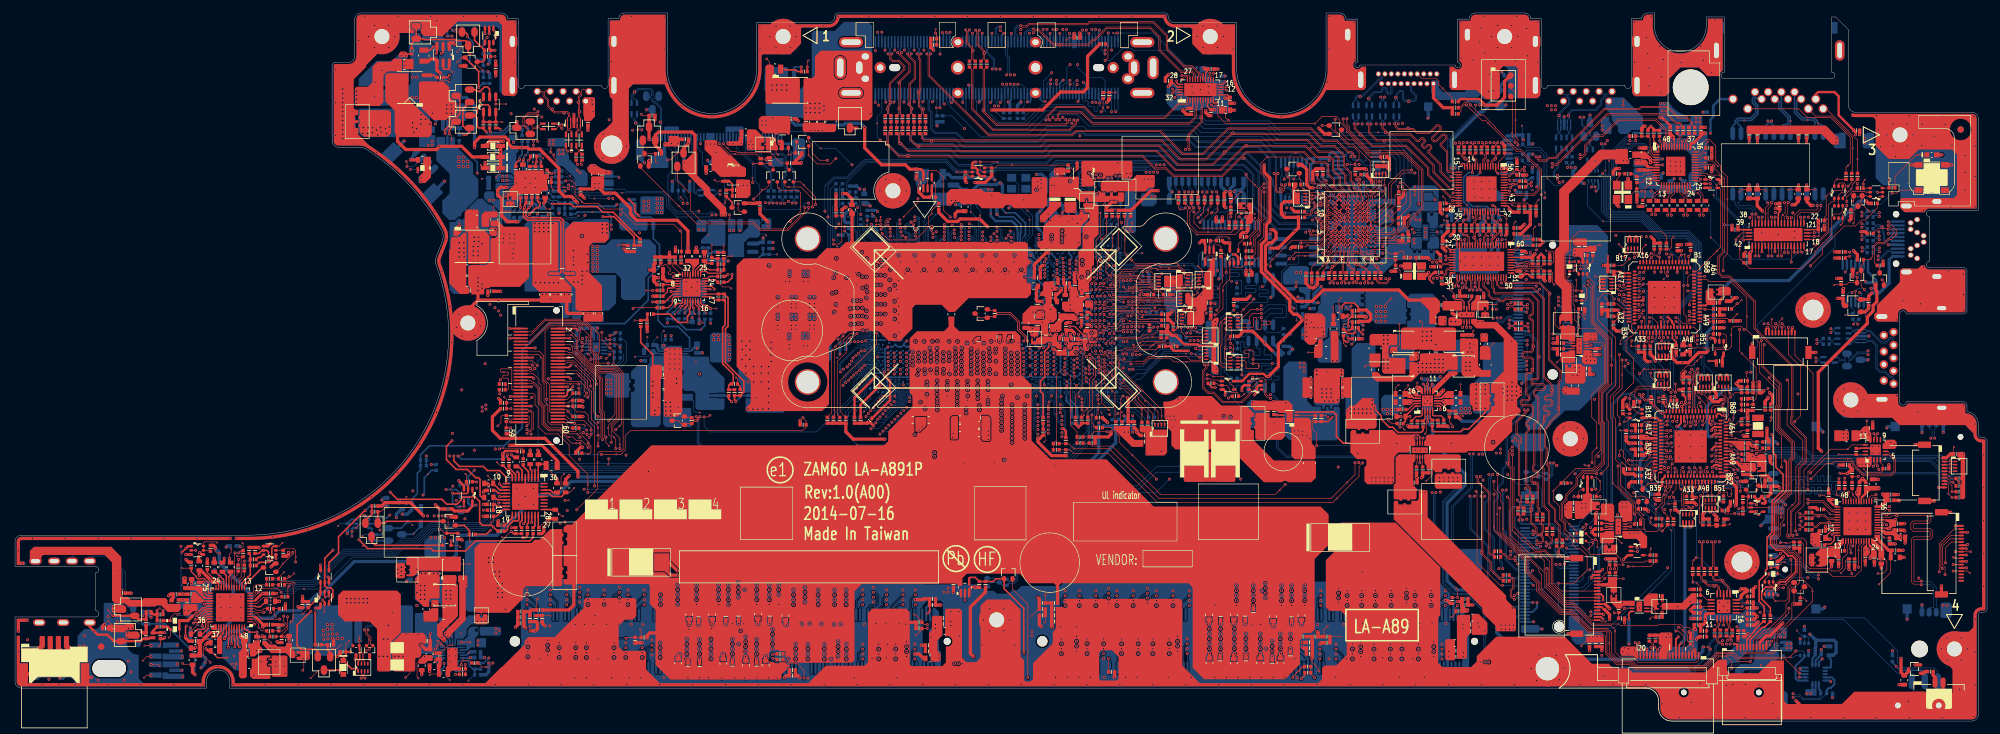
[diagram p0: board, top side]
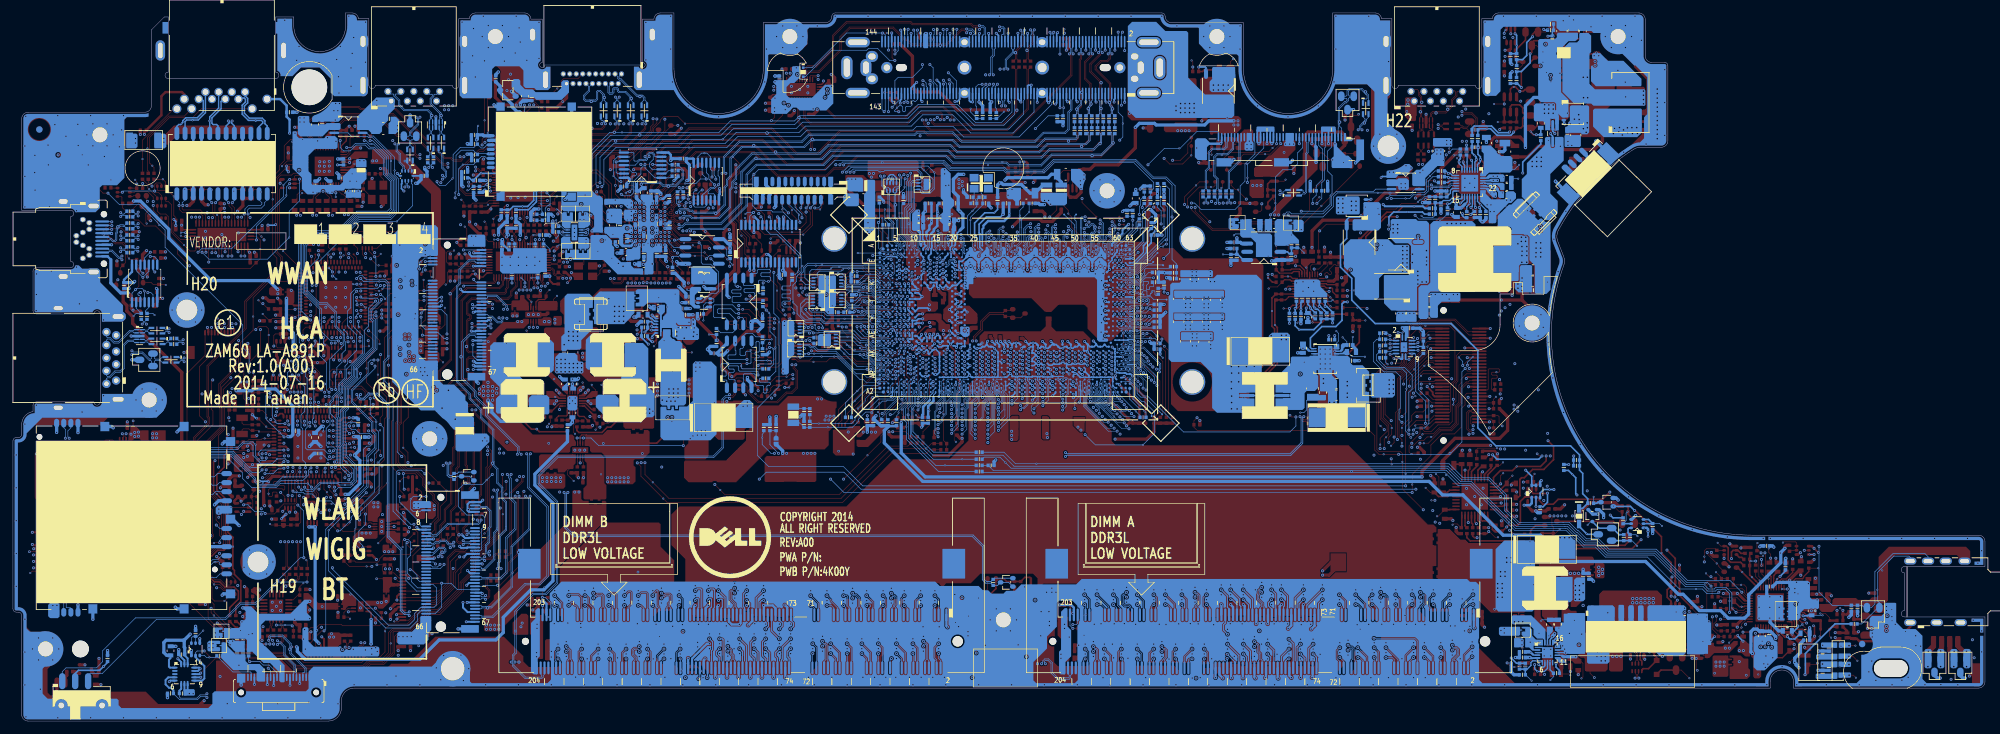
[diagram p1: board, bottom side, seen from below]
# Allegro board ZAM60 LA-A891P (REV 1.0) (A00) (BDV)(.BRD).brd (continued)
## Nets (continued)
N22988375: C319.1 R273.2
N23890107: QE4.2 RE70.2
N24544483: PD5.2 PD5.3 PL3.1 PQ2.1 PR7.1 PR10.2
N24607258: PC309.1 PU300.5
N48705653: PQ2.3 PR7.2 PR9.1
N48705663: PQ3.2 PR10.1 PR12.2
N48705665: PQ2.2 PQ3.1 PR11.2 PR13.1
N48708367: PR210.2 PU200.7
N48708425: PR206.2 PU200.9
N48716673: PR838.1 PU800.28
N48716693: PR845.1 PU800.26
N49522072: PC700.2 PQ701.2 PQ702.2 PR702.2
N49522215: PQ703.1 PQ703.3 PR706.2 PR707.2 PR709.2
N49522242: PC702.2 PC703.1 PR705.2 PU700.1
N49522275: PC701.2 PC702.1 PR704.2 PU700.2
N49522729: PQ701.1 PR701.2
N49522731: PQ702.1 PR701.3
N49522780: PQ700.4 PR700.1
N61500733: PR513.1 PU500.4
N61500909: PC510.2 PR526.1 PU500.28
N61500999: PH501.2 PR515.1
N61501245: PC501.1 PH500.2 PR505.2 PU500.14
N61501462: PR511.2 PU500.16
N66971793: PR105.2 PU100.5
N66972075: PR106.2 PU100.1
N78957489: PQ816.1 PR822.2
N78967043: PQ816.2 PU806.4
N78985854: PR810.2 PR812.2 PU804.2
N79002827: PQ806.2 PU804.4
N79023703: PR863.1 PU800.19
N79030038: PQ813.2 PQ813.3 PR829.2
N79030087: PQ813.6 PR826.2
N79030091: PQ814.2 PR826.1 PR827.1
N79030745: PD813.2 PQ814.1
N79114795: PC4.1 PQ1.2 PR6.2
N79114801: PD4.2 PQ1.1
N80905978: PC402.1 PR400.2 PR401.1 PU400.8
N80906026: PC403.2 PR402.2 PR403.1 PU400.2

Pads without a net: FD1 1; FD2 1; FD3 1; FD4 1; JAPS1 16 17 18; JDIMM1 77 122 125 198 205 206; JDIMM2 77 122 125 198 205 206; JEDP1 16 20 32; JHDMI1 14; JKBTP1 6 13; JLED1 9; JLOM1 14 15; JNGFF1 9 36 38 40 50 52 54 56; JNGFF2 12 14 16 17 20 32 34 36 38 40 48 50 51 52 53 54 55 56 57 58 59 60; JSATA1 8 20; JSIM1 1 2 5; JSPI1 17; JUSH1 9 10; JXDP1 40 42; PBATT1 11 12; PD2 3; PRP2 4 5; PU200 10; PU400 7; PU500 5; PU700 4; PU800 20 29 30 31 35 36; QL2 3 4 5; QZ11 3 4 5; RPC1 7; RPC17 8; RPE5 1; RPE6 4 5; UC1 A5 A21 A23 A35 A41 A43 A49 AA23 AA59 AB8 AB21 AB23 AC20 AC58 AC59 AD5 AD7 AD8 AD10 AD23 AD59 AD60 AE59 AE60 AF20 AG58 AH13 AL1 AL2 AL11 AL32 AM10 AM11 AN10 AP7 AP32 AT2 AU10 AU12 AU15 AU44 AV2 AV10 AV44 AV50 AV62 AW10 AW14 AW49 AY8 AY14 AY42 AY43 B21 B22 B23 B35 B41 B43 B49 C4 C21 C46 C47 D1 D15 D58 D61 E1 E6 E8 E13 E15 F6 F8 F22 G1 G10 H10 H18 H22 J2 J4 J13 J20 J21 J58 K4 K10 K18 K21 L3 L11 L59 M20 M21 N23 N58 N60 P20 R5 R20 R23 T23 T59 U10 U59 V21 V59 W23 Y20 Y22; UC8 1; UD1 1; UE1 A3 A5 A8 A9 A11 A12 A16 A23 A32 A42 A45 A46 A48 A49 A52 A55 A56 A57 A58 A59 A60 A61 A64 B1 B3 B4 B6 B7 B11 B13 B14 B16 B17 B18 B32 B39 B40 B45 B47 B49 B56 B57 B58 B60 B61 B63 B64 B65 B66; UE2 A15 B15 B16 B62; UI3 9 15; UI4 8 13 17; UL4 5; UN1 2 3; UN2 7; UR1 19 39 40 44 46; UV7 46; UV8 E10 H3 H11 K2 L2 L10 L11 L12 L13 M1 M2 M10 M11; UV600 2 4 14 22 23 58; UZ1 1 2 5 6 7 9 12 13 14 15 17 27 28; YC2 2 4

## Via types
v1: diameter 0.305, hole 0.152, TOP to BOTTOM, 753 vias
v2: diameter 0.457, hole 0.203, TOP to BOTTOM, 4660 vias
v3: diameter 0.406, hole 0.203, TOP to BOTTOM, 157 vias
v4: diameter 0.508, hole 0.254, TOP to BOTTOM, 593 vias

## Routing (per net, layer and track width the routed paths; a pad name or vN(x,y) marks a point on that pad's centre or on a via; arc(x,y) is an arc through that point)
0.675V_DDR_VTT_ON: length 105.7
  TOP w0.102: PR210.1 72.15,8.36 v1(72.73,8.36) 73.21,8.36 v2(73.85,8.99)
  TOP w0.254: UD1.4 147.45,22.07 147.6,22.22 148.37,22.22 149.01,21.58 RD14.2 RD9.2 151.19,21.58 151.6,22 QD1.2 152.84,20.49 155.89,17.44 v2(155.89,10.52)
  IN3 w0.122: v2(73.85,8.99) 75.05,7.79 118.22,7.79 118.73,8.3 143.62,8.3 145.84,10.52 v2(155.89,10.52)
1.05V_LP_EN: length 0.6
  BOTTOM w0.102: 200.04,66.56 200.4,66.56 v1(200.58,66.74)
1.05V_M_PWRGD: length 35.5
  TOP w0.254: v2(208.28,59.82) 207.58,60.51 PR313.1 ; RC27.1 185,51.59 v2(185.48,51.59)
  IN2 w0.254: v2(185.48,51.59) 185.02,52.04 185.02,54.58 185.49,55.05 188.82,55.05 190.07,53.81 193.9,53.81 194.42,53.29 199.5,53.29 200.23,54.01 200.23,57.26 201.98,59.02 204.37,59.02 205.19,59.84 206.11,59.84 206.32,59.63 208.09,59.63 v2(208.28,59.82)
  BOTTOM w0.102: v2(185.48,51.59) v1(184.78,51.59)
1.05V_MODPHY_EN: length 15.6
  TOP w0.102: QZ6.3 164.13,85.22 163.97,85.05 163.66,85.05 CZ25.1 v1(154.06,85.97) 151.84,85.97 151.4,85.53 RZ5.2 150.9,85.56 QZ10.3
1.05V_MP_PWROK: length 2.4
  TOP w0.254: v2(206.05,60.46) 206.34,60.46 PR313.2 PR315.2
  BOTTOM w0.254: PU300.2 v2(206.05,60.46)
1.5VSP:
  vias: v1(107.15,75.16)
1.35V_B+: length 26.1
  TOP w0.102: PQ200.5 v1(70.27,24.28)
  IN1 w0.254: v2(62.1,23.47) 60.98,22.35 60.98,9.25 61.49,8.74 66.1,8.74 v2(66.29,8.93)
  BOTTOM w0.254: v2(66.29,8.93) 66.29,8.36 65.77,7.84 PR206.1
  BOTTOM w0.508: PC206.1 PC203.1 v2(62.1,23.47)
1.35V_FB: length 6.8
  BOTTOM w0.102: PR209.1 70.97,7.16 v1(70.06,6.25)
  BOTTOM w0.203: PC213.1 70.74,8.03 70.16,8.61 70.16,9.05 69.91,9.31 68.45,9.31 68.41,9.27 PU200.6
  BOTTOM w0.254: PR205.1 PC213.1 71.04,7.17 PR209.1
3.3V_CAM_EN#: length 137.2
  TOP w0.102: QZ1.2 102.35,83.55 104.39,81.51 104.39,78.97 106.17,77.19 114.17,77.19 115.26,76.1 119.33,76.1 122.06,78.83 v2(122.06,79.43) ; v2(171.21,56.75) 171.84,57.38 173.23,57.38 173.99,58.14 v1(175.88,58.14) 175.98,58.14 176.3,58.46 179.08,58.46 RC174.1
  IN3 w0.076: 168.87,72.77 168.41,72.31 168.41,68.57 168.64,68.34 168.64,66.84 168.08,66.28 165.82,66.28 165.46,65.93 165.46,61.07 165.98,60.55 167.04,60.55 167.28,60.32 167.28,59.77 167.54,59.51 168.44,59.51 168.92,59.03
  IN3 w0.122: v2(122.06,79.43) 122.06,80.16 122.64,80.75 124.33,80.75 128.61,85.03 149.99,85.03 159.1,94.14 159.87,94.14 160.22,94.5 163.17,94.5 163.52,94.14 164.43,94.14 165.21,93.36 165.21,89.1 163.58,87.46 163.58,82.13 168.59,77.13 168.59,76.36 168.87,76.09 168.87,72.77 ; v2(171.21,56.75) 171.21,57.63 169.81,59.03 168.92,59.03
  BOTTOM w0.081: UC1.AM4 169.13,56.13 169.6,56.13 169.64,56.09 169.66,56.09 169.66,56.09 170.37,56.09 170.37,56.09 170.38,56.09 170.55,56.26 170.9,56.26 171.21,56.57 v2(171.21,56.75)
3.3V_HDD_EN: length 118.4
  TOP w0.102: UN3.3 v2(248.74,17.45) 248.06,16.78 RN6.2 RN7.1
  IN1 w0.089: v2(204.49,39.28) 204.77,39.28 211.32,32.73 228.96,32.73 229.28,32.41 238.35,32.41 244.94,25.82 244.94,21.68 245.81,20.81 245.81,18.77 247.12,17.45 v2(248.74,17.45)
  IN3 w0.122: v2(204.49,39.28) 199.19,39.28 196.1,42.37 196.1,47.68 195.9,47.89 195.9,56.95 195.75,57.09 191.52,61.33 191.52,63.07 187.24,67.35 185.46,67.35 184.64,68.17 181.33,68.17 180.34,69.16 v2(177.23,69.16)
  BOTTOM w0.076: UC1.K2 170.49,68.14 170.82,68.14 171.32,68.64 172.57,68.64 v1(173.17,68.04) 173.36,68.04
  BOTTOM w0.102: 173.36,68.04 173.95,67.45 175.75,67.45 175.97,67.66 175.97,68.54 176.59,69.16 v2(177.23,69.16)
3.3V_TP_EN: length 15.6
  TOP w0.081: v2(168.27,67.65) 168.8,68.18 169.64,68.18 171,69.54 172.7,69.54 173.36,70.19
  TOP w0.102: RPC3.7 180.88,68.43 180.68,68.63 180.68,69.01 179.83,69.86 176.49,69.86 176.38,69.98 v1(175.6,69.98) 175.35,70.23 173.39,70.23 173.36,70.19
  BOTTOM w0.081: v2(168.27,67.65) 168.15,67.53 UC1.L5
3.3V_TS_EN: length 123.7
  TOP w0.102: RPC4.7 176.38,67.73 175.85,68.27 174.13,68.27 173.7,68.7 171.08,68.7 170.29,67.91 170.29,67.29 170.01,67.01 168.66,67.01 168.47,67.2 167.53,67.2 v2(167.02,66.69) ; v2(122.64,79.43) 122.64,79.08 119.4,75.84 115.14,75.84 114.11,76.87 105.34,76.87 v1(102.54,79.67) 96.63,85.59 QV7.2
  IN3 w0.081: 167.42,76.26 167.42,73.15 168.21,72.36 168.21,68.45 167.94,68.18 167.56,68.18 167.36,67.98 167.36,67.41 167.02,67.07 v2(167.02,66.69)
  IN3 w0.122: v2(122.64,79.43) 122.64,79.51 123.52,80.39 124.32,80.39 128.69,84.76 150.07,84.76 159.21,93.89 159.97,93.89 160.32,94.25 163.07,94.25 163.42,93.89 164.33,93.89 164.96,93.26 164.96,91.9 162.37,89.31 162.37,82.58 167.42,77.53 167.42,76.26
  BOTTOM w0.081: UC1.N7 166.85,66.52 v2(167.02,66.69)
3.3V_WWAN_EN: length 15.7
  TOP w0.102: v2(244.92,57.59) 244.92,57.66 v1(245.27,58.01)
  TOP w0.203: RZ40.2 244.18,57.62 UZ2.3
  TOP w0.305: UE1.B42 v2(254.37,61.77)
  TOP w0.508: RZ40.2 v2(244.92,57.59)
  IN4 w0.508: v2(254.37,61.77) 253.39,60.78 250.63,60.78 250.41,61.01 247.04,61.01 246.44,60.4 246.44,59.11 v2(244.92,57.59)
+0.9V_LAN: length 7.1
  TOP w0.203: UL1.46 255.23,89.29 254.87,89.64 v2(254.83,89.64) UL1.47 ; UL1.11 253.14,83.99 252.66,83.51 v2(252.66,83.48) ; v2(258.37,81.77) 258.03,82.11 UL1.22 ; v2(257.67,89.71) 257.63,89.67 UL1.40 ; v2(255.44,81.77) 255.63,81.95 UL1.16
  TOP w0.508: CL9.1 v2(261.16,90.9)
  vias: v1(259.98,89.94) v2(250.76,85.25) v2(251.39,85.25) v2(256.14,90.22)
+0.675V_DDR_VTT: length 151.8
  IN4 w1.524: 74.67,12.48 74.67,9.94 76.77,7.85 142.28,7.85 142.8,8.36 143.63,7.53 148.76,7.53 149.4,8.17 222.23,8.17
  vias: v2(74.29,14.33) v2(74.29,13.63) v2(74.8,14.01) v2(142.24,14.96) v2(142.24,14.33) v2(142.8,10.33) v2(142.8,9.7) v2(223.76,14.97) v2(223.76,14.33) v2(223.83,10.58) v2(223.83,9.94) v3(141.51,12.98)
+0.675V_P: length 1.3
  TOP w0.127: v2(68.96,12.19) v3(70.28,12.19)
+1.2V_LDO: length 31.6
  TOP w0.102: v3(278.88,34.9) 279.61,34.9 280.25,34.26 CR21.2
  TOP w0.203: UR1.10 280.79,29.51 279.78,28.49 CR18.2 ; UR1.1 281.31,33.11 280.97,33.45
  TOP w0.381: CR21.2 280.27,34.14 280.97,33.45
  TOP w0.508: CR21.2 v2(280.97,34.26)
  IN2 w0.508: v2(289.61,29.76) 290.02,29.76 290.56,30.3 v2(290.56,31.16) 290.56,34.47 289.93,35.1 v2(288.59,35.1) 288.59,35.41 v2(288.02,35.99) 287.45,36.56 282.11,36.56 280.97,35.41 v2(280.97,34.26) 280.97,32.43 281.52,31.88 281.52,28.47 281.16,28.11 v2(280.53,28.11)
+1.05V_M: length 131.9
  TOP w0.381: v2(164.68,60.93) 164.81,61.06 RC300.1
  TOP w0.508: v2(163.71,59.88) 163.71,60.03 163.31,60.43 162.54,60.43 162.46,60.51 ; CC61.1 162.46,60.51 ; 162.46,60.51 v2(162.46,59.83) ; RC14.2 RC18.2 RC16.2 RC15.2 128.39,44.74 129.54,43.6 v2(134.43,43.6)
  IN2 w0.508: v2(197.71,44.22) 197.71,41.22 197.04,40.55 155,40.55 153.09,42.46 135.56,42.46 v2(134.43,43.6)
  IN3 w1.524: 171.88,82.98 171.88,81.2 173.85,79.23 178.62,79.23 182.5,75.35 188.59,75.35 192.15,71.79 194.26,71.79 196.21,69.84 196.21,63.14 197.44,61.91 197.44,59.77 198.99,58.22 198.99,56.5
  BOTTOM w0.203: UC1.AG13 163.51,59.38 163.71,59.58 v2(163.71,59.88) ; v2(162.46,59.83) 162.69,59.6 UC1.AG14
  BOTTOM w0.254: v2(166.44,59.07) 166.44,58.77 166.26,58.6 UC1.AG8 ; UC1.AF9 UC1.AE9
  BOTTOM w0.33: v2(166.44,59.07) UC1.AF9
  vias: v2(171.76,84.68) v2(172.08,84.11) v2(172.4,84.68) v2(197.74,44.87) v2(198.35,44.22) v2(198.37,44.87) v2(198.59,55.36) v2(198.59,54.72) v2(198.98,44.81) v2(198.98,44.22) v2(199.22,55.36) v2(199.22,54.72) v2(199.22,54.09) v2(199.67,44.09) v2(200.09,43.66) v3(170.42,86.33)
+1.05V_MODPHY:
  vias: v3(160.13,82.85)
+1.05V_MODPHY_PCH: length 2.7
  BOTTOM w0.254: UC1.M9 164.95,66.69 v2(164.88,66.76) 164.9,66.76 UC1.L10 165.75,67.61 UC1.K9 165.75,68.15 v2(165.78,68.18)
  vias: v3(166.3,76.89)
+1.05V_MP: length 13
  IN4 w0.254: v2(206.56,58.28) 206.56,50.96 205.23,49.63 v4(204.4,49.63)
  BOTTOM w0.254: PR307.1 PC304.1 207.58,59.3 v2(206.56,58.28)
  vias: v1(202.78,54.05) v4(201.17,54.2) v4(201.17,53.57) v4(201.98,51.35) v4(201.98,50.72) v4(201.98,50.08) v4(202.42,49.47) v4(202.68,51.35) v4(202.68,50.72) v4(202.68,50.08) v4(203.07,49.47) v4(203.37,51.35) v4(203.37,50.72) v4(203.37,50.08) v4(203.72,49.45) v4(204.98,54.2) v4(204.98,53.57)
+1.5V_RUN: length 185.5
  TOP w0.102: v3(30.19,9.07) 29.09,10.16 29.09,11.44 v2(29.49,11.84)
  TOP w0.508: RA3.1 29.78,12.13 v2(29.49,11.84)
  IN2 w0.508: v2(162.99,68.63) 162.99,68.24 162.48,67.74 158.67,67.74 158.1,68.31 158.1,71.8 156.77,73.13 127.51,73.13 124.58,70.21 118.87,70.21 113.88,75.19 107.43,75.19 ; v2(29.49,11.84) 30.74,11.84 32.06,10.52 35.05,10.52 36.26,11.72 36.26,20.1 36.95,20.8 36.95,24.68 38.8,26.52 40.7,26.52 41.52,27.34 43.37,27.34 44.34,28.31 48.67,28.31 51.54,31.18 54.89,31.18 60.09,36.38 61.96,36.38 66.04,40.46 66.04,43.99 68.13,46.09 68.13,51.85 70.74,54.46 76.01,54.46 83.7,62.15 90.75,62.15 92.58,63.98 92.58,65.7 101.29,74.4 104.46,74.4 105.34,75.29
  BOTTOM w0.254: UC1.J15 162.65,68.29 v2(162.99,68.63)
  vias: v2(105.66,75.98) v2(106.36,75.98)
+1.05V_RUN: length 251.7
  TOP w0.254: UV8.E5 205.28,74.9 205.28,74.91 v2(205.29,74.91) ; UV8.J3 v2(208.54,73.61)
  TOP w0.279: 263.62,37.84 262.96,37.84 UE2.B51 ; JXDP1.43 v2(76.51,50.2) ; v2(86.2,51.72) 86.2,51.7 85.34,50.84 85.34,50.48 85.06,50.2 JXDP1.44
  TOP w0.508: 263.62,37.84 264.63,37.84 265.29,37.18 265.29,36.93 266.01,36.21 CE25.1 266.01,33.45 v2(265.86,33.3) ; v2(127.89,81.57) 128.52,81.57 129.35,80.75 CC79.1 ; RE70.1 252.03,32.8 v2(252.41,32.42) ; RC197.1 v2(126.87,81.57) ; CC84.1 157.84,66.97 157.84,65.08 CC70.1 158.7,64.89 v2(158.73,64.86) ; v2(162.05,68.62) 162.05,67.77 CC59.1 162.33,67.44 162.33,65.91 CC60.1 ; RC117.1 v2(87.75,47.09)
  IN2 w0.508: v2(86.2,51.72) 86.2,51.32 85.72,50.84 79.31,50.84 78.67,50.2 v2(76.51,50.2) ; v2(198.64,69.37) 210.8,69.37 212.85,71.41 212.85,74.93 214.75,76.83 216.6,76.83
  IN2 w1.524: 210.82,87.67 215.64,87.67 218.06,85.25 218.06,79.43
  IN3 w0.508: v2(252.41,32.42) 251.76,31.77 250.97,31.77 249.97,30.77 249.37,30.77 248.84,30.24 248.84,29.18 246.97,27.31 245.48,27.31 243.88,25.7 243.32,25.7 239.79,22.18 237.91,22.18 237.58,21.85 228.69,21.85 227.13,23.41 206.02,23.41 203.12,26.31 193.08,26.31 179.07,40.32 179.07,45.19 ; v2(126.87,81.57) 126.49,81.57 123,78.08 116.09,78.08 115.07,77.06 110.15,77.06 104.4,71.32 104.4,69.65 102.49,67.73 100.8,67.73 99.5,66.43 99.5,64.55 95.63,60.68 95.63,57.25 92.27,53.89 91.5,53.89 90.53,52.91 86.94,52.91 86.2,52.17 v2(86.2,51.72) 86.2,48.64 v2(87.75,47.09)
  IN4 w0.508: v2(265.86,33.3) 265.86,33.2 265.28,32.62 264.24,32.62 262.98,31.36 254.62,31.36 253.55,32.42 v2(252.41,32.42)
  BOTTOM w0.229: v2(162.04,69.2) 162.2,69.2 UC1.H15 ; v2(163.96,69.35) 164.22,69.1 164.22,69.09 UC1.H11 UC1.J11
  BOTTOM w0.254: v2(166.37,66.69) 166.37,66.69 166.2,66.51 UC1.N8 165.93,66.22 165.75,66.04 UC1.P9 ; UC1.AG17 161.15,58.72 v2(161.47,58.4) 161.79,58.72 UC1.AG16 ; v2(162.05,68.62) 161.72,68.29 UC1.J17 ; v2(158.69,59.25) 158.68,59.24 158.24,59.24 UC1.AF22 ; v2(166.37,60.03) 166.2,59.85 UC1.AE8
  BOTTOM w0.305: UC1.R21 159.1,65.23 v2(158.73,64.86) 159.1,64.5 UC1.T21
  BOTTOM w0.457: RC125.1 v2(127.89,81.57) RC124.1 ; RC126.1 v2(126.87,81.57) RC127.1
  BOTTOM w0.508: v2(131.24,82.21) RC196.2
  vias: v2(144.4,79.92) v2(144.7,80.5) v2(145.34,80.5) v2(158.05,83.41) v2(158.05,82.78) v2(158.56,83.73) v2(158.56,83.1) v2(158.56,82.46) v2(160.96,59.81) v2(174.53,83.79) v2(175.12,83.79) v2(175.7,83.79) v2(177.89,47.14) v2(178.05,46.56) v2(178.47,47.14) v2(178.66,46.56) v2(179.08,47.14) v2(179.26,46.56) v2(179.79,49.81) v2(180.4,49.81) v2(198.03,69.35) v2(216.18,74.48) v2(216.2,73.9) v3(155.86,80.59)
+1.5V_RUN_AUDIO:
  vias: v1(31.9,13.33)
+1.05V_RUN_UZ7:
  vias: v1(194.55,46.1)
+1.05V_RUN_VMM: length 16.8
  TOP w0.127: v2(197.98,67.18) v3(197.98,67.88)
  IN3 w0.508: v2(211.19,70.76) 210.08,69.66 200.96,69.66 198.49,67.18 v2(197.98,67.18)
  BOTTOM w0.508: QV20.4 196.98,66.84 196.98,66.84 197.63,66.84 v2(197.98,67.18)
+1.05V_VCCST: length 114.2
  TOP w0.508: PC511.1 PR529.1 PR528.1 ; PR528.1 PR527.1 ; PR528.1 v2(101.14,72.5) ; v2(150.29,76.44) v3(149.09,77.63) 146.05,77.63 145.67,77.25 144.14,77.25 142.75,78.65 RC202.2
  IN1 w0.508: v2(101.14,72.5) 101.84,71.8 105.55,71.8 106.19,71.17 106.98,71.17 109.85,68.3 116.1,68.3 118.03,70.23 125.88,70.23 v2(126.79,69.32)
  IN2 w0.508: v2(150.29,76.44) 149.02,76.44 148.51,75.93 148.51,74.4 147.94,73.83 132.58,73.83 127.76,78.65 127.76,79.92 128.33,80.49 128.78,80.49 v2(130.55,82.27)
  IN3 w0.508: v2(126.79,69.32) 126.79,70.54 125.79,71.54 125.79,76.81 127.19,78.21 127.19,79.6 127.95,80.37 129.28,80.37 130.55,81.64 v2(130.55,82.27) ; v2(150.29,76.44) 150.29,75.35 150.16,75.22 150.16,71.43 151.75,69.84 151.75,67.3 157.21,61.84 v2(157.21,60.71)
  BOTTOM w0.457: v2(130.55,82.27) 130.1,82.73 RC199.1 RC25.1
  BOTTOM w0.508: RC204.1 126.87,67.86 RC208.1 RC114.1 126.86,69.38 v2(126.79,69.32) RC116.1
  vias: v2(157.22,60.05)
+1.5V_VIN: length 1.9
  BOTTOM w0.102: v1(116.07,75.1) 115.85,75.32 114.23,75.32
+1.05V_VMM_UV10: length 0.8
  BOTTOM w0.102: 219.9,73.62 220.41,73.62 v1(220.65,73.38)
+1.05V_VMM_VDD: length 6.9
  TOP w0.203: UV8.G3 206.91,73.94 v2(207.24,73.61) ; UV8.E9 v2(205.29,78.16) ; UV8.C8 v2(203.99,77.51) ; UV8.C9 v2(203.99,78.16) ; UV8.E8 v2(205.29,77.51) ; UV8.H8 v2(207.89,77.51) ; UV8.E6 v2(205.29,75.56) ; UV8.E7 v2(205.29,76.21) ; UV8.F12 v2(205.94,80.11) ; UV8.G12 v2(207.24,80.11) ; UV8.H6 v2(207.89,75.56) ; UV8.H7 v2(207.89,76.21) ; UV8.H9 v2(207.89,78.16) ; UV8.D3 v2(204.64,73.61) ; UV8.E3 v2(205.29,73.61)
  vias: v1(206.61,73.89)
+1.05V_VMM_VDDTX: length 6.3
  TOP w0.203: UV8.E12 v2(205.29,80.11) ; UV8.F3 v2(205.94,73.61) ; UV8.J2 v2(207.89,73.61) ; UV8.C6 v2(203.99,75.56) ; UV8.D12 v2(205.29,79.46) ; UV8.C7 v2(203.99,76.21)
  TOP w0.254: UV8.K10 v2(209.19,78.81) ; UV8.J10 v2(208.54,78.81) ; UV8.K9 v2(209.19,78.16) ; UV8.K8 v2(209.19,77.51)
  BOTTOM w0.508: v2(203.99,76.21) 203.27,76.21 CV93.1 ; CV91.1 205.28,80.12 v2(205.29,80.11)
  vias: v1(209.81,77.49)
+1.8V_RUN_CARD: length 3.9
  TOP w0.102: v2(288.4,25.06) 288.91,25.06 289.27,24.71 289.27,23.42 288.66,22.81 v3(287.89,22.81)
  vias: v2(288.38,26.44) v2(297.95,17.88) v2(298.59,17.87)
+1.35V_MEM: length 90.1
  TOP w0.508: 86.36,21.5 86.36,17.94 85.6,17.18 RD4.1 ; RD22.1 161.11,23.2 161.1,23.22 ; RD2.1 97.67,13.19 98.11,13.63 100.19,13.63
  BOTTOM w0.178: v2(147.21,49.62) 146.78,50.05 UC1.AY40 ; UC1.AN33 150.88,55.29 v2(150.62,55.03)
  BOTTOM w0.203: UC1.AR48 141.86,53.99 v2(141.54,53.66)
  BOTTOM w0.229: v2(140.9,49.99) 140.84,49.99 140.46,50.37 140.46,50.74 140.49,50.76 UC1.AY50
  BOTTOM w0.254: UC1.AP43 144.72,54.64 v2(144.39,54.31) ; UC1.AY44 143.64,50.74 v2(144.08,50.29) ; UC1.AY35 149.93,50.65 v2(150.37,50.22)
  BOTTOM w0.279: UC1.AJ33 151.01,58.19 151.47,58.65 v2(151.47,58.75) ; UC1.AJ31 152.31,58.19 152.76,58.64 v2(152.76,58.75) ; UC1.AH26 155.24,58.22 154.99,58.47 v2(154.99,58.47) ; v2(148.86,57.63) 148.6,57.89 UC1.AJ37
  BOTTOM w0.356: v2(116.57,18.01) 116.57,18 116.2,17.64 JDIMM1.117 ; JDIMM2.112 v2(196.2,6.77) ; JDIMM2.81 186.9,17.44 187.34,17.88 v2(188.75,17.88) 188.7,17.83 JDIMM2.87 ; JDIMM2.124 199.8,9.66 197.5,11.95 v2(197.11,11.95) ; JDIMM1.105 112.6,15.07 v2(112.63,15.05) ; v2(117.79,6.65) 118.3,7.16 JDIMM1.124 ; v2(110.85,15.05) 110.8,15.1 JDIMM1.99 ; JDIMM2.75 185.1,17.59 185.1,17.59 v2(185.46,17.95) ; v2(108.72,18.01) 109,17.73 JDIMM1.93 ; JDIMM2.99 192.3,15.14 v2(192.49,14.96) 192.51,14.93 193.66,14.93 194.1,15.37 JDIMM2.105 ; v2(118.02,18.01) 118,17.99 JDIMM1.123 ; JDIMM1.75 103.6,14.74 v2(104.12,14.22) ; v2(116.44,6.67) 116.5,6.73 JDIMM1.118 ; v2(194.4,6.77) JDIMM2.106 ; v2(192.6,6.77) JDIMM2.100 ; JDIMM2.94 v2(190.8,6.77) ; v2(191.13,14.83) 190.5,15.46 JDIMM2.93 ; JDIMM1.88 107.5,7.03 v2(107.18,6.71) ; JDIMM1.81 105.4,17.93 v2(105.33,18.01) ; JDIMM1.100 111.1,6.8 v2(111.21,6.69) ; v2(199.31,17.88) 199.5,17.69 JDIMM2.123 ; v2(107.68,14.32) 107.2,14.79 JDIMM1.87 ; v2(114.62,18.01) 114.4,17.79 JDIMM1.111 ; JDIMM2.76 v2(185.4,6.77) ; JDIMM1.112 114.7,6.71 v2(114.66,6.67) ; v2(109.21,6.61) 109.3,6.7 JDIMM1.94 ; JDIMM1.82 105.7,6.8 v2(105.77,6.73) ; JDIMM2.118 198,9.41 v2(197.78,9.63) ; JDIMM2.111 195.9,17.7 v2(195.72,17.88) ; JDIMM1.106 112.9,6.8 v2(112.74,6.64) ; v2(189,6.77) JDIMM2.88 ; v2(197.29,17.88) 197.7,17.47 JDIMM2.117 ; JDIMM2.82 v2(187.2,6.77) ; v2(103.99,6.73) 103.9,6.82 JDIMM1.76
  vias: v3(97.88,38.61)
+1.35V_MEN_P: length 32.5
  IN1 w0.508: v4(74.61,19.15) 74.61,15.91 73.28,14.58 73.28,11.85 71.24,9.82 v2(70.36,9.82)
  IN4 w0.254: v4(73.91,25.25) 75.24,25.25 76.04,24.45 76.04,17.4 73.21,14.58 v2(73.21,9.75)
  BOTTOM w0.254: PC213.2 PR205.2 72.41,8.95 v2(73.21,9.75)
  vias: v3(75.78,17.3) v4(73.21,25.25) v4(73.21,24.55) v4(73.91,24.55) v4(74.17,23.09) v4(74.17,22.39) v4(74.61,21.25) v4(74.61,20.55) v4(74.61,19.85) v4(74.86,23.09) v4(74.86,22.39) v4(75.31,21.25) v4(75.31,20.55) v4(75.31,19.85) v4(75.31,19.15)
+3.3V_ALW: length 499.4
  TOP w0.254: v2(205.03,63.93) 205.03,64.15 205.53,64.66 206.94,64.66 207.58,64.02 PR306.1 ; RPE3.7 260.85,53.25 v2(260.59,53.51) 260.35,53.27 RPE3.8 ; RPE6.6 261.73,32.55 v2(261.98,32.3) 262.23,32.55 RPE6.7 ; RPE5.8 263.27,53.27 v2(263.51,53.51) 263.77,53.25 RPE5.7 ; RPE6.8 262.73,32.76 v2(263.06,32.43) ; RPE4.6 250.25,74.65 v2(250.5,74.9) 250.75,74.66 RPE4.5 ; RPE9.7 255,56.06 v2(255.19,55.86) 255.5,56.17 RPE9.8 ; RPE9.6 254.5,55.99 v2(254.3,55.8) 254,56.1 RPE9.5 ; RPE4.7 249.75,74.65 v2(249.49,74.9) 249.25,74.66 RPE4.8
  TOP w0.305: JLED1.8 269.65,12.19 ; 245.73,18.06 245.69,18.1 JKBTP1.11
  TOP w0.381: v2(269.49,34.01) 268.81,34.7 RZ22.1 ; UZ10.5 264.03,56.44 263.84,56.24 CZ48.1 ; UC8.5 140.37,84.96 140,85.33 139.38,85.33 ; UZ6.5 270.44,33.68 270.57,33.8 270.57,34.01 269.97,34.61 CZ34.1 ; PU804.5 70.67,33.22 70.2,32.75
  TOP w0.457: CZ34.1 269.49,34.23 v2(269.49,34.01)
  TOP w0.508: 70.2,32.75 69.94,32.49 v2(69.4,32.49) 67.9,32.49 67.58,32.81 PC805.2 ; v2(264.77,31.24) RE63.1 ; v2(264.16,62.78) RE9.1 RE10.1 RE84.2 ; RE79.1 RE36.1 257.79,53.68 v2(258.12,54.01) ; v2(252.79,74.9) 253.29,74.41 RE11.1 RE35.1 ; RE83.1 v2(266.63,61.89) ; v2(263.84,54.92) CZ48.1 ; 139.38,85.33 CC35.1 138.29,85.33 137.6,86.02 133.92,86.02 131.3,88.63 v2(131.3,91.8) ; RE81.1 271.59,49.26 271.59,50.34 v2(271.13,50.8) ; v2(252.65,55.59) 252.22,55.59 251.82,55.99 RE12.1 250.89,57.06 RE276.1 ; RE5.1 247.5,60.31 v2(248.04,60.31) ; RC213.1 173.35,44.98 v2(173.35,44.68) 173.86,44.17 RC217.1 ; PR306.1 207.67,63.56 208.84,63.56 209.5,62.9 209.5,62.12 209.2,61.82 207.71,61.82 PR315.1 ; PR2.1 50.21,10.38 v2(49.84,10.01) ; RE25.1 v2(264.13,60.81) ; RZ31.1 286.88,80.03 286.47,80.03 v2(286.09,80.42) ; PR895.1 56.63,33.26 57.16,33.78 61.08,33.78 v2(63.14,31.72) ; v2(246.41,17.37) 246.41,17.4 245.76,18.06 245.73,18.06 ; PR859.2 v2(72.37,31.67) ; v2(273.26,25.44) 272.53,24.7 272.36,24.7 RZ24.1 ; v2(94.09,73.02) 94.5,72.61 PR813.1 PR815.1 ; PR107.2 223,47.02 v2(223.29,46.74) ; RE8.1 v2(258.3,73.72) ; v2(273.17,15.15) 271.21,13.18 270.63,13.18 269.65,12.19 ; RE69.1 249.74,36.99 249.37,36.63 v2(249.37,36.2) ; RE68.1 248.46,49.55 v2(248.92,50.01)
  IN1 w0.508: v2(91.82,92.98) 82.86,92.98 82.65,92.76 80.17,92.76 79.02,93.92 v2(76.67,93.92) ; v2(273.17,15.15) 273.17,16.54 271.73,17.99 271.73,23.35 273.26,24.89 v2(273.26,25.44) 273.1,25.27 271.7,25.27 270.49,26.48 270.49,33.01 v2(269.49,34.01) ; v2(72.37,31.67) 71.3,31.67 70.48,32.49 v2(69.4,32.49) 68.83,31.91 68.83,31.03 67.94,30.14 63.62,30.14 63.14,30.62 v2(63.14,31.72) 62.48,31.72 56.13,25.37 56.13,11.53 55.37,10.77 52.83,10.77 52.07,10.01 v2(49.84,10.01)
  IN2 w0.508: v2(249.54,29.06) 248.38,27.9 246.03,27.9 244.79,26.66 244.79,25.03 245.95,23.88 245.95,22.83 246.41,22.36 v2(246.41,17.37)
  IN2 w0.635: v2(301.13,41.3) 295.77,41.3 295.02,40.55 281.43,40.55 276.41,45.57 276.41,46.77 272,51.19
  IN3 w0.508: v2(173.35,44.68) 173.36,44.67 173.36,37.19 190,20.55 190,18.05 191.14,16.91 202.23,16.91 205.34,13.79 222.12,13.79 222.74,13.17 224.27,13.17 224.93,13.83 225.97,13.83 225.98,13.84 226.92,12.89 240.75,12.89 241.23,13.37 241.23,16.17 242.82,17.75 244.28,17.75 244.66,17.37 v2(246.41,17.37)
  IN4 w0.508: v2(205.03,63.93) 206.86,65.76 218.81,65.76 220.52,64.05 220.52,63.35 220.93,62.94 221.47,62.94 221.92,62.5 v4(221.92,61.77) ; v2(76.67,93.92) 76.65,93.92 73.62,96.95 73.62,99.99 73.68,100.05 73.68,100.98 v2(73.11,101.55) ; v2(95.44,91.35) 95.44,83.62 93,81.19 v2(93,79.87) 95.03,77.84 95.03,73.81 94.24,73.02 v2(94.09,73.02) 93.27,72.2 93.27,66.27 91.76,64.77 91.76,63.06 90.7,62 89.4,62 88.52,61.11 86.5,61.11 83.7,58.31 80.13,58.31 78.23,56.41 78.23,51.22 78.44,51.01 78.44,44.28 79.25,43.47 80.54,43.47 82.04,41.97 82.04,33.88 81.02,32.87 81.02,29.37 79.37,27.72 77.15,27.72 76.64,28.23 73.02,28.23 72.37,28.88 v2(72.37,31.67)
  BOTTOM w0.305: PR740.2 86.55,79.29 86.87,79.6 92.74,79.6 v2(93,79.87)
  BOTTOM w0.508: v2(73.11,101.55) 73.33,101.76 PR8.2 ; v2(223.29,46.74) 223.69,46.34 229.35,46.34 230.74,47.73 230.74,48.83 231.33,49.42 v4(231.33,49.63) ; v2(116.08,92.81) 119.95,92.81 120.58,92.18 128.08,92.18 128.33,92.43 130.67,92.43 v2(131.3,91.8) ; PR810.1 69.14,32.23 v2(69.4,32.49) ; v2(263.83,66.72) 265.22,68.12 274.11,68.12 280.67,74.67 280.67,76.05 285.04,80.42 v2(286.09,80.42)
  vias: v2(115.44,92.81) v2(115.44,92.18) v2(116.08,92.18) v2(226.11,61.77) v2(226.74,61.77) v2(236.79,95.16) v2(237.42,95.16) v2(237.42,94.53) v2(238.06,95.16) v2(238.06,94.53) v2(242.81,56.36) v2(242.82,55.73) v2(243.46,56.36) v2(243.46,55.73) v2(243.52,59.73) v2(243.52,59.09) v2(243.52,57) v2(244.15,59.73) v2(244.15,59.09) v2(244.09,55.73) v2(248.35,33.76) v2(248.35,33.12) v2(248.98,33.76) v2(248.98,33.12) v2(250.17,29.06) v2(250.81,29.06) v2(251.33,74.9) v2(252.09,74.9) v2(263.83,66.09) v2(268.54,40.93) v2(269.1,40.75) v2(270.89,51.41) v3(117.1,93.27) v3(221.96,42.95) v3(231.3,58.67) v4(222.61,61.77) v4(229.99,51.41) v4(229.99,50.71) v4(230.63,51.73) v4(230.63,51.03) v4(230.63,50.33) v4(230.63,49.63) v4(231.34,52.37) v4(231.33,51.73) v4(231.33,51.03) v4(231.33,50.33) v4(232.03,51.73) v4(232.03,51.03) v4(232.03,50.33) v4(232.66,51.35) v4(232.66,50.65)
+3.3V_ALW2: length 387.6
  TOP w0.203: PU100.3 v2(218.28,46.22)
  TOP w0.381: v2(75.33,41.33) 75.77,41.76 77.57,41.76 PR846.1 ; v2(193.66,53.26) 193.4,53.26 192.95,53.71 190.76,53.71 189.62,52.57 UC6.5 ; PU806.5 v2(47.21,24.13)
  TOP w0.508: v2(270.74,45.29) 270.74,43.72 271.01,43.44 RE57.2 ; v2(44.43,19.29) PC810.2 PR819.2 ; R272.2 165.75,102.81 165.75,97.94 165.08,97.28 161.58,97.28 158.79,94.5 v2(150.9,94.5) ; v2(147.06,83.29) 146.86,83.49 RZ16.1 ; v2(75.33,41.33) 75.4,41.26 PR855.1 ; v2(193.04,86.02) 193.04,84.87 193.93,83.98 193.93,77.3 193.35,76.73 193.35,74.47 192.59,73.71 192.59,69.49 197,65.08 197,63.51 197.62,62.89 198.17,62.89 v2(198.87,62.19) 198.87,61.9 v3(195.88,58.91) 195.23,58.27 195.23,54.83 v2(193.66,53.26)
  IN1 w0.508: v2(72.66,55.27) 74.99,57.6 76.8,57.6 79.29,60.09 84.71,60.09 86.88,62.25 86.88,63.42 92.52,69.06 92.52,75.72 v2(92.16,76.07) ; v2(44.43,19.29) 44.43,21.42 47.14,24.13 v2(47.21,24.13) 49.23,24.13 51.36,26.25 v2(51.36,29) ; v2(147.06,83.29) 147.06,90.66 v2(150.9,94.5)
  IN2 w0.508: v2(92.16,76.07) 92.92,75.31 95.63,75.31 96.19,74.75 97.13,74.75 97.53,75.16 103.57,75.16 105.22,76.81 114.68,76.81 116.01,78.14 123.19,78.14 125.33,80.29 125.33,82.26 128.45,85.37 132.5,85.37 132.96,85.83 141.65,85.83 144.2,83.29 v2(147.06,83.29) 147.06,83.73 147.63,84.3 149.6,84.3 152.13,86.82 177.69,86.82 178.5,86.02 v2(193.04,86.02) ; v2(218.28,46.22) 218.16,46.34 202.67,46.34 196.24,52.77 194.15,52.77 v2(193.66,53.26) ; v2(61.47,35.6) 60.26,35.6 54.58,29.92 51.64,29.92 51.36,29.64 v2(51.36,29)
  IN3 w0.508: v2(61.47,35.6) 64.32,38.46 v2(64.32,39.66) 64.32,41.22 v2(67.59,44.49) 67.59,48.01 71.05,51.47 71.05,53.67 v2(72.66,55.27)
  IN4 w0.508: v2(75.33,41.33) 75.27,41.26 74.16,41.26 70.93,44.49 v2(67.59,44.49) ; v2(270.74,45.29) 270.74,47.81 269.99,48.56 268.53,48.56 264.4,52.69 250.12,52.69 246,48.57 235.51,48.57 233.02,46.08 222.82,46.08 222.37,46.52 218.58,46.52 v2(218.28,46.22)
  BOTTOM w0.254: PR864.1 65.08,39.67 64.83,39.66 v2(64.32,39.66)
  BOTTOM w0.508: PR829.1 v2(51.36,29) ; PC100.2 218.3,46.24 v2(218.28,46.22) 218.67,45.84 PR103.2 ; RV212.1 198.97,62.29 v2(198.87,62.19)
+3.3V_ALW_DEG: length 1.1
  TOP w0.102: v1(299.65,42.39) 299.53,42.27 RE71.2
+3.3V_ALW_PCH: length 346.7
  TOP w0.305: JAPS1.1 v2(299.84,30.19)
  TOP w0.381: v2(185.04,58.02) 182.93,58.02 182.71,58.24 180.71,58.24 v3(180.65,58.29) 179.43,59.51 v2(179.43,59.65)
  TOP w0.508: RC120.2 73.77,47.05 73.77,44.94 74.99,43.72 81.9,43.72 86.99,38.63 v2(86.99,37.76) ; RC81.1 178,60.67 178.13,60.79 RC179.1 ; RC81.1 178.23,60.17 178.75,59.65 v2(179.43,59.65) ; RC81.1 RC82.1
  IN2 w0.508: v2(299.84,30.19) 300.71,29.32 300.71,18.17 297.75,15.21 294.45,15.21 v2(290.13,10.9) ; 161.53,57.64 161.53,51.54 164,49.07 164,47.73 165.59,46.15 v2(167.48,46.15) 168.12,45.5 170.36,45.5 171.19,44.68 v2(171.45,44.68)
  IN2 w0.762: 227.14,63.54 226.03,64.64 223.56,64.64 221.82,66.38 193.62,66.38 191.67,64.43 187.51,64.43 186.74,63.65 186.74,63.04 185.72,62.02 ; 172.08,43.92 173.03,42.96 187.39,42.96 188.91,44.49 188.91,50.14 186.18,52.87
  IN3 w0.508: v2(227.5,62.66) 227.5,65.26 227.8,65.56 233.84,65.56 236.92,62.48 238.54,62.48 240.66,60.36 240.66,56.87 242.76,54.77 245.04,54.77 245.62,54.2 249.57,54.2 250.04,54.68 254.87,54.68 255.89,55.7 261.02,55.7 261.25,55.93 269.55,55.93 270.58,54.91 273.04,54.91 276.71,51.23 276.71,45.01 279.03,42.7 285.72,42.7 286.64,43.61 288.66,43.61 290.41,45.36 296.03,45.36 298.21,43.19 298.21,31.83 v2(299.84,30.19)
  BOTTOM w0.229: UC1.AH14 162.66,58.03 v2(162.34,58.35) ; UC1.AE20 159.95,60.33 v2(160.02,60.33)
  BOTTOM w0.254: UC1.AC9 UC1.AA9 165.1,61.93 164.82,62.2 v2(164.16,62.2) ; UC1.AE21 159.2,59.58 UC1.AE20
  BOTTOM w0.508: RC2.1 v2(290.13,10.9) ; v2(86.99,37.76) 163.76,37.76 167.48,41.47 v2(167.48,46.15)
  vias: v2(160.96,60.4) v2(172.08,44.68) v2(185.51,61.78) v2(185.54,61.19) v2(185.73,54.42) v2(185.73,53.83) v2(226.87,62.66)
+3.3V_ALW_PCH_UZ8: length 1.5
  TOP w0.127: v1(228.95,64.41) 227.78,64.41 227.57,64.63
+3.3V_ALW_UE1: length 59.1
  TOP w0.254: CE6.1 256.71,58.59 256.12,59.18 UE1.A43
  TOP w0.279: UE1.A17 248.39,69.26 248.14,69.51 CE4.1
  TOP w0.305: UE1.A54 261.31,64.26 261.73,64.69 CE2.1 ; UE1.B30 v2(250.97,63.51) ; UE1.B5 v2(256.87,69.39)
  TOP w0.508: CE3.1 v2(257.54,72.74) ; CE6.1 256.41,58.1 256.02,57.7 256.02,56.24 256.84,55.42 v3(257.69,55.42) 258.62,55.42 260.18,56.98 261.35,56.98 v2(261.63,57.27) ; CE5.1 v2(247.76,63.55) ; CE4.1 247.07,69.06 v2(247.32,68.82) ; CE2.1 v2(262.48,65.37)
  IN1 w0.508: v2(247.76,63.55) 247.76,63.93 246.74,64.95 246.74,68.24 v2(247.32,68.82) ; v2(256.87,69.39) 256.87,72.47 257.15,72.74 v2(257.54,72.74)
  IN4 w0.508: v2(247.32,68.82) 247.32,69.39 248.21,70.28 255.98,70.28 v2(256.87,69.39) 257.62,68.64 259.69,68.64 v2(261.73,66.59) ; v2(250.97,63.51) 250.56,63.93 248.14,63.93 v2(247.76,63.55)
  BOTTOM w0.508: v2(262.48,65.37) 262.48,61.06 261.44,60.01 261.44,57.46 v2(261.63,57.27)
+3.3V_ALW_UE2: length 70.3
  TOP w0.254: CE13.1 258.13,50.11 v3(258.13,49.33) 258.13,49.18 257.61,48.66 v2(257.53,48.66)
  TOP w0.279: UE2.A26 252.76,41.71 252.74,41.73 ; UE2.B3 261.94,46.8 261.8,46.66 261.8,46.1 262.09,45.81 v2(262.12,45.81) ; v2(257.53,48.66) 257.69,48.51 UE2.A11 ; 259.19,35.67 259.19,35.67 UE2.A41
  TOP w0.305: 254.52,37.35 254.94,37.76 UE2.B35
  TOP w0.381: 259.19,35.67 CE19.1 ; 254.52,37.35 254.52,36.45 254.05,35.98 CE22.1
  TOP w0.508: v2(263.95,49.7) 263.58,49.7 263.26,49.38 262.43,49.38 261.97,49.84 CE17.1 ; v2(259.83,34.59) 259.33,34.59 CE19.1 ; CE22.1 254.03,35.06 v2(253.41,35.06)
  IN1 w0.508: v2(267.73,39.64) 267.73,40.07 267.52,40.27 267.52,41.34 266.18,42.68 v2(265.94,42.68) 265.94,46.85 264.58,48.21 264.58,49.34 264.21,49.7 v2(263.95,49.7)
  IN2 w0.508: v2(259.83,34.59) 258.83,34.59 258.12,33.88 254.85,33.88 253.67,35.06 v2(253.41,35.06) ; v2(263.95,49.7) 263.66,49.7 261.64,47.69 261.64,46.11 261.94,45.81 v2(262.12,45.81)
  IN4 w0.508: v2(266.89,39.66) 266.89,39.04 267.33,38.59 267.33,36.74 266.89,36.3 265.36,36.3 263.78,34.71 262.95,34.71 262.32,34.08 260.01,34.08 259.83,34.26 v2(259.83,34.59) ; v2(263.95,49.7) 262.53,49.7 260.62,47.8 258.4,47.8 v2(257.53,48.66)
  BOTTOM w0.508: v2(253.41,35.06) 252.82,35.06 251.14,36.74 251.14,40.3 v2(251.97,41.12) 251.2,41.88 251.2,43.78 CE14.1 251.41,43.99 v2(252.08,43.99)
+3.3V_ALWP: length 10.8
  TOP w0.254: v4(227.19,48.36) 227.19,47.71 224.62,45.15 v3(223.8,45.15) 223.39,44.74 219.26,44.74 219.01,45 PR100.1
  vias: v4(225.8,51.98) v4(225.8,51.28) v4(225.79,50.59) v4(225.79,49.83) v4(225.79,49.13) v4(225.8,48.36) v4(226.5,51.98) v4(226.49,51.29) v4(226.49,50.59) v4(226.49,49.83) v4(226.49,49.13) v4(226.5,48.36) v4(227.2,51.98) v4(227.19,51.29) v4(227.19,50.59)
+3.3V_CAM: length 6.4
  TOP w0.127: v3(100.81,86.78) 101.29,86.78 102.35,87.85 QZ1.1
  TOP w0.508: QZ1.1 103.31,88.57 v2(104.02,89.28) 104.09,89.35 CZ1.1
  BOTTOM w0.254: v2(104.02,89.28) 103.96,89.34 JEDP1.11
+3.3V_HDD: length 16.2
  TOP w0.254: 266.76,19.09 266.42,18.74 UN2.20
  TOP w0.381: RN18.1 RN10.2 v2(258.89,18.52) ; RN8.2 v2(258.89,15.85)
  TOP w0.508: RN24.1 267.31,13.06 v2(267.76,13.51) ; v2(269.24,17.5) RN12.2 RN14.1 ; v2(266.62,20.27) 266.79,20.43 267.43,20.43 CN29.1 267.52,19.99 267.34,19.99 266.76,19.41 266.76,19.09 ; v2(269.36,15.34) 268.86,14.83 RN20.1 ; RN22.1 260.49,14.49 260.41,14.57 CN24.1 260.86,14.9 261.22,15.26 v2(261.22,15.75) 261.22,16.37
  IN2 w0.508: v2(266.62,20.27) 268.62,18.27 268.62,18.12 v2(269.24,17.5)
  vias: v3(256.97,17.7)
+3.3V_LAN: length 100
  TOP w0.203: UL4.21 278.66,75.98 CL15.1
  TOP w0.254: UL4.14 274.96,72.53 v2(274.93,72.49) ; UL4.1 268.46,72.67 268.29,72.5 v2(268.21,72.5) ; CL27.1 272.72,78.76 272.5,78.55 272.5,77.74 272.46,77.71 UL4.30 ; UL4.8 v2(271.96,72.57) ; UL4.39 267.2,75.98 267.19,75.99 CL26.1 ; UL4.4 v2(269.96,72.57)
  TOP w0.381: v2(263.46,83.16) 263.46,83.67 263.37,83.75 UL2.5 ; RL4.2 RL6.1 253.24,91.54 v2(252.79,91.99) 252.35,91.54 RL5.1 ; JLOM1.12 278.27,96.89 278.64,97.26 281.18,97.26 281.81,96.62 281.81,93.69 CL19.1 284.44,91.06 v2(284.44,90.72)
  TOP w0.508: RL1.1 v2(262.2,87.86) RL2.1 ; CL27.1 272.65,79.2 272.53,79.29 v2(272.08,79.29) ; RL30.1 CL25.1 268.09,72.38 v2(268.21,72.5) ; CL15.1 v2(278.67,76.68) RL29.1 ; CL26.1 v2(266.25,76.63)
  TOP w1.524: 239.77,63.75 239.77,67.07 238.71,68.13 238.71,72.48 239.39,73.16 239.39,75.09 239.38,75.09 239.38,81.81 v3(244.17,86.6) 245.17,87.6 247.62,87.6 247.63,87.59
  IN2 w0.381: v2(284.44,90.72) 284.44,85.98 282.38,83.92 264.6,83.92
  IN2 w0.508: v2(272.08,79.29) 270.73,79.29 269.78,80.25 266.11,80.25
  BOTTOM w0.381: v2(262,90.91) 262,93 262.46,93.46 CL18.1 262.46,95.17 263.46,96.18 JLOM1.9
  vias: v2(248.56,86.64) v2(249.15,86.61)
+3.3V_LAN_OUT: length 5.7
  TOP w0.203: v2(254.86,81.69) 254.86,81.84 255.23,82.2 UL1.15 ; UL1.29 v2(260.54,85.19) ; v2(252.73,86.96) 252.89,86.79 UL1.4 ; UL1.5 252.74,86.39 v2(252.73,86.37) ; UL1.19 v2(256.83,81.93)
  BOTTOM w0.102: v2(254.86,81.69) v1(254.86,81.04)
+3.3V_LAN_UZ2: length 3.8
  TOP w0.102: v1(238,63.91) 238,61.28 238.52,60.76 238.74,60.76 238.87,60.88
+3.3V_M: length 76.8
  TOP w0.508: v2(187.1,79.38) 186.86,79.62 RC231.1 ; 217.6,65.09 215.41,65.09 213.85,66.66 202.18,66.66 200.42,64.9 v1(199.31,64.9) 198.08,64.9 193.23,69.75 193.23,73.44 193.74,73.95 194.18,73.95 194.88,74.65 194.88,75.54 194.43,75.98 v2(194.05,75.98)
  IN2 w0.508: v2(194.05,75.98) 194.05,77.32 191.89,79.48 v2(189.1,79.48) 187.19,79.48 v2(187.1,79.38) 184.75,79.38 184.15,78.78 184.15,72.55 182.5,70.9 180,70.9 177.34,68.24 177.34,63.84 176.2,62.7 173.33,62.7 172.79,63.23 171.17,63.23
  BOTTOM w0.254: v2(166.46,61.9) 166.2,62.16 UC1.Y8
  BOTTOM w0.508: v2(187.1,79.38) 186.88,79.6 JSPI1.16
+3.3V_M_TPM: length 28.1
  TOP w0.102: v1(191.63,77.8) 190.97,77.14 CZ6.1
  TOP w0.508: CZ6.1 190.5,77.7 v2(190.24,77.95) ; CZ4.1 191.15,69.43 v2(190.88,69.7) ; CZ7.1 186.59,77.33 v2(186.59,77.95)
  IN2 w0.508: v2(190.24,77.95) 190.24,77.57 189.8,77.13 187.41,77.13 v2(186.59,77.95) 186.5,77.86 186.5,69.32 185.99,68.81 v2(185.99,68.36) 187.51,68.36 187.83,68.68 190.31,68.68 190.88,69.26 v2(190.88,69.7)
  BOTTOM w0.356: v2(186.59,77.95) 186.33,77.7 UZ1.19 ; UZ1.3 v2(190.88,69.7) ; UZ1.24 189.58,77.41 190.13,77.95 v2(190.24,77.95)
+3.3V_M_UZ8: length 1.2
  TOP w0.102: 221.22,64.82 221.22,65.2 v1(220.67,65.75)
+3.3V_MMI: length 5.3
  TOP w0.102: v2(283.4,23.47) 283.86,23.01 v3(283.86,22.77)
  TOP w0.203: UR1.11 281.04,29.11 v2(280.81,28.87) ; UR1.9 280.3,29.91 CR2.1
  TOP w0.457: RR6.1 v2(283.4,23.47)
  TOP w0.508: CR2.1 v2(279.78,30.07)
  vias: v2(280.48,26.83) v2(281.11,26.83) v2(281.68,27.09) v2(284.59,35.35) v2(286.7,25.18) v2(291.4,28.42)
+3.3V_RTC_LDO: length 113.4
  TOP w0.102: v2(260.92,11.47) v3(261.68,11.47)
  TOP w0.508: PD3.3 v2(293.62,8.7)
  IN4 w0.508: v2(293.62,8.7) 293.24,9.08 288.64,9.08 281.68,16.05 273.21,16.05 268.06,10.9 261.49,10.9 v2(260.92,11.47)
  BOTTOM w0.508: PR103.1 219.06,43.22 224.09,38.18 224.09,36.49 221.29,33.69 221.29,21.69 222.69,20.29 224.72,20.29 228.98,16.04 228.98,13.69 230.12,12.55 238.88,12.55 241.87,9.56 259.6,9.56 260.8,10.77 260.8,11.35 v2(260.92,11.47)
+3.3V_RUN: length 268.5
  TOP w0.102: v3(44.46,7.85) 44.63,8.01 v2(44.63,9.68)
  TOP w0.203: UV7.56 230.44,84.88 230.63,85.06 230.63,85.35 230.49,85.5 ; UV7.41 228.82,79.47 228.56,79.73 v2(228.33,79.73) ; CV604.1 232.96,71.69 UV600.57 ; UV7.28 221.74,79.68 CV62.1 ; UV600.5 228.83,74.18 v2(229.11,74.46) ; UV600.21 221.72,72.89 221.31,73.3 CV601.1 ; UV600.51 231.48,69.29 232.1,68.67 CV603.1 ; UV600.30 221.93,69.29 221.8,69.17 v2(221.8,68.81) ; v2(223.52,85.89) 223.52,86.08 223.64,86.21 223.9,86.21 224.02,86.09 UV7.14 ; PU500.20 107.37,66.83 v2(107.43,66.78) ; PU500.21 107.67,67.23 108.06,66.84 v2(108.06,66.78)
  TOP w0.254: RPE8.7 245.1,67.36 v2(244.84,67.1) 245.08,66.86 RPE8.8 ; RPE3.6 261.35,53.27 v2(261.59,53.51) 261.85,53.25 RPE3.5 ; RPE8.6 245.16,67.86 v2(244.9,68.12) 245.15,68.36 RPE8.5
  TOP w0.305: RV604.1 221.27,67.59 221.8,68.12 v2(221.8,68.81) ; JUSH1.8 256.66,10.16 256.66,12.66 v2(257.03,13.03) ; JLPDE1.2 271.06,60.63 v2(270.81,60.88) 270.56,60.62 JLPDE1.1 ; RV611.1 234.26,68.67 233.8,69.13 v2(233.3,69.13)
  TOP w0.381: 192.59,51.92 192.21,51.92 191.89,51.6 191.89,50.79 v2(191.54,50.44) ; RC156.2 174.42,65.95 v2(174.41,65.96) ; RV615.1 235.71,74.46 v2(236.15,74.02) 235.71,73.57 RV601.1 ; v2(226.98,95.26) 226.98,95.49 226.3,96.18 223.4,96.18 RV8.1 ; v2(189.59,51.09) 189.59,51.59 189.93,51.92 190.69,51.92
  TOP w0.406: UC5.5 187.74,73.92 v2(187.7,73.95)
  TOP w0.457: RV54.1 222.37,75.62 v2(221.79,75.03) ; v2(233.3,69.13) 232.84,68.67 CV603.1
  TOP w0.508: CC96.2 115.12,78.43 v2(116.41,77.15) ; RV605.1 v2(218.75,70.27) ; v2(234.88,72.24) 234.5,71.86 RV614.1 234.4,71.72 CV604.1 ; CC64.1 160.79,65.11 CC66.1 161.1,66.01 161.67,66.59 v2(161.67,66.87) ; RV51.1 RV511.1 v2(234.17,77.19) 234.17,76.77 232.75,75.35 RV603.1 ; v2(229.7,85.41) 229.79,85.5 230.49,85.5 ; v2(250.34,48.69) 250.16,48.86 RE67.1 ; RE51.1 248.97,43.35 249.35,42.97 v2(249.68,42.97) RE48.1 ; v2(187.7,73.95) 186.88,73.95 RC95.1 ; RV501.1 v2(281.18,71.6) ; RC163.1 RC176.1 RC164.1 172.48,78.98 175.5,82.01 v2(176.65,82.01) ; CV62.1 v2(221.97,79.1) ; RV613.1 v2(237.17,72.24) ; RV612.1 v2(237.17,68.05) ; CD31.1 CD32.1 143.04,17.94 v2(143.05,17.95) ; v2(226.98,95.26) 229.02,95.26 230.2,96.44 230.2,98.92 MIC1.6 ; v2(178.75,63.28) 178.37,62.9 RC180.1 RC66.1 178.41,62.01 RC247.2 ; v2(281.62,65.37) CV510.1 282.51,64.56 UV501.1 ; 146.75,78.84 145.67,78.84 145.29,78.46 v2(145.29,77.95) ; RV6.1 99.9,88.09 98.94,89.04 QV8.3 98.94,90.59 99.44,91.08 104.61,91.08 105.09,90.6 105.09,86.78 ; RV515.1 v2(233.61,84.43) ; PR516.2 98.73,67.98 PR519.1 v2(99.44,68.55) ; RV507.1 v2(281.49,68.44) ; v2(87.75,48.56) 87.63,48.69 RC122.1 ; CV601.1 220.6,73.19 v2(221.1,72.68)
  TOP w1.016: 109.41,79.16 106.93,81.64 106.93,82.21 105.85,83.29
  IN1 w0.508: v2(224.41,17.18) 237.23,17.18 237.93,17.88 244.98,17.88 246.12,16.74 v2(247.14,16.74)
  IN2 w0.381: v2(250.34,48.69) 254.18,48.69 255.06,49.57 256.79,49.57 259.78,52.55 260.63,52.55 v2(261.59,53.51)
  IN2 w0.508: v2(99.44,68.55) 96.58,68.55 93.41,65.38 93.41,63.91 91.01,61.51 90.79,61.51 v2(90.03,60.75) ; v2(94.42,41.12) 94.42,44.93 90.79,48.56 v2(87.75,48.56)
  IN3 w0.508: v2(112.14,13.95) 113,13.95 113.6,14.55 113.6,15.79 114.37,16.56 140.45,16.56 141.84,17.95 v2(143.05,17.95)
  BOTTOM w0.203: RPC20.5 168.21,83.98 168.72,84.49 169.16,84.49 169.42,84.24 169.42,84.05 v2(169.48,83.98) 169.48,83.79 169.71,83.57 RPC20.8
  BOTTOM w0.254: UC1.W9 165.75,62.91 UC1.V8 166.37,63.54 v2(166.37,63.84) ; v2(161.67,66.87) 161.99,67.18 UC1.K16 UC1.K14 ; UC1.U8 166.2,64.61 v2(166.37,64.79) UC1.T9 ; JEDP1.10 103.46,88.84
  BOTTOM w0.305: UN1.1 280.48,8.26 280.64,8.42 280.64,9.49 280.4,9.73 CN1.1 ; RV610.1 228.17,72.86 229.09,73.77 CV600.1 ; 277.75,4.77 UN1.8 ; 278.25,4.71 UN1.7 ; CN2.1 278.22,10.29 278.22,10.16 277.75,9.7 277.75,8.74 UN1.14
  BOTTOM w0.356: v2(222.94,18.49) 222.66,18.49 222.3,18.13 JDIMM2.199 ; JDIMM1.199 140.8,17.55 141.21,17.95 v2(143.05,17.95) ; CV514.1 287.59,68.24 286.35,69.48 UV502.14
  BOTTOM w0.508: CV600.1 229.17,74.4 v2(229.11,74.46) ; 278.43,12.5 278.28,12.34 278.28,11.42 278.2,11.34 CN2.1 ; 278.43,12.5 281.09,12.5 281.43,12.15 281.43,10.6 280.98,10.16 CN1.1 ; 278.43,12.5 278.31,12.5 v2(277.37,13.44) ; v2(233.19,80.57) 233.56,80.94 RV57.1 ; v2(226.35,75.14) 226.35,75.14 226.35,76.77 226.71,77.13 CV61.1 RV68.1 ; RN2.1 v2(276.53,14.65) ; RC160.1 RC158.1 175.21,69.24 v2(174.94,69.51) ; RV58.1 CV66.1 228.67,77.13 229.7,76.1 v2(229.7,75.17) ; RC68.1 174.46,65.91 v2(174.41,65.96) ; v2(103.38,86.4) 103.38,88.76 103.46,88.84 ; RV602.1 221.92,75.16 v2(221.79,75.03) ; v2(221.8,68.81) 221.82,68.8 CV602.1 ; v2(285.94,67.98) 286.12,67.8 CV514.1 ; v2(235.19,82.63) 235.4,82.84 RV60.1 CV69.1 ; RV55.1 RV56.1 221.56,78.37 v2(221.26,78.07) ; RN4.1 v2(280.87,3.62) ; v2(117.14,73.07) PR400.1
  vias: v2(45.25,9.7) v2(109.15,78.27) v2(109.79,78.27) v2(116.41,76.52) v2(163.07,83.48) v2(176.15,63.89) v2(178.6,68.45) v2(178.6,67.41) v2(179.19,68.45) v2(179.19,67.41) v2(183.29,65.86) v2(183.77,66.97) v2(216.52,77.52) v2(217.12,77.52) v2(220.14,37.64) v2(220.14,37.04) v2(220.84,37.64) v2(220.84,37.04) v2(221,62.13) v2(221,61.54) v2(221.54,37.64) v2(221.54,37.04) v2(222.23,37.64) v2(222.23,37.04) v2(222.93,37.64) v2(222.93,37.04) v2(247.08,18.52) v2(247.8,18.33) v2(248.38,18.31) v2(272.84,13) v2(273.48,13.63) v2(273.48,13) v2(276.9,4.24) v2(277.49,25.5) v2(277.49,24.89) v2(277.49,24.29) v2(277.49,4.25)
+3.3V_RUN_AUDIO: length 66.1
  TOP w0.102: v3(25.89,8.94) 26.1,8.74 RA4.1
  TOP w0.508: v2(37.72,26.77) 37.64,26.85 RA26.1 RA38.2 ; RA4.1 27.43,7.56 v2(27.81,7.17) ; v2(42.29,26.07) 42.29,25.82 41.97,25.5 RA29.1 ; RA45.2 v2(29.72,25.08)
  IN1 w0.508: v2(39.49,11.28) 38.35,10.13 37.27,10.13 36.89,9.75 29.02,9.75 27.81,8.55 v2(27.81,7.17) ; v2(40.13,11.28) 40.13,11.66 39.75,12.04 39.75,13.05 v2(38.27,14.52) 37.84,14.95 37.84,17.82 38.27,18.25 v2(38.27,19.73) 42.29,23.74 v2(42.29,26.07) ; v2(29.72,25.08) 29.72,26.85 30.45,27.58 36.9,27.58 v2(37.72,26.77)
  IN3 w0.508: v2(42.29,26.07) 41.84,26.52 37.97,26.52 v2(37.72,26.77)
  BOTTOM w0.254: v2(27.81,7.17) 27.76,7.23 27.76,10.44 23.17,15.02 RA1.1
+3.3V_RUN_CARD: length 17.8
  TOP w0.127: v2(272.95,32.17) v3(272.95,31.51)
  IN2 w1.016: 272.37,31.6 272.37,29.25 273.8,27.83 275.61,27.83 277.07,26.36 278.13,26.36 279.5,24.99 284.73,24.99 285.24,25.5
  vias: v2(272.93,32.78) v2(285.81,26.44) v2(286.42,26.44)
+3.3V_RUN_UN3:
  vias: v1(252.6,19.57)
+3.3V_RUN_UZ9: length 2.8
  TOP w0.102: v1(218.09,37.13) 219.06,38.1 219.06,38.68 218.49,39.26 CZ44.1
+3.3V_RUN_VDDA: length 5.4
  TOP w0.102: v2(210.75,79.6) 211.08,79.6 211.67,80.19 v3(211.67,80.57)
  TOP w0.203: UV8.H5 v2(207.89,74.91) ; UV8.H12 v2(207.89,80.11) ; UV8.C10 v2(203.99,78.81) ; UV8.J4 v2(208.54,74.26) ; UV8.K7 v2(209.19,76.21) ; UV8.K6 v2(209.19,75.56)
  BOTTOM w0.508: CV98.1 208.39,80.83 207.89,80.32 v2(207.89,80.11)
+3.3V_RUN_VDDIO: length 7
  TOP w0.203: UV8.C11 v2(203.99,79.46) ; UV8.K12 v2(209.19,80.11) ; UV8.C3 v2(203.99,73.61) ; UV8.C12 v2(203.99,80.11) ; UV8.C4 v2(203.99,74.26) ; UV8.K4 v2(209.19,74.26) ; UV8.K11 v2(209.19,79.46)
  TOP w0.254: v2(203.34,75.56) 203.34,75.56 203.66,75.89 UV8.B6 ; UV8.K3 208.86,73.94 v2(209.19,74.26) ; UV8.B5 v2(203.34,74.91)
  BOTTOM w0.457: CV96.1 209.73,74.26 v2(209.19,74.26)
  BOTTOM w0.508: CV97.1 203.88,73.51 v2(203.99,73.61) ; CV95.1 203.56,80.11 v2(203.99,80.11)
  vias: v1(209.81,79.7)
+3.3V_RUN_VMM: length 83.5
  TOP w0.508: RV83.2 RV84.2 201.28,67.55 v2(201.02,67.29) 201.02,67.28 200.8,67.06 200.12,67.06 199.5,67.68 RV516.2 ; v2(209.66,83.29) 209.66,83.55 208.91,84.3 RV82.2 ; RV86.1 197.36,73.32 v2(197.1,73.06) ; 197.41,80.31 196.14,80.31 195.69,79.86 195.69,78.41 196.2,77.9 RV85.2 198.35,76.29 v3(197.75,75.69) 196.76,74.71 196.76,74.69 195.2,73.13 v2(193.93,73.13) ; v2(200.61,83.57) 200.56,83.62 200.56,84.94 201.03,85.41 RV518.1 RV519.1 ; RV88.1 215.26,75.3 v2(215.26,75.79)
  IN2 w0.508: v2(216.33,81.33) v2(216.33,81.96) v2(216.33,82.6) 213.66,85.26 v2(212.44,85.26) 211.63,85.26 v2(209.66,83.29) 209.05,82.68 202.59,82.68 201.71,83.57 v2(200.61,83.57) 200.47,83.57 199.9,83 199.9,81.89 197.91,79.91 197.91,75.81 ; 197.91,75.13 197.91,73.87 v2(197.1,73.06) 195.65,73.06 195.51,73.2 194,73.2 v2(193.93,73.13) 193.93,71.98 197.5,68.41 200.7,68.41 201.02,68.09 v2(201.02,67.29)
  BOTTOM w0.381: v2(209.66,83.29) 209.47,83.48 209.47,83.82 209.66,84.01 UV11.14 ; CV121.1 199.64,86.97 199.55,86.87 UV12.14
  BOTTOM w0.457: v2(200.61,83.57) 200.47,83.57 200.21,83.83 200.21,86.02 200.71,86.51 CV121.1
  BOTTOM w0.508: v2(201.02,67.29) 201.02,67.87 202.41,69.25 RV517.1 ; UV9.8 194.94,74.52 194.23,73.81 CV114.1 v2(193.93,73.13) RV87.1 ; CV118.1 209.9,83.05 v2(209.66,83.29)
+3.3V_SPI: length 51.2
  TOP w0.508: RC31.1 189.11,59.48 189.54,59.92 189.54,60.24 v2(189.61,60.3) 191.26,60.3 v3(193.08,58.48) v2(194.31,57.25) ; v2(187.13,81.89) 186.86,81.62 RC231.2 ; v2(190.88,65.76) 190.33,65.21 188.35,65.21 RC29.1
  IN1 w0.508: v2(190.88,65.76) 190.43,65.32 190.43,61.06 189.61,60.24 v2(189.61,60.3)
  IN2 w0.508: v2(190.88,65.76) 192.02,66.9 192.02,73 193.16,74.14 194.05,74.14 195.07,75.16 195.07,77.51 191.45,81.13 187.64,81.13 187.13,81.64 v2(187.13,81.89)
  BOTTOM w0.508: UC2.8 190.61,61.58 190.31,61.89 189.74,61.89 189.15,61.3 CC6.1 188.91,61 v2(189.61,60.3) ; JSPI1.15 186.38,82.64 v2(187.13,81.89) ; v2(194.31,57.25) 194.94,56.62 195.69,56.62 CC7.1 194.42,58.4 UC3.8
+3.3V_SUS: length 196.6
  TOP w0.102: v3(187.54,92.86) 187.06,93.34 v2(187.06,94.23)
  TOP w0.203: UI4.3 181.98,94.93 CI419.1 ; UI4.29 179.62,98.04 CI418.1 ; UI4.9 184.38,95.61 184.26,95.49 184.26,95.05 CI416.1 ; CI414.1 187.36,96.84 UI4.12 ; UI4.16 186.61,98.44 186.99,98.83 v2(186.99,98.85) ; UI4.20 183.98,100.22 184.38,100.62 CI415.1
  TOP w0.508: CI414.1 187.63,96.32 v2(186.99,96.32) ; CI415.1 183.88,100.82 v2(183.69,101.01) ; CI416.1 v2(185.4,94.55) ; CI418.1 178.69,98.61 v2(178.23,98.15) ; CI419.1 181.16,94.74 v2(181.09,94.66) ; 254.39,13.27 RZ9.1 RZ8.1
  IN2 w1.016: 249.79,27.73 249.79,27.71 256.45,27.71 257.36,28.62 264.83,28.62 267.42,31.22 267.42,33.63 268.68,34.89 270.01,34.89 274.6,39.48 274.6,45.02 266.3,53.32 266.3,58.15 265.64,58.81 265.64,63.58 265.2,64.02 265.2,70.37 259.34,76.24 256.35,76.24 255.39,77.19 246.57,77.19 242.5,81.25 v2(242.5,83.16) 242.88,83.54 242.88,88.14 239.42,91.6 237.74,91.6 234.38,94.97 231.98,94.97 230.57,96.38 221.07,96.38 219.53,94.84 203.24,94.84 200.57,92.17 189.1,92.17 187.7,93.57
  IN2 w1.524: 255.03,14.22 256.14,15.34 256.14,19.05 254.87,20.32 254.85,20.32 248.65,26.52
  BOTTOM w0.254: UI5.10 CI38.1
  BOTTOM w0.508: CI38.1 241.68,83.73 242.25,83.16 v2(242.5,83.16)
  vias: v2(187.06,94.82) v2(246.05,26.18) v2(246.68,26.18) v2(247.32,26.19) v2(255.19,12.99) v2(255.51,13.49) v2(255.83,12.99)
+3.3V_SUS_UL3: length 2.1
  TOP w0.102: v1(248.3,27.51) 246.92,28.88 UL3.14
+3.3V_TP: length 3.2
  TOP w0.102: RZ18.1 v3(248.55,22)
  TOP w0.305: JKBTP1.5 245.25,21.1
  TOP w0.508: 246.41,21.06 245.28,21.06 245.25,21.1
+3.3V_TSP: length 5
  TOP w0.102: v3(96.78,93.84) 96.99,93.64 CZ2.1
  TOP w0.508: v2(97.98,89.92) QV8.1 CZ2.1
+3.3V_VMM_UV10: length 1.3
  BOTTOM w0.127: 219.69,78.43 219.9,78.43 220.58,79.12 v1(220.72,79.12)
+3.3V_WLAN: length 16.1
  TOP w0.102: CZ18.2 242.85,12.44 v3(242.05,11.63)
  IN2 w2.032: 241.17,29.18 241.93,28.42 241.93,15.02
  vias: v2(242.12,33.63) v2(242.12,32.99) v2(242.76,33.63) v2(242.76,32.99) v2(243.2,13.06) v2(243.84,13.06) v2(244.47,13.06) v2(245.11,13.06)
+3.3V_WLAN_UL3:
  vias: v1(246.77,33.02)
+3.3V_WWAN: length 1.6
  TOP w0.102: v3(244.96,73.6) 244.47,73.6 244.22,73.34
  TOP w0.508: RZ39.1 v2(242.57,62.97)
  vias: v2(240.73,53.44) v2(241.03,72.75) v2(241.03,72.12) v2(241.11,54.65) v2(241.11,54.01) v2(241.42,53.44) v2(241.74,54.65) v2(241.74,54.01)
+3.3V_WWAN_UZ2: length 1.6
  TOP w0.102: v1(238.29,55.47) 239.28,56.46 CZ24.1
+3V5V_PWR_SRC: length 15.8
  TOP w0.102: v4(217.51,60.2) 217.51,61.47 v3(217.15,61.82)
  TOP w0.203: PU100.12 218.68,51.61 219,51.92 v2(219,52.12)
  IN2 w0.508: v2(219,52.12) 220.79,52.12 222.31,53.63 222.31,57.57 221.03,58.85 v4(218.87,58.85)
  BOTTOM w0.508: v2(219,52.12) 219.44,51.67 PC117.1
  vias: v4(217.5,59.51) v4(217.5,58.81) v4(218.17,59.51) v4(218.17,58.81) v4(218.18,60.2) v4(218.87,59.54) v4(218.88,60.24) v4(219.57,58.2)
+5V_ALW: length 447.2
  TOP w0.203: UZ8.4 v2(224.33,60.88) ; v2(249.67,30.09) 249.66,30.08 UL3.4 ; v2(243.57,58.15) 243.44,58.02 UZ2.4 ; UZ9.4 217.09,43.99 216.84,44.24 216.14,44.24 215.95,44.05
  TOP w0.254: UZ7.4 203.75,47.79 204.2,47.33 204.2,44.02 205.25,42.97 206.87,42.97 ; UN3.4 249.65,16.95 249.4,16.7 v2(249.4,15.72)
  TOP w0.305: JLED1.1 266.15,11.76 265.99,11.92 v2(265.64,11.92)
  TOP w0.381: PU1.5 73.28,103.94 PR11.1 v2(74.17,103.73)
  TOP w0.508: RD9.1 149.97,19.96 147.63,17.63 147.63,10.45 v2(148.14,9.94) ; v2(73.07,65.81) CC95.2 ; PR526.2 v2(104,73.26) 104,75.8 102.35,77.45 96.07,77.45 95.12,78.4 95.12,79.29 92.77,81.64 v3(91.95,81.64) 91.05,81.64 v2(90.22,82.47) ; LED3.2 v2(297.76,87.55) ; PR204.2 v2(62.85,7.17) ; v2(281.84,39.48) 281.94,39.59 CI19.1 ; RZ21.1 271.35,37.41 270.84,37.91 v2(269.77,37.91) ; PC20.1 74.28,102.04 v2(74.27,102.06) ; RZ5.1 150.92,84.29 149.92,83.29 v2(148.33,83.29) ; CC94.1 89.4,82.28 v2(89.58,82.47) ; v2(81.72,29.95) 81.72,29.31 81.4,28.99 PR843.2 ; PR202.1 v2(64.07,7.66) ; RI13.2 v2(289.57,39.66)
  IN1 w0.508: v2(104,73.26) 104,74.09 104.7,74.78 115.54,74.78 v2(115.6,74.72)
  IN2 w0.508: v2(115.6,74.72) 117.53,74.72 121,71.25 123.92,71.25 125.79,73.13 125.79,76.75 126.53,77.48 126.53,79.16 126.24,79.45 126.24,81.89 128.71,84.37 133.22,84.37 133.66,84.81 141.16,84.81 143.76,82.21 147.44,82.21 148.33,83.1 v2(148.33,83.29) ; v2(269.77,37.91) 268.27,36.41 266.3,36.41 264.23,34.33 264.23,32.7 262.5,30.97 254.32,30.97 253.44,30.09 v2(249.67,30.09) 249.41,30.09 247.86,28.54 245.77,28.54 244.04,26.81 244.04,24.61 244.42,24.23 244.42,15.81 245.93,14.3 245.93,10.67 245.44,10.17 v2(245.21,10.17) ; v2(201.37,64.71) 202.28,65.62 221.5,65.62 222.9,64.23 222.9,62.57 224.33,61.14 v2(224.33,60.88) 224.33,60.54 224.62,60.25 225.69,60.25 226.13,60.69 230.05,60.69 234.38,56.36 234.38,50.42 232.32,48.36 232.32,47.24 228.99,43.92 223.5,43.92 218.74,39.16 214.38,39.16 v2(212.85,37.63)
  IN2 w2.032: 85.6,42.52 85.6,44.93 83.31,47.22 77.85,47.22 ; 208.15,37.31 203.71,37.31 201.93,39.09 165.92,39.09 164.04,37.21 90.78,37.21 88.39,39.6
  IN3 w0.508: v2(87.25,40.49) 87.75,39.98 87.75,37.25 86.1,35.6 86.1,32.23 85.53,31.66 84.26,31.66 82.55,29.95 v2(81.72,29.95) ; v2(216.21,75.51) 216.21,75.35 217.64,73.93 219.53,73.93 220.43,73.02 220.43,63.68 221.65,62.46 223.01,62.46 224.33,61.14 v2(224.33,60.88)
  IN4 w0.508: v2(224.33,60.88) 224.33,61.3 224.6,61.57 225.3,61.57 225.74,61.12 229.64,61.12 234.17,56.6 241.96,56.6 243.51,58.15 v2(243.57,58.15)
  BOTTOM w0.203: UV10.4 216.25,75.55 v2(216.21,75.51)
  BOTTOM w0.508: v2(249.41,11.94) 249.4,11.95 v2(249.4,15.72) ; PU400.6 114.86,73.83 115.05,74.02 PC400.1 v2(115.6,74.72) ; v2(201.37,64.71) RV210.1
  vias: v2(72.2,48.55) v2(72.2,47.92) v2(72.77,48.87) v2(72.77,48.23) v2(89.6,83.1) v2(90.23,83.1) v2(209.67,37.63) v2(209.67,36.99) v2(210.31,37.63) v2(210.31,36.99) v2(210.94,37.63) v2(210.94,36.99) v2(211.58,37.63) v2(211.58,36.99) v2(212.21,37.63) v2(212.21,36.99) v2(212.85,36.99) v2(259.76,93.26) v2(259.76,92.63) v2(260.4,93.26) v2(260.4,92.63) v2(284.85,39.71) v2(285.43,39.71) v2(286.01,39.7) v2(286.61,39.62) v2(289.86,43.12) v2(289.87,42.53) v2(290.47,42.77) v3(207.48,41.38) v3(213.52,42.93)
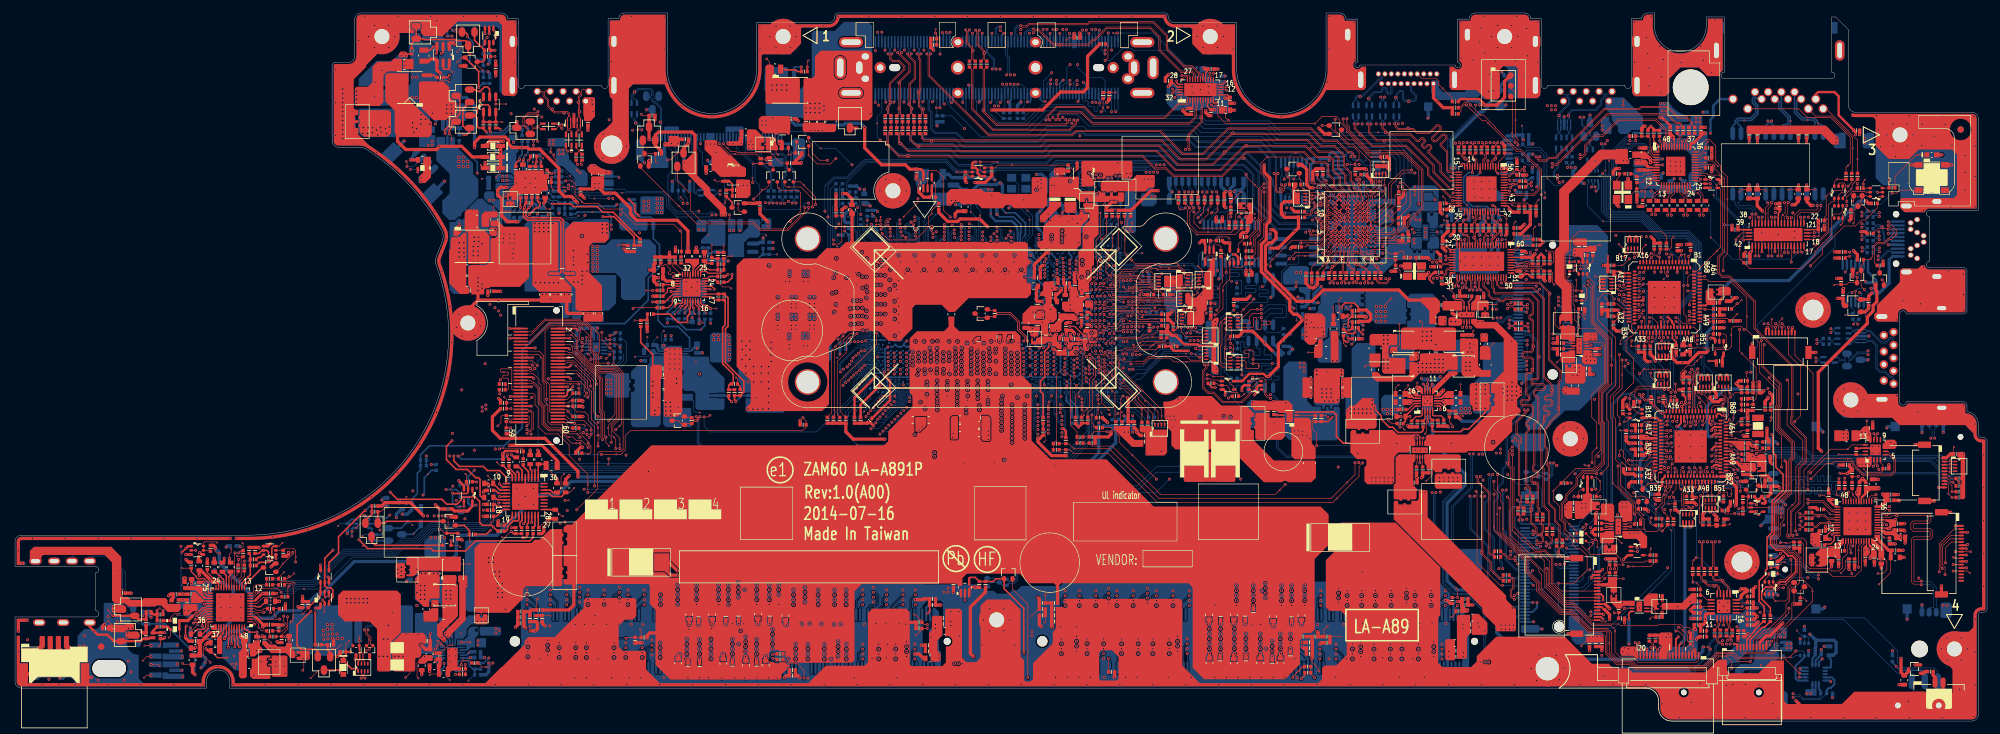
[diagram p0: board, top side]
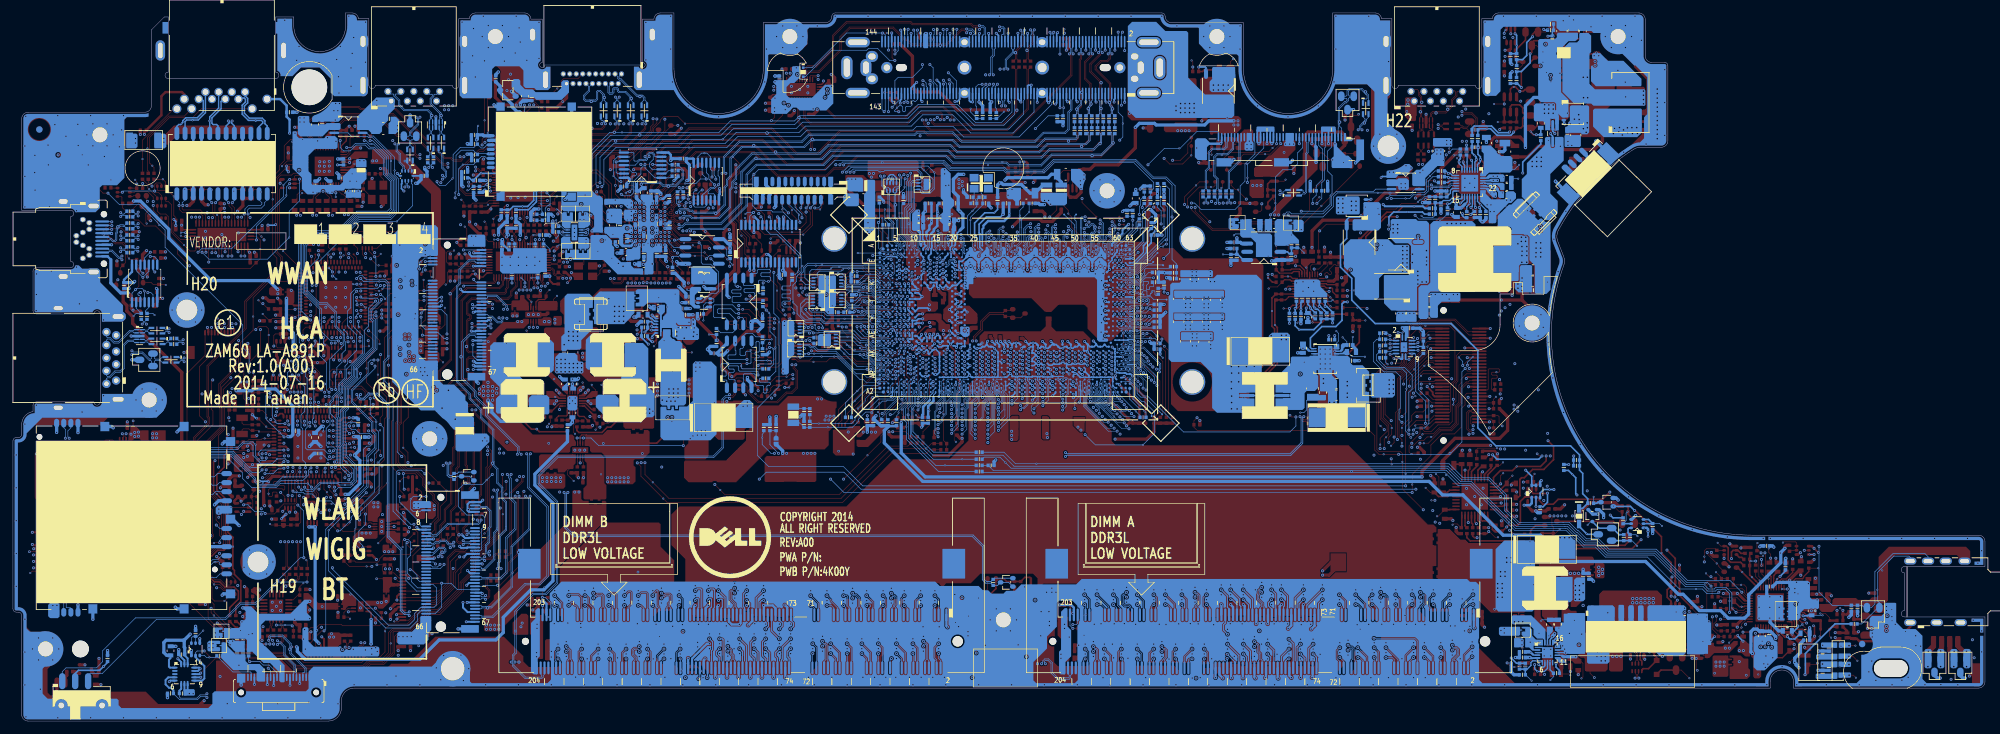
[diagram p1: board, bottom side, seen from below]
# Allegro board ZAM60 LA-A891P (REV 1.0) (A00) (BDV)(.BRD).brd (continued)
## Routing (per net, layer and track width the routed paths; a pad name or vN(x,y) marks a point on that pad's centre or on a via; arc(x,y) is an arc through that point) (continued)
+5V_ALW2: length 2.6
  TOP w0.102: v2(218.28,52.12) v3(218.28,52.87)
  TOP w0.203: PU100.13 v2(218.28,52.12)
  BOTTOM w0.508: PC118.1 218.28,51.53 v2(218.28,52.12)
+5V_ALW_UZ5: length 2
  TOP w0.508: UZ5.1 269.41,36.42 269.54,36.3 CZ35.1 RZ21.2
+5V_ALWP: length 25.8
  TOP w0.203: v2(217.6,52.12) 217.88,51.83 PU100.14
  TOP w0.254: PR101.2 217.6,44.93 217.29,44.63 213.73,44.63 212.9,45.45 212.37,45.45 211.13,46.68 211.13,47.22 210.23,48.12 210.23,48.69 209.98,48.94 v4(209.74,48.94)
  IN4 w0.508: v4(209.53,47.61) 210.75,46.39 216.28,46.39 217.17,47.28 217.17,50.38 217.65,50.86 217.65,52.06 v2(217.6,52.12)
  vias: v3(205.85,47.92) v4(206.36,48.24) v4(206.36,47.61) v4(206.99,48.24) v4(206.99,47.61) v4(207.63,48.24) v4(207.63,47.61) v4(208.26,48.24) v4(208.26,47.61) v4(208.9,48.24) v4(208.9,47.61) v4(209.53,48.24) v4(209.74,49.63)
+5V_HDD:
  vias: v3(269.82,8.62)
+5V_RUN: length 361.7
  TOP w0.254: RPE2.7 258.74,30.28 v2(259,30.02) 259.24,30.26 RPE2.8 ; RPE2.5 257.74,30.32 v2(258.05,30.02) 258.24,30.21 RPE2.6 ; JUSH1.7 257.17,11.73 v2(257.48,12.04)
  TOP w0.305: JKBTP1.12 245.22,17.6 245.58,17.25
  TOP w0.508: QV501.2 287.51,66.66 287.72,66.46 287.72,64.84 287.14,64.27 287.14,63.41 286.24,62.51 286.24,61.49 278.66,53.91 278.66,42.21 v2(279.17,41.71) ; 245.58,17.25 245.63,17.25 246.41,16.46 v2(246.41,15.72)
  IN2 w0.508: v2(279.17,41.71) 279.17,41.36 270.66,32.85 270.66,26.66 271.5,25.82 271.5,18.35 271.97,17.88 272.03,17.88 274.44,15.47 v2(274.44,11.98) ; 258.25,7.98 258.24,7.99 258.24,11.16 257.48,11.92 v2(257.48,12.04) ; v2(246.41,15.72) 246.62,15.51 246.62,8.97 246.41,8.76 ; v2(105.39,57.64) 105.39,59.78 104.25,60.92 94.16,60.92 92.83,59.6 92.83,55.09 91.44,53.7 71.5,53.7 v2(69.02,51.22)
  IN2 w1.016: 222.95,84.81 223.69,84.06 223.69,80.84 225.71,78.82 229.93,78.82 231.23,77.52 231.23,71.18 228.74,68.7 228.74,67.26 229.68,66.33 233.55,66.33 235.33,64.55 235.33,47.73 233.08,45.48 233.08,41.37 230.77,39.06 226.92,39.06 226.63,38.77 219.83,38.77 218.75,37.69 218.75,37.19 217.93,36.36
  IN4 w1.016: 63.45,83.82 63.61,83.98 63.61,85.88 65.87,88.14 70.24,88.14 71.02,87.36 73.48,87.36 74.05,86.79 76.49,86.79 77.66,85.62 80.05,85.62 85.27,80.4 85.27,67.72 86.47,66.51 86.47,65.58 85.8,64.91 79.3,64.91 69.02,54.63 v2(69.02,51.22) 69.02,47.43 66.22,44.63 66.22,40.03 64.26,38.07 64.26,34.65 51.5,21.88 51.5,20.65 48.99,18.15 48.99,17.41 46.92,15.34 45.34,15.34 44.51,14.52 44.51,12.93 41.65,10.07
  BOTTOM w0.508: 222.08,86.21 222.1,86.22 222.1,88.77 221.93,88.94 221.93,89.7 226.44,94.21 226.84,94.21 227.59,94.97 227.59,95.34 229.47,97.21 UV2.1 229.47,98.18 CV23.1 ; v2(259,30.02) v2(258.05,30.02) 258.05,12.61 v2(257.48,12.04)
  vias: v2(40.31,9.13) v2(40.31,8.49) v2(40.94,9.13) v2(40.94,8.49) v2(41.58,9.13) v2(41.58,8.49) v2(62.74,84.05) v2(62.74,83.41) v2(217.28,35.41) v2(217.93,35.41) v2(221.93,85.57) v2(222.53,85.57) v2(229.68,14.83) v2(229.68,14.2) v2(230.31,14.83) v2(230.31,14.2) v2(230.95,14.83) v2(230.95,14.2) v2(231.58,14.83) v2(231.58,14.2) v2(273.83,11.98) v2(273.83,11.34) v2(274.44,11.34) v3(41.78,7.4)
+5V_RUN_AUDIO: length 23.2
  IN2 w0.635: v2(37.97,9.18) 37.46,9.69 29.72,9.69 28.81,10.59 28.81,11.61 25.08,15.34 25.08,19.79 26.21,20.92 v2(26.21,22.08)
  vias: v3(36.89,7.09)
+5V_RUN_PVDD: length 8.2
  BOTTOM w0.508: v2(32.34,12.78) 32.34,13.07 33.13,13.86 CA47.1 33.4,13.89 CA46.1 34.88,13.89 35.21,14.22 35.77,14.22 36.17,13.83 36.17,10.68 v2(35.94,10.45)
  vias: v1(35.05,7.21)
+5V_RUN_UZ9:
  vias: v1(213.88,38.15)
+5V_USB_CHG_PWR: length 1.1
  TOP w0.102: v3(286.18,46.42) 286.18,45.31
  vias: v2(285.35,44.69) v2(285.35,44.05) v2(285.94,44.63) v2(285.94,44) v2(286.51,44.36)
+GND_CHASSIS:
  vias: v2(281.43,90.09) v2(281.43,89.51)
+V1.05S_APLLOPI: length 2.6
  TOP w0.102: v3(172.62,77.08) 172.62,76.52 v2(172.34,76.24)
  BOTTOM w0.254: v2(158.73,63.24) 159.1,62.87 UC1.W21 159.1,62.79 v2(158.72,62.42) 159.1,62.04 UC1.AA21
  vias: v2(172.02,75.73) v2(172.65,75.73)
+V1.05SP_B+:
  vias: v1(202.42,66.01)
+VCC_CORE: length 73.2
  TOP w0.508: v2(129.03,79.1) 129.35,78.78 CC79.2 129.35,73.76
  BOTTOM w0.127: 155.98,70.47 155.98,70.14 UC1.G25 ; 154.51,70.13 UC1.F28 ; UC1.F28 154,70.64 ; UC1.F28 154.54,70.67 154.54,70.82 v2(154.39,70.97) ; UC1.F28 154,70.13 ; UC1.F48 141.46,70.64 ; UC1.F48 141.46,70.13 ; UC1.F48 142.02,70.69 142.02,70.81 v2(141.85,70.98) ; UC1.F48 141.97,70.13 ; UC1.F24 157.03,70.65 157.03,70.8 v2(156.88,70.96) ; UC1.F24 156.51,70.64 ; UC1.F24 157.01,70.13 ; UC1.F24 156.51,70.13 ; UC1.G35 149.64,69.77 149.46,69.77 ; UC1.G35 150.1,69.89 150.1,69.62 v2(149.93,69.45) ; UC1.G35 150.1,70.23 150.1,70.47 ; UC1.G35 149.59,70.39 149.59,70.4 ; UC1.G53 138.81,70.35 138.81,70.36 ; UC1.G53 138.55,70.06 138.81,69.79 ; UC1.G53 138.43,70.14 138.43,70.49 ; UC1.G53 v2(138.52,69.45) ; UC1.G33 151.01,70.11 151.01,70.49 ; UC1.G33 151.01,70.01 151.01,69.5 v2(151.06,69.45) ; UC1.G33 151.34,69.77 151.43,69.77 ; UC1.G33 151.29,70.29 ; UC1.G49 141.33,70.37 141.33,70.4 ; UC1.G49 140.91,69.94 140.91,69.56 v2(141.03,69.45) ; UC1.G49 141.25,69.83 141.53,69.83 ; UC1.G49 140.91,70.17 140.91,70.55 ; UC1.F56 136.45,70.13 ; UC1.F56 136.45,70.64 ; UC1.F56 136.99,70.67 136.99,70.83 v2(136.84,70.98) ; UC1.F56 136.95,70.13 ; 137.1,70.36 137.39,70.07 UC1.G55 ; 146.48,69.9 146.2,69.9 UC1.G41 ; 157.25,66.89 UC1.M23 ; UC1.M23 UC1.L22 UC1.K23 ; UC1.M23 157.67,67.31 UC1.K23 ; 157.65,70.4 157.65,70.26 UC1.G23 ; UC1.G29 153.79,69.83 153.97,69.83 ; UC1.G29 153.44,69.94 153.44,69.56 v2(153.56,69.45) ; UC1.G29 153.44,70.17 153.44,70.52 ; UC1.G29 153.84,70.34 153.84,70.4 ; v2(155.96,69.34) 155.96,69.94 UC1.G25 ; UC1.G31 152.42,70.06 152.1,69.74 ; UC1.G31 152.53,70.15 152.53,70.5 ; UC1.G31 v2(152.44,69.45) ; UC1.G31 152.44,70.06 152.17,70.32 ; 147.37,70.47 147.42,70.41 UC1.G39 ; 138.95,70.13 UC1.F52 ; UC1.F52 139.51,70.68 139.51,70.82 v2(139.34,70.98) ; UC1.F52 138.95,70.64 ; UC1.F52 139.46,70.13 ; UC1.F36 149.54,70.68 149.54,70.82 v2(149.37,70.98) ; UC1.F36 148.98,70.64 ; UC1.F36 148.98,70.13 ; UC1.F36 149.49,70.13 ; 146.35,70.37 UC1.G41 ; UC1.G41 146.04,70.05 145.93,69.94 145.93,69.56 v2(146.04,69.45) ; UC1.G41 145.93,70.17 145.93,70.45 146,70.52 ; UC1.F32 151.49,70.64 ; UC1.F32 152,70.13 ; UC1.F32 152.05,70.69 152.05,70.83 v2(151.9,70.98) ; UC1.F32 151.49,70.13 ; 144.64,70.33 UC1.G43 ; UC1.G43 145.04,69.93 145.04,69.57 v2(144.91,69.45) ; UC1.G43 144.69,69.83 144.45,69.83 ; UC1.G43 145.02,70.16 145.02,70.53 ; 157.15,70.36 UC1.G23 ; UC1.G23 157.23,69.83 157.08,69.83 ; UC1.G23 157.71,69.8 157.67,69.75 UC1.H23 ; UC1.G51 140.02,70.18 140.02,70.49 ; UC1.G51 139.89,70.06 139.65,70.3 ; UC1.G51 139.9,70.05 139.64,69.79 ; UC1.G51 140.02,69.93 140.02,69.57 v2(139.9,69.45) ; 157.25,67.71 UC1.K23 ; UC1.K23 UC1.J23 ; UC1.G47 142.5,69.97 142.5,69.54 v2(142.41,69.45) ; UC1.G47 142.53,70.18 142.53,70.5 ; UC1.G47 142.38,70.06 142.05,69.72 ; UC1.G47 142.41,70.07 142.12,70.36 ; 143.97,70.13 UC1.F44 ; UC1.F44 144.51,70.67 144.51,70.83 v2(144.36,70.98) ; UC1.F44 143.97,70.64 ; UC1.F44 144.48,70.13 ; 155.06,70.5 155.06,70.18 UC1.G27 ; 156.4,70.23 156.25,70.23 UC1.G25 ; UC1.F40 146.98,70.13 ; UC1.F40 147.03,70.68 147.03,70.82 v2(146.87,70.98) ; UC1.F40 146.48,70.64 ; UC1.F40 146.48,70.13 ; 143.41,70.52 143.41,70.18 UC1.G45 ; 148.85,70.36 148.55,70.06 UC1.G37 ; 148.85,69.79 148.58,70.06 UC1.G37 ; UC1.G45 143.76,69.83 144,69.83 ; UC1.G45 143.81,70.33 ; UC1.G45 143.44,69.96 143.44,69.54 v2(143.53,69.45) ; 148.47,70.49 148.47,70.14 UC1.G37 ; 137.48,70.49 137.48,70.15 UC1.G55 ; UC1.G55 137.54,69.9 137.54,69.6 ; UC1.G55 137.37,70.06 137.1,69.79 ; UC1.G39 147.42,69.95 147.18,69.7 ; UC1.G39 147.02,70.06 146.99,70.02 ; UC1.G25 156.4,69.72 156.4,69.72 ; UC1.G27 154.61,70.39 154.61,70.4 ; UC1.G27 155.01,69.99 v2(155.01,69.41) ; UC1.G27 154.72,69.83 154.61,69.83 ; UC1.H23 UC1.J23 ; UC1.H23 157.23,69.33 ; UC1.J23 157.3,68.52 ; 136.27,69.79 136.01,70.05 ; 136.01,70.05 136.01,69.67 136.02,69.66 ; 136.01,70.05 UC1.G57 ; UC1.G57 135.83,70.24 135.83,70.42 ; UC1.G57 136.03,70.06 136.27,70.3 ; UC1.G37 v2(148.55,69.45)
  BOTTOM w0.229: UC1.F59 134.76,70.15 v2(134.46,70.45)
  BOTTOM w0.254: v2(136.59,60.14) 136.5,60.23 UC1.AD57 ; UC1.M57 136.26,66.73 v2(136.27,66.74) ; v2(136.52,68.11) 136.45,68.03 UC1.K57 ; UC1.AB57 136.46,61.53 v2(136.53,61.6) ; v2(136.53,64.14) 136.52,64.13 UC1.U57 ; v2(136.53,62.87) 136.49,62.83 UC1.W57 ; v2(136.27,59.06) 136.14,58.93 UC1.AG57 ; v2(136.34,65.34) 136.25,65.43 UC1.P57
  BOTTOM w0.508: v2(129.03,79.1) 128.94,79.1 128.15,78.31 128.15,77.3 128.38,77.08 RC209.1
  vias: v2(117.87,61.16) v2(117.87,60.57) v2(117.88,64.58) v2(117.88,63.98) v2(119.06,67.96) v2(119.66,58.19) v2(119.66,57.59) v2(119.69,67.96) v2(120,64.52) v2(120,63.92) v2(120,61.18) v2(120,60.58) v2(120.67,64.52) v2(120.67,63.92) v2(120.69,61.18) v2(120.69,60.58) v2(121.83,67.98) v2(121.84,58.01) v2(122.54,67.97) v2(122.48,58.01) v2(122.81,64.55) v2(122.81,63.96) v2(122.81,61.21) v2(122.81,60.62) v2(123.53,64.55) v2(123.53,63.96) v2(123.53,61.21) v2(123.53,60.62) v2(136.27,69.22) v2(137.48,69.15) v2(147.44,69.38) v2(152.97,69.13) v3(114.53,50.01) v4(112.32,58.75) v4(112.37,55.9) v4(112.38,57.48) v4(112.94,56.58) v4(112.91,54.88) v4(112.93,53.75) v4(112.98,58.04) v4(113.27,48.23) v4(113.28,52.48) v4(113.56,58.74) v4(113.55,55.92) v4(113.59,57.44) v4(114.03,48.23) v4(114.13,54.82) v4(114.15,53.72) v4(114.15,52.45) v4(114.79,48.23) v4(115.34,54.82) v4(115.33,53.81) v4(115.33,52.46) v4(115.57,48.26) v4(116.47,54.81) v4(116.42,53.81) v4(116.46,52.45) v4(116.46,51.41) v4(116.42,50.25) v4(116.42,49.25) v4(116.44,48.28) v4(116.86,58.57) v4(116.84,57.68) v4(116.84,56.59) v4(116.85,55.6)
+VCC_PWR_SRC: length 26.2
  TOP w0.254: v4(98.55,52.49) 98.55,56.68 96.7,58.53 PR518.1
  IN4 w0.254: v2(107.49,61.51) 107.49,60.83 105.69,59.03 99.63,59.03 98.55,57.95 v4(98.55,52.49)
  BOTTOM w0.254: v2(107.49,61.51) PR511.1
  vias: v1(99.43,48.49) v4(98.55,51.85) v4(98.55,50.71) v4(98.55,50.08) v4(98.87,48.04) v4(98.87,47.41)
+VCCIO_OUT: length 9.5
  TOP w0.102: v1(131.1,79.83) 131.26,79.67 v2(132.14,79.67)
  IN4 w0.508: v2(132.14,79.67) 132.33,79.48 v2(132.33,76.81)
  BOTTOM w0.305: UC1.A59 134.88,73.81 133.28,75.41 133.28,75.92 132.39,76.81 v2(132.33,76.81)
  BOTTOM w0.508: v2(132.14,79.67) 131.69,80.12 RC196.1
+VCCIOA_OUT: length 3.1
  TOP w0.508: v2(159.05,70.46) 158.76,70.46 158.44,70.14 v3(158.44,69.77) RC133.1
  BOTTOM w0.254: v2(159.05,70.46) 159.19,70.46 159.61,70.88 UC1.E20
+VDDA_AVDD1:
  vias: v1(28.9,19.67)
+VDDA_PVDD:
  vias: v1(29.78,13.36)
GND: length 3640.2
  TOP w0.152: UV8.D7 204.64,76.86 v2(203.99,76.86)
  TOP w0.203: UV8.J11 v2(208.54,79.46) ; UV8.H10 v2(207.89,78.81) ; v2(207.24,76.21) 206.91,76.54 UV8.G7 ; UV8.F10 v2(205.94,78.81) ; UV8.F11 v2(205.94,79.46) 205.62,79.14 UV8.E11 ; UV8.J7 v2(208.54,76.21) ; UV8.D10 v2(204.64,78.81) 204.96,79.13 UV8.D11 ; UV8.K5 v2(209.19,74.91) ; UV8.G5 206.91,75.24 v2(207.24,75.56) 206.91,75.89 UV8.G6 ; UV8.C5 v2(203.99,74.91) ; UV8.D6 v2(204.64,75.56) ; UV8.F6 v2(205.94,75.56) 206.26,75.24 UV8.F5 ; UV8.F8 v2(205.94,77.51) ; UL3.11 v2(245.86,30.08) ; UV8.J9 v2(208.54,78.16) ; v2(105.39,66.47) 105.43,66.43 PU500.19 ; UV8.D8 v2(204.64,77.51) ; UI4.28 179.78,98.44 179.5,98.72 v2(179.5,98.98) ; UV8.D9 v2(204.64,78.16) ; UV600.11 v2(226.43,74.45) ; v2(103.74,67.93) 104.08,67.93 104.35,68.19 PU500.29 ; v2(183.52,99.99) 183.58,99.94 UI4.21 ; UV8.J12 v2(208.54,80.11) ; UV7.35 226.42,77.73 v2(226.39,77.7) ; v2(105.39,67.93) 105.69,67.63 PU500.22 ; UI4.11 185.18,95.68 185.29,95.57 v2(185.6,95.57) ; UV8.G8 v2(207.24,77.51) ; UZ8.11 v2(224.33,62.85) ; v2(227.67,77.76) 227.62,77.82 UV7.38 ; UV7.26 v2(222.16,80.48) ; UZ9.11 v2(217.09,39.92) ; UV600.19 223.23,72.59 v2(224.09,71.73) ; UV8.J8 v2(208.54,77.51) ; UV8.J5 v2(208.54,74.91) ; UV8.D5 v2(204.64,74.91) ; UV8.D4 v2(204.64,74.26) ; UV8.G4 206.91,74.59 v2(207.24,74.26) ; UV8.G11 v2(207.24,79.46) ; UZ2.11 v2(241.73,58.02) ; UV8.F9 v2(205.94,78.16) ; UV8.G9 v2(207.24,78.16) ; UV8.L8 UV8.L7 v2(209.84,76.21) 209.51,75.89 UV8.L6 ; UV7.43 230.67,79.68 230.9,79.45 v2(230.9,79.2) ; v2(232.03,69.63) 231.97,69.69 UV600.52 ; UV8.J6 v2(208.54,75.56) ; UV8.F7 v2(205.94,76.21) ; UV8.H4 v2(207.89,74.26) ; UV8.E4 v2(205.29,74.26) ; UV8.F4 v2(205.94,74.26) ; UV8.G10 v2(207.24,78.81)
  TOP w0.254: PC3.2 64.16,13.5 v3(64.22,13.56) ; RI14.1 285.16,42.16 285.21,42.21 UI3.14 286.56,42.21 286.81,41.96 UI3.17 ; RPE10.8 253.87,53.71 v2(254.11,53.96) 254.37,53.7 RPE10.7 ; RPE10.6 254.87,53.71 v2(255.11,53.96) 255.37,53.7 RPE10.5 ; JXDP1.8 v2(85.76,59.2) ; v3(261.74,55.67) CZ48.2 ; RE24.2 v3(246.16,71.89) ; v3(281.98,38.35) 282.06,38.27 v2(283.19,38.27) ; v3(140.98,16.61) 141.34,16.97 CD32.2 ; UN3.5 252.87,16.95 252.92,16.9 v2(252.92,16.89) ; PU800.32 v2(78.85,34.72) PU800.5 ; PU800.23 78.85,30.78 v2(78.6,30.53) ; UV8.C14 204.31,81.13 v2(204.64,81.46) 204.64,81.45 204.96,81.13 UV8.D14 ; v3(219.06,67.78) 218.58,68.26 v2(218.58,68.49) ; UN2.3 v2(264.04,17.74) ; UV8.C13 204.32,80.44 v2(204.64,80.76) UV8.D13 ; PU800.14 v2(74.86,34.72)
  TOP w0.279: v2(76.58,46.27) 76.65,46.2 JXDP1.59 ; JXDP1.49 v2(79.79,48.7) ; JXDP1.32 85.58,53.2 v2(85.85,52.93) ; v2(85.66,57.57) 85.53,57.7 JXDP1.14 ; v2(85.91,55.03) 85.58,54.7 JXDP1.26 ; JXDP1.13 v2(80.39,57.7) ; JXDP1.31 79.94,53.2 v2(80.16,52.97) ; JXDP1.37 v2(79.82,51.7) ; JXDP1.19 v2(80.01,56.2) ; JXDP1.38 v2(85.4,51.7) ; JXDP1.1 v2(76.45,60.7) ; JXDP1.25 79.51,54.7 v2(79.69,54.52) ; JXDP1.50 v2(85.51,48.7) ; JXDP1.2 86.73,60.7 v2(87,60.43) ; JXDP1.7 v2(76.45,59.2) ; JXDP1.20 v2(85.6,56.2)
  TOP w0.305: v2(262.28,39.22) 262.67,39.61 263.11,39.61 263.26,39.46 UE2.B54 ; JDEG1.10 v2(297.25,36.13) ; UE2.B66 263.2,45.46 263.19,45.48 262.57,45.48 262.18,45.09 v2(262.18,44.93) ; v2(252.78,46.91) 253.68,46.91 254.13,46.46 UE2.B18 ; v2(258.03,46.28) 257.94,46.37 UE2.B11 ; v2(243.6,22.07) 243.6,22.28 243.92,22.6 JKBTP1.2 ; v2(301.55,26.64) 301.5,26.69 JAPS1.8 ; JAPS1.10 v2(301.57,25.69) ; v2(245.41,18.71) 245.41,19.29 245.1,19.6 JKBTP1.8 ; v2(274.7,60.87) 274.7,60.69 274.56,60.55 JLPDE1.9 ; v2(245.41,15.77) 245.08,16.1 JKBTP1.15 ; v2(252.16,11.1) 252.17,11.09 JUSH1.17 ; JAPS1.14 v2(301.57,23.69) ; JLED1.10 270.65,12.2 v2(270.81,12.36) ; JKBTP1.14 245.32,16.6 v2(245.48,16.45) ; v2(245.34,23.46) 244.99,23.11 244.51,23.11 JKBTP1.1 ; v2(262.24,41.96) 262.24,42.08 262.62,42.46 263.53,42.46 UE2.B60 ; JUSH1.3 259.17,10.75 259.56,11.14 v2(259.56,11.12) 259.66,11.02 259.66,10.16 JUSH1.2 ; v2(251.63,65.51) 251.63,65.26 251.39,65.01 UE1.B27 ; JAPS1.12 v2(301.57,24.69)
  TOP w0.381: RC140.2 v2(179.07,65.95) ; UZ11.3 249.25,25.65 v2(248.57,24.98) ; RV620.2 235.39,71.79 v2(235.84,72.24) 236.28,71.79 RV619.2 ; RC242.2 RC243.2 164.83,45.92 v2(164.35,45.44) 163.89,45.9 RC152.2 ; UC4.3 183.93,73.72 183.8,73.84 RC80.2 ; UC5.3 189.04,71.73 188.59,72.17 v2(188.27,72.17) ; DE1.2 v2(62.25,84.91) ; v2(269.1,32.44) 269.04,32.38 UZ6.3 ; CC100.1 166,63.25 v2(166.41,62.84) ; CC49.2 161.45,59.41 v2(161.86,59.82) ; v2(181.35,57.25) 179.07,57.25 178.67,57.64 RC174.2 RC175.2 ; v2(148.38,20.75) 147.86,20.75 147.45,20.33 UD1.3 ; PQ817.4 v2(48.5,19.31) ; PR858.2 v2(76.69,29.9) ; v2(218.58,68.49) 218.58,68.66 219.3,69.38 RV608.1 ; v2(148.51,86.44) 148.17,86.44 147.94,86.22 QZ10.4 148.47,85.56 148.76,85.26 148.76,84.69 149.2,84.26 QZ10.1 ; UL2.3 v2(262,82.45) ; UC8.3 141.67,81.34 CC24.2 ; QE2.1 v2(252.19,46.89) ; PU804.3 69.37,36.38 v2(68.56,37.19) ; CC80.2 163.29,59.33 163.09,59.54 v2(163.09,59.81) ; v2(46.42,17.46) 47.09,17.46 47.2,17.57 PQ817.1 ; v2(48.36,22.28) 48.51,22.13 PU806.3 ; v2(161.78,45.21) 162.01,45.21 162.39,44.83 CC12.1 ; CC52.2 166.02,61.32 v2(166.37,60.96) ; PU1.2 v2(73.28,106.27) ; v2(40.32,25.15) 40.32,25.73 QA3.1 ; v2(254.11,93.29) 254.58,93.29 v3(254.94,92.94) 255.78,92.1 CL8.2 ; v2(187,50.39) 187,51.05 186.8,51.26 186.5,51.26 186.5,51.26 UC6.3
  TOP w0.406: v2(262.05,59.23) 262.49,59.23 262.73,58.99 UZ10.3
  TOP w0.457: v2(139.25,83.79) 139.25,83.95 139.32,84.01 CC35.2 ; DI1.3 v2(86.37,93.83) ; RN13.1 268.79,16.61 v2(269.24,16.17) 268.79,15.72 RN21.1 ; QE2.4 249.09,48.64 v2(249.09,48.98) ; v2(223.23,66.6) 223.28,66.55 CZ41.2 ; v2(128.46,79.48) 128.25,79.48 RC198.2 ; v2(39.43,27.41) 39.07,27.05 QA3.4 ; RC130.2 132.2,46.13 v2(132.68,45.66) ; v2(153.45,58.71) 153.45,59.14 CC28.2 ; CR31.2 v2(285.92,24.11) ; RN9.1 259.33,16.74 v2(258.89,17.18) 259.33,17.63 RN11.1 ; v2(52.58,9.56) 52.7,9.69 PD2.1 ; v2(54.8,9.6) PD1.1 ; CZ37.2 244.08,29.7 v2(243.63,29.26) 244.08,28.81 CZ36.2 ; YV2.4 v2(214.11,70.38)
  TOP w0.508: v2(270.89,50.08) 270.89,49.89 270.44,49.45 RE82.1 ; CD8.2 114.6,9.61 v2(114.6,9.61) ; RC191.2 121.33,46.47 v2(121.33,46.48) ; CZ18.1 v2(243.32,10.9) ; v2(184.57,10.43) 184.59,10.41 CD52.2 ; JLPDE1.12 v2(268.46,58.4) ; PR303.2 v2(208.25,59.12) ; v2(208.84,85.26) 208.7,85.4 RV75.2 ; CD43.2 190.23,10.41 v2(190.21,10.43) ; SW3.3 v2(299.27,86) ; C316.2 164.59,106.33 v2(164.52,106.39) ; C319.2 169.1,96.05 v2(168.72,95.67) ; CR8.1 v2(281.81,23.85) ; PC4.2 49.22,12.56 v4(49.06,12.72) ; CR21.1 v2(280.27,35.92) ; v2(106.54,71.86) PC507.1 ; CV10.2 120.71,93.13 v2(121.03,92.81) ; CD28.2 140.38,9.7 139.7,10.38 v2(139.05,10.38) ; CI414.2 v2(188.47,95.54) ; v2(263.85,65.39) 263.39,64.93 CE2.2 ; v2(184.01,94.41) 184.01,94.09 184.46,93.63 CI416.2 ; CE1.2 265.18,64.94 265.68,65.44 v2(266.13,65.44) ; CD38.2 190.1,15.06 v2(190.11,15.06) ; RV502.1 v2(281.18,72.55) ; RD7.2 81.47,15.14 v2(81.9,14.71) ; v2(245.22,62.85) CE9.2 245.27,63.55 CE5.2 RE17.1 ; CV113.2 217.45,71.65 218.34,71.65 v2(218.6,71.39) ; RR8.2 v2(284.29,23.47) ; v2(272.69,36.07) 272.46,36.3 CZ35.2 271.35,35.17 CZ34.2 ; v2(227.86,100.04) 228.02,99.88 MIC1.1 ; v2(168.84,46.14) 168.07,46.91 RC91.1 ; RV89.2 RV76.2 215.06,77.83 v2(215.44,78.21) ; CZ2.2 v2(98.89,92.94) ; v2(259.67,14.15) 259.5,14.33 CN24.2 ; 71.54,65.11 69.98,63.54 H7.1 ; 71.54,65.11 v3(74.72,65.11) PC706.2 ; 71.54,65.11 71.54,66.58 v4(71.55,66.59) ; RD21.2 201.85,12.11 v2(201.64,11.9) ; CD37.2 197.28,14.97 v2(197.27,14.96) ; CI415.2 v2(185.91,100.82) ; CL21.2 CL20.2 269.22,79.68 v2(270.06,78.84) ; QV10.3 198.9,86.02 199.62,85.31 RV509.1 200.12,82.46 200.58,82.46 v2(200.58,82.47) ; v2(107.75,15.03) 107.74,15.04 CD14.2 ; CD39.2 186.31,15.01 v2(186.3,15) ; RV61.2 220.6,74.89 CV601.2 v2(221.24,74.22) ; CL19.2 v2(285.06,90.72) ; v2(282.58,66.89) 282.51,66.82 CV510.2 ; v2(148.25,58.71) 148.72,59.18 CC27.2 ; PC705.2 85.25,65.1 85.25,63.23 85.45,63.04 v2(88.25,63.04) ; v2(300.5,4.93) JRTC1.4 ; JKBTP1.17 239.65,25.2 v2(239.63,25.22) ; v2(258.85,20.33) 258.87,20.36 RN19.1 ; RR5.2 v2(290.56,27.39) ; PR308.2 208.71,62.58 208.82,62.47 v2(208.77,62.47) ; RZ33.2 283.72,77.63 v2(283.46,77.38) ; v2(13.87,14.96) 13.54,14.63 CA13.2 ; v2(245.46,70.47) RE24.2 CE4.2 ; v2(277.87,79.73) 277.51,79.73 276.91,80.33 CL16.2 ; v2(64.96,33.44) 65.59,32.81 PC805.1 ; RN23.1 260.25,13.06 v2(259.86,12.67) ; v2(277.29,33) 278.3,33 RR2.1 ; v2(253.41,34.4) 253.67,34.14 254.03,34.14 CE22.2 ; v2(169.38,44.73) 169.38,44.37 168.95,43.94 CC15.1 CC14.1 ; v2(137.65,14.97) 137.96,15.28 RD15.1 RD16.1 ; RZ40.1 v2(244.92,56.67) ; RV1.2 116.34,87.11 v2(116.08,86.84) ; v2(41.78,18.14) CA33.2 ; CE28.2 267.2,44.03 v2(267.06,44.17) ; v2(141.95,103.74) 141.51,104.18 R271.2 C311.2 ; v2(109.41,10.33) 109.46,10.28 CD18.2 ; v2(111.82,15.09) 111.81,15.1 CD3.2 ; CA12.2 v2(17.96,19.79) ; RE86.2 CE19.2 259.46,33.81 v2(259.83,33.45) ; CE34.2 248.57,38.48 248.84,38.21 v2(249.28,38.21) 250.16,38.21 CE36.2 ; CZ7.2 185.6,77.86 v2(185.68,77.95) ; v2(178.29,99.99) 177.77,99.47 CI418.2 ; CR13.1 v2(291.04,35.03) ; v2(39.56,23.85) 40.09,24.38 QA1.3 ; v2(186.3,10.43) 186.24,10.37 CD44.2 ; YL1.4 247.51,79.87 v2(247.84,79.54) ; PC816.2 72.97,36.75 73.2,36.52 v2(73.2,36.49) ; CR35.2 RR11.2 v2(275.79,26.12) ; RE56.1 256.73,32.67 v2(257.16,32.24) ; v2(102.74,10.33) 102.49,10.08 CD19.2 ; CA53.2 v2(40.88,18.52) ; RV50.2 CV62.2 220.25,78.72 v2(220.55,78.42) ; CI420.2 v2(188.47,94.46) ; v2(249.23,83.92) 249.31,83.85 YL1.2 ; CD35.2 169.92,6.82 v2(169.87,6.77) ; v2(257.06,51.23) 257.65,51.23 CE13.2 ; CD17.2 112.95,9.95 v2(112.9,10) ; PC3.2 64.16,11.66 64.07,11.57 PC209.1 63.45,11.09 v2(62.75,11.79) ; CC61.2 162.61,61.63 v2(163.13,61.63) ; v2(98.54,65.7) PR513.2 ; v2(116.01,10.01) 116,10 CD16.2 ; PC813.2 80.88,41.77 v2(80.77,41.88) ; v2(272.08,79.99) 272.64,79.99 272.72,80.03 CL27.2 ; PR525.2 97.69,61.06 v2(97.69,60.21) ; CZ41.2 CZ42.2 ; CL14.1 v2(250.63,80.24) ; CD49.2 195.56,10.41 v2(195.55,10.43) ; v2(197.11,11.19) 197.09,11.17 CD41.2 ; v2(152.15,58.71) 152.15,59.36 CC26.2 ; CA50.2 v2(40.43,19.73) ; CE8.2 v2(264.13,61.77) ; v2(198.94,11.47) 199.13,11.28 CD55.2 CD56.2 ; v2(271.52,39.78) 271.26,40.04 CE21.2 ; v2(139.7,82.33) 139.7,81.75 140.45,81 CC24.2 ; MIC1.2 228.81,98.5 v2(228.15,99.16) ; JDEG1.12 v2(293.62,42.73) ; RV503.1 285.99,75.67 v2(285.24,75.67) ; v2(245.79,25.08) CZ31.2 CZ30.2 ; RE65.2 CE30.2 260.84,32.05 v2(261.1,32.3) ; v2(233.55,72.41) 233.33,72.63 CV604.2 ; CL13.1 247,85.05 247.38,85.43 v2(247.96,85.43) ; CD6.2 95.91,12.11 v2(96.93,12.11) ; v2(214.55,81.83) 214.55,81.26 214.22,80.93 RV78.2 RV77.2 ; RD14.1 148.46,20.67 v2(148.38,20.75) ; CL17.2 275.57,80.34 275.07,79.83 v2(274.58,79.83) ; CI419.2 181.03,93.82 180.46,94.38 v2(180.46,94.53) ; CD24.2 CD25.2 v2(140.06,11.73) ; CV115.2 v2(212.61,69.57) ; CD7.2 105.65,14.91 v2(105.66,14.9) ; CD50.2 192.45,10.43 v2(192.45,10.43) ; CD45.2 198.8,14.97 v2(198.8,14.96) ; v2(230.9,79.2) 231.38,78.71 RV52.2 ; CD4.2 109.84,15.04 v2(109.85,15.03) ; CD46.2 194.42,14.84 194.51,14.75 v2(194.51,14.72) ; CR6.2 v2(287.33,24.1) ; RV617.2 RV618.2 236.28,68.24 v2(236.47,68.05) ; v2(87.75,49.45) 87.63,49.58 CC21.2 ; v2(98.04,86.72) 97.93,86.6 QV7.3 ; CE18.2 268.04,38.13 v2(268.48,37.69) ; QV9.3 202.41,90.79 202.38,90.77 v2(201.47,91.68) ; CR15.1 v2(291.77,26.4) ; RV510.2 v2(235.06,78.09) ; RL13.2 v2(250.82,79.59) ; CE7.2 258.29,57.18 RE21.1 v2(258.87,56.57) ; CR3.2 291.91,29.51 v2(292.02,29.4) ; v2(105.27,73.26) PC510.1 ; v2(183.07,73.95) 183.39,74.28 RC80.2 ; v2(218.45,69.34) 217.89,68.78 YV2.2 ; CA30.2 40.65,12.15 v2(40.51,12.29) ; CD47.2 188.34,15.09 v2(188.43,15) ; RC306.2 RC139.1 168.65,79.41 169.48,80.24 v2(170.16,80.24) ; CL7.2 v2(251.01,88.62) ; PC817.2 72.63,35.67 v2(72.37,35.41) ; v2(98.04,69.76) PC505.1 98.74,70.66 PC511.2 ; CV60.2 230.17,89.01 v2(229.77,89.42) ; RE58.2 268.88,42.54 268.51,42.54 v2(268.5,42.53) 267.99,43.03 CE20.2 CE15.2 ; CC96.1 114.61,80.12 114.54,80.05 v2(113.6,80.05) 113.58,80.06 QV2.3 ; v2(272.75,6.9) JLED1.12 272.75,8.4 ; CR4.2 285.04,37.03 v2(285.51,37.5) 285.99,37.01 CR10.1 ; RE20.1 252.71,56.75 253.48,55.99 v2(253.48,55.67) ; CR22.1 v2(292.02,30.53) ; JAPS1.20 v2(297.7,20.9) ; CL24.2 CL23.2 244.26,32.08 v2(244.41,32.23) ; v2(110.86,9.61) 110.85,9.61 CD9.2 ; v2(190.24,69.7) 190.23,69.68 CZ4.2 ; CR9.1 v2(287.96,37.38) ; RV609.1 220.25,72.06 v2(219.75,72.57) ; RV514.1 232.09,86.84 v2(232.03,86.91) ; CR1.2 v2(292.1,27.53) ; v2(74.27,99.77) 74.28,99.78 PC20.2 ; CE3.2 v2(257.54,73.65) ; v2(251.2,31.1) RZ38.1 ; CD42.2 194.29,10.03 v2(194.28,10.05) ; v2(103.83,9.61) 104.01,9.43 CD11.2 ; UV501.2 285.94,63.29 v2(286.19,63.54) 286.45,63.79 CV509.2 ; CD12.2 119.06,15.04 v2(119.2,14.9) ; CE17.2 262.89,50.73 v2(262.36,51.26) ; JDEG1.11 v2(296.59,34.03) ; PQ832.3 67.41,31.56 v2(67.23,31.73) ; RV73.2 213.75,74.26 v2(213.74,74.27) ; v2(215.19,45.73) 215.41,45.5 PR106.1 PR104.2 ; CZ48.2 v2(262.92,55.02) ; CZ1.2 102.52,89.97 ; v2(116.63,15.07) 116.63,15.07 CD2.2 ; RD20.2 v2(198.94,12.17) ; v2(2.41,6.96) 2.09,7.28 JSPK1.6 ; v2(184.69,62.19) 184.78,62.28 RC303.2 ; CZ50.2 CZ23.2 v2(237.68,58.46) ; v2(283.19,38.27) 283.65,38.73 CR23.2 283.89,39 283.47,39.42 CI19.2 ; CA11.2 40.7,14.9 CA54.2 v2(41.45,14.85) ; v2(284.1,72.75) 284.72,72.12 RV504.2 ; v2(104.2,14.96) 104.19,14.98 CD15.2 ; PR114.2 v4(213.34,48.18) ; v2(228.41,97.5) 228.81,97.09 MIC1.3 ; v2(221.03,18.64) 221.36,18.64 221.81,18.19 RD28.2 ; PR844.2 68.96,28.1 v2(69.09,27.98) ; v2(191.36,17.88) 191.37,17.87 CD40.2 ; CD13.2 114.79,15.04 v2(114.79,15.04) ; v2(267.45,72.5) 267.18,72.23 CL25.2 ; SW3.1 v2(293.11,86) ; JAPS1.19 v2(299.15,32.29) ; v2(249.74,42.02) RE55.1 250.42,41.14 CE16.2 ; v2(102.07,73.29) PC514.1 ; CZ44.2 CZ45.2 217.53,37.81 v2(217.36,37.63) ; DI2.1 v2(77.54,92.71) ; JRTC1.2 v2(297.95,4.61) ; JLPDE1.11 v2(278.32,57) ; PQ3.3 v2(68.72,101.3) ; CD63.2 CD64.2 v2(225.28,17.95) ; CZ52.2 CZ53.2 v2(243.95,53.64) ; PC810.1 43.88,17.56 v2(43.75,17.69) ; v2(251.9,91.99) 251.71,91.99 251.39,91.67 RL9.2 ; RC132.2 RC131.2 131.68,46.06 RC130.2 ; RC304.2 189.39,75.23 189.7,75.54 v2(190.24,75.54) 190.5,75.79 CZ6.2 ; CE29.2 v2(267.76,47.37) 267.71,47.42 CE45.2 267.73,48.04 CE44.2 ; v2(221.49,45.5) 221.37,45.62 PR105.1 PR102.1 ; RZ27.2 275.13,18.12 v2(275.02,18.01) ; PC119.2 v2(214.17,47.1) ; CZ20.2 CZ17.1 v2(245.22,10.9) ; RE88.2 264.73,32.95 v2(265.03,33.26) 265.1,33.32 CE25.2 ; v2(268.98,20.79) 268.62,20.42 CN29.2 RN16.1 ; CE12.2 266.48,51.68 v2(265.99,52.18) 266.43,52.62 CE10.2 ; CD22.2 CD23.2 120.66,7.09 120.9,7.09 v2(121.27,6.71) ; CZ9.2 187.77,81.39 v2(187.77,81.89) ; v2(258.77,49.83) 258.75,49.85 CE40.2 ; CR7.1 v2(280.72,23.85) ; RV67.1 230.5,75.29 v2(230.35,75.13) ; CN4.2 v2(254.52,16.83) ; v2(102.36,22.57) 101.36,22.57 99.96,23.96 CD20.2 101.05,24.55 v2(102.37,23.23) ; CD51.2 188.34,10.34 v2(188.43,10.43) ; RC128.1 v2(76.56,44.42) ; v2(249.79,45.77) CE38.2 RE77.2 ; CE23.2 v2(249.73,43.92) ; RV3.1 121.57,87.57 RV2.2 121.41,86.27 v2(121.51,86.37) ; v2(262.56,31.99) 262.95,31.59 JTAG1.2 ; v2(105.78,9.61) 105.79,9.61 CD10.2 ; RV74.2 197.75,78.79 v2(197.23,79.31) ; PR874.2 v2(72.37,33.51) ; JKBTP1.18 v2(239.99,13.5) ; v2(74.74,49.89) 75.03,49.59 CC22.2 ; CN3.1 v2(254.57,18.69) ; 275.7,2.08 275.7,2.66 v2(275.21,3.15) ; CC13.1 160.2,41.03 158.07,43.15 158.07,43.72 v2(158.08,43.72) 158.37,43.72 CC65.2 ; RV79.2 v2(200.39,67.74) ; QV502.3 v2(283.99,68.68) ; v2(77.34,14.52) 77.71,14.88 CD1.2 CD5.2 RD6.2 ; RV100.2 232.67,76.25 v2(233.25,76.82) ; CI3.2 v2(88.53,91.34) ; v2(248.73,15.19) RN7.2 ; JSPK1.5 11.31,6.77 v2(11.87,6.77) ; RL12.2 v2(262.19,84.94) ; RN25.1 v2(266.27,12.45) ; CI17.2 v2(287.08,46.27) ; CZ46.2 v2(216.58,37.64) 216.67,37.55 CZ47.2 ; v2(232.03,69.63) 232.08,69.58 CV603.2 ; CD32.2 CD31.2 140.4,18.9 140.27,18.77 v2(139.14,18.77) ; v2(292.61,3.05) JRTC1.3 ; CE6.2 v2(256.71,56.5) ; v2(291.17,34.07) 291.17,34.07 291.1,34.14 CR19.1 ; v2(237.68,57.57) CZ49.2 CZ24.2 ; CR14.1 v2(291.94,25.32) ; UZ5.2 v2(266.61,37.08) ; CR34.2 v2(288.4,23.66) ; v2(130.1,91.71) D20.1 ; v2(158.62,14.6) 158.29,14.93 RD25.2 ; CL15.2 v2(279.59,76.63) ; v2(87.7,42.34) 87.41,42.34 86.67,41.6 RC305.2 ; CZ43.2 v2(226.96,66.19) ; v2(67.9,104.67) 67.7,104.88 67.2,104.88 67.1,104.77 PQ6.6 ; CL9.2 v2(261.21,91.82) ; RZ10.1 258.94,13.56 v2(258.71,13.79) ; CA10.2 v2(42.35,12.48) ; CV9.2 112.27,90.14 112.2,90.08 ; CD48.2 184.53,15.05 v2(184.57,15) ; CV12.2 v2(106.8,84.68) ; CZ40.2 222.35,62.85 v2(223.57,62.85) ; CD30.2 v2(145.02,19.91) ; CE32.2 v2(61.11,86.78) ; RV505.1 v2(288.68,71.14) ; PC1.2 v2(291.16,5.63) ; CL26.2 v2(265.34,76.68) ; PC815.2 v2(79.61,41.89)
  GND1 w0.203: JDOCK1.159 158.64,100.11 ; JDOCK1.159 157.7,99.79 ; JDOCK1.159 158.96,101.05 ; JDOCK1.159 156.76,101.99 ; JDOCK1.159 156.76,100.11 ; JDOCK1.159 156.44,101.05 ; JDOCK1.159 158.64,101.99 ; JDOCK1.159 157.7,102.31 ; 75.9,98.3 JUSB1.11 ; JUSB1.11 76.85,100.15 ; JUSB1.11 75.9,100.15 ; JUSB1.11 76.85,96.44 ; JUSB1.11 75.9,96.44 ; JUSB1.11 77.8,96.44 ; JDOCK1.155 158.76,105.95 ; JDOCK1.155 158.76,104 ; JDOCK1.155 156.65,104 ; JDOCK1.155 158.76,104.97 ; JDOCK1.155 156.65,104.97 ; JDOCK1.155 157.7,104 ; JDOCK1.155 156.65,105.95 ; H13.1 152.87,16.82 ; H13.1 152.87,14.48 ; H13.1 153.29,15.65 ; H13.1 151.7,17.24 ; H13.1 151.7,14.06 ; H13.1 150.11,15.65 ; H13.1 150.53,16.82 ; H13.1 150.53,14.48 ; 234.95,103.69 JUSB2.12 ; JUSB2.12 234,105.1 ; JUSB2.12 234,103.69 ; JUSB2.12 234.95,106.51 ; JUSB2.12 234,106.51 ; H6.1 292.89,90.65 ; H6.1 292.47,91.82 ; H6.1 292.47,89.48 ; H6.1 290.13,89.48 ; H6.1 289.71,90.65 ; H6.1 291.3,89.06 ; H6.1 291.3,92.24 ; H6.1 290.13,91.82 ; JDOCK1.158 146.96,101.05 ; JDOCK1.158 145.7,99.79 ; JDOCK1.158 146.64,100.11 ; JDOCK1.158 146.64,101.99 ; JDOCK1.158 144.76,101.99 ; JDOCK1.158 145.7,102.31 ; JDOCK1.158 144.44,101.05 ; JDOCK1.158 144.76,100.11 ; 296.99,79.63 JMDP1.22 ; JMDP1.22 298.07,79.63 ; JMDP1.22 295.91,79.63 ; JMDP1.22 295.91,81.07 ; JMDP1.22 298.07,81.07 ; JMDP1.22 296.99,81.07 ; JMDP1.22 295.91,80.35 ; JMDP1.22 298.07,80.35 ; JDOCK1.154 146.76,104 ; JDOCK1.154 145.7,104 ; JDOCK1.154 145.7,105.95 ; JDOCK1.154 144.65,105.95 ; JDOCK1.154 144.65,104 ; JDOCK1.154 144.65,104.97 ; JDOCK1.154 146.76,104.97 ; JDOCK1.154 146.76,105.95 ; H15.1 124.09,50.84 ; H15.1 120.9,50.84 ; H15.1 124.09,54.03 ; H15.1 122.5,50.25 ; H15.1 124.68,52.43 ; H15.1 120.31,52.43 ; H15.1 122.5,54.62 ; H15.1 120.9,54.03 ; JHDMI1.23 225.53,106.15 ; JHDMI1.23 224.45,104.57 ; JHDMI1.23 224.45,107.73 ; JHDMI1.23 225.53,104.57 ; JHDMI1.23 223.37,106.15 ; JHDMI1.23 225.53,107.73 ; JHDMI1.23 223.37,104.57 ; JHDMI1.23 223.37,107.73 ; JUSB2.11 235.9,96.44 ; JUSB2.11 234,98.3 ; JUSB2.11 234.95,96.44 ; JUSB2.11 234,96.44 ; JUSB2.11 234,100.15 ; JUSB2.11 234.95,100.15 ; 291.11,69.45 JMDP1.23 ; JMDP1.23 293.47,69.45 ; JMDP1.23 291.11,68.73 ; JMDP1.23 292.29,70.17 ; JMDP1.23 293.47,68.73 ; JMDP1.23 293.47,70.17 ; JMDP1.23 292.29,68.73 ; H4.1 230.2,107.44 ; H4.1 228.61,105.85 ; H4.1 229.03,107.02 ; H4.1 230.2,104.26 ; H4.1 231.38,107.02 ; H4.1 231.38,104.68 ; H4.1 231.79,105.85 ; H4.1 229.03,104.68 ; 293.95,74.97 JMDP1.7 ; JMDP1.7 294.58,76.13 ; JMDP1.7 293.31,74.97 ; JMDP1.7 293.95,76.13 ; JDOCK1.164 174.2,98.1 ; JDOCK1.164 172.14,98.1 ; JDOCK1.164 176.26,98.1 ; JDOCK1.164 174.2,96.15 ; JDOCK1.164 172.14,96.15 ; JDOCK1.164 176.26,97.12 ; JDOCK1.164 172.14,97.12 ; JDOCK1.164 176.26,96.15 ; 296.28,2.42 SW1.4 ; SW1.4 296.52,3.18 ; SW1.4 298.28,2.42 ; SW1.4 298.04,3.18 ; SW1.4 298.04,1.66 ; SW1.4 297.28,3.42 ; SW1.4 296.52,1.66 ; SW1.4 297.28,1.41 ; JMDP1.24 298.07,68.75 ; JMDP1.24 295.91,68.75 ; JMDP1.24 296.99,69.47 ; JMDP1.24 295.91,69.47 ; JMDP1.24 295.91,68.03 ; JMDP1.24 296.99,68.03 ; JMDP1.24 298.07,69.47 ; JMDP1.24 298.07,68.03 ; 177.82,72.39 H17.1 ; H17.1 179.42,72.98 ; H17.1 175.64,74.57 ; H17.1 179.42,76.17 ; H17.1 176.23,72.98 ; H17.1 176.23,76.17 ; H17.1 180.01,74.57 ; H17.1 177.82,76.76 ; 238.76,43.65 H10.1 ; H10.1 241.52,42.48 ; H10.1 240.35,42.06 ; H10.1 239.18,42.48 ; H10.1 239.18,44.82 ; H10.1 240.35,45.24 ; H10.1 241.94,43.65 ; H10.1 241.52,44.82 ; 207.07,97.42 JHDMI1.20 ; JHDMI1.20 208.83,97.42 ; JHDMI1.20 208.83,99.17 ; JHDMI1.20 208.83,100.92 ; JHDMI1.20 207.07,99.17 ; JHDMI1.20 207.95,97.42 ; 84.13,97.94 JUSB1.7 ; JUSB1.7 85.27,96.8 ; JUSB1.7 85.44,97.37 ; JUSB1.7 83.96,97.37 ; JUSB1.7 84.7,96.63 ; JUSB1.7 84.13,96.8 ; JUSB1.7 85.27,97.94 ; 129.2,104 JDOCK1.153 ; JDOCK1.153 131.26,104 ; JDOCK1.153 129.2,105.95 ; JDOCK1.153 127.14,104.97 ; JDOCK1.153 127.14,105.95 ; JDOCK1.153 131.26,105.95 ; JDOCK1.153 131.26,104.97 ; JDOCK1.153 127.14,104 ; JUSB2.13 251.6,105.1 ; JUSB2.13 250.65,103.69 ; JUSB2.13 251.6,103.69 ; JUSB2.13 251.6,106.51 ; JUSB2.13 250.65,106.51 ; H12.1 239.04,8.1 ; H12.1 236.8,10.34 ; H12.1 236.8,5.86 ; H12.1 235.17,9.73 ; H12.1 234.57,8.1 ; H12.1 238.43,6.47 ; H12.1 235.17,6.47 ; H12.1 238.43,9.73 ; 293.95,76.97 JMDP1.1 ; JMDP1.1 294.58,76.97 ; JMDP1.1 293.31,78.13 ; JMDP1.1 294.58,77.55 ; JMDP1.1 294.58,78.13 ; JMDP1.1 293.95,78.13 ; JDOCK1.156 174.2,105.95 ; JDOCK1.156 176.26,104 ; JDOCK1.156 176.26,105.95 ; JDOCK1.156 172.14,104.97 ; JDOCK1.156 174.2,104 ; JDOCK1.156 172.14,105.95 ; JDOCK1.156 176.26,104.97 ; JDOCK1.156 172.14,104 ; 127.14,96.15 JDOCK1.161 ; JDOCK1.161 127.14,97.12 ; JDOCK1.161 131.26,96.15 ; JDOCK1.161 131.26,97.12 ; JDOCK1.161 127.14,98.1 ; JDOCK1.161 131.26,98.1 ; JDOCK1.161 129.2,98.1 ; JDOCK1.161 129.2,96.15 ; 264.84,24.6 H19.1 ; H19.1 268.9,24.6 ; H19.1 266.87,22.57 ; H19.1 268.36,23.11 ; H19.1 265.38,23.11 ; H19.1 265.38,26.09 ; H19.1 266.87,26.63 ; H19.1 268.36,26.09 ; 91.6,96.44 JUSB1.10 ; JUSB1.10 92.55,96.44 ; JUSB1.10 93.5,98.3 ; JUSB1.10 92.55,100.15 ; JUSB1.10 93.5,96.44 ; JUSB1.10 93.5,100.15 ; 133.7,99.99 JDOCK1.157 ; JDOCK1.157 132.65,101.05 ; JDOCK1.157 133.7,102.1 ; JDOCK1.157 134.5,101.85 ; JDOCK1.157 134.5,100.25 ; JDOCK1.157 132.91,100.25 ; JDOCK1.157 132.91,101.85 ; H20.1 279.36,65.05 ; H20.1 275.84,63.56 ; H20.1 276.38,62.07 ; H20.1 279.9,63.56 ; H20.1 277.87,61.53 ; H20.1 277.87,65.59 ; H20.1 279.36,62.07 ; H20.1 276.38,65.05 ; 290.98,1.41 SW1.5 ; SW1.5 289.98,2.42 ; SW1.5 290.22,1.66 ; SW1.5 291.74,1.66 ; SW1.5 290.22,3.18 ; SW1.5 291.98,2.42 ; SW1.5 291.74,3.18 ; SW1.5 290.98,3.42 ; JDOCK1.162 145.7,98.1 ; JDOCK1.162 144.65,96.15 ; JDOCK1.162 145.7,96.15 ; JDOCK1.162 146.76,98.1 ; JDOCK1.162 146.76,97.12 ; JDOCK1.162 144.65,98.1 ; JDOCK1.162 146.76,96.15 ; JDOCK1.162 144.65,97.12 ; H11.1 300.88,9.98 ; H11.1 299.7,9.56 ; H11.1 301.29,11.15 ; H11.1 298.53,12.32 ; H11.1 299.7,12.74 ; H11.1 298.53,9.98 ; H11.1 300.88,12.32 ; H11.1 298.11,11.15 ; JUSB3.11 289.83,49.75 ; JUSB3.11 287.17,48.92 ; JUSB3.11 287.17,50.58 ; JUSB3.11 287.17,49.75 ; JUSB3.11 288.5,50.58 ; JUSB3.11 289.83,48.92 ; JUSB3.11 288.5,48.92 ; JUSB3.11 289.83,50.58 ; 92.55,103.69 JUSB1.13 ; JUSB1.13 93.5,103.69 ; JUSB1.13 92.55,106.51 ; JUSB1.13 93.5,105.1 ; JUSB1.13 93.5,106.51 ; JUSB1.4 81.77,96.44 ; JUSB1.4 81.77,95.3 ; JUSB1.4 80.63,96.44 ; JUSB1.4 81.94,95.87 ; JUSB1.4 80.63,95.3 ; JUSB1.4 81.2,95.13 ; JUSB1.4 80.46,95.87 ; 239.3,95.13 JUSB2.4 ; JUSB2.4 238.73,95.3 ; JUSB2.4 240.04,95.87 ; JUSB2.4 239.87,95.3 ; JUSB2.4 239.87,96.44 ; JUSB2.4 238.56,95.87 ; JUSB2.4 238.73,96.44 ; H21.1 137.26,82 ; H21.1 135.67,80.41 ; H21.1 135.67,83.59 ; H21.1 134.08,82 ; H21.1 136.84,83.17 ; H21.1 134.5,80.83 ; H21.1 136.84,80.83 ; H21.1 134.5,83.17 ; JHDMI1.8 214.66,99.03 ; JHDMI1.8 214.2,99.15 ; JHDMI1.8 213.74,99.03 ; JHDMI1.8 214.2,97.99 ; JHDMI1.8 213.74,98.11 ; JHDMI1.8 214.66,98.11 ; 215.7,99.49 JHDMI1.11 ; JHDMI1.11 215.24,99.61 ; JHDMI1.11 215.7,100.65 ; JHDMI1.11 216.16,99.61 ; JHDMI1.11 215.24,100.53 ; JHDMI1.11 216.16,100.53 ; H9.1 283.7,51.24 ; H9.1 284.88,50.82 ; H9.1 282.53,50.82 ; H9.1 283.7,48.06 ; H9.1 282.53,48.48 ; H9.1 284.88,48.48 ; H9.1 285.29,49.65 ; H9.1 282.11,49.65 ; JHDMI1.21 223.33,99.17 ; JHDMI1.21 222.45,97.42 ; JHDMI1.21 221.57,100.92 ; JHDMI1.21 221.57,97.42 ; JHDMI1.21 221.57,99.17 ; JHDMI1.21 223.33,97.42 ; H7.1 71.15,62.72 ; H7.1 68.81,60.38 ; H7.1 69.98,59.96 ; H7.1 69.98,63.14 ; H7.1 71.15,60.38 ; H7.1 68.39,61.55 ; H7.1 71.57,61.55 ; H7.1 68.81,62.72 ; H22.1 93.72,87.38 ; H22.1 93.72,90.42 ; H22.1 92.2,86.82 ; H22.1 90.68,90.42 ; H22.1 92.2,90.98 ; H22.1 90.68,87.38 ; H22.1 94.28,88.9 ; H22.1 90.12,88.9 ; JHDMI1.5 213.16,99.61 ; JHDMI1.5 212.7,100.65 ; JHDMI1.5 212.7,99.49 ; JHDMI1.5 212.24,99.61 ; JHDMI1.5 212.24,100.53 ; JHDMI1.5 213.16,100.53 ; JUSB3.10 289.83,63.38 ; JUSB3.10 289.83,62.55 ; JUSB3.10 287.17,63.38 ; JUSB3.10 289.83,61.72 ; JUSB3.10 287.17,61.72 ; JUSB3.10 287.17,62.55 ; JUSB3.10 288.5,63.38 ; JUSB3.10 288.5,61.72 ; 289.47,56.15 JUSB3.7 ; JUSB3.7 290.3,56.98 ; JUSB3.7 290.3,55.32 ; JUSB3.7 289.66,56.79 ; JUSB3.7 289.66,55.52 ; JDOCK1.163 158.76,97.12 ; JDOCK1.163 158.76,96.15 ; JDOCK1.163 158.76,98.1 ; JDOCK1.163 156.65,97.12 ; JDOCK1.163 156.65,98.1 ; JDOCK1.163 157.7,98.1 ; JDOCK1.163 157.7,96.15 ; JDOCK1.163 156.65,96.15 ; JDOCK1.160 170.5,100.25 ; JDOCK1.160 168.91,101.85 ; JDOCK1.160 169.7,99.99 ; JDOCK1.160 169.7,102.1 ; JDOCK1.160 170.76,101.05 ; JDOCK1.160 168.91,100.25 ; JDOCK1.160 170.5,101.85 ; 291.11,80.37 JMDP1.21 ; JMDP1.21 293.47,80.37 ; JMDP1.21 292.29,80.37 ; JMDP1.21 293.47,79.65 ; JMDP1.21 292.29,78.93 ; JMDP1.21 293.47,78.93 ; JMDP1.21 291.11,79.65 ; H2.1 119.87,104.68 ; H2.1 117.53,107.02 ; H2.1 118.7,107.44 ; H2.1 119.87,107.02 ; H2.1 117.11,105.85 ; H2.1 120.29,105.85 ; H2.1 117.53,104.68 ; H2.1 118.7,104.26 ; JDOCK1.152 176.93,103.03 ; JDOCK1.152 176.93,101.05 ; JDOCK1.152 176.93,99.07 ; JDOCK1.152 174.82,103.03 ; JDOCK1.152 175.88,99.07 ; JDOCK1.152 174.82,99.07 ; JDOCK1.152 174.82,101.05 ; JDOCK1.152 175.88,103.03 ; 287.97,59.65 JUSB3.4 ; JUSB3.4 289.43,59.01 ; JUSB3.4 288.8,60.48 ; JUSB3.4 288.16,60.28 ; JUSB3.4 288.16,59.01 ; JUSB3.4 288.8,58.82 ; H16.1 179.42,50.84 ; H16.1 177.82,50.25 ; H16.1 180.01,52.43 ; H16.1 175.64,52.43 ; H16.1 176.23,54.03 ; H16.1 177.82,54.62 ; H16.1 176.23,50.84 ; H16.1 179.42,54.03 ; JHDMI1.17 219.16,100.53 ; JHDMI1.17 218.7,100.65 ; JHDMI1.17 218.24,100.53 ; JHDMI1.17 218.7,99.49 ; JHDMI1.17 218.24,99.61 ; JHDMI1.17 219.16,99.61 ; 262.01,101.95 JLOM1.16 ; JLOM1.16 262.01,103.7 ; JLOM1.16 262.01,105.45 ; JLOM1.16 262.93,101.95 ; JLOM1.16 262.93,105.45 ; H3.1 186.29,105.85 ; H3.1 185.87,104.68 ; H3.1 183.11,105.85 ; H3.1 184.7,104.26 ; H3.1 184.7,107.44 ; H3.1 183.53,107.02 ; H3.1 185.87,107.02 ; H3.1 183.53,104.68 ; 242.23,97.94 JUSB2.7 ; JUSB2.7 243.37,97.94 ; JUSB2.7 243.37,96.8 ; JUSB2.7 242.06,97.37 ; JUSB2.7 242.23,96.8 ; JUSB2.7 243.54,97.37 ; JUSB2.7 242.8,96.63 ; 297.75,48.45 298.93,48.45 ; 297.75,48.45 298.93,47.67 ; 297.75,48.45 296.57,48.45 ; 297.75,48.45 296.57,47.67 ; 297.75,48.45 297.75,47.67 ; 75.9,103.69 JUSB1.12 ; JUSB1.12 75.9,106.51 ; JUSB1.12 75.9,105.1 ; JUSB1.12 76.85,106.51 ; JUSB1.12 76.85,103.69 ; H1.1 56.7,107.44 ; H1.1 55.11,105.85 ; H1.1 56.7,104.26 ; H1.1 58.29,105.85 ; H1.1 55.53,107.02 ; H1.1 57.87,104.68 ; H1.1 57.87,107.02 ; H1.1 55.53,104.68 ; 204.87,106.15 JHDMI1.22 ; JHDMI1.22 207.03,106.15 ; JHDMI1.22 205.95,107.73 ; JHDMI1.22 204.87,104.57 ; JHDMI1.22 207.03,107.73 ; JHDMI1.22 204.87,107.73 ; JHDMI1.22 207.03,104.57 ; JHDMI1.22 205.95,104.57 ; 126.47,103.03 JDOCK1.145 ; JDOCK1.145 126.47,99.07 ; JDOCK1.145 127.53,103.03 ; JDOCK1.145 127.53,99.07 ; JDOCK1.145 126.47,101.05 ; JDOCK1.145 128.58,99.07 ; JDOCK1.145 128.58,103.03 ; JDOCK1.145 128.58,101.05 ; H14.1 124.09,76.17 ; H14.1 120.9,76.17 ; H14.1 120.31,74.57 ; H14.1 124.09,72.98 ; H14.1 122.5,76.76 ; H14.1 124.68,74.57 ; H14.1 122.5,72.39 ; H14.1 120.9,72.98 ; JUSB2.10 251.6,100.15 ; JUSB2.10 249.7,96.44 ; JUSB2.10 251.6,96.44 ; JUSB2.10 251.6,98.3 ; JUSB2.10 250.65,100.15 ; JUSB2.10 250.65,96.44 ; JUSB3.12 298.93,64.62 ; JUSB3.12 296.57,63.85 ; JUSB3.12 297.75,64.62 ; JUSB3.12 298.93,63.85 ; JUSB3.12 296.57,64.62 ; 293.31,74.13 JMDP1.13 ; JMDP1.13 294.58,72.97 ; JMDP1.13 293.95,74.13 ; JMDP1.13 293.95,72.97 ; JMDP1.19 294.58,71.55 ; JMDP1.19 294.58,72.13 ; JMDP1.19 293.95,70.97 ; JMDP1.19 293.31,70.97 ; JMDP1.19 293.95,72.13 ; JMDP1.19 294.58,70.97 ; JHDMI1.2 211.2,99.15 ; JHDMI1.2 210.74,98.11 ; JHDMI1.2 210.62,98.57 ; JHDMI1.2 210.74,99.03 ; JHDMI1.2 211.2,97.99 ; JHDMI1.2 211.66,99.03 ; JHDMI1.2 211.66,98.11
  VCC w0.203: 55.53,104.68 H1.1 ; H1.1 55.11,105.85 ; H1.1 56.7,104.26 ; H1.1 58.29,105.85 ; H1.1 57.87,107.02 ; H1.1 55.53,107.02 ; H1.1 57.87,104.68 ; H1.1 56.7,107.44 ; 150.11,15.65 H13.1 ; H13.1 152.87,16.82 ; H13.1 150.53,16.82 ; H13.1 150.53,14.48 ; H13.1 151.7,14.06 ; H13.1 153.29,15.65 ; H13.1 152.87,14.48 ; H13.1 151.7,17.24
  IN2 w0.508: 16.98,15.6 20.58,15.6 v2(21.04,16.05) ; v2(15.81,15.38) 14.28,15.38 v2(13.87,14.96)
  IN2 w0.762: 16.7,16 16.7,16.57 16.11,17.16 ; 16.13,17.84 17.96,19.67 v2(17.96,19.79) ; v2(10.68,11.67) 12.05,13.04 16.2,13.04 16.69,13.52 16.76,13.52 16.77,13.54 16.77,14.71
  GND2 w0.203: JDOCK1.157 134.5,101.85 ; JDOCK1.157 132.91,101.85 ; JDOCK1.157 132.65,101.05 ; JDOCK1.157 134.5,100.25 ; JDOCK1.157 133.7,99.99 ; JDOCK1.157 132.91,100.25 ; JDOCK1.157 133.7,102.1 ; 235.17,9.73 H12.1 ; H12.1 238.43,6.47 ; H12.1 238.43,9.73 ; H12.1 234.57,8.1 ; H12.1 236.8,10.34 ; H12.1 236.8,5.86 ; H12.1 235.17,6.47 ; H12.1 239.04,8.1 ; 287.97,59.65 JUSB3.4 ; JUSB3.4 288.16,59.01 ; JUSB3.4 288.8,58.82 ; JUSB3.4 288.8,60.48 ; JUSB3.4 289.43,59.01 ; JUSB3.4 288.16,60.28 ; JUSB2.7 243.54,97.37 ; JUSB2.7 242.23,96.8 ; JUSB2.7 242.23,97.94 ; JUSB2.7 243.37,96.8 ; JUSB2.7 242.06,97.37 ; JUSB2.7 243.37,97.94 ; JUSB2.7 242.8,96.63 ; 223.37,107.73 JHDMI1.23 ; JHDMI1.23 223.37,104.57 ; JHDMI1.23 225.53,106.15 ; JHDMI1.23 224.45,104.57 ; JHDMI1.23 223.37,106.15 ; JHDMI1.23 225.53,104.57 ; JHDMI1.23 224.45,107.73 ; JHDMI1.23 225.53,107.73 ; JUSB1.4 81.94,95.87 ; JUSB1.4 80.46,95.87 ; JUSB1.4 80.63,96.44 ; JUSB1.4 81.2,95.13 ; JUSB1.4 81.77,95.3 ; JUSB1.4 80.63,95.3 ; JUSB1.4 81.77,96.44 ; 157.7,96.15 JDOCK1.163 ; JDOCK1.163 158.76,98.1 ; JDOCK1.163 156.65,98.1 ; JDOCK1.163 156.65,97.12 ; JDOCK1.163 158.76,96.15 ; JDOCK1.163 157.7,98.1 ; JDOCK1.163 158.76,97.12 ; JDOCK1.163 156.65,96.15 ; 292.29,78.93 JMDP1.21 ; JMDP1.21 291.11,79.65 ; JMDP1.21 293.47,79.65 ; JMDP1.21 291.11,80.37 ; JMDP1.21 293.47,80.37 ; JMDP1.21 292.29,80.37 ; JMDP1.21 293.47,78.93 ; 293.31,78.13 JMDP1.1 ; JMDP1.1 294.58,77.55 ; JMDP1.1 293.95,78.13 ; JMDP1.1 293.95,76.97 ; JMDP1.1 294.58,76.97 ; JMDP1.1 294.58,78.13 ; 145.7,96.15 JDOCK1.162 ; JDOCK1.162 145.7,98.1 ; JDOCK1.162 144.65,96.15 ; JDOCK1.162 146.76,96.15 ; JDOCK1.162 146.76,98.1 ; JDOCK1.162 144.65,98.1 ; JDOCK1.162 146.76,97.12 ; JDOCK1.162 144.65,97.12 ; JUSB1.11 77.8,96.44 ; JUSB1.11 75.9,98.3 ; JUSB1.11 76.85,100.15 ; JUSB1.11 75.9,96.44 ; JUSB1.11 76.85,96.44 ; JUSB1.11 75.9,100.15 ; JUSB2.10 251.6,96.44 ; JUSB2.10 249.7,96.44 ; JUSB2.10 251.6,98.3 ; JUSB2.10 250.65,100.15 ; JUSB2.10 251.6,100.15 ; JUSB2.10 250.65,96.44 ; 228.61,105.85 H4.1 ; H4.1 229.03,104.68 ; H4.1 230.2,107.44 ; H4.1 230.2,104.26 ; H4.1 231.79,105.85 ; H4.1 229.03,107.02 ; H4.1 231.38,104.68 ; H4.1 231.38,107.02 ; 239.3,95.13 JUSB2.4 ; JUSB2.4 238.73,95.3 ; JUSB2.4 238.56,95.87 ; JUSB2.4 239.87,95.3 ; JUSB2.4 240.04,95.87 ; JUSB2.4 238.73,96.44 ; JUSB2.4 239.87,96.44 ; JHDMI1.20 208.83,100.92 ; JHDMI1.20 208.83,99.17 ; JHDMI1.20 208.83,97.42 ; JHDMI1.20 207.07,97.42 ; JHDMI1.20 207.07,99.17 ; JHDMI1.20 207.95,97.42 ; 129.2,96.15 JDOCK1.161 ; JDOCK1.161 129.2,98.1 ; JDOCK1.161 127.14,98.1 ; JDOCK1.161 131.26,96.15 ; JDOCK1.161 131.26,97.12 ; JDOCK1.161 127.14,97.12 ; JDOCK1.161 127.14,96.15 ; JDOCK1.161 131.26,98.1 ; 122.5,50.25 H15.1 ; H15.1 122.5,54.62 ; H15.1 124.09,54.03 ; H15.1 120.9,50.84 ; H15.1 124.68,52.43 ; H15.1 120.9,54.03 ; H15.1 120.31,52.43 ; H15.1 124.09,50.84 ; 126.47,99.07 JDOCK1.145 ; JDOCK1.145 128.58,99.07 ; JDOCK1.145 127.53,103.03 ; JDOCK1.145 126.47,103.03 ; JDOCK1.145 127.53,99.07 ; JDOCK1.145 126.47,101.05 ; JDOCK1.145 128.58,103.03 ; JDOCK1.145 128.58,101.05 ; H11.1 300.88,12.32 ; H11.1 301.29,11.15 ; H11.1 298.53,9.98 ; H11.1 298.11,11.15 ; H11.1 298.53,12.32 ; H11.1 299.7,9.56 ; H11.1 300.88,9.98 ; H11.1 299.7,12.74 ; 210.74,99.03 JHDMI1.2 ; JHDMI1.2 210.74,98.11 ; JHDMI1.2 211.66,98.11 ; JHDMI1.2 211.2,99.15 ; JHDMI1.2 211.2,97.99 ; JHDMI1.2 211.66,99.03 ; JHDMI1.2 210.62,98.57 ; JDOCK1.154 146.76,104 ; JDOCK1.154 146.76,105.95 ; JDOCK1.154 146.76,104.97 ; JDOCK1.154 145.7,105.95 ; JDOCK1.154 144.65,105.95 ; JDOCK1.154 144.65,104.97 ; JDOCK1.154 145.7,104 ; JDOCK1.154 144.65,104 ; 134.5,83.17 H21.1 ; H21.1 137.26,82 ; H21.1 135.67,83.59 ; H21.1 135.67,80.41 ; H21.1 136.84,83.17 ; H21.1 136.84,80.83 ; H21.1 134.5,80.83 ; H21.1 134.08,82 ; 262.01,103.7 JLOM1.16 ; JLOM1.16 262.93,105.45 ; JLOM1.16 262.01,101.95 ; JLOM1.16 262.01,105.45 ; JLOM1.16 262.93,101.95 ; 156.44,101.05 JDOCK1.159 ; JDOCK1.159 156.76,100.11 ; JDOCK1.159 158.96,101.05 ; JDOCK1.159 158.64,101.99 ; JDOCK1.159 157.7,102.31 ; JDOCK1.159 156.76,101.99 ; JDOCK1.159 157.7,99.79 ; JDOCK1.159 158.64,100.11 ; SW1.5 291.74,1.66 ; SW1.5 291.98,2.42 ; SW1.5 290.22,3.18 ; SW1.5 289.98,2.42 ; SW1.5 290.98,1.41 ; SW1.5 290.22,1.66 ; SW1.5 291.74,3.18 ; SW1.5 290.98,3.42 ; 144.76,100.11 JDOCK1.158 ; JDOCK1.158 144.44,101.05 ; JDOCK1.158 145.7,102.31 ; JDOCK1.158 146.64,100.11 ; JDOCK1.158 146.64,101.99 ; JDOCK1.158 145.7,99.79 ; JDOCK1.158 146.96,101.05 ; JDOCK1.158 144.76,101.99 ; H19.1 268.36,26.09 ; H19.1 268.9,24.6 ; H19.1 264.84,24.6 ; H19.1 265.38,26.09 ; H19.1 265.38,23.11 ; H19.1 266.87,22.57 ; H19.1 266.87,26.63 ; H19.1 268.36,23.11 ; H17.1 179.42,76.17 ; H17.1 177.82,72.39 ; H17.1 177.82,76.76 ; H17.1 175.64,74.57 ; H17.1 179.42,72.98 ; H17.1 176.23,76.17 ; H17.1 180.01,74.57 ; H17.1 176.23,72.98 ; H14.1 124.09,76.17 ; H14.1 122.5,76.76 ; H14.1 122.5,72.39 ; H14.1 124.68,74.57 ; H14.1 124.09,72.98 ; H14.1 120.9,76.17 ; H14.1 120.31,74.57 ; H14.1 120.9,72.98 ; 56.7,104.26 H1.1 ; H1.1 57.87,104.68 ; H1.1 56.7,107.44 ; H1.1 58.29,105.85 ; H1.1 57.87,107.02 ; H1.1 55.53,104.68 ; H1.1 55.11,105.85 ; H1.1 55.53,107.02 ; JUSB1.10 92.55,100.15 ; JUSB1.10 91.6,96.44 ; JUSB1.10 92.55,96.44 ; JUSB1.10 93.5,96.44 ; JUSB1.10 93.5,98.3 ; JUSB1.10 93.5,100.15 ; 68.81,60.38 H7.1 ; H7.1 71.15,62.72 ; H7.1 68.81,62.72 ; H7.1 71.15,60.38 ; H7.1 69.98,59.96 ; H7.1 69.98,63.14 ; H7.1 68.39,61.55 ; H7.1 71.57,61.55 ; H9.1 284.88,48.48 ; H9.1 283.7,51.24 ; H9.1 282.53,48.48 ; H9.1 283.7,48.06 ; H9.1 285.29,49.65 ; H9.1 282.53,50.82 ; H9.1 282.11,49.65 ; H9.1 284.88,50.82 ; 295.91,68.75 JMDP1.24 ; JMDP1.24 296.99,69.47 ; JMDP1.24 298.07,68.03 ; JMDP1.24 295.91,69.47 ; JMDP1.24 295.91,68.03 ; JMDP1.24 296.99,68.03 ; JMDP1.24 298.07,69.47 ; JMDP1.24 298.07,68.75 ; 212.24,100.53 JHDMI1.5 ; JHDMI1.5 212.7,99.49 ; JHDMI1.5 212.7,100.65 ; JHDMI1.5 212.24,99.61 ; JHDMI1.5 213.16,100.53 ; JHDMI1.5 213.16,99.61 ; JDOCK1.152 175.88,103.03 ; JDOCK1.152 176.93,99.07 ; JDOCK1.152 175.88,99.07 ; JDOCK1.152 174.82,99.07 ; JDOCK1.152 174.82,101.05 ; JDOCK1.152 174.82,103.03 ; JDOCK1.152 176.93,103.03 ; JDOCK1.152 176.93,101.05 ; H6.1 292.89,90.65 ; H6.1 292.47,89.48 ; H6.1 290.13,89.48 ; H6.1 291.3,92.24 ; H6.1 292.47,91.82 ; H6.1 291.3,89.06 ; H6.1 289.71,90.65 ; H6.1 290.13,91.82 ; 156.65,104.97 JDOCK1.155 ; JDOCK1.155 158.76,104.97 ; JDOCK1.155 156.65,105.95 ; JDOCK1.155 156.65,104 ; JDOCK1.155 158.76,105.95 ; JDOCK1.155 158.76,104 ; JDOCK1.155 157.7,104 ; 176.23,50.84 H16.1 ; H16.1 175.64,52.43 ; H16.1 180.01,52.43 ; H16.1 179.42,54.03 ; H16.1 176.23,54.03 ; H16.1 179.42,50.84 ; H16.1 177.82,50.25 ; H16.1 177.82,54.62 ; 297.75,47.67 297.75,48.45 ; 297.75,48.45 298.93,48.45 ; 297.75,48.45 296.57,48.45 ; 297.75,48.45 298.93,47.67 ; 297.75,48.45 296.57,47.67 ; H3.1 184.7,107.44 ; H3.1 183.11,105.85 ; H3.1 185.87,107.02 ; H3.1 186.29,105.85 ; H3.1 183.53,104.68 ; H3.1 185.87,104.68 ; H3.1 183.53,107.02 ; H3.1 184.7,104.26 ; JMDP1.7 293.95,76.13 ; JMDP1.7 294.58,76.13 ; JMDP1.7 293.95,74.97 ; JMDP1.7 293.31,74.97 ; 129.2,104 JDOCK1.153 ; JDOCK1.153 127.14,104 ; JDOCK1.153 131.26,105.95 ; JDOCK1.153 127.14,105.95 ; JDOCK1.153 131.26,104 ; JDOCK1.153 131.26,104.97 ; JDOCK1.153 129.2,105.95 ; JDOCK1.153 127.14,104.97 ; 291.11,68.73 JMDP1.23 ; JMDP1.23 293.47,68.73 ; JMDP1.23 291.11,69.45 ; JMDP1.23 292.29,68.73 ; JMDP1.23 293.47,70.17 ; JMDP1.23 292.29,70.17 ; JMDP1.23 293.47,69.45 ; JDOCK1.164 176.26,98.1 ; JDOCK1.164 172.14,97.12 ; JDOCK1.164 174.2,98.1 ; JDOCK1.164 172.14,96.15 ; JDOCK1.164 172.14,98.1 ; JDOCK1.164 176.26,97.12 ; JDOCK1.164 174.2,96.15 ; JDOCK1.164 176.26,96.15 ; 287.17,48.92 JUSB3.11 ; JUSB3.11 289.83,50.58 ; JUSB3.11 287.17,50.58 ; JUSB3.11 288.5,50.58 ; JUSB3.11 289.83,48.92 ; JUSB3.11 288.5,48.92 ; JUSB3.11 287.17,49.75 ; JUSB3.11 289.83,49.75 ; 289.66,56.79 JUSB3.7 ; JUSB3.7 289.47,56.15 ; JUSB3.7 290.3,56.98 ; JUSB3.7 290.3,55.32 ; JUSB3.7 289.66,55.52 ; 75.9,105.1 JUSB1.12 ; JUSB1.12 75.9,106.51 ; JUSB1.12 76.85,106.51 ; JUSB1.12 75.9,103.69 ; JUSB1.12 76.85,103.69 ; 168.91,101.85 JDOCK1.160 ; JDOCK1.160 169.7,102.1 ; JDOCK1.160 170.5,101.85 ; JDOCK1.160 168.91,100.25 ; JDOCK1.160 169.7,99.99 ; JDOCK1.160 170.5,100.25 ; JDOCK1.160 170.76,101.05 ; 84.7,96.63 JUSB1.7 ; JUSB1.7 85.27,96.8 ; JUSB1.7 85.44,97.37 ; JUSB1.7 83.96,97.37 ; JUSB1.7 84.13,96.8 ; JUSB1.7 85.27,97.94 ; JUSB1.7 84.13,97.94 ; 234.95,96.44 JUSB2.11 ; JUSB2.11 235.9,96.44 ; JUSB2.11 234.95,100.15 ; JUSB2.11 234,98.3 ; JUSB2.11 234,96.44 ; JUSB2.11 234,100.15 ; 117.11,105.85 H2.1 ; H2.1 117.53,107.02 ; H2.1 120.29,105.85 ; H2.1 119.87,107.02 ; H2.1 119.87,104.68 ; H2.1 118.7,107.44 ; H2.1 118.7,104.26 ; H2.1 117.53,104.68 ; 172.14,105.95 JDOCK1.156 ; JDOCK1.156 176.26,104.97 ; JDOCK1.156 172.14,104.97 ; JDOCK1.156 176.26,105.95 ; JDOCK1.156 176.26,104 ; JDOCK1.156 174.2,105.95 ; JDOCK1.156 172.14,104 ; JDOCK1.156 174.2,104 ; H10.1 240.35,45.24 ; H10.1 239.18,44.82 ; H10.1 241.94,43.65 ; H10.1 238.76,43.65 ; H10.1 241.52,42.48 ; H10.1 239.18,42.48 ; H10.1 240.35,42.06 ; H10.1 241.52,44.82 ; JHDMI1.22 207.03,104.57 ; JHDMI1.22 207.03,107.73 ; JHDMI1.22 204.87,106.15 ; JHDMI1.22 205.95,107.73 ; JHDMI1.22 207.03,106.15 ; JHDMI1.22 204.87,104.57 ; JHDMI1.22 204.87,107.73 ; JHDMI1.22 205.95,104.57 ; JMDP1.19 294.58,70.97 ; JMDP1.19 293.31,70.97 ; JMDP1.19 293.95,70.97 ; JMDP1.19 293.95,72.13 ; JMDP1.19 294.58,71.55 ; JMDP1.19 294.58,72.13 ; 90.12,88.9 H22.1 ; H22.1 92.2,90.98 ; H22.1 92.2,86.82 ; H22.1 90.68,90.42 ; H22.1 90.68,87.38 ; H22.1 93.72,90.42 ; H22.1 94.28,88.9 ; H22.1 93.72,87.38 ; 296.57,64.62 JUSB3.12 ; JUSB3.12 297.75,64.62 ; JUSB3.12 298.93,63.85 ; JUSB3.12 298.93,64.62 ; JUSB3.12 296.57,63.85 ; 287.17,63.38 JUSB3.10 ; JUSB3.10 289.83,63.38 ; JUSB3.10 288.5,61.72 ; JUSB3.10 288.5,63.38 ; JUSB3.10 287.17,61.72 ; JUSB3.10 289.83,62.55 ; JUSB3.10 287.17,62.55 ; JUSB3.10 289.83,61.72 ; JHDMI1.11 215.7,100.65 ; JHDMI1.11 215.7,99.49 ; JHDMI1.11 215.24,100.53 ; JHDMI1.11 216.16,100.53 ; JHDMI1.11 216.16,99.61 ; JHDMI1.11 215.24,99.61 ; H13.1 151.7,17.24 ; H13.1 150.53,14.48 ; H13.1 152.87,14.48 ; H13.1 150.53,16.82 ; H13.1 151.7,14.06 ; H13.1 152.87,16.82 ; H13.1 153.29,15.65 ; H13.1 150.11,15.65 ; JMDP1.22 296.99,81.07 ; JMDP1.22 296.99,79.63 ; JMDP1.22 295.91,81.07 ; JMDP1.22 298.07,80.35 ; JMDP1.22 298.07,79.63 ; JMDP1.22 295.91,80.35 ; JMDP1.22 298.07,81.07 ; JMDP1.22 295.91,79.63 ; JHDMI1.8 214.2,99.15 ; JHDMI1.8 214.2,97.99 ; JHDMI1.8 213.74,99.03 ; JHDMI1.8 214.66,99.03 ; JHDMI1.8 214.66,98.11 ; JHDMI1.8 213.74,98.11 ; JUSB1.13 93.5,106.51 ; JUSB1.13 92.55,103.69 ; JUSB1.13 93.5,103.69 ; JUSB1.13 93.5,105.1 ; JUSB1.13 92.55,106.51 ; 221.57,100.92 JHDMI1.21 ; JHDMI1.21 223.33,97.42 ; JHDMI1.21 221.57,97.42 ; JHDMI1.21 221.57,99.17 ; JHDMI1.21 223.33,99.17 ; JHDMI1.21 222.45,97.42 ; JUSB2.12 234.95,106.51 ; JUSB2.12 234.95,103.69 ; JUSB2.12 234,106.51 ; JUSB2.12 234,105.1 ; JUSB2.12 234,103.69 ; SW1.4 298.04,3.18 ; SW1.4 298.04,1.66 ; SW1.4 297.28,3.42 ; SW1.4 296.52,3.18 ; SW1.4 298.28,2.42 ; SW1.4 296.52,1.66 ; SW1.4 296.28,2.42 ; SW1.4 297.28,1.41 ; 276.38,65.05 H20.1 ; H20.1 279.9,63.56 ; H20.1 277.87,61.53 ; H20.1 279.36,62.07 ; H20.1 276.38,62.07 ; H20.1 279.36,65.05 ; H20.1 277.87,65.59 ; H20.1 275.84,63.56 ; JUSB2.13 251.6,106.51 ; JUSB2.13 250.65,103.69 ; JUSB2.13 250.65,106.51 ; JUSB2.13 251.6,105.1 ; JUSB2.13 251.6,103.69 ; 293.31,74.13 JMDP1.13 ; JMDP1.13 294.58,72.97 ; JMDP1.13 293.95,72.97 ; JMDP1.13 293.95,74.13 ; JHDMI1.17 219.16,99.61 ; JHDMI1.17 218.24,99.61 ; JHDMI1.17 218.7,100.65 ; JHDMI1.17 218.7,99.49 ; JHDMI1.17 219.16,100.53 ; JHDMI1.17 218.24,100.53
  GND3 w0.203: JMDP1.24 296.99,69.47 ; JMDP1.24 298.07,68.75 ; JMDP1.24 296.99,68.03 ; JMDP1.24 295.91,69.47 ; JMDP1.24 295.91,68.75 ; JMDP1.24 295.91,68.03 ; JMDP1.24 298.07,68.03 ; JMDP1.24 298.07,69.47 ; 291.11,68.73 JMDP1.23 ; JMDP1.23 292.29,70.17 ; JMDP1.23 291.11,69.45 ; JMDP1.23 293.47,70.17 ; JMDP1.23 293.47,69.45 ; JMDP1.23 292.29,68.73 ; JMDP1.23 293.47,68.73 ; 156.65,105.95 JDOCK1.155 ; JDOCK1.155 157.7,104 ; JDOCK1.155 158.76,104.97 ; JDOCK1.155 156.65,104.97 ; JDOCK1.155 158.76,104 ; JDOCK1.155 158.76,105.95 ; JDOCK1.155 156.65,104 ; JUSB3.4 288.8,60.48 ; JUSB3.4 288.16,60.28 ; JUSB3.4 288.8,58.82 ; JUSB3.4 289.43,59.01 ; JUSB3.4 288.16,59.01 ; JUSB3.4 287.97,59.65 ; JUSB1.12 76.85,106.51 ; JUSB1.12 76.85,103.69 ; JUSB1.12 75.9,105.1 ; JUSB1.12 75.9,103.69 ; JUSB1.12 75.9,106.51 ; 212.24,100.53 JHDMI1.5 ; JHDMI1.5 212.7,99.49 ; JHDMI1.5 212.7,100.65 ; JHDMI1.5 212.24,99.61 ; JHDMI1.5 213.16,100.53 ; JHDMI1.5 213.16,99.61 ; JDOCK1.145 128.58,101.05 ; JDOCK1.145 128.58,103.03 ; JDOCK1.145 126.47,103.03 ; JDOCK1.145 128.58,99.07 ; JDOCK1.145 127.53,103.03 ; JDOCK1.145 126.47,99.07 ; JDOCK1.145 127.53,99.07 ; JDOCK1.145 126.47,101.05 ; 81.2,95.13 JUSB1.4 ; JUSB1.4 81.77,95.3 ; JUSB1.4 80.63,95.3 ; JUSB1.4 80.46,95.87 ; JUSB1.4 81.77,96.44 ; JUSB1.4 81.94,95.87 ; JUSB1.4 80.63,96.44 ; JDOCK1.158 146.64,100.11 ; JDOCK1.158 145.7,99.79 ; JDOCK1.158 144.44,101.05 ; JDOCK1.158 146.64,101.99 ; JDOCK1.158 145.7,102.31 ; JDOCK1.158 146.96,101.05 ; JDOCK1.158 144.76,101.99 ; JDOCK1.158 144.76,100.11 ; 210.62,98.57 JHDMI1.2 ; JHDMI1.2 210.74,99.03 ; JHDMI1.2 210.74,98.11 ; JHDMI1.2 211.2,97.99 ; JHDMI1.2 211.66,98.11 ; JHDMI1.2 211.2,99.15 ; JHDMI1.2 211.66,99.03 ; 156.65,96.15 JDOCK1.163 ; JDOCK1.163 157.7,96.15 ; JDOCK1.163 156.65,98.1 ; JDOCK1.163 158.76,96.15 ; JDOCK1.163 158.76,98.1 ; JDOCK1.163 157.7,98.1 ; JDOCK1.163 158.76,97.12 ; JDOCK1.163 156.65,97.12 ; H13.1 153.29,15.65 ; H13.1 151.7,14.06 ; H13.1 150.53,14.48 ; H13.1 151.7,17.24 ; H13.1 152.87,16.82 ; H13.1 150.11,15.65 ; H13.1 152.87,14.48 ; H13.1 150.53,16.82 ; 229.03,107.02 H4.1 ; H4.1 231.79,105.85 ; H4.1 229.03,104.68 ; H4.1 231.38,104.68 ; H4.1 230.2,104.26 ; H4.1 230.2,107.44 ; H4.1 228.61,105.85 ; H4.1 231.38,107.02 ; 127.14,105.95 JDOCK1.153 ; JDOCK1.153 131.26,104.97 ; JDOCK1.153 131.26,104 ; JDOCK1.153 127.14,104 ; JDOCK1.153 129.2,104 ; JDOCK1.153 131.26,105.95 ; JDOCK1.153 127.14,104.97 ; JDOCK1.153 129.2,105.95 ; H6.1 292.89,90.65 ; H6.1 289.71,90.65 ; H6.1 290.13,91.82 ; H6.1 291.3,92.24 ; H6.1 291.3,89.06 ; H6.1 292.47,91.82 ; H6.1 290.13,89.48 ; H6.1 292.47,89.48 ; JHDMI1.20 208.83,99.17 ; JHDMI1.20 208.83,97.42 ; JHDMI1.20 207.07,97.42 ; JHDMI1.20 208.83,100.92 ; JHDMI1.20 207.95,97.42 ; JHDMI1.20 207.07,99.17 ; 134.5,83.17 H21.1 ; H21.1 135.67,80.41 ; H21.1 134.5,80.83 ; H21.1 137.26,82 ; H21.1 136.84,80.83 ; H21.1 135.67,83.59 ; H21.1 136.84,83.17 ; H21.1 134.08,82 ; 290.22,3.18 SW1.5 ; SW1.5 290.98,1.41 ; SW1.5 291.98,2.42 ; SW1.5 290.22,1.66 ; SW1.5 290.98,3.42 ; SW1.5 291.74,1.66 ; SW1.5 291.74,3.18 ; SW1.5 289.98,2.42 ; 183.53,107.02 H3.1 ; H3.1 184.7,107.44 ; H3.1 183.53,104.68 ; H3.1 185.87,104.68 ; H3.1 183.11,105.85 ; H3.1 185.87,107.02 ; H3.1 186.29,105.85 ; H3.1 184.7,104.26 ; 289.66,55.52 JUSB3.7 ; JUSB3.7 290.3,55.32 ; JUSB3.7 289.47,56.15 ; JUSB3.7 290.3,56.98 ; JUSB3.7 289.66,56.79 ; 84.13,96.8 JUSB1.7 ; JUSB1.7 83.96,97.37 ; JUSB1.7 85.27,96.8 ; JUSB1.7 84.13,97.94 ; JUSB1.7 84.7,96.63 ; JUSB1.7 85.27,97.94 ; JUSB1.7 85.44,97.37 ; JDOCK1.160 170.76,101.05 ; JDOCK1.160 169.7,99.99 ; JDOCK1.160 169.7,102.1 ; JDOCK1.160 168.91,100.25 ; JDOCK1.160 170.5,100.25 ; JDOCK1.160 168.91,101.85 ; JDOCK1.160 170.5,101.85 ; 235.17,6.47 H12.1 ; H12.1 239.04,8.1 ; H12.1 236.8,5.86 ; H12.1 234.57,8.1 ; H12.1 235.17,9.73 ; H12.1 238.43,9.73 ; H12.1 238.43,6.47 ; H12.1 236.8,10.34 ; JUSB2.10 250.65,100.15 ; JUSB2.10 251.6,100.15 ; JUSB2.10 251.6,96.44 ; JUSB2.10 249.7,96.44 ; JUSB2.10 250.65,96.44 ; JUSB2.10 251.6,98.3 ; H11.1 301.29,11.15 ; H11.1 300.88,9.98 ; H11.1 299.7,12.74 ; H11.1 300.88,12.32 ; H11.1 298.53,9.98 ; H11.1 298.11,11.15 ; H11.1 298.53,12.32 ; H11.1 299.7,9.56 ; JMDP1.22 296.99,81.07 ; JMDP1.22 298.07,81.07 ; JMDP1.22 295.91,81.07 ; JMDP1.22 296.99,79.63 ; JMDP1.22 298.07,80.35 ; JMDP1.22 295.91,80.35 ; JMDP1.22 298.07,79.63 ; JMDP1.22 295.91,79.63 ; JHDMI1.11 216.16,100.53 ; JHDMI1.11 215.7,99.49 ; JHDMI1.11 215.24,100.53 ; JHDMI1.11 215.24,99.61 ; JHDMI1.11 216.16,99.61 ; JHDMI1.11 215.7,100.65 ; 287.17,50.58 JUSB3.11 ; JUSB3.11 288.5,48.92 ; JUSB3.11 289.83,49.75 ; JUSB3.11 289.83,50.58 ; JUSB3.11 289.83,48.92 ; JUSB3.11 288.5,50.58 ; JUSB3.11 287.17,49.75 ; JUSB3.11 287.17,48.92 ; 293.95,76.97 JMDP1.1 ; JMDP1.1 293.31,78.13 ; JMDP1.1 293.95,78.13 ; JMDP1.1 294.58,77.55 ; JMDP1.1 294.58,76.97 ; JMDP1.1 294.58,78.13 ; JDOCK1.162 145.7,98.1 ; JDOCK1.162 144.65,98.1 ; JDOCK1.162 146.76,97.12 ; JDOCK1.162 144.65,97.12 ; JDOCK1.162 146.76,98.1 ; JDOCK1.162 146.76,96.15 ; JDOCK1.162 145.7,96.15 ; JDOCK1.162 144.65,96.15 ; 275.84,63.56 H20.1 ; H20.1 276.38,62.07 ; H20.1 277.87,65.59 ; H20.1 277.87,61.53 ; H20.1 279.9,63.56 ; H20.1 279.36,62.07 ; H20.1 279.36,65.05 ; H20.1 276.38,65.05 ; JUSB1.10 93.5,96.44 ; JUSB1.10 92.55,96.44 ; JUSB1.10 91.6,96.44 ; JUSB1.10 93.5,98.3 ; JUSB1.10 92.55,100.15 ; JUSB1.10 93.5,100.15 ; JUSB3.10 289.83,62.55 ; JUSB3.10 289.83,63.38 ; JUSB3.10 287.17,61.72 ; JUSB3.10 289.83,61.72 ; JUSB3.10 287.17,62.55 ; JUSB3.10 288.5,61.72 ; JUSB3.10 287.17,63.38 ; JUSB3.10 288.5,63.38 ; JUSB1.13 93.5,105.1 ; JUSB1.13 92.55,106.51 ; JUSB1.13 93.5,103.69 ; JUSB1.13 93.5,106.51 ; JUSB1.13 92.55,103.69 ; 282.11,49.65 H9.1 ; H9.1 284.88,50.82 ; H9.1 283.7,51.24 ; H9.1 282.53,48.48 ; H9.1 282.53,50.82 ; H9.1 284.88,48.48 ; H9.1 283.7,48.06 ; H9.1 285.29,49.65 ; H10.1 241.94,43.65 ; H10.1 241.52,44.82 ; H10.1 239.18,42.48 ; H10.1 240.35,45.24 ; H10.1 239.18,44.82 ; H10.1 241.52,42.48 ; H10.1 240.35,42.06 ; H10.1 238.76,43.65 ; 265.38,23.11 H19.1 ; H19.1 264.84,24.6 ; H19.1 266.87,26.63 ; H19.1 268.9,24.6 ; H19.1 265.38,26.09 ; H19.1 268.36,26.09 ; H19.1 266.87,22.57 ; H19.1 268.36,23.11 ; 172.14,104 JDOCK1.156 ; JDOCK1.156 176.26,104 ; JDOCK1.156 176.26,105.95 ; JDOCK1.156 176.26,104.97 ; JDOCK1.156 172.14,104.97 ; JDOCK1.156 172.14,105.95 ; JDOCK1.156 174.2,105.95 ; JDOCK1.156 174.2,104 ; 218.24,99.61 JHDMI1.17 ; JHDMI1.17 219.16,100.53 ; JHDMI1.17 219.16,99.61 ; JHDMI1.17 218.7,99.49 ; JHDMI1.17 218.7,100.65 ; JHDMI1.17 218.24,100.53 ; H7.1 69.98,63.14 ; H7.1 68.39,61.55 ; H7.1 69.98,59.96 ; H7.1 71.15,60.38 ; H7.1 71.15,62.72 ; H7.1 71.57,61.55 ; H7.1 68.81,62.72 ; H7.1 68.81,60.38 ; H22.1 94.28,88.9 ; H22.1 90.68,87.38 ; H22.1 92.2,86.82 ; H22.1 90.12,88.9 ; H22.1 93.72,90.42 ; H22.1 92.2,90.98 ; H22.1 93.72,87.38 ; H22.1 90.68,90.42 ; 176.23,54.03 H16.1 ; H16.1 177.82,50.25 ; H16.1 177.82,54.62 ; H16.1 176.23,50.84 ; H16.1 180.01,52.43 ; H16.1 179.42,54.03 ; H16.1 175.64,52.43 ; H16.1 179.42,50.84 ; 132.65,101.05 JDOCK1.157 ; JDOCK1.157 134.5,100.25 ; JDOCK1.157 134.5,101.85 ; JDOCK1.157 132.91,100.25 ; JDOCK1.157 133.7,102.1 ; JDOCK1.157 133.7,99.99 ; JDOCK1.157 132.91,101.85 ; SW1.4 298.28,2.42 ; SW1.4 298.04,1.66 ; SW1.4 297.28,3.42 ; SW1.4 298.04,3.18 ; SW1.4 296.52,1.66 ; SW1.4 297.28,1.41 ; SW1.4 296.52,3.18 ; SW1.4 296.28,2.42 ; 127.14,98.1 JDOCK1.161 ; JDOCK1.161 129.2,98.1 ; JDOCK1.161 127.14,97.12 ; JDOCK1.161 131.26,97.12 ; JDOCK1.161 131.26,98.1 ; JDOCK1.161 129.2,96.15 ; JDOCK1.161 127.14,96.15 ; JDOCK1.161 131.26,96.15 ; H14.1 124.09,76.17 ; H14.1 122.5,72.39 ; H14.1 122.5,76.76 ; H14.1 120.9,76.17 ; H14.1 124.09,72.98 ; H14.1 124.68,74.57 ; H14.1 120.31,74.57 ; H14.1 120.9,72.98 ; 156.76,101.99 JDOCK1.159 ; JDOCK1.159 156.76,100.11 ; JDOCK1.159 157.7,99.79 ; JDOCK1.159 157.7,102.31 ; JDOCK1.159 156.44,101.05 ; JDOCK1.159 158.64,100.11 ; JDOCK1.159 158.64,101.99 ; JDOCK1.159 158.96,101.05 ; 221.57,100.92 JHDMI1.21 ; JHDMI1.21 223.33,99.17 ; JHDMI1.21 221.57,97.42 ; JHDMI1.21 221.57,99.17 ; JHDMI1.21 223.33,97.42 ; JHDMI1.21 222.45,97.42 ; H17.1 179.42,72.98 ; H17.1 175.64,74.57 ; H17.1 180.01,74.57 ; H17.1 176.23,76.17 ; H17.1 179.42,76.17 ; H17.1 176.23,72.98 ; H17.1 177.82,72.39 ; H17.1 177.82,76.76 ; 297.75,48.45 298.93,47.67 ; 297.75,48.45 296.57,47.67 ; 297.75,48.45 298.93,48.45 ; 297.75,48.45 296.57,48.45 ; 297.75,48.45 297.75,47.67 ; H15.1 124.09,54.03 ; H15.1 120.9,54.03 ; H15.1 124.68,52.43 ; H15.1 124.09,50.84 ; H15.1 122.5,54.62 ; H15.1 122.5,50.25 ; H15.1 120.9,50.84 ; H15.1 120.31,52.43 ; 234,98.3 JUSB2.11 ; JUSB2.11 234.95,100.15 ; JUSB2.11 234.95,96.44 ; JUSB2.11 234,100.15 ; JUSB2.11 234,96.44 ; JUSB2.11 235.9,96.44 ; JMDP1.19 294.58,72.13 ; JMDP1.19 293.31,70.97 ; JMDP1.19 294.58,71.55 ; JMDP1.19 294.58,70.97 ; JMDP1.19 293.95,70.97 ; JMDP1.19 293.95,72.13 ; 172.14,97.12 JDOCK1.164 ; JDOCK1.164 176.26,96.15 ; JDOCK1.164 176.26,98.1 ; JDOCK1.164 172.14,98.1 ; JDOCK1.164 174.2,98.1 ; JDOCK1.164 172.14,96.15 ; JDOCK1.164 176.26,97.12 ; JDOCK1.164 174.2,96.15 ; 293.95,72.97 JMDP1.13 ; JMDP1.13 293.95,74.13 ; JMDP1.13 294.58,72.97 ; JMDP1.13 293.31,74.13 ; 239.3,95.13 JUSB2.4 ; JUSB2.4 240.04,95.87 ; JUSB2.4 239.87,96.44 ; JUSB2.4 238.73,96.44 ; JUSB2.4 239.87,95.3 ; JUSB2.4 238.73,95.3 ; JUSB2.4 238.56,95.87 ; JMDP1.21 293.47,78.93 ; JMDP1.21 291.11,80.37 ; JMDP1.21 292.29,78.93 ; JMDP1.21 293.47,80.37 ; JMDP1.21 291.11,79.65 ; JMDP1.21 292.29,80.37 ; JMDP1.21 293.47,79.65 ; 293.31,74.97 JMDP1.7 ; JMDP1.7 293.95,74.97 ; JMDP1.7 293.95,76.13 ; JMDP1.7 294.58,76.13 ; JHDMI1.22 205.95,107.73 ; JHDMI1.22 207.03,106.15 ; JHDMI1.22 207.03,104.57 ; JHDMI1.22 204.87,104.57 ; JHDMI1.22 204.87,107.73 ; JHDMI1.22 205.95,104.57 ; JHDMI1.22 207.03,107.73 ; JHDMI1.22 204.87,106.15 ; JDOCK1.154 146.76,104 ; JDOCK1.154 145.7,105.95 ; JDOCK1.154 144.65,104.97 ; JDOCK1.154 146.76,104.97 ; JDOCK1.154 144.65,104 ; JDOCK1.154 145.7,104 ; JDOCK1.154 146.76,105.95 ; JDOCK1.154 144.65,105.95 ; 242.06,97.37 JUSB2.7 ; JUSB2.7 242.23,97.94 ; JUSB2.7 243.54,97.37 ; JUSB2.7 243.37,97.94 ; JUSB2.7 243.37,96.8 ; JUSB2.7 242.23,96.8 ; JUSB2.7 242.8,96.63 ; 117.53,107.02 H2.1 ; H2.1 120.29,105.85 ; H2.1 118.7,104.26 ; H2.1 117.53,104.68 ; H2.1 119.87,104.68 ; H2.1 117.11,105.85 ; H2.1 119.87,107.02 ; H2.1 118.7,107.44 ; JDOCK1.152 176.93,103.03 ; JDOCK1.152 174.82,101.05 ; JDOCK1.152 174.82,103.03 ; JDOCK1.152 174.82,99.07 ; JDOCK1.152 176.93,101.05 ; JDOCK1.152 175.88,103.03 ; JDOCK1.152 176.93,99.07 ; JDOCK1.152 175.88,99.07 ; JUSB3.12 297.75,64.62 ; JUSB3.12 296.57,64.62 ; JUSB3.12 296.57,63.85 ; JUSB3.12 298.93,64.62 ; JUSB3.12 298.93,63.85 ; JUSB2.13 251.6,105.1 ; JUSB2.13 250.65,106.51 ; JUSB2.13 251.6,106.51 ; JUSB2.13 250.65,103.69 ; JUSB2.13 251.6,103.69 ; JHDMI1.8 214.66,98.11 ; JHDMI1.8 213.74,99.03 ; JHDMI1.8 214.66,99.03 ; JHDMI1.8 214.2,97.99 ; JHDMI1.8 213.74,98.11 ; JHDMI1.8 214.2,99.15 ; H1.1 56.7,107.44 ; H1.1 55.53,104.68 ; H1.1 56.7,104.26 ; H1.1 58.29,105.85 ; H1.1 57.87,104.68 ; H1.1 57.87,107.02 ; H1.1 55.53,107.02 ; H1.1 55.11,105.85 ; 234,105.1 JUSB2.12 ; JUSB2.12 234.95,103.69 ; JUSB2.12 234,106.51 ; JUSB2.12 234,103.69 ; JUSB2.12 234.95,106.51 ; 75.9,100.15 JUSB1.11 ; JUSB1.11 76.85,96.44 ; JUSB1.11 75.9,96.44 ; JUSB1.11 77.8,96.44 ; JUSB1.11 76.85,100.15 ; JUSB1.11 75.9,98.3 ; JHDMI1.23 225.53,106.15 ; JHDMI1.23 224.45,104.57 ; JHDMI1.23 223.37,106.15 ; JHDMI1.23 223.37,104.57 ; JHDMI1.23 225.53,107.73 ; JHDMI1.23 225.53,104.57 ; JHDMI1.23 224.45,107.73 ; JHDMI1.23 223.37,107.73 ; 262.93,101.95 JLOM1.16 ; JLOM1.16 262.01,105.45 ; JLOM1.16 262.01,103.7 ; JLOM1.16 262.01,101.95 ; JLOM1.16 262.93,105.45
  BOTTOM w0.127: UC1.AV46 142.89,52.33 143.25,52.7 143.25,52.96 143.24,52.98 143.24,53.29 ; UC1.AV39 147.61,52.33 147.98,52.7 147.98,53.2 147.96,53.22 ; UC1.AV41 146.04,52.33 146.4,52.7 146.4,53.18 146.45,53.22 ; 149.48,53.22 149.55,53.15 149.55,52.7 149.19,52.33 UC1.AV36 ; UC1.AV43 144.46,52.33 144.83,52.7 144.83,53.17 144.78,53.21
  BOTTOM w0.152: v2(154.92,50.04) 154.92,50.1 155.11,50.29 UC1.AY26 ; UC1.AD3 169.42,60.33 169.09,60.66 168.7,60.66 168.5,60.47 168.5,60.32 v2(168.2,60.01)
  BOTTOM w0.178: UC1.AN63 131.41,55.12 v2(131.28,54.99) ; UC1.AT46 UC1.AT43 ; UC1.AV51 UC1.AW51 UC1.AY51 139.8,49.46 v2(139.94,49.33) ; UC1.AV24 UC1.AW24 UC1.AY24 156.47,50.35 v2(156.39,50.27) ; v2(161.65,50.18) 161.65,50.18 161.6,50.23 161.6,50.88 161.61,50.9 161.61,51.01 161.6,51.02 UC1.AY16 161.56,51.24 UC1.AW16 UC1.AV16 ; v2(134.66,50.27) 134.7,50.3 UC1.AY59 ; v2(152.61,50.28) 152.68,50.36 UC1.AY30 ; UC1.AW33 151.33,52.45 UC1.AV33 ; UC1.AW33 UC1.AY33 ; UC1.AW33 151.09,51.85 UC1.AV34 ; v2(138.26,50) 138.34,50.08 138.34,50.44 138.45,50.55 UC1.AY53 ; v2(150.62,53.73) 150.35,53.46 UC1.AT35 ; v2(135.95,50.23) 136.02,50.3 UC1.AY57 ; UC1.AV59 UC1.AW59 ; v2(131.3,57.28) 131.52,57.28 131.79,57.55 UC1.AJ63 ; 148.21,53.22 147.96,53.22 ; UC1.AR52 139,54.19 139,54.44 UC1.AP52 ; v2(167.55,72.22) 167.43,72.22 166.93,71.72 UC1.D8 ; UC1.AY18 160.25,50.35 v2(160.18,50.28) ; UC1.AY22 157.82,50.32 v2(157.88,50.26) ; UC1.AD63 132.14,60.34 v2(131.64,60.34) ; UC1.AU30 152.17,53.15 152.15,53.18 UC1.AU33 ; UC1.D2 170.06,71.43 169.67,71.82 169.17,71.82 v2(169.05,71.94)
  BOTTOM w0.203: UC1.AN49 140.88,55.29 140.77,55.18 140.4,55.18 140.29,55.29 UC1.AN51 139.95,55.29 139.82,55.16 139.44,55.16 139.31,55.29 UC1.AN52 ; v2(133.16,61.46) 133.16,61.35 133.46,61.05 UC1.AC61 ; PU200.3 PU200.21 ; UC1.Y63 131.7,62.58 v2(131.59,62.47) ; UC1.K1 170.84,67.78 171.13,68.07 v2(171.31,68.07) ; UC1.D59 134.88,71.29 135.41,70.77 UC1.F58 ; v2(165.53,52.5) 165.85,52.18 UC1.AV8 ; UC1.B56 UC1.A56 ; v2(131.58,68.7) 131.7,68.57 UC1.J63 ; v2(167.33,50.36) 167.41,50.44 UC1.AY6 ; UC1.AW60 134.46,51.53 UC1.AW59 ; v2(68.12,11.09) 68.41,11.39 PU200.1 ; UV10.11 219.7,75.55 v2(219.78,75.63) ; v2(169.78,65.91) 169.48,66.21 UC1.N3 ; UC1.B44 UC1.A44 ; v2(167.48,55.67) 167.29,55.67 UC1.AN7 ; v2(169.21,62.92) 169.21,63.05 UC1.V3 ; v2(169.15,53.96) 169.48,54.29 UC1.AP3 ; v2(133.16,70.45) 133.46,70.15 UC1.F61 ; UC1.AU51 139.31,53.15 139.28,53.18 138.98,53.18 138.95,53.15 UC1.AU53 ; v2(133.16,64.45) 133.46,64.15 UC1.U61 ; v2(168.2,60.01) 168.2,59.6 UC1.AE5 ; PU501.3 102.76,56.79 v2(102.73,56.75) ; UC1.AM1 171.19,55.8 v2(171.4,56) ; v2(169.09,56.93) 169.48,57.33 UC1.AK3 ; UC1.T1 v2(171.32,64.79) ; UC1.AW4 168.81,50.93 UC1.AY4 168.86,50.38 v2(169.06,50.18) ; UC1.A52 UC1.B52
  BOTTOM w0.229: UC1.AN31 UC1.AM31 UC1.AL31 152.52,57.06 v2(153.03,57.57) 153.36,57.89 UC1.AJ29 ; UC1.AN31 UC1.AP31 UC1.AR31 152.52,53.31 UC1.AU30 153.06,53.15 153.1,53.2 153.41,53.2 153.45,53.15 UC1.AU28 154.35,53.15 154.39,53.2 154.7,53.2 154.74,53.15 UC1.AU26 155.59,53.15 155.64,53.2 155.94,53.2 155.99,53.15 UC1.AU24 ; UC1.AN31 152.19,55.62 151.96,55.39 UC1.AN32 ; v2(145.28,57.66) 145.51,57.89 UC1.AJ41 ; v2(145.28,57.66) 145.16,57.77 UC1.AH42 ; v2(145.28,57.66) 144.75,57.66 UC1.AJ43 ; UC1.AP38 148.08,54.64 v2(147.76,54.31) UC1.AR39 ; v2(148.71,55.12) 148.88,55.29 UC1.AN36 ; UC1.AH49 141.26,57.77 v2(141.37,57.66) ; UC1.AU53 138.08,53.15 138.04,53.2 137.73,53.2 137.69,53.15 UC1.AU55 136.79,53.15 136.74,53.2 136.44,53.2 136.39,53.15 UC1.AU57 135.54,53.15 135.5,53.2 135.19,53.2 135.15,53.15 UC1.AU59 ; UC1.AH34 150.36,57.79 v2(150.51,57.63) ; UC1.AH34 150.13,58.45 v2(149.71,58.45) ; UC1.AH34 v2(150.85,58.71) ; UC1.H13 v2(163.02,69.33) ; v2(131.45,58.81) 131.63,58.99 132.39,58.99 UC1.AG63 UC1.AG62 UC1.AG61 UC1.AG60 ; v2(167.02,63.84) 166.85,63.66 UC1.V7 ; UC1.F30 153,69.8 v2(152.99,69.8) ; v2(154.94,54.31) 155.26,54.64 UC1.AP26 ; UC1.AL60 UC1.AL61 133.31,56.34 v2(133.27,56.3) ; UC1.AL60 134.43,56.79 134.47,56.83 134.47,57.14 134.43,57.18 UC1.AJ60 ; UC1.AL60 134.43,55.97 134.48,55.92 134.48,55.54 134.43,55.49 UC1.AN60 134.43,54.64 134.47,54.6 134.47,54.13 v2(134.34,54) ; UC1.AW50 140.55,51.53 v2(140.9,51.88) 141.01,51.88 UC1.AV49 ; UC1.F42 145.48,69.8 v2(145.47,69.8) ; UC1.U22 v2(158.75,64.05) 158.18,64.62 UC1.R22 ; v2(137.95,69.8) 137.95,69.8 UC1.F54 ; UC1.AW35 150.29,51.88 v2(150.35,51.88) 150.35,51.89 150.64,52.18 UC1.AV34 ; v2(140.46,69.8) 140.46,69.8 UC1.F50 ; v2(149.71,58.45) UC1.AJ35 ; v2(149.71,58.45) 149.29,58.45 UC1.AH36 ; v2(141.49,54.31) 141.82,54.64 UC1.AP48 UC1.AN48 ; UC1.AN23 157.17,55.29 v2(156.84,54.96) 157.17,54.64 UC1.AP23 ; UC1.AL46 143.25,56.32 v2(143.44,56.32) 143.64,56.32 143.9,56.59 UC1.AL45 ; v2(150.62,56.33) 150.88,56.59 UC1.AL33 ; UC1.AR15 162.43,53.59 v2(162.19,53.59) ; 157.17,57.24 v2(156.84,57.57) 156.86,57.59 UC1.AH24 ; 157.17,57.24 UC1.AK23 ; 157.17,57.24 v2(156.84,56.92) 157.17,56.59 ; v2(137.27,52) 137.24,52.03 UC1.AV55 ; UC1.AJ58 135.73,57.89 UC1.AH57 136.38,57.89 UC1.AJ56 ; v2(164.18,62.95) 164.76,62.95 UC1.Y10 ; UC1.AJ25 156.21,57.79 156.01,57.58 v2(155.75,57.58) 155.67,57.66 155.15,57.66 UC1.AJ27 ; v2(164.72,57.03) 165.02,56.73 UC1.AL10 ; v2(158.75,61.61) UC1.AB22 ; UC1.J10 165.18,68.29 v2(164.82,68.64) ; UC1.E11 164.37,70.9 164.08,71.19 v2(163.95,71.19) 164.05,71.29 UC1.D12 ; UC1.AP54 138.11,54.64 v2(137.78,54.31) ; UC1.AN42 145.94,55.29 v2(146.26,54.96) 146.59,55.29 UC1.AN40 ; UC1.AB7 166.8,61.45 166.37,61.02 v2(166.37,60.96) ; v2(148.78,51.83) 148.47,51.53 UC1.AW37 ; UC1.AP22 158.01,54.64 v2(157.69,54.31) ; UC1.AU33 151.17,53.18 v2(150.62,53.73) 150.88,53.99 UC1.AR33 ; v2(169.05,71.94) 168.93,71.82 168.28,71.82 168.23,71.78 168.22,71.78 UC1.D5 ; UC1.AL17 161.56,56.93 162.25,57.61 v2(162.25,57.6) ; UC1.F26 155.51,69.8 v2(155.5,69.8) ; UC1.AP39 146.98,54.96 UC1.AN40 ; UC1.AN39 146.98,55.62 UC1.AN40 ; v2(139.63,56.27) 139.96,56.59 UC1.AL51 ; UC1.AR43 144.72,53.99 v2(144.39,53.66) 144.05,53.32 UC1.AT43 144.12,53.21 145.55,53.21 UC1.AT42 146.01,53.29 146.08,53.22 146.45,53.22 146.51,53.29 UC1.AT40 147.27,53.21 148.2,53.21 148.28,53.29 UC1.AT37 149.41,53.29 149.48,53.22 149.85,53.22 149.92,53.29 UC1.AT35 ; UC1.AB20 159.95,61.96 v2(160.05,61.96) ; UC1.AW42 145.29,51.53 v2(145.63,51.87) 145.94,52.18 UC1.AV41 ; v2(141.37,57.66) 141.67,57.66 141.9,57.89 UC1.AJ47 142.26,57.89 v2(142.49,57.66) 142.98,57.66 UC1.AJ45 ; v2(141.37,57.66) 140.91,57.66 140.68,57.89 UC1.AJ50 ; 157.17,56.59 UC1.AL23 ; 157.17,56.59 v2(156.84,56.27) 157.17,55.94 UC1.AM23 ; UC1.AN52 139.05,55.29 138.8,55.04 v2(138.71,55.04) ; UC1.AH28 154.26,58.59 v2(154.12,58.74) ; v2(158.57,66.04) 158.18,66.43 UC1.M22 ; v2(158.57,66.04) 158.61,66.08 UC1.N21 ; v2(158.57,66.04) 158.2,65.68 UC1.P22 ; v2(161.02,69.26) 161.18,69.26 161.51,68.94 UC1.H17 ; UC1.L61 133.46,67.15 v2(133.17,67.44) ; v2(153.03,56.27) 153.36,56.59 UC1.AL29 ; v2(149.66,54.96) 149.99,55.29 UC1.AN35 ; UC1.AF18 160.19,59.69 160.05,59.69 160.05,59.7 v2(160.06,59.7) ; UC1.AF14 163.09,59.24 v2(163.09,59.81) ; UC1.AL54 138.19,56.59 v2(138.68,57.08) ; UC1.AN48 142.22,55.29 v2(142.49,55.56) 142.76,55.29 UC1.AN46 143.09,55.18 143.8,55.18 UC1.AN45 144.17,55.03 144.63,55.03 UC1.AN43 ; UC1.AN48 141.76,55.12 141.2,55.12 UC1.AN49 ; v2(158.7,59.94) 158.69,59.94 158.69,59.91 159.1,60.31 159.1,60.36 ; UC1.AV46 142.83,52.18 v2(142.47,51.83) 142.18,51.53 UC1.AW47 ; UC1.AW40 146.84,51.53 v2(147.2,51.88) 147.49,52.18 UC1.AV39 ; v2(156.91,53.47) 157.04,53.47 157.35,53.15 UC1.AU22 158.19,53.15 158.23,53.2 158.54,53.2 158.58,53.15 UC1.AU20 159.48,53.15 159.53,53.2 159.83,53.2 159.87,53.15 UC1.AU18 160.73,53.15 160.77,53.2 161.08,53.2 161.12,53.15 UC1.AU16 ; UC1.AJ39 147.47,57.89 147.76,57.6 v2(147.76,57.57) ; UC1.AJ39 147.11,57.42 147.24,57.28 UC1.AL39 ; UC1.AJ39 v2(147.11,58.45) ; v2(138.75,56.27) 138.81,56.27 139.14,55.94 ; v2(153.93,52) 153.9,52.03 UC1.AV28 ; UC1.AH17 161.25,57.85 161.7,57.85 UC1.AH16 ; UC1.AH40 146.69,58.45 v2(147.11,58.45) ; UC1.AV20 159.03,52.03 v2(159.07,52) ; UC1.AL22 158.01,56.59 v2(157.69,56.27) ; v2(157.29,63.25) 157.67,63.62 UC1.V23 158.08,63.24 UC1.W22 ; v2(154.94,56.27) 155.26,56.59 UC1.AL26 ; UC1.AH32 151.55,58.1 v2(151.55,57.57) ; UC1.F34 150.49,69.8 v2(150.49,69.8) ; v2(147.11,58.45) 147.53,58.45 UC1.AH38 ; UC1.AP29 153.36,54.64 v2(153.03,54.31) ; v2(164.35,59.79) 164.35,59.6 UC1.AF11 ; v2(163.96,57.02) 163.6,57.38 UC1.AJ13 163.32,57.2 163.32,56.85 UC1.AL13 162.69,57.25 UC1.AJ14 ; v2(171.3,58.67) 171.18,58.79 UC1.AG1 ; v2(142.96,69.8) 142.97,69.8 UC1.F46 ; UC1.A18 160.18,73.93 v2(160.21,73.97) ; v2(138.68,57.08) 138.84,57.24 UC1.AK52 139.31,57.35 UC1.AJ52 ; v2(138.68,57.08) 138.66,57.1 UC1.AH53 ; v2(135.88,54.31) 136.2,54.64 UC1.AP57 ; UC1.W20 159.64,63.24 v2(160.03,63.63) UC1.U20 ; v2(138.73,55.64) 138.84,55.64 139.14,55.94 ; v2(147.98,69.8) 147.98,69.8 UC1.F38 ; v2(148.71,56.42) 148.88,56.59 UC1.AL36 ; UC1.AP20 159.92,54.64 v2(159.59,54.31) ; UC1.AV43 144.46,52.13 144.2,51.87 v2(144.06,51.87) 143.71,51.53 UC1.AW44 ; UC1.AL20 159.92,56.59 v2(159.59,56.27) ; 139.14,55.94 UC1.AM52 ; UC1.AL57 136.2,56.59 v2(135.88,56.27) ; UC1.D18 160.68,71.6 v2(161.02,71.27) 161.03,71.27 161.4,70.89 UC1.E17 ; v2(164.41,50.18) UC1.AY11
  BOTTOM w0.254: v2(134.34,54) 134.22,53.87 UC1.AT61 133.73,53.82 UC1.AT62 132.79,53.82 132.64,53.66 UC1.AT63 132.03,53.66 v2(131.72,53.35) ; JDOCK1.43 143.45,95.59 v2(143.63,95.41) ; v2(160.39,57.48) 160.25,57.62 UC1.AH19 UC1.AH17 ; UC1.AE10 165.22,59.55 165.22,59.54 165.04,59.54 UC1.AF11 164.32,58.82 ; 110.96,91.35 JEDP1.25 v2(110.96,89.28) ; v2(244.33,81.96) 244.71,82.34 244.71,83.04 244.64,83.12 UI5.6 ; 165.45,98.41 165.95,97.91 JDOCK1.125 ; 165.45,98.41 JDOCK1.123 ; 165.45,98.41 v2(165.09,98.77) ; 164.32,58.82 UC1.AF12 ; 164.32,58.82 UC1.AG11 ; UC1.AL40 147.24,56 UC1.AN39 ; UC1.AL40 146.26,56.2 146.26,56.2 v2(146.24,56.21) ; UC1.AL40 146.98,56.92 UC1.AL39 ; v2(166.99,67.63) 166.85,67.48 UC1.L7 ; v2(153.97,106.33) 153.95,106.31 JDOCK1.82 ; JDOCK1.93 156.95,95.93 156.77,95.74 v2(156.45,95.74) JDOCK1.91 ; v2(164.26,95.8) 164.45,96 JDOCK1.119 ; UC1.F30 UC1.D30 ; UC1.AJ14 162.47,57.38 v2(162.25,57.6) ; JSATA1.14 v2(265.44,5.64) ; UC1.AP10 165.16,54.78 v2(165.48,54.46) ; v2(134.46,65.95) 134.76,65.65 UC1.P59 ; v2(155.38,106.34) 155.45,106.27 JDOCK1.88 ; UC1.AR52 139.02,53.99 138.45,53.42 UC1.AU53 ; JDOCK1.37 141.95,95.94 v2(141.77,95.76) ; UC1.A28 UC1.B28 ; JDOCK1.120 164.45,106.32 v2(164.52,106.39) ; v2(161.02,69.26) 160.87,69.26 160.56,69.57 UC1.G18 ; v2(135.91,64.9) 135.79,64.78 UC1.T58 ; JDOCK1.69 150.95,95.86 v2(150.77,95.68) ; UC1.F50 UC1.D50 ; UC1.G5 168.07,69.59 v2(167.76,69.9) 167.45,69.59 UC1.G6 166.9,69.91 v2(166.8,69.91) 166.6,69.91 UC1.G8 ; JDOCK1.57 147.95,98.21 147.83,98.34 v2(147.38,98.34) 147.45,98.26 JDOCK1.55 ; v2(167.57,106.84) 167.45,106.72 JDOCK1.132 ; UC1.AH32 v2(152.15,58.71) ; UC1.B20 159.07,73.01 v2(159.42,73.01) 159.42,72.72 159.27,72.57 UC1.C20 ; UC1.AF17 161.47,59.44 v2(161.86,59.82) 161.86,59.74 162.29,59.31 UC1.AF15 ; UC1.AT13 163.39,53.3 v2(163.75,53.3) 164.21,53.3 164.56,53.65 UC1.AR11 ; 102.46,91.34 JEDP1.8 v2(102.46,89.28) ; UC1.AH51 v2(140.45,58.71) ; UC1.AH51 140.28,57.89 UC1.AJ50 ; UC1.AH51 139.63,57.89 UC1.AJ52 ; v2(100.46,89.28) JEDP1.4 100.46,91.44 100.45,91.44 ; JDOCK1.95 158.45,96.15 158.8,95.8 v2(159.18,95.8) ; UI5.5 244.99,84.31 v2(245.36,84.68) ; JDOCK1.13 135.95,95.85 v2(135.81,95.71) ; UC1.AU24 156.6,53.15 v2(156.91,53.47) 156.91,53.66 157.24,53.99 UC1.AR23 ; v2(140.62,53.74) 140.87,53.48 UC1.AT49 ; v2(140.62,53.74) 140.39,53.74 UC1.AU51 ; v2(140.62,53.74) 140.87,53.99 UC1.AR49 ; UC1.J59 134.76,68.57 134.43,68.9 v2(134.43,68.89) ; v2(137.45,103.74) JDOCK1.20 ; UC1.AH22 158.8,58.36 UC1.AG21 158.83,57.89 v2(158.95,57.77) 159.2,58.03 UC1.AH20 ; v2(139.14,58.71) UC1.AH53 138.33,57.89 UC1.AJ54 137.68,57.89 UC1.AH55 ; JDOCK1.108 v2(161.45,106.33) ; v2(145.39,55.02) 145.38,55.02 145.45,55.09 145.64,55.09 UC1.AN42 ; 112.46,91.38 JEDP1.28 112.46,89.53 v2(112.2,89.28) 111.96,89.53 JEDP1.27 111.96,91.37 ; UC1.AJ27 154.59,57.89 UC1.AH28 153.94,57.89 UC1.AJ29 ; v2(162.54,52.5) 162.87,52.18 UC1.AV14 ; v2(161.97,99.12) 161.45,98.6 JDOCK1.107 ; v2(171.38,52.72) 171.25,52.85 UC1.AU1 ; v2(266.61,37.08) 265.3,37.08 v3(265.22,36.99) ; JDOCK1.63 149.45,96.19 v2(148.99,95.72) 148.95,95.76 JDOCK1.61 ; v2(143.31,106.46) 143.45,106.32 JDOCK1.44 ; v2(265.34,76.68) 264.25,76.68 v3(264.14,76.78) ; UC1.AH49 v2(141.75,58.71) ; UC1.AH40 146.32,58.08 v2(146.32,57.67) 146.04,57.67 UC1.AJ41 ; v3(41.78,13.06) v2(42.35,12.48) ; v2(134.45,103.74) JDOCK1.8 ; v3(279.89,77.57) 279.59,77.27 v2(279.59,76.63) ; v2(163.05,98.49) 162.95,98.39 JDOCK1.113 ; v2(132.95,95.68) JDOCK1.1 ; UC1.Y59 134.76,62.64 v2(134.47,62.93) ; v2(138.95,103.74) JDOCK1.26 ; UC1.AH55 137.03,57.89 UC1.AJ56 ; UC1.AH55 137.36,58.34 v2(137.79,58.78) ; v2(168.35,54.07) 167.94,54.07 UC1.AR5 ; JDOCK1.102 v2(159.95,106.33) ; v2(262.19,84.94) 262.47,85.22 v3(262.47,85.83) ; JSATA1.12 264.44,6.13 264.45,6.12 v2(264.45,5.51) ; v2(101.46,89.28) JEDP1.6 101.46,91.36 ; JSATA1.18 v2(267.44,5.68) ; UC1.AJ60 134.6,57.55 v2(134.88,57.83) ; UC1.AG23 UC1.AJ23 158.04,57.95 v2(158.29,57.7) ; UC1.R8 UC1.R10 164.62,65.26 v2(164.25,65.63) 164.83,66.22 UC1.N10 ; UC1.AL17 UC1.AM17 UC1.AN17 UC1.AP17 UC1.AR17 161.56,53.96 161.93,53.59 v2(162.19,53.59) ; JDOCK1.101 159.95,98.47 v2(160.02,98.53) ; v2(153.49,95.74) 153.6,95.74 153.95,96.1 JDOCK1.81 ; v2(152.26,95.68) 152.45,95.87 JDOCK1.75 ; v2(169.84,68.91) 169.84,69.02 169.54,69.32 UC1.G3 ; UI1.1 93.15,84.21 v3(93.33,84.02) ; UC1.B4 168.39,72.86 v2(168.36,72.9) ; JDOCK1.87 v2(155.45,95.74) ; UC1.U9 165.31,63.39 UC1.V10 164.8,63.87 163.4,63.87 v2(163.13,63.6) ; JDOCK1.49 144.95,95.86 v2(144.7,95.61) 144.45,95.86 JDOCK1.47 ; JEDP1.15 v2(105.96,89.28) ; v2(131.57,65.44) 131.71,65.58 UC1.P63 UC1.P62 ; JDOCK1.58 v2(147.95,106.34) ; JDOCK1.38 v2(141.95,103.74) ; UC1.F58 135.41,69.96 v2(135.27,69.83) 135.7,69.41 UC1.H57 ; v2(140.27,95.76) 140.45,95.94 JDOCK1.31 ; UC1.D12 164.4,72.08 164.4,72.28 UC1.C11 ; UC1.AJ45 143.53,58.22 UC1.AH44 ; UC1.F20 159.58,70.24 v2(159.11,69.77) 159.09,69.74 UC1.G22 158.55,70.11 UC1.D21 158.04,71.08 UC1.D23 ; JDOCK1.51 v2(146.45,95.68) ; JSATA1.4 v2(260.44,5.82) ; UC1.F54 UC1.D54 ; v2(135.95,103.74) JDOCK1.14 ; UC7.7 90.03,56.05 90.1,55.99 90.31,55.99 v2(90.56,56.24) ; v2(162.99,71.23) 163.26,71.5 UC1.D14 163.26,71.9 UC1.C14 162.87,72.33 162.87,73.04 162.75,73.15 UC1.A14 162.75,74.64 v2(162.35,75.04) ; UC1.D59 134.88,71.63 134.48,72.04 134.48,72.2 134.12,72.56 UC1.B60 ; RPC20.6 168.71,83.79 168.89,83.98 ; v2(167.63,95.56) 167.63,95.97 167.45,96.15 JDOCK1.131 ; UC1.C18 160.28,72.13 UC1.D18 ; JDOCK1.114 v2(162.95,106.33) ; v2(262.56,31.99) 262.56,31.99 v3(263.26,31.29) ; v2(52.07,29.31) v3(52.07,28.56) ; v2(137.36,95.71) 137.45,95.81 JDOCK1.19 ; v2(150.95,106.35) JDOCK1.70 ; v3(267.09,46.84) 267.23,46.84 v2(267.76,47.37) ; UC1.AU59 UC1.AV59 ; UC1.L17 161.06,66.9 v2(161.03,66.9) 161.02,66.9 UC1.L18 160.24,67.04 v2(160.24,66.9) 160,66.9 UC1.L20 ; UC1.AJ43 144.18,58.22 UC1.AH44 ; UC1.A24 UC1.B24 ; v2(118.11,89.28) 117.96,89.43 JEDP1.39 ; 110.46,91.41 JEDP1.24 110.46,89.53 v2(110.2,89.28) 109.96,89.53 JEDP1.23 109.96,91.42 ; v2(168.89,83.98) 168.89,83.98 ; 168.89,83.98 168.97,83.9 168.97,83.67 169.21,83.43 RPC20.7 ; UC1.K12 163.45,67.36 UC1.L13 163.42,67.13 v2(163,66.71) 162.47,67.25 UC1.L15 ; UC1.AA1 171.19,61.79 v2(171.3,61.9) ; JDOCK1.32 v2(140.45,103.74) ; UC1.AD21 159.1,60.36 ; JDOCK1.7 134.45,96.24 134.57,96.12 134.57,95.72 v2(134.57,95.71) ; v2(145.65,58.71) UC1.AH42 ; JDOCK1.137 168.95,95.91 v2(168.72,95.67) ; UC1.AH38 v2(148.25,58.71) ; v2(135.96,63.48) UC1.V58 ; v3(38.21,13.26) 38.21,13.17 v2(37.4,12.36) ; UC1.AH30 v2(153.45,58.71) ; JDOCK1.64 v2(149.45,106.35) ; UC1.AA58 v2(135.96,62.18) ; JSATA1.7 v2(261.94,5.54) ; UC1.AE58 v2(135.96,59.58) ; v2(152.79,106.35) 152.45,106.01 JDOCK1.76 ; UC1.F46 UC1.D46 ; UC1.A11 v2(164.42,74.02) ; v2(144.35,58.71) UC1.AH44 ; UC1.AB10 165.16,61.45 165.16,61.47 165.08,61.54 v2(164.2,61.54) ; UC1.AL52 139.08,56.59 v2(138.75,56.27) ; v2(135.93,67.38) UC1.L58 ; UC1.F26 UC1.D26 ; v2(168.95,106.41) JDOCK1.138 ; JDOCK1.25 v2(138.95,95.76) ; UC1.F42 UC1.D42 ; UC1.F38 UC1.D38 ; v2(131.63,71.53) UC1.D63 132.21,71.47 UC1.D62 ; v2(142.56,58.74) UC1.AH46 ; v2(165.95,106.33) JDOCK1.126 ; UC1.F34 UC1.D34
  BOTTOM w0.279: UC1.L20 159.53,67.38 158.92,67.38 UC1.J22
  BOTTOM w0.305: JNGFF2.31 233.29,63.35 233.42,63.22 v2(233.61,63.22) ; v2(275.73,6.78) 275.75,6.76 UN1.10 ; JNGFF1.28 239.76,25.1 v2(239.63,25.22) ; UN1.12 276.15,7.76 v2(275.82,8.09) 275.99,8.26 UN1.13 ; JNGFF1.22 239.93,26.6 v2(239.76,26.77) ; v2(242.34,29.97) 241.97,29.6 JNGFF1.10 ; v2(233.93,60.32) 233.87,60.26 233.27,60.26 233.18,60.35 JNGFF2.43 ; JNGFF1.67 v2(234.69,15.35) ; v2(232.22,24.28) 232.28,24.35 JNGFF1.31 ; v2(230.95,62) 231.33,62 231.48,61.85 231.56,61.85 231.56,61.85 JNGFF2.37 ; v2(235.72,27.03) 235.72,27.02 235.49,26.78 234.55,26.78 234.49,26.85 JNGFF1.21 ; JNGFF1.7 234.3,32.35 234.5,32.55 234.5,33.53 234.19,33.85 JNGFF1.1 232.47,33.85 v2(232.15,34.16) ; v2(232.22,19.72) 232.34,19.85 JNGFF1.49 ; JNGFF1.15 234.26,28.35 234.31,28.3 234.86,28.3 235.11,28.55 235.12,28.55 v2(235.37,28.8) ; JNGFF1.55 v2(234.57,18.35) ; v2(234.5,23.28) 234.08,22.85 JNGFF1.37 ; JNGFF2.49 v2(233.68,58.85) ; v2(235.58,66.78) 235.16,66.35 JNGFF2.19 ; v2(280.59,6.1) 280.43,6.26 UN1.5 ; v2(235.2,18.33) 235.2,17.56 234.49,16.85 JNGFF1.61 ; JNGFF2.25 231.33,64.85 v2(231.18,64.69) ; JNGFF1.43 234.27,21.35 v2(234.63,20.99) ; CN2.2 279.12,10.26 278.25,9.4 278.25,8.74 UN1.15 ; v2(234.19,72.43) 234.19,72.17 233.86,71.85 JNGFF2.5 ; UN1.16 278.75,9.12 v2(279.27,9.64) ; v2(235.07,25.37) 234.6,25.85 JNGFF1.25 ; v2(233.55,72.41) 233.49,72.35 JNGFF2.3 ; JNGFF2.11 v2(233.61,70.35) ; v2(239.76,28.17) 239.83,28.1 JNGFF1.16
  BOTTOM w0.356: v2(212.62,15) 212.7,15.08 JDIMM2.167 ; JDIMM2.11 163.5,17.66 v2(164.47,18.63) ; JDIMM2.2 v2(160.8,6.77) ; JDIMM1.184 v2(136.3,6.71) ; JDIMM1.173 v2(133,15.07) ; JDIMM2.26 168,7.09 v2(168.32,6.77) 168.6,7.05 JDIMM2.28 ; v2(134.66,9.78) 134.5,9.62 JDIMM1.178 ; JDIMM1.196 139.9,9.52 v2(139.05,10.38) ; v2(86.5,6.71) JDIMM1.26 ; JDIMM2.43 173.1,17.37 173.37,17.64 173.37,18.31 173.05,18.63 v2(172.82,18.63) ; JDIMM2.190 219.6,9.48 220.39,10.27 ; v2(204,6.77) JDIMM2.138 ; JDIMM1.43 91.6,15.17 v2(91.4,14.97) ; v2(89.37,14.96) 89.8,15.39 JDIMM1.37 ; v2(171.6,6.77) JDIMM2.38 ; v2(175.84,11.2) 176.4,10.63 JDIMM2.54 ; JDIMM1.25 86.2,15.28 v2(86.56,14.92) ; v2(175.84,12.72) 174.6,11.49 JDIMM2.48 ; v2(217.8,6.79) JDIMM2.184 ; v2(122.5,6.65) JDIMM1.138 ; JDIMM2.150 207.6,9.65 v2(207.95,10) ; v2(190.24,75.54) 190.23,75.55 UZ1.25 ; JDIMM2.3 161.1,15.08 v2(161.6,14.58) ; v2(84.1,10.59) 84.7,9.99 JDIMM1.20 ; JDIMM2.13 v2(164.1,14.58) ; JDIMM1.179 134.8,15.28 v2(134.56,15.04) ; JDIMM2.156 209.4,9.78 v2(210,10.38) ; JDIMM1.167 131.2,15.01 v2(131.25,14.96) ; v2(93.21,14.97) 93.4,15.16 JDIMM1.49 ; JNGFF2.63 233.17,55.35 233.49,55.66 v2(233.61,55.66) ; v2(136.6,15.05) JDIMM1.185 ; v2(125.07,10.38) 124.3,9.61 JDIMM1.144 ; JDIMM1.32 v2(88.3,6.71) ; JDIMM2.153 208.5,15.3 v2(208.26,15.06) 207.9,15.41 JDIMM2.151 ; JDIMM1.46 92.5,7.03 v2(92.19,6.71) 91.9,7 JDIMM1.44 ; JDIMM2.172 214.2,7 v2(213.98,6.78) 213.6,7.15 213.6,7.15 JDIMM2.170 ; v2(188.27,72.17) 188.02,72.17 187.63,71.79 UZ1.8 ; v2(221.55,9.9) 221.4,9.75 JDIMM2.196 ; JDIMM2.136 203.4,9.33 v2(203.07,9.66) 202.8,9.39 JDIMM2.134 ; JDIMM1.187 137.2,15.41 137.21,15.41 v2(137.65,14.97) ; JDIMM2.195 v2(221.1,15.07) ; v2(124.6,15.03) JDIMM1.145 ; JDIMM2.14 v2(164.4,6.77) ; JDIMM1.55 95.2,14.99 v2(95.24,14.95) ; v2(79.25,10.72) 78.66,10.13 78.66,9.77 79.3,9.13 JDIMM1.2 ; v2(85.25,18.77) 85.24,18.77 84.4,17.94 JDIMM1.19 ; JDIMM2.63 179.1,13.65 v2(179.65,13.1) ; JDIMM1.8 v2(81.1,9.63) ; v2(122.53,10.38) 121.9,9.75 JDIMM1.136 ; JDIMM1.156 127.9,9.29 ; v2(100.3,6.71) JDIMM1.72 ; v2(169.87,6.77) 169.8,6.83 JDIMM2.32 ; v2(121.59,15.03) 121.4,15.03 121,15.42 JDIMM1.133 ; v2(170.28,18.63) 171.3,17.6 JDIMM2.37 ; v2(98.43,10.21) 98.5,10.14 JDIMM1.66 ; v2(96.7,6.71) JDIMM1.60 ; JDIMM2.49 174.9,18.15 v2(175,18.25) ; v2(167.01,18.63) 165.9,17.52 JDIMM2.19 ; JDIMM2.8 v2(162.6,6.77) ; v2(167.01,20.15) 167.83,19.33 167.83,17.56 167.7,17.44 JDIMM2.25 ; JDIMM2.185 218.1,15.32 217.85,15.07 v2(217.02,15.07) ; v2(176.39,18.63) 176.98,18.04 176.98,17.67 176.7,17.4 JDIMM2.55 ; JDIMM1.162 v2(129.7,6.71) ; v2(139.14,18.77) 139.74,18.17 139.74,17.67 139.6,17.52 JDIMM1.195 ; v2(211.33,9.77) 211.2,9.65 JDIMM2.162 ; JDIMM1.38 v2(90.1,9.63) ; v2(82.71,18.77) 82,18.06 JDIMM1.11 ; JDIMM1.31 v2(88,14.97) ; JDIMM1.127 v2(119.2,14.9) ; JDIMM1.128 v2(119.5,9.63) ; v2(215.03,18.26) 214.5,17.73 JDIMM2.173 ; JDIMM1.168 131.5,9.35 131.62,9.46 131.62,9.77 v2(131.01,10.38) ; JDIMM1.71 100,17.3 100.32,17.63 100.32,18.21 99.76,18.77 v2(99.76,18.77) ; v2(185.8,69.7) 185.68,69.81 UZ1.11 ; v2(210.24,18.64) 210.59,18.64 210.9,18.33 JDIMM2.161 ; v2(137.78,10) 138.1,9.67 JDIMM1.190 ; v2(120.64,10.38) 121.3,9.72 JDIMM1.134 ; JDIMM1.14 82.9,9.63 v2(82.32,10.21) ; JNGFF2.65 233.36,54.85 233.54,55.03 v2(233.61,55.03) ; v2(178.2,6.77) JDIMM2.60 ; JDIMM1.61 97,14.92 v2(97.02,14.9) 97.41,14.9 97.6,15.1 JDIMM1.63 ; JDIMM1.172 132.7,9.45 v2(132.44,9.71) 132.1,9.37 JDIMM1.170 ; v2(86.64,10.59) 87.23,10 87.23,9.52 87.1,9.4 JDIMM1.28 ; v2(81.9,14.71) 81.4,15.21 JDIMM1.9 ; JDIMM2.139 204.3,18.03 v2(204.54,18.26) ; UZ1.4 190.23,69.71 v2(190.24,69.7) ; JDIMM2.179 216.3,14.97 216.8,14.48 v2(216.99,14.48) ; v2(128.44,18.77) 129.4,17.81 JDIMM1.161 ; JDIMM1.13 v2(82.6,14.71) ; JDIMM1.150 v2(126.1,9.59) ; JDIMM2.44 v2(173.4,6.77) ; v2(97.24,18.77) 97.35,18.77 98.2,17.92 JDIMM1.65 ; 220.45,10.31 v2(220.52,10.38) ; JDIMM2.145 206.1,15.32 205.75,14.97 v2(205.36,14.97) ; JDIMM2.31 169.5,17.45 169.3,17.65 169.3,17.95 v2(169.01,18.25) ; JDIMM2.65 179.7,17.88 v2(178.96,18.63) ; v2(178.38,12.72) 178.5,12.85 JDIMM2.61 ; JDIMM2.144 v2(205.8,9.61) ; JDIMM2.127 200.7,15.23 201.01,14.92 v2(201.29,14.92) 201.92,14.92 202.5,15.5 JDIMM2.133 ; JDIMM2.20 v2(166.2,6.77) ; JDIMM2.71 181.5,17.12 182,17.62 182,18.09 v2(181.47,18.63) ; JDIMM2.128 201,9.74 v2(201.64,10.38) ; v2(122.8,15.07) JDIMM1.139 ; JDIMM2.178 v2(216,9.63) ; v2(92.57,10.59) 93.24,9.92 93.24,9.61 93.1,9.47 JDIMM1.48 ; JDIMM2.155 209.1,17.66 v2(208.12,18.64) ; UZ1.18 v2(185.68,77.95) ; JDIMM2.187 218.7,15.46 v2(219,15.16) 219.3,15.46 JDIMM2.189 ; JDIMM1.189 137.8,18.19 v2(137.22,18.77) ; v2(212.54,10.38) 213.09,9.82 213.09,9.39 213,9.29 JDIMM2.168 ; JDIMM2.46 174,9.49 174.1,9.59 174.1,10.66 v2(173.57,11.2) ; JDIMM2.9 162.9,18.58 v2(164.47,20.15) ; JDIMM2.72 v2(181.8,6.77) ; JDIMM1.153 127,15.37 v2(126.56,14.93) 126.4,15.09 JDIMM1.151 ; JDIMM1.155 v2(127.6,14.97) ; JDIMM1.3 v2(79.6,14.65) ; JDIMM1.54 v2(94.9,6.71)
  BOTTOM w0.381: v2(202.61,83.57) 202.56,83.57 201.96,84.17 RV508.1 ; v2(174.74,63.31) 174.83,63.22 RC171.2 ; UV12.7 195.65,81.37 195.54,81.48 v2(195.54,82.34) ; v2(204.64,80.76) 204.23,80.76 203.71,81.27 CV95.2 ; v2(203.09,86.68) 203.09,87.56 203.44,87.91 UV11.7 ; RC187.2 RC178.2 164.21,45.58 v2(164.35,45.44) ; v2(170.16,80.24) 170.16,80.43 170.76,81.02 RC141.1 ; CC83.2 RC123.2 133.08,78.98 v2(133.28,78.78) ; UV502.7 282.45,66.76 v2(282.58,66.89) ; v2(68.56,37.19) 68.74,37.01 PQ806.4 ; 127.9,9.29 v2(127.2,10) ; PQ813.1 52.25,29.88 52.07,29.69 v2(52.07,29.31) ; PQ806.1 70.04,33.69 70.34,33.38 v2(71.23,33.38)
  BOTTOM w0.406: QV21.1 198.51,65.33 v2(198.26,65.58) ; DI4.3 286.48,59.53 v2(286.5,59.54) ; QN1.4 v2(275.88,12.74) ; QV21.4 197.44,64.03 197.63,63.84 v2(197.63,63.83) ; JMDP1.8 289.56,75.45 v2(289.49,75.39) ; JMDP1.14 v2(289.49,73.65) ; DI6.3 v2(239.39,93.45)
  BOTTOM w0.432: QN1.1 v2(277.18,10.92)
  BOTTOM w0.457: CV121.2 202.81,86.97 v2(203.09,86.68) ; PQ813.4 54.58,31.18 v2(53.97,31.79) ; v2(252.19,46.89) 251.63,46.89 RE277.1 ; v2(209.19,74.91) 209.73,74.91 CV96.2
  BOTTOM w0.508: v2(34.8,26.96) 34.67,27.09 RA37.2 ; JSD1.24 278.57,45.55 v2(279.4,44.72) ; JSD1.6 274.22,26.97 v2(274.27,26.92) ; v2(194.08,65.51) 194.41,65.84 194.41,67.65 194.42,67.65 UC2.4 ; v2(187.83,57.06) 188.22,56.67 CC9.1 ; v2(228.61,82.27) 229.39,81.49 JSIM1.9 ; v2(234.57,87.67) 233.93,87.67 CZ66.2 233.87,87.6 CZ65.2 ; v2(257.16,42.46) 257.85,43.15 CE31.2 258.25,43.15 v2(258.94,42.46) ; CV83.2 CV91.2 205.01,81.97 204.64,81.6 v2(204.64,81.46) ; JSPI1.21 178.38,82.26 v2(178.81,81.83) 178.38,81.4 JSPI1.22 ; v2(152.87,40.38) 153.13,40.12 CC5.2 ; v2(73.21,8.99) 73.21,7.59 72.78,7.16 PR209.2 ; JSD1.20 272.21,19.67 v2(272.41,19.47) ; RC185.2 RC21.2 128.82,58.4 v2(129.1,58.68) ; CV84.2 208.54,76.8 v2(208.54,76.21) ; DA6.1 3.81,7.02 3.43,6.64 v2(3.05,6.64) ; v2(219.43,80.64) 218.99,81.09 JSIM1.11 ; PR403.2 107.35,71.29 PU400.1 109.53,71.29 109.67,71.16 v2(110.23,71.16) ; JEDP1.44 116.52,86.4 v2(116.08,86.84) ; JSD1.22 272.03,43.22 v2(272.4,42.85) ; CV89.2 CV97.2 203.88,71.21 v2(203.77,71.09) ; v2(233.42,35.98) 234.12,35.28 JNGFF1.68 ; CI38.2 240.76,85.01 241.11,85.35 v2(241.11,85.62) ; CE14.2 249.74,43.92 v2(249.73,43.92) ; JSD1.17 v2(294.7,17.98) ; v2(228.18,75.18) 228.38,75.39 CV66.2 CV61.2 ; JSATA1.21 v2(269.49,5.57) ; CA6.2 v2(101.58,83.46) ; v2(289.26,45.35) 289.46,45.55 JSD1.26 ; CN2.2 279.13,10.31 v2(279.13,11.05) ; CL3.2 257.72,83.5 v2(257.35,83.87) ; v2(21.04,16.05) 20.65,16.43 RA2.2 ; v2(185.8,69.7) 185.4,69.3 CZ5.2 ; CV82.2 207.55,82.4 207.98,81.97 CV98.2 v2(208.39,83.29) ; CI417.2 186.98,99.75 v2(186.99,99.75) ; PC741.1 v2(84.07,78.52) ; JSPI1.18 187.88,81.26 187.77,81.38 v2(187.77,81.89) 187.77,82.27 188.38,82.89 JSPI1.19 ; PC503.1 97.44,55.73 v2(96.71,55.73) ; CV116.2 CV117.2 v2(221.32,77.32) ; JNGFF2.69 233.12,52.5 v2(232.85,52.23) ; JSD1.10 v2(294.7,44.6) ; v2(229.77,89.42) 230.15,89.8 JSIM1.7 ; JFAN1.5 v2(60.13,89.71) ; C42.2 153.73,95.51 v2(153.49,95.74) ; CC50.2 CC3.1 v2(172.72,44.68) ; JEDP1.41 96.56,88.35 96.56,87.03 v2(97.28,86.31) ; 200.83,70.71 201.86,70.71 v2(202.18,71.04) ; R268.2 C310.2 v2(142.48,92.06) ; RL3.1 v2(254.57,86.92) ; v2(107.02,86.72) 107.34,86.4 JEDP1.43 ; CV93.2 203.54,76.86 v2(203.99,76.86) ; v2(104.63,62.4) PC500.1 ; UC3.4 190.61,52.14 191.25,52.78 v2(191.25,53.13) ; RC129.1 86.79,60.22 v2(87,60.43) 87.32,60.75 CC17.2 ; PC206.2 60.79,21.93 v2(60.49,21.63) ; JSPI1.24 189.88,81.61 189.42,82.08 ; v2(273.61,33.44) 272.97,34.07 JSD1.3 ; CV23.2 230.15,99.96 v2(229.74,100.37) ; PC300.2 v2(200.09,63.8) ; CL10.2 254.38,84.45 v2(254.68,84.75) ; CV87.2 208.64,70.66 v2(208.71,70.72) ; v2(126.86,64.43) RC189.2 RC190.2 ; C43.2 154.9,95.19 v2(155.45,95.74) ; CC56.2 v2(164.78,77.63) ; RC240.2 146.24,80.05 146.05,79.86 v2(145.35,79.86) ; v2(73.07,100.41) 73.34,100.14 PR12.1 ; CV90.2 210.88,72.36 v2(211.39,72.36) ; 98.04,85.91 98.53,86.4 JEDP1.42 ; v2(234.49,85.61) CV69.2 ; PC310.2 206.2,63.93 v2(206.44,64.16) ; PR310.2 207.77,61.77 v2(208.33,61.21) ; v2(193.99,75.35) 193.93,75.29 CV114.2 ; v2(217.34,53) 217.53,52.81 PC118.2 ; CL18.2 v2(260.86,94.14) ; v2(6.92,6.64) 7.36,6.64 7.81,7.09 DA7.1 ; CV374.2 200.75,66.09 v2(201.85,67.2) ; CL11.2 256.03,83.5 v2(256.4,83.87) ; v2(72.56,9.82) PC214.2 PC212.2 ; CN1.2 v2(279.58,11.56) ; JSD1.23 279.39,17.35 v2(279.66,17.61) ; v2(56.69,34.18) 57.01,34.49 PQ816.3 ; CA5.2 v2(104.28,83.46) ; DI3.1 v2(243.38,93.71) ; UV2.2 227.07,96.74 v2(227.71,97.38) ; PR401.2 116.53,71.25 PC402.2 v2(116.53,70.46) ; C263.2 CZ67.2 234.48,89.22 v2(234.54,89.28) ; CC4.1 186.81,47.1 v2(186.8,47.12) ; PC309.2 208.45,62.47 v2(208.77,62.47) ; CC8.1 153.96,79.73 v2(153.59,79.36) ; RV62.2 RV64.2 224.7,78.69 224.2,79.19 v2(223.48,79.19) ; DV4.1 v2(97.57,94.54) ; CC6.2 v2(188.91,62.97) ; RC183.2 RC184.2 RC188.2 127.17,62.66 v2(126.6,63.23) ; v2(185.8,41.4) 185.8,41.78 CMOS1.1 ; v2(28.75,8.24) 29.18,8.67 29.18,8.85 v3(29.4,9.07) 29.4,9.74 28.52,10.62 28.52,11.99 RA36.2 ; v2(105.71,61.45) PC501.2 ; CC10.1 196.99,57.94 v2(197.42,57.51) 196.86,56.95 CC7.2 ; RE78.2 258.25,41.38 v2(258.94,40.69) ; JSIM1.12 218.39,93.29 v2(218.33,93.23) ; JSD1.25 v2(292.4,15.75) ; CA49.1 31.89,13.94 33.21,15.26 33.21,15.87 v2(33.26,15.92) ; v2(231.66,83.6) RV66.2 ; v2(85.01,81.97) PC737.2 PR745.2 ; v2(286.83,66.89) CV514.2 ; DI5.1 v2(286.37,55.86) ; v2(183.13,47.03) 182.76,47.4 CC1.1 CC2.1 ; CV100.2 211.66,73.67 v2(211.38,73.39) ; v2(230.4,95.29) 230.13,95.02 JSIM1.10 ; CC11.1 157.29,81.19 157.86,81.76 v2(157.86,82.14) ; v2(33.26,19.22) 33.5,19.22 33.73,19.45 RA35.2 ; JSD1.13 v2(298,44.64) ; JFAN1.6 v2(66.38,83.48) ; v2(226.34,95.29) 226.34,95.54 225.94,95.94 CV27.2 225.63,95.95 CV26.2 ; CV85.2 204.64,76.91 v2(204.64,77.51) ; v2(126.49,68.55) 125.99,68.55 CC20.2 ; 189.42,82.08 188.59,82.08 v2(188.4,81.89) 188.88,81.41 JSPI1.20 ; 189.42,82.08 189.88,82.55 JSPI1.23 ; JFAN1.1 v2(61.11,86.78) ; PC311.2 v2(199.65,62.83) ; CV88.2 207.26,75.54 v2(207.24,75.56) ; v2(220.27,53.26) 219.82,52.81 PC117.2 ; CV118.2 210.82,82.39 v2(211.27,81.94) ; JSD1.21 270.79,31.22 v2(269.8,30.23) ; CV86.2 v2(207.25,71.23) ; v2(231.81,82.09) 232.14,81.76 RV63.2 ; RC218.2 v2(127.19,75.16) ; v2(260.71,44.24) 260.59,44.37 CE11.2 ; RC142.1 v2(167.13,81.57) ; JNGFF1.69 v2(235.96,14.25) ; PC709.2 v2(77.05,89.48) ; RV65.2 229.28,77.77 v2(229.59,77.47) ; PC509.1 v2(106.22,56.94) ; v2(117.14,74.02) PC400.2
  vias: v2(0.52,10.69) v2(1.67,9.79) v2(1.94,12.57) v2(4.2,5.61) v2(5.24,6.45) v2(6.82,5.65) v2(9.28,5.61) v2(9.94,11.58) v2(10.72,13.19) v2(12.84,6.32) v2(14.36,5.61) v2(14.39,16.15) v2(15.22,17.7) v2(15.22,17.11) v2(16.42,15.38) v2(16.86,6.29) v2(17.41,13.6) v2(17.42,13) v2(17.5,9.28) v2(17.94,7.61) v2(19.44,5.61) v2(24.52,5.61) v2(25.71,10.83) v2(25.78,7.85) v2(29.08,5.63) v2(31.35,8.43) v2(31.61,19.22) v2(31.8,17.57) v2(31.8,15.92) v2(33.26,17.57) v2(33.56,8.8) v2(33.72,5.63) v2(33.94,8.29) v2(34.17,8.85) v2(34.27,28.24) v2(34.91,19.22) v2(34.91,17.57) v2(34.91,15.92) v2(37.34,10.9) v2(37.97,10.9) v2(38.67,5.61) v2(39.81,28.47) v2(43.75,5.61) v2(45.25,29.63) v2(47.72,12.65) v2(48.37,12.71) v2(48.83,5.61) v2(49.49,100.72) v2(49.49,95.64) v2(49.49,90.56) v2(50.4,31.72) v2(52.37,89.23) v2(53.08,105.27) v2(53.91,5.61) v2(54.09,108.99) v2(54.62,105.85) v2(55.08,34.67) v2(55.56,107.55) v2(55.56,104.15) v2(55.84,87.97) v2(57.74,107.55) v2(57.74,104.15) v2(58.68,105.85) v2(58.99,5.61) v2(59.17,108.99) v2(59.14,85.34) v2(59.17,38.4) v2(60.26,101.99) v2(60.26,101.4) v2(60.88,107.35) v2(61.45,83.04) v2(62.54,42.77) v2(63.59,108.42) v2(63.85,89) v2(64.07,5.61) v2(64.25,108.99) v2(64.45,89.62) v2(64.45,89.03) v2(64.77,78.83) v2(64.97,11.12) v2(65.12,47.73) v2(65.17,108.29) v2(65.28,11.63) v2(65.96,69.49) v2(66.62,74.51) v2(66.79,53.06) v2(67.1,11.09) v2(67.1,10.08) v2(67.21,64.08) v2(67.49,58.55) v2(68.12,10.08) v2(68.26,60.88) v2(68.62,62.84) v2(69.05,59.54) v2(69.15,5.61) v2(69.33,108.99) v2(71.08,59.64) v2(71.31,62.94) v2(71.55,12.43) v2(71.55,11.79) v2(71.97,61.09) v2(73.34,80.56) v2(73.92,80.54) v2(74.23,42.07) v2(74.23,5.61) v2(74.41,108.99) v2(74.85,74.64) v2(74.84,73.96) v2(74.93,75.32) v2(75.56,75.32) v2(75.49,74.64) v2(75.47,73.96) v2(75.87,78.79) v2(76.35,79.82) v2(76.45,78.78) v2(76.48,75.27) v2(76.48,74.62) v2(76.49,73.94) v2(76.93,79.83) v2(76.93,72.31) v2(76.93,71.55) v2(77.01,73) v2(77.12,75.23) v2(77.15,74.55) v2(77.12,73.91) v2(77.25,108.08) v2(77.25,101.9) v2(77.56,36) v2(77.83,33.45) v2(79.12,20.3) v2(79.12,18.77) v2(79.25,12.24) v2(79.31,5.61) v2(79.74,44.37) v2(80.12,35.99) v2(80.12,33.45) v2(80.25,94.64) v2(81.4,93.41) v2(81.52,65.96) v2(82.15,65.96) v2(82.32,12.5) v2(82.57,89.78) v2(82.57,89.19) v2(82.71,20.3) v2(83.18,89.78) v2(83.18,89.19) v2(83.23,65.96) v2(83.87,65.96) v2(84.1,12.11) v2(84.39,5.61) v2(84.95,65.96) v2(85.25,20.3) v2(85.58,65.96) v2(86.64,12.11) v2(87.25,20.68) v2(87.25,18.39) v2(87.82,44.61) v2(88.3,12.11) v2(88.3,10.59) v2(88.39,44.36) v2(88.52,20.3) v2(88.52,18.77) v2(88.69,85.52) v2(88.88,63.04) v2(89.47,85.89) v2(89.47,5.61) v2(89.78,57.83) v2(89.91,88.9) v2(89.96,63.04) v2(90.6,63.04) v2(90.88,90.75) v2(90.88,87.05) v2(91.06,20.3) v2(91.06,18.77) v2(91.41,84.87) v2(92.01,84.87) v2(92.16,101.98) v2(92.57,12.11) v2(93.39,20.68) v2(93.39,18.39) v2(93.52,90.75) v2(93.52,87.05) v2(94.39,12.11) v2(94.39,10.59) v2(94.49,88.9) v2(94.55,5.61) v2(94.7,20.3) v2(94.7,18.77) v2(95.23,108.99) v2(96.93,10.59) v2(97.24,20.3) v2(98.43,12.5) v2(99.63,5.61) v2(99.7,12.11) v2(99.7,10.59) v2(100.31,108.99) v2(100.31,103.91) v2(100.59,98.83) v2(101.2,57.51) v2(101.2,56.75) v2(101.2,55.99) v2(101.2,55.23) v2(101.2,54.46) v2(101.96,57.51) v2(101.96,56.75) v2(101.96,55.99) v2(101.96,55.23) v2(101.96,54.46) v2(102.4,21.06) v2(102.4,19.53) v2(102.4,18.01) v2(102.73,57.51) v2(102.73,55.99) v2(102.73,55.23) v2(102.73,54.46) v2(103.03,95.12) v2(103.74,66.47) v2(103.83,12.66) v2(103.83,11.14) v2(104.55,67.03) v2(104.71,5.61) v2(105.33,21.06) v2(105.33,19.53) v2(105.78,12.66) v2(105.78,11.14) v2(107.56,11.9) v2(107.56,10.38) v2(107.71,93.45) v2(108.72,21.06) v2(108.72,19.53) v2(109.79,5.61) v2(110.25,21.06) v2(110.25,19.53) v2(110.25,18.01) v2(110.42,75.86) v2(110.86,12.66) v2(110.86,11.14) v2(111.06,75.86) v2(111.77,21.44) v2(111.77,19.15) v2(111.81,11.9) v2(112.01,75.86) v2(112.41,95.12) v2(112.76,20.3) v2(112.9,13.04) v2(112.9,10.76) v2(114.62,21.06) v2(114.62,19.53) v2(114.6,12.66) v2(114.6,11.14) v2(114.84,98.83) v2(114.87,5.61) v2(115.12,107.49) v2(115.12,103.91) v2(115.95,80.17) v2(116.67,105.85) v2(116.57,21.06) v2(116.57,19.53) v2(117.06,14.19) v2(117.06,12.66) v2(117.06,11.14) v2(117.61,107.49) v2(117.61,104.15) v2(117.73,80.1) v2(117.89,65.55) v2(117.88,62.8) v2(117.89,62.22) v2(118.02,21.06) v2(118.02,19.53) v2(119.53,80.35) v2(119.64,59.8) v2(119.64,59.21) v2(119.71,69.48) v2(119.71,68.88) v2(119.79,107.49) v2(119.79,104.15) v2(119.95,5.61) v2(120,65.55) v2(120.01,62.81) v2(120.01,62.22) v2(120.3,20.3) v2(120.3,18.77) v2(120.64,11.9) v2(120.73,105.85) v2(120.67,65.55) v2(120.69,62.81) v2(120.69,62.22) v2(121.83,88.61) v2(121.79,59.87) v2(121.79,59.27) v2(121.88,69.47) v2(121.88,68.87) v2(122.08,20.68) v2(122.08,18.39) v2(122.51,69.47) v2(122.51,68.87) v2(122.49,59.87) v2(122.49,59.27) v2(122.53,11.9) v2(122.81,65.55) v2(122.82,62.81) v2(122.82,62.22) v2(123,91.29) v2(123.5,65.55) v2(123.52,62.81) v2(123.52,62.22) v2(123.58,91.29) v2(124.17,91.29) v2(124.11,20.3) v2(124.11,18.77) v2(124.75,91.29) v2(124.88,107.49) v2(125.03,5.61) v2(125.07,11.9) v2(126.3,66.14) v2(126.65,20.3) v2(126.65,18.77) v2(127.21,108.99) v2(127.2,12.28) v2(128.44,20.3) v2(128.47,11.9) v2(128.47,10.38) v2(128.59,54.75) v2(128.83,52.73) v2(129.52,56.16) v2(130.05,53.85) v2(130.11,5.61) v2(130.48,52.09) v2(131,66.97) v2(130.98,20.3) v2(130.98,18.77) v2(131.01,11.9) v2(131.96,108.99) v2(131.87,47.54) v2(132.65,20.68) v2(132.65,18.39) v2(133.02,48.93) v2(133.45,11.9) v2(133.45,10.38) v2(133.64,82) v2(133.66,44.37) v2(133.68,47.04) v2(134.58,83.7) v2(134.58,80.3) v2(134.68,20.3) v2(134.68,18.77) v2(134.84,11.89) v2(134.93,48.48) v2(135.04,45.75) v2(135.24,76.13) v2(135.19,5.61) v2(136.09,11.9) v2(136.09,10.38) v2(136.42,47.13) v2(136.54,72.03) v2(136.76,83.7) v2(136.76,80.3) v2(136.88,76.28) v2(137.04,108.99) v2(137.22,20.3) v2(137.67,74.8) v2(137.7,82) v2(137.79,48.51) v2(137.78,12.28) v2(138.48,77.16) v2(139.03,72.04) v2(139.05,11.9) v2(139.14,20.3) v2(139.76,82.94) v2(139.71,45) v2(139.8,83.54) v2(140.17,45.45) v2(140.27,5.61) v2(141.92,72.02) v2(142.12,108.99) v2(142.38,75.67) v2(142.52,49.22) v2(143.62,75.61) v2(143.57,19.91) v2(144.21,20.55) v2(144.21,19.91) v2(144.41,72.04) v2(144.65,16.93) v2(144.59,15.4) v2(144.59,14.77) v2(144.97,44.45) v2(144.89,43.84) v2(145.21,74.78) v2(145.35,5.61) v2(145.61,50.05) v2(145.86,16.93) v2(145.92,13.18) v2(146.22,75.61) v2(146.43,8.86) v2(146.93,72.02) v2(147.2,108.99) v2(147.43,75.67) v2(149.44,72.02) v2(149.41,11.79) v2(149.55,75.62) v2(149.67,15.65) v2(150.37,82.21) v2(150.42,44.81) v2(150.42,44.18) v2(150.42,43.54) v2(150.43,5.61) v2(150.61,17.35) v2(150.61,13.95) v2(151,82.21) v2(151.29,75.36) v2(151.57,72.05) v2(152.21,100.81) v2(152.28,108.99) v2(152.46,48.48) v2(152.47,46.74) v2(152.79,17.35) v2(152.79,13.95) v2(153.15,74.66) v2(153.73,15.65) v2(154.09,46.93) v2(154.09,44.37) v2(154.09,43.07) v2(154.43,99.92) v2(154.45,72.02) v2(154.49,11.72) v2(155.51,5.61) v2(156.05,47.62) v2(156.05,45.67) v2(156.76,106.35) v2(156.96,72.02) v2(157.16,13.82) v2(157.16,13.18) v2(157.36,108.99) v2(158.06,45.73) v2(158.08,47.62) v2(158.23,74.07) v2(159.68,47.54) v2(159.71,45.72) v2(160.02,77.39) v2(160.37,93.33) v2(160.59,5.61) v2(160.78,85.25) v2(160.78,84.62) v2(161.35,78.08) v2(161.7,12.72) v2(161.7,11.2) v2(161.78,47.14) v2(161.91,93.34) v2(162.28,20.15) v2(162.28,18.63) v2(162.44,108.99) v2(163.13,64.36) v2(163.31,92.44) v2(163.38,77.63) v2(164.05,13.1) v2(164.05,10.82) v2(164.15,56.07) v2(164.78,78.84) v2(165.58,56.37) v2(165.67,5.61) v2(165.68,12.72) v2(165.68,11.2) v2(167.52,108.99) v2(168.22,12.72) v2(168.22,11.2) v2(168.22,9.67) v2(169.01,20.53) v2(170.28,20.15) v2(170.75,5.61) v2(171.01,12.72) v2(171.01,11.2) v2(172.51,60.18) v2(172.6,108.99) v2(172.58,61.01) v2(172.82,20.15) v2(173.57,12.72) v2(175,20.53) v2(175.59,81.11) v2(175.83,5.61) v2(176.17,81.12) v2(176.39,20.15) v2(177.58,86.03) v2(177.68,108.99) v2(178.38,11.2) v2(178.96,20.15) v2(179.65,10.82) v2(180.45,107.49) v2(180.82,41.4) v2(180.91,5.61) v2(181.15,12.72) v2(181.15,11.2) v2(181.38,81.83) v2(181.4,41.4) v2(181.47,20.15) v2(181.91,98.15) v2(181.91,97.14) v2(181.99,41.4) v2(182.18,78.71) v2(182.67,105.85) v2(182.6,41.4) v2(183.18,97.64) v2(183.51,81.83) v2(183.61,107.49) v2(183.61,104.15) v2(184.45,98.15) v2(184.45,97.14) v2(184.57,13.48) v2(184.57,11.95) v2(185.19,41.4) v2(185.79,107.49) v2(185.79,104.15) v2(185.99,5.61) v2(186.3,13.48) v2(186.3,11.95) v2(186.73,105.85) v2(188.3,103.91) v2(188.43,13.48) v2(188.43,11.95) v2(188.58,98.83) v2(188.75,20.93) v2(188.75,19.41) v2(189.49,78.47) v2(190.21,13.48) v2(190.21,11.95) v2(191.02,95.12) v2(191.07,5.61) v2(191.26,49.31) v2(191.26,48.72) v2(191.36,20.93) v2(191.36,19.41) v2(191.91,48.66) v2(192.45,13.48) v2(192.45,11.95) v2(192.58,64.25) v2(192.7,20.17) v2(193.21,21.31) v2(193.21,19.03) v2(193.31,11.19) v2(194.28,12.34) v2(194.43,49.44) v2(195.55,13.48) v2(195.55,11.95) v2(195.69,93.45) v2(195.72,20.93) v2(195.72,19.41) v2(196.15,5.61) v2(197.11,13.48) v2(197.29,20.93) v2(197.29,19.41) v2(198.1,6.71) v2(199.31,20.93) v2(199.31,19.41) v2(199.45,60.79) v2(199.48,75.59) v2(200.06,60.81) v2(200.26,52.75) v2(200.26,52.12) v2(200.26,51.35) v2(200.26,50.72) v2(200.39,95.12) v2(200.5,77.49) v2(200.72,80.14) v2(201,78.59) v2(201.22,75.8) v2(201.23,5.61) v2(201.32,60.82) v2(201.8,20.17) v2(201.8,18.64) v2(201.94,60.86) v2(202.83,98.83) v2(203.11,108.99) v2(203.11,103.91) v2(204.14,11.9) v2(204.14,10.38) v2(204.38,67.72) v2(204.54,20.55) v2(205.15,52.75) v2(205.15,52.12) v2(205.15,51.04) v2(205.15,50.4) v2(205.87,20.17) v2(205.87,18.64) v2(206.16,67.74) v2(206.31,5.61) v2(206.68,11.9) v2(206.68,10.38) v2(206.94,108.03) v2(206.94,102.23) v2(207.67,39.95) v2(207.71,86.08) v2(207.89,79.46) v2(207.93,67.72) v2(207.95,12.28) v2(208.12,20.17) v2(208.19,92.34) v2(209.71,67.74) v2(210,11.9) v2(210.24,20.17) v2(210.35,92.35) v2(211.39,5.61) v2(212.23,78.13) v2(212.43,92.35) v2(212.54,11.9) v2(212.68,20.17) v2(212.68,18.64) v2(212.81,78.71) v2(212.81,77.53) v2(214.32,11.9) v2(214.32,10.38) v2(214.42,92.42) v2(215.03,20.55) v2(216.36,20.17) v2(216.36,18.64) v2(216.39,41.89) v2(216.47,5.61) v2(216.86,11.9) v2(216.86,10.38) v2(217.15,41.89) v2(217.85,49.96) v2(217.85,49.09) v2(217.92,41.89) v2(217.98,76.18) v2(217.98,75.55) v2(217.98,74.91) v2(218.28,49.51) v2(218.72,49.96) v2(218.72,49.09) v2(218.86,20.17) v2(218.86,18.64) v2(219.25,12.28) v2(219.25,10) v2(220.27,35.41) v2(220.52,11.9) v2(221.03,20.17) v2(221.55,10.77) v2(221.55,5.61) v2(222.11,67.69) v2(222.6,89.37) v2(223.45,108.05) v2(223.45,102.46) v2(224.09,70.46) v2(224.39,89.45) v2(225.09,62.85) v2(225.33,102.17) v2(225.36,71.73) v2(225.36,70.46) v2(225.44,82.32) v2(225.47,83.48) v2(225.6,81.01) v2(225.64,67.16) v2(226.06,15.15) v2(226.17,89.45) v2(226.25,14.58) v2(226.35,105) v2(226.53,107.19) v2(226.55,9.13) v2(226.63,83.45) v2(226.62,82.28) v2(226.63,71.73) v2(226.63,70.46) v2(226.63,5.61) v2(226.69,80.94) v2(226.69,59.73) v2(226.74,35.35) v2(226.87,37.26) v2(226.98,108.99) v2(227.14,103.3) v2(227.33,59.73) v2(227.82,83.48) v2(227.8,82.3) v2(227.82,80.88) v2(227.95,89.45) v2(227.9,71.73) v2(227.9,70.46) v2(228.17,105.85) v2(228.42,62.28) v2(228.8,102.04) v2(229.11,107.55) v2(229.11,104.15) v2(229.17,71.73) v2(229.17,70.46) v2(231.29,107.55) v2(231.29,104.15) v2(231.49,43.31) v2(231.71,5.61) v2(231.82,43.79) v2(231.87,102.09) v2(232.06,108.99) v2(232.23,105.85) v2(232.19,43.33) v2(233.23,74.97) v2(233.28,99.59) v2(233.58,107.09) v2(233.61,31.22) v2(233.72,102.87) v2(233.87,74.97) v2(234.31,8.1) v2(235.14,6.26) v2(235.34,108.08) v2(235.34,101.88) v2(235.52,10.2) v2(237.17,26.82) v2(238.25,39.53) v2(238.19,10.13) v2(238.32,43.65) v2(238.63,83.26) v2(238.63,6.39) v2(239.27,51.16) v2(239.26,45.35) v2(239.26,41.95) v2(239.33,8.23) v2(239.65,33.31) v2(239.65,32.71) v2(239.71,51.6) v2(241.04,74.4) v2(241.04,73.76) v2(241.44,45.35) v2(241.44,41.95) v2(241.73,58.78) v2(241.73,57.26) v2(241.87,5.61) v2(242.38,43.65) v2(245.3,92.05) v2(245.3,91.41) v2(245.55,6.96) v2(246.06,89.76) v2(246.95,5.61) v2(247.76,30.84) v2(247.76,30.08) v2(247.76,29.32) v2(248.45,10.76) v2(249.31,11.2) v2(249.3,10.34) v2(250.25,108.08) v2(250.26,101.88) v2(250.28,11) v2(251.05,17.5) v2(251.39,81.95) v2(252.03,5.61) v2(252.09,105.7) v2(252.32,103.24) v2(252.51,100.99) v2(252.5,98.17) v2(252.84,108.99) v2(252.85,81.95) v2(253.35,67.04) v2(253.35,65.51) v2(253.35,63.99) v2(254.16,104.32) v2(254.37,97.12) v2(254.29,95.5) v2(254.44,99.63) v2(254.54,94.39) v2(254.52,2.67) v2(254.72,102.3) v2(254.87,95.5) v2(254.87,67.04) v2(254.87,65.51) v2(254.87,63.99) v2(255.15,94.39) v2(255.86,86.55) v2(255.85,85.83) v2(255.86,85.03) v2(256.4,67.04) v2(256.4,65.51) v2(256.4,63.99) v2(256.64,86.47) v2(256.63,85.79) v2(256.64,85) v2(257.16,44.24) v2(257.16,40.69) v2(257.19,0.51) v2(257.33,86.49) v2(257.45,101.82) v2(257.38,85.83) v2(257.39,85.03) v2(258.94,44.24) v2(259.05,2.9) v2(260.54,104.32) v2(260.71,42.46) v2(260.71,40.69) v2(260.91,102.17) v2(261.54,27.73) v2(262.15,100.34) v2(262.27,0.51) v2(262.75,108.37) v2(263.38,27.73) v2(263.41,18.38) v2(263.41,17.11) v2(263.83,2.69) v2(264.46,11.91) v2(264.58,24.6) v2(264.68,18.38) v2(264.68,17.11) v2(265.05,11.91) v2(265.55,26.45) v2(265.55,22.75) v2(267.35,0.51) v2(268.11,77.88) v2(268.19,26.45) v2(268.19,22.75) v2(269.03,23.79) v2(269.68,16.8) v2(269.92,75.48) v2(270.01,20.97) v2(271.19,11.79) v2(271.45,12.36) v2(271.64,2.69) v2(272.03,78.66) v2(272.46,75.23) v2(272.43,0.51) v2(274.74,78.59) v2(275,75.74) v2(275,74.72) v2(275.38,28.84) v2(275.58,63.56) v2(276.02,30.91) v2(276.55,65.41) v2(276.55,61.71) v2(277.14,77.92) v2(277.51,0.51) v2(277.71,28.37) v2(277.71,27.75) v2(278.14,27.32) v2(279.19,65.41) v2(279.19,61.71) v2(280.16,63.56) v2(281.67,49.65) v2(282.56,44.43) v2(282.56,43.8) v2(282.61,51.35) v2(282.61,47.95) v2(282.59,0.51) v2(283.17,44.43) v2(283.17,43.8) v2(283.45,32.18) v2(283.45,30.91) v2(283.45,29.64) v2(284.72,32.18) v2(284.72,30.91) v2(284.72,29.64) v2(284.79,51.35) v2(284.79,47.95) v2(285.73,49.65) v2(285.81,90.08) v2(285.81,89.38) v2(285.99,32.18) v2(285.99,30.91) v2(285.99,29.64) v2(287,42.46) v2(287,41.45) v2(287.67,93.62) v2(287.67,0.51) v2(287.96,91.41) v2(288.05,75.64) v2(288.02,42.46) v2(288.02,41.45) v2(288.03,38.9) v2(288.3,88.8) v2(289.27,90.65) v2(290.21,92.35) v2(290.21,88.95) v2(290.62,87.3) v2(290.75,62.03) v2(290.75,50.32) v2(291.75,65) v2(292.39,92.35) v2(292.39,88.95) v2(292.75,93.62) v2(292.75,0.51) v2(293.33,90.65) v2(294.07,47.79) v2(294.19,22.11) v2(294.47,64.52) v2(294.66,89) v2(294.73,92.28) v2(294.93,78.92) v2(294.93,70.21) v2(296.56,90.42) v2(297.67,11.15) v2(297.83,93.62) v2(297.83,0.51) v2(298.27,92.24) v2(298.61,12.85) v2(298.61,9.45) v2(298.82,69.6) v2(299.1,79.5) v2(299.32,89.06) v2(300.79,12.85) v2(300.79,9.45) v2(301.1,69.14) v2(301.13,65.96) v2(301.15,63.47) v2(301.13,48.84) v2(301.36,87.46) v2(301.33,82.1) v2(301.39,84.82) v2(301.73,11.15) v2(302.77,93.51) v2(302.74,0.65) v2(302.91,88.92) v2(302.91,84.23) v2(302.91,79.5) v2(302.91,45.92) v2(302.91,15.75) v2(302.91,10.67) v2(302.91,5.59) v2(304.24,41.15) v2(304.24,36.07) v2(304.24,30.99) v2(304.24,25.91) v2(304.24,20.83) v3(33.86,10.07) v3(62.11,19.9) v3(62.09,19.84) v3(67.22,9.17) v3(82.8,65.25) v3(89.62,16.33) v3(100.49,57.17) v3(102.5,48.53) v3(106.4,67.75) v3(139.23,84.45) v3(150.96,81.3) v3(160.59,82.8) v3(164.17,76.94) v3(196.35,49.2) v3(199.03,59.77) v3(200.28,61.65) v3(208.16,23.04) v3(223.35,71.09) v3(227.14,13.92) v3(239.61,50.67) v3(248.7,11.34) v4(47.64,14.01) v4(47.65,13.3) v4(48.3,14.91) v4(48.3,14.21) v4(48.33,13.42) v4(49,14.91) v4(49,14.21) v4(49.04,13.45) v4(49.76,13.47) v4(49.88,12.76) v4(50.65,97.73) v4(50.65,97.03) v4(50.65,96.33) v4(50.65,95.63) v4(50.65,94.93) v4(50.65,94.23) v4(50.65,93.55) v4(50.65,92.85) v4(50.65,92.15) v4(50.65,91.45) v4(50.65,90.75) v4(50.65,90.06) v4(50.59,12.79) v4(62.1,21.25) v4(62.1,17.88) v4(62.67,20.93) v4(62.67,20.23) v4(62.67,19.53) v4(62.67,18.83) v4(62.8,22.83) v4(63.31,20.93) v4(63.31,20.23) v4(63.31,19.53) v4(63.31,18.83) v4(63.43,22.83) v4(64.07,22.83) v4(64.26,28.36) v4(64.7,22.83) v4(64.96,28.36) v4(65.34,22.83) v4(65.66,28.36) v4(66.35,28.36) v4(71.54,68.52) v4(71.55,67.87) v4(71.55,67.22) v4(72.17,67.59) v4(72.17,66.93) v4(100.58,49.28) v4(100.58,48.58) v4(100.58,47.94) v4(100.61,47.31) v4(101.28,49.28) v4(101.29,48.6) v4(101.31,47.97) v4(101.32,47.31) v4(102.23,52.93) v4(102.23,52.23) v4(105.81,53.67) v4(108,59.66) v4(107.99,58.99) v4(108.71,59.65) v4(108.72,58.99) v4(110.31,59.59) v4(110.32,58.9) v4(110.37,58.23) v4(110.37,57.44) v4(110.37,56.67) v4(110.39,55.94) v4(199.53,60.16) v4(199.63,62.03) v4(199.59,61.39) v4(199.6,59.49) v4(200.68,60.82) v4(201.01,59.19) v4(202.17,60.18) v4(202.17,59.54) v4(211.44,48.18) v4(212.07,48.18) v4(212.07,47.54) v4(212.71,48.18) v4(212.71,47.54) v4(216.88,55.28) v4(216.88,54.65) v4(216.88,54.01) v4(217.51,55.28) v4(217.51,54.65) v4(217.51,54.01) v4(218.15,55.28) v4(218.15,54.65) v4(218.15,54.01) v4(218.78,55.28) v4(218.78,54.65) v4(218.78,54.01) v4(219.42,55.92) v4(219.42,55.28) v4(219.42,54.65) v4(219.42,54.01) v4(220.05,55.92) v4(220.05,55.28) v4(220.05,54.65) v4(220.05,54.01) v4(220.69,55.92) v4(220.69,55.28) v4(220.69,54.65) v4(220.69,54.01) v4(223.5,48.31) v4(223.61,47.68) v4(224.14,48.31) v4(224.24,47.66) v4(224.77,48.31) v4(224.89,47.66)
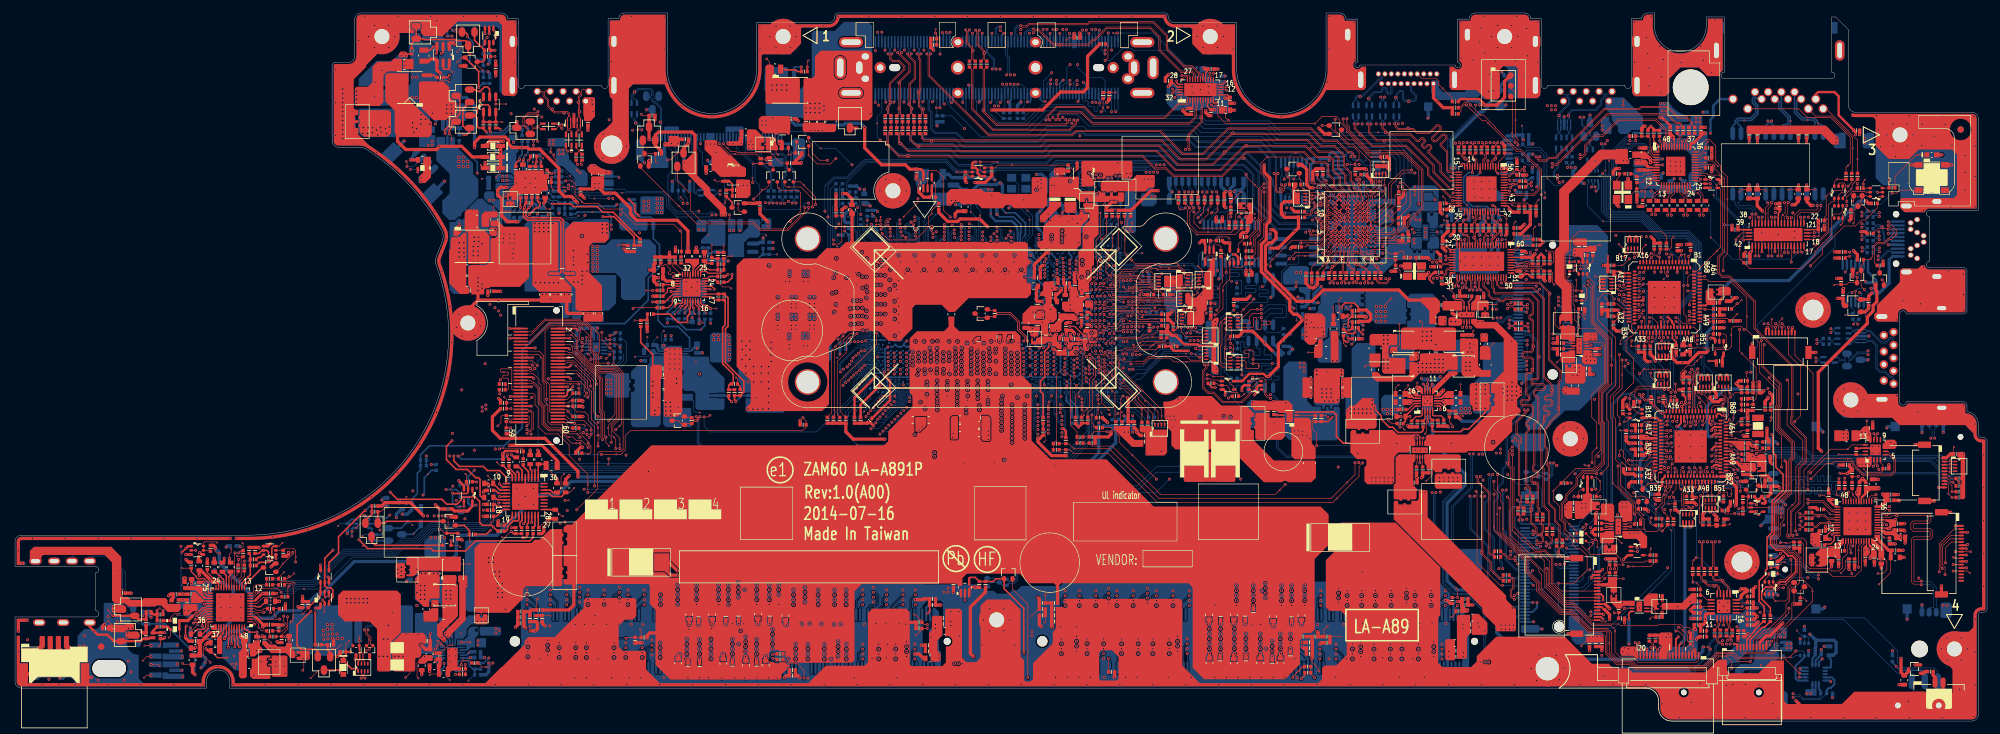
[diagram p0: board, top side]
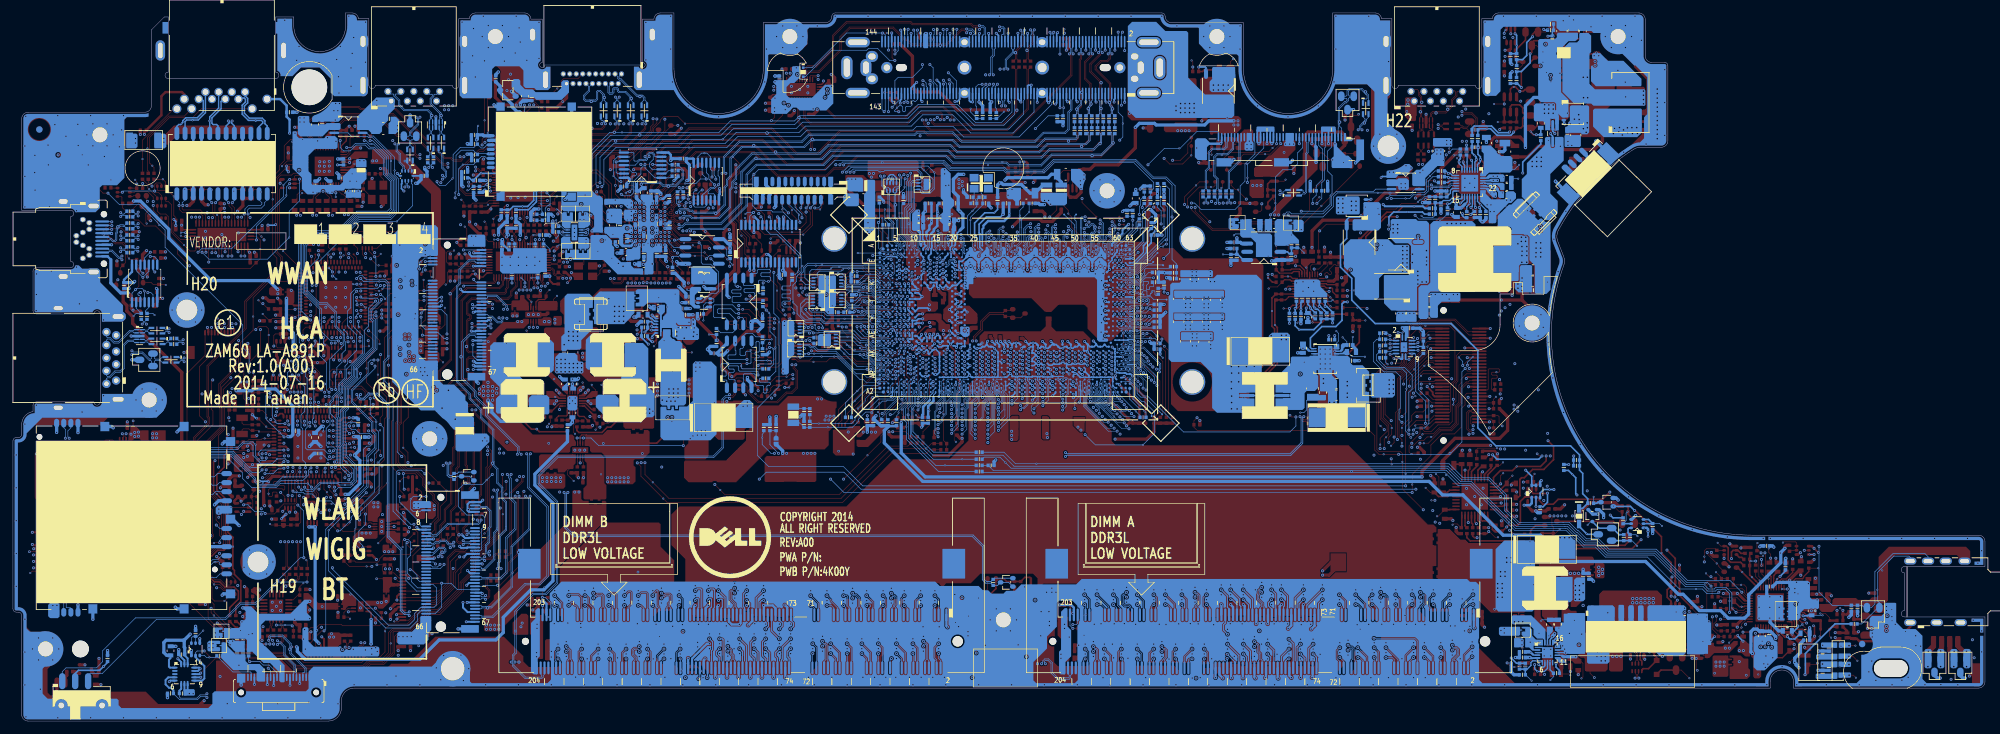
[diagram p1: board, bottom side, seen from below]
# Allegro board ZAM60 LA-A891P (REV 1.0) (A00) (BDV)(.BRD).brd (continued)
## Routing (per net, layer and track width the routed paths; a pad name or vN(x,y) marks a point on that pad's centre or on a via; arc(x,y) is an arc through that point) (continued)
GNDA: length 25.9
  TOP w0.203: UA1.26 29.74,19.37 29.38,19.73 v2(29.38,19.86) ; v3(32.8,9.79) 31.3,9.79 CA16.2
  TOP w0.254: v3(26.5,14.73) 26.35,14.58 v2(26.35,13.12) ; v2(26.41,26.71) v3(25.77,26.06)
  TOP w0.381: v2(26.41,26.71) 26.75,27.05 QA2.1 ; CA16.2 29.84,10.86 v2(29.51,11.19) ; v2(28.52,26.03) 28.59,26.03 28.87,25.75 QA2.4
  TOP w0.508: CA2.2 20.25,13.66 CA3.2 19.73,13.65 v2(19.56,13.82) ; CA4.2 v2(25.94,18.74) CA1.2 ; v2(26.41,24.99) 26.85,24.56 CA35.1 ; v2(27.87,11.4) 27.75,11.28 CA18.2 ; CA17.2 26.86,12.36 26.35,12.86 v2(26.35,13.12) ; CA8.2 v2(29.12,21.46) ; v2(28.37,25.41) 28.37,24.8 CA26.2 ; CA9.2 v2(27.29,21.25) ; CA51.2 v2(30.78,25.17)
  BOTTOM w0.508: v2(19.67,16.29) 19.7,16.31 CA41.2 ; RA37.1 32.83,27.09 v2(32.64,26.9) ; 30.03,21.44 32.18,21.44 RA35.1 ; RA44.2 30.83,25.12 v2(30.78,25.17) ; v2(27.1,14.41) CA52.2 RA36.1
  vias: v2(0.52,26.34) v2(0.52,13.94) v2(1.1,24.41) v2(1.81,15.6) v2(2.7,28.24) v2(7.78,28.24) v2(12.86,28.24) v2(17.94,28.24) v2(23.02,28.24) v2(28.1,28.24) v2(29.38,20.49) v2(30.54,14.52) v2(33.18,28.24)
GNDA_CHG:
  vias: v1(77.48,83.16) v2(78.85,83.93) v2(78.86,82.52) v2(79.61,83.17) v2(80.37,83.93) v2(80.39,82.52)
VCCSENSE: length 31.6
  TOP w0.254: PR531.1 109.84,68.75 v2(110.16,69.07)
  IN1 w0.254: v2(110.16,69.07) 110.22,69.13 110.22,70.09 111.74,71.6 119.5,71.6 119.71,71.4 125.21,71.4 127.7,73.89 127.7,76.11 128.01,76.43 v2(128.2,76.43)
  BOTTOM w0.203: 130.05,73 130.05,72.45 131.64,70.86 UC1.E63
  BOTTOM w0.254: 130.05,73 130.05,73.51 129.41,74.14 129.41,75.6 128.85,76.16 RC209.2 128.57,76.43 v2(128.2,76.43)
VDD_1.35V: length 4.8
  TOP w0.102: v1(64.09,7.09) 64.28,7.28 PC211.1
  TOP w0.508: v2(64.96,9.31) 65.26,9.61 PR201.1 65.66,8.67 PR202.2 65.47,7.34 PC211.1
VSSSENSE: length 32.4
  TOP w0.254: PR532.1 110.11,67.86 v1(110.79,68.54) v2(110.79,69.07)
  IN1 w0.254: v2(110.79,69.07) 110.73,69.13 110.73,69.87 111.95,71.09 119.25,71.09 119.45,70.89 125.46,70.89 128.2,73.63 v2(128.2,75.79)
  BOTTOM w0.203: 129.6,73.19 129.6,72.43 131.58,70.45 132.43,70.45 UC1.E62
  BOTTOM w0.254: 129.6,73.19 128.85,73.94 RC218.1 128.84,75.16 v2(128.2,75.79)
3301_ACAV_IN_NB: length 2
  TOP w0.254: PR848.1 79.17,30.46 79.35,30.64 PU800.24
3301_PWRSRC: length 2.2
  TOP w0.254: PU800.15 74.54,34.22 74.17,34.59 PR860.1
+AUX_LDO: length 3
  TOP w0.203: UR1.12 281.28,28.71 281.12,28.55 281.12,27.93 280.58,27.38 279.83,27.38 CR17.2
+BL_PWR_SRC:
  vias: v2(106.83,89.22) v2(107.46,89.22) v2(108.1,89.22) v3(108.32,87.93)
+CAP_LDO: length 10.4
  TOP w0.305: UE1.B46 256.37,61.28 256.08,61.58 256.08,61.82 v2(255.42,62.49)
  TOP w0.508: CE7.1 257.79,58.5 v2(258.05,58.76)
  IN1 w0.508: v2(258.05,58.76) 257.73,59.07 257.73,62.54 257.17,63.09 255.82,63.09 255.42,62.69 v2(255.42,62.49)
  BOTTOM w0.102: v2(258.05,58.76) 258.05,58.32 v1(258.35,58.01)
+COINCELL: length 1.8
  TOP w0.508: JRTC1.1 296.7,6.78 296.43,7.06 PR1.1
+DC_IN: length 100
  TOP w0.508: PC5.2 63.92,102.06 64.21,102.35 64.95,102.35 65.2,102.09 PQ6.3 65.2,100.67 65.68,100.19 v2(65.68,100.18) ; v2(71.02,88.68) 71.02,89.47 71.85,90.31 75.78,90.31 76.26,89.83 76.26,89.26 76.83,88.68 v3(78.32,88.68) 79.17,88.68 79.41,88.44 81.07,88.44 84.06,85.46 84.06,81.99 84.92,81.13 85.96,81.13 v3(86.45,80.64) v2(86.93,80.16) ; PR835.1 83.78,40.3 v3(82.68,41.4) 81.44,42.63 v2(76.39,42.63)
  IN4 w0.508: v2(76.39,42.63) 75.52,43.49 75.52,51.07 76.07,51.62 76.07,57.3 79.24,60.47 82.8,60.47 85.82,63.49 86.19,63.49 91.08,68.38 91.08,73.72 89.65,75.16 89.65,78.75 88.24,80.16 v2(86.93,80.16)
  BOTTOM w0.508: 65.34,96.43 69.72,96.43 71.02,95.14 v2(71.02,88.68) ; PR737.1 v2(86.93,80.16)
+DC_IN_SS: length 111.4
  TOP w0.508: 59.12,93.32 59.12,89.64 60.37,88.38 65.12,88.38 v3(65.62,88.87) 69.02,88.87 70.66,87.24 PD704.2 ; PR831.1 v2(83.75,37.44)
  IN1 w0.508: v2(75.05,62.78) 75.05,58.56 71.05,54.56 71.05,41.95 v2(70.99,41.88)
  IN2 w0.508: v2(83.75,37.44) 80.32,37.44 77.91,39.85 74.72,39.85 72.69,41.88 v2(70.99,41.88) 70.99,41.54 64.56,35.11 64.2,35.11 63.43,34.35 62.19,34.35 59.85,32.02 v2(59.85,32)
  IN3 w0.508: v2(75.05,62.78) 72.86,62.78 67.6,68.03 67.6,76.43 69.96,78.79 69.96,82.16 64.01,88.11 62.83,88.11 62.06,88.88 62.06,90.61 v4(61.63,91.05)
  BOTTOM w0.508: v2(59.85,32) 60.62,32 PD817.3
  vias: v4(61.47,92.51) v4(61.44,91.76) v4(62.06,91.6) v4(62.72,93.02) v4(62.7,92.32) v4(62.79,93.76) v4(63.45,93.08) v4(64.08,92.32)
+DCIN: length 2
  BOTTOM w0.102: v1(71.99,86) 72.67,85.33 73.71,85.33
+DCIN_JACK:
  vias: v3(55.53,96.52) v3(55.59,98.79) v3(56.73,100.61) v4(52.77,95.44) v4(52.78,97.41) v4(52.78,96.77) v4(52.78,96.11) v4(61.44,99.55) v4(61.4,96.39) v4(62.04,96.39) v4(62.08,99.55)
+DCPRRTC: length 0.5
  BOTTOM w0.229: v2(166.92,60.03) 166.85,59.95 UC1.AE7
  vias: v1(166.86,58.67)
+DIMM1_VREF_DQ: length 9.2
  TOP w0.102: RD4.2 80.63,18.74 v3(80.78,18.9)
  TOP w0.508: RD5.1 79.56,16.93 ; 79.56,16.93 RD6.1 CD5.1 CD1.1 78.62,14.69 v2(78.91,14.4) ; 79.56,16.93 79.82,17.18 RD4.2
  BOTTOM w0.356: JDIMM1.1 79,14.48 v2(78.91,14.4)
+DIMM2_VREF_DQ: length 8.1
  TOP w0.102: RD23.1 v3(159.2,19.57)
  TOP w0.508: v2(160.32,14.53) 160.2,14.66 CD33.1 CD34.1 RD24.1 RD22.2 RD23.1
  BOTTOM w0.356: v2(160.32,14.53) 160.5,14.71 JDIMM2.1
+DOCK_PWR_BAR: length 89.9
  TOP w0.508: PR832.2 85.09,37.39 v2(85.66,37.96) ; PD705.2 73.38,89.67 v2(75.45,89.67)
  IN1 w0.508: v4(97.2,78.98) 97.19,78.97 85.47,78.97 83.78,80.66 83.78,84.81 81.24,87.35 79.12,87.35 77.82,88.65 76.47,88.65 v2(75.45,89.67)
  IN4 w0.508: v2(85.66,37.96) 84.71,38.91 84.71,44.55 84.13,45.12 82.48,45.12 81.09,46.52 81.09,48.68 80.39,49.38 79.69,49.38 79.26,49.81 79.26,51.08 78.86,51.48 78.86,55.92 79.82,56.87 83.16,56.87 84.86,58.57 86.03,58.57 87.5,60.05 88.46,60.05 89.77,61.36 90.96,61.36 92.4,62.79 92.4,64.51 94.18,66.29 94.18,71.97 97.2,74.99 v4(97.2,78.98)
  vias: v3(132.22,93.93) v4(97.2,80.37) v4(97.2,79.67) v4(97.9,80.37) v4(97.9,79.67) v4(97.9,78.98) v4(99.23,80.75) v4(99.23,80.06) v4(99.23,79.36) v4(99.23,78.66) v4(99.93,80.75) v4(99.93,80.06) v4(99.93,79.36) v4(99.93,78.66) v4(122.22,95.49) v4(122.22,94.79) v4(122.22,94.09) v4(122.92,95.49) v4(122.92,94.79) v4(122.92,94.09) v4(123.62,95.49) v4(123.62,94.79) v4(123.62,94.09) v4(124.32,95.49) v4(124.32,94.79) v4(124.32,94.09) v4(125.02,95.1) v4(125.02,94.41)
+EDP_VDD: length 1.3
  TOP w0.102: v1(117.96,87.52) 117.6,87.87 UV24.1
+LCDVDD:
  vias: v2(113.41,89.15) v2(113.41,88.52) v2(114.04,89.15) v2(114.04,88.52) v3(113.69,89.67)
+LOM_VCT: length 2
  TOP w0.102: C316.1 162.81,105.65 v1(162.49,105.33)
  TOP w0.508: C316.1 v2(163.67,106.34)
+MIC1_VREF_OUT: length 8.3
  TOP w0.127: v1(25.55,13.07) 25.4,13.22 DA4.2
  TOP w0.203: UA1.30 29.59,17.77 29.31,17.49 28.95,17.49 28.19,16.74 27.91,16.74 27.4,16.23
  TOP w0.381: DA4.2 DA5.2 25.82,15.53
  TOP w0.508: 25.82,15.53 26.71,15.53 27.4,16.23
+NBDOCK_DC_IN_SS: length 146.9
  TOP w0.127: v2(142.95,94.84) v3(142.36,94.84)
  TOP w0.508: v2(74.74,30.96) 74.65,30.87 PR863.2
  IN1 w0.508: v2(69.53,31.28) 70.19,30.62 74.39,30.62 v2(74.74,30.96)
  IN3 w0.508: v2(142.95,94.84) 142.48,94.37 130.35,94.37 126.35,90.37 120.09,90.37 117.94,88.23 116.42,88.23 114.96,86.77 111.74,86.77 111.05,87.46 97.08,87.46 95.76,86.14 95.76,79.41 94.8,78.46 94.8,75.37 93.06,73.63 93.06,68.08 91.21,66.23 91.21,62.67 90.74,62.2 87.19,62.2 83.92,58.94 80.69,58.94 77.66,55.91 77.66,40.8 77.21,40.36 71.05,40.36 70.04,39.34 70.04,31.79 v2(69.53,31.28) 68.99,30.74 59.66,30.74 v2(58.94,31.46)
  BOTTOM w0.254: JDOCK1.41 v2(142.95,94.84)
  BOTTOM w0.508: PD817.2 59.63,32.7 58.94,32 v2(58.94,31.46)
+PBATT: length 79.3
  TOP w0.508: PR838.2 82.48,31.28 v2(82.23,31.03) ; PD702.2 v2(72.65,86.39) ; CC95.1 v2(75.04,66.46)
  IN1 w0.381: v2(82.23,31.03) 81.14,32.12 78.28,32.12 74.93,35.47 73.28,35.47 72.73,36.02 v2(71.35,36.02)
  IN2 w0.508: v2(72.65,86.39) 75.44,86.39 76.71,85.13 76.71,83.1 77.54,82.26 77.54,78.9 78.86,77.58 80.93,77.58 81.67,78.32 v2(82.4,78.32)
  IN3 w0.508: v2(82.4,78.32) 82.86,77.85 84.96,77.85 86.8,76.01 86.8,74.68 87.28,74.19 88.52,74.19 v4(89.32,73.39) ; v4(57.68,14.82) 59.48,14.82 61.4,16.74 61.4,23.98 62.48,25.06 70.61,25.06 73.47,27.91 77.02,27.91 78.29,29.18 79.94,29.18 81.79,31.03 v2(82.23,31.03)
  BOTTOM w0.508: v2(82.4,78.32) 82.03,77.95 PR723.2
  vias: v3(58.29,16.75) v4(51.27,18.94) v4(51.27,18.3) v4(51.9,18.94) v4(51.9,18.3) v4(52.54,18.94) v4(52.54,18.3) v4(53.17,18.94) v4(53.17,18.3) v4(53.81,18.94) v4(53.81,18.3) v4(54.44,18.94) v4(54.44,18.3) v4(56.26,10.01) v4(56.96,12.67) v4(56.89,10.01) v4(57.53,10.01) v4(57.59,12.67) v4(89.32,72.76) v4(89.32,72.12) v4(89.32,71.49) v4(89.32,70.85) v4(89.32,70.22) v4(89.32,69.58) v4(89.98,73.38) v4(89.98,72.75) v4(89.98,72.11) v4(89.98,71.48) v4(89.98,70.84) v4(89.98,70.21) v4(89.98,69.57)
+PCH_ASATA3PLL: length 9.6
  TOP w0.102: LC2.2 163.07,79.79 v3(161.78,78.51)
  BOTTOM w0.254: 164.08,76.36 164.14,76.3 164.14,74.47 163.89,74.22 163.89,73.73 UC1.A12 164.09,73.09 UC1.B11
  BOTTOM w0.508: 164.08,76.36 CC55.1 CC56.1 164.08,78.52 v2(163.76,78.84) 163.78,78.85 RC17.2
+PCH_AUSB3PLL: length 23
  IN2 w0.508: v2(151.76,78.34) 152.71,77.39 v2(158.61,77.39)
  BOTTOM w0.254: UC1.B27 155.34,73.26 155.34,75.37 155.45,75.48 155.45,76.82 154.3,77.96 152.14,77.96 v2(151.76,78.34) ; 159.45,74.74 159.45,74.54 159.64,74.35 159.64,73.5 159.91,73.23 UC1.B18
  BOTTOM w0.508: v2(151.76,78.34) 151.71,78.39 RC149.1 ; 159.45,74.74 159.45,76.04 CC51.1 CC47.1 158.66,77.44 v2(158.61,77.39)
  vias: v3(159.65,78.38)
+PCH_RTC_VCCSUS3_3: length 17.8
  TOP w0.508: v2(171.89,50.01) 172.02,49.89 v3(172.02,47.65) RC212.2 RC213.2
  IN2 w0.381: 164.7,56.31 164.75,56.26 164.75,52.14 165.8,51.09 171.38,51.09 171.89,50.58 v2(171.89,50.01)
  BOTTOM w0.229: 164.31,58.03 164.27,58.03 v2(163.96,57.72)
  BOTTOM w0.254: UC1.AH11 164.31,58.03
+PCH_VCC1P05: length 35.6
  TOP w0.076: v2(161.02,68.61) 160.7,68.94 v3(160.45,68.94)
  TOP w0.508: v2(161.02,68.61) 161.17,68.46 CC78.1
  IN3 w0.508: v2(161.02,68.61) 160.29,67.88 157.32,67.88 156.65,68.55 156.65,69.95 155.42,71.18 155.42,78.74 151.44,82.71 v2(151.44,83.67)
  BOTTOM w0.229: v2(161.02,68.61) 160.78,68.61 160.56,68.39 UC1.J18 160.56,68.17 160.2,67.81 UC1.K19
  BOTTOM w0.508: v2(151.44,83.67) 151.09,84.02 144.8,84.02 144.27,84.56 CC77.1 143.38,83.98 142.75,83.35 LC4.2
+PCH_VCCACLKPLL: length 31.6
  IN2 w0.508: v2(157.82,84.54) 157.06,85.31 153.12,85.31 152.28,84.47 v2(152.28,83.2)
  BOTTOM w0.254: 158.37,75.92 158.81,75.48 158.81,74.63 159.11,74.33 159.11,73.65 UC1.A20
  BOTTOM w0.508: 158.37,75.92 157.95,76.34 157.95,78.36 v3(158.4,78.82) 158.67,79.08 CC82.1 158.67,81.11 159.42,81.86 159.42,83.79 158.67,84.54 v2(157.82,84.54) ; LC5.2 145.57,82.88 CC81.1 147.57,81.64 148.9,82.97 151.74,82.97 151.97,83.2 v2(152.28,83.2) 152.59,82.89 RC69.2
+PCH_VCCDSW: length 22.8
  TOP w0.203: CC97.2 165.24,59.55 163.76,61.02 v2(163.01,61.02)
  TOP w0.254: RC211.2 v1(158.87,48.13) 158.87,50.56 158.47,50.97 158.47,52.55 159.13,53.21 159.13,57.21 159.85,57.93 v2(159.85,58.28)
  IN2 w0.254: v2(159.85,58.28) 159.5,58.63 159.5,60.79 160.09,61.39 162.71,61.39 163.01,61.09 v2(163.01,61.02)
  BOTTOM w0.254: UC1.AG19 160.25,58.69 v2(159.85,58.28) 159.44,58.69 UC1.AG20
+PCH_VCCDSW3_3: length 171
  TOP w0.305: JAPS1.3 v2(301.75,29.19) ; JAPS1.7 301.62,27.19 v2(301.75,27.31)
  IN2 w0.508: v2(175.66,44.69) 175.66,48.02 171.83,51.85 171.13,51.85 170.56,52.43 170.56,56.3
  IN3 w0.381: v2(301.75,29.19) v2(301.75,27.31) 301.24,27.31 300.73,26.81 300.73,22.9 297.16,19.33 278.25,19.33 276.15,21.44 272.5,21.44 271.1,20.04 269.89,20.04 269.47,19.62 265.57,19.62 265.15,20.04 262.25,20.04 260.16,17.94 258.43,17.94 256.75,16.27 248.49,16.27 246.81,17.94 244.92,17.94 244.54,18.33 242.57,18.33 240.26,16.02 226.6,16.02 226.29,15.71 204.32,15.71 202.45,17.58 202.45,20.3 200.89,21.86 190.57,21.86 174.94,37.49 174.94,41.25 v2(174.9,41.29)
  BOTTOM w0.254: v2(165.73,57.56) 165.26,58.03 UC1.AH10
  vias: v3(177.15,41.73)
+PCH_VCCDSW_R: length 3.2
  TOP w0.076: v1(159.04,43.18) 159.29,43.43 159.29,44.78 158.94,45.14 CC65.1
  TOP w0.254: CC65.1 RC211.1
+PWR_SRC: length 2.4
  TOP w0.102: v3(212.66,65.33) 211.77,64.44 v4(211.77,64.12)
  TOP w0.508: CC94.2 87.51,81.37 v2(88.01,80.87)
  vias: v2(111.89,82.82) v2(112.52,82.82) v2(113.15,82.82) v4(59.12,23.47) v4(59.12,22.83) v4(59.69,23.79) v4(59.69,23.15) v4(59.69,22.52) v4(80.32,76.94) v4(80.32,76.3) v4(80.32,75.67) v4(80.48,67.79) v4(81.02,76.94) v4(81.02,76.3) v4(81.02,75.67) v4(81.17,67.79) v4(81.72,76.94) v4(81.72,76.3) v4(81.72,75.67) v4(81.87,67.79) v4(82.42,76.94) v4(82.42,76.3) v4(82.42,75.67) v4(82.57,67.79) v4(83.12,76.94) v4(83.27,67.79) v4(83.97,67.79) v4(91.42,52.75) v4(91.42,52.05) v4(91.42,51.35) v4(91.42,50.65) v4(92.07,52.74) v4(92.07,52.04) v4(92.07,51.35) v4(92.07,50.65) v4(210.37,64.12) v4(210.37,63.35) v4(210.37,62.59) v4(210.39,61.82) v4(211.07,64.12) v4(211.07,63.35) v4(211.07,62.59) v4(211.08,61.82) v4(211.77,63.35) v4(211.77,62.59) v4(211.78,61.82)
+PWR_SRC_AC: length 63.9
  TOP w0.102: v3(116.15,102.4) 116.61,101.94 PC807.1
  TOP w0.254: v2(67.52,43.34) 66.67,42.49 66.67,40.42 68.18,38.91 69.9,38.91 71.18,37.63 71.63,37.63 71.87,37.39 71.87,34.86 72.14,34.59 PR860.2
  IN1 w0.254: v2(73.4,64.43) 73.4,63.89 73.78,63.51 73.78,59.09 69.59,54.9 69.59,49.19 68.77,48.36 68.77,44.49 67.62,43.34 v2(67.52,43.34)
  IN2 w0.254: v4(68.58,85.76) 68.58,82.92 69.78,81.71 69.78,75.48 69.09,74.78 68.68,74.78 68.09,74.19 68.09,69.25 72.92,64.43 v2(73.4,64.43)
  vias: v4(68.56,87.18) v4(68.58,86.52) v4(69.26,87.18) v4(69.28,86.52) v4(69.28,85.76) v4(69.97,86.52) v4(69.97,85.76) v4(116.95,98.34) v4(116.95,97.58) v4(117.71,98.34) v4(117.71,97.58) v4(118.47,98.34) v4(118.47,97.58) v4(119.24,98.34) v4(119.24,97.58)
+RSVD_VCC3P3_1: length 3.1
  TOP w0.203: RL6.2 253.24,89.72 254,88.96 254,88.11 253.87,87.99 UL1.1
+RTC_CELL: length 395.3
  TOP w0.102: v2(30.92,26.71) 30.92,26.22 31.18,25.97 v3(31.63,25.97)
  TOP w0.254: RPE5.6 264.27,53.25 v2(264.52,53.51) 264.77,53.27 RPE5.5
  TOP w0.508: PD3.1 292.62,7.69 PC1.1 291.45,7.54 v2(291.45,9.69) ; RE32.1 269.55,52.42 v2(269.54,52.43) ; v2(30.92,26.71) 30.92,26.94 30.69,27.17 RA21.1 ; v2(268.32,49.89) 267.78,49.89 RE62.1 ; RE31.1 v2(268.59,52.43)
  IN1 w0.508: v2(291.45,9.69) 291.45,21.79 294.05,24.4 294.05,36.02 291.83,38.24 285.67,38.24 285.24,38.67 284.05,38.67 276.91,45.81 276.91,47.41 274.87,49.45 270.54,49.45 269.54,50.45 v2(269.54,52.43) v2(268.59,52.43)
  IN2 w0.381: v2(163.03,57.71) 163.03,58.06 163.34,58.37 v2(164.71,58.37)
  IN2 w0.508: v2(187.81,47) 187.81,45.1 186.75,44.04 175.13,44.04 173.23,45.95 172.02,45.95 171.38,46.58 v2(171.38,47.22) 171.38,48.11 170.49,49 166.8,49 164.96,50.85 164.13,50.85 163.37,51.61 163.37,52.62 163.03,52.96 v2(163.03,57.71)
  IN3 w0.508: v2(268.32,49.89) 266.65,49.89 265.26,51.29 264.08,51.29 260.72,47.93 257.36,47.93 256.98,47.55 248.61,47.55 247.08,46.01 247.08,38.26 245.36,36.55 243.96,36.55 243.08,35.66 238.06,35.66 235.39,32.99 235.39,31.79 232.74,29.14 229.73,29.14 228.89,28.3 209.76,28.3 206.55,31.51 197.24,31.51 189.91,38.85 189.91,42.6 187.81,44.7 v2(187.81,47)
  IN4 w0.508: v2(268.59,52.43) 267.51,53.51 v2(264.52,53.51) ; v2(268.32,49.89) 269.54,51.11 v2(269.54,52.43)
  BOTTOM w0.254: v2(164.71,58.37) 164.7,58.37 164.72,58.35 164.72,58.33 165.1,58.72 UC1.AG10
  BOTTOM w0.381: RC78.2 169.48,45.62 168.27,45.62 RC1.1
  BOTTOM w0.508: v2(30.92,26.71) 31.56,26.07 31.56,24.49 36.51,19.53 36.51,16.55 37.14,15.91 39.68,15.91 40.85,17.08 44.13,17.08 46.66,19.61 47.38,19.61 52.44,24.68 67.12,24.68 68.2,25.76 68.2,28.23 68.7,28.74 74.46,28.74 80.68,34.96 80.68,34.97 83.83,34.97 85.91,37.06 164.14,37.06 170.09,43 170.09,44.93 169.53,45.49 169.53,45.68 RC78.2 169.54,45.67 170.49,45.67 RC9.1 170.67,45.68 171.59,46.6 CC50.1 171.76,46.84 v2(171.38,47.22) ; RC10.1 RC8.1 187.77,46.96 v2(187.81,47)
+RTC_CELL_VBAT: length 17.6
  TOP w0.305: UE2.B64 262.65,44.46 262.24,44.05 v2(262.24,43.99)
  TOP w0.508: v2(270.25,51.09) 269.92,50.76 RE32.2
  BOTTOM w0.508: v2(270.25,51.09) v1(268.54,51.09) 267.84,51.09 267.59,51.35 264.16,51.35 261.5,48.69 CE11.1 261.5,44.28 261.8,43.99 v2(262.24,43.99)
+SD_IO_LDO: length 8.6
  TOP w0.102: v1(288.02,21.13) 289.86,22.97 CR14.2
  TOP w0.508: CR14.2 289.86,26.16 CR15.2 289.55,26.4 288.16,27.79
+SDC_IN: length 81.7
  TOP w0.254: v2(79.36,86.72) 79.66,87.03 PR710.2 ; PR847.1 77.1,40.78 v2(76.68,41.2)
  IN4 w0.254: v2(79.36,86.72) 79.95,86.72 80.39,87.16 81.25,87.16 83.57,84.84 84.68,84.84 86.36,83.16 86.36,79.92 86.74,79.54 88.03,79.54 89.09,78.49 89.09,74.99 90.57,73.51 90.57,68.59 85.98,63.99 85.61,63.99 82.59,60.98 79.03,60.98 75.56,57.51 75.56,52.11 73.94,50.48 73.94,44.18 76.68,41.44 v2(76.68,41.2)
  IN4 w0.508: v4(68.07,93.98) 68.3,93.98 72.58,89.7 74.37,89.7 75.38,88.68 78.19,88.68 79.36,87.52 v2(79.36,86.72)
  BOTTOM w0.203: v2(79.36,86.72) 79.23,86.59 PU700.3
  vias: v3(64.51,94) v4(66.72,95.27) v4(66.72,94.64) v4(66.74,93.98) v4(67.4,95.27) v4(67.42,94.64) v4(67.43,93.98) v4(68.04,95.3) v4(68.09,94.63)
+SIM_PWR: length 34.9
  IN2 w0.508: v2(238.5,64.3) 238.3,64.3 237.89,64.7 237.89,72.38 238.67,73.16 238.67,76.92 232.56,83.03 232.56,86.11 233.11,86.65 v2(233.11,89.88)
  BOTTOM w0.102: v1(232.86,92.05) 232.99,91.92 C263.1
  BOTTOM w0.305: JNGFF2.28 238.7,64.1 v2(238.5,64.3)
  BOTTOM w0.508: v2(233.11,89.88) 232.99,89.99 C263.1 232.14,90.64 232,90.5 JSIM1.8
+SM_VREF_CA: length 95.3
  TOP w0.102: v3(202.8,14.66) 202.28,14.13 CD36.1
  TOP w0.508: v2(201.2,13.87) 201.35,13.72 RD19.2 CD36.1
  IN3 w0.508: v2(201.2,13.87) 201.2,13.88 200.97,14.11 190.19,14.11 188.64,15.67 186.82,15.67 179.83,22.65 146.73,22.65 141.1,28.28 141.1,42.03 141.91,42.84 141.91,46.95 141.67,47.19 141.67,52.93
  BOTTOM w0.279: v2(140.58,54.35) 140.88,54.64 UC1.AP49
+SM_VREF_CA_DIMM: length 94.3
  TOP w0.102: v2(200.4,9.7) 200.4,9.16 201.46,8.1 v3(201.46,7.75)
  TOP w0.508: v2(118.9,6.7) 119.22,7.02 CD23.1 CD22.1 ; RD18.2 RD19.1 200.44,12.21 RD20.1 CD55.1 CD56.1 200.48,9.78 v2(200.4,9.7)
  IN3 w0.508: v2(118.9,6.7) 119.86,7.67 146.88,7.67 147.77,8.55 199.26,8.55 v2(200.4,9.7)
  BOTTOM w0.356: JDIMM1.126 v2(118.9,6.7) ; JDIMM2.126 v2(200.4,9.7)
+SM_VREF_DQ0: length 92.2
  TOP w0.508: RD5.2 CD21.1 80.73,15.18 80.73,14.25 v3(80.43,13.94) v2(79.63,13.94)
  IN3 w0.457: v2(139.47,53.58) 139.47,52.69 139.17,52.39
  IN3 w0.508: v2(79.63,13.94) 79.76,13.94 80.39,14.57 80.39,21.06 83.26,23.93 123.56,23.93 132.13,32.49 132.13,44.11 136.95,48.94 136.95,50.18 139.17,52.39
  BOTTOM w0.254: UC1.AR51 139.7,53.66 139.55,53.66 v2(139.47,53.58)
+SM_VREF_DQ1: length 53.7
  TOP w0.102: CD54.1 158.16,17.31 v1(157.08,16.23)
  TOP w0.508: v2(158.09,19.08) 158.29,18.88 RD23.2 CD54.1
  IN3 w0.457: v2(139.63,54.31) 139.63,54.25 140.06,53.82 140.06,52.04
  IN3 w0.508: 140.06,52.04 140.06,50.56 139.13,49.63 139.13,48.17 140.97,46.33 140.97,43.34 140.01,42.39 140.01,28.17 146.55,21.64 155.53,21.64 v2(158.09,19.08)
  BOTTOM w0.254: v2(139.63,54.31) 139.96,54.64 UC1.AP51
+USB_LEFT_PWR:
  vias: v2(84.07,88.3) v2(84.12,87.69) v2(84.68,88.3) v2(84.71,87.69) v2(86.87,85.19) v2(87.31,84.81) v3(89.34,94.26) v4(89.16,96.04) v4(89.2,95.38)
+USB_RIGHT_PWR: length 0.8
  TOP w0.127: v2(248.52,95.21) v3(248.52,95.97)
+V_DDR_REF:
  vias: v1(70.16,10.59)
+VCHGR:
  vias: v3(86.28,71.14) v4(86.31,72.75) v4(86.29,71.73) v4(86.31,70.55) v4(86.33,67.91) v4(86.99,67.89) v4(87.65,69.54) v4(87.65,68.88) v4(87.64,68.22) v4(87.64,67.58) v4(88.4,69.57) v4(88.48,72.2) v4(88.5,70.9) v4(90.76,76.77) v4(90.76,76.14) v4(90.76,75.5) v4(91.46,76.77) v4(91.46,76.14) v4(91.46,75.5)
+VDISPLAY_VCC: length 12.8
  TOP w0.102: v3(284.43,66.48) 284.43,65.52 284.76,65.19 UV501.3
  TOP w0.508: UV501.3 285.25,65.2 CV509.1 286.45,65.7 v2(286.95,66.2)
  BOTTOM w0.356: 289.62,71.35 290.12,71.85 JMDP1.20
  BOTTOM w0.508: v2(286.95,66.2) 288.1,66.2 289.62,67.73 289.62,71.35
+VHDMI_VCC: length 6.7
  TOP w0.508: JHDMI1.18 219.2,96.37 v3(219.79,95.78) 220.72,94.84 RV9.2 RV7.2
+VLDOIN_1.35V:
  vias: v1(68.92,13.56) v4(71.43,15.34) v4(72.07,15.34) v4(72.7,15.34)
+VR_CAP: length 4.3
  TOP w0.305: v2(256.79,45.58) 256.98,45.58 257.44,46.03 UE2.B12
  BOTTOM w0.102: v2(256.79,45.58) v1(256.79,44.79)
  BOTTOM w0.508: v2(256.79,45.58) 257.04,45.58 CE31.1
+VREFOUT: length 11.3
  TOP w0.203: UA1.23 31.46,21.27 31.32,21.41
  TOP w0.508: 31.32,21.41 31.24,21.49 30.53,21.49 v3(30.21,21.81) 28.71,23.3 CA26.1 v2(28.47,22.55) ; RA6.2 v2(25.99,19.62) RA5.2
  IN1 w0.508: v2(25.99,19.62) 27.26,19.62 28.19,20.55 28.19,22.28 v2(28.47,22.55)
+Z4012: length 1.2
  TOP w0.508: PR1.2 295.15,7.66 294.88,7.4 PD3.2
-DCIN_JACK:
  vias: v3(57.25,91.64) v4(53.72,90.87) v4(53.82,91.77) v4(54.56,91.76) v4(54.48,90.87) v4(55.26,91.74) v4(55.22,90.97) v4(55.86,91.41) v4(56.04,90.63) v4(56.49,91.78) v4(56.59,91.1) v4(57.43,90.84) v4(57.83,91.85)
/BATPRES: length 19.3
  TOP w0.254: PR816.2 96.59,74.52 92.43,78.69 90.83,78.69 89.96,79.55 v1(88.22,79.55) 86.32,79.55 85.89,79.98 v2(83.06,79.98)
  BOTTOM w0.203: PR728.2 v2(83.06,79.98) 82.67,79.98 81.91,80.75 80.96,80.75 80.83,80.88 PU700.15
A_ON: length 96.5
  TOP w0.102: UE2.A4 261.19,49.07 v3(260.28,49.98) 259.73,50.53 259.73,51.85 259.9,52.03 259.9,53.7 v2(260.07,53.87) ; v2(202.91,46.99) 202.66,47.23 RZ42.1 ; v2(252.79,53.82) 252.79,53.25 253.29,52.75 254.75,52.75 254.87,52.63 RPE10.3 ; UZ8.3 223.93,61.11 v2(223.69,60.88)
  IN3 w0.122: v2(202.91,46.99) 202.96,46.99 207.03,51.07 207.03,59.22 v2(208.3,60.48)
  IN4 w0.089: v2(208.3,60.48) 209.28,61.46 209.28,65.09 209.48,65.29 218.68,65.29 220.05,63.92 220.05,61.26 220.44,60.88 v2(223.69,60.88) 224.15,60.43 229.38,60.43 232.39,57.42 232.39,54.27 237.68,48.99 245.82,48.99 250.16,53.33 252.3,53.33 v2(252.79,53.82) 253.28,53.33 259.53,53.33 v2(260.07,53.87)
AC_DIS: length 304.1
  TOP w0.102: v2(258.77,49.21) 258.62,49.21 258.19,48.78 UE2.A10
  TOP w0.254: PR828.1 v1(72.83,28.87) v2(73.47,29.5) ; v2(65.9,103.24) 66.15,103.49 PQ6.5
  IN1 w0.089: v2(85.34,32.55) 84.9,32.11 84.07,32.11 82.42,30.45 81.79,30.45 80.9,31.34 76.26,31.34 74.42,29.5 v2(73.47,29.5)
  IN2 w0.122: v2(85.34,32.55) 85.65,32.24 229.82,32.24 230.53,32.95 232.43,32.95 236.47,36.99 236.47,44.11 240.35,47.99 257.54,47.99 258.17,48.62 258.17,49 258.38,49.21 v2(258.77,49.21)
  IN4 w0.254: v2(73.47,29.5) 73.34,29.63 73.34,30.39 79.07,36.12 79.07,42.32 77.55,43.83 77.55,50.64 77.34,50.85 77.34,56.77 79.76,59.2 83.33,59.2 86.35,62.22 86.71,62.22 92.35,67.85 92.35,74.79 93.02,75.46 93.02,77.63 85,85.66 83.83,85.66 81.66,87.83 81.66,90.03 80.8,90.89 77.41,90.89 71.8,96.49 71.26,96.49 65.9,101.85 v2(65.9,103.24)
AC_PRESENT: length 137.8
  TOP w0.076: 173.36,51.06 173.36,51.66 172.78,52.23
  TOP w0.081: 172.78,52.23 170.48,54.53 170.48,55.67 170.04,56.11 169.05,56.11 168.69,56.46 168.06,56.46 167.8,56.72 166.81,56.72 166.33,57.2 166.33,57.56 165.86,58.02 v2(165.86,58.14)
  TOP w0.102: v2(265.1,41.19) 265.08,41.21 UE2.A54 ; 173.36,51.06 v1(176.15,48.27) 176.64,47.78 176.64,46.53 177.16,46.02 RPC1.6
  IN1 w0.089: v2(165.86,58.14) 165.86,58.08 166.14,57.81 166.14,57.16 166.49,56.8 166.49,53.56 168.01,52.04 172.64,52.04 176.42,55.83 179.6,55.83 181.54,53.89 181.54,53.24 182.81,51.97 184.83,51.97 185.15,52.29 187.53,52.29 189.77,50.04 193.27,50.04 195.37,47.94 200.05,47.94 205.99,42 214.9,42 216.05,40.84 229.23,40.84 229.55,41.16 v2(229.55,41.44)
  IN4 w0.089: v2(229.55,41.44) 229.55,41.06 230.39,40.22 233.67,40.22 236.12,37.76 240.03,37.76 242.78,40.51 248.4,40.51 249.45,39.46 253.03,39.46 254.04,40.47 256.36,40.47 256.89,39.94 260.75,39.94 261.24,40.42 261.24,40.93 261.74,41.44 263.59,41.44 263.83,41.19 v2(265.1,41.19)
  BOTTOM w0.081: UC1.AJ8 165.86,57.98 v2(165.86,58.14)
ACAV_DOCK_SRC#: length 119.9
  TOP w0.102: v2(74.86,42.07) 74.99,42.2 v1(75.42,42.2) 78.36,42.2 78.56,42 PR846.2 78.53,41.67 PR842.1
  IN3 w0.122: v2(74.86,42.07) 74.86,49.31 76.71,51.16 76.71,55.93 80.58,59.81 83.81,59.81 92.37,68.36 92.37,73.99 94.1,75.73 94.1,80.65 93.53,81.22 93.53,85.06 96.7,88.23 111.48,88.23 112.24,87.46 114.63,87.46 119.12,91.96 126.87,91.96 133.44,98.53 141.91,98.53 142.95,99.58 v2(142.95,103.14)
  BOTTOM w0.102: JDOCK1.42 v2(142.95,103.14)
ACAV_IN: length 323.6
  TOP w0.102: UE2.A64 264.64,46.21 264.92,46.49 v2(264.92,46.62) ; v2(68.45,41) 68.87,41 v3(69.2,41.33)
  TOP w0.254: v2(76.09,41.17) 76.09,40.69 PR851.1 ; v2(78.15,79.41) 78.1,79.46 PR715.1 ; PQ817.5 47.85,19.27 v2(47.93,19.19)
  IN1 w0.089: v2(76.09,41.17) 77.23,40.04 82.32,40.04 85.53,36.83 85.53,34.84 85.85,34.52 85.85,31.66 v2(84.96,30.77)
  IN1 w0.254: v2(47.93,19.19) 47.93,20.27 56.39,28.73 v2(56.39,29.54)
  IN2 w0.122: v2(264.92,46.62) 264.36,46.62 263.57,45.83 263.57,44.75 263.25,44.43 261.48,44.43 261.48,44.41 260.86,43.79 258.24,43.79 257.35,42.9 256.92,42.9 256.35,42.33 254.57,42.33 253.84,41.6 242.98,41.6 233.09,31.71 231.04,31.71 230.32,30.99 85.18,30.99 v2(84.96,30.77)
  IN2 w0.254: v2(68.45,41) 68.45,39.73 64.49,35.76 62.52,35.76 56.39,29.63 v2(56.39,29.54)
  IN3 w0.254: v2(78.15,79.41) 78.15,79.27 78.51,78.92 80.19,78.92 80.49,79.22 82.17,79.22 82.34,79.4 ; 82.34,79.4 87.58,79.4 89.86,77.11 89.86,74.97 90.89,73.94 90.89,68.96 83.44,61.51 80.16,61.51 71.88,53.23 71.88,51.16 68.64,47.92 68.64,41.19 v2(68.45,41) ; 82.34,79.4 82.34,80.29 84.01,81.95 84.01,85.19 80.13,89.06 v2(80.12,89.06)
  BOTTOM w0.254: PR713.2 78,79.26 v2(78.15,79.41) ; v2(76.09,41.17) 75.42,40.5 68.95,40.5 v2(68.45,41) ; v2(80.12,89.06) PR714.1
ACAV_IN#: length 33.4
  TOP w0.254: v2(49.15,26.44) 47.86,25.15 PU806.2 47.86,20.92 48.18,20.6 48.79,20.6 49.12,20.27 49.12,19.15 48.5,18.53 PQ817.3
  IN3 w0.254: v2(63.05,34.96) 63.05,33.5 62.23,32.68 56.51,32.68 52.07,28.23 50.94,28.23 v2(49.15,26.44)
  BOTTOM w0.254: v2(63.05,34.96) 63.24,35.15 63.24,37.63 v1(63.78,38.16) 64.37,38.76 PR864.2
ACAV_IN_NB: length 260.5
  TOP w0.102: UE2.B20 254.64,45.46 254.97,45.79 v2(255.31,45.79)
  TOP w0.254: v2(78.49,28.36) 78.89,28.36 79.17,28.63 PR848.2
  IN2 w0.122: v2(255.31,45.79) 254.84,46.27 250.95,46.27 250.76,46.46 246.69,46.46 232.69,32.45 230.73,32.45 230.03,31.75 82,31.75 78.61,28.36 v2(78.49,28.36)
  IN4 w0.254: v2(78.49,28.36) 78.05,28.8 73.28,28.8 72.9,29.18 72.9,30.52 78.69,36.31 78.69,42.13 77.17,43.64 77.17,50.49 76.96,50.69 76.96,56.93 79.61,59.58 83.17,59.58 86.19,62.6 86.56,62.6 91.97,68.01 91.97,74.94 92.64,75.62 92.64,76.33 92.28,76.69 v2(92.11,76.69)
  BOTTOM w0.254: v2(92.11,76.69) 92.11,77.98 91.37,78.71 v1(89.21,78.71) 86.93,78.71 86.61,78.4 PR743.2
ACAVDK_SRC: length 2.4
  TOP w0.254: PR842.2 78.53,39.4 79.35,38.58 PU800.4
ACAVIN: length 2.3
  TOP w0.254: PU800.8 77.35,38.14 76.34,39.15 PR851.2
ALW_PWRGD_3V_5V: length 68.3
  TOP w0.102: v2(222.17,45.5) 222.17,45.71 v1(221.9,45.97) 221.66,46.22 PR108.1 ; v2(266.37,32.83) 266.47,32.93 RE283.2 RZ51.1
  IN1 w0.089: v2(265.21,48.74) 265.21,48.18 266.37,47.03 266.37,43.18 267.98,41.57 267.98,40.45 268.2,40.23 268.2,39.42 267.51,38.73 267.51,36.83 267.24,36.56 267.24,35.01 266.37,34.14 v2(266.37,32.83)
  IN4 w0.089: v2(222.17,45.5) 222.27,45.4 233.26,45.4 235.78,47.92 246.26,47.92 250,51.66 258,51.66 259.27,50.39 263.89,50.39 265.21,49.07 v2(265.21,48.74)
ALW_PWRGD_3V_5V_EC: length 22.1
  TOP w0.102: UE2.A1 262.69,48.25 262.81,48.37 263.46,48.37 v2(264.02,47.81) ; v2(266.37,32.02) RE283.1
  IN1 w0.089: v2(266.37,32.02) 266.37,32.08 265.44,33.01 265.44,33.55 267.03,35.14 267.03,36.69 267.29,36.96 267.29,39.86 267.08,40.08 267.08,41.1 266.26,41.92 265.27,41.92 264.78,42.4 264.78,45.88 265.33,46.43 265.33,46.8 264.31,47.81 v2(264.02,47.81)
ALWON: length 64.6
  TOP w0.102: v2(265.29,44.21) UE2.A60 ; v2(214.04,45.45) 213.59,45.9 PR113.1 212.71,46.02 v3(212.23,46.51)
  IN4 w0.089: v2(265.29,44.21) 264.52,44.98 264.52,46.8 265.62,47.9 265.62,48.97 262.94,51.66 260.1,51.66 259.88,51.88 249.91,51.88 246.17,48.14 235.69,48.14 233.17,45.62 222.64,45.62 222.25,46.01 219.12,46.01 218.44,45.33 214.16,45.33 v2(214.04,45.45)
AUD_HP_NB_SENSE: length 289.4
  TOP w0.102: v2(42.92,26.07) 42.92,25.84 v1(41.45,24.37) 41.13,24.05 41.13,23.91 QA1.2 ; v2(255.44,59.29) 255.12,59.61 UE1.A41
  IN2 w0.122: v2(42.92,26.07) 43.43,26.07 44.33,26.97 57.16,26.97 61.91,31.72 61.91,32.19 62.7,32.98 67.89,32.98 69.05,31.82 70.07,31.82 70.93,30.96 72.9,30.96 74.17,32.23 78.22,32.23 78.62,32.63 78.62,33.45 80.24,35.07 86.23,35.07 87.18,34.12 228.23,34.12 229.25,35.15 229.25,35.97 229.63,36.35 231.63,36.35 234.95,39.66 234.95,44.74 241.99,51.78 247.1,51.78 252.38,57.06 254.74,57.06 255.95,58.27 255.95,58.62 255.95,58.62 255.95,58.66 255.44,59.16 v2(255.44,59.29)
  IN3 w0.122: v2(42.92,26.07) 42.03,26.96 38.67,26.96 38.22,27.41 26.03,27.41 v2(25.65,27.03)
  BOTTOM w0.102: v2(25.65,27.03) 25.65,19.94 23.61,17.89 20.66,17.89 RA2.1 CA41.1 19,17.89 18.63,17.53 DA2.3 17.56,17.53 17.02,18.07 17.02,23.09 14.22,25.88 9.27,25.88 8.8,25.41 JHP1.6
AUD_HP_OUT_L: length 24.5
  TOP w0.102: v1(33.41,26.69) 33.41,26.09 33.13,25.8 v2(33.13,25.19)
  TOP w0.381: CA43.2 33.13,24.68 v2(33.13,25.19) ; v2(23.15,13.68) 22.49,13.68 RA7.2 21.34,13.65 LA2.1 21.32,13.94 RA24.1
  IN4 w0.381: v2(33.13,25.19) 33.13,24.28 32.45,23.6 26.73,23.6 25.14,22.01 25.14,16.74 23.15,14.74 v2(23.15,13.68)
AUD_HP_OUT_L1: length 11.6
  TOP w0.381: JHP1.1 11.55,14.58 v1(12.28,13.86) 12.77,13.36 14.27,13.36 15.28,12.35 DA3.3 19.42,12.35 19.8,12.73 CA3.1 20.68,12.73 20.83,12.88 LA2.2
AUD_HP_OUT_R: length 21.7
  TOP w0.102: v2(21.96,17.12) 22.29,17.45 v1(22.39,17.45)
  TOP w0.381: CA44.2 32.32,24.76 v2(32.32,25.18) ; RA8.2 RA25.1 ; RA8.2 v2(21.96,17.12) ; RA8.2 21.4,16.48 21.08,16.8 LA3.1
  IN4 w0.381: v2(21.96,17.12) 22.65,16.42 23.62,16.42 24.38,17.18 24.38,22.33 26.41,24.36 32.06,24.36 32.32,24.61 v2(32.32,25.18)
AUD_HP_OUT_R1: length 26.7
  TOP w0.102: v1(14.4,17.26) 14.4,17 v2(15.12,16.29)
  TOP w0.381: LA3.2 20.25,16.8 CA2.1 19.04,15.73 DA1.2 v2(15.12,16.29)
  IN3 w0.381: JHP1.2 6.05,25.58 6.54,26.07 13.66,26.07 14.46,25.27 14.46,16.94 v2(15.12,16.29)
AUD_NB_MUTE#: length 276.4
  TOP w0.102: UE1.A39 v2(254.12,59.29) ; v1(39.55,12.13) 38.66,13.01 RA18.2 ; QA2.2 v2(27.92,26.4)
  TOP w0.203: UA1.48 35.46,14.23 35.56,14.13 35.81,14.13 36.19,13.75 v2(37.4,13.75) 37.39,13.74 CA31.1 37.44,13.01 RA18.2
  IN1 w0.089: v2(27.92,26.4) 27.92,24.94 28.32,24.55 34.29,24.55 35.62,23.22 35.62,15.53 v2(37.4,13.75)
  IN2 w0.122: v2(37.4,13.75) 37.65,14.01 37.65,18.14 38.69,19.17 38.69,25.27 39.24,25.82 41.08,25.82 41.91,26.65 43.65,26.65 44.62,27.62 49.59,27.62 50,27.22 57.06,27.22 61.66,31.82 61.66,32.29 62.62,33.25 64.06,33.25 64.68,33.87 67.38,33.87 69.18,32.07 70.17,32.07 71.03,31.22 72.77,31.22 74.04,32.49 78.13,32.49 78.37,32.73 78.37,33.56 80.13,35.32 86.34,35.32 87.28,34.37 223.44,34.37 225.05,35.98 228.83,35.98 229.45,36.6 231.51,36.6 234.69,39.79 234.69,44.84 241.89,52.03 247,52.03 252.28,57.31 253.09,57.31 253.48,57.69 253.48,58.64 v2(254.12,59.29)
AUD_OUT_L: length 10.6
  TOP w0.102: v1(22.26,11.58) 22.46,11.78 RA7.1
  TOP w0.203: UA1.33 29.84,16.57 29.77,16.5 29.57,16.5 28.33,15.26 27.68,15.26 v2(27.57,15.15)
  TOP w0.381: RA7.1 22.97,12.73 v2(23.15,12.92)
  IN1 w0.381: v2(27.57,15.15) 26.16,15.15 23.92,12.92 v2(23.15,12.92)
AUD_OUT_R: length 9.1
  TOP w0.203: v2(27.84,15.73) 28.24,15.73 v1(28.97,16.46) 29.34,16.83 29.64,16.83 29.78,16.97 UA1.32
  TOP w0.381: RA8.1 v2(22.87,17.12)
  IN1 w0.381: v2(27.84,15.73) 27.59,15.73 27.29,16.04 23.95,16.04 v2(22.87,17.12)
AUD_PC_BEEP: length 4.6
  TOP w0.102: CA28.2 CA27.2 v1(37.68,21.06) 37.22,21.06 36.83,20.68 36.83,19.85 36.75,19.77 UA1.12
AUD_SENSE_A: length 4.4
  TOP w0.203: UA1.13 35.46,20.98 35.67,21.19
  TOP w0.254: QA1.1 38.21,23.73 v1(37.51,23.03) 35.67,21.19
AUD_SENSE_B: length 5.9
  TOP w0.203: 35.44,21.7 35.06,21.31 UA1.14
  TOP w0.254: 36.01,22.26 35.45,21.7 35.44,21.7 ; 36.01,22.26 36.36,22.6 RA27.1 RA28.1 36.36,25.77 RA38.1 ; 36.01,22.26 v1(36.01,22.25)
AUX_EN_WOWL: length 62.2
  TOP w0.102: UL3.5 249.24,30.48 249.41,30.65 249.73,30.65 249.92,30.46 RZ38.2 250.5,30.68 250.5,31.79 v2(250.28,32.02) 250.11,32.18 250.11,33.58 v1(246.88,36.81) 246.88,46.58 246.59,46.87 246.59,50.27 246.83,50.51 247.95,51.63 v2(247.95,56.67) ; v2(250.68,26.78) 250.52,26.95 UZ11.1 ; v2(258.51,67.36) 258.51,68.66 258.86,69.01 UE1.B67
  IN1 w0.089: v2(258.51,67.36) 258.05,66.9 258.05,66.22 259.88,64.39 259.88,60.38 260.41,59.84 260.41,59.33 v2(259.98,58.9)
  IN4 w0.089: v2(247.95,56.67) 247.95,56.67 248.27,57 258.07,57 v2(259.98,58.9)
  BOTTOM w0.102: v2(250.68,26.78) 250.68,27.11 251.29,27.72 251.29,29.39 250.28,30.4 v2(250.28,32.02)
B-RAMP: length 4.5
  TOP w0.102: v2(103.55,63.86) v1(103.55,63.05)
  TOP w0.203: PU500.11 103.95,64.26 v2(103.55,63.86)
  BOTTOM w0.254: PR502.1 102.6,63.16 103.11,63.67 103.36,63.67 v2(103.55,63.86) 103.74,64.05 PR507.2
BAT1_LED#: length 43.1
  TOP w0.254: RZ28.1 270.3,17.74 269.53,18.52 269.53,21.69 270.53,22.69 270.53,23.3 270.75,23.52 v1(270.75,26.97) 270.75,28.41 271.52,29.18 271.52,34.01 273.23,35.71 273.23,38.13 272.11,39.25 272.11,41.06 271.66,41.5 271.66,44.11 v2(271.48,44.3) ; v2(264.17,47.24) 263.75,47.24 263.45,47.54 263.13,47.54 262.94,47.35 UE2.B1
  IN4 w0.254: v2(264.17,47.24) 264.17,44.65 265.39,43.42 270.61,43.42 v2(271.48,44.3)
BAT2_LED#: length 42.2
  TOP w0.254: UE2.A55 265.31,41.71 v2(265.66,41.37) ; v2(273.52,40.27) 273.75,40.04 273.75,35.58 v1(273.26,35.09) 271.9,33.73 271.9,28.98 271.29,28.37 271.29,27.27 272.15,26.42 273.11,26.42 273.99,25.54 274.63,25.54 275.18,24.99 275.18,23.1 273.61,21.53 272.8,21.53 271.99,20.72 270.56,20.72 269.91,20.08 269.91,18.87 271.26,17.53 RZ25.1
  IN4 w0.254: v2(265.66,41.37) 265.66,41.5 265.96,41.8 266.58,41.8 267.53,40.85 267.9,40.85 268.95,39.8 270.77,39.8 271.24,40.27 v2(273.52,40.27)
BATDRV#: length 11.5
  IN3 w0.254: v2(87.6,74.99) 87.6,76.3 84.88,79.02 82.69,79.02 82.51,78.84 81.14,78.84 v2(80.76,78.46)
  BOTTOM w0.254: PQ800.4 v2(87.6,74.99) ; v2(80.76,78.46) 80.76,78.17 80.44,77.85 PR722.2
BATT_WHITE#: length 5.4
  TOP w0.254: JLED1.5 268.15,12.59 v1(269.58,14.02) 270.08,14.52 270.37,14.52 RZ25.2
BATT_YELLOW#: length 5.1
  TOP w0.254: RZ28.2 270.14,15.4 268.82,14.08 268.82,13.92 v1(268.3,13.4) 268.3,13.28 267.65,12.63 JLED1.4
BBS_BIT: length 12.2
  TOP w0.102: T109.1 167.71,75.04 167.07,74.4 167.07,71.35 167.29,71.12 167.29,68.56 v2(166.37,67.65)
  BOTTOM w0.081: v2(166.37,67.65) 166.2,67.47 UC1.L8
BC_CLK_ECE1117: length 60.5
  TOP w0.102: v2(231.41,41.21) 231.41,39.45 231.66,39.21 231.66,29.96 233.35,28.27 ; JKBTP1.7 238.95,20.1 237.65,21.4 237.65,25.25 236.44,26.47 235.15,26.47 233.35,28.27 ; 233.35,28.27 v1(233.35,28.27) ; v2(252.14,44.6) 252.48,44.94 253,44.94 253.22,44.71 UE2.A20
  IN4 w0.089: v2(252.14,44.6) 251.17,44.6 249.98,43.42 249.03,43.42 248.94,43.5 248.94,44.13 248.85,44.22 248.53,44.22 248.44,44.13 248.44,43.5 248.36,43.42 246.84,43.42 246.75,43.5 246.75,44.13 246.66,44.22 246.35,44.22 246.26,44.13 246.26,43.5 246.17,43.42 245.85,43.42 245.76,43.5 245.76,44.13 245.67,44.22 245.36,44.22 245.27,44.13 245.27,43.5 245.18,43.42 244.33,43.42 239.62,38.7 236.51,38.7 233.99,41.21 v2(231.41,41.21)
BC_CLK_ECE5048: length 39.7
  TOP w0.102: UE1.A30 248.73,62.76 v2(248.65,62.68) ; v2(260.19,35.76) UE2.A43
  BOTTOM w0.102: v2(248.65,62.68) 248.5,62.53 248.5,57.51 251.47,54.54 251.47,53.09 253.1,51.46 253.1,48.43 253.65,47.88 253.65,42.98 253.42,42.74 253.42,40.93 251.9,39.41 251.9,37.19 252.59,36.5 v1(253.43,36.5) 254.3,36.5 254.51,36.71 257.19,36.71 258.37,35.53 259.48,35.53 259.71,35.76 v2(260.19,35.76)
BC_DAT_ECE1117: length 76.4
  TOP w0.102: v2(255.27,44.92) 254.75,44.92 254.72,44.96 UE2.B21 ; v2(231.39,41.8) 231,41.41 231,39.48 231.38,39.1 231.38,29.52 v1(231.87,29.02) 233.26,27.63 233.51,27.63 234.91,26.24 236.34,26.24 237.42,25.16 237.42,21.25 239.57,19.1 JKBTP1.9 ; RPE5.2 263.77,50.5 264.4,49.86 264.4,49.49 v2(263.94,49.04)
  IN4 w0.089: v2(263.94,49.04) 263.46,48.55 263.46,45.88 262.95,45.38 261.87,45.38 261.14,44.64 256.82,44.64 256.67,44.49 255.7,44.49 v2(255.27,44.92) 252.93,44.92 252.85,45 250.87,45 250.3,44.43 245.04,44.43 239.53,38.92 236.6,38.92 233.71,41.8 v2(231.39,41.8)
BC_DAT_ECE5048: length 44.4
  TOP w0.102: v2(260.59,56.35) 260.59,56.35 v1(259.96,55.72) 259.18,54.94 258.4,54.94 257.34,53.88 257.34,52.75 RE36.2 ; v2(259.55,39.18) 259.68,39.18 259.94,38.92 UE2.B45 ; UE1.B31 251.17,63.01 v2(251.63,63.48)
  IN1 w0.089: v2(260.59,56.35) 259.38,57.56 251.62,57.56 250.71,58.48 250.71,60.93 250.33,61.32 250.33,62.69 250.68,63.04 251.19,63.04 v2(251.63,63.48)
  BOTTOM w0.102: v2(259.55,39.18) 259.55,39.94 259.97,40.36 259.97,45.19 260.23,45.45 260.23,47.33 259.65,47.92 259.65,51.66 261.02,53.03 261.02,54.72 260.59,55.16 v2(260.59,56.35)
BC_INT#_ECE1117: length 60
  TOP w0.102: v2(252.09,45.65) 252.53,45.21 UE2.A19 ; JKBTP1.10 239.69,18.6 237.17,21.12 237.17,24.64 235.8,26.01 233.86,26.01 v1(233.61,26.25) 231.15,28.72 231.15,38.95 230.77,39.33 230.77,41.77 v2(231.39,42.39)
  IN4 w0.089: v2(252.09,45.65) 250.69,45.65 250.36,45.32 245.62,45.32 239.44,39.13 236.69,39.13 233.43,42.39 v2(231.39,42.39)
BC_INT#_ECE5048: length 39.1
  TOP w0.102: v2(259.69,36.18) UE2.A42 ; UE1.A29 v2(248.65,63.26)
  BOTTOM w0.102: v2(248.65,63.26) 249.08,62.83 249.08,62.46 248.73,62.1 248.73,57.6 251.7,54.63 251.7,53.19 253.33,51.55 253.33,48.56 253.88,48.01 253.88,42.85 253.65,42.62 253.65,40.46 v1(253.21,40.02) 252.16,38.96 252.16,37.31 252.6,36.87 254.34,36.87 254.42,36.94 257.29,36.94 258.47,35.76 259.27,35.76 v2(259.69,36.18)
BCM5882_ALERT#: length 78.8
  TOP w0.102: UE1.B62 v2(258.49,66.51) ; v1(254.19,11.47) 253.83,11.11 253.83,11.06 ; 253.83,11.06 253.67,10.9 JUSH1.14 ; 253.83,11.06 v2(253.83,11.04)
  IN1 w0.089: v2(258.49,66.51) 260.11,64.9 260.11,60.58 263.23,57.45 263.23,56.53 265.14,54.62 265.14,51.97 268.95,48.16 274.33,48.16 275.62,46.88 275.62,45.72 275.08,45.19 273.16,45.19 272.69,44.72 272.69,43.85 270.92,42.08 270.92,38.36 268.69,36.13 268.69,31.75 264.69,27.75 264.69,27.52 257.54,20.37 257.54,14.2 256.41,13.07 256.41,12.92 254.53,11.04 v2(253.83,11.04)
BEEP: length 234.5
  TOP w0.102: UE2.B19 254.69,45.96 255.13,46.4 v2(255.34,46.4) ; RA13.2 42.04,22.02 v2(42.35,22.33) 42.61,22.33 v1(43.11,22.83)
  IN2 w0.122: v2(255.34,46.4) 254.42,47.33 240.07,47.33 236.73,43.98 236.73,36.87 232.56,32.7 230.63,32.7 229.92,32 81.8,32 79.44,29.63 78.29,29.63 77.53,28.87 73.34,28.87 72.07,30.14 69.02,30.14 68.26,30.9 68.26,31.47 67.5,32.23 63.04,32.23 62.66,31.85 62.66,31.39 57.46,26.2 50.86,26.2 49.29,24.63 44.21,24.63 42.35,22.77 v2(42.35,22.33)
BIA_PWM: length 3.9
  TOP w0.102: v1(114.03,86.13) 114.11,86.21 LV1.2 115.33,86.19 RV1.1 117.15,85.75 DV1.1
BIA_PWM_EC: length 209.4
  TOP w0.102: DV1.2 116.5,82.84 115.83,82.17 v1(115.4,82.17) 115.4,81.97 v2(114.15,80.71) ; UE2.B25 255.28,42.96 v2(255.33,43.01)
  IN2 w0.122: v2(114.15,80.71) 114.15,80.97 115.28,82.1 121.05,82.1 123.57,84.62 123.57,86.65 126.3,89.38 146.24,89.38 147.51,90.65 156.13,90.65 157.21,91.73 182.59,91.73 183.41,90.91 203.77,90.91 204.49,91.63 219.63,91.63 222.02,94.02 233.86,94.02 239.32,88.56 239.32,85.52 241.2,83.65 241.2,80.4 245.42,76.17 254.82,76.17 255.71,75.29 258.95,75.29 263.41,70.83 263.41,65.11 263.71,64.81 263.71,55.99 264.97,54.73 264.97,51.71 260.36,47.11 260.36,45.31 259.8,44.75 258.84,44.75 257.24,43.15 256.79,43.15 256.22,42.58 255.75,42.58 v2(255.33,43.01)
BLUE_DOCK: length 87.5
  TOP w0.102: v2(213.75,82.66) 213.75,82.32 213.85,82.22 RV78.1 213.27,81.26 213.27,79.76 210.7,77.19 UV8.M8
  BOTTOM w0.102: JDOCK1.45 143.95,95.85 144.19,95.61 144.19,95.39 149.26,90.32 157.83,90.32 159.42,91.91 165.14,91.91 165.67,91.38 182.04,91.38 183.02,90.4 192.72,90.4 194.43,88.68 v1(200.28,88.68) 211.57,88.68 213.43,86.83 213.43,82.98 v2(213.75,82.66)
BOARD_ID: length 13.3
  TOP w0.102: v2(258.02,45.63) 258.11,45.63 258.44,45.95 UE2.B10 ; v2(258.83,53.91) 259.2,53.54 259.2,52.75 RE79.2 CE40.1
  BOTTOM w0.102: v2(258.02,45.63) 258.04,45.63 258.44,46.03 258.44,46.67 258.25,46.85 v1(258.25,47.65) 258.25,53.33 v2(258.83,53.91)
BOOT_1.35V:
  vias: v1(67.4,13.18)
BOOT_1.35V_C: length 1.4
  BOTTOM w0.102: v1(68.59,15.52) 68.45,15.66 PR200.1
BQ24770_REGN: length 13.1
  TOP w0.508: v2(75.99,82.53) 75.01,82.53 74.58,82.1 v1(74.58,81.67) 74.58,81.37 75.22,80.73 75.22,78.12 76.12,77.22 v2(77.72,77.22)
  BOTTOM w0.203: v2(75.99,82.53) 76.45,82.53 76.62,82.7 77.05,82.7 77.11,82.76 PU700.24
  BOTTOM w0.508: PR725.1 PR713.1 78,77.49 v2(77.72,77.22) 77.52,77.22 77.12,77.61 PR799.2
BREATH_LED#: length 230.1
  TOP w0.102: v2(262.81,41) 263.25,41 263.29,40.96 UE2.B57 ; QZ7.4 286.24,82.42 286.23,82.4 RZ34.1 v2(285.62,83.04) 285.62,83.45 v1(285.86,83.69)
  IN1 w0.089: v2(285.62,83.04) 285.62,81.96 284.79,81.13 284.79,80.21 282.67,78.09 282.67,70.52 280.53,68.37 272.84,68.37 269.86,65.39 269.86,59.93 272.43,57.36 272.43,53.3 274.51,51.22 274.51,51.22 275.14,50.58 v2(275.52,50.58)
  IN3 w0.122: v2(285.62,83.04) 283.71,81.13 282.49,81.13 275.38,74.02 270.53,74.02 269.14,75.41 255.77,75.41 254.63,74.27 249.51,74.27 247.73,76.05 246.5,76.05 240.73,81.83 240.73,84.18 239.2,85.7 239.2,88.63 233.07,94.77 201.39,94.77 199.18,92.56 184.97,92.56 183.07,94.46 183.07,95.99 182.58,96.48 182.58,99.05 182.23,99.39 182.23,100.24 180.25,102.23 180.25,104.62 176.7,108.17 160.09,108.17 158.89,106.96 v2(158.88,106.96)
  IN4 w0.089: v2(275.52,50.58) 275.52,41.22 274.08,39.78 272.83,39.78 272.37,39.32 268.92,39.32 268.13,40.11 264.28,40.11 263.39,41 v2(262.81,41)
  BOTTOM w0.102: v2(158.88,106.96) 158.95,106.89 JDOCK1.98
BREATH_LED#_Q: length 2.3
  TOP w0.102: QZ7.3 289.57,82.42 RZ32.1 v1(289.61,83.68)
BREATH_WHITE_LED#: length 99.5
  TOP w0.102: v2(270.32,58.2) 270.19,58.08 270.19,54.89 272.94,52.13 272.94,48.61 272.75,48.42 272.75,45.36 274.97,43.14 274.97,40.62 274.53,40.18 274.53,35.19 273.17,33.83 273.17,33.21 273.36,33.02 273.36,31.1 272.79,30.53 272.79,28.68 272.24,28.12 272.24,27.47 272.53,27.18 273.43,27.18 274.28,26.33 274.97,26.33 276.01,25.29 276.01,22.17 277.77,20.41 v1(277.77,20.09) 277.77,18.5 272.3,13.03 272.3,10.97 271.71,10.39 267.08,10.39 266.65,10.82 JLED1.2 ; RZ34.2 v2(284.71,83.12)
  IN1 w0.089: v2(270.32,58.2) 270.32,59.03 269.64,59.7 269.64,65.48 272.75,68.59 280.44,68.59 282.46,70.61 282.46,78.19 284.58,80.31 284.58,82.99 v2(284.71,83.12)
BREATH_WHITE_LED_SNIFF#: length 8.1
  TOP w0.102: LED3.1 v1(294.04,87.55) 293.82,87.55 290.52,84.25 RZ32.2
BST_3V:
  vias: v1(220.94,50.11)
BST_3V_C: length 1.5
  TOP w0.102: PR110.1 v1(223.38,52.07)
BST_5V: length 1.6
  TOP w0.102: v1(215.3,51.99) 215.3,51.79 214.74,51.23 PR109.1
BST_5V_C: length 1.6
  TOP w0.102: v1(213.8,51.99) 213.34,51.54 PR109.2
BST_+V1.05SP: length 5.1
  TOP w0.102: PC302.1 205.15,62.6 204.59,63.16 204.59,65.11 v1(204.95,65.47)
  TOP w0.508: v2(205.98,62.78) 205.8,62.59 PC302.1
  BOTTOM w0.254: v2(205.98,62.78) 205.8,62.59 205.77,62.59 205.43,62.26 PU300.6
BST_+V1.05SP_C: length 2.7
  TOP w0.102: PC302.2 203.76,63.92 v1(203.64,64.03)
  TOP w0.508: PC302.2 PR312.1
BT_LED#: length 11.6
  TOP w0.102: v2(244.97,34.72) RZ15.1 244.34,35.09 244.97,35.71 v1(244.97,37.08) 244.35,37.7 QZ2.4
  BOTTOM w0.102: v2(244.97,34.72) 244.97,33.84 241.81,30.67 241.81,30.26 241.64,30.1 JNGFF1.8
BT_RADIO_DIS#: length 59.6
  TOP w0.102: RE11.2 253.3,72.09 v2(252.87,71.66) 252.62,71.41 UE1.A13 ; v2(243.09,68.03) 243.77,67.35 243.77,61.66 246.29,59.14 246.29,52.02 245.15,50.88 245.15,46.27 245.44,45.98 245.44,39.93 244.03,38.52 242.44,38.52 241.49,37.57 241.49,36.49 239.84,34.84 239.84,34.2 239.18,33.54 239.18,31.5 v1(240.21,30.47) 241.36,29.31 DZ2.1
  IN4 w0.089: v2(243.09,68.03) 243.8,68.74 243.8,69.86 245.02,71.08 250.49,71.08 251.07,71.66 v2(252.87,71.66)
BT_RADIO_DIS#_R: length 13.6
  TOP w0.102: DZ2.2 242.76,28.98 243.68,28.06 v2(244.22,28.06) 244.34,28.06 244.54,27.86 v1(244.54,26.9)
  BOTTOM w0.102: JNGFF1.46 242.23,20.6 243.19,21.56 243.19,22.25 243.77,22.83 243.77,25.17 243.29,25.65 243.29,27.69 243.66,28.06 v2(244.22,28.06)
CAM_MIC_CBL_DET#: length 121.8
  TOP w0.102: RPC16.8 182.77,67.55 182.7,67.47 182.7,67.21 v2(182.94,66.97) ; v2(110.42,78.27) v1(110.42,77.69)
  IN1 w0.089: v2(182.94,66.97) 182.94,67.28 182.24,67.98 174.62,67.98 173.91,68.69 170.78,68.69 v2(169.07,70.4)
  IN3 w0.081: v2(169.07,70.4) 169.07,70.77 169.91,71.61 169.91,75.81 169.45,76.26
  IN3 w0.122: 169.45,76.26 169.16,76.56 169.16,77.32 164.08,82.4 164.08,87.26 165.72,88.9 165.72,93.55 164.64,94.64 163.73,94.64 163.38,94.99 160.01,94.99 159.66,94.64 158.9,94.64 149.79,85.53 127.4,85.53 123.95,82.08 114.93,82.08 111.12,78.27 v2(110.42,78.27)
  BOTTOM w0.076: UC1.F4 168.83,70.17 v2(169.07,70.4)
  BOTTOM w0.102: JEDP1.14 105.46,88.64 106.23,87.86 106.23,86.14 107.12,85.25 108.52,85.25 109.66,84.11 109.66,79.03 v2(110.42,78.27)
CD3301_DCIN: length 5.4
  TOP w0.102: PR835.2 82.08,39.24 v1(83.27,38.05)
  TOP w0.254: PR835.2 81.88,39.73 PC813.1 80.85,39.7 PU800.1
CD3301_SDC_IN: length 2.3
  TOP w0.254: PR847.2 77.77,39.38 78.35,38.8 PU800.6
CD_PBATT_OFF: length 3.6
  TOP w0.102: PR843.1 80.97,29.9 81.54,30.48 82.15,30.48 v1(82.28,30.35)
  TOP w0.254: PU800.27 80.85,30 PR843.1
CFG0: length 91
  TOP w0.102: v2(93.47,42.14) v1(93.47,42.75) 93.47,43.73 92.39,44.81 92.39,45.63 93.47,46.71 93.47,53.63 92.54,54.56 90.46,54.56 89.67,55.34 89.67,56.72 88.92,57.47 88.92,60.52 88.33,61.11 87.62,61.11 87.04,61.7 82.55,61.7 79.55,58.7 JXDP1.9
  IN3 w0.122: v2(93.47,42.14) 116.33,42.14 121.54,47.35 124.58,47.35 132.01,54.77 132.01,59.03 131.05,59.99 v2(131.05,60.35)
  BOTTOM w0.076: UC1.AC60 133.74,60.68 133.41,60.68 133.34,60.75 133.33,60.75 133.29,60.79 132.52,60.79 132.36,60.63 131.89,60.63 131.78,60.74 131.44,60.74 v2(131.05,60.35)
  BOTTOM w0.102: RC183.1 128.48,60.79 130.31,60.79 130.75,60.35 v2(131.05,60.35)
CFG1: length 89.1
  TOP w0.102: v2(92.83,42.14) 92.83,43.6 v1(92.56,43.88) 92.14,44.3 92.14,45.76 93.22,46.84 93.22,53.5 92.39,54.33 90.36,54.33 89.44,55.25 89.44,56.63 88.69,57.38 88.69,59.68 86.91,61.47 82.7,61.47 79.43,58.2 JXDP1.11
  IN3 w0.122: v2(92.83,42.14) 93.28,42.58 116.39,42.58 121.41,47.6 124.41,47.6 127.12,50.31 127.12,56.04 126.67,56.49 126.67,59.2 128.81,61.34 v2(129.16,61.34)
  BOTTOM w0.076: 129.42,61.09 129.53,60.97 130.38,60.97 130.54,60.81 131.08,60.81 131.19,60.92 131.9,60.92 132.02,60.79 132.28,60.79 132.57,61.08 UC1.AC62
  BOTTOM w0.102: RC184.1 128.74,61.77 v2(129.16,61.34) 129.42,61.09
CFG2: length 75.6
  TOP w0.102: v2(82.16,49.76) 82.16,52.17 81.68,52.65 81.68,56.53 81.01,57.2 JXDP1.15
  IN1 w0.089: v2(130.34,61.47) 130.02,61.79 127.98,61.79 125.79,59.6 125.79,58.76 124.01,56.98 120.59,56.98 117.93,54.33 117.93,47.15 115.88,45.1 94.06,45.1 92.26,46.9 91.25,46.9 90.99,46.65 87.31,46.65 86.48,47.47 84.45,47.47 v2(82.16,49.76)
  BOTTOM w0.076: v2(130.34,61.47) 130.73,61.08 UC1.AC63
  BOTTOM w0.102: v2(82.16,49.76) v1(82.16,48.94)
CFG3: length 84
  TOP w0.102: RC305.1 88.41,41.43 88.54,41.3 v1(88.63,41.3) 88.71,41.3 89,41.59 89,42.54 v2(88.58,42.96) 88.58,43.22 87.31,44.49 87.31,45.14 RC113.2 86.62,44.81 85.53,44.81 84.54,45.8 82.83,45.8 82.34,46.3 82.34,48.89 81.75,49.47 81.75,52.26 81.46,52.55 81.46,56.15 80.9,56.7 JXDP1.17
  IN3 w0.122: v2(88.58,42.96) 90.29,42.96 90.74,42.52 92.2,42.52 92.79,43.11 116.16,43.11 121.16,48.11 124.22,48.11 126.62,50.5 126.62,55.84 126.18,56.28 126.18,59.49 128.84,62.15 129.53,62.15 129.78,62.4 v2(129.78,62.61)
  BOTTOM w0.076: v2(129.78,62.61) 130.29,62.1 130.98,62.1 131.08,62.01 131.38,61.7 132.03,61.7 UC1.AA63
CFG3_R: length 4.8
  TOP w0.102: JXDP1.60 84.96,46.2 85.85,45.31 RC113.1 86.34,45.31 86.89,45.86 87.88,45.86 v1(88.05,45.69)
CFG4: length 82.6
  TOP w0.102: JXDP1.27 79.38,54.2 79.46,54.11 79.92,54.11 v2(80.32,54.52) ; v2(90.61,41.25) v1(92.92,41.25) 93.66,41.25 94.29,41.88 94.29,44.11 95.12,44.93 121.73,44.93 122.25,45.45 RC191.1 122.25,46.42 v2(121.76,46.91)
  IN3 w0.122: v2(121.76,46.91) 121.84,46.98 124.67,46.98 132.59,54.9 132.59,60.23 v2(133.81,61.46)
  BOTTOM w0.081: UC1.AA60 134.11,61.76 v2(133.81,61.46)
  BOTTOM w0.102: v2(80.32,54.52) 80.83,54.01 80.83,43.15 82.74,41.25 v2(90.61,41.25)
CFG5: length 80.8
  TOP w0.102: JXDP1.29 80.11,53.7 80.97,52.85 80.97,52.27 81.3,51.94 81.3,49.28 81.88,48.7 81.88,46.11 82.64,45.34 84.32,45.34 85.24,44.42 86.84,44.42 v1(86.94,44.33) 87.31,43.95 v2(87.31,43.85)
  IN3 w0.122: v2(130.96,62.65) 130.96,63.33 131.32,63.69 131.32,64.96 130.62,65.66 128.78,65.66 127.99,64.87 127.99,63.41 124.68,60.11 124.68,56.81 123.66,55.78 121.08,55.78 119.12,53.82 119.12,48.36 115.37,44.61 89.86,44.61 89.11,43.85 v2(87.31,43.85)
  BOTTOM w0.076: v2(130.96,62.65) 130.96,62.6 131.22,62.34 131.22,62.34 131.44,62.12 131.79,62.12 131.96,62.29 132.27,62.29 132.57,62.58 UC1.Y62
CFG6: length 78.3
  TOP w0.102: JXDP1.33 79.61,52.7 79.88,52.43 80.17,52.43 81.07,51.53 81.07,49.19 81.65,48.61 81.65,46.01 82.55,45.12 84.22,45.12 85.4,43.94 v1(85.58,43.94) 86.2,43.94 86.73,43.41 87.5,43.41 v2(88.58,42.33)
  IN3 w0.122: v2(133.12,62.95) 134.24,61.83 134.24,61 133.66,60.43 133.66,55.09 132.2,53.63 132.2,52.49 121.43,41.72 89.19,41.72 v2(88.58,42.33)
  BOTTOM w0.081: UC1.Y61 133.46,62.64 133.15,62.95 v2(133.12,62.95)
CFG7: length 77.8
  TOP w0.102: v2(87.32,42.96) v1(86.73,42.96) 86.02,42.96 84.1,44.89 82.45,44.89 81.42,45.92 81.42,48.51 80.84,49.09 80.84,51.4 80.04,52.2 JXDP1.35
  IN3 w0.122: v2(87.32,42.96) 87.77,43.41 90.29,43.41 90.61,43.09 91.5,43.09 92.02,43.61 115.9,43.61 120.9,48.62 124.02,48.62 126.11,50.7 126.11,55.65 125.68,56.08 125.68,59.7 129.02,63.04 129.96,63.04 v2(130.36,62.64)
  BOTTOM w0.076: v2(130.36,62.64) 130.72,62.28 131.04,62.28 131.15,62.17 131.37,61.95 131.86,61.95 132.02,62.11 132.34,62.11 132.51,62.29 133.3,62.29 133.33,62.25 133.81,62.25 UC1.Y60
CFG8: length 77.6
  TOP w0.102: v1(91.78,42.57) 91.31,43.04 v2(91.31,43.92) 91.06,44.17 91.06,47.73 90.8,47.98 90.8,52.92 86.52,57.2 86.52,58.34 86.17,58.7 JXDP1.10
  IN3 w0.122: v2(129.03,63.76) 129.03,63.76 125.18,59.91 125.18,55.83 125.6,55.41 125.6,50.96 123.76,49.12 120.65,49.12 115.63,44.11 91.5,44.11 v2(91.31,43.92)
  BOTTOM w0.076: 129.42,63.37 129.68,63.11 131.09,63.11 131.35,62.85 132.02,62.85 132.03,62.87 132.35,62.87 UC1.V62
  BOTTOM w0.102: 129.42,63.37 v2(129.03,63.76) 128.82,63.55 RC190.1
CFG9: length 78.1
  TOP w0.102: JXDP1.12 85.87,58.2 v1(86.17,57.9) 86.17,57.23 90.55,52.85 90.55,47.85 90.8,47.6 v2(90.8,43.54)
  IN3 w0.122: v2(129.62,63.87) 129.62,63.63 129.33,63.34 128.97,63.34 125.43,59.8 125.43,55.96 125.85,55.54 125.85,50.84 123.89,48.87 120.77,48.87 115.77,43.86 91.89,43.86 91.5,43.47 90.87,43.47 v2(90.8,43.54)
  BOTTOM w0.076: UC1.V61 133.2,63.62 132.68,63.62 132.48,63.42 132.48,63.24 132.29,63.05 131.8,63.05 131.77,63.02 131.42,63.02 131.09,63.35 130.14,63.35 v2(129.62,63.87)
  BOTTOM w0.081: 129.47,64.01 v2(129.62,63.87)
  BOTTOM w0.102: 129.47,64.01 129.05,64.43 RC189.1
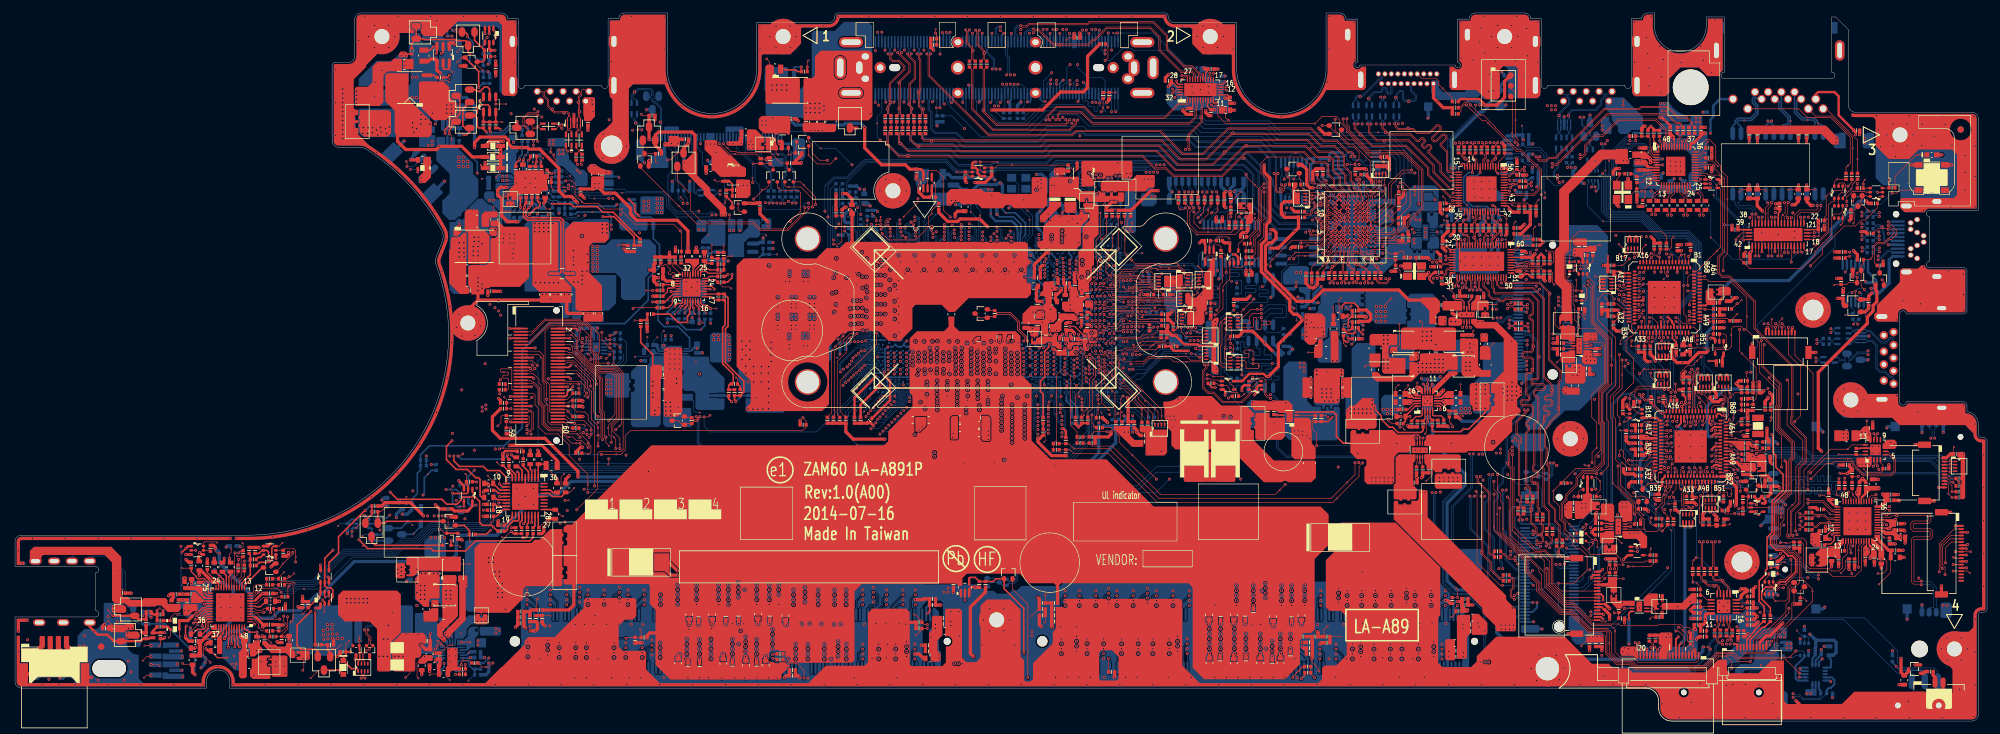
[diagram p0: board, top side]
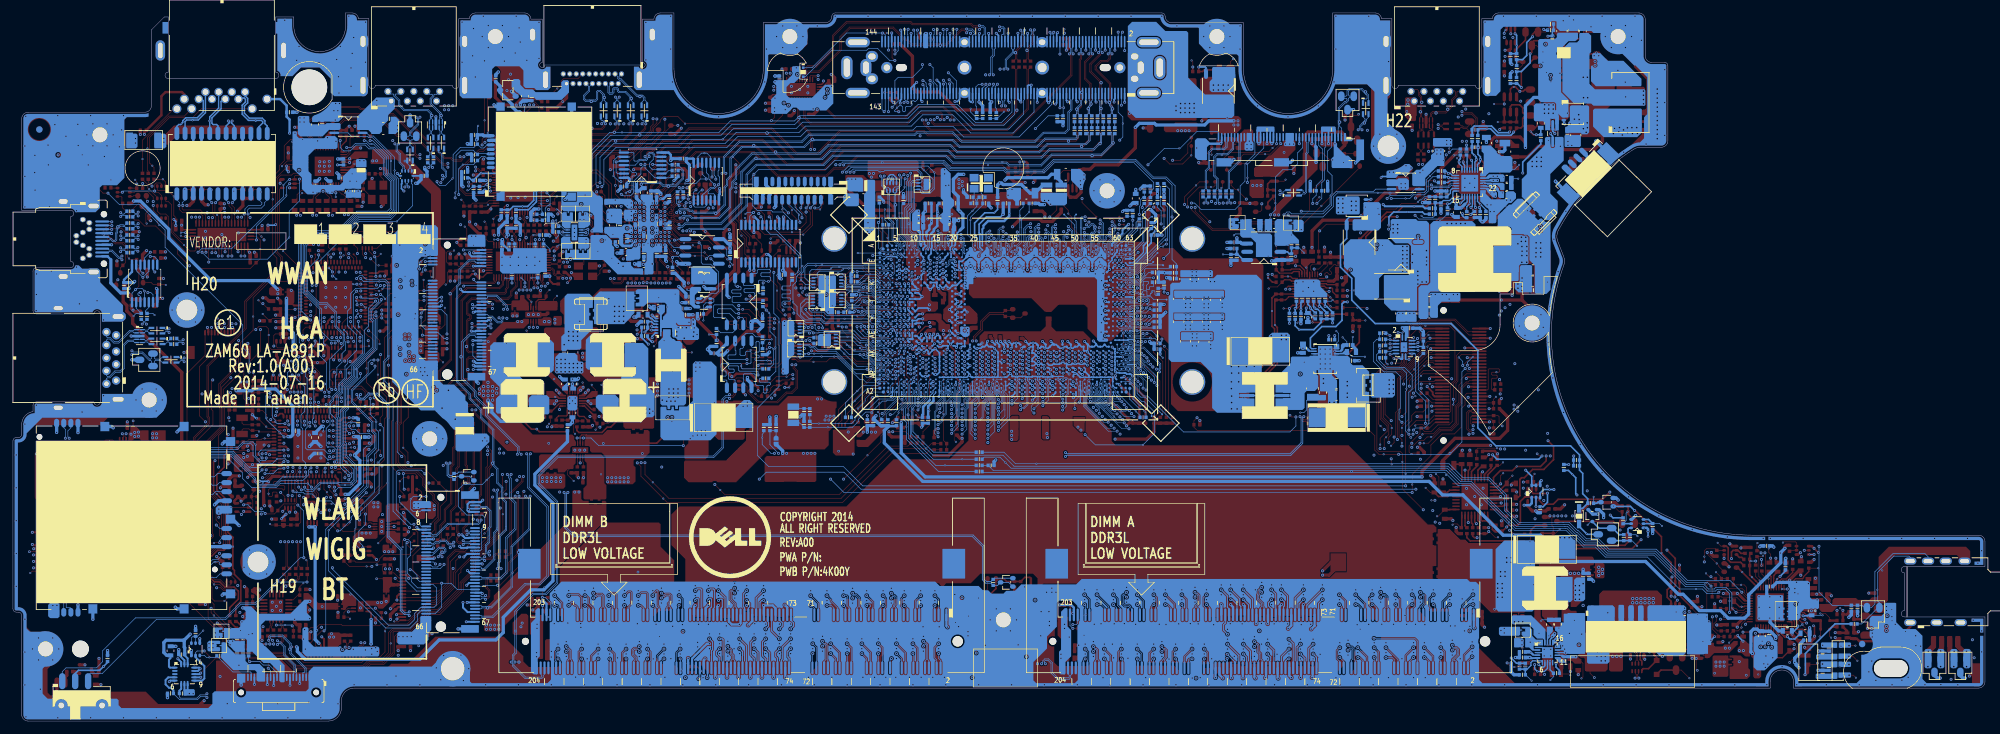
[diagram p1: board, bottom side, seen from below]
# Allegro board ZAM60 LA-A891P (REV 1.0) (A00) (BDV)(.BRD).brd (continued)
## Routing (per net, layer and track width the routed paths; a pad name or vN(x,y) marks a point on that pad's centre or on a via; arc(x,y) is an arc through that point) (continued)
CFG10: length 80
  TOP w0.102: JXDP1.16 85.33,57.2 85.53,57 86.08,57 90.29,52.78 90.29,47.73 90.55,47.47 90.55,43.98 90.1,43.54 v1(90.1,43.03) v2(90.1,42.52)
  IN3 w0.081: v2(129.71,61.39) 129.71,61.64 129.59,61.77 129.42,61.77
  IN3 w0.122: v2(90.1,42.52) 90.35,42.27 92.33,42.27 92.9,42.84 116.27,42.84 121.28,47.85 124.32,47.85 126.87,50.41 126.87,55.94 126.43,56.38 126.43,59.35 128.85,61.77 129.42,61.77
  IN4 w0.089: v2(129.71,61.39) 130.43,62.1 133.1,62.1 133.72,62.73 v2(133.72,62.94)
  BOTTOM w0.081: v2(133.72,62.94) 133.72,62.98 134.11,63.36 UC1.V60 ; 129.47,61.63 v2(129.71,61.39)
  BOTTOM w0.102: 129.47,61.63 128.44,62.66 RC188.1
CFG11: length 73.8
  TOP w0.102: JXDP1.18 85.88,56.7 v1(88.21,54.37) 89.85,52.73 v2(89.85,52.11)
  IN4 w0.089: v2(130.22,63.88) 129.74,64.36 129.21,64.36 128.89,64.69 128.89,66.09 127.44,67.54 126.3,67.54 123.84,70 119.95,70 118.14,71.81 116.3,71.81 114.38,73.72 100.81,73.72 97.63,70.54 97.63,62.53 95.63,60.53 95.63,57.11 92.4,53.89 91.31,53.89 89.85,52.43 v2(89.85,52.11)
  BOTTOM w0.076: v2(130.22,63.88) 130.59,63.51 131.12,63.51 131.42,63.81 131.78,63.81 131.97,63.62 132.35,63.62 132.51,63.79 133.3,63.79 133.37,63.71 133.78,63.71 UC1.U60
CFG12: length 70.9
  TOP w0.102: v2(90.1,44.17) v1(90.1,45.34) 90.1,45.63 89.06,46.67 89.06,51.05 88.45,51.66 88.45,52.56 86.82,54.2 JXDP1.28
  IN3 w0.122: v2(130.67,65.02) 130.14,64.49 128.48,64.49 128.24,64.24 128.24,63.31 124.93,60.01 124.93,56.7 123.76,55.53 121.19,55.53 119.38,53.72 119.38,48.23 115.5,44.36 90.29,44.36 v2(90.1,44.17)
  BOTTOM w0.081: UC1.T63 132.03,64.71 130.99,64.71 v2(130.67,65.02)
CFG13: length 74.4
  TOP w0.102: JXDP1.30 86.85,53.7 v1(87.16,53.39) 88.2,52.35 88.2,51.54 88.73,51 88.73,50.29 v2(88.52,50.08)
  IN4 w0.089: v2(130.11,65.02) 130.11,64.85 129.88,64.62 129.3,64.62 129.12,64.8 129.12,66.18 127.51,67.79 126.36,67.79 123.94,70.21 120.12,70.21 118.31,72.02 116.38,72.02 114.47,73.94 100.72,73.94 97.41,70.63 97.41,62.62 95.41,60.62 95.41,57.21 92.34,54.14 91.18,54.14 89.41,52.36 89.41,50.96 v2(88.52,50.08)
  BOTTOM w0.076: UC1.T62 132.5,64.52 130.62,64.52 v2(130.11,65.02)
CFG14: length 74.4
  TOP w0.102: v1(88.02,50.24) 88.33,50.55 v2(88.33,50.71) 87.94,51.09 87.94,51.92 87.35,52.52 85.15,52.52 84.97,52.7 JXDP1.34
  IN4 w0.089: v2(88.33,50.71) 88.52,50.9 88.52,52.23 90.93,54.65 92.24,54.65 94.98,57.39 94.98,60.8 96.98,62.8 96.98,70.81 100.54,74.37 114.65,74.37 116.56,72.45 118.56,72.45 120.37,70.64 125.05,70.64 125.79,69.9 126.92,69.9 127.82,69 127.82,68.12 129.81,66.14 130.17,66.14 131.37,64.93 133.14,64.93 133.18,64.9 133.56,64.9 133.8,64.66 v2(133.8,64.45)
  BOTTOM w0.081: v2(133.8,64.45) 133.8,64.52 UC1.T61
CFG15: length 71.8
  TOP w0.102: JXDP1.36 85.32,52.2 85.38,52.15 v1(85.81,52.15) 87.08,52.15 v2(87.12,52.11)
  IN4 w0.089: v2(87.12,52.11) 88.01,52.11 90.8,54.9 92.18,54.9 94.76,57.48 94.76,60.89 96.76,62.89 96.76,70.9 100.45,74.59 114.74,74.59 116.65,72.67 118.66,72.67 120.47,70.86 125.24,70.86 125.97,70.13 127.01,70.13 128.08,69.06 128.08,68.3 129.85,66.52 130.74,66.52 131.32,65.95 132.62,65.95 133.42,65.15 133.73,65.15 v2(134.43,64.45)
  BOTTOM w0.081: UC1.T60 134.43,64.54 v2(134.43,64.45)
CFG16: length 73.2
  TOP w0.102: v2(91.75,46.46) 92.71,47.41 92.71,53.25 92.14,53.82 90.22,53.82 86.75,57.3 86.75,58.95 v1(86.01,59.7) JXDP1.6
  IN1 w0.089: v2(91.75,46.46) 92.39,46.46 93.98,44.87 115.95,44.87 118.15,47.06 118.15,54.24 120.68,56.77 124.18,56.77 126.01,58.6 126.01,59.51 127.44,60.94 130.41,60.94 130.88,61.41 v2(130.88,61.46)
  BOTTOM w0.076: v2(130.88,61.46) 130.97,61.37 132.35,61.37 132.75,61.77 132.75,61.77 UC1.AA62
CFG17: length 80.1
  TOP w0.102: JXDP1.4 86.01,60.2 86.98,59.23 86.98,57.39 90.29,54.08 92.26,54.08 92.96,53.38 92.96,46.96 91.68,45.68 v1(91.68,45.31) 91.68,44.35 92.14,43.89 v2(92.14,43.09)
  IN3 w0.122: v2(92.14,43.09) 92.41,43.36 116.03,43.36 121.03,48.36 124.12,48.36 126.36,50.6 126.36,55.74 125.93,56.18 125.93,59.6 128.9,62.57 v2(129.14,62.57)
  BOTTOM w0.076: UC1.AA61 133.18,61.87 132.93,62.12 132.68,62.12 132.51,61.95 132.51,61.78 132.28,61.54 131.31,61.54 131.01,61.84 129.87,61.84 129.42,62.29
  BOTTOM w0.102: 129.42,62.29 v2(129.14,62.57)
CFG18: length 71.4
  TOP w0.102: v2(88.96,51.79) 88.96,52.6 v1(86.64,54.93) 86.09,55.47 85.34,55.47 85.07,55.2 JXDP1.24
  IN4 w0.089: v2(88.96,51.79) 88.96,52.3 91.06,54.39 92.29,54.39 95.2,57.3 95.2,60.71 97.2,62.71 97.2,70.72 100.63,74.16 114.56,74.16 116.47,72.24 118.44,72.24 120.25,70.43 124.04,70.43 126.43,68.05 127.57,68.05 129.55,66.06 v2(129.55,65.02)
  BOTTOM w0.076: UC1.U63 131.95,64.29 130.29,64.29 v2(129.55,65.02)
CFG19: length 68.8
  TOP w0.102: v2(90.1,47.09) 89.41,47.79 v1(89.41,51.38) 89.41,52.63 86.33,55.7 JXDP1.22
  IN1 w0.089: v2(90.1,47.09) 90.17,47.15 92.33,47.15 94.16,45.32 115.79,45.32 117.72,47.24 117.72,54.42 120.5,57.2 123.92,57.2 125.57,58.85 125.57,59.69 129.13,63.25 130.3,63.25 v2(130.93,63.88)
  BOTTOM w0.076: v2(130.93,63.88) 131.08,64.03 131.79,64.03 132.03,63.79 132.28,63.79 132.57,64.08 UC1.U62
CFG_RCOMP: length 11.9
  IN3 w0.381: v2(127.48,56.76) 128.53,57.82 128.53,59.74 129.4,60.6 130.21,60.6 130.52,60.91 131.25,60.91 131.66,61.32 131.66,61.75 132.13,62.22 132.13,62.97 131.69,63.41 v2(131.58,63.41)
  BOTTOM w0.102: v1(127.06,56.18) 127.48,56.6 v2(127.48,56.76)
  BOTTOM w0.178: UC1.V63 131.66,63.33 131.58,63.41 v2(131.58,63.41)
  BOTTOM w0.381: RC185.1 v2(127.48,56.76)
CHAGER_SRC:
  vias: v1(67.61,67.88) v4(68.65,73.95) v4(68.64,72.47) v4(68.66,71.78) v4(68.68,73.13) v4(69.36,73.96) v4(69.38,73.13) v4(69.38,72.43) v4(69.4,71.78)
CHARGER_CELL_PIN: length 5.8
  TOP w0.254: PR729.1 80.77,80.43 v2(81.09,80.11) 81.09,79.6 v1(80.82,79.34) 80.49,79.34 v2(79.47,78.32)
  BOTTOM w0.203: PU700.16 80.43,80.64 80.96,80.11 v2(81.09,80.11)
  BOTTOM w0.254: PR725.2 79,78.79 v2(79.47,78.32)
CHARGER_SMBCLK: length 247.5
  TOP w0.102: v2(262.3,38.56) 262.44,38.43 UE2.B50 ; v2(85.56,82.32) 85.34,82.54 PT2.1 ; v2(261.59,34.86) 261.73,34.72 RPE6.3
  IN1 w0.089: v2(261.59,34.86) 261.83,35.1 261.83,35.38 262.09,35.63 262.09,38.08 262.3,38.3 v2(262.3,38.56) 262.9,38.56 263.28,38.94 263.28,45.99 262.42,46.85 262.42,50.66 262.77,51.01 262.77,52.69 261.99,53.46 261.99,53.73 260.86,54.86 252.22,54.86 245.63,61.45 245.63,63.42 245.34,63.71 245.34,69.44 245.92,70.03 245.92,86.79 243.25,89.45 239.7,89.45 236.28,92.87 221.68,92.87 220.81,93.74 202.91,93.74 200.46,91.3 189.08,91.3 187.94,92.44 174.13,92.44 169.62,96.95 161.85,96.95 159.91,95.02 155.22,95.02 153.43,96.81 149.02,96.81 141.05,88.84 131.46,88.84 126.64,84.02 98.13,84.02 95.64,81.53 87.23,81.53 86.27,82.5 85.74,82.5 v2(85.56,82.32)
  BOTTOM w0.102: PU700.12 82.03,82.76 82.12,82.84 82.48,82.84 82.83,82.49 85.38,82.49 v2(85.56,82.32)
CHARGER_SMBDAT: length 248.8
  TOP w0.102: PT1.1 85.81,82.65 v2(85.56,82.9) ; UE2.A47 262.19,34.96 v2(262.24,34.91) 262.23,34.9 RPE6.2
  IN1 w0.089: v2(262.24,34.91) 262.05,35.1 262.05,35.29 262.3,35.54 262.3,37.99 262.65,38.34 262.99,38.34 263.5,38.85 263.5,46.08 262.63,46.94 262.63,50.57 262.98,50.92 262.98,52.78 262.2,53.55 262.2,53.82 260.95,55.07 252.31,55.07 245.84,61.54 245.84,63.51 245.55,63.8 245.55,69.35 246.14,69.94 246.14,86.88 243.34,89.67 239.79,89.67 236.37,93.09 221.77,93.09 220.9,93.95 202.82,93.95 200.38,91.51 189.17,91.51 188.03,92.65 174.22,92.65 169.71,97.16 161.76,97.16 159.83,95.23 155.31,95.23 153.52,97.03 148.93,97.03 140.96,89.06 131.37,89.06 126.55,84.24 98.04,84.24 95.55,81.75 87.32,81.75 86.36,82.72 85.74,82.72 v2(85.56,82.9)
  BOTTOM w0.102: v2(85.56,82.9) 85.38,82.72 82.92,82.72 82.57,83.07 82.12,83.07 82.03,83.16 PU700.11
CHG_BTS:
  vias: v1(76.11,83.06)
CHG_BTS_C: length 1.1
  BOTTOM w0.102: PC712.1 v1(72.13,83.87)
CHG_LGATE: length 4.3
  IN4 w1.016: 73.9,76.8 73.9,78.87 75.47,80.45
  vias: v1(76.38,81.66) v2(75.65,81.17) v2(75.87,81.8) v4(73.53,76.03) v4(74.2,76.03)
CHG_SNUB: length 0.9
  TOP w0.102: 73.94,78.63 v1(73.94,79.54)
CHG_SW: length 10.7
  IN4 w1.016: 71.38,75.51 71.42,75.55 71.42,82.47 73,84.06 74.53,84.06
  vias: v1(70.7,78.92) v2(75.36,84.25) v2(75.99,84.25) v4(70.8,73.38) v4(70.8,72.68) v4(70.8,71.98) v4(70.81,70.94) v4(70.97,74.82) v4(70.99,74.18) v4(71.56,73.38) v4(71.54,72.66) v4(71.56,71.98) v4(71.64,74.82) v4(71.65,74.17) v4(71.57,70.94) v4(72.18,73.81)
CHG_UGATE: length 10.2
  TOP w0.102: v4(68.65,76.48) v1(68.65,77.06)
  IN1 w1.016: 74.42,83.3 73.05,83.3 69.11,79.36 69.11,76.68
  vias: v2(75.36,83.61) v2(75.99,83.61) v4(68.67,75.82)
CLK_27M_IN: length 8.8
  TOP w0.102: UV8.K1 208.86,72.49 209.01,72.34 210.29,72.34 211.08,71.55 v1(212.2,71.55) 213.14,71.55 RV80.1 CV115.1 213.34,70.4 214.04,69.7 214.04,69.25 214.51,68.78 YV2.1
CLK_27M_OUT: length 6.5
  TOP w0.102: UV8.L1 209.8,72.93 211.65,72.93 212.32,72.26 RV80.2 213.68,72.26 214.07,72.64 v1(214.36,72.64) 214.68,72.33 RV81.2
CLK_27M_OUT_R: length 2.9
  TOP w0.102: YV2.3 216.8,70.38 216.52,70.66 CV113.1 RV81.1
CLK_BIASREF: length 11
  BOTTOM w0.102: 155.93,74.98 155.68,74.73 155.68,73.18 155.15,72.65 155.15,72.45 155.51,72.09 UC1.C26
  BOTTOM w0.254: 155.93,74.98 156.14,75.2 156.14,77.02 154.57,78.59 v1(153.1,78.59) 152.59,79.1 RC69.1
CLK_DDC2_DOCK: length 110
  TOP w0.102: UV8.L4 209.84,74.91 210.57,74.91 210.67,74.82 212.81,74.82 214.47,76.47 215.02,76.47 215.22,76.68 215.22,77.23 216.29,78.29 v1(216.29,78.41) 216.41,78.41 217.36,79.36 217.36,85.17 214.61,87.91 209.36,87.91 205.97,91.3 205.97,91.76 205.25,92.48 v2(205.25,93.1)
  IN3 w0.122: v2(144.49,106.5) 144.49,104.57 145.14,103.92 161.42,103.92 163.08,105.59 168.86,105.59 170.94,107.67 176.49,107.67 179.75,104.41 179.75,102.02 181.24,100.53 181.24,96.51 182.56,95.18 182.56,94.21 184.72,92.05 199.38,92.05 201.06,93.73 204.62,93.73 v2(205.25,93.1)
  BOTTOM w0.102: JDOCK1.48 144.45,106.1 144.32,106.24 144.32,106.33 v2(144.49,106.5)
CLK_KBD: length 186
  TOP w0.102: RPE2.3 258.24,32.68 v2(258.24,32.68) 257.54,33.38 257.54,35.19 257.9,35.55 257.9,36.41 257.69,36.62 UE2.A38
  IN1 w0.089: v2(153.25,99.93) 153.44,99.74 153.44,99.4 153.83,99.01 155.2,99.01 155.71,98.5 155.71,97.2 157.02,95.9 158.57,95.9 160.11,97.43 169.82,97.43 174.3,92.95 188.15,92.95 189.31,91.78 200.06,91.78 202.55,94.27 221.39,94.27 222.1,93.56 236.28,93.56 239.75,90.09 243.3,90.09 246.43,86.96 246.43,69.68 245.96,69.21 245.96,64.03 246.34,63.65 246.34,62.1 247.3,61.14 248.07,61.14 249.15,60.06 249.15,58.62 251.5,56.26 255.5,56.26 256.42,55.34 261.06,55.34 262.47,53.93 262.47,53.68 263.25,52.9 263.25,50.78 262.96,50.49 262.96,46.99 263.76,46.19 263.76,38.74 262.66,37.64 262.66,34.74 260.1,32.18 258.17,32.18 258.05,32.3 258.05,32.49 v2(258.24,32.68)
  BOTTOM w0.102: v2(153.25,99.93) 153.43,100.11 153.43,102.57 153.09,102.9 153.09,103.86 152.95,104 JDOCK1.78
CLK_MSE: length 172.5
  TOP w0.102: RPE2.2 258.74,32.23 258.88,32.36 258.88,32.89 v2(258.7,33.06) 258.44,33.32 258.01,33.32 257.82,33.51 257.82,35.07 258.19,35.44 UE2.A39
  IN1 w0.089: v2(151.38,95.11) 151.56,94.94 151.56,93.85 153.96,91.45 187.43,91.45 188.56,90.31 202.35,90.31 203.08,91.05 221.11,91.05 221.64,91.58 236.21,91.58 239.38,88.41 242.73,88.41 244.08,87.07 244.08,83.5 244.78,82.8 244.78,72.29 243.66,71.17 243.66,61.94 252.97,52.62 257.59,52.62 258.72,51.5 258.72,51.21 259.68,50.25 260.57,50.25 260.93,49.89 260.93,48.2 260.16,47.44 260.16,44.69 260.06,44.59 260.06,41.11 258.25,39.3 258.25,37.89 259.04,37.1 259.04,33.4 v2(258.7,33.06)
  BOTTOM w0.102: v2(151.38,95.11) 151.59,95.31 151.59,95.86 151.45,96 JDOCK1.71
CLK_PCI_DOCK: length 100.9
  TOP w0.102: v2(167.86,94.23) 168.15,94.51 v1(168.15,94.84) R273.1 ; v2(168.79,44.74) 168.79,44.75 166.81,44.75 CC15.2 RC70.2
  IN1 w0.089: v2(144.84,76.62) 146.11,77.89 146.11,91.73 150.56,96.18 152.46,96.18 154.81,93.83 167.46,93.83 v2(167.86,94.23)
  IN3 w0.122: v2(168.79,44.74) 163.76,44.74 162.75,45.76 162.75,48.87 161.92,49.69 160.08,49.69 156.33,53.44 156.33,57.7 155.44,58.59 155.44,60.75 148.52,67.67 147.83,67.67 146.87,68.62 146.87,70.33 144.65,72.55 144.65,76.43 v2(144.84,76.62)
  BOTTOM w0.102: v2(167.86,94.23) 168.41,94.23 168.5,94.31 168.5,94.44 167.78,95.15 167.44,95.15 167.25,94.96 167.25,94.35 167.13,94.23 166.96,94.23 166.84,94.35 166.84,94.89 166.68,95.05 166.03,95.05 165.8,95.28 165.8,95.48 165.86,95.54 165.86,95.76 165.69,95.92 165.54,95.92 165.41,95.8 165.28,95.8 164.95,96.13 JDOCK1.121
CLK_PCI_LPDEBUG: length 154.7
  TOP w0.102: v2(275.18,29.39) 275.18,29.39 275.18,32.11 276.45,33.38 276.45,38.79 277.85,40.19 277.85,53.76 275.06,56.55 JLPDE1.10 ; v2(196.29,36.58) v1(195.44,35.74) 194.77,35.07 177.01,35.07 169.55,42.52 166.46,42.52 166,42.98 CC14.2 RC67.2
  IN4 w0.089: v2(275.18,29.39) 274.66,29.91 272.92,29.91 271.45,28.43 265.36,28.43 261.49,24.56 243.31,24.56 240.11,27.77 238.39,27.77 235.25,30.9 233.88,30.9 233.63,30.64 231.23,30.64 231.08,30.5 202.37,30.5 v2(196.29,36.58)
CLK_PCI_MEC: length 104.7
  TOP w0.102: v2(208.26,39.93) 207.71,39.37 207.71,37.87 v1(204.25,34.42) 203.66,33.83 176.52,33.83 168.95,41.4 163.59,41.4 163.04,41.95 CC13.2 RC74.2 ; UE2.A29 252.95,40.21 251.7,38.97 RE66.1 250.7,39.6 249.53,39.6 248.87,40.26 248.87,40.47 248.54,40.8 248.54,41.8 248.41,41.92 248.03,41.92 247.93,41.82 v2(247.93,41.06)
  IN1 w0.089: v2(208.26,39.93) 214.43,39.93 215.72,38.63 218.81,38.63 219.32,39.14 234.4,39.14 236.45,41.19 238.63,41.19 239.43,40.38 242.46,40.38 243.52,41.44 247.55,41.44 v2(247.93,41.06)
CLK_PCI_SIO: length 129.4
  TOP w0.102: v2(245.11,38.26) 246.27,39.43 246.27,46.33 245.98,46.62 245.98,50.53 247.34,51.88 247.34,59.3 244.61,62.03 244.61,65.25 245.48,66.12 246.39,66.12 247.07,65.43 RE27.1 247.69,64.5 248.43,63.76 UE1.A28 ; v2(207.08,39.95) 207.08,38.13 v1(205.87,36.92) 203.4,34.46 176.75,34.46 169.1,42.11 163.61,42.11 162.82,42.9 CC12.2 RC72.2
  IN1 w0.089: v2(207.08,39.95) 207.75,39.28 214.18,39.28 215.43,38.04 219.33,38.04 219.83,38.54 234.7,38.54 236.74,40.59 238.38,40.59 239.95,39.03 244.35,39.03 v2(245.11,38.26)
CLK_PCIE_LAN: length 129.4
  TOP w0.102: v2(241.86,87.6) 242.02,87.43 242.21,87.43 242.52,87.74 242.52,89.01 244.15,90.65 245.3,90.65 247.75,93.11 253.61,93.11 255.28,91.44 255.28,90.25 255.95,89.58 255.95,89.39 256.03,89.32 UL1.44
  IN1 w0.089: v2(146.22,75.01) 146.42,74.82 146.52,74.82 146.66,74.96 146.66,76.96 149.95,80.24 157.08,80.24 167.81,90.98 187.23,90.98 188.37,89.84 202.54,89.84 203.28,90.58 221.35,90.58 221.88,91.11 236.01,91.11 239.29,87.83 240.24,87.83 240.63,87.44 241.69,87.44 v2(241.86,87.6)
  BOTTOM w0.102: v2(146.22,75.01) 146.06,74.85 145.8,74.85 145.5,74.54 145.5,72.61 145.47,72.59 145.47,72.54 UC1.B42
CLK_PCIE_LAN#: length 129
  TOP w0.102: UL1.45 255.63,89.32 255.7,89.39 255.7,89.48 255.03,90.15 255.03,91.34 253.51,92.85 247.86,92.85 245.4,90.4 244.26,90.4 242.77,88.91 242.77,87.63 242.31,87.18 242.02,87.18 v2(241.86,87.01)
  IN1 w0.089: v2(146.22,74.43) 146.42,74.62 146.61,74.62 146.86,74.88 146.86,76.88 150.03,80.05 157.16,80.05 167.89,90.78 187.15,90.78 188.28,89.65 202.62,89.65 203.36,90.38 221.43,90.38 221.96,90.92 235.93,90.92 239.21,87.64 240.16,87.64 240.55,87.24 241.63,87.24 v2(241.86,87.01)
  BOTTOM w0.102: v2(146.22,74.43) 146.06,74.59 145.91,74.59 145.75,74.44 145.75,72.72 146.04,72.43 UC1.C41
CLK_PCIE_MMI: length 177.7
  TOP w0.102: v2(277.06,33.69) 277.23,33.86 279.31,33.86 280.8,32.37 281.11,32.37 281.18,32.31 UR1.3
  IN4 w0.089: v2(277.06,33.69) 276.87,33.89 272.76,33.89 271.71,32.84 268.23,32.84 265.87,30.48 252.87,30.48 248.2,35.15 243.86,35.15 243.55,35.46 240.21,35.46 239.56,36.11 234.92,36.11 232.45,38.58 229.6,38.58 227.39,40.79 227.39,41.68 226.77,42.29 206.74,42.29 199.45,49.58 199.45,52.85 196.76,55.54 196.76,68.18 189.94,74.99 189.26,74.99 187.06,77.19 187.06,78.2 184.82,80.43 175.57,80.43 174.78,79.63 166.25,79.63 165.72,80.17 160.53,80.17 160.24,79.88 148.6,79.88 145.75,77.04 145.75,75.74 145.58,75.56 145.34,75.56 v2(145.14,75.37)
  BOTTOM w0.081: v2(145.14,75.37) 144.97,75.55 144.88,75.55 144.69,75.35 144.69,73.95 144.62,73.88 144.62,73.44 144.68,73.32 144.68,73.1 144.66,73.01 144.65,73 144.63,72.95 144.62,72.95 144.62,72.94 144.62,72.81 144.65,72.71 144.86,72.5 145.03,72.5 145.21,72.33 UC1.C42
CLK_PCIE_MMI#: length 177.5
  TOP w0.102: v2(277.06,34.28) 277.23,34.11 279.42,34.11 280.91,32.62 281.12,32.62 281.2,32.71 UR1.2
  IN4 w0.089: v2(145.14,75.95) 145.34,75.76 145.5,75.76 145.56,75.82 145.56,77.12 148.52,80.08 160.16,80.08 160.45,80.36 165.8,80.36 166.34,79.83 174.7,79.83 175.49,80.62 184.9,80.62 187.25,78.28 187.25,77.27 189.34,75.19 190.02,75.19 196.95,68.26 196.95,55.62 199.64,52.93 199.64,49.66 206.82,42.49 226.85,42.49 227.58,41.76 227.58,40.87 229.68,38.77 232.53,38.77 235.01,36.3 239.65,36.3 240.29,35.65 243.64,35.65 243.95,35.34 248.28,35.34 252.95,30.68 265.79,30.68 268.15,33.04 271.63,33.04 272.67,34.08 276.87,34.08 v2(277.06,34.28)
  BOTTOM w0.081: UC1.C43 144.6,72.48 144.5,72.63 144.46,72.79 144.46,72.97 144.47,73 144.47,73 144.52,73.13 144.52,73.23 144.46,73.4 144.46,74.04 144.46,74.04 144.46,75.45 144.79,75.78 144.97,75.78 v2(145.14,75.95)
CLK_PCIE_SATA: length 135.4
  IN4 w0.089: v2(226.21,41.26) 226.6,40.87 226.6,40.48 226.3,40.18 219.46,40.18 219.08,40.56 206.84,40.56 198.31,49.09 198.31,52.38 195.58,55.11 195.58,66.96 189.23,73.32 187.2,73.32 184.17,76.34 183.11,76.34 180.31,79.14 175.93,79.14 175.18,78.4 161.92,78.4 161.6,78.71 155.36,78.71 154.79,78.15 152.49,78.15 152.18,77.84 149.34,77.84 148.02,76.52 147.88,76.52 v2(147.49,76.91)
  BOTTOM w0.081: 148.58,75.6 148.58,75.58 148.57,75.58 148.57,74.02 148.34,73.78 148.34,73.65 148.48,73.51 UC1.A37
  BOTTOM w0.102: v2(147.49,76.91) 147.66,76.74 147.96,76.74 148.58,76.11 148.58,75.6 ; v2(226.21,41.26) 226.54,41.59 226.54,42.43 231.43,47.32 231.43,48.51 233.18,50.27 233.18,50.99 235.14,52.95 235.14,58.61 234.15,59.6 233.36,59.6 233.3,59.53 233.3,59.42 233.23,59.35 JNGFF2.47
CLK_PCIE_SATA#: length 135.8
  IN4 w0.089: v2(226.79,41.26) 226.79,40.4 226.38,39.98 219.38,39.98 219,40.36 206.76,40.36 198.11,49.01 198.11,52.3 195.39,55.03 195.39,66.88 189.15,73.12 187.11,73.12 184.09,76.14 183.03,76.14 180.22,78.95 176.01,78.95 175.26,78.2 161.84,78.2 161.52,78.52 155.44,78.52 154.87,77.95 152.57,77.95 152.26,77.64 149.42,77.64 148.1,76.32 v2(147.49,76.32)
  BOTTOM w0.081: UC1.B37 148.55,73.11 148.1,73.55 148.1,73.88 148.34,74.12 148.34,75.57 148.33,75.58 148.33,75.6
  BOTTOM w0.102: 148.33,75.6 148.33,76.01 147.86,76.49 147.66,76.49 v2(147.49,76.32) ; JNGFF2.45 234.25,59.85 235.39,58.71 235.39,52.84 233.43,50.89 233.43,50.16 231.68,48.41 231.68,47.22 226.79,42.33 v2(226.79,41.26)
CLK_PCIE_WIGIG: length 145.5
  IN4 w0.089: v2(146.22,76.2) 146.34,76.31 146.73,76.31 147.02,76.6 147.02,77.34 148.44,78.76 154.41,78.76 154.84,79.2 160.54,79.2 160.84,79.5 165.43,79.5 165.97,78.96 175.09,78.96 175.89,79.76 183.27,79.76 184.15,78.88 184.15,78.25 188.57,73.82 189.4,73.82 196.07,67.15 196.07,55.28 198.78,52.57 198.78,49.29 207.01,41.07 220.71,41.07 221.13,40.65 224.95,40.65 225.17,40.87 225.17,41.14 v2(225.37,41.33)
  BOTTOM w0.081: UC1.B39 147.42,73.07 146.69,73.8 146.69,74.68 146.68,74.69 146.68,74.71
  BOTTOM w0.102: v2(146.22,76.2) 146.34,76.31 146.54,76.31 146.68,76.17 146.68,74.71 ; JNGFF1.63 232.42,16.35 232.3,16.23 230.7,16.23 225.61,21.31 223.39,21.31 222.25,22.45 222.25,33.08 225.23,36.07 225.23,41.19 v2(225.37,41.33)
CLK_PCIE_WIGIG#: length 145.4
  IN4 w0.089: v2(224.78,41.33) 224.98,41.14 224.98,40.95 224.87,40.84 221.21,40.84 220.79,41.26 207.09,41.26 198.98,49.38 198.98,52.65 196.27,55.36 196.27,67.23 189.48,74.02 188.65,74.02 184.34,78.33 184.34,78.96 183.35,79.96 175.8,79.96 175,79.16 166.05,79.16 165.51,79.7 160.76,79.7 160.46,79.39 154.76,79.39 154.33,78.96 148.36,78.96 146.83,77.42 146.83,76.68 146.65,76.5 146.5,76.5 v2(146.22,76.78)
  BOTTOM w0.081: 146.93,74.71 146.93,74.69 146.92,74.68 146.92,73.9 147.31,73.51 UC1.A39
  BOTTOM w0.102: JNGFF1.65 232.42,15.85 232.3,15.97 230.59,15.97 225.51,21.06 223.29,21.06 222,22.35 222,33.19 224.98,36.17 224.98,41.14 v2(224.78,41.33) ; v2(146.22,76.78) 146.44,76.56 146.65,76.56 146.93,76.27 146.93,74.71
CLK_PCIE_WLAN: length 134.2
  IN4 w0.089: v2(147.43,75.09) 147.63,74.89 148.05,74.89 148.31,75.16 148.31,75.77 149.67,77.13 152.47,77.13 152.66,77.32 155.46,77.32 156.12,77.98 160.58,77.98 160.91,77.65 162.72,77.65 163.18,77.19 170.1,77.19 170.6,77.7 175.43,77.7 176.21,78.48 180.03,78.48 182.83,75.67 183.63,75.67 187.64,71.67 189.86,71.67 194.9,66.62 194.9,54.84 197.65,52.1 197.65,48.8 206.93,39.51 227.49,39.51 228.14,38.87 228.14,38.35 v2(228.35,38.14)
  BOTTOM w0.081: 148.08,74.4 148.08,74.38 148.07,74.37 148.07,74.15 147.93,74.02 147.93,73.46 148.25,73.15 148.25,72.7 148.55,72.4 UC1.C37
  BOTTOM w0.102: 148.08,74.4 148.08,74.77 147.83,75.02 147.5,75.02 v2(147.43,75.09) ; v2(228.35,38.14) 228.18,37.98 228.18,37.62 228,37.44 228,34.43 227.26,33.69 227.26,29.76 228.64,28.38 228.64,22.98 229.4,22.23 232.3,22.23 232.42,22.35 JNGFF1.39
CLK_PCIE_WLAN#: length 134.2
  IN4 w0.089: v2(147.43,74.5) 147.63,74.7 148.13,74.7 148.51,75.08 148.51,75.69 149.76,76.94 152.55,76.94 152.74,77.13 155.54,77.13 156.2,77.79 160.5,77.79 160.83,77.46 162.64,77.46 163.1,76.99 170.18,76.99 170.69,77.5 175.51,77.5 176.29,78.28 179.95,78.28 182.75,75.48 183.55,75.48 187.56,71.47 189.78,71.47 194.71,66.54 194.71,54.76 197.45,52.02 197.45,48.72 206.85,39.32 227.41,39.32 227.94,38.79 227.94,38.32 v2(227.76,38.14)
  BOTTOM w0.081: 147.82,74.4 147.82,74.38 147.83,74.37 147.83,74.25 147.7,74.11 147.7,73.37 148.02,73.05 148.02,72.87 147.95,72.81 147.83,72.81 147.66,72.64 147.66,72.51 147.74,72.43 147.88,72.43 UC1.B38
  BOTTOM w0.102: v2(227.76,38.14) 227.93,37.98 227.93,37.72 227.75,37.54 227.75,34.53 227.01,33.8 227.01,29.65 228.39,28.28 228.39,22.88 229.29,21.97 232.3,21.97 232.42,21.85 JNGFF1.41 ; v2(147.43,74.5) 147.43,74.57 147.63,74.77 147.73,74.77 147.82,74.67 147.82,74.4
CLK_TP_SIO: length 24.1
  TOP w0.102: v2(257.46,35.86) 257.44,35.86 257.19,36.11 257.19,36.62 UE2.A37 ; JKBTP1.3 245.07,22.1 245.89,22.92 RZ19.2 246.11,23.24 246.11,23.85 CZ31.1 246.55,24.04 246.55,23.55 v2(246.57,23.53)
  IN1 w0.089: v2(246.57,23.53) 246.76,23.73 246.76,25.07 249.58,27.88 251.74,27.88 257.74,33.89 257.74,35.58 v2(257.46,35.86)
CLKRUN#: length 181.7
  TOP w0.102: RPC15.4 179.9,61.4 179.32,61.98 179.32,63.35 178.94,63.73 176.82,63.73 176.51,63.42 175.65,63.42 v1(175.63,63.45) 175.31,63.77 173.18,63.77 172.89,63.47 168.93,63.47 168.8,63.35 168.14,63.35 v2(167.67,62.88) ; UE1.B20 250.93,68.51 v2(251.01,68.43) ; v2(253.45,37.63) 253.45,38.05 253.2,38.3 253.2,38.61 253.3,38.71 UE2.A32
  IN3 w0.081: 173.36,57.38 172.08,57.38 169.95,59.51 169,59.51 168.78,59.73 168.78,60.31 169.06,60.59 169.06,60.6 169.45,60.99 169.45,61.65 169.31,61.78 169.07,61.78 168.46,62.4 168.16,62.4 v2(167.67,62.88)
  IN3 w0.122: v2(253.45,37.63) 253.45,37.14 252,35.7 252,34.93 249.49,32.42 247.52,32.42 245.01,29.91 v2(243.47,29.91) 243.14,29.59 243.14,27.96 242.71,27.53 242.71,26.53 239.58,23.41 237.61,23.41 236.98,24.04 234.12,24.04 233.13,23.05 231.68,23.05 230.13,24.6 206.86,24.6 203.71,27.75 195.52,27.75 183.01,40.26 183.01,41.81 180.68,44.15 180.68,47.96 179.53,49.1 176.44,49.1 174.43,51.11 174.43,56.81 173.86,57.38 173.36,57.38
  BOTTOM w0.081: UC1.V5 168.15,63.36 v2(167.67,62.88)
  BOTTOM w0.102: v2(243.47,29.91) 246.01,32.46 246.01,50.81 247.52,52.32 247.52,55.6 246.89,56.24 246.89,67.6 247.27,67.98 250.57,67.98 v2(251.01,68.43)
CMPIN: length 7.1
  BOTTOM w0.102: v1(87.61,80.29) 87.32,80.58 87.09,80.58 86.59,81.08 PR737.2
  BOTTOM w0.203: PU700.13 82.33,82.36 82.61,82.08 82.61,81.62 PR745.1 PC737.1 84.94,81.05 PR738.1 PR737.2
CMPOUT: length 8.9
  BOTTOM w0.102: v1(87.08,78.13) 86.8,77.85 85.33,77.85 84.95,78.23 PR743.1
  BOTTOM w0.203: PR738.2 84.92,80.12 PC741.2 83.7,80.49 82.74,80.49 82.23,81 82.23,81.83 82.1,81.96 PU700.14
  BOTTOM w0.254: PR743.1 PR740.1 84.96,79.3 PR738.2
CONTACTLESS_DET#: length 145.3
  TOP w0.102: JUSH1.4 258.67,10.86 259.41,11.59 259.41,13.75 258.71,14.45 257.85,14.45 257.38,14.92 254,14.92 253.82,14.74 248.09,14.74 247.83,15.01 243.82,15.01 240.83,18.01 239.52,18.01 236.66,20.87 236.66,23.02 236.32,23.37 236.32,24.79 v2(235.71,25.4) ; v1(182.76,66.24) 182.42,65.89 v2(182.1,65.89)
  IN1 w0.089: v2(182.1,65.89) 180.91,65.89 180.41,66.4 175.41,66.4 174.3,65.28 170.45,65.28 170.23,65.06 169.25,65.06 168.6,64.41 168.06,64.41 v2(167.66,64.81)
  IN3 w0.081: v2(167.66,64.81) 168.16,64.31 168.46,64.31 169.42,63.35 169.86,63.35 170.33,62.88 170.33,61.92 170.55,61.71 170.55,60.21 171.36,59.39 173.13,59.39 173.3,59.22 173.36,59.22
  IN3 w0.122: v2(235.71,25.4) 235.29,25.82 234.63,25.82 233.75,26.69 230.74,26.69 229.9,25.85 207.43,25.85 204.28,29 196.04,29 184.27,40.78 184.27,42.46 181.94,44.79 181.94,53.39 178.97,56.36 177.42,56.36 174.56,59.22 173.36,59.22
  BOTTOM w0.081: v2(167.66,64.81) 167.62,64.77 167.62,64.43 UC1.U6
  BOTTOM w0.102: RPC6.5 181.96,65.76 v2(182.1,65.89)
CORE_BOOT: length 1.5
  BOTTOM w0.102: v1(99.27,59.33) 98.61,58.67 PC504.2
CORE_BOOT_C: length 1.3
  BOTTOM w0.102: PC504.1 v1(97.7,59.41)
CORE_BOOT_R: length 3.1
  BOTTOM w0.102: PR517.1 98.51,57.07 97.77,56.34 v1(95.82,56.34)
CORE_SNUB: length 3.7
  BOTTOM w0.102: PR522.2 104.31,50.08 104.86,49.53 104.86,48.08 105.24,47.7 v1(105.8,47.7)
CORE_SW:
  vias: v1(105.19,55.5)
CPPE#: length 4.2
  BOTTOM w0.102: RC160.2 174.15,67.92 172.98,69.09 v1(172.3,69.09) 171.34,69.09 UC1.J1
CPU_DPB_AUX: length 148.8
  IN4 w0.089: v2(284.77,61.38) 284.77,63.26 279.65,68.37 266.68,68.37 260.59,74.47 244.44,74.47 235.07,83.83 235.07,85.84 234.71,86.2 234.48,86.2 231.05,89.62 231.05,90.04 229.64,91.45 221.86,91.45 219.63,89.22 204.62,89.22 202.11,86.71 192.46,86.71 191.53,85.79 179.03,85.79 178.1,86.71 170.81,86.71 170.1,86 v2(170.1,84.28)
  BOTTOM w0.076: 168.71,76.26 168.71,76.25 168.72,76.23 168.72,74.51 168.31,74.1 168.06,74.1 167.72,73.76 167.72,73.35 167.45,73.08 167.45,72.94 167.52,72.86 UC1.B5
  BOTTOM w0.102: CV512.2 284.58,61.79 284.58,61.57 v2(284.77,61.38) ; 168.71,76.26 168.71,77.18 169.32,77.79 169.32,81.72 169.21,81.84 RPC20.2 169.21,82.27 169.48,82.55 170.01,82.55 170.32,82.86 170.32,84.07 v2(170.1,84.28)
CPU_DPB_AUX#: length 148.7
  IN4 w0.089: v2(284.12,61.38) 284.29,61.38 284.38,61.47 284.38,61.58 284.6,61.79 284.6,63.19 279.58,68.2 266.61,68.2 260.52,74.3 244.37,74.3 234.9,83.76 234.9,85.77 234.64,86.03 234.41,86.03 230.88,89.55 230.88,89.97 229.57,91.28 221.93,91.28 219.7,89.05 204.69,89.05 202.18,86.54 192.53,86.54 191.6,85.62 178.96,85.62 178.03,86.54 170.88,86.54 170.27,85.93 170.27,84.7 v2(170.69,84.28)
  BOTTOM w0.076: UC1.C5 168.01,72.59 167.96,72.65 167.96,73.03 167.9,73.09 167.9,73.68 168.13,73.91 168.39,73.91 168.9,74.43 168.9,76.23 168.92,76.25 168.92,76.26
  BOTTOM w0.102: 168.92,76.26 168.92,77.07 169.53,77.68 169.53,81.64 169.71,81.82 RPC20.1 169.71,82.2 169.85,82.34 170.1,82.34 170.53,82.77 170.53,84.13 v2(170.69,84.28) ; v2(284.12,61.38) 284.37,61.63 284.37,61.79 CV513.2
CPU_DPB_CTRLCLK: length 165.9
  IN3 w0.122: v2(175.38,84.87) 175.38,86.08 175.76,86.46 196.12,86.46 196.82,85.76 204.92,85.76 205.66,86.5 208.78,86.5 209.66,87.38 226.81,87.38 226.98,87.56 229.63,87.56 231.14,86.05 231.14,84.75 232.86,83.02 232.86,81.63 235.03,79.46 236.23,79.46 240.34,75.35 240.34,69.25 246.56,63.04 246.56,61.9 247.29,61.17 250.19,61.17 250.81,60.55 262.25,60.55 263.08,59.73 267.71,59.73 269.11,61.12 269.11,66.76 274.03,71.68 277.66,71.68 279.64,69.7 281.87,69.7 282.64,68.94 283.21,68.94 283.52,69.25 v2(284.67,69.25)
  BOTTOM w0.076: 166.49,76.26 166.49,75.29 165.62,74.43 165.62,73.39 165.1,72.86 UC1.B9
  BOTTOM w0.102: v2(284.67,69.25) 285.05,69.63 UV502.12 ; v2(175.38,84.87) 174.89,85.36 164.93,85.36 164.27,84.71 164.27,83.41 164.47,83.22 RPC2.2 165.22,83.22 165.34,83.34 165.68,83.34 165.88,83.13 165.88,79.46 v1(166.11,79.23) 166.49,78.86 166.49,76.26
CPU_DPB_CTRLDAT: length 163.5
  IN3 w0.122: v2(282.83,69.44) 282.82,69.44 282.25,70.01 279.79,70.01 277.8,72.01 274,72.01 268.86,66.86 268.86,61.25 267.59,59.98 263.2,59.98 262.38,60.81 250.94,60.81 250.32,61.42 247.39,61.42 246.81,62 246.81,63.19 244.17,65.82 244.17,71.9 236.33,79.75 236.02,79.75 235.1,79.75 233.11,81.73 233.11,83.15 231.39,84.87 231.39,86.15 229.73,87.81 226.88,87.81 226.7,87.63 209.56,87.63 208.67,86.75 205.37,86.75 204.64,86.01 196.93,86.01 196.22,86.72 175.51,86.72 174.8,86 v2(174.8,84.87)
  BOTTOM w0.076: UC1.C9 165.43,72.96 165.79,73.32 165.79,74.31 166.72,75.24 166.72,76.26
  BOTTOM w0.102: UV502.9 283.1,69.72 v2(282.83,69.44) ; 166.72,76.26 166.72,79.16 166.11,79.76 166.11,83.22 165.77,83.57 165.26,83.57 165.11,83.72 RPC2.1 164.6,83.72 164.5,83.82 164.5,84.59 165.04,85.13 170.02,85.13 170.19,84.96 v1(170.75,84.96) 170.91,84.96 171.08,85.13 174.54,85.13 v2(174.8,84.87)
CPU_DPC_AUX: length 91.8
  TOP w0.102: v2(234.33,83.33) 234.15,83.14 233.76,83.14 CV79.1
  IN4 w0.089: v2(167.76,84.43) 167.54,84.43 167.42,84.31 167.42,84.08 167.95,83.54 170.84,83.54 171.19,83.89 171.19,85.12 171.56,85.5 177.76,85.5 178.11,85.15 192.79,85.15 193.72,86.07 203.09,86.07 205.59,88.58 219.91,88.58 222.14,90.81 229.36,90.81 230.39,89.77 230.39,89.38 233.9,85.87 233.9,85.06 234.23,84.73 234.23,83.96 233.66,83.39 233.66,83.04 233.75,82.95 233.95,82.95 v2(234.33,83.33)
  BOTTOM w0.076: UC1.A6 167.03,73.5 167.13,73.41 167.27,73.41 167.37,73.5 167.37,73.74 167.26,73.85 167.13,73.85 167.04,73.94 167.04,74.15 168.2,75.3 168.2,76.23 168.21,76.25 168.21,76.26
  BOTTOM w0.102: v2(167.76,84.43) 167.66,84.34 167.66,82.92 167.99,82.6 168.45,82.6 168.71,82.34 RPC20.3 168.71,81.84 168.56,81.7 168.56,80.13 168.58,80.11 168.58,79.55 168.56,79.53 168.56,77.76 168.21,77.4 168.21,76.26
CPU_DPC_AUX#: length 91.8
  TOP w0.102: v2(234.33,82.75) 234.15,82.94 233.76,82.94 CV80.1
  IN4 w0.089: v2(234.33,82.75) 234.3,82.78 233.68,82.78 233.49,82.97 233.49,83.46 234.06,84.04 234.06,84.66 233.73,84.99 233.73,85.8 230.22,89.31 230.22,89.7 229.29,90.64 222.21,90.64 219.98,88.41 205.66,88.41 203.16,85.9 193.79,85.9 192.86,84.98 178.04,84.98 177.69,85.33 171.63,85.33 171.36,85.05 171.36,83.82 170.91,83.37 167.88,83.37 167.25,84.01 167.25,84.3 v2(167.06,84.49)
  BOTTOM w0.076: 168,76.26 168,76.25 168.01,76.23 168.01,75.37 166.86,74.22 166.86,73.8 166.7,73.64 166.7,72.9 UC1.B6
  BOTTOM w0.102: 168,76.26 168,77.49 168.35,77.84 v4(168.35,79.83) 168.35,81.71 168.21,81.85 RPC20.4 168.21,82.25 168.07,82.39 167.9,82.39 167.45,82.83 167.45,84.16 167.12,84.49 v2(167.06,84.49)
CPU_DPC_AUX#_C: length 2.6
  TOP w0.102: CV80.2 232.14,82.96 231.79,82.96 231.76,82.94 v4(231.48,82.94) 231.2,82.94 231.18,82.96 230.67,82.96 230.59,82.88 UV7.51
CPU_DPC_AUX_C: length 2.6
  TOP w0.102: CV79.2 232.19,83.17 230.71,83.17 230.59,83.28 UV7.52
CPU_DPC_CTRLCLK: length 93.4
  TOP w0.102: UV7.50 230.75,82.48 230.8,82.52 v2(231.14,82.52)
  IN3 w0.122: v2(175.97,84.87) 176.6,85.51 208.14,85.51 209.76,87.13 226.91,87.13 227.08,87.3 229.53,87.3 230.43,86.41 230.43,83.24 v2(231.14,82.52)
  BOTTOM w0.076: UC1.D9 165.59,71.72 165.1,72.22 165.1,72.38 164.75,72.73 164.75,72.96 165.03,73.24 165.03,74.95 165.39,75.31 165.85,75.31 166.25,75.72 166.25,76.26
  BOTTOM w0.102: v2(175.97,84.87) 175.25,85.59 164.37,85.59 v1(164.01,85.23) 162.57,83.79 162.57,82.45 163.18,81.84 164.09,81.84 164.27,82.02 164.27,82.52 164.47,82.72 RPC2.3 165.4,82.72 165.64,82.47 165.64,79.19 166.25,78.58 166.25,76.26
CPU_DPC_CTRLDAT: length 93.8
  TOP w0.102: v2(230.96,81.95) 230.83,82.08 UV7.49
  IN3 w0.122: v2(230.96,81.95) 230.17,82.74 230.17,86.31 229.43,87.06 227.18,87.06 227.01,86.88 209.87,86.88 208.09,85.11 176.8,85.11 v2(176.57,84.87)
  BOTTOM w0.076: 166.02,76.26 166.02,75.81 165.71,75.49 165.31,75.49 164.86,75.04 164.86,73.31 164.58,73.03 164.58,72.66 164.93,72.31 164.93,72.15 165.2,71.88 165.2,71.76 165.11,71.67 164.99,71.67 UC1.D11
  BOTTOM w0.102: v2(176.57,84.87) 175.62,85.82 163.35,85.82 v1(162.34,84.81) 162.34,82.3 163.05,81.58 164.27,81.58 164.53,81.84 164.53,82.09 164.65,82.22 RPC2.4 165.26,82.22 165.41,82.07 165.41,79.09 166.02,78.48 166.02,76.26
CPU_PWR_DEBUG#: length 90.8
  TOP w0.102: RC197.2 RC198.1 127.76,78.07 127.76,74.21 127.31,73.76 v2(126.49,73.76) ; JXDP1.45 79.51,49.7 v2(79.87,50.06)
  IN4 w0.089: v2(126.49,73.76) 126.01,74.24 126.01,75.7 123.79,77.93 119.81,77.93 117.8,75.92 115.5,75.92 114.69,76.73 101.07,76.73 95.68,71.35 95.68,64.54 93.9,62.76 93.9,58.03 92.19,56.31 91.22,56.31 90.24,55.33 88.78,55.33 88.47,55.64 84.32,55.64 84.1,55.87 80.26,55.87 79.29,54.89 79.29,51.66 79.87,51.08 v2(79.87,50.06)
  BOTTOM w0.076: 130.39,70.64 131.4,69.62 132.43,69.62 132.59,69.78 133.28,69.78 133.41,69.65 134.46,69.65 UC1.H59
  BOTTOM w0.102: 130.39,70.64 129.61,71.41 129.28,71.41 128.7,71.99 128.7,72.12 127.44,73.39 v1(127.02,73.39) 126.64,73.76 v2(126.49,73.76)
CPU_SEL: length 13.6
  TOP w0.102: v2(169.11,68.92) 168.59,69.44 168.59,72.17 169.61,73.19 v1(169.61,74.73) 169.61,75.17 170.49,76.06 RC163.2 RC306.1
  BOTTOM w0.076: v2(169.11,68.92) 168.79,68.92 168.51,69.2 168.51,70.5 UC1.E4
CPU_XDP_PRDY#: length 88.3
  TOP w0.102: JXDP1.5 79.73,59.7 81.96,61.92 87.14,61.92 87.72,61.34 88.42,61.34 89.15,60.61 89.15,57.57 89.9,56.82 89.9,55.44 90.55,54.79 92.69,54.79 93.72,53.76 93.72,45.95 v1(93.41,45.64) v2(92.83,45.06)
  IN3 w0.089: 129.22,66.1 130.94,67.82 v2(130.94,68.71)
  IN3 w0.122: v2(92.83,45.06) 93.04,44.86 115.25,44.86 118.87,48.48 118.87,53.92 120.98,56.03 123.55,56.03 124.43,56.91 124.43,60.21 127.74,63.52 127.74,65 128.84,66.1 129.22,66.1
  BOTTOM w0.076: v2(130.94,68.71) 131.32,68.33 131.99,68.33 132.03,68.28 132.28,68.28 132.57,68.57 UC1.J62
CPU_XDP_PREQ#: length 95.3
  TOP w0.102: v2(91.69,55.35) 90.32,55.35 90.15,55.51 90.15,56.88 90.31,57.04 90.31,59.78 v1(89.98,60.1) 88.52,61.57 87.81,61.57 87.23,62.15 81.86,62.15 79.91,60.2 JXDP1.3
  IN3 w0.122: v2(126.92,71.54) 128.5,69.97 v2(128.5,68.54)
  IN4 w0.089: v2(128.5,68.54) 128.5,69.02 127.16,70.36 126.1,70.36 125.38,71.08 120.59,71.08 118.04,73.62 116.01,73.62 114.83,74.8 100.37,74.8 96.55,70.99 96.55,62.98 94.55,60.98 94.55,57.63 92.26,55.35 v2(91.69,55.35)
  BOTTOM w0.076: UC1.K62 132.81,67.63 132.53,67.36 131.94,67.36 131.69,67.61 130.67,67.61 130.36,67.92
  BOTTOM w0.102: v2(126.92,71.54) 126.04,72.42 126.04,82.28 RC126.2 ; v2(128.5,68.54) 129.74,68.54 130.36,67.92
CPU_XDP_TCLK: length 92.3
  TOP w0.102: v2(76.6,45.33) RC128.2 RC119.1 76.3,46.7 JXDP1.57 ; v3(92.9,60.1) 92.4,59.6 v2(91.95,59.6)
  IN1 w0.089: v2(91.95,59.6) 91.37,59.03 91.37,55.73 89.41,53.76 89.41,49.95 89.13,49.68 88.28,49.68 87.49,50.46 78.49,50.46 77.21,49.19 77.21,45.95 v2(76.6,45.33)
  IN4 w0.089: v2(133.77,71.28) 133.64,71.41 133.09,71.41 132.46,72.05 130.66,72.05 130.13,72.57 130.13,72.79 127.1,75.82 126.51,75.82 123.96,78.37 116.67,78.37 115.47,77.17 100.89,77.17 95.25,71.52 95.25,64.73 93.47,62.94 93.47,61.53 91.95,60 v2(91.95,59.6)
  BOTTOM w0.081: UC1.E60 134.11,70.95 v2(133.77,71.28)
  BOTTOM w0.102: v2(91.95,59.6) 92.33,59.99 RC112.1
CPU_XDP_TDI: length 70.2
  TOP w0.102: v2(91.93,56.72) 91.93,56.64 v3(91.35,56.06)
  IN4 w0.089: v2(126.87,76.3) 126.33,76.3 124.05,78.59 116.54,78.59 115.34,77.38 100.8,77.38 95.04,71.61 95.04,64.82 93.25,63.04 93.25,61.88 91.53,60.16 91.53,57.12 v2(91.93,56.72)
  BOTTOM w0.081: UC1.F63 131.56,70.07 129.42,72.22
  BOTTOM w0.102: 129.42,72.22 126.68,74.95 126.68,76.11 v2(126.87,76.3) 126.87,79.1 127.38,79.6 127.38,82.6 RC125.2 ; UC7.6 91.47,56.83 91.58,56.72 v2(91.93,56.72)
CPU_XDP_TDO: length 67.6
  TOP w0.102: v3(93.51,57.73) 92.91,58.33 v2(91.93,58.33)
  IN4 w0.089: v2(126.49,74.4) 126.49,75.53 123.87,78.16 116.8,78.16 115.59,76.95 100.98,76.95 95.47,71.43 95.47,64.63 93.69,62.85 93.69,60.08 v2(91.93,58.33)
  BOTTOM w0.076: 129.62,71.74 131.56,69.79 132.27,69.79 132.55,70.07 UC1.F62
  BOTTOM w0.081: 129.62,71.74 129.42,71.74
  BOTTOM w0.102: RC127.2 126.36,79.53 126.36,74.52 v2(126.49,74.4) 126.76,74.4 129.42,71.74 ; UC7.3 v2(91.93,58.33)
CPU_XDP_TMS: length 69.1
  TOP w0.102: v2(89.01,55.93) 89.01,56.31 v3(88.55,56.77)
  IN4 w0.089: v2(89.01,55.93) 91.32,58.24 91.32,60.24 93.04,61.97 93.04,64.24 94.82,66.02 94.82,71.7 100.72,77.6 115.23,77.6 116.43,78.8 124.14,78.8 126.07,76.87 v2(127.31,76.87) 127.57,76.62 127.57,75.79 v2(130.87,72.49)
  BOTTOM w0.081: UC1.E61 133.26,71.06 133.26,71.45 132.93,71.78 132.55,71.78 132.47,71.86 132.3,71.86 132.29,71.86 131.88,71.86 131.76,71.98 131.38,71.98 v2(130.87,72.49)
  BOTTOM w0.102: UC7.8 89.53,56.05 89.41,55.93 v2(89.01,55.93) ; RC124.2 127.89,79.48 127.31,78.9 v2(127.31,76.87)
CPU_XDP_TRST#: length 69.3
  TOP w0.102: v3(88.3,59.31) 88.3,58.6 v2(87.63,57.92)
  IN4 w0.089: v2(134.42,71.28) 133.85,71.86 133.41,71.86 126.9,78.37 124.93,78.37 124.28,79.02 116.33,79.02 115.12,77.81 100.63,77.81 94.61,71.79 94.61,66.11 92.82,64.33 92.82,62.06 91.1,60.33 91.1,58.88 90.48,58.27 88.64,58.27 88.3,57.92 v2(87.63,57.92)
  BOTTOM w0.081: UC1.E59 134.76,70.95 v2(134.42,71.28)
  BOTTOM w0.203: RC109.1 86.93,57.92 v2(87.63,57.92) 87.72,57.83 UC7.11
  BOTTOM w0.254: RC109.1 RC129.2
CPUSB#: length 8.6
  TOP w0.081: v2(169.85,67.41) 169.85,67.83 170.94,68.92 173.36,68.92
  TOP w0.102: RPC4.6 176.38,68.23 175.91,68.71 v1(175.07,68.71) 174.4,68.71 174.18,68.92 173.36,68.92
  BOTTOM w0.081: v2(169.85,67.41) 169.48,67.78 UC1.K3
CS_1.35V: length 4.6
  TOP w0.102: v1(67.61,11.73) 67.02,11.73 65.81,10.53 PR201.2
  TOP w0.508: v2(64.82,10.53) 64.87,10.48 65.28,10.48 65.33,10.53 PR201.2
  BOTTOM w0.203: v2(64.82,10.53) 64.88,10.59 PU200.13
CSN1: length 25.5
  TOP w0.203: PU500.18 PC502.1
  TOP w0.254: PC502.1 PC513.1 110.19,65.43 v1(110.19,63.4) 110.19,61.05 109.79,60.65 109.79,55.41 112.63,52.56 112.63,50.89 PR515.2 PR514.2 111.19,49.71 111.36,49.53 v2(111.36,49.38)
  BOTTOM w0.254: PL500.2 112.32,50.34 v2(111.36,49.38)
CSP1: length 19.3
  TOP w0.203: PU500.17 107.56,65.63 108.08,65.12 PC502.2
  TOP w0.254: PR514.1 PR512.1 110.3,51.93 110.49,52.12 PH501.1 111,52.37 111,53.62 109.36,55.26 109.36,60.86 v1(109.74,61.24) 109.74,64.97 PC513.2 PC502.2
CSS_GC: length 68.8
  TOP w0.254: PU800.10 75.95,37.67 74.89,38.73 73.01,38.73 v1(72.37,39.37) 68.68,39.37 67.82,40.23 v2(67.82,41)
  IN1 w0.254: v2(74.74,63.41) 74.55,63.22 74.55,58.78 70.48,54.71 70.48,48.68 69.66,47.85 69.66,43.79 67.82,41.95 v2(67.82,41)
  IN3 w0.254: v2(71.43,84.75) 70.5,83.81 70.5,76.67 68.12,74.29 68.12,68.27 72.98,63.41 v2(74.74,63.41)
  BOTTOM w0.254: v2(71.43,84.75) 71.43,86.42 68.64,89.22 PR702.1
CSSN_1: length 16
  TOP w0.254: PQ703.2 73.34,95.03 73.09,95.29 71.88,95.29 71.43,94.84 71.43,94.08 71,93.65 ; 71,93.65 PQ701.3 ; 71,93.65 71.43,93.22 71.43,91.99 71.7,91.72 PR707.1 72.39,91.54 v2(72.83,91.1)
  BOTTOM w0.254: PR705.1 78.37,91.42 PR703.1 78.2,91.59 v1(76.96,91.59) 76.4,91.59 75.38,90.58 73.26,90.58 72.83,91.01 v2(72.83,91.1)
CSSP_1: length 20.5
  TOP w0.254: PR706.1 73.34,91.22 v2(73.47,91.1) ; PQ702.3 71.09,97.65 71.36,97.38 v2(71.88,97.38) 72.55,98.06 v1(72.82,98.06) 73,98.06 73.34,97.71 PQ703.5
  IN1 w0.254: v2(71.88,97.38) 71.88,97.37 71.17,96.66 71.17,94.86 73.47,92.56 v2(73.47,91.1)
  BOTTOM w0.254: v2(73.47,91.1) 73.58,90.98 75.22,90.98 76.25,92.01 78.93,92.01 79.27,91.67 PR703.2 79.26,91.42 PR704.1
D_CLKRUN#: length 111.7
  TOP w0.102: v1(244.15,68.78) 244.26,68.68 246.09,68.68 246.41,68.36 RPE8.4 247.56,68.36 v2(248.01,68.82) 248.57,68.26 UE1.A19
  IN3 w0.122: v2(163.02,99.07) 163.02,99.29 163.18,99.45 165.42,99.45 166.17,98.7 168.04,98.7 175.39,91.35 180.46,91.35 183.07,88.75 204.55,88.75 205.31,89.51 208.37,89.51 208.51,89.65 220.29,89.65 221.27,90.62 233.07,90.62 233.52,90.17 233.52,87.52 235.46,85.59 235.46,83.66 237.97,81.14 237.97,80.6 246.69,71.87 246.69,71.04 248.01,69.72 v2(248.01,68.82)
  BOTTOM w0.102: v2(163.02,99.07) 162.45,98.5 JDOCK1.111
D_DLDRQ1#: length 109.5
  TOP w0.102: UE1.B24 v2(251,66.51) ; RPE8.2 v2(247.37,67.36)
  IN3 w0.122: v2(247.37,67.36) 247.13,67.36 246.19,68.3 246.19,71.67 237.47,80.39 237.47,80.94 234.95,83.45 234.95,83.51 234.95,83.51 234.95,84.44 234.07,85.32 234.07,85.94 232.76,87.25 232.76,89.17 231.81,90.12 221.52,90.12 220.54,89.14 208.73,89.14 208.6,89 205.5,89 204.74,88.24 182.81,88.24 180.4,90.65 175.38,90.65 168.13,97.91 165.9,97.91 165.51,98.3 164.24,98.3 v2(164.13,98.41)
  IN4 w0.089: v2(251,66.51) 248.22,66.51 v2(247.37,67.36)
  BOTTOM w0.102: v2(164.13,98.41) 163.95,98.23 JDOCK1.117 ; v2(247.37,67.36) 247.37,67.12 v1(247.66,66.83)
D_LAD0: length 119.9
  TOP w0.102: UE1.B29 251.21,64.01 v2(251.57,64.37)
  IN3 w0.122: v2(251.57,64.37) 251.57,64.62 251.19,65.01 250.81,65.01 250,65.81 250,69.14 247.68,71.46 247.68,71.46 247.68,72.29 247.68,72.29 247.68,72.76 247.21,72.76 238.96,81.01 238.96,81.63 236.61,83.99 236.61,88.56 233.54,91.63 220.75,91.63 219.78,90.67 208.06,90.67 207.92,90.53 204.92,90.53 204.15,89.76 183.58,89.76 180.97,92.37 175.78,92.37 168.45,99.69 166.58,99.69 165.58,100.69 160.64,100.69 v2(160.19,100.25)
  BOTTOM w0.102: v1(251.72,65) 251.57,64.84 v2(251.57,64.37) ; v2(160.19,100.25) 158.95,99.01 JDOCK1.97
D_LAD1: length 117.7
  TOP w0.102: UE1.B28 250.86,64.51 v2(250.94,64.43)
  IN3 w0.122: v2(250.94,64.43) 249.75,65.62 249.75,69.04 247.44,71.35 247.44,71.57 247.44,72.51 247.11,72.51 238.71,80.91 238.71,81.45 236.36,83.81 236.36,88.42 233.41,91.38 220.88,91.38 219.92,90.42 208.16,90.42 208.02,90.27 205.01,90.27 204.25,89.51 183.45,89.51 180.85,92.11 175.68,92.11 168.35,99.44 166.48,99.44 165.48,100.44 161.02,100.44 160.07,99.49 v2(160.07,99.17)
  BOTTOM w0.102: v1(250.25,63.91) 250.78,64.43 v2(250.94,64.43) ; v2(160.07,99.17) 159.45,98.55 JDOCK1.99
D_LAD2: length 114.9
  TOP w0.102: UE1.A25 249.03,65.26 248.78,65.51 248.4,65.51 v2(247.95,65.96)
  IN3 w0.122: v2(247.95,65.96) 249.08,67.08 249.08,69.01 246.94,71.15 246.94,71.77 246.94,72.01 246.9,72.01 238.22,80.7 238.22,81.25 235.71,83.75 235.71,85.68 233.79,87.6 233.79,90.26 233.17,90.88 221.14,90.88 220.16,89.9 208.38,89.9 208.24,89.76 205.21,89.76 204.45,89 183.19,89 180.59,91.6 175.48,91.6 168.15,98.94 166.27,98.94 165.27,99.95 161.82,99.95 v2(160.96,99.08)
  BOTTOM w0.102: v2(160.96,99.08) 160.45,98.58 JDOCK1.103 ; v1(247.23,65.25) 247.23,65.33 247.86,65.96 v2(247.95,65.96)
D_LAD3: length 115.6
  TOP w0.102: UE1.A24 248.78,65.76 v2(248.59,65.95)
  IN3 w0.122: v2(160.95,98.5) 160.74,98.5 160.51,98.72 160.51,99.58 161.13,100.19 165.38,100.19 166.38,99.19 168.25,99.19 175.58,91.86 180.72,91.86 183.32,89.26 204.35,89.26 205.11,90.02 208.12,90.02 208.27,90.17 220.05,90.17 221.01,91.13 233.27,91.13 234.04,90.37 234.04,88.87 234.99,87.92 235.77,87.92 236.11,87.58 236.11,83.7 238.47,81.35 238.47,80.8 247,72.26 247.19,72.26 247.19,72.08 247.19,71.25 249.33,69.11 249.33,66.69 v2(248.59,65.95)
  BOTTOM w0.102: v2(248.59,65.95) v1(249.4,65.95) ; JDOCK1.105 v2(160.95,98.5)
D_LFRAME#: length 115.7
  TOP w0.102: UE1.B23 251.06,67.01 v2(251.6,67.56)
  IN3 w0.122: v2(163.05,101.52) 163.57,101 165.62,101 166.69,99.94 168.56,99.94 175.88,92.62 181.1,92.62 183.7,90.02 204.06,90.02 204.82,90.78 207.82,90.78 207.96,90.92 219.66,90.92 220.62,91.88 233.67,91.88 236.87,88.68 236.87,84.08 239.21,81.74 239.21,81.11 247.31,73.01 247.93,73.01 247.93,72.39 247.93,71.56 250.25,69.24 250.25,68.49 250.73,68 251.25,68 251.6,67.65 v2(251.6,67.56)
  BOTTOM w0.102: v2(251.6,67.56) v1(252.22,67.56) ; JDOCK1.109 161.95,98.33 162.54,98.92 162.54,101.01 v2(163.05,101.52)
D_SERIRQ: length 109.1
  TOP w0.102: UE1.A20 248.93,67.76 v2(248.59,67.42) 248.59,67.76 248.37,67.97 v1(248.14,67.97) 247.28,67.97 247.17,67.86 RPE8.3
  IN3 w0.122: v2(164.13,99.03) 164.3,99.2 165.32,99.2 166.07,98.45 167.94,98.45 175.29,91.1 180.34,91.1 182.94,88.49 204.64,88.49 205.41,89.26 208.47,89.26 208.61,89.39 220.42,89.39 221.39,90.37 231.91,90.37 233.01,89.28 233.01,87.68 235.2,85.49 235.2,83.56 237.72,81.04 237.72,80.49 246.44,71.77 246.44,69.1 247.36,68.18 248.14,68.18 248.59,67.74 v2(248.59,67.42)
  BOTTOM w0.102: v2(164.13,99.03) 163.99,99.03 163.62,98.66 163.62,98.15 163.45,97.98 JDOCK1.115
DAI_12MHZ#: length 175
  TOP w0.102: RA30.1 v2(35.43,24.74)
  IN3 w0.122: v2(154.98,98.46) 154.98,97.99 154.09,97.11 150.7,97.11 150.16,96.56 150.16,95.24 148.83,93.91 146.33,93.91 143.97,91.55 132.83,91.55 132.51,91.22 129.62,91.22 127.08,88.68 124.22,88.68 122.45,86.91 121.4,86.91 119.44,84.95 108.92,84.95 105.98,82.02 104.07,82.02 102.74,80.68 102.74,77.95 94.99,70.21 94.99,67.54 92.96,65.51 92.96,61.94 91.16,60.13 91.16,58.22 89.31,56.37 87.14,56.37 86.67,56.83 84.74,56.83 84.28,56.37 82.96,56.37 80.66,54.07 80.66,43.61 80.16,43.1 80.16,40.02 77.91,37.77 77.16,37.77 73.81,34.42 73.81,33.28 72.64,32.11 72.13,32.11 71.82,31.79 71.82,30.84 69.97,28.99 59.18,28.99 56.52,26.33 51.76,26.33 48.51,23.09 37.08,23.09 v2(35.43,24.74)
  BOTTOM w0.102: v2(35.43,24.74) v1(36.23,24.74) ; v2(154.98,98.46) 155.55,98.46 155.95,98.06 JDOCK1.89 155.95,95.12 155.83,95 R41.1
DAI_BCLK#: length 172.8
  TOP w0.102: v1(35.16,27.53) 35.24,27.46 RA31.1 34.94,26.34 v2(34.6,26.01)
  IN3 w0.122: v2(152.61,98.48) 150.65,98.48 148.32,96.14 148.32,95.26 148,94.94 145.65,94.94 144.4,93.68 130.64,93.68 126.63,89.68 120.4,89.68 116.67,85.95 105.28,85.95 101.34,82.02 101.34,78.08 93.75,70.48 93.75,67.79 91.9,65.94 91.9,62.35 91.06,61.51 88.96,61.51 86.19,58.74 84.7,58.74 83.94,57.98 81.86,57.98 80.9,57.01 79.83,57.01 78.42,55.6 78.42,40.49 77.52,39.59 76.12,39.59 73.85,37.31 73.85,36.11 72.51,34.77 71.5,34.77 70.8,34.07 70.8,31.34 69.47,30.01 58.67,30.01 56,27.34 51.22,27.34 49.25,25.37 41.85,25.37 41.4,25.82 35.56,25.82 35.37,26.01 v2(34.6,26.01)
  BOTTOM w0.102: v2(152.61,98.48) 152.95,98.14 JDOCK1.77 152.95,94.89 152.78,94.72 R6.1
DAI_DI: length 180.9
  TOP w0.102: UA1.24 31.06,20.36 30.99,20.29 30.67,20.29 v2(30.54,20.42)
  IN3 w0.122: v2(30.54,20.42) 30.54,20.04 30.92,19.66 33.4,19.66 34.1,20.36 34.1,25.25 34.41,25.56 41.27,25.56 41.72,25.12 49.38,25.12 51.35,27.09 56.13,27.09 58.8,29.76 69.59,29.76 71.05,31.22 71.05,32.49 71.69,33.12 71.69,34.01 72.2,34.52 72.64,34.52 74.1,35.98 74.1,37.19 76.25,39.34 77.62,39.34 78.67,40.39 78.67,55.51 79.93,56.77 81,56.77 81.96,57.73 84.04,57.73 84.79,58.48 86.32,58.48 89.09,61.25 91.18,61.25 92.15,62.22 92.15,65.84 94,67.69 94,70.35 101.6,77.95 101.6,81.89 105.41,85.7 116.78,85.7 120.5,89.43 126.74,89.43 130.74,93.43 144.5,93.43 145.73,94.66 148.52,94.66 149.4,95.55 149.4,96.88 150.41,97.88 153.57,97.88 153.81,98.12 v2(153.81,98.48)
  BOTTOM w0.102: v2(30.54,20.42) v1(31.35,20.42) ; JDOCK1.83 154.45,97.83 v2(153.81,98.48)
DAI_DO#: length 175.4
  TOP w0.102: RA32.1 34.48,24.93 v2(34.54,24.99)
  IN3 w0.122: v2(154.39,98.48) 154.39,98.2 153.83,97.63 150.51,97.63 149.65,96.77 149.65,95.45 148.62,94.42 145.84,94.42 144.6,93.18 130.84,93.18 126.84,89.18 124.01,89.18 122.31,87.48 121.23,87.48 119.21,85.46 105.54,85.46 101.85,81.76 101.85,77.83 94.25,70.22 94.25,67.58 92.4,65.73 92.4,62.08 90.85,60.54 90.52,60.54 89.57,59.59 89.57,58.25 88.19,56.87 87.35,56.87 86.18,58.04 84.7,58.04 83.76,57.1 82.36,57.1 80.99,55.73 79.5,55.73 79.26,55.49 79.26,47.38 80.16,46.48 80.16,43.81 79,42.66 79,40.21 77.76,38.96 76.26,38.96 74.36,37.06 74.36,35.85 72.77,34.26 72.32,34.26 71.94,33.88 71.94,32.99 71.31,32.36 71.31,31.09 69.72,29.5 58.93,29.5 56.26,26.83 51.48,26.83 48.24,23.6 43.43,23.6 42.67,24.36 36.57,24.36 35.68,25.25 34.8,25.25 v2(34.54,24.99)
  BOTTOM w0.102: v2(154.39,98.48) 154.39,98.4 154.95,97.84 JDOCK1.85 ; v2(34.54,24.99) v1(34.54,24.04)
DAI_LRCK#: length 177.3
  TOP w0.102: UA1.18 v1(33.46,22.04) 33.94,22.53 33.94,25.95 v2(34.01,26.01)
  IN3 w0.122: v2(153.22,98.48) 153.22,98.65 152.97,98.91 150.73,98.91 148.07,96.24 148.07,95.36 147.89,95.19 145.55,95.19 144.3,93.93 130.53,93.93 126.53,89.93 120.27,89.93 116.54,86.2 105.15,86.2 101.09,82.14 101.09,78.21 93.5,70.62 93.5,67.89 91.65,66.04 91.65,62.48 90.93,61.76 87.37,61.76 83.83,58.23 81.76,58.23 80.79,57.26 79.73,57.26 78.1,55.64 78.1,40.55 77.47,39.92 71.31,39.92 70.51,39.12 70.51,31.44 69.34,30.26 58.54,30.26 55.88,27.6 51.1,27.6 49.12,25.62 41.98,25.62 41.53,26.07 36.07,26.07 35.71,26.43 34.43,26.43 v2(34.01,26.01)
  BOTTOM w0.102: v2(153.22,98.48) 153.22,98.22 153.45,97.99 JDOCK1.79
DAT_DDC2_DOCK: length 110.9
  TOP w0.102: UV8.M4 212.9,74.59 214.56,76.25 215.11,76.25 215.45,76.58 215.45,77.1 217.59,79.23 217.59,85.26 214.61,88.24 v1(210.93,88.24) 209.35,88.24 206.19,91.39 206.19,91.91 205.83,92.27 v2(205.83,93.14)
  IN3 w0.122: v2(143.91,106.5) 143.91,104.59 144.83,103.67 161.51,103.67 163.18,105.34 169.9,105.34 171.99,107.42 176.39,107.42 179.5,104.31 179.5,101.92 180.99,100.43 180.99,96.4 182.31,95.09 182.31,94.08 184.59,91.8 199.47,91.8 201.16,93.48 204.18,93.48 204.97,92.68 205.42,92.68 205.83,93.09 v2(205.83,93.14)
  BOTTOM w0.102: JDOCK1.46 143.95,106.1 144.09,106.24 144.09,106.33 v2(143.91,106.5)
DAT_KBD: length 189
  TOP w0.102: v2(257.6,32.68) 257.74,32.55 RPE2.4 ; v2(257.85,38.56) 257.94,38.47 UE2.B41
  IN1 w0.089: v2(153.83,99.93) 153.65,99.75 153.65,99.49 153.92,99.22 155.29,99.22 155.93,98.59 155.93,97.29 157.11,96.11 158.48,96.11 160.02,97.64 169.91,97.64 174.39,93.16 188.24,93.16 189.4,92 199.97,92 202.46,94.49 221.48,94.49 222.19,93.77 236.37,93.77 239.84,90.3 243.39,90.3 246.64,87.05 246.64,69.59 246.17,69.12 246.17,64.12 246.56,63.74 246.56,62.19 247.39,61.35 248.16,61.35 249.36,60.15 249.36,58.71 251.59,56.48 255.59,56.48 256.51,55.56 261.15,55.56 262.69,54.02 262.69,53.77 263.46,52.99 263.46,50.69 263.18,50.41 263.18,47.08 263.98,46.28 263.98,38.65 262.87,37.55 262.87,34.65 260.19,31.96 258.09,31.96 257.83,32.21 257.83,32.46 v2(257.6,32.68) 258.22,33.3 258.22,37.54 257.85,37.92 v2(257.85,38.56)
  BOTTOM w0.102: v2(153.83,99.93) 153.65,100.11 153.65,102.66 153.32,103 153.32,103.86 153.45,104 JDOCK1.80
DAT_MSE: length 168.2
  TOP w0.102: v2(259.28,33.06) 259.11,32.89 259.11,32.36 259.24,32.23 RPE2.1 ; UE2.B42 258.44,38.27 v2(258.68,38.52)
  IN1 w0.089: v2(151.97,95.11) 151.77,94.92 151.77,93.94 154.05,91.66 187.52,91.66 188.65,90.53 202.26,90.53 202.99,91.27 221.02,91.27 221.55,91.8 236.3,91.8 239.47,88.63 242.82,88.63 244.29,87.16 244.29,83.59 244.99,82.89 244.99,72.2 243.88,71.08 243.88,62.03 253.06,52.84 257.68,52.84 258.93,51.59 258.93,51.3 259.76,50.47 260.66,50.47 261.15,49.98 261.15,48.11 260.38,47.35 260.38,44.6 260.28,44.5 260.28,41.02 259.14,39.89 259.14,38.98 v2(258.68,38.52) 258.68,37.76 259.25,37.19 259.25,33.09 v2(259.28,33.06)
  BOTTOM w0.102: v2(151.97,95.11) 151.82,95.26 151.82,95.86 151.95,96 JDOCK1.73
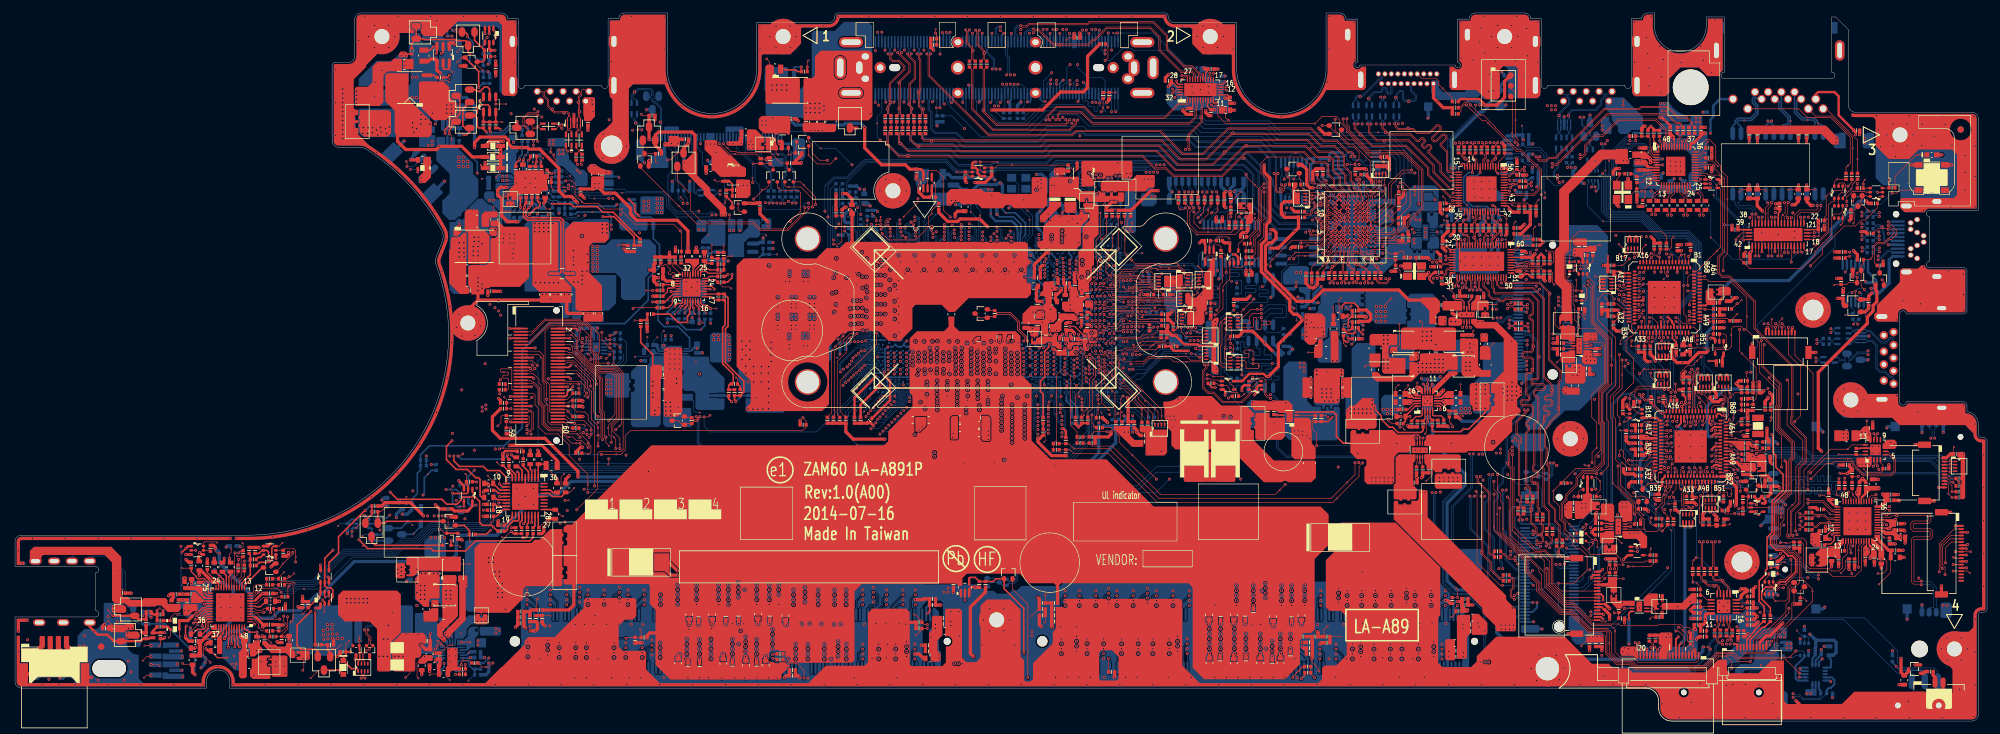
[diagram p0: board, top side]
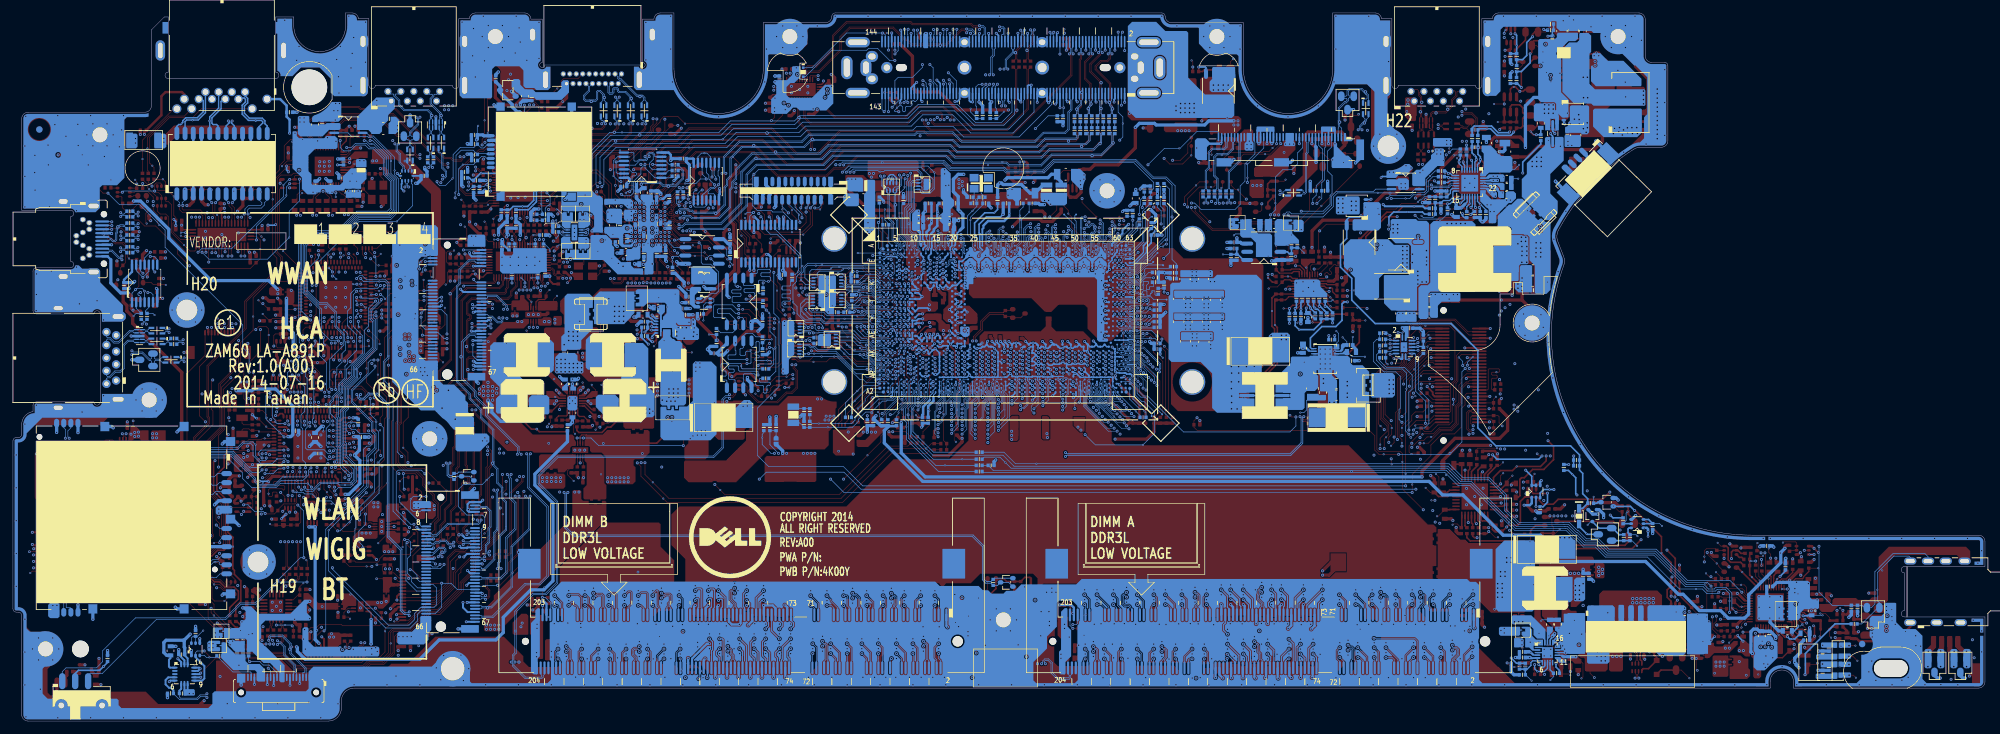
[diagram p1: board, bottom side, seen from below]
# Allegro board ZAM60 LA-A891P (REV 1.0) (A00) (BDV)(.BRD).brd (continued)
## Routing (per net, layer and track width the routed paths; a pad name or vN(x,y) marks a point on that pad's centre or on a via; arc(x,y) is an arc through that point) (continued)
DAT_TP_SIO: length 30.3
  TOP w0.102: v2(247.19,23.54) 247.19,24.04 CZ30.1 ; JKBTP1.4 245.21,21.6 v2(245.68,22.07) ; RZ18.2 247.63,23.24 247.63,23.85 CZ30.1 ; v2(257.76,39.23) 257.44,38.9 UE2.B40 ; CZ30.1 v3(248.51,24.16)
  IN1 w0.089: v2(245.68,22.07) 247.15,23.54 v2(247.19,23.54) 246.98,23.75 246.98,24.98 249.67,27.67 251.82,27.67 257.96,33.8 257.96,37.16 257.44,37.67 257.44,38.9 v2(257.76,39.23)
DC_BLOCK_GC: length 82.6
  TOP w0.254: PR700.2 66.8,99.53 v2(67.13,99.86) ; v2(77.64,38.54) 77.85,38.33 PU800.7
  IN1 w0.254: v2(74.17,63.92) 74.17,58.93 70.04,54.81 70.04,48.93 69.21,48.11 69.21,44.17 67.18,42.14 v2(67.18,41)
  IN2 w0.254: v2(67.13,99.86) 67.69,99.3 67.69,97.27 68.68,96.28 68.68,93.59 67.69,92.6 67.69,83.12 69.33,81.48 69.33,75.63 68.92,75.22 68.58,75.22 67.69,74.33 67.69,69.09 72.73,64.05 72.77,64.05 72.9,63.92 v2(74.17,63.92)
  IN4 w0.254: v2(67.18,41) 67.18,39.92 67.75,39.34 76.84,39.34 v2(77.64,38.54)
  BOTTOM w0.102: v1(67.13,99.29) v2(67.13,99.86)
DC_IN_SS: length 5.4
  TOP w0.102: v1(84.85,38.2) 84.39,37.74 84.39,35.99 PR831.2
  TOP w0.254: PU800.34 82.72,35.72 83.08,35.36 PR831.2
DC_TEST_A3_B3: length 0.7
  BOTTOM w0.081: UC1.A3 169.53,73.39 UC1.B3
DC_TEST_A4: length 6.1
  BOTTOM w0.102: UC1.A4 169.4,74.02 RC192.1 169.4,76.88 170.01,77.48 v1(170.01,79.12)
DC_TEST_A60: length 5.7
  BOTTOM w0.102: RC193.1 131.19,77.14 131.19,76.11 133.35,73.95 133.61,73.95 UC1.A60
DC_TEST_A61_B61: length 0.7
  BOTTOM w0.081: UC1.B61 133.47,73.44 UC1.A61
DC_TEST_A62: length 4.1
  BOTTOM w0.102: RC193.2 130.93,76.48 130.93,75.92 132.75,74.11 UC1.A62
DC_TEST_AV1: length 8.8
  BOTTOM w0.102: RC194.1 176.1,49.21 v1(174.25,51.05) 173.45,51.85 171.12,51.85 UC1.AV1
DC_TEST_AW1: length 7.5
  BOTTOM w0.102: UC1.AW1 172.71,51.47 v1(174.67,49.51) 175.18,49 RC194.2
DC_TEST_AW63: length 5.8
  BOTTOM w0.102: RC195.1 129.65,47.67 v1(129.88,47.9) 130.24,48.26 130.64,48.26 132.16,49.77 UC1.AW63
DC_TEST_AY2_AW2: length 5.9
  BOTTOM w0.076: UC1.AY2 171.99,50.88 172.96,49.91 172.96,49.53 173.36,49.13
  BOTTOM w0.081: UC1.AY2 170.12,51 UC1.AW2
  BOTTOM w0.102: 173.36,49.13 v1(174.18,48.31)
DC_TEST_AY3_AW3: length 0.7
  BOTTOM w0.081: UC1.AY3 169.52,51.49 UC1.AW3
DC_TEST_AY60: length 5.4
  BOTTOM w0.102: UC1.AY60 134.04,50.71 v1(131.22,47.89) 130.57,47.24 RC195.2
DC_TEST_AY61_AW61: length 0.7
  BOTTOM w0.081: UC1.AW61 133.37,51.45 UC1.AY61
DC_TEST_AY62_AW62: length 0.7
  BOTTOM w0.081: UC1.AY62 132.72,51.44 UC1.AW62
DC_TEST_B62_B63: length 0.7
  BOTTOM w0.081: UC1.B62 132.29,72.78 UC1.B63
DC_TEST_C1_C2: length 4.1
  BOTTOM w0.076: UC1.C2 170.66,72.25 UC1.C1 173.36,72.37
  BOTTOM w0.102: 173.36,72.37 v1(174.2,72.37)
DDI1_LANE_N0: length 173.1
  IN4 w0.089: v2(136.74,76.92) 136.99,77.16 137.08,77.16 137.34,77.43 137.34,77.84 138.59,79.08 139.55,79.08 148.28,87.82 178.81,87.82 179.49,87.14 191.23,87.14 191.91,87.82 201.65,87.82 204.16,90.33 219.16,90.33 221.38,92.56 231.05,92.56 233.95,89.65 233.95,88.88 234.61,88.23 235.39,88.23 236.6,87.02 236.6,84.49 244.75,76.33 261.97,76.33 264.48,73.82 277.73,73.82 278.63,74.73 285.14,74.73 v2(285.4,74.47)
  BOTTOM w0.081: UC1.C54 137.69,72.31 137.51,72.5 137.34,72.5 137.13,72.71 137.1,72.81 137.1,72.94 137.12,73 137.12,73 137.13,73.01 137.16,73.1 137.16,73.32 137.1,73.44 137.1,73.93 136.45,74.59 136.45,75.06 136.46,75.07 136.46,75.09
  BOTTOM w0.102: 136.46,75.09 136.46,76.78 136.59,76.92 v2(136.74,76.92) ; v2(285.4,74.47) 285.59,74.66 285.85,74.66 CV508.2
DDI1_LANE_N1: length 173.1
  IN4 w0.089: v2(134.89,76.62) 135.59,77.32 135.59,78.1 138.95,81.46 140.09,81.46 147.74,89.1 201.12,89.1 203.64,91.62 218.62,91.62 220.84,93.84 231.64,93.84 239.01,86.46 239.01,85.7 247.1,77.61 266.92,77.61 267.44,77.1 282.07,77.1 283.23,78.26 285.25,78.26 v2(285.4,78.11)
  BOTTOM w0.076: 134.52,76.26 134.52,76.25 134.5,76.23 134.5,75.95 134.77,75.68 134.77,74.95 135.55,74.17 135.55,72.89 135.85,72.59 135.85,72.46 135.55,72.16 135.43,72.16 135.35,72.24 135.35,72.44 UC1.B58
  BOTTOM w0.102: 134.52,76.26 134.52,76.54 134.62,76.64 134.87,76.64 v2(134.89,76.62) ; CV506.2 285.89,78.3 285.59,78.3 v2(285.4,78.11)
DDI1_LANE_N2: length 171.9
  IN4 w0.089: v2(137.12,75.05) 137.36,75.29 137.74,75.29 138.06,75.62 138.06,77.65 138.85,78.44 139.82,78.44 148.56,87.18 178.3,87.18 179.23,86.26 191.24,86.26 192.17,87.18 201.92,87.18 204.42,89.69 219.43,89.69 221.66,91.92 229.99,91.92 232.65,89.26 232.65,88.77 234.75,86.67 234.95,86.67 235.65,85.98 235.65,84.53 244.48,75.69 260.85,75.69 263.4,73.15 279.03,73.15 279.22,73.33 279.22,73.71 279.35,73.84 279.69,73.84 279.82,73.71 279.82,73.33 280.01,73.15 284.5,73.15 284.58,73.07 285.03,73.07 v2(285.44,72.65)
  BOTTOM w0.081: UC1.B55 137.39,73.06 137.48,73.15 137.63,73.15 137.87,73.4 137.87,74.24 137.69,74.43 137.17,74.43 136.84,74.75 136.84,74.98 136.9,75.05 v2(137.12,75.05)
  BOTTOM w0.102: v2(285.44,72.65) 285.6,72.81 285.86,72.81 CV504.2
DDI1_LANE_N3: length 171.8
  IN4 w0.089: v2(135.25,74.99) 135.49,75.22 135.63,75.22 136.26,75.84 136.26,77.78 138.2,79.72 139.27,79.72 148.01,88.46 179.45,88.46 180.13,87.78 190.96,87.78 191.64,88.46 201.39,88.46 203.9,90.98 218.89,90.98 221.11,93.2 231.36,93.2 237.94,86.62 237.94,85.87 246.83,76.97 263.62,76.97 264.72,75.88 267.66,75.88 267.92,76.14 278.37,76.14 278.45,76.06 283.55,76.06 284,76.51 285.22,76.51 v2(285.4,76.33)
  BOTTOM w0.081: UC1.A57 136.01,73.26 135.94,73.19 135.78,73.19 135.72,73.25 135.72,73.73 135.82,73.82 136.14,73.82 136.2,73.88 136.2,74.01 135.77,74.43 135.77,74.78 135.48,75.08 135.34,75.08 v2(135.25,74.99)
  BOTTOM w0.102: v2(285.4,76.33) 285.56,76.5 285.85,76.5 CV502.2
DDI1_LANE_P0: length 173.1
  IN4 w0.089: v2(136.74,77.5) 136.91,77.33 137.01,77.33 137.17,77.5 137.17,77.91 138.52,79.25 139.48,79.25 148.21,87.99 178.88,87.99 179.56,87.31 191.15,87.31 191.83,87.99 201.58,87.99 204.09,90.5 219.09,90.5 221.31,92.73 231.12,92.73 234.12,89.72 234.12,88.95 234.68,88.4 235.46,88.4 236.77,87.09 236.77,84.56 244.82,76.5 262.04,76.5 264.55,73.99 277.66,73.99 278.56,74.9 285.24,74.9 v2(285.4,75.05)
  BOTTOM w0.081: UC1.C55 137.07,72.48 136.98,72.63 136.93,72.79 136.93,72.97 136.95,73 136.95,73 137,73.13 137,73.23 136.93,73.4 136.91,73.43 136.91,73.86 136.26,74.51 136.26,75.06 136.25,75.07 136.25,75.09
  BOTTOM w0.102: 136.25,75.09 136.25,77 v2(136.74,77.5) ; v2(285.4,75.05) 285.59,74.86 285.93,74.86 CV507.2
DDI1_LANE_P1: length 173.2
  IN4 w0.089: v2(285.4,78.7) 285.13,78.43 283.16,78.43 282,77.27 267.51,77.27 266.99,77.78 247.17,77.78 239.18,85.77 239.18,86.53 231.71,94.01 220.76,94.01 218.55,91.8 203.57,91.8 201.05,89.27 147.67,89.27 140.02,81.63 138.88,81.63 135.42,78.17 135.42,77.39 135.23,77.21 v2(134.89,77.21)
  BOTTOM w0.076: UC1.C58 135.17,72.16 135.17,72.36 135.16,72.36 135.16,72.73 135.37,72.94 135.37,74.1 134.59,74.88 134.59,75.6 134.32,75.87 134.32,76.24 134.31,76.26 134.31,76.26
  BOTTOM w0.102: v2(134.89,77.21) 134.31,76.63 134.31,76.26 ; v2(285.4,78.7) 285.59,78.51 285.89,78.51 CV505.2
DDI1_LANE_P2: length 171.8
  IN4 w0.089: v2(136.91,75.67) 137.11,75.46 137.67,75.46 137.89,75.69 137.89,77.72 138.78,78.61 139.75,78.61 148.49,87.35 178.37,87.35 179.3,86.43 191.17,86.43 192.1,87.35 201.85,87.35 204.35,89.86 219.36,89.86 221.59,92.09 230.06,92.09 232.82,89.33 232.82,88.84 234.82,86.84 235.02,86.84 235.82,86.05 235.82,84.6 244.56,75.86 260.92,75.86 263.47,73.32 278.96,73.32 279.05,73.4 279.05,73.78 279.28,74.01 279.76,74.01 279.99,73.78 279.99,73.4 280.08,73.32 284.57,73.32 284.65,73.24 v2(285.44,73.24)
  BOTTOM w0.081: v2(136.91,75.67) 136.91,75.42 136.65,75.16 136.65,74.68 137.09,74.24 137.61,74.24 137.68,74.16 137.68,73.48 137.59,73.38 137.52,73.38 UC1.A55
  BOTTOM w0.102: v2(285.44,73.24) 285.66,73.02 285.92,73.02 CV503.2
DDI1_LANE_P3: length 171.8
  IN4 w0.089: v2(285.4,76.92) 285.16,76.68 283.93,76.68 283.48,76.23 278.52,76.23 278.44,76.31 267.85,76.31 267.59,76.05 264.79,76.05 263.7,77.14 246.9,77.14 238.11,85.94 238.11,86.69 231.43,93.37 221.04,93.37 218.82,91.15 203.83,91.15 201.32,88.63 191.57,88.63 190.89,87.95 180.2,87.95 179.52,88.63 147.94,88.63 139.2,79.89 138.13,79.89 136.09,77.85 136.09,75.91 135.56,75.39 135.43,75.39 135.41,75.41 135.41,75.41 v2(135.25,75.57)
  BOTTOM w0.081: v2(135.25,75.57) 135.96,74.86 135.96,74.51 136.39,74.09 136.39,73.37 136.01,72.99 UC1.B57
  BOTTOM w0.102: CV501.2 285.93,76.71 285.61,76.71 v2(285.4,76.92)
DDI2_LANE_N0: length 109.4
  TOP w0.102: CV72.1 228.62,88.77 228.78,88.93 228.78,89.21 v2(228.55,89.45)
  IN4 w0.089: v2(228.55,89.45) 228.92,89.83 228.92,89.92 228.85,90 222.49,90 220.25,87.75 205.91,87.75 203.41,85.25 194.16,85.25 193.24,84.34 192.56,84.34 191.92,83.7 180.45,83.7 180.26,83.88 180.26,84.2 180.13,84.33 179.95,84.33 179.82,84.2 179.82,83.88 179.63,83.7 179.22,83.7 179.03,83.88 179.03,84.17 178.9,84.3 178.72,84.3 178.59,84.17 178.59,83.88 178.4,83.7 177.96,83.7 177.77,83.89 177.77,84.21 177.7,84.28 177.27,84.28 177.19,84.19 177.19,84.02 176.96,83.79 176.63,83.79 176.4,84.02 176.4,84.19 176.31,84.28 173.12,84.28 171.58,82.73 167.06,82.73 166.19,83.6 164.04,83.6 163.7,83.94 160.05,83.94 158.39,85.6 147.9,85.6 140.04,77.74 139.4,77.74 v2(139.05,77.39)
  BOTTOM w0.081: UC1.C51 139.96,72.14 139.96,72.05 139.88,71.97 139.67,71.97 139.54,72.09 139.54,72.27 139.63,72.36 139.63,72.45 139.54,72.54 139.48,72.63 139.44,72.79 139.44,72.97 139.45,73 139.46,73 139.5,73.13 139.5,73.23 139.44,73.4 139.44,73.72 139.58,73.86 139.58,76.23 139.57,76.24 139.57,76.26
  BOTTOM w0.102: 139.57,76.26 139.57,77.72 139.55,77.74 139.39,77.74 139.05,77.4 v2(139.05,77.39)
DDI2_LANE_N0_C: length 2.6
  TOP w0.102: CV72.2 228.78,87.47 228.78,87.25 228.38,86.86 228.38,86.83 228.11,86.56 228.11,86.27 228.02,86.17 UV7.4
DDI2_LANE_N1: length 109
  TOP w0.102: v2(226.76,89.45) 226.97,89.23 226.97,88.94 226.8,88.77 CV74.1
  IN4 w0.089: v2(226.76,89.45) 226.79,89.45 227.2,89.04 227.2,88.96 226.16,87.92 224.64,87.92 223.87,87.16 222.32,87.16 221.05,85.89 213.94,85.89 212.48,84.43 205.09,84.43 203.82,83.16 199.85,83.16 199.45,82.77 197.71,82.77 195.64,80.69 188.33,80.69 187.76,81.26 176.83,81.26 176.41,81.69 175.36,81.69 174.58,80.9 168.34,80.9 167.9,80.47 166.65,80.47 166.11,81 160.08,81 159.82,80.75 148.09,80.75 146.06,78.71 144.09,78.71 142.94,77.57 142.94,74.77 142.49,74.32 139,74.32 138.62,74.7 138.62,76.26 138.74,76.38 139.16,76.38 139.23,76.31 139.23,76.16 v2(139.2,76.14)
  BOTTOM w0.081: 138.25,75.13 138.24,75.12 138.24,72.73 138.24,72.72 138.24,72.17 138.31,72.1 138.47,72.1 138.52,72.15 UC1.C53
  BOTTOM w0.102: 138.25,75.13 138.25,75.41 138.05,75.61 137.71,75.61 137.59,75.73 137.59,75.86 137.74,76.02 137.74,76.6 137.85,76.71 138.03,76.71 138.44,76.31 139.03,76.31 v2(139.2,76.14)
DDI2_LANE_N1_C: length 2.5
  TOP w0.102: UV7.7 226.82,86.8 227.14,87.12 227.14,87.43 226.71,87.85 CV74.2
DDI2_LANE_N2: length 109.6
  TOP w0.102: v2(224.99,89.45) 225.19,89.25 225.19,89.12 CV76.1
  IN4 w0.089: v2(224.99,89.45) 224.99,88.68 224.88,88.57 224.31,88.57 223.59,87.86 222.02,87.86 220.73,86.57 212.26,86.57 211.83,86.14 211.83,85.2 211.71,85.07 210.42,85.07 210.29,85.2 210.29,86.34 210.06,86.57 208.49,86.57 208.27,86.34 208.27,85.36 208.14,85.23 204.96,85.23 203.87,84.14 199.75,84.14 199.02,83.41 197.42,83.41 195.34,81.33 192.53,81.33 192.4,81.46 192.4,82.36 192.18,82.59 191.65,82.59 191.42,82.36 191.42,81.42 191.33,81.33 190.91,81.33 190.82,81.42 190.82,82.36 190.6,82.59 189.98,82.59 189.76,82.36 189.76,81.46 189.63,81.33 189.14,81.33 189.02,81.46 189.02,82.36 188.79,82.59 175.35,82.59 174.34,81.58 167.92,81.58 167.45,81.11 166.96,81.11 166.42,81.64 163.81,81.64 163.72,81.73 163.72,81.97 163.49,82.2 163.17,82.2 162.94,81.97 162.94,81.73 162.85,81.64 162.58,81.64 162.49,81.73 162.49,82.04 162.31,82.23 161.9,82.23 161.71,82.04 161.71,81.73 161.62,81.64 161.35,81.64 161.27,81.73 161.27,82.04 161.08,82.23 160.67,82.23 160.48,82.04 160.48,81.73 160.39,81.64 159.66,81.64 159.44,81.42 146.29,81.42 145.94,81.07 145.94,79.61 145.72,79.39 143.26,79.39 140.84,76.97 140.84,76.18 141.02,76 141.55,76 v2(141.65,75.89)
  BOTTOM w0.081: UC1.C49 140.97,72.16 140.85,72.16 140.74,72.26 140.74,72.41 140.74,73.62 141.17,74.05 141.17,74.99 141.18,75 141.18,75.02
  BOTTOM w0.102: v2(141.65,75.89) 141.55,76 141.47,76 141.18,75.71 141.18,75.02
DDI2_LANE_N2_C: length 2.6
  TOP w0.102: UV7.10 225.62,86.27 225.71,86.37 225.71,86.69 225.63,86.77 225.42,86.77 225.18,87.02 225.18,87.51 CV76.2
DDI2_LANE_N3: length 109.2
  TOP w0.102: v2(223.21,89.45) 223.43,89.23 223.43,89.14 CV78.1
  IN4 w0.089: v2(139.18,75.57) 139.18,75.42 139.26,75.34 139.33,75.34 139.35,75.32 139.56,75.32 139.96,75.73 139.96,77 145.15,82.19 147.37,82.19 147.63,82.45 147.63,84.68 147.86,84.91 148.68,84.91 148.9,84.68 148.9,82.52 149.03,82.4 149.75,82.4 149.87,82.51 149.87,84.83 150.09,85.06 150.76,85.06 150.99,84.83 150.99,82.92 151.13,82.78 152.61,82.78 152.74,82.91 152.74,84.75 153.12,85.13 158.09,85.13 160.27,82.96 166.13,82.96 166.82,82.26 174.12,82.26 175.09,83.23 192.17,83.23 192.67,83.73 194.78,83.73 195.83,84.78 203.61,84.78 205.67,86.84 207.64,86.84 208.02,87.22 220.47,87.22 221.74,88.5 223.04,88.5 223.47,88.93 223.47,89.19 v2(223.21,89.45)
  BOTTOM w0.081: UC1.A53 138.52,73.42 138.56,73.38 138.72,73.38 138.75,73.4 139.07,73.73 139.07,73.94 139.22,74.1 139.22,74.36 139.17,74.41 139.08,74.41 138.82,74.16 138.59,74.16 138.43,74.32 138.43,75.17 138.61,75.35 139.09,75.35 139.18,75.44 v2(139.18,75.57)
DDI2_LANE_N3_C: length 3
  TOP w0.102: UV7.13 224.42,86.27 224.51,86.37 224.51,86.51 v4(224.08,86.94) 224.08,86.94 223.89,87.13 223.74,87.13 223.47,87.4 223.47,87.72 223.34,87.85 CV78.2
DDI2_LANE_P0: length 109.4
  TOP w0.102: v2(229.13,89.45) 228.99,89.31 228.99,88.89 229.11,88.77 CV71.1
  IN4 w0.089: v2(139.05,77.97) 139.11,77.91 139.96,77.91 147.82,85.77 158.46,85.77 160.12,84.11 163.77,84.11 164.11,83.77 166.26,83.77 167.13,82.9 171.51,82.9 173.05,84.45 176.38,84.45 176.57,84.26 176.57,84.09 176.7,83.96 176.89,83.96 177.02,84.09 177.02,84.26 177.2,84.45 177.77,84.45 177.94,84.28 177.94,83.96 178.03,83.87 178.33,83.87 178.42,83.96 178.42,84.24 178.65,84.47 178.97,84.47 179.2,84.24 179.2,83.96 179.29,83.87 179.56,83.87 179.65,83.96 179.65,84.27 179.88,84.5 180.2,84.5 180.43,84.27 180.43,83.96 180.52,83.87 191.85,83.87 192.49,84.51 193.17,84.51 194.09,85.42 203.34,85.42 205.84,87.92 220.18,87.92 222.42,90.17 228.92,90.17 229.09,89.99 229.09,89.49 v2(229.13,89.45)
  BOTTOM w0.081: UC1.C50 140.19,72.33 140.02,72.5 139.84,72.5 139.64,72.71 139.61,72.81 139.61,72.94 139.63,73 139.64,73.01 139.64,73.01 139.67,73.1 139.67,73.32 139.61,73.44 139.61,73.65 139.77,73.81 139.77,76.23 139.78,76.24 139.78,76.26
  BOTTOM w0.102: 139.78,76.26 139.78,77.8 139.63,77.95 139.07,77.95 v2(139.05,77.97)
DDI2_LANE_P0_C: length 2.5
  TOP w0.102: UV7.3 228.42,86.17 228.32,86.27 228.32,86.47 v4(228.76,86.92) 228.76,86.92 228.98,87.14 228.98,87.55 CV71.2
DDI2_LANE_P1: length 109
  TOP w0.102: CV73.1 227.37,88.77 227.18,88.96 227.18,89.27 v2(227.37,89.45)
  IN4 w0.089: v2(138.86,76.74) 138.45,76.33 138.45,74.63 138.93,74.15 142.56,74.15 143.11,74.7 143.11,77.49 144.16,78.54 146.13,78.54 148.16,80.58 159.89,80.58 160.15,80.83 166.04,80.83 166.58,80.3 167.97,80.3 168.41,80.73 174.65,80.73 175.43,81.52 176.34,81.52 176.76,81.09 187.69,81.09 188.26,80.52 195.71,80.52 197.78,82.6 199.52,82.6 199.92,82.99 203.89,82.99 205.16,84.26 212.55,84.26 214.01,85.72 221.12,85.72 222.39,86.99 223.94,86.99 224.71,87.75 226.23,87.75 227.37,88.89 v2(227.37,89.45)
  BOTTOM w0.081: 138.04,75.14 138.05,75.13 138.05,72.87 137.98,72.81 137.73,72.81 137.63,72.71 137.63,72.61 137.75,72.49 137.91,72.49 UC1.B54
  BOTTOM w0.102: v2(138.86,76.74) 138.63,76.51 138.52,76.51 138.12,76.92 137.77,76.92 137.51,76.67 v4(137.51,76.38) 137.51,76.08 137.38,75.95 137.38,75.65 137.63,75.4 137.96,75.4 138.04,75.33 138.04,75.14
DDI2_LANE_P1_C: length 2.4
  TOP w0.102: CV73.2 227.35,87.69 227.35,87.04 227.02,86.72 227.02,86.51 227.22,86.32 UV7.6
DDI2_LANE_P2: length 109.6
  TOP w0.102: v2(225.57,89.45) 225.4,89.27 225.4,89.1 CV75.1
  IN4 w0.089: v2(225.57,89.45) 225.16,89.04 225.16,88.61 224.95,88.4 224.38,88.4 223.66,87.69 222.09,87.69 220.8,86.4 212.33,86.4 212,86.07 212,85.13 211.78,84.9 210.35,84.9 210.12,85.13 210.12,86.27 209.99,86.4 208.56,86.4 208.44,86.27 208.44,85.29 208.21,85.06 205.04,85.06 203.94,83.97 199.82,83.97 199.09,83.24 197.49,83.24 195.41,81.16 192.46,81.16 192.23,81.39 192.23,82.29 192.11,82.42 191.72,82.42 191.59,82.29 191.59,81.35 191.4,81.16 190.84,81.16 190.65,81.35 190.65,82.29 190.53,82.42 190.05,82.42 189.93,82.29 189.93,81.39 189.7,81.16 189.07,81.16 188.85,81.39 188.85,82.29 188.72,82.42 175.42,82.42 174.41,81.41 167.99,81.41 167.52,80.94 166.89,80.94 166.35,81.47 163.74,81.47 163.55,81.66 163.55,81.9 163.42,82.03 163.24,82.03 163.11,81.9 163.11,81.66 162.92,81.47 162.51,81.47 162.32,81.66 162.32,81.97 162.24,82.06 161.97,82.06 161.88,81.97 161.88,81.66 161.69,81.47 161.28,81.47 161.1,81.66 161.1,81.97 161.01,82.06 160.74,82.06 160.65,81.97 160.65,81.66 160.46,81.47 159.73,81.47 159.51,81.25 146.36,81.25 146.11,81 146.11,79.54 145.79,79.22 143.33,79.22 141.01,76.9 141.01,76.25 141.09,76.17 141.34,76.17 v2(141.65,76.48)
  BOTTOM w0.081: 140.97,75.02 140.97,75.01 140.98,75 140.98,74.13 140.56,73.7 140.56,72.94 140.5,72.88 140.4,72.88 140.29,72.78 140.29,72.63 140.4,72.53 UC1.B50
  BOTTOM w0.102: v2(141.65,76.48) 140.97,75.8 140.97,75.02
DDI2_LANE_P2_C: length 2.6
  TOP w0.102: UV7.9 226.02,86.27 225.92,86.36 225.92,86.78 225.71,86.98 225.51,86.98 225.38,87.11 225.38,87.51 CV75.2
DDI2_LANE_P3: length 109.4
  TOP w0.102: v2(223.8,89.45) 223.64,89.29 223.64,89.08 223.67,89.05 223.67,89.05 CV77.1
  IN4 w0.089: v2(139.18,74.98) 139.35,75.15 139.63,75.15 140.13,75.66 140.13,76.93 145.22,82.02 147.44,82.02 147.81,82.38 147.81,84.61 147.93,84.74 148.61,84.74 148.73,84.61 148.73,82.45 148.96,82.23 149.82,82.23 150.04,82.44 150.04,84.76 150.16,84.89 150.69,84.89 150.82,84.76 150.82,82.85 151.06,82.61 152.68,82.61 152.91,82.83 152.91,84.68 153.19,84.96 158.02,84.96 160.2,82.79 166.05,82.79 166.75,82.09 174.19,82.09 175.16,83.06 192.24,83.06 192.74,83.56 194.85,83.56 195.9,84.61 203.68,84.61 205.74,86.67 207.71,86.67 208.09,87.05 220.54,87.05 221.82,88.33 223.11,88.33 223.64,88.86 223.64,89.3 v2(223.8,89.45)
  BOTTOM w0.081: v2(139.18,74.98) 139,75.16 138.68,75.16 138.62,75.09 138.62,74.39 138.67,74.35 138.75,74.35 139,74.6 139.25,74.6 139.41,74.44 139.41,74.02 139.25,73.86 139.25,73.8 139.25,73.8 139.25,73.65 138.88,73.27 138.82,73.21 138.79,73.19 138.6,73.19 138.54,73.13 138.54,72.88 UC1.B53
DDI2_LANE_P3_C: length 2.8
  TOP w0.102: CV77.2 223.87,87.85 223.68,87.67 223.68,87.49 223.83,87.34 224,87.34 224.44,86.9 224.44,86.87 224.72,86.59 224.72,86.43 224.82,86.33 UV7.12
DDR3_DRAMRST#: length 174.4
  TOP w0.102: v2(94.42,12.81) 94.55,12.94 CD6.1 95.83,12.93 RD2.2 96.76,13.99 v1(96.56,14.2) ; CD35.1 169.01,9.64 v2(168.98,9.67)
  IN1 w0.089: v2(94.42,12.81) 95.31,11.91 95.31,9.68 96.07,8.92 140.71,8.92 142.55,10.77 148.02,10.77 149.8,8.98 168.29,8.98 v2(168.98,9.67)
  IN4 w0.089: v2(168.98,9.67) 169.53,9.12 182.43,9.12 183.07,9.75 183.07,21.37 176.46,27.98 176.46,36.61 175.7,37.38 175.7,37.58 170.13,43.15 169.61,43.15 165.29,47.47 165.29,49.95 164.65,50.58 164.65,50.77 164.91,51.03 164.91,51.21 164.68,51.45 164.5,51.45 163.76,50.71 163.58,50.71 163.34,50.94 163.34,51.12 163.58,51.36 163.58,51.66 163.45,51.79 163.19,51.79 163.07,51.92 163.07,52.3 163.19,52.43 163.7,52.43 163.83,52.55 163.83,52.81 163.7,52.93 163.32,52.93 163.19,53.06 163.19,54.9 163.07,55.03 162.75,55.03 162.62,54.9 162.62,53.06 162.49,52.93 162.11,52.93 161.99,52.81 161.99,52.42 v2(162.56,51.85)
  BOTTOM w0.076: 162.21,52.18 162.23,52.18 v2(162.56,51.85)
  BOTTOM w0.081: UC1.AV15 162.21,52.18
  BOTTOM w0.102: JDIMM1.30 87.7,12.37 88.13,12.81 v2(94.42,12.81) ; v2(168.98,9.67) 169.2,9.45 JDIMM2.30
DDR_A_BS0: length 76.9
  IN4 w0.089: 148.86,42.1 148.86,44.23 150.37,45.74 v2(150.37,49.02)
  IN4 w0.145: 148.86,42.1 148.86,36.47 146.34,33.95 146.34,33.74 147.29,32.79 147.29,32.61 147.06,32.38 146.89,32.38 145.92,33.35 145.74,33.35 145.47,33.08 145.47,32.9 146.39,31.98 146.39,31.7 136.59,21.9 116.25,21.9 115.55,21.21 115.55,18.67 115.43,18.54 115.2,18.54 115.07,18.41 115.07,18.08 115.2,17.96 115.43,17.96 115.55,17.83 115.55,17.4 115.41,17.25 115.01,17.25 114.87,17.11 114.87,16.82 115.01,16.68 115.41,16.68 115.55,16.53 115.55,15.75 115.43,15.62 114.28,15.62 114.16,15.75 114.16,18.64 114.28,18.77 v2(114.62,18.77)
  BOTTOM w0.081: UC1.AU35 149.88,52.73 149.53,52.37 149.53,52.08 149.47,52.02 149.47,49.93 v2(150.37,49.02)
  BOTTOM w0.168: v2(114.62,18.77) 113.8,17.95 JDIMM1.109
DDR_A_BS1: length 77.9
  IN4 w0.089: 149.26,42.1 149.26,44.24 150.73,45.72 150.73,49.22 v2(150.37,49.58)
  IN4 w0.145: v2(114.6,11.9) 115.88,11.9 116.01,12.03 116.01,12.42 115.88,12.55 115.16,12.55 115.03,12.67 115.03,13.07 115.16,13.2 115.86,13.2 116.01,13.35 116.01,13.64 115.86,13.78 115.25,13.78 115.12,13.91 115.12,14.3 115.25,14.43 115.82,14.43 115.95,14.55 115.95,15.37 116.08,15.5 116.72,15.5 116.85,15.63 116.85,16.08 116.72,16.2 116.08,16.2 115.95,16.33 115.95,21.04 116.41,21.5 136.76,21.5 147.81,32.56 147.81,32.83 146.92,33.73 146.92,33.96 149.26,36.3 149.26,42.1
  BOTTOM w0.081: UC1.AV35 149.64,51.88 149.64,50.31 v2(150.37,49.58)
  BOTTOM w0.168: JDIMM1.108 113.5,10.8 v2(114.6,11.9)
DDR_A_BS2: length 75.8
  IN4 w0.089: 139.93,42.1 139.93,42.95 145.09,48.12 145.09,50.09 v2(145.61,50.61)
  IN4 w0.145: v2(102.4,20.3) 102.89,20.78 102.89,23.87 109.18,30.16 129.49,30.16 133.4,34.07 133.4,34.28 133.05,34.63 133.05,34.83 133.25,35.04 133.46,35.04 133.81,34.69 134.01,34.69 134.22,34.89 134.22,35.1 133.87,35.45 133.87,35.65 134.07,35.86 134.28,35.86 134.63,35.51 134.83,35.51 135.04,35.71 135.04,35.92 134.69,36.27 134.69,36.47 134.89,36.68 135.09,36.68 135.45,36.33 135.65,36.33 135.84,36.52 135.84,36.72 135.48,37.09 135.48,37.27 135.71,37.5 135.89,37.5 136.25,37.13 136.46,37.13 136.66,37.34 136.66,37.54 136.3,37.91 136.3,38.09 136.53,38.32 136.71,38.32 137.07,37.95 137.28,37.95 137.48,38.16 137.48,38.36 137.12,38.73 137.12,38.91 137.35,39.14 137.53,39.14 137.89,38.77 138.1,38.77 138.3,38.98 138.3,39.18 137.94,39.55 137.94,39.72 138.17,39.96 138.35,39.96 138.71,39.59 138.92,39.59 139.12,39.8 139.12,40 138.76,40.36 138.76,40.54 138.99,40.77 139.17,40.77 139.53,40.41 139.74,40.41 139.93,40.6 139.93,40.87 139.55,41.24 139.55,41.34 139.93,41.72 139.93,42.1
  BOTTOM w0.081: UC1.AY41 145.88,50.88 v2(145.61,50.61)
  BOTTOM w0.168: JDIMM1.79 104.8,17.92 102.43,20.3 v2(102.4,20.3)
DDR_A_CAS#: length 77.3
  IN4 w0.089: 150.45,42.1 150.45,42.21 151.64,43.4 151.64,51.25 v2(150.36,52.53)
  IN4 w0.145: 150.45,42.1 150.45,33.51 150.2,33.26 150.2,33.07 150.45,32.82 150.45,32.46 150.28,32.28 150.07,32.28 149.74,32.62 149.56,32.62 149.28,32.34 149.28,32.16 149.75,31.69 149.75,31.51 149.5,31.27 149.36,31.27 148.88,31.75 148.7,31.75 148.38,31.44 148.38,31.26 148.78,30.86 148.78,30.54 141.52,23.28 141.52,23.08 141.92,22.68 141.92,22.5 141.69,22.27 141.51,22.27 141.11,22.67 140.91,22.67 140.7,22.47 140.7,22.26 141.54,21.42 141.54,21.22 141.34,21.01 141.13,21.01 140.29,21.85 140.09,21.85 139.88,21.65 139.88,21.44 140.72,20.6 140.72,20.4 140.52,20.19 140.31,20.19 139.47,21.03 139.27,21.03 138.58,20.34 138.58,17.63 138.13,17.18 117.17,17.18 117,17.35 117,18.34 v2(116.57,18.77)
  BOTTOM w0.081: v2(150.36,52.53) 150.66,52.83 UC1.AU34
  BOTTOM w0.168: v2(116.57,18.77) 116.34,18.77 115.6,18.04 JDIMM1.115
DDR_A_D0: length 58.6
  IN1 w0.089: v2(129.75,58.68) 129.75,58.28 125.91,54.45 125.91,50.95 123.14,48.18 123.14,47.72 120.63,45.21 120.63,27.88 120.54,27.79 120.3,27.79 120.18,27.66 120.18,27.42 120.3,27.3 120.54,27.3 120.63,27.21 120.63,26.89 120.54,26.8 119.78,26.8 119.69,26.71 119.69,26.39 119.78,26.31 120.54,26.31 120.63,26.22 120.63,25.9 120.54,25.81 119.78,25.81 119.69,25.72 119.69,25.4 119.78,25.32 120.54,25.32 120.63,25.23 120.63,24.91 120.54,24.82 119.78,24.82 119.69,24.73 119.69,24.41 119.78,24.32 120.54,24.32 120.63,24.24 120.63,23.92 120.54,23.83 119.78,23.83 119.69,23.74 119.69,23.42 119.78,23.33 120.54,23.33 120.63,23.25 120.63,22.93 120.54,22.84 119.78,22.84 119.69,22.75 119.69,22.43 119.78,22.34 120.54,22.34 120.63,22.25 120.63,21.77 120.5,21.63 120.05,21.63 119.9,21.48 119.9,18.41 v2(120.3,18.01)
  BOTTOM w0.076: UC1.AH63 131.9,58.23 131.77,58.1 130.32,58.1 v2(129.75,58.68)
  BOTTOM w0.102: v2(120.3,18.01) 119.8,17.51 JDIMM1.129
DDR_A_D1: length 59.4
  IN1 w0.089: v2(120.3,19.53) 120.3,19.28 120.43,19.15 120.82,19.15 120.95,19.28 120.95,41.04 121.04,41.13 121.85,41.13 121.98,41.25 121.98,41.49 121.85,41.62 121.04,41.62 120.95,41.71 120.95,42.03 121.04,42.12 121.99,42.12 122.12,42.24 122.12,42.48 121.99,42.61 121.04,42.61 120.95,42.7 120.95,43.02 121.04,43.11 121.99,43.11 122.12,43.23 122.12,43.47 121.99,43.6 121.04,43.6 120.95,43.69 120.95,44.01 121.04,44.1 121.99,44.1 122.12,44.22 122.12,44.47 121.99,44.59 121.04,44.59 120.95,44.68 120.95,45.08 121.26,45.39 121.6,45.39 121.82,45.17 121.99,45.17 122.12,45.3 122.12,46.25 123.46,47.59 123.46,48.05 126.23,50.82 126.23,54.31 130.3,58.39 v2(130.3,58.68)
  BOTTOM w0.076: v2(130.3,58.68) 130.72,58.26 131.7,58.26 131.96,58.52 132.23,58.52 132.4,58.43 132.6,58.23 UC1.AH62
  BOTTOM w0.102: v2(120.3,19.53) 120.74,19.1 120.74,17.83 120.4,17.5 JDIMM1.131
DDR_A_D2: length 57.9
  IN1 w0.076: v2(129.94,56.51) 131.41,56.51 132.25,55.67 132.25,54.85 129.73,52.33 129.73,52.27
  IN1 w0.089: 129.73,52.27 128.97,51.5 128.97,50.07 125.93,47.02 125.93,46.57 124.71,45.35 124.71,28.4 124.62,28.31 124.37,28.31 124.29,28.24 124.29,27.89 124.37,27.82 124.62,27.82 124.71,27.73 124.71,27.42 124.62,27.33 124.09,27.33 124.01,27.25 124.01,26.91 124.09,26.84 124.62,26.84 124.71,26.75 124.71,26.43 124.62,26.34 124.1,26.34 124.01,26.25 124.01,25.93 124.1,25.85 124.62,25.85 124.71,25.76 124.71,25.44 124.62,25.35 124.1,25.35 124.01,25.26 124.01,24.94 124.1,24.85 124.62,24.85 124.71,24.77 124.71,24.45 124.62,24.36 124.1,24.36 124.01,24.27 124.01,23.95 124.1,23.86 124.62,23.86 124.71,23.77 124.71,23.46 124.62,23.37 124.1,23.37 124.01,23.28 124.01,22.96 124.1,22.87 124.62,22.87 124.71,22.78 124.71,22.47 124.62,22.38 124.1,22.38 124.01,22.29 124.01,21.97 124.1,21.88 124.62,21.88 124.71,21.79 124.71,21.48 124.62,21.39 124.1,21.39 124.01,21.3 124.01,20.98 124.1,20.89 124.62,20.89 124.71,20.8 124.71,19.24 124.63,19.16 124.19,19.16 124.11,19.24 v2(124.11,19.53)
  BOTTOM w0.076: v2(129.94,56.51) 130.46,56.51 130.51,56.55 131.56,56.55 131.76,56.75 132.03,56.75 UC1.AK63
  BOTTOM w0.102: JDIMM1.141 123.4,18.82 v2(124.11,19.53)
DDR_A_D3: length 58.3
  IN1 w0.076: v2(129.27,55.67) 131.68,55.67 131.87,55.48 131.87,54.81 129.53,52.47
  IN1 w0.089: v2(122.53,9.61) 123.23,10.31 123.23,18.37 123.69,18.83 123.69,28.09 124.39,28.78 124.39,45.48 125.61,46.7 125.61,47.15 128.65,50.2 128.65,51.59 129.53,52.47
  BOTTOM w0.076: UC1.AK62 132.57,56.88 132.28,56.59 131.83,56.59 131.62,56.37 130.57,56.37 129.86,55.67 v2(129.27,55.67)
  BOTTOM w0.102: v2(122.53,9.61) 122.95,9.61 123.1,9.46 JDIMM1.140
DDR_A_D4: length 59.7
  IN1 w0.089: v2(120.64,9.61) 120.24,10.01 120.24,13.31 120.33,13.4 120.78,13.4 120.87,13.49 120.87,13.81 120.78,13.9 120.33,13.9 120.24,13.98 120.24,14.3 120.33,14.39 120.6,14.39 120.72,14.52 120.72,14.76 120.6,14.89 120.33,14.89 120.24,14.98 120.24,15.62 121.26,16.64 121.26,40.09 122.43,41.26 122.43,46.12 123.77,47.46 123.77,47.92 126.55,50.69 126.55,54.17 130.88,58.5 v2(130.88,58.68)
  BOTTOM w0.076: v2(130.88,58.68) 131.12,58.44 131.64,58.44 131.89,58.69 132.27,58.69 132.41,58.61 133.07,58.61 UC1.AH61
  BOTTOM w0.102: JDIMM1.132 120.7,9.55 v2(120.64,9.61)
DDR_A_D5: length 60.3
  IN1 w0.089: v2(130.76,57.23) 130.74,57.25 130.08,57.25 126.86,54.03 126.86,50.56 124.09,47.78 124.09,47.33 122.75,45.99 122.75,41.12 121.58,39.95 121.58,15.92 121.19,15.52 121.19,14.43 121.28,14.34 121.6,14.34 121.73,14.22 121.73,13.97 121.6,13.85 121.28,13.85 121.19,13.76 121.19,13.4 121.28,13.31 121.69,13.31 121.81,13.18 121.81,12.94 121.69,12.81 121.28,12.81 121.19,12.73 121.19,11.68 v2(120.64,11.14)
  BOTTOM w0.076: UC1.AH60 134.11,57.46 133.9,57.26 133.66,57.26 133.64,57.28 133.27,57.28 133.25,57.26 133.07,57.26 132.92,57.33 132.69,57.33 132.54,57.26 132.42,57.26 132.31,57.31 132.31,57.31 132.26,57.33 131.97,57.33 131.71,57.08 131.62,57.08 131.45,56.91 131.01,56.91 130.76,57.16 v2(130.76,57.23)
  BOTTOM w0.102: JDIMM1.130 120.1,10.6 v2(120.64,11.14)
DDR_A_D6: length 58.7
  IN1 w0.076: 129.91,52.1 129.91,52.15 131.94,54.18 131.94,54.25 132.52,54.83 132.52,55.92 131.56,56.87 v2(130.35,56.87)
  IN1 w0.089: v2(124.11,18.01) 123.93,18.01 123.54,17.63 123.54,15.63 123.62,15.56 124.95,15.56 125.02,15.63 125.02,16.07 124.95,16.15 124.14,16.15 124.06,16.22 124.06,16.57 124.14,16.64 124.93,16.64 125.02,16.73 125.02,17.05 124.93,17.14 124.51,17.14 124.43,17.21 124.43,17.56 124.51,17.63 124.93,17.63 125.02,17.72 125.02,18.04 124.93,18.13 124.67,18.13 124.6,18.2 124.6,18.55 124.67,18.62 124.93,18.62 125.02,18.71 125.02,45.21 126.24,46.43 126.24,46.89 129.27,49.92 129.27,51.46 129.91,52.1
  BOTTOM w0.076: UC1.AK61 133.11,56.98 132.98,57.12 132.89,57.16 132.72,57.16 132.64,57.12 132.58,57.09 132.38,57.09 132.22,57.17 132.03,57.17 131.78,56.92 131.69,56.92 131.51,56.73 130.49,56.73 v2(130.35,56.87)
  BOTTOM w0.102: v2(124.11,18.01) 124,17.9 JDIMM1.143
DDR_A_D7: length 60.4
  IN1 w0.076: 130,53.21 131.42,54.63 131.42,54.63 131.63,54.84 131.63,54.84 131.64,54.85 131.64,55.12 131.63,55.13 131.42,55.34 131.13,55.34 131.13,55.34 129.67,55.34 129.49,55.16 v2(128.95,55.16)
  IN1 w0.089: 130,53.21 129.82,53.21 128.34,51.72 128.34,50.33 125.29,47.29 125.29,46.83 124.07,45.61 124.07,28.91 123.37,28.22 123.37,19.01 122.13,17.77 122.13,11.54 v2(122.53,11.14)
  BOTTOM w0.076: UC1.AK60 133.87,56.98 133.58,56.69 133.03,56.69 132.93,56.59 132.51,56.59 132.35,56.42 131.9,56.42 131.69,56.21 130.66,56.21 129.88,55.43 129.6,55.43 129.33,55.16 v2(128.95,55.16)
  BOTTOM w0.102: JDIMM1.142 123.7,9.97 v2(122.53,11.14)
DDR_A_D8: length 84.5
  IN4 w0.089: v2(79.12,19.53) 79.12,19.24 79.2,19.16 79.47,19.16 79.55,19.24 79.55,24.61 101.49,46.55 115.79,46.55 116.43,47.18 117.61,47.18 117.69,47.25 117.69,48.19 117.76,48.26 118.14,48.26 118.22,48.17 118.22,47.27 118.31,47.18 118.63,47.18 118.72,47.27 118.72,48.17 118.81,48.26 119.13,48.26 119.22,48.17 119.22,47.27 119.3,47.18 119.62,47.18 119.71,47.27 119.71,48.17 119.8,48.26 120.02,48.26 120.1,48.35 120.1,48.75 120.18,48.83 120.52,48.83 120.6,48.75 120.6,48.35 120.69,48.26 121.01,48.26 121.09,48.35 121.09,48.89 121.18,48.98 121.5,48.98 121.59,48.89 121.59,48.35 121.68,48.26 122,48.26 122.09,48.35 122.09,48.89 122.17,48.98 122.49,48.98 122.58,48.89 122.58,48.35 122.67,48.26 123.11,48.26 123.19,48.34 123.19,48.92 123.26,49 124.41,49 126.63,51.21 126.63,51.76 128.4,53.53 129.6,53.53 v2(129.62,53.52)
  BOTTOM w0.076: UC1.AM63 132.07,55.71 130.92,55.71 130.13,54.93 130.13,54.59 129.62,54.07 v2(129.62,53.52)
  BOTTOM w0.102: v2(79.12,19.53) 80.8,17.85 JDIMM1.7
DDR_A_D9: length 85.4
  IN4 w0.089: v2(128.37,52.36) 128.37,51.61 122.99,46.23 122.24,46.23 122.16,46.3 122.16,47.23 122.08,47.31 120.93,47.31 120.84,47.22 120.84,46.33 120.74,46.23 116.82,46.23 116.19,45.59 101.88,45.59 80.51,24.23 80.51,11.22 v2(79.25,9.96)
  BOTTOM w0.076: 128.53,53.37 129.91,54.74 129.91,54.95 130.83,55.88 131.82,55.88 132.03,56.09 132.28,56.09 132.57,55.8 UC1.AM62
  BOTTOM w0.102: 128.53,53.37 128.37,53.21 v2(128.37,52.36) ; v2(79.25,9.96) 79.9,9.3 JDIMM1.4
DDR_A_D10: length 84.3
  IN4 w0.089: v2(82.71,19.53) 82.71,19.28 82.84,19.15 83.25,19.15 83.38,19.28 83.38,20.7 83.29,20.78 82.75,20.78 82.66,20.87 82.66,21.19 82.75,21.28 83.29,21.28 83.38,21.37 83.38,21.69 83.29,21.78 82.75,21.78 82.66,21.86 82.66,22.18 82.75,22.27 83.29,22.27 83.38,22.36 83.38,22.68 83.29,22.77 82.75,22.77 82.66,22.85 82.66,23.17 82.75,23.26 83.29,23.26 83.38,23.35 83.38,24.45 88.98,30.05 88.98,30.18 88.88,30.27 88.88,30.45 89.06,30.62 89.23,30.62 89.3,30.55 89.48,30.55 89.65,30.72 89.65,30.9 89.58,30.97 89.58,31.15 89.76,31.32 89.94,31.32 90,31.25 90.18,31.25 90.33,31.4 90.33,31.58 90.25,31.66 90.25,31.78 90.48,32.01 90.6,32.01 90.71,31.9 90.83,31.9 91.06,32.13 91.06,32.25 90.95,32.36 90.95,32.48 91.18,32.71 91.3,32.71 91.41,32.6 91.53,32.6 91.76,32.83 91.76,32.95 91.65,33.06 91.65,33.18 91.88,33.41 92,33.41 92.12,33.3 92.23,33.3 92.47,33.54 92.47,33.65 92.33,33.79 92.33,33.89 92.57,34.14 92.68,34.14 92.82,34 92.93,34 93.17,34.24 93.17,34.35 93.03,34.49 93.03,34.59 93.27,34.84 93.38,34.84 93.52,34.7 93.63,34.7 93.87,34.94 93.87,35.05 93.73,35.19 93.73,35.29 93.97,35.54 94.08,35.54 94.21,35.41 94.34,35.41 94.56,35.63 94.56,35.76 94.43,35.89 94.43,36 94.67,36.24 94.78,36.24 94.91,36.11 95.04,36.11 95.26,36.33 95.26,36.46 95.17,36.55 95.17,36.73 95.34,36.9 95.52,36.9 95.61,36.81 95.74,36.81 95.96,37.03 95.96,37.16 95.83,37.29 95.83,37.4 96.07,37.64 96.18,37.64 96.31,37.51 96.44,37.51 96.66,37.73 96.66,37.86 96.53,37.99 96.53,38.1 96.77,38.34 96.88,38.34 97.01,38.21 97.14,38.21 97.36,38.43 97.36,38.56 97.23,38.69 97.23,38.8 97.47,39.04 97.58,39.04 97.72,38.9 97.83,38.9 98.07,39.14 98.07,39.25 97.93,39.39 97.93,39.5 98.18,39.74 98.28,39.74 98.41,39.61 98.54,39.61 100.18,41.25 100.18,41.38 100.06,41.5 100.06,41.62 100.29,41.85 100.41,41.85 100.53,41.73 100.66,41.73 100.88,41.95 100.88,42.08 100.76,42.2 100.76,42.33 100.99,42.55 101.11,42.55 101.23,42.43 101.36,42.43 101.58,42.65 101.58,42.78 101.46,42.9 101.46,43.03 101.69,43.25 101.81,43.25 101.93,43.13 102.06,43.13 102.28,43.35 102.28,43.48 102.16,43.6 102.16,43.73 102.39,43.95 102.51,43.95 102.63,43.83 102.76,43.83 103.01,44.08 116.82,44.08 117.45,44.71 123.77,44.71 130.1,51.05 v2(130.1,51.48)
  BOTTOM w0.076: UC1.AP63 131.77,54.45 130.1,52.77 v2(130.1,51.48)
  BOTTOM w0.102: v2(82.71,19.53) 83.8,18.45 JDIMM1.17
DDR_A_D11: length 84.6
  IN4 w0.089: v2(130.89,52.5) 130.89,51.38 123.9,44.39 117.58,44.39 116.95,43.76 103.14,43.76 83.7,24.32 83.7,15.66 83.79,15.57 84.08,15.57 84.17,15.48 84.17,15.16 84.08,15.07 83.79,15.07 83.7,14.98 83.7,14.67 83.79,14.58 84.08,14.58 84.17,14.49 84.17,14.17 84.08,14.08 83.79,14.08 83.7,13.99 83.7,13.67 83.79,13.59 84.08,13.59 84.17,13.5 84.17,13.18 84.08,13.09 83.79,13.09 83.7,13 83.7,12.89 83.61,12.8 83.09,12.8 83,12.72 83,12.4 83.09,12.31 83.61,12.31 83.7,12.22 83.7,11.9 83.61,11.81 83.13,11.81 83.04,11.73 83.04,11.41 83.13,11.32 83.61,11.32 83.7,11.23 83.7,10.91 83.61,10.82 83.13,10.82 83.04,10.73 83.04,10.42 83.13,10.33 83.61,10.33 83.7,10.24 83.7,10.23 v2(84.1,9.83)
  BOTTOM w0.076: UC1.AP62 132.57,54.45 132.31,54.19 132.3,54.19 132.27,54.15 131.74,54.15 130.89,53.31 v2(130.89,52.5)
  BOTTOM w0.102: JDIMM1.18 84.1,9.82 v2(84.1,9.83)
DDR_A_D12: length 85.8
  IN4 w0.089: v2(127.97,51.9) 127.96,51.9 127.96,51.65 123.94,47.63 123.17,47.63 123.06,47.51 123.06,47.33 122.98,47.26 122.55,47.26 122.48,47.33 122.48,47.52 122.37,47.63 120.6,47.63 120.52,47.55 120.52,46.62 120.45,46.54 116.69,46.54 116.06,45.91 101.75,45.91 80.2,24.36 80.2,12.43 v2(79.25,11.48)
  BOTTOM w0.076: 128.53,53.84 129.42,54.72 129.42,54.72 130.74,56.04 131.76,56.04 131.97,56.26 132.35,56.26 132.51,56.09 132.93,56.09 133.33,55.69 UC1.AM61
  BOTTOM w0.102: JDIMM1.6 80.5,10.22 v2(79.25,11.48) ; v2(127.97,51.9) 127.97,53.27 128.53,53.84
DDR_A_D13: length 86.2
  IN4 w0.089: v2(129.23,53.13) 128.45,53.13 126.95,51.63 126.95,51.08 123.81,47.94 120.21,47.94 120.12,47.86 120.12,46.94 120.04,46.86 116.56,46.86 115.93,46.23 101.62,46.23 79.88,24.49 79.88,18.75 79.79,18.66 79.55,18.66 79.47,18.58 79.47,18.24 79.55,18.16 79.79,18.16 79.88,18.07 79.88,17.76 79.79,17.67 79.46,17.67 79.39,17.59 79.39,17.25 79.46,17.17 79.79,17.17 79.88,17.08 79.88,16.77 79.79,16.68 79.36,16.68 79.28,16.6 79.28,16.26 79.36,16.18 79.79,16.18 79.88,16.09 79.88,15.43 79.8,15.35 78.81,15.35 78.74,15.43 78.74,17.63 v2(79.12,18.01)
  BOTTOM w0.076: UC1.AM60 134.11,55.03 133.9,54.83 133.07,54.83 132.91,54.9 132.7,54.9 132.65,54.88 132.55,54.83 132.41,54.83 132.26,54.9 131.72,54.9 130.23,53.4 130.02,53.4 129.75,53.13 v2(129.23,53.13)
  BOTTOM w0.102: JDIMM1.5 80.2,17.49 79.68,18.01 v2(79.12,18.01)
DDR_A_D14: length 84.8
  IN4 w0.089: v2(82.71,18.01) 83.06,18.01 83.18,17.88 83.18,17.46 83.06,17.33 81.99,17.33 81.87,17.46 81.87,18.47 81.99,18.59 82.19,18.59 82.31,18.72 82.31,18.96 82.19,19.08 81.96,19.08 81.87,19.17 81.87,19.49 81.96,19.58 82.23,19.58 82.31,19.67 82.31,19.99 82.23,20.07 81.96,20.07 81.87,20.16 81.87,20.48 81.96,20.57 82.23,20.57 82.31,20.66 82.31,20.98 82.23,21.06 81.96,21.06 81.87,21.15 81.87,21.47 81.96,21.56 82.23,21.56 82.31,21.65 82.31,21.97 82.23,22.06 81.96,22.06 81.87,22.14 81.87,22.46 81.96,22.55 82.23,22.55 82.31,22.64 82.31,22.87 82.19,23 81.99,23 81.87,23.13 81.87,23.45 81.99,23.58 82.94,23.58 83.06,23.71 83.06,23.98 82.94,24.1 82.45,24.1 82.37,24.18 82.37,24.38 82.59,24.6 83.08,24.6 83.43,24.95 83.43,25.1 83.32,25.22 83.32,25.33 83.55,25.56 83.67,25.56 83.8,25.44 83.92,25.44 84.15,25.67 84.15,25.79 84.02,25.91 84.02,26.04 84.25,26.26 84.37,26.26 84.5,26.14 84.62,26.14 84.85,26.37 84.85,26.49 84.72,26.61 84.72,26.74 84.95,26.96 85.07,26.96 85.2,26.84 85.32,26.84 85.55,27.07 85.55,27.19 85.43,27.31 85.43,27.44 85.65,27.66 85.78,27.66 85.9,27.54 86.02,27.54 86.25,27.77 86.25,27.89 86.13,28.01 86.13,28.14 86.35,28.36 86.48,28.36 86.6,28.24 86.72,28.24 86.95,28.47 86.95,28.59 86.83,28.72 86.83,28.84 87.05,29.07 87.18,29.07 87.3,28.94 87.42,28.94 87.65,29.17 87.65,29.29 87.53,29.42 87.53,29.54 87.75,29.77 87.88,29.77 88,29.64 88.12,29.64 88.35,29.87 88.35,29.99 88.23,30.12 88.23,30.24 98.14,40.16 98.64,40.16 99.38,40.9 99.38,41.39 102.38,44.39 116.69,44.39 117.32,45.03 123.49,45.03 v2(129.64,51.18)
  BOTTOM w0.076: UC1.AP61 133.22,54.45 132.98,54.69 132.89,54.73 132.72,54.73 132.64,54.69 132.58,54.67 132.37,54.67 132.33,54.69 132.32,54.69 132.22,54.74 131.81,54.74 129.64,52.57 v2(129.64,51.18)
  BOTTOM w0.102: JDIMM1.15 83.2,17.71 82.91,18.01 v2(82.71,18.01)
DDR_A_D15: length 85.3
  IN4 w0.089: v2(84.1,11.35) 85.32,12.57 85.32,13.37 85.2,13.49 84.59,13.49 84.5,13.58 84.5,13.9 84.59,13.99 85.47,13.99 85.56,14.08 85.56,14.39 85.47,14.48 84.59,14.48 84.5,14.57 84.5,14.89 84.59,14.98 85.47,14.98 85.56,15.07 85.56,15.39 85.47,15.47 84.59,15.47 84.5,15.56 84.5,15.78 84.02,16.26 84.02,24.19 103.27,43.44 117.08,43.44 117.71,44.07 124.03,44.07 131.32,51.37 v2(131.32,52.86)
  BOTTOM w0.076: UC1.AP60 133.88,54.22 133.64,54.22 133.58,54.15 132.51,54.15 132.38,54.02 132.37,54.02 132.34,53.99 131.83,53.99 131.32,53.49 v2(131.32,52.86)
  BOTTOM w0.102: v2(84.1,11.35) 83.5,10.76 JDIMM1.16
DDR_A_D16: length 53.3
  IN1 w0.076: 129.42,45.14 130.21,45.94 130.21,47.89 133.77,51.45 134.13,51.45 135.3,52.62 135.3,53.94 v2(134.93,54.31)
  IN1 w0.089: v2(128.44,18.01) 128.42,17.99 128.42,15.61 128.04,15.23 128.04,14.19 128.14,14.09 128.61,14.09 128.9,14.38 128.9,15.5 129.18,15.78 129.18,16.23 129.09,16.32 129,16.32 128.91,16.41 128.91,16.72 129,16.81 129.09,16.81 129.18,16.9 129.18,17.22 129.09,17.31 129,17.31 128.91,17.4 128.91,17.71 129,17.8 129.09,17.8 129.18,17.89 129.18,18.21 129.09,18.3 128.95,18.3 128.83,18.42 128.83,18.67 128.95,18.79 129.09,18.79 129.18,18.88 129.18,20.85 128.74,21.3 128.74,30.96 128.82,31.05 129.18,31.05 129.31,31.17 129.31,31.41 129.18,31.54 128.82,31.54 128.74,31.63 128.74,31.95 128.82,32.04 129.18,32.04 129.31,32.16 129.31,32.45 129.23,32.53 129.09,32.53 129.01,32.61 129.01,32.95 129.09,33.03 129.24,33.03 129.31,33.1 129.31,45.04 129.42,45.14
  BOTTOM w0.081: v2(134.93,54.31) 135.25,54.64 UC1.AP58
  BOTTOM w0.102: JDIMM1.159 128.8,17.65 v2(128.44,18.01)
DDR_A_D17: length 53.2
  IN1 w0.076: v2(134.93,53.66) 134.93,52.49 134.06,51.62 133.68,51.62 130.03,47.98 130.03,46.21 129.42,45.59
  IN1 w0.089: v2(128.44,19.53) 128.44,19.28 128.57,19.15 128.74,19.15 128.86,19.28 128.86,20.62 128.79,20.69 128.49,20.69 128.42,20.77 128.42,32.1 128.69,32.37 128.69,32.71 128.62,32.78 128.52,32.78 128.42,32.88 128.42,33.16 128.55,33.29 128.9,33.29 128.99,33.38 128.99,33.69 128.9,33.78 128.51,33.78 128.42,33.87 128.42,34.19 128.51,34.28 128.9,34.28 128.99,34.37 128.99,34.68 128.9,34.77 128.51,34.77 128.42,34.86 128.42,35.18 128.51,35.27 128.9,35.27 128.99,35.36 128.99,35.67 128.9,35.76 128.51,35.76 128.42,35.85 128.42,36.25 128.51,36.34 128.9,36.34 128.99,36.42 128.99,36.74 128.9,36.83 128.51,36.83 128.42,36.92 128.42,37.24 128.51,37.33 128.9,37.33 128.99,37.41 128.99,37.73 128.9,37.82 128.51,37.82 128.42,37.91 128.42,38.23 128.51,38.32 128.9,38.32 128.99,38.41 128.99,38.72 128.9,38.81 128.51,38.81 128.42,38.9 128.42,39.22 128.51,39.31 128.9,39.31 128.99,39.4 128.99,39.71 128.9,39.8 128.51,39.8 128.42,39.89 128.42,40.21 128.51,40.3 128.9,40.3 128.99,40.39 128.99,40.7 128.9,40.79 128.51,40.79 128.42,40.88 128.42,41.2 128.51,41.29 128.9,41.29 128.99,41.38 128.99,41.69 128.9,41.78 128.51,41.78 128.42,41.87 128.42,42.19 128.51,42.28 128.9,42.28 128.99,42.37 128.99,42.69 128.9,42.77 128.51,42.77 128.42,42.86 128.42,43.18 128.51,43.27 128.9,43.27 128.99,43.36 128.99,43.68 128.9,43.76 128.51,43.76 128.43,43.84 128.43,44.25 128.51,44.32 128.92,44.32 128.99,44.4 128.99,45.17 129.42,45.59
  BOTTOM w0.081: v2(134.93,53.66) 135.25,53.99 UC1.AR58
  BOTTOM w0.102: JDIMM1.157 128.2,17.6 128.01,17.79 128.01,19.1 v2(128.44,19.53)
DDR_A_D18: length 56
  IN1 w0.089: v2(135.88,55.62) 135.31,56.18 135.31,57.06 135.08,57.29 134.78,57.29 134.26,56.77 134.26,56.05 132.29,54.08 132.29,52.72 130.24,50.66 130.24,49.77 128.84,48.38 128.84,48.2 127.16,46.51 127.16,46.06 125.94,44.84 125.94,10.48 v2(125.07,9.61)
  BOTTOM w0.081: v2(135.88,55.62) 136.2,55.94 UC1.AM57
  BOTTOM w0.102: v2(125.07,9.61) 124.9,9.45 JDIMM1.146
DDR_A_D19: length 56.9
  IN1 w0.089: v2(125.07,11.14) 124.61,11.6 124.61,13.25 124.7,13.34 125.18,13.34 125.26,13.42 125.26,13.76 125.18,13.84 124.7,13.84 124.61,13.92 124.61,14.37 125.62,15.39 125.62,44.97 126.84,46.19 126.84,46.64 129.97,49.77 129.97,50.74 132.11,52.88 132.11,54.15 133.99,56.02 133.99,56.83 134.62,57.47 135.28,57.47 v2(135.83,56.92)
  BOTTOM w0.081: v2(135.83,56.92) 136.15,57.24 UC1.AK57
  BOTTOM w0.102: JDIMM1.148 125.5,10.71 v2(125.07,11.14)
DDR_A_D20: length 55.4
  IN1 w0.089: v2(126.65,18.01) 126.37,18.01 126.32,17.96 126.32,15.6 126.43,15.49 126.56,15.49 126.81,15.74 126.81,16.4 126.87,16.46 127.11,16.46 127.22,16.57 127.22,16.97 127.13,17.06 126.91,17.06 126.82,17.15 126.82,17.47 126.91,17.56 127.13,17.56 127.22,17.65 127.22,40.96 127.15,41.04 126.63,41.04 126.57,41.09 126.57,41.47 126.63,41.53 127.16,41.53 127.22,41.58 127.22,41.95 127.14,42.03 126.65,42.03 126.57,42.1 126.57,42.44 126.65,42.52 127.14,42.52 127.22,42.6 127.22,42.94 127.14,43.02 126.65,43.02 126.57,43.09 126.57,43.44 126.65,43.51 127.15,43.51 127.22,43.58 127.22,43.95 127.16,44.01 126.66,44.01 126.57,44.1 126.57,44.54 126.65,44.63 126.77,44.63 126.89,44.5 127.13,44.5 127.22,44.59 127.22,44.93 127.14,45.01 127.14,45.14 127.79,45.79 127.79,46.25 129.3,47.75 129.3,48.27 130.69,49.67 130.69,50.39 132.66,52.36 132.66,53.93 134.67,55.94 134.67,55.95 134.94,56.21 v2(134.94,56.27)
  BOTTOM w0.081: UC1.AL58 135.26,56.59 v2(134.94,56.27)
  BOTTOM w0.102: JDIMM1.149 125.8,17.49 126.32,18.01 v2(126.65,18.01)
DDR_A_D21: length 56.3
  IN1 w0.089: v2(126.65,19.53) 126.25,19.93 126.25,31.1 126.34,31.19 126.81,31.19 126.9,31.28 126.9,31.59 126.81,31.68 126.34,31.68 126.25,31.77 126.25,32.09 126.34,32.18 126.81,32.18 126.9,32.27 126.9,32.58 126.81,32.67 126.34,32.67 126.25,32.76 126.25,33.08 126.34,33.17 126.81,33.17 126.9,33.26 126.9,33.57 126.81,33.66 126.34,33.66 126.25,33.75 126.25,34.07 126.34,34.16 126.81,34.16 126.9,34.25 126.9,34.57 126.81,34.65 126.34,34.65 126.25,34.74 126.25,35.06 126.34,35.15 126.81,35.15 126.9,35.24 126.9,35.56 126.81,35.64 126.34,35.64 126.25,35.73 126.25,36.05 126.34,36.14 126.81,36.14 126.9,36.23 126.9,36.55 126.81,36.64 126.34,36.64 126.25,36.72 126.25,37.04 126.34,37.13 126.81,37.13 126.9,37.22 126.9,37.54 126.81,37.63 126.34,37.63 126.25,37.71 126.25,38.03 126.34,38.12 126.81,38.12 126.9,38.21 126.9,38.53 126.81,38.62 126.34,38.62 126.25,38.71 126.25,39.02 126.34,39.11 126.81,39.11 126.9,39.2 126.9,39.52 126.81,39.61 126.34,39.61 126.25,39.7 126.25,40.01 126.34,40.1 126.81,40.1 126.9,40.19 126.9,40.51 126.81,40.6 126.34,40.6 126.25,40.69 126.25,44.7 127.47,45.92 127.47,46.38 129.08,47.99 129.08,48.35 130.46,49.73 130.46,50.52 132.47,52.53 132.47,53.99 134.5,56.01 134.5,56.49 v2(134.93,56.92)
  BOTTOM w0.081: UC1.AK58 135.25,57.24 v2(134.93,56.92)
  BOTTOM w0.102: JDIMM1.147 125.2,18.08 v2(126.65,19.53)
DDR_A_D22: length 53.6
  IN1 w0.076: 130.57,45.61 130.57,47.73 133.91,51.07 134.25,51.07 135.88,52.7 v2(135.88,53.66)
  IN1 w0.089: 130.57,45.61 129.94,44.99 129.94,30.79 129.37,30.22 129.37,21.56 129.82,21.11 129.82,15.52 129.53,15.24 129.53,14.73 129.62,14.64 130.98,14.64 131.1,14.51 131.1,14.27 130.98,14.14 130.58,14.14 130.45,14.02 130.45,13.78 130.58,13.65 130.98,13.65 131.1,13.52 131.1,13.28 130.98,13.15 130.71,13.15 129.82,12.26 129.82,9.68 129.75,9.61 v2(128.47,9.61)
  BOTTOM w0.081: UC1.AR57 136.2,53.99 v2(135.88,53.66)
  BOTTOM w0.102: JDIMM1.158 128.5,9.58 v2(128.47,9.61)
DDR_A_D23: length 55.4
  IN1 w0.076: 130.39,45.76 130.39,47.8 133.83,51.25 134.18,51.25 135.5,52.57 135.5,54.59 v2(135.88,54.96)
  IN1 w0.089: v2(128.47,11.14) 128.47,10.88 128.59,10.76 128.94,10.76 129.06,10.88 129.06,11.23 129.19,11.35 129.37,11.35 129.5,11.48 129.5,11.87 129.37,12 129.19,12 129.06,12.13 129.06,12.55 129.19,12.67 129.78,12.67 129.91,12.8 129.91,13.13 129.78,13.26 129.34,13.26 129.22,13.39 129.22,13.67 129.34,13.79 130.01,13.79 130.13,13.92 130.13,14.16 130.01,14.29 129.31,14.29 129.22,14.38 129.22,15.37 129.5,15.65 129.5,20.98 129.05,21.43 129.05,30.35 129.63,30.93 129.63,45 130.39,45.76
  BOTTOM w0.081: UC1.AN57 136.2,55.29 v2(135.88,54.96)
  BOTTOM w0.102: v2(128.47,11.14) 129.1,10.5 JDIMM1.160
DDR_A_D24: length 80.8
  IN4 w0.089: v2(136.83,54.36) 136.46,53.99 136.46,53.44 134.63,51.61 134.57,51.61 134.56,51.61 133.41,51.61 124.65,42.84 118.22,42.84 117.59,42.21 103.78,42.21 86.68,25.11 86.47,24.89 86.47,23.99 86.15,23.67 86.15,10.31 v2(86.64,9.83)
  BOTTOM w0.081: UC1.AP55 137.11,54.64 v2(136.83,54.36)
  BOTTOM w0.102: v2(86.64,9.83) 86.49,9.83 85.9,9.24 JDIMM1.24
DDR_A_D25: length 80.3
  IN4 w0.089: v2(86.64,11.35) 87.04,11.75 87.04,16.48 86.47,17.04 86.47,23.54 86.78,23.85 86.78,24.76 103.91,41.89 117.72,41.89 118.35,42.53 124.78,42.53 133.69,51.43 134.64,51.43 134.64,51.44 134.72,51.44 136.83,53.55 136.83,53.66 136.82,53.67 v2(136.82,53.66)
  BOTTOM w0.081: UC1.AR55 137.16,53.99 136.83,53.66 v2(136.82,53.66)
  BOTTOM w0.102: v2(86.64,11.35) 85.3,10.02 JDIMM1.22
DDR_A_D26: length 82.7
  IN4 w0.089: v2(88.3,11.35) 88.8,11.85 88.8,15.11 89.45,15.76 89.45,17.7 89.62,17.86 89.62,23.76 91.56,25.7 91.56,26.94 104.67,40.06 124.94,40.06 131.16,46.28 131.48,46.28 135.86,50.65 136.88,50.65 138.37,52.15 138.37,54.56 138.16,54.77 138.16,55.42 138.16,55.89 v2(137.78,56.27)
  BOTTOM w0.081: v2(137.78,56.27) 138.11,55.94 UC1.AM54
  BOTTOM w0.102: v2(88.3,11.35) 89.5,10.15 JDIMM1.36
DDR_A_D27: length 83.9
  IN4 w0.089: v2(88.3,9.83) 88.89,9.83 89.77,10.71 89.77,17.57 89.94,17.73 89.94,23.63 91.87,25.57 91.87,26.81 104.8,39.74 125.07,39.74 130.66,45.34 131.23,45.34 135.67,49.79 136.72,49.79 138.62,51.69 138.62,54.6 138.34,54.89 138.34,56.31 v2(137.73,56.92)
  BOTTOM w0.081: UC1.AK54 138.06,57.24 v2(137.73,56.92)
  BOTTOM w0.102: JDIMM1.34 88.9,9.23 v2(88.3,9.83)
DDR_A_D28: length 82.5
  IN4 w0.089: v2(85.25,19.53) 85.25,19.28 85.38,19.15 85.71,19.15 85.84,19.28 85.84,20.57 85.71,20.7 85.06,20.7 84.93,20.82 84.93,21.06 85.06,21.19 85.71,21.19 85.84,21.32 85.84,21.56 85.71,21.69 85.06,21.69 84.93,21.81 84.93,22.05 85.06,22.18 85.71,22.18 85.84,22.31 85.84,22.55 85.71,22.68 85.06,22.68 84.93,22.8 84.93,23.05 85.06,23.17 85.71,23.17 85.84,23.3 85.84,23.51 85.71,23.63 85.01,23.63 84.93,23.71 84.93,23.81 85.47,24.35 85.56,24.35 85.91,23.99 86.02,23.99 86.15,24.12 86.15,24.54 85.96,24.73 85.96,24.84 103.65,42.53 117.46,42.53 118.09,43.16 124.41,43.16 129.42,48.17 129.42,48.18 133.25,52.01 133.25,52.16 133.54,52.45 135.19,52.45 136.28,53.54 136.28,55.71 v2(136.83,56.27)
  BOTTOM w0.081: UC1.AL55 137.16,56.59 v2(136.83,56.27)
  BOTTOM w0.102: v2(85.25,19.53) 85.83,18.96 85.83,17.78 85.6,17.55 JDIMM1.23
DDR_A_D29: length 83.2
  IN4 w0.089: v2(136.78,56.92) 136.78,57.28 136.57,57.49 135.56,57.49 135.31,57.24 135.31,53.52 134.59,52.81 133.4,52.81 132.95,52.36 132.95,52.15 124.28,43.48 117.96,43.48 117.33,42.85 103.52,42.85 84.61,23.94 84.61,16.51 84.74,16.38 85.71,16.38 85.84,16.51 85.84,16.81 85.71,16.94 85.48,16.94 85.35,17.07 85.35,17.4 85.48,17.53 85.71,17.53 85.84,17.65 85.84,18.27 85.71,18.39 85.38,18.39 85.25,18.27 v2(85.25,18.01)
  BOTTOM w0.081: UC1.AK55 137.11,57.24 v2(136.78,56.92)
  BOTTOM w0.102: JDIMM1.21 85,17.76 v2(85.25,18.01)
DDR_A_D30: length 80.6
  IN4 w0.089: v2(88.52,19.53) 88.85,19.53 88.93,19.62 88.93,23.98 89.84,24.88 89.84,25 89.34,25.5 89.34,25.62 89.57,25.85 89.69,25.85 90.19,25.35 90.31,25.35 90.56,25.6 90.56,25.7 90.07,26.2 90.07,26.35 90.28,26.57 90.4,26.57 90.68,26.29 90.79,26.29 90.92,26.42 90.92,26.75 90.76,26.91 90.76,27.05 104.41,40.69 118.72,40.69 118.81,40.78 118.81,41.2 118.94,41.33 119.18,41.33 119.31,41.2 119.31,40.78 119.4,40.69 119.71,40.69 119.8,40.78 119.8,41.2 119.93,41.33 120.17,41.33 120.3,41.2 120.3,40.78 120.39,40.69 120.71,40.69 120.79,40.78 120.79,41.2 120.92,41.33 121.16,41.33 121.29,41.2 121.29,40.78 121.38,40.69 121.7,40.69 121.78,40.78 121.78,41.2 121.91,41.33 122.15,41.33 122.28,41.2 122.28,40.78 122.37,40.69 122.69,40.69 122.78,40.78 122.78,41.26 122.85,41.33 123.19,41.33 123.27,41.24 123.27,40.78 123.36,40.69 123.68,40.69 123.77,40.78 123.77,41.24 123.85,41.33 124.16,41.33 124.26,41.23 124.26,40.77 124.34,40.69 124.67,40.69 124.8,40.82 124.8,41.26 124.86,41.33 125.31,41.33 130.82,46.84 130.82,47.47 134.03,50.68 135.35,50.68 137.78,53.11 v2(137.78,53.66)
  BOTTOM w0.081: UC1.AR54 138.11,53.99 v2(137.78,53.66)
  BOTTOM w0.102: JDIMM1.33 88.6,17.32 88.11,17.81 88.11,19.13 v2(88.52,19.53)
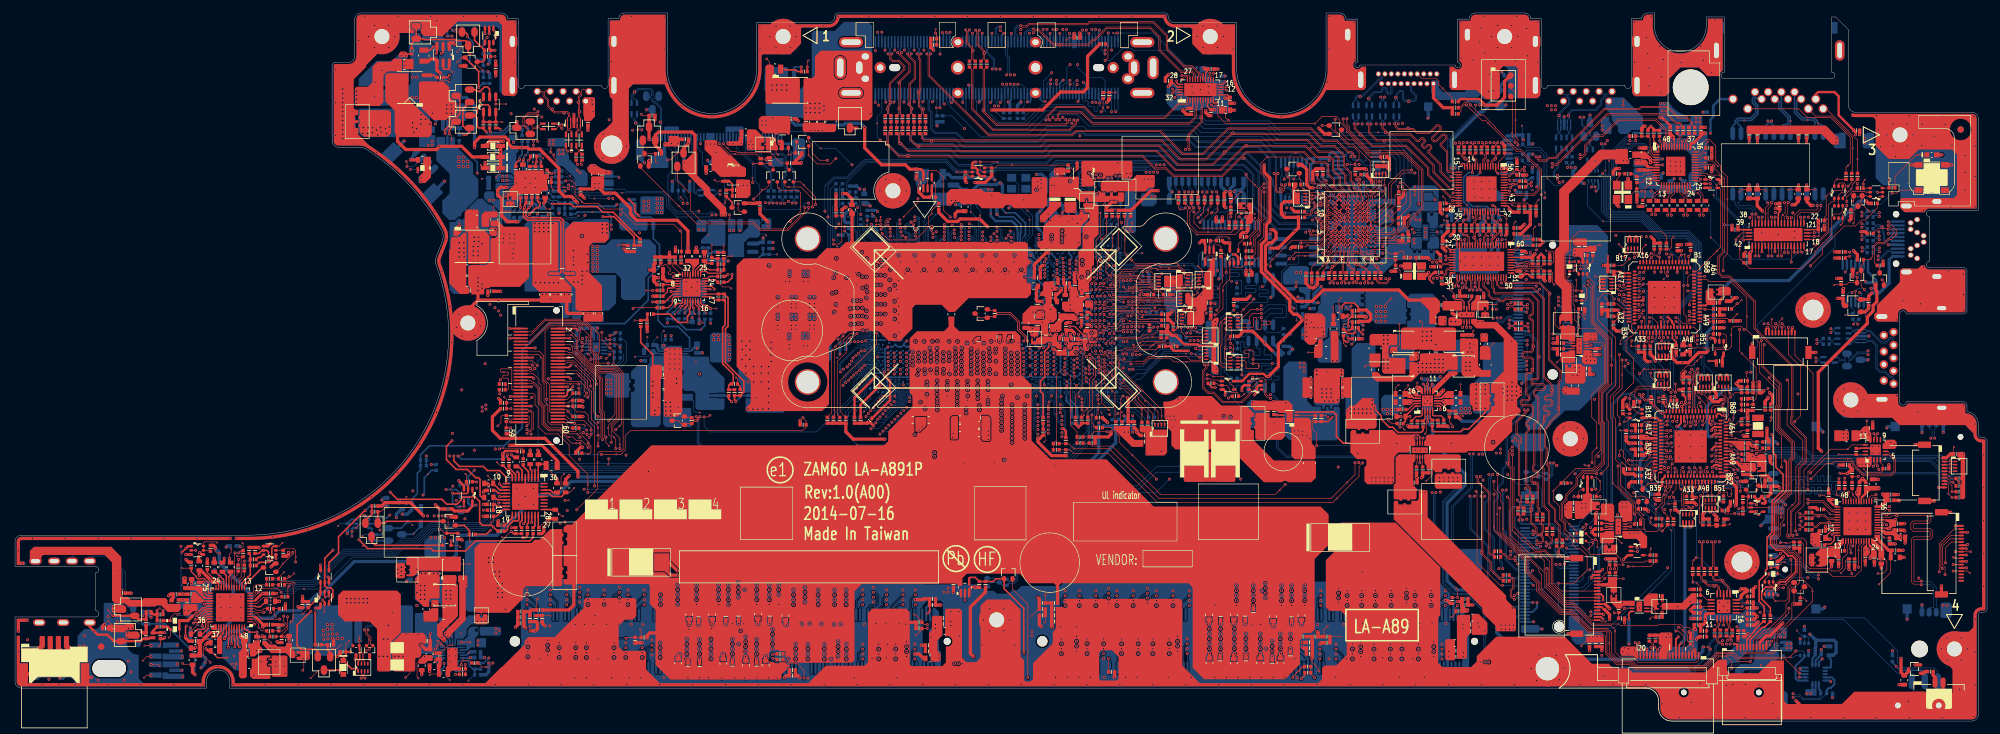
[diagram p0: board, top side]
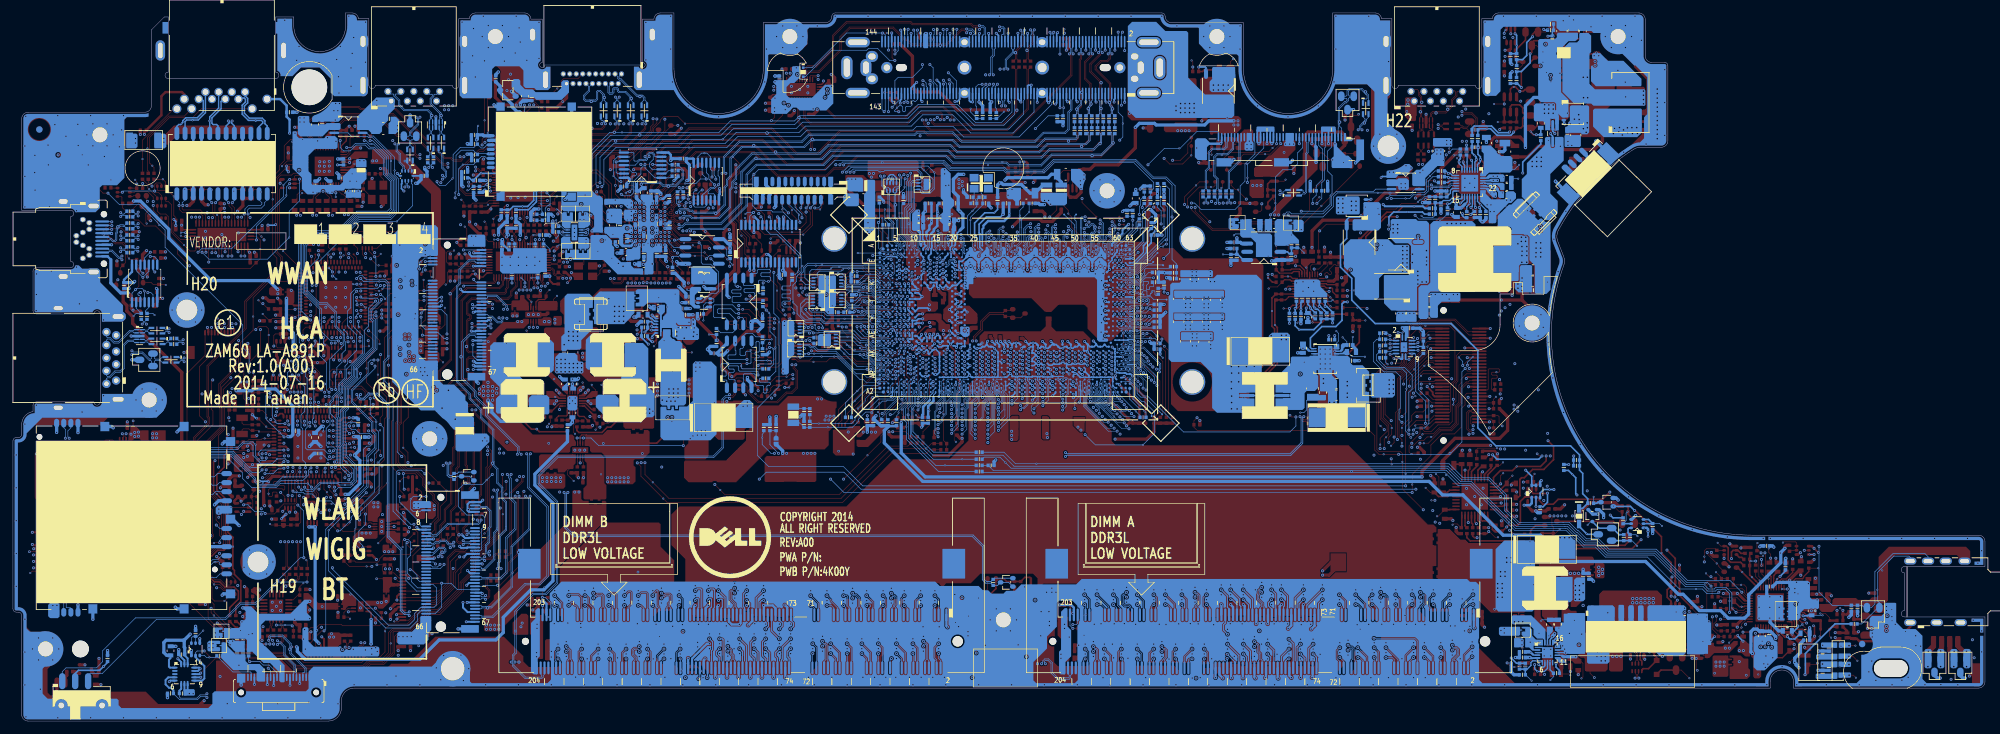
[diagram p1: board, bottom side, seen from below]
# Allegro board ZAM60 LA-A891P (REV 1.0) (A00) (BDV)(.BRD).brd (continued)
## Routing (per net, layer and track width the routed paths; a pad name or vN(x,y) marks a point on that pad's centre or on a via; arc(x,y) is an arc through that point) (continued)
DDR_A_D31: length 82.1
  IN4 w0.089: v2(137.78,54.96) 137.78,54.84 138.17,54.45 138.17,52.24 136.79,50.86 135.79,50.86 131.54,46.61 131.04,46.61 124.8,40.38 104.54,40.38 91.24,27.07 91.24,25.83 89.27,23.86 89.27,17.96 89.13,17.83 89.13,15.9 89.01,15.77 87.48,15.77 87.36,15.9 87.36,16.43 87.48,16.56 88.36,16.56 88.49,16.69 88.49,17.12 88.36,17.25 87.37,17.25 87.24,17.37 87.24,17.88 87.37,18.01 v2(88.52,18.01)
  BOTTOM w0.081: UC1.AN54 138.11,55.29 v2(137.78,54.96)
  BOTTOM w0.102: JDIMM1.35 89.2,17.52 88.71,18.01 v2(88.52,18.01)
DDR_A_D32: length 46.6
  IN1 w0.076: 131.12,44.18 131.12,47.56 132.95,49.39 v2(133.38,49.39)
  IN1 w0.089: v2(131.01,9.61) 130.41,10.21 130.41,12.01 130.91,12.51 131.33,12.51 131.7,12.88 131.7,20.59 131.18,21.12 131.18,44.13 131.12,44.18
  BOTTOM w0.081: UC1.AY58 135.23,50.76 135.23,50.08 134.54,49.39 v2(133.38,49.39)
  BOTTOM w0.102: v2(131.01,9.61) 130.9,9.51 JDIMM1.166
DDR_A_D33: length 47.6
  IN1 w0.076: 130.92,45.17 130.92,47.6 133.14,49.81 v2(133.72,49.81)
  IN1 w0.089: 130.92,45.17 130.86,45.11 130.86,21.2 130.73,21.08 130.73,20.77 130.8,20.7 131.15,20.7 131.38,20.46 131.38,17.56 131.29,17.47 131.04,17.47 130.91,17.34 130.91,17.1 131.04,16.98 131.29,16.98 131.38,16.89 131.38,16.57 131.29,16.48 130.95,16.48 130.88,16.42 130.88,16.06 130.96,15.99 131.29,15.99 131.38,15.9 131.38,15.44 131.31,15.36 131.09,15.36 130.96,15.24 130.51,15.24 130.41,15.33 130.41,18.33 130.48,18.39 130.85,18.39 130.98,18.27 v2(130.98,18.01)
  BOTTOM w0.081: UC1.AW58 135.05,51.24 135.05,50.14 134.72,49.81 v2(133.72,49.81)
  BOTTOM w0.102: JDIMM1.165 130.6,17.63 v2(130.98,18.01)
DDR_A_D34: length 47.5
  IN1 w0.089: v2(134.68,19.53) 134.97,19.53 135.08,19.65 135.08,20.64 135.01,20.71 134.58,20.71 134.51,20.79 134.51,21.27 134.58,21.35 135,21.35 135.07,21.42 135.07,21.82 135,21.89 134.58,21.89 134.51,21.97 134.51,22.27 134.6,22.36 134.8,22.36 134.89,22.45 134.89,22.77 134.8,22.85 134.6,22.85 134.51,22.94 134.51,23.26 134.6,23.35 134.8,23.35 134.89,23.44 134.89,23.76 134.8,23.84 134.6,23.84 134.51,23.93 134.51,24.25 134.6,24.34 134.8,24.34 134.89,24.43 134.89,24.75 134.8,24.84 134.6,24.84 134.51,24.92 134.51,25.24 134.6,25.33 134.8,25.33 134.89,25.42 134.89,25.74 134.8,25.83 134.6,25.83 134.51,25.91 134.51,26.23 134.6,26.32 134.8,26.32 134.89,26.41 134.89,26.73 134.8,26.82 134.41,26.82 134.34,26.89 134.34,27.24 134.41,27.31 134.81,27.31 134.89,27.39 134.89,27.73 134.81,27.81 134.17,27.81 133.98,27.62 133.61,27.62 133.35,27.88 133.35,28.1 133.42,28.18 134.78,28.18 134.86,28.26 134.86,28.54 134.5,28.9 134.35,28.9 134.06,28.62 133.41,28.62 133.35,28.68 133.35,29.01 133.44,29.1 133.8,29.1 133.87,29.17 133.87,29.53 133.8,29.6 133.46,29.6 133.35,29.72 133.35,43.4 133.02,43.73 133.02,44.72 135.39,47.09 v2(135.39,48.94)
  BOTTOM w0.081: UC1.AY56 136.68,50.86 136.68,49.86 136.27,49.45 136.27,49.3 135.94,48.97 135.42,48.97 v2(135.39,48.94)
  BOTTOM w0.102: v2(134.68,19.53) 134.09,18.94 134.09,17.92 133.6,17.43 JDIMM1.175
DDR_A_D35: length 48.5
  IN1 w0.089: v2(134.47,48.02) 134.5,47.99 134.5,46.57 132.79,44.86 132.79,43.52 133.03,43.27 133.03,27.75 134.19,26.59 134.19,19.31 133.72,18.83 133.72,15.32 134.44,14.6 134.44,11.39 134.37,11.31 133.94,11.31 133.85,11.22 133.85,10.9 133.94,10.81 134.4,10.81 134.48,10.74 134.48,10.4 134.4,10.32 133.94,10.32 133.85,10.23 133.85,10.01 v2(133.45,9.61)
  BOTTOM w0.081: UC1.AW56 136.7,51.29 136.99,51 136.99,50.76 136.85,50.62 136.85,49.79 136.45,49.39 136.45,49.24 136.01,48.8 135.77,48.8 134.99,48.02 v2(134.47,48.02)
  BOTTOM w0.102: JDIMM1.174 133.3,9.47 v2(133.45,9.61)
DDR_A_D36: length 48
  IN1 w0.076: 130.67,45.38 130.74,45.45 130.74,47.66 133.28,50.2 v2(134.11,50.2)
  IN1 w0.089: v2(130.98,19.53) 130.88,19.43 130.49,19.43 130.41,19.51 130.41,21.21 130.54,21.34 130.54,21.64 130.45,21.73 130.04,21.73 129.97,21.81 129.97,22.15 130.04,22.23 130.45,22.23 130.54,22.32 130.54,22.63 130.45,22.72 130.04,22.72 129.97,22.8 129.97,23.14 130.04,23.22 130.45,23.22 130.54,23.31 130.54,23.62 130.45,23.71 130.04,23.71 129.97,23.79 129.97,24.13 130.04,24.21 130.45,24.21 130.54,24.3 130.54,24.61 130.45,24.7 130.04,24.7 129.97,24.78 129.97,25.12 130.04,25.2 130.45,25.2 130.54,25.29 130.54,25.6 130.45,25.69 130.04,25.69 129.97,25.77 129.97,26.11 130.04,26.19 130.45,26.19 130.54,26.28 130.54,26.6 130.45,26.68 130.04,26.68 129.97,26.76 129.97,27.1 130.04,27.18 130.45,27.18 130.54,27.27 130.54,27.59 130.45,27.67 130.04,27.67 129.97,27.75 129.97,28.09 130.04,28.17 130.45,28.17 130.54,28.26 130.54,28.47 130.45,28.56 130.06,28.56 129.97,28.65 129.97,28.97 130.06,29.06 130.45,29.06 130.54,29.15 130.54,29.47 130.45,29.55 130.04,29.55 129.97,29.63 129.97,29.97 130.04,30.05 130.45,30.05 130.54,30.14 130.54,45.3 130.62,45.38 130.67,45.38
  BOTTOM w0.076: UC1.AV58 135.12,51.95 135.12,51.85 135.08,51.8 135.08,51.73 134.9,51.56 134.84,51.56 134.36,51.09 134.36,50.62 134.11,50.37 v2(134.11,50.2)
  BOTTOM w0.102: JDIMM1.163 130,18.55 v2(130.98,19.53)
DDR_A_D37: length 49.6
  IN1 w0.089: v2(131.5,47.09) 131.49,47.08 131.49,21.25 132.02,20.72 132.02,12.15 v2(131.01,11.14)
  BOTTOM w0.076: v2(131.5,47.09) 133.03,47.09 135.78,49.84 136.12,49.84 136.33,50.06 136.33,50.6 136.24,50.69 136.24,50.98 136.26,51.03 136.27,51.03 136.32,51.14 136.32,51.28 136.26,51.39 136.26,51.39 136.24,51.44 136.24,51.63 136.26,51.68 136.31,51.77 136.31,51.79 136.31,52.04 136.3,52.06 136.3,52.3 136.31,52.32 136.31,52.67 136.15,52.83 136.11,52.83 136.11,52.83 UC1.AU58
  BOTTOM w0.102: JDIMM1.164 130.3,10.43 v2(131.01,11.14)
DDR_A_D38: length 48.7
  IN1 w0.089: v2(135.85,49.4) 135.85,47.21 133.26,44.61 133.26,43.81 133.66,43.4 133.66,30.18 135.2,28.65 135.2,22.17 135.4,21.98 135.4,19.38 135.31,19.29 135.17,19.29 135.08,19.2 135.08,18.88 135.17,18.79 135.31,18.79 135.4,18.71 135.4,18.39 135.31,18.3 135.17,18.3 135.08,18.21 135.08,17.89 135.17,17.8 135.31,17.8 135.4,17.71 135.4,17.4 135.31,17.31 134.61,17.31 134.53,17.23 134.53,16.89 134.61,16.81 135.31,16.81 135.4,16.72 135.4,16.18 135.33,16.1 135.07,16.1 134.95,16.23 134.68,16.23 134.57,16.12 134.57,15.86 134.71,15.72 134.71,15.54 134.6,15.44 134.11,15.44 134.04,15.52 134.04,18.3 134.11,18.38 134.61,18.38 134.68,18.3 v2(134.68,18.01)
  BOTTOM w0.076: v2(135.85,49.4) 136.12,49.67 136.18,49.67 136.5,49.99 136.5,50.67 136.41,50.76 136.41,50.94 136.46,51.05 136.48,51.07 136.48,51.32 136.41,51.48 136.41,51.59 136.43,51.65 136.45,51.7 136.59,51.84 UC1.AV56
  BOTTOM w0.102: v2(134.68,18.01) 134.2,17.53 JDIMM1.177
DDR_A_D39: length 49.9
  IN1 w0.089: v2(133.45,11.14) 133.09,11.14 133.02,11.21 133.02,12.61 133.09,12.69 134.04,12.69 134.13,12.78 134.13,14.46 133.4,15.19 133.4,18.97 133.87,19.44 133.87,26.46 132.71,27.62 132.71,43.19 132.59,43.31 132.59,45 134.12,46.53 v2(134.12,47.5)
  BOTTOM w0.076: UC1.AU56 136.72,52.7 136.72,52.46 136.88,52.3 136.88,52.06 136.88,52.05 136.88,51.76 137.17,51.47 137.17,50.66 137.02,50.51 137.02,49.7 137.01,49.69 137.01,49.69 136.64,49.32 136.64,49.16 136.05,48.58 135.81,48.58 134.73,47.5 v2(134.12,47.5)
  BOTTOM w0.102: v2(133.45,11.14) 133.9,10.69 JDIMM1.176
DDR_A_D40: length 75.6
  IN4 w0.089: v2(132.28,45.2) 132.27,45.2 125.55,38.49 108.58,38.49 108.11,38.01 104.85,38.01 93.11,26.26 93.11,24.55 91.81,23.26 91.81,10.58 v2(92.57,9.83)
  BOTTOM w0.081: UC1.AY54 137.68,50.78 137.68,50.46 137.53,50.3 137.53,49.49 137.14,49.1 137.14,48.96 136.16,47.98 136.16,47.98 133.37,45.2 v2(132.28,45.2)
  BOTTOM w0.102: v2(92.57,9.83) 91.6,9.83 91.3,9.53 JDIMM1.42
DDR_A_D41: length 76.9
  IN4 w0.089: v2(91.06,18.01) 90.37,17.32 90.37,14.35 90.49,14.22 90.87,14.22 90.99,14.35 90.99,15.24 91.12,15.36 91.36,15.36 91.48,15.49 91.48,15.79 91.39,15.88 91.16,15.88 91.07,15.97 91.07,16.29 91.16,16.38 91.39,16.38 91.48,16.47 91.48,16.84 91.39,16.92 91.16,16.92 91.07,17.01 91.07,17.46 91.16,17.55 91.39,17.55 91.48,17.64 91.48,23.37 92.79,24.68 92.79,26.4 104.72,38.33 107.98,38.33 108.45,38.8 125.42,38.8 131.34,44.72 131.34,44.85 132.61,46.12 v2(133.01,46.12)
  BOTTOM w0.076: v2(133.01,46.12) 134.06,46.12 136.09,48.15 136.09,48.15 136.97,49.03 136.97,49.17 137.36,49.56 137.36,50.37 137.5,50.51 137.5,51.25 UC1.AW54
  BOTTOM w0.102: v2(91.06,18.01) 91,17.95 JDIMM1.41
DDR_A_D42: length 76.3
  IN4 w0.089: v2(135.5,46.21) 134.97,46.21 133.28,44.53 133.28,43.62 126.31,36.65 119.83,36.65 119.35,36.18 105.61,36.18 94.94,25.5 94.94,20.78 94.85,20.7 94.4,20.7 94.28,20.57 94.28,18.25 93.99,17.96 93.99,14.23 94.08,14.14 94.76,14.14 94.85,14.05 94.85,13.74 94.76,13.65 94.08,13.65 93.99,13.56 93.99,11.75 v2(94.39,11.35)
  BOTTOM w0.076: UC1.AY52 139,50.75 139,50.27 138.98,50.25 138.98,48.79 136.7,46.5 136.46,46.5 136.17,46.21 v2(135.5,46.21)
  BOTTOM w0.102: JDIMM1.50 93.7,10.67 v2(94.39,11.35)
DDR_A_D43: length 77.3
  IN4 w0.089: v2(94.7,18.01) 94.55,18.01 94.3,17.76 94.3,14.66 94.43,14.53 94.68,14.53 94.8,14.66 94.8,15.37 94.93,15.49 95.08,15.49 95.21,15.37 95.45,15.37 95.57,15.49 95.57,16.08 95.45,16.2 95.03,16.2 94.9,16.33 94.9,16.69 95.03,16.81 95.45,16.81 95.57,16.94 95.57,17.17 95.45,17.3 95.13,17.3 95.01,17.42 95.01,17.66 95.13,17.79 95.49,17.79 95.57,17.88 95.57,18.2 95.49,18.29 95.21,18.29 95.09,18.41 95.09,18.66 95.21,18.78 95.49,18.78 95.57,18.87 95.57,20.93 96.1,21.46 96.1,25.77 105.87,35.54 126.1,35.54 133.98,43.42 133.98,43.71 134.58,44.3 v2(134.58,45.29)
  BOTTOM w0.076: UC1.AW52 139.34,51.31 139.34,51.1 139.37,51.05 139.38,51.02 139.42,50.93 139.42,50.46 139.15,50.18 139.15,48.72 135.72,45.29 v2(134.58,45.29)
  BOTTOM w0.102: v2(94.7,18.01) 94.53,18.01 94,17.49 JDIMM1.51
DDR_A_D44: length 76.6
  IN4 w0.089: v2(91.06,19.53) 91.06,19.28 90.93,19.15 90.64,19.15 90.53,19.25 90.53,20.62 90.61,20.7 91.04,20.7 91.16,20.82 91.16,21.13 91.11,21.19 90.63,21.19 90.53,21.29 90.53,21.59 90.63,21.69 91.08,21.69 91.16,21.77 91.16,22.09 91.08,22.18 90.62,22.18 90.53,22.27 90.53,22.59 90.62,22.68 91.08,22.68 91.16,22.77 91.16,23.08 91.08,23.17 90.63,23.17 90.53,23.27 90.53,23.39 91,23.85 91.08,23.85 91.25,23.68 91.34,23.68 91.59,23.93 91.59,24.04 91.42,24.21 91.42,24.28 91.71,24.56 91.77,24.56 91.94,24.4 92.05,24.4 92.28,24.63 92.28,24.75 92.15,24.88 92.15,25.01 92.47,25.32 92.47,26.53 104.59,38.64 104.91,38.64 105,38.73 105,39.09 105.05,39.14 105.43,39.14 105.49,39.08 105.49,38.71 105.56,38.64 105.86,38.64 105.94,38.72 105.94,39.09 106,39.14 106.33,39.14 106.38,39.09 106.38,38.73 106.47,38.64 106.77,38.64 106.83,38.71 106.83,39.09 106.88,39.14 107.22,39.14 107.27,39.09 107.27,38.71 107.34,38.64 107.78,38.64 107.83,38.7 107.83,39.09 107.89,39.14 125.32,39.14 130.87,44.7 130.87,44.7 132.81,46.64 v2(133.28,46.64)
  BOTTOM w0.076: v2(133.28,46.64) 134.15,46.64 v1(134.6,47.09) 135.86,48.35 136.06,48.35 136.8,49.09 136.8,49.23 136.81,49.23 136.81,49.25 137.17,49.62 137.17,49.62 137.18,49.63 137.18,50.44 137.33,50.59 137.33,51.5 137.88,52.05 UC1.AV54
  BOTTOM w0.102: v2(91.06,19.53) 90.4,18.88 JDIMM1.39
DDR_A_D45: length 78.2
  IN4 w0.089: v2(92.57,11.35) 92.14,11.78 92.14,23.14 93.42,24.42 93.42,26.13 104.98,37.69 108.24,37.69 108.72,38.17 125.69,38.17 132.16,44.64 132.24,44.64 137.02,49.41 v2(138.23,49.41)
  BOTTOM w0.076: UC1.AU54 138.54,52.83 138.74,52.63 138.74,51.79 138.74,51.77 138.69,51.68 138.67,51.63 138.67,51.43 138.75,51.27 138.75,51.14 138.7,51.03 138.69,51.03 138.67,50.98 138.67,50.47 138.65,50.45 138.65,49.83 v2(138.23,49.41)
  BOTTOM w0.102: v2(92.57,11.35) 90.7,9.48 JDIMM1.40
DDR_A_D46: length 77.8
  IN4 w0.089: v2(94.39,9.83) 93.67,10.55 93.67,11.43 93.58,11.52 93.22,11.52 93.13,11.61 93.13,11.88 93.22,11.96 93.58,11.96 93.67,12.05 93.67,12.37 93.58,12.46 93.22,12.46 93.13,12.55 93.13,12.87 93.22,12.95 93.58,12.95 93.67,13.04 93.67,18.09 93.95,18.37 93.95,20.89 94.07,21.01 94.55,21.01 94.62,21.08 94.62,25.64 105.48,36.49 119.22,36.49 119.7,36.97 126.18,36.97 132.95,43.74 132.95,44.45 135.17,46.67 v2(135.96,46.67)
  BOTTOM w0.076: UC1.AV52 139.02,51.84 138.89,51.7 138.86,51.65 138.84,51.59 138.84,51.47 138.91,51.31 138.91,51.1 138.89,51.05 138.84,50.94 138.84,50.34 138.82,50.32 138.82,48.85 136.63,46.67 v2(135.96,46.67)
  BOTTOM w0.102: v2(94.39,9.83) 94.3,9.74 JDIMM1.52
DDR_A_D47: length 78.3
  IN4 w0.089: v2(94.7,19.53) 94.7,19.28 94.83,19.15 95.13,19.15 95.26,19.28 95.26,21.41 95.31,21.47 95.66,21.47 95.79,21.6 95.79,21.92 95.66,22.05 95.35,22.05 95.26,22.14 95.26,22.43 95.33,22.5 95.74,22.5 95.79,22.55 95.79,22.9 95.7,22.98 95.31,22.98 95.26,23.04 95.26,23.43 95.31,23.48 95.7,23.48 95.79,23.56 95.79,23.89 95.7,23.98 95.35,23.98 95.26,24.06 95.26,24.38 95.35,24.47 95.7,24.47 95.79,24.56 95.79,24.88 95.7,24.97 95.35,24.97 95.26,25.05 95.26,25.37 95.35,25.46 95.7,25.46 95.79,25.55 95.79,25.9 105.74,35.86 119.84,35.86 119.89,35.9 119.89,36.26 119.96,36.33 120.27,36.33 120.33,36.27 120.33,35.95 120.42,35.86 120.69,35.86 120.78,35.95 120.78,36.24 120.87,36.33 121.13,36.33 121.22,36.24 121.22,35.95 121.31,35.86 121.58,35.86 121.67,35.95 121.67,36.24 121.75,36.33 122.02,36.33 122.11,36.24 122.11,35.95 122.2,35.86 122.47,35.86 122.55,35.95 122.55,36.24 122.64,36.33 122.91,36.33 123,36.24 123,35.95 123.09,35.86 123.35,35.86 123.44,35.95 123.44,36.24 123.53,36.33 123.8,36.33 123.89,36.24 123.89,35.95 123.98,35.86 124.24,35.86 124.33,35.95 124.33,36.24 124.42,36.33 124.69,36.33 124.78,36.24 124.78,35.95 124.87,35.86 125.13,35.86 125.22,35.95 125.22,36.24 125.31,36.33 125.58,36.33 125.67,36.24 125.67,35.95 125.75,35.86 125.97,35.86 126.06,35.95 126.06,36.27 126.12,36.33 126.45,36.33 133.6,43.49 133.6,43.73 134.12,44.24 v2(134.12,44.83)
  BOTTOM w0.076: UC1.AU52 139.51,52.45 139.51,51.13 139.53,51.08 139.56,51.03 139.56,51.03 139.56,51.03 139.59,50.97 139.59,50.39 139.31,50.11 139.31,50.11 139.31,48.64 135.5,44.83 v2(134.12,44.83)
  BOTTOM w0.102: v2(94.7,19.53) 95.17,19.07 95.17,17.9 94.6,17.33 94.6,17.21 94.6,17.21 JDIMM1.53
DDR_A_D48: length 86.4
  IN4 w0.089: v2(146.27,56.96) 146.33,56.96 146.85,56.44 146.85,53.44 146.29,52.89 143.93,52.89 143.65,52.6 143.65,47.98 141.95,46.28 140.45,46.28 138.25,44.08 138.25,42.41 127.68,31.84 108.49,31.84 100.9,24.26 100.9,19.6 100.81,19.51 100.26,19.51 100.13,19.39 100.13,19.15 100.26,19.02 100.81,19.02 100.9,18.93 100.9,18.61 100.81,18.52 100.31,18.52 100.19,18.4 100.19,18.16 100.31,18.03 100.81,18.03 100.9,17.94 100.9,17.44 101.35,16.99 101.35,16.33 101.44,16.24 101.93,16.24 102.02,16.15 102.02,15.84 101.93,15.75 101.44,15.75 101.35,15.66 101.35,15.34 101.44,15.25 101.89,15.25 102.02,15.12 102.02,14.88 101.89,14.76 100.85,14.76 100.75,14.86 100.75,16.59 99.76,17.58 v2(99.76,18.01)
  BOTTOM w0.081: UC1.AK40 146.55,57.24 v2(146.27,56.96)
  BOTTOM w0.102: v2(99.76,18.01) 99.4,17.65 JDIMM1.69
DDR_A_D49: length 86.2
  IN4 w0.089: v2(145.35,56.97) 145.73,56.59 146.42,56.59 146.64,56.36 146.64,53.53 146.23,53.11 143.9,53.11 143.37,52.58 143.37,48.04 141.99,46.66 140.37,46.66 137.93,44.22 137.93,42.54 127.55,32.16 108.36,32.16 108.02,31.82 107.9,31.82 107.69,32.03 107.56,32.03 107.34,31.81 107.34,31.68 107.55,31.47 107.55,31.35 107.32,31.12 107.2,31.12 106.99,31.33 106.86,31.33 106.64,31.11 106.64,30.98 106.85,30.77 106.85,30.65 106.62,30.42 106.49,30.42 106.29,30.63 106.16,30.63 105.94,30.41 105.94,30.28 106.14,30.07 106.14,29.95 105.92,29.72 105.79,29.72 105.59,29.93 105.46,29.93 105.24,29.7 105.24,29.58 105.44,29.37 105.44,29.25 105.22,29.02 105.09,29.02 104.89,29.23 104.76,29.23 104.54,29 104.54,28.88 104.74,28.67 104.74,28.55 104.52,28.32 104.39,28.32 104.18,28.53 104.06,28.53 103.83,28.3 103.83,28.18 104.04,27.97 104.04,27.84 103.82,27.62 103.69,27.62 103.48,27.83 103.36,27.83 103.13,27.6 103.13,27.48 103.34,27.27 103.34,27.14 103.12,26.92 102.99,26.92 102.78,27.13 102.66,27.13 102.43,26.9 102.43,26.78 102.64,26.57 102.64,26.44 102.42,26.22 102.29,26.22 102.08,26.43 101.96,26.43 101.73,26.2 101.73,26.08 101.94,25.87 101.94,25.74 101.72,25.52 101.59,25.52 101.38,25.73 101.26,25.73 101.03,25.5 101.03,25.38 101.24,25.17 101.24,25.04 101.07,24.87 100.94,24.87 100.78,25.03 100.7,25.03 100.59,24.92 100.59,22 100.5,21.91 100.18,21.91 99.92,21.65 99.92,21.5 100.01,21.41 100.5,21.41 100.59,21.32 100.59,21.01 100.5,20.92 99.77,20.92 99.66,20.81 99.66,20.5 99.79,20.37 100.46,20.37 100.59,20.24 100.59,19.96 100.49,19.86 99.86,19.86 99.76,19.76 v2(99.76,19.53)
  BOTTOM w0.081: UC1.AK42 145.62,57.24 v2(145.35,56.97)
  BOTTOM w0.102: v2(99.76,19.53) 98.8,18.58 JDIMM1.67
DDR_A_D50: length 84
  IN4 w0.089: v2(144.34,55.72) 144.01,55.72 143.58,55.29 143.11,55.29 142.73,54.91 142.4,54.91 141.93,54.44 141.93,53.54 141.31,52.92 140.85,52.92 140.26,52.33 140.26,50.65 139.33,49.72 139.33,48.2 136.1,44.98 136.1,43.33 126.76,33.99 106.93,33.99 98.75,25.82 98.75,23.08 97.65,21.98 97.65,17.62 97.56,17.53 97.47,17.53 97.34,17.4 97.34,17.16 97.47,17.03 97.56,17.03 97.65,16.94 97.65,16.3 97.94,16.02 97.94,13.16 97.81,13.03 97.55,13.03 97.42,13.16 97.42,15.18 97.29,15.3 96.96,15.3 96.83,15.43 96.83,17.88 96.96,18.01 v2(97.24,18.01)
  BOTTOM w0.081: v2(144.34,55.72) 144.37,55.75 144.41,55.75 144.59,55.94 UC1.AM43
  BOTTOM w0.102: v2(97.24,18.01) 96.87,18.01 96.4,17.54 JDIMM1.59
DDR_A_D51: length 83.2
  IN4 w0.089: v2(97.24,19.53) 97.24,19.28 97.12,19.15 96.91,19.15 96.83,19.23 96.83,20.45 97.11,20.73 97.24,20.73 97.34,20.82 97.34,22.11 97.57,22.35 97.57,22.45 97.34,22.69 97.34,23.06 97.39,23.11 97.65,23.11 97.9,22.86 98.08,22.86 98.43,23.21 98.43,23.6 98.35,23.68 97.42,23.68 97.34,23.77 97.34,24.09 97.42,24.18 98.35,24.18 98.43,24.27 98.43,24.59 98.35,24.68 97.42,24.68 97.34,24.76 97.34,25.26 97.58,25.5 97.7,25.5 98.03,25.17 98.35,25.17 98.43,25.26 98.43,25.58 98.08,25.93 98.08,26 98.59,26.52 98.66,26.52 98.78,26.4 98.88,26.4 99.11,26.62 99.11,26.75 99.03,26.83 99.03,26.95 99.25,27.18 99.38,27.18 99.46,27.1 99.58,27.1 99.81,27.32 99.81,27.45 99.73,27.53 99.73,27.65 99.95,27.88 100.08,27.88 100.16,27.8 100.28,27.8 100.51,28.02 100.51,28.15 100.43,28.23 100.43,28.35 100.65,28.58 100.78,28.58 100.86,28.5 100.99,28.5 101.21,28.72 101.21,28.85 101.13,28.93 101.13,29.05 101.35,29.28 101.48,29.28 101.56,29.2 101.69,29.2 101.91,29.42 101.91,29.55 101.83,29.63 101.83,29.75 102.06,29.98 102.18,29.98 102.26,29.9 102.39,29.9 102.61,30.12 102.61,30.25 102.53,30.33 102.53,30.45 102.76,30.68 102.88,30.68 102.96,30.6 103.09,30.6 103.31,30.82 103.31,30.95 103.23,31.03 103.23,31.16 103.46,31.38 103.58,31.38 103.66,31.3 103.79,31.3 104.01,31.52 104.01,31.65 103.93,31.73 103.93,31.86 104.16,32.08 104.28,32.08 104.36,32 104.49,32 104.71,32.23 104.71,32.35 104.63,32.43 104.63,32.56 104.86,32.78 104.98,32.78 105.06,32.7 105.19,32.7 105.41,32.93 105.41,33.05 105.33,33.13 105.33,33.26 105.56,33.48 105.68,33.48 105.76,33.4 105.89,33.4 106.11,33.63 106.11,33.75 106.03,33.83 106.03,33.96 106.26,34.18 106.38,34.18 106.46,34.1 106.59,34.1 106.8,34.31 126.63,34.31 135.78,43.46 135.78,45.09 139.1,48.4 139.1,49.91 140.06,50.87 140.06,52.62 141.04,53.59 141.04,54.39 141.34,54.69 141.74,54.69 142.17,55.11 142.62,55.11 143.18,55.67 v2(143.44,55.67)
  BOTTOM w0.081: v2(143.44,55.67) 143.71,55.94 UC1.AM45
  BOTTOM w0.102: v2(97.24,19.53) 95.8,18.09 JDIMM1.57
DDR_A_D52: length 83.6
  IN4 w0.089: v2(143.45,56.97) 143.17,57.26 142.36,57.26 142.1,57 142.1,55.66 141.49,55.04 140.64,55.04 140.04,54.44 140.04,53.52 139.8,53.28 139.8,51.02 138.87,50.09 138.87,48.46 135.47,45.06 135.47,43.61 126.48,34.63 106.25,34.63 97.02,25.39 97.02,21.09 96.52,20.58 96.52,13.36 96.61,13.27 96.76,13.27 96.89,13.14 96.89,12.9 96.76,12.78 96.61,12.78 96.52,12.69 96.52,11.43 96.59,11.35 v2(96.93,11.35)
  BOTTOM w0.081: UC1.AK45 143.72,57.24 v2(143.45,56.97)
  BOTTOM w0.102: v2(96.93,11.35) 95.5,9.93 JDIMM1.56
DDR_A_D53: length 85.4
  IN4 w0.089: v2(96.93,9.83) 96.17,10.58 96.17,20.69 96.7,21.22 96.7,25.52 106.12,34.94 126.35,34.94 135.06,43.66 135.06,44.94 138.67,48.55 138.67,50.3 139.1,50.73 139.1,54.38 140.12,55.4 140.12,57 141.16,58.04 143.26,58.04 v2(144.34,56.96)
  BOTTOM w0.081: v2(144.34,56.96) 144.62,57.24 UC1.AK43
  BOTTOM w0.102: JDIMM1.58 96.1,9.32 96.61,9.83 v2(96.93,9.83)
DDR_A_D54: length 85.1
  IN4 w0.089: v2(99.7,9.83) 100.02,9.83 100.43,10.24 100.43,10.66 100.55,10.78 101.93,10.78 102.02,10.86 102.02,14.15 101.93,14.24 100.52,14.24 100.43,14.33 100.43,16.46 99.35,17.54 99.35,21.53 100.27,22.45 100.27,25.19 107.56,32.47 127.42,32.47 137.62,42.67 137.62,44.34 140.22,46.94 141.95,46.94 143.09,48.08 143.09,52.55 143.82,53.29 145.51,53.29 145.83,53.61 145.83,55.16 v2(146.26,55.59)
  BOTTOM w0.081: v2(146.26,55.59) 146.61,55.94 UC1.AM40
  BOTTOM w0.102: v2(99.7,9.83) 99.1,9.23 JDIMM1.68
DDR_A_D55: length 84.9
  IN4 w0.089: v2(145.35,55.71) 145.35,55.59 144.46,54.7 144.26,54.7 144.02,54.46 144.02,53.76 142.86,52.6 142.86,52.43 142.63,52.2 142.33,52.2 142.06,51.93 142.06,49.18 137.3,44.42 137.3,42.81 127.29,32.79 107.42,32.79 99.95,25.32 99.95,22.58 99,21.63 99,17.43 100.11,16.32 100.11,13.85 100.2,13.76 101.61,13.76 101.7,13.67 101.7,13.36 101.61,13.27 100.2,13.27 100.11,13.18 100.11,12.85 100.2,12.76 101,12.76 101.13,12.63 101.13,12.39 101,12.26 100.2,12.26 100.11,12.17 100.11,11.76 v2(99.7,11.35)
  BOTTOM w0.081: UC1.AM42 145.58,55.94 v2(145.35,55.71)
  BOTTOM w0.102: JDIMM1.70 99.7,9.22 100.13,9.65 100.13,10.92 v2(99.7,11.35)
DDR_A_D56: length 59.6
  IN1 w0.076: 139.91,46.78 139.91,48.68 140.32,49.08 140.32,49.49 139.79,50.02 139.79,52.78 140.38,53.38 140.82,53.38 141.08,53.64 141.08,54.42 141.53,54.88 141.58,54.88 142.09,55.39 142.09,55.81 v2(142.49,56.21)
  IN1 w0.089: v2(139.05,11.14) 139.05,10.88 138.92,10.76 138.73,10.76 138.6,10.88 138.6,12.02 139.14,12.56 139.14,13.63 139.23,13.72 139.8,13.72 139.93,13.84 139.93,14.08 139.8,14.21 139.23,14.21 139.14,14.3 139.14,14.62 139.23,14.71 140.11,14.71 140.24,14.83 140.24,15.08 140.11,15.21 139.27,15.21 139.14,15.34 139.14,16.05 139.27,16.18 139.7,16.18 139.82,16.05 139.82,15.89 139.95,15.76 140.45,15.76 140.57,15.89 140.57,29.43 137.19,32.81 137.19,44.06 139.91,46.78
  BOTTOM w0.081: UC1.AM46 142.76,55.94 v2(142.49,56.21)
  BOTTOM w0.102: v2(139.05,11.14) 138.62,10.71 138.62,9.44 138.7,9.36 JDIMM1.192
DDR_A_D57: length 59.1
  IN1 w0.076: v2(142.49,56.86) 142.86,56.49 142.86,55.41 141.91,54.45 141.91,53.51 141.59,53.19 140.45,53.19 139.98,52.72 139.98,50.1 140.51,49.57 140.51,48.98 140.17,48.64 140.17,46.66
  IN1 w0.089: v2(139.05,9.61) 139.59,10.16 139.59,12 139.72,12.13 140.78,12.13 140.9,12.26 140.9,12.5 140.78,12.63 139.58,12.63 139.46,12.76 139.46,13 139.58,13.12 140.78,13.12 140.9,13.25 140.9,13.64 140.78,13.77 140.37,13.77 140.24,13.89 140.24,14.39 140.56,14.71 140.56,15.08 140.92,15.44 140.92,29.7 137.51,33.1 137.51,44.01 140.17,46.66
  BOTTOM w0.081: v2(142.49,56.86) 142.87,57.24 UC1.AK46
  BOTTOM w0.102: JDIMM1.194 139.3,9.36 v2(139.05,9.61)
DDR_A_D58: length 56.8
  IN1 w0.076: v2(140.58,55.64) 140.22,55.64 139.81,55.23 139.42,55.23 138.6,54.42 138.6,52.69 138.81,52.49 138.81,47.56
  IN1 w0.089: v2(137.22,18.01) 137.22,16.23 136.03,15.04 136.03,13.32 136.16,13.19 136.88,13.19 137,13.32 137,13.73 136.92,13.82 136.64,13.82 136.54,13.92 136.54,14.24 136.66,14.36 136.88,14.36 137,14.49 137,15.17 137.4,15.57 137.81,15.57 137.94,15.7 137.94,23.37 136.75,24.56 136.75,30.66 135.36,32.05 135.36,42.56 135.63,42.84 135.63,44.39 138.81,47.56
  BOTTOM w0.081: UC1.AM49 140.88,55.94 v2(140.58,55.64)
  BOTTOM w0.102: v2(137.22,18.01) 136.57,18.01 136,17.44 JDIMM1.183
DDR_A_D59: length 56.7
  IN1 w0.076: 138.16,48.1 138.16,48.69 137.66,49.19 137.66,52.51 137.2,52.97 137.2,57.12 137.69,57.61 139.91,57.61 v2(140.58,56.94)
  IN1 w0.089: 138.16,48.1 134.87,44.81 134.87,43.41 134.41,42.94 134.41,30.29 135.8,28.89 135.8,22.42 136,22.22 136,15.91 135.37,15.28 135.37,10.33 v2(136.09,9.61)
  BOTTOM w0.081: UC1.AK49 140.88,57.24 v2(140.58,56.94)
  BOTTOM w0.102: JDIMM1.182 135.7,9.23 v2(136.09,9.61)
DDR_A_D60: length 58.5
  IN1 w0.076: 139.38,46.93 139.38,52.95 140.01,53.58 140.01,54.53 140.37,54.89 140.99,54.89 141.54,55.44 v2(141.54,55.62)
  IN1 w0.089: v2(139.14,19.53) 139.78,19.53 139.86,19.62 139.86,20.54 139.77,20.62 139.37,20.62 139.14,20.85 139.14,23.92 138.47,24.59 138.47,24.88 138.39,24.96 138.1,24.96 137.95,25.11 137.95,25.57 138.07,25.69 138.44,25.69 138.57,25.56 138.78,25.56 138.92,25.7 138.92,26.09 139.24,26.4 139.72,26.4 139.86,26.54 139.86,27.2 139.66,27.4 139.48,27.4 138.3,26.22 138.12,26.22 137.95,26.39 137.95,26.88 138.14,27.06 138.44,27.06 139.36,27.98 139.8,27.98 139.86,28.04 139.86,28.66 139.69,28.83 139.51,28.83 138.3,27.62 138.12,27.62 137.99,27.76 137.99,28.54 138.14,28.69 138.67,28.69 139.42,29.44 139.42,29.69 139.17,29.94 139.04,29.94 138.39,29.29 138.2,29.29 137.95,29.53 137.95,29.8 138.12,29.97 138.37,29.97 138.64,30.24 138.64,30.43 138.46,30.61 138.02,30.61 137.95,30.68 137.95,31.15 136.56,32.55 136.56,44.1 139.38,46.93
  BOTTOM w0.081: UC1.AM48 141.86,55.94 v2(141.54,55.62)
  BOTTOM w0.102: JDIMM1.191 138.4,18.8 v2(139.14,19.53)
DDR_A_D61: length 57.9
  IN1 w0.076: v2(141.54,56.92) 141.91,56.54 141.91,55.46 141.52,55.07 141.45,55.07 141.09,54.71 140.44,54.71 140.19,54.46 140.19,53.48 139.57,52.86 139.57,46.77
  IN1 w0.089: v2(139.14,18.01) 139.14,18.01 139.14,16.62 139.27,16.5 140.05,16.5 140.18,16.62 140.18,18.46 140.09,18.55 139.63,18.55 139.54,18.64 139.54,18.96 139.63,19.05 140.09,19.05 140.18,19.14 140.18,21.53 140.09,21.62 139.58,21.62 139.46,21.75 139.46,21.99 139.58,22.12 140.09,22.12 140.18,22.21 140.18,22.52 140.09,22.61 139.58,22.61 139.46,22.74 139.46,22.98 139.58,23.11 140.09,23.11 140.18,23.2 140.18,23.52 140.09,23.6 139.58,23.6 139.46,23.73 139.46,23.97 139.58,24.1 140.09,24.1 140.18,24.19 140.18,24.51 140.09,24.59 138.91,24.59 138.79,24.72 138.79,24.96 138.91,25.09 140.09,25.09 140.18,25.18 140.18,25.5 140.09,25.59 139.37,25.59 139.24,25.71 139.24,25.95 139.37,26.08 140.09,26.08 140.18,26.17 140.18,29.37 136.88,32.68 136.88,44.07 139.57,46.77
  BOTTOM w0.081: UC1.AK48 141.86,57.24 v2(141.54,56.92)
  BOTTOM w0.102: v2(139.14,18.01) 139,17.87 JDIMM1.193
DDR_A_D62: length 55.7
  IN1 w0.076: v2(139.63,55.62) 139.15,56.1 139.15,56.46 138.99,56.63 138.52,56.63 138.24,56.35 138.24,52.78 138.62,52.4 138.62,47.7
  IN1 w0.089: 138.62,47.7 135.38,44.46 135.38,43.03 135.04,42.69 135.04,31.62 135.33,31.33 135.63,31.33 135.79,31.17 135.79,31.04 135.22,30.48 135.22,30.37 135.47,30.13 135.57,30.13 136.14,30.69 136.26,30.69 136.43,30.52 136.43,29.98 136.36,29.91 136.17,29.91 136.09,29.83 136.09,29.5 136.17,29.43 136.36,29.43 136.43,29.35 136.43,24.43 136.63,24.24 136.63,24.15 136.43,23.95 136.43,23.77 136.54,23.67 136.82,23.67 136.94,23.79 137.08,23.79 137.46,23.41 137.46,23.27 137.37,23.17 136.51,23.17 136.43,23.1 136.43,22.75 136.51,22.68 137.55,22.68 137.62,22.6 137.62,22.26 137.55,22.18 136.71,22.18 136.63,22.11 136.63,21.76 136.71,21.69 137.55,21.69 137.62,21.61 137.62,21.27 137.55,21.19 136.71,21.19 136.63,21.12 136.63,20.77 136.71,20.7 137.53,20.7 137.62,20.61 137.62,19.28 137.5,19.15 137.35,19.15 137.22,19.28 v2(137.22,19.53)
  BOTTOM w0.081: UC1.AM51 139.96,55.94 v2(139.63,55.62)
  BOTTOM w0.102: v2(137.22,19.53) 135.4,17.71 JDIMM1.181
DDR_A_D63: length 55.4
  IN1 w0.076: v2(139.63,56.92) 139.1,57.44 137.76,57.44 137.37,57.06 137.37,53.09 137.84,52.62 137.84,49.29 138.34,48.79 138.34,47.79
  IN1 w0.089: 138.34,47.79 135.13,44.57 135.13,43.22 134.72,42.82 134.72,30.42 136.12,29.03 136.12,22.55 136.32,22.36 136.32,15.78 135.69,15.15 135.69,11.54 v2(136.09,11.14)
  BOTTOM w0.081: UC1.AK51 139.72,56.92 v2(139.63,56.92)
  BOTTOM w0.102: v2(136.09,11.14) 135.1,10.15 JDIMM1.180
DDR_A_DQS0: length 59.3
  IN1 w0.102: v2(122.08,19.15) 122.08,19.4 122.21,19.53 122.55,19.53 122.72,19.7 122.72,29 122.82,29.1 123.23,29.1 123.45,29.32 123.45,29.78 123.23,30 122.82,30 122.72,30.1 122.72,30.41 122.82,30.51 123.23,30.51 123.45,30.72 123.45,31.19 123.23,31.41 122.82,31.41 122.72,31.51 122.72,31.81 122.82,31.92 123.23,31.92 123.45,32.13 123.45,32.6 123.23,32.81 122.82,32.81 122.72,32.92 122.72,33.22 122.82,33.32 123.23,33.32 123.45,33.54 123.45,34.01 123.23,34.22 122.82,34.22 122.72,34.32 122.72,34.63 122.82,34.73 123.23,34.73 123.45,34.95 123.45,35.41 123.23,35.63 122.82,35.63 122.72,35.73 122.72,36.04 122.82,36.14 123.23,36.14 123.45,36.35 123.45,36.82 123.23,37.04 122.82,37.04 122.72,37.14 122.72,37.44 122.82,37.54 123.23,37.54 123.45,37.76 123.45,38.23 123.23,38.44 122.82,38.44 122.72,38.55 122.72,38.85 122.82,38.95 123.23,38.95 123.45,39.17 123.45,39.63 123.23,39.85 122.97,39.85 122.84,39.98 122.84,40.23 122.97,40.36 123.23,40.36 123.45,40.57 123.45,45.7 124.79,47.04 124.79,47.49 127.56,50.27 127.56,52.44 128.32,53.19 128.32,53.71 127.98,54.05 127.98,54.38 v2(128.02,54.42)
  BOTTOM w0.076: UC1.AJ62 133.14,57.56 133.31,57.56 133.38,57.63 133.38,57.72 133.3,57.8 133.2,57.85 133.07,57.85 132.91,57.78 132.69,57.78 132.65,57.8 132.65,57.8 132.54,57.85 132.42,57.85 132.4,57.84 132.38,57.84 132.36,57.83 132.36,57.82 132.36,57.82 132.31,57.8 132.31,57.8 132.31,57.8 132.24,57.77 131.57,57.77 131.46,57.66 130.05,57.66 129.62,57.22 129.62,57.21
  BOTTOM w0.102: v2(128.02,54.42) 127.73,54.42 127.57,54.58 127.57,55.16 129.62,57.21 ; JDIMM1.137 122.2,17.39 122,17.59 122,17.83 121.63,18.21 121.63,19.38 121.75,19.51 121.97,19.51 122.08,19.4 v2(122.08,19.15)
DDR_A_DQS1: length 85.2
  IN4 w0.084: 129.5,52.25 129.51,52.26 129.52,52.26 129.56,52.3 129.57,52.3 130.68,53.4 130.68,54.03 v2(130.49,54.22)
  IN4 w0.102: v2(82.32,10.97) 82.15,11.14 81.85,11.14 81.17,11.82 81.17,24.17 102.09,45.09 116.4,45.09 117.03,45.72 123.2,45.72 128.94,51.47 128.94,51.69 129.5,52.25
  BOTTOM w0.076: v2(130.49,54.22) 130.49,54.45 130.36,54.58 130.36,54.9 130.98,55.52 132.23,55.52 132.38,55.58 132.58,55.58 132.74,55.51 133.16,55.51 133.32,55.35 133.56,55.35 UC1.AN61
  BOTTOM w0.102: JDIMM1.12 82.3,9.55 81.52,10.34 81.52,11 81.7,11.18 82.11,11.18 v2(82.32,10.97)
DDR_A_DQS2: length 54.6
  IN1 w0.089: 133.34,52.29 133.35,52.3 133.35,52.31 133.39,52.35 133.39,52.36 133.72,52.69 133.72,54.32 134.6,55.21 134.82,55.21 134.93,55.1 v2(134.93,54.96)
  IN1 w0.102: v2(127.2,10.76) 127.2,11.04 127.27,11.12 127.78,11.12 127.97,11.31 127.97,12.59 128.08,12.69 128.5,12.69 128.72,12.91 128.72,13.37 128.5,13.59 127.59,13.59 127.18,14.01 127.18,15.13 127.92,15.87 127.92,44.93 128.49,45.5 128.49,45.96 129.77,47.24 129.77,48.08 132.18,50.49 132.18,51.14 133.34,52.29
  BOTTOM w0.081: v2(134.93,54.96) 135.25,55.29 UC1.AN58
  BOTTOM w0.102: v2(127.2,10.76) 126.92,11.04 126.81,11.04 126.68,10.9 126.68,9.91 127.01,9.58 127.01,9.49 127.3,9.19 JDIMM1.154
DDR_A_DQS3: length 81.4
  IN4 w0.089: v2(137.78,55.62) 137.75,55.65 137.46,55.65 137.4,55.59 137.4,53.22 135.2,51.02 133.96,51.02 130.26,47.32 130.26,47.01 130.08,46.83 130.08,46.82 130.04,46.78 130.04,46.77 130.03,46.76
  IN4 w0.102: 130.03,46.76 125.1,41.83 118.64,41.83 118.01,41.2 104.2,41.2 88.61,25.6 88.61,25.48 89.04,25.05 89.04,24.79 88.66,24.41 88.4,24.41 87.96,24.85 87.85,24.85 87.48,24.47 87.48,24.39 88.12,23.75 88.12,23.47 87.95,23.3 87.21,23.3 87.17,23.25 87.17,22.87 87.25,22.79 88.25,22.79 88.43,22.6 88.43,22.08 88.24,21.89 87.25,21.89 87.17,21.8 87.17,21.51 87.4,21.27 87.55,21.27 87.66,21.38 88.26,21.38 88.43,21.2 88.43,20.79 88.05,20.4 88.05,19.71 87.87,19.53 87.44,19.53 87.25,19.34 v2(87.25,19.15)
  BOTTOM w0.081: v2(137.78,55.62) 137.55,55.62 UC1.AN55
  BOTTOM w0.102: v2(87.25,19.15) 86.97,19.43 86.84,19.43 86.72,19.32 86.72,18.24 87.18,17.78 87.18,17.66 87.4,17.43 JDIMM1.29
DDR_A_DQS4: length 48.2
  IN1 w0.102: v2(132.23,48.01) 132.39,48.01 132.58,47.82 132.58,47.18 131.72,46.32 131.72,44.73 132,44.45 132,26.65 132.39,26.26 133.09,26.26 133.18,26.17 133.18,25.72 133.07,25.62 132.21,25.62 131.99,25.4 131.99,24.94 132.21,24.72 133.07,24.72 133.18,24.62 133.18,24.31 133.07,24.21 132.21,24.21 131.99,24 131.99,23.53 132.21,23.31 133.07,23.31 133.18,23.21 133.18,22.91 133.07,22.8 132.3,22.8 132.11,22.61 132.11,22.1 132.3,21.91 133.07,21.91 133.18,21.8 133.18,19.73 133.09,19.64 132.93,19.64 v2(132.65,19.91)
  BOTTOM w0.076: v2(132.23,48.01) 132.27,48.05 132.61,48.05 132.77,47.89 133.3,47.89 134.18,48.77 134.43,48.77 135.59,49.93 135.59,50.48 135.8,50.69 135.8,50.98 135.78,51.03 135.78,51.03 135.74,51.12 135.73,51.14 135.73,51.27 135.78,51.37 135.78,51.37 135.8,51.43 135.8,51.62 135.72,51.79 135.72,51.92 135.77,52.02 135.85,52.11 135.94,52.11 136.02,52.03 136.02,51.86 UC1.AW57
  BOTTOM w0.102: v2(132.65,19.91) 132.93,19.63 133.12,19.63 133.36,19.39 133.36,18.16 132.95,17.75 132.34,17.75 132.2,17.61 132.2,17.51 132.4,17.31 JDIMM1.171
DDR_A_DQS5: length 76.9
  IN4 w0.089: v2(137.34,48.05) 137.2,47.92 137.06,47.92 137.03,47.95 136.97,47.95 136.57,48.35 136.27,48.35 131.52,43.6 131.52,43.29 131.06,42.84
  IN4 w0.102: v2(93.39,19.15) 93.39,19.4 93.26,19.53 92.89,19.53 92.65,19.77 92.65,21.49 92.87,21.71 93.86,21.71 93.92,21.77 93.92,22.17 93.84,22.25 92.86,22.25 92.65,22.46 92.65,22.93 93.01,23.29 93.3,23.29 93.45,23.15 93.8,23.15 93.92,23.27 93.92,23.55 93.74,23.73 93.74,24.02 93.92,24.21 93.92,25.92 105.19,37.19 108.61,37.19 108.71,37.29 108.71,37.45 108.92,37.67 109.41,37.67 109.61,37.47 109.61,37.26 109.68,37.19 110.1,37.19 110.18,37.27 110.18,37.48 110.37,37.67 110.91,37.67 111.08,37.49 111.08,37.26 111.15,37.19 111.5,37.19 111.6,37.29 111.6,37.5 111.77,37.67 112.31,37.67 112.5,37.47 112.5,37.26 112.57,37.19 112.99,37.19 113.1,37.3 113.1,37.47 113.29,37.67 113.78,37.67 114,37.45 114,37.29 114.1,37.19 114.41,37.19 114.51,37.29 114.51,37.45 114.72,37.67 115.19,37.67 115.41,37.45 115.41,37.29 115.51,37.19 115.81,37.19 115.92,37.29 115.92,37.45 116.13,37.67 116.6,37.67 116.81,37.45 116.81,37.29 116.92,37.19 117.22,37.19 117.32,37.29 117.32,37.45 117.54,37.67 118.01,37.67 118.22,37.45 118.22,37.26 118.29,37.19 118.64,37.19 118.73,37.28 118.73,37.45 118.95,37.67 125.89,37.67 131.06,42.84
  BOTTOM w0.076: v2(137.34,48.05) 137.31,48.03 137.12,48.03 137.04,48.1 137.04,48.38 137.48,48.81 137.48,48.96 137.87,49.35 137.87,50.15 138.08,50.37 138.08,50.52 138.23,50.67 138.23,50.98 138.16,51.13 138.16,51.3 138.24,51.45 138.24,51.65 UC1.AW53
  BOTTOM w0.102: JDIMM1.47 92.8,17.37 92.57,17.6 92.57,19.15 92.83,19.41 93.14,19.41 v2(93.39,19.15)
DDR_A_DQS6: length 84.8
  IN4 w0.089: v2(145.35,56.32) 145.18,56.32 144.97,56.11 144.97,55.56 144.5,55.09 144.13,55.09 143.9,54.86 143.44,54.86 143.1,54.52 143.1,53.63 142.55,53.08 142.42,53.08 141.67,52.32 141.67,49.88 140.05,48.26 140.05,47.98 136.79,44.73 136.79,43.01 135.89,42.1
  IN4 w0.102: 135.89,42.1 127.08,33.29 107.22,33.29 99.45,25.53 99.45,22.79 98.35,21.69 98.35,16.59 98.45,16.49 99.24,16.49 99.45,16.28 99.45,15.81 99.24,15.59 98.76,15.59 98.64,15.47 98.64,15.34 98.89,15.08 99.12,15.08 99.45,14.76 99.45,14.19 99.23,13.97 98.87,13.97 98.68,13.79 98.68,13.19 99.22,12.65 99.22,11.5 98.99,11.27 98.73,11.27 v2(98.43,10.97)
  BOTTOM w0.081: UC1.AL42 145.62,56.59 v2(145.35,56.32)
  BOTTOM w0.102: v2(98.43,10.97) 98.13,11.28 97.88,11.28 97.7,11.1 97.7,9.6 97.9,9.4 JDIMM1.64
DDR_A_DQS7: length 57.2
  IN1 w0.076: 138.81,47.08 139.01,47.28 139.01,52.57 138.87,52.71 138.87,54.32 139.45,54.91 139.79,54.91 140.16,55.28 140.84,55.28 140.99,55.43 140.99,55.89 v2(140.58,56.29)
  IN1 w0.089: 138.81,47.08 135.87,44.14 135.87,42.11 135.86,42.1
  IN1 w0.102: 135.86,42.1 135.86,32.26 137.25,30.86 137.25,24.82 138.44,23.63 138.44,14.68 138.31,14.55 137.77,14.55 137.53,14.3 137.53,13.75 137.77,13.51 138.21,13.51 138.34,13.39 138.34,13.02 138.21,12.9 137.29,12.9 136.52,12.12 136.52,11.48 136.79,11.2 137.53,11.2 137.78,10.95 v2(137.78,10.76)
  BOTTOM w0.081: UC1.AL49 140.88,56.59 v2(140.58,56.29)
  BOTTOM w0.102: JDIMM1.188 137.5,9.31 137.3,9.5 137.3,10.92 137.42,11.04 137.59,11.04 137.78,10.85 v2(137.78,10.76)
DDR_A_DQS#0: length 59.3
  IN1 w0.102: v2(127.57,54) 127.75,54 128.12,53.62 128.12,53.28 127.36,52.52 127.36,50.35 124.59,47.58 124.59,47.12 123.25,45.78 123.25,40.66 123.15,40.55 122.89,40.55 122.65,40.31 122.65,39.9 122.89,39.65 123.15,39.65 123.25,39.55 123.25,39.25 123.15,39.15 122.74,39.15 122.53,38.93 122.53,38.46 122.74,38.25 123.15,38.25 123.25,38.15 123.25,37.84 123.15,37.74 122.74,37.74 122.53,37.52 122.53,37.06 122.74,36.84 123.15,36.84 123.25,36.74 123.25,36.43 123.15,36.33 122.74,36.33 122.53,36.12 122.53,35.65 122.74,35.43 123.15,35.43 123.25,35.33 123.25,35.03 123.15,34.93 122.74,34.93 122.53,34.71 122.53,34.24 122.74,34.03 123.15,34.03 123.25,33.92 123.25,33.62 123.15,33.52 122.74,33.52 122.53,33.3 122.53,32.84 122.74,32.62 123.15,32.62 123.25,32.52 123.25,32.21 123.15,32.11 122.74,32.11 122.53,31.9 122.53,31.43 122.74,31.21 123.15,31.21 123.25,31.11 123.25,30.81 123.15,30.7 122.74,30.7 122.53,30.49 122.53,30.02 122.74,29.8 123.15,29.8 123.25,29.7 123.25,29.4 123.15,29.3 122.74,29.3 122.53,29.08 122.53,19.78 122.47,19.72 122.2,19.72 122.08,19.84 v2(122.08,19.91)
  BOTTOM w0.076: UC1.AJ61 133.46,57.88 133.4,57.94 133.29,57.99 133.24,58.02 133.03,58.02 132.97,57.99 132.87,57.94 132.73,57.94 132.58,58.01 132.38,58.01 132.32,57.98 132.25,57.95 132.21,57.93 131.48,57.93 131.38,57.83 129.96,57.83 129.47,57.35
  BOTTOM w0.102: 129.47,57.35 127.37,55.24 127.37,54.49 127.57,54.29 v2(127.57,54) ; v2(122.08,19.91) 121.88,19.71 121.67,19.71 121.42,19.46 121.42,18.13 121.8,17.75 121.8,17.58 121.6,17.38 JDIMM1.135
DDR_A_DQS#1: length 85.1
  IN4 w0.084: v2(130.88,54.6) 130.86,54.58 130.86,53.33 129.64,52.11
  IN4 w0.102: 129.64,52.11 129.14,51.61 129.14,51.39 123.28,45.53 117.11,45.53 116.48,44.9 102.17,44.9 81.37,24.09 81.37,11.9 81.93,11.33 82.06,11.33 82.32,11.6 v2(82.32,11.73)
  BOTTOM w0.076: UC1.AN62 133.17,55.17 133.17,55.24 133.07,55.34 132.71,55.34 132.65,55.37 132.56,55.41 132.55,55.42 132.43,55.42 132.27,55.35 131.05,55.35 130.54,54.84 130.54,54.66 130.59,54.6 v2(130.88,54.6)
  BOTTOM w0.102: v2(82.32,11.73) 82.32,11.48 82.22,11.38 81.62,11.38 81.32,11.08 81.32,10.26 82.08,9.49 82.08,9.39 82.01,9.32 81.76,9.32 81.7,9.27 JDIMM1.10
DDR_A_DQS#2: length 54.6
  IN1 w0.089: 133.2,52.43 133.22,52.45 133.54,52.77 133.54,54.4 134.53,55.39 134.7,55.39 v2(134.93,55.62)
  IN1 w0.102: v2(127.2,11.52) 127.4,11.32 127.7,11.32 127.78,11.39 127.78,12.67 127.99,12.89 128.42,12.89 128.52,12.99 128.52,13.29 128.42,13.39 127.51,13.39 126.98,13.93 126.98,15.21 127.72,15.95 127.72,45.01 128.29,45.58 128.29,46.04 129.58,47.32 129.58,48.16 131.99,50.57 131.99,51.22 133.2,52.43
  BOTTOM w0.081: UC1.AM58 135.25,55.94 v2(134.93,55.62)
  BOTTOM w0.102: v2(127.2,11.52) 127.2,11.37 127.06,11.24 126.73,11.24 126.48,10.98 126.48,9.82 126.81,9.49 126.81,9.35 126.7,9.25 JDIMM1.152
DDR_A_DQS#3: length 81.4
  IN4 w0.089: v2(136.83,55.62) 136.83,55.71 136.95,55.83 137.11,55.83 137.22,55.72 137.22,53.29 137.22,53.29 137.22,53.29 135.13,51.2 133.89,51.2 130.08,47.4 130.08,47.09 129.89,46.9
  IN4 w0.102: v2(87.25,19.91) 87.44,19.73 87.79,19.73 87.85,19.79 87.85,20.48 88.24,20.87 88.24,21.12 88.17,21.18 87.74,21.18 87.64,21.08 87.32,21.08 86.97,21.43 86.97,21.88 87.17,22.08 88.16,22.08 88.24,22.16 88.24,22.52 88.16,22.59 87.17,22.59 86.97,22.79 86.97,23.33 87.13,23.49 87.87,23.49 87.93,23.55 87.93,23.67 87.28,24.31 87.28,24.56 87.77,25.04 88.05,25.04 88.48,24.6 88.58,24.6 88.84,24.87 88.84,24.97 88.41,25.4 88.41,25.68 104.12,41.39 117.93,41.39 118.56,42.02 125.02,42.02 129.89,46.9
  BOTTOM w0.081: v2(136.83,55.62) 137.02,55.62 137.22,55.81 UC1.AM55
  BOTTOM w0.102: JDIMM1.27 86.8,17.42 86.98,17.6 86.98,17.7 86.52,18.16 86.52,19.4 86.76,19.63 86.97,19.63 v2(87.25,19.91)
DDR_A_DQS#4: length 48.2
  IN1 w0.102: v2(132.69,48.47) 132.57,48.35 132.57,48.19 132.6,48.16 132.6,48.08 132.78,47.9 132.78,47.1 131.91,46.24 131.91,44.82 132.2,44.53 132.2,26.73 132.47,26.45 133.17,26.45 133.37,26.25 133.37,25.64 133.16,25.42 132.29,25.42 132.19,25.32 132.19,25.02 132.29,24.92 133.16,24.92 133.37,24.7 133.37,24.23 133.16,24.02 132.29,24.02 132.19,23.91 132.19,23.61 132.29,23.51 133.16,23.51 133.37,23.29 133.37,22.82 133.16,22.61 132.38,22.61 132.31,22.53 132.31,22.18 132.38,22.1 133.16,22.1 133.37,21.88 133.37,19.65 133.17,19.45 132.94,19.45 v2(132.65,19.15)
  BOTTOM w0.076: UC1.AV57 136.02,52.5 136.02,52.35 135.94,52.27 135.79,52.27 135.7,52.18 135.64,52.12 135.56,51.96 135.56,51.76 135.59,51.69 135.64,51.59 135.64,51.46 135.62,51.42 135.62,51.42 135.56,51.31 135.56,51.1 135.59,51.05 135.58,51.04 135.63,50.94 135.63,50.76 135.42,50.55 135.42,50.01 134.36,48.94 134.1,48.94 133.23,48.07 132.84,48.07 132.69,48.22 v2(132.69,48.47)
  BOTTOM w0.102: JDIMM1.169 131.8,17.28 132,17.48 132,17.7 132.26,17.95 132.87,17.95 133.16,18.24 133.16,19.31 133.03,19.43 132.93,19.43 v2(132.65,19.15)
DDR_A_DQS#5: length 76.9
  IN4 w0.089: 131.28,42.77 131.7,43.19 131.7,43.52 136.34,48.17 136.5,48.17 136.88,47.79 v2(136.88,47.59)
  IN4 w0.102: v2(93.39,19.91) 93.2,19.72 92.97,19.72 92.85,19.85 92.85,21.41 92.95,21.51 93.94,21.51 94.12,21.69 94.12,22.25 93.92,22.44 92.94,22.44 92.84,22.54 92.84,22.85 93.09,23.1 93.22,23.1 93.37,22.95 93.88,22.95 94.12,23.19 94.12,23.63 93.93,23.81 93.93,23.94 94.12,24.13 94.12,25.84 105.27,36.99 108.69,36.99 108.9,37.21 108.9,37.37 109,37.47 109.33,37.47 109.41,37.39 109.41,37.18 109.6,36.99 110.18,36.99 110.38,37.19 110.38,37.4 110.45,37.47 110.83,37.47 110.89,37.41 110.89,37.18 111.07,36.99 111.58,36.99 111.8,37.21 111.8,37.42 111.85,37.47 112.22,37.47 112.31,37.39 112.31,37.18 112.49,36.99 113.07,36.99 113.3,37.22 113.3,37.39 113.37,37.47 113.7,37.47 113.8,37.37 113.8,37.21 114.02,36.99 114.49,36.99 114.7,37.21 114.7,37.37 114.81,37.47 115.11,37.47 115.21,37.37 115.21,37.21 115.43,36.99 115.89,36.99 116.11,37.21 116.11,37.37 116.21,37.47 116.52,37.47 116.62,37.37 116.62,37.21 116.83,36.99 117.3,36.99 117.52,37.21 117.52,37.37 117.62,37.47 117.92,37.47 118.03,37.37 118.03,37.18 118.21,36.99 118.72,36.99 118.93,37.2 118.93,37.37 119.03,37.47 125.97,37.47 131.28,42.77
  BOTTOM w0.076: v2(136.88,47.59) 136.88,48.02 136.87,48.03 136.87,48.45 137.3,48.89 137.3,49.03 137.69,49.42 137.69,50.22 137.91,50.44 137.91,50.59 138.06,50.74 138.06,50.95 137.98,51.1 137.98,51.33 138.07,51.45 138.07,51.95 138.18,52.06 138.18,52.23 UC1.AV53
  BOTTOM w0.102: v2(93.39,19.91) 93.08,19.61 92.74,19.61 92.37,19.24 92.37,17.58 92.2,17.4 JDIMM1.45
DDR_A_DQS#6: length 84.8
  IN4 w0.089: 135.61,42.1 136.61,43.1 136.61,44.8 139.86,48.06 139.86,48.34 141.48,49.96 141.48,52.4 142.35,53.27 142.48,53.27 142.91,53.7 142.91,54.59 143.36,55.04 143.82,55.04 144.05,55.27 144.42,55.27 144.79,55.63 144.79,56.13 144.52,56.39 v2(144.39,56.39)
  IN4 w0.102: 135.61,42.1 127,33.49 107.14,33.49 99.25,25.61 99.25,22.87 98.15,21.77 98.15,16.51 98.37,16.3 99.15,16.3 99.26,16.19 99.26,15.89 99.15,15.79 98.68,15.79 98.44,15.55 98.44,15.26 98.81,14.89 99.04,14.89 99.26,14.68 99.26,14.27 99.15,14.17 98.79,14.17 98.49,13.87 98.49,13.11 99.03,12.56 99.03,11.58 98.91,11.46 98.7,11.46 v2(98.43,11.73)
  BOTTOM w0.081: UC1.AL43 144.59,56.59 v2(144.39,56.39)
  BOTTOM w0.102: JDIMM1.62 97.3,9.33 97.5,9.53 97.5,11.18 97.79,11.48 98.18,11.48 v2(98.43,11.73)
DDR_A_DQS#7: length 57.2
  IN1 w0.076: v2(141.54,56.27) 141.48,56.32 141.23,56.32 141.08,56.17 141.08,56.06 141.17,55.96 141.17,55.35 140.92,55.1 140.24,55.1 139.86,54.72 139.53,54.72 139.05,54.25 139.05,52.79 139.18,52.66 139.18,47.19 138.94,46.95
  IN1 w0.089: 138.94,46.95 136.05,44.07 136.05,42.11 136.06,42.1
  IN1 w0.102: v2(137.78,11.52) 137.66,11.4 136.87,11.4 136.71,11.56 136.71,12.04 137.37,12.7 138.29,12.7 138.53,12.94 138.53,13.47 138.29,13.71 137.86,13.71 137.73,13.83 137.73,14.22 137.86,14.35 138.39,14.35 138.64,14.6 138.64,23.71 137.45,24.9 137.45,30.94 136.06,32.34 136.06,42.1
  BOTTOM w0.081: v2(141.54,56.27) 141.86,56.59 UC1.AL48
  BOTTOM w0.102: JDIMM1.186 136.9,9.31 137.1,9.5 137.1,11.01 137.33,11.24 137.56,11.24 137.78,11.46 v2(137.78,11.52)
DDR_A_MA0: length 75
  IN4 w0.089: v2(148.78,52.62) 148.22,52.05 148.22,46.66 146.24,44.68 146.24,43.24 145.55,42.55 145.55,42.1
  IN4 w0.145: 145.55,42.1 145.55,37.8 132.93,25.18 110.97,25.18 110.28,24.49 110.28,21.69 109.82,21.24 109.82,17.83 111.29,16.36 111.29,10.8 v2(110.86,10.38)
  BOTTOM w0.081: v2(148.78,52.62) 149,52.83 UC1.AU36
  BOTTOM w0.168: v2(110.86,10.38) 110.38,9.9 110.38,9.4 110.5,9.28 JDIMM1.98
DDR_A_MA1: length 75.4
  IN4 w0.089: 146.35,42.1 146.35,42.44 146.67,42.76 146.67,44.42 148.6,46.35 148.6,49.67 v2(148.78,49.85)
  IN4 w0.145: v2(110.25,18.77) 111.08,19.6 111.08,24.16 111.3,24.39 133.26,24.39 134.5,25.62 136.8,25.62 138.89,27.72 138.89,27.91 137.93,28.87 137.93,29.05 138.26,29.38 138.44,29.38 139.41,28.41 139.59,28.41 139.82,28.64 139.82,28.82 138.85,29.79 138.85,29.97 139.08,30.2 139.26,30.2 140.23,29.23 140.41,29.23 140.64,29.46 140.64,29.64 139.67,30.61 139.67,30.79 139.91,31.04 140.06,31.04 141.03,30.07 141.24,30.07 141.44,30.27 141.44,30.94 141.3,31.08 140.84,31.08 140.52,31.4 140.52,31.65 140.78,31.9 141.34,31.9 141.44,32.01 141.44,32.57 146.35,37.47 146.35,42.1
  BOTTOM w0.081: v2(148.78,49.85) 148.36,50.27 UC1.AY37
  BOTTOM w0.168: v2(110.25,18.77) 110.72,18.31 110.72,17.82 110.2,17.3 JDIMM1.97
DDR_A_MA2: length 77.9
  IN4 w0.089: 144.12,42.1 144.12,42.18 145.6,43.66 145.6,44.96 147.69,47.04 147.69,48.62 146.85,49.45 146.85,50.43 147.18,50.76 147.24,50.76 147.76,51.28 v2(147.76,53.66)
  IN4 w0.145: v2(110.86,11.9) 110.26,12.51 110.26,13.13 107.65,15.74 107.65,23.55 110.49,26.4 132.45,26.4 140.09,34.03 140.09,34.77 143.52,38.2 143.52,39.49 144.12,40.09 144.12,42.1
  BOTTOM w0.081: v2(147.76,53.66) 148.08,53.99 UC1.AR38
  BOTTOM w0.168: v2(110.86,11.9) 109.9,10.94 JDIMM1.96
DDR_A_MA3: length 77.2
  IN4 w0.089: 145.95,42.1 145.95,42.49 146.47,43 146.47,44.58 148.4,46.51 148.4,51.97 148.65,52.22 148.96,52.22 149.15,52.41 149.15,53.4 149.11,53.44 149.11,54.07 v2(148.71,54.47)
  IN4 w0.145: 145.95,42.1 145.95,37.64 137.38,29.06 137.38,28.86 138.33,27.9 138.33,27.72 138.1,27.49 137.92,27.49 136.95,28.46 136.77,28.46 136.54,28.23 136.54,28.05 137.51,27.08 137.51,26.9 137.28,26.67 137.1,26.67 136.13,27.64 135.95,27.64 135.72,27.41 135.72,27.23 136.53,26.43 136.53,26.1 136.44,26.02 135.69,26.02 135.57,26.14 135.57,26.57 135.33,26.81 135.12,26.81 134.96,26.65 134.96,26.14 134.84,26.02 134.33,26.02 133.1,24.79 111.14,24.79 110.68,24.32 110.68,20.72 110.26,20.3 v2(110.25,20.3)
  BOTTOM w0.081: v2(148.71,54.47) 148.88,54.64 UC1.AP36
  BOTTOM w0.168: JDIMM1.95 109.6,19.65 v2(110.25,20.3)
DDR_A_MA4: length 76.5
  IN4 w0.089: 143.32,42.1 143.32,43.45 147.33,47.46 147.33,48.46 146.49,49.3 146.49,51.88 v2(147.2,52.58)
  IN4 w0.145: v2(107.56,11.14) 106.98,11.14 106.61,11.51 106.61,23.64 110.2,27.23 132.12,27.23 139.29,34.4 139.29,35.1 142.72,38.53 142.72,39.82 143.32,40.42 143.32,42.1
  BOTTOM w0.081: v2(147.2,52.58) 147.45,52.83 UC1.AU39
  BOTTOM w0.168: JDIMM1.92 108.7,9.99 v2(107.56,11.14)
DDR_A_MA5: length 76.9
  IN4 w0.089: v2(148.71,53.82) 148.71,53.58 148.04,52.91 148.04,46.79 146.03,44.78 146.03,43.45 145.15,42.56 145.15,42.1
  IN4 w0.145: 145.15,42.1 145.15,37.97 132.77,25.58 110.81,25.58 109.88,24.65 109.88,21.86 109.42,21.4 109.42,17.46 110.04,16.84 110.04,15.96 109.87,15.78 108.17,15.78 108.05,15.9 108.05,16.38 108.17,16.51 108.49,16.51 108.62,16.64 108.62,17.17 108.49,17.3 108.17,17.3 108.05,17.42 108.05,18.57 108.25,18.77 v2(108.72,18.77)
  BOTTOM w0.081: UC1.AR36 148.88,53.99 v2(148.71,53.82)
  BOTTOM w0.168: v2(108.72,18.77) 108.61,18.77 108.26,18.42 108.26,17.82 108.4,17.67 JDIMM1.91
DDR_A_MA6: length 78.1
  IN4 w0.089: v2(146.97,47.64) 146.97,47.55 142.92,43.51 142.92,42.1
  IN4 w0.145: v2(107.56,9.61) 106.21,10.96 106.21,23.81 110.06,27.65 131.91,27.65 134.59,30.33 134.59,30.53 134.48,30.65 134.48,30.85 134.68,31.06 134.89,31.06 135,30.94 135.21,30.94 135.41,31.15 135.41,31.35 135.3,31.47 135.3,31.67 135.5,31.88 135.71,31.88 135.82,31.76 136.02,31.76 136.23,31.97 136.23,32.17 136.12,32.28 136.12,32.49 136.32,32.69 136.53,32.69 136.64,32.58 136.84,32.58 137.05,32.79 137.05,32.99 136.94,33.1 136.94,33.31 137.14,33.51 137.35,33.51 137.46,33.4 137.66,33.4 137.87,33.61 137.87,33.81 137.75,33.92 137.75,34.13 137.96,34.33 138.16,34.33 138.28,34.22 138.48,34.22 138.69,34.42 138.69,34.63 138.57,34.74 138.57,34.95 142.32,38.7 142.32,39.98 142.92,40.58 142.92,42.1
  BOTTOM w0.081: v2(146.97,47.64) 147.39,48.06 147.39,48.71 146.49,49.6 146.49,51.41 146.49,51.41 146.49,51.65 146.49,51.65 146.49,51.89 UC1.AV40
  BOTTOM w0.168: v2(107.56,9.61) 107.74,9.61 108.1,9.26 JDIMM1.90
DDR_A_MA7: length 76.6
  IN4 w0.089: 143.72,42.1 143.72,42.57 144.23,43.08 144.72,43.08 145.36,43.72 145.36,45.02 147.51,47.17 147.51,48.54 146.67,49.38 146.67,50.7 v2(147.2,51.23)
  IN4 w0.145: v2(107.56,12.66) 107.56,13 107.69,13.13 108.57,13.13 108.7,13.26 108.7,13.76 108.57,13.89 107.26,13.89 107.13,14.01 107.13,23.6 110.33,26.8 132.25,26.8 139.69,34.24 139.69,34.94 140.33,35.57 143.12,38.37 143.12,39.65 143.72,40.25 143.72,42.1
  BOTTOM w0.081: v2(147.2,51.23) 147.49,51.53 UC1.AW39
  BOTTOM w0.168: v2(107.56,12.66) 106.9,12.01 JDIMM1.86
DDR_A_MA8: length 76
  IN4 w0.089: 144.52,42.1 144.52,42.26 145.82,43.56 145.82,44.87 147.86,46.91 147.86,49.62 v2(147.21,50.27)
  IN4 w0.145: 144.52,42.1 144.52,41.48 144.75,41.24 144.75,40.77 144.52,40.53 144.52,40.22 144.75,39.99 144.75,39.47 144.63,39.34 144.04,39.34 143.92,39.22 143.92,38.84 144.04,38.71 144.63,38.71 144.75,38.58 144.75,38.18 144.63,38.05 143.93,38.05 143.8,37.92 143.8,37.74 143.99,37.55 143.99,37.37 143.71,37.09 143.53,37.09 143.34,37.28 143.16,37.28 142.93,37.05 142.93,36.87 143.11,36.69 143.11,36.49 142.9,36.28 142.7,36.28 142.54,36.45 142.33,36.45 142.13,36.24 142.13,36.04 142.29,35.88 142.29,35.67 142.09,35.47 141.88,35.47 141.72,35.63 141.51,35.63 141.31,35.42 141.31,35.22 141.47,35.06 141.47,34.85 141.27,34.65 141.06,34.65 140.9,34.81 140.69,34.81 140.49,34.6 140.49,34.4 140.65,34.24 140.65,34.03 132.6,25.98 110.64,25.98 109.13,24.47 109.13,24.28 109.48,23.93 109.48,23.85 109.48,23.64 109.35,23.51 108.96,23.51 108.67,23.8 108.46,23.8 108.05,23.39 108.05,23.08 108.19,22.93 109.34,22.93 109.48,22.79 109.48,22.5 109.28,22.3 109.28,21.82 109.05,21.59 108.82,21.59 108.72,21.69 108.72,22.2 108.57,22.36 108.19,22.36 108.05,22.21 108.05,20.07 108.17,19.94 108.6,19.94 108.72,20.07 v2(108.72,20.3)
  BOTTOM w0.081: UC1.AY39 147.21,50.48 v2(147.21,50.27)
  BOTTOM w0.168: v2(108.72,20.3) 107.78,19.35 107.78,17.7 107.8,17.69 JDIMM1.89
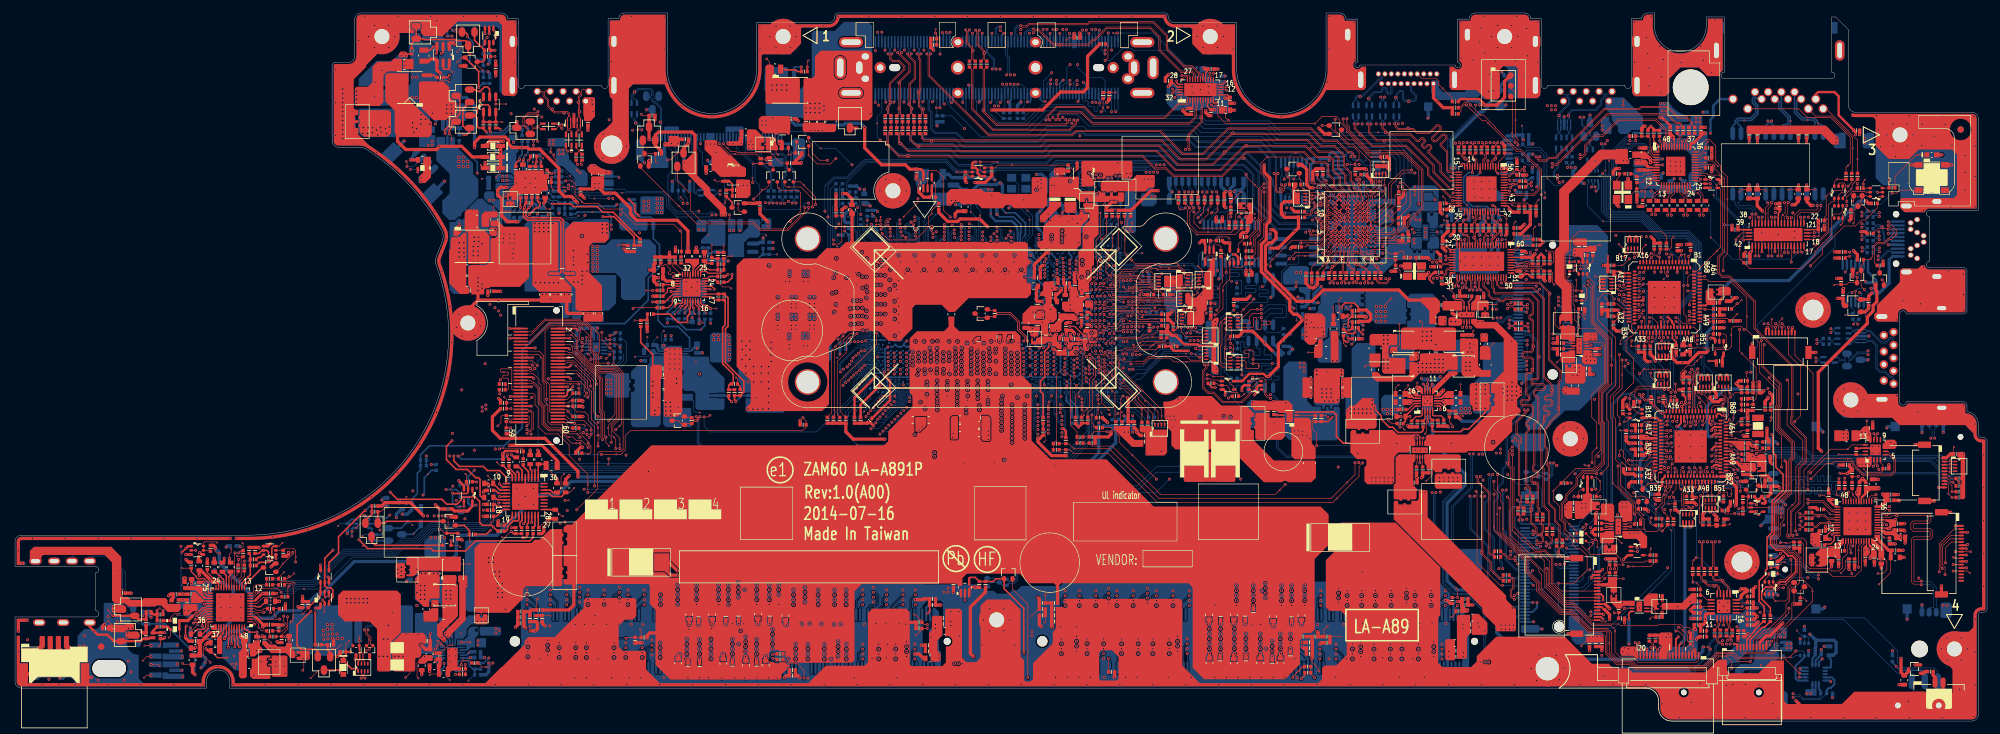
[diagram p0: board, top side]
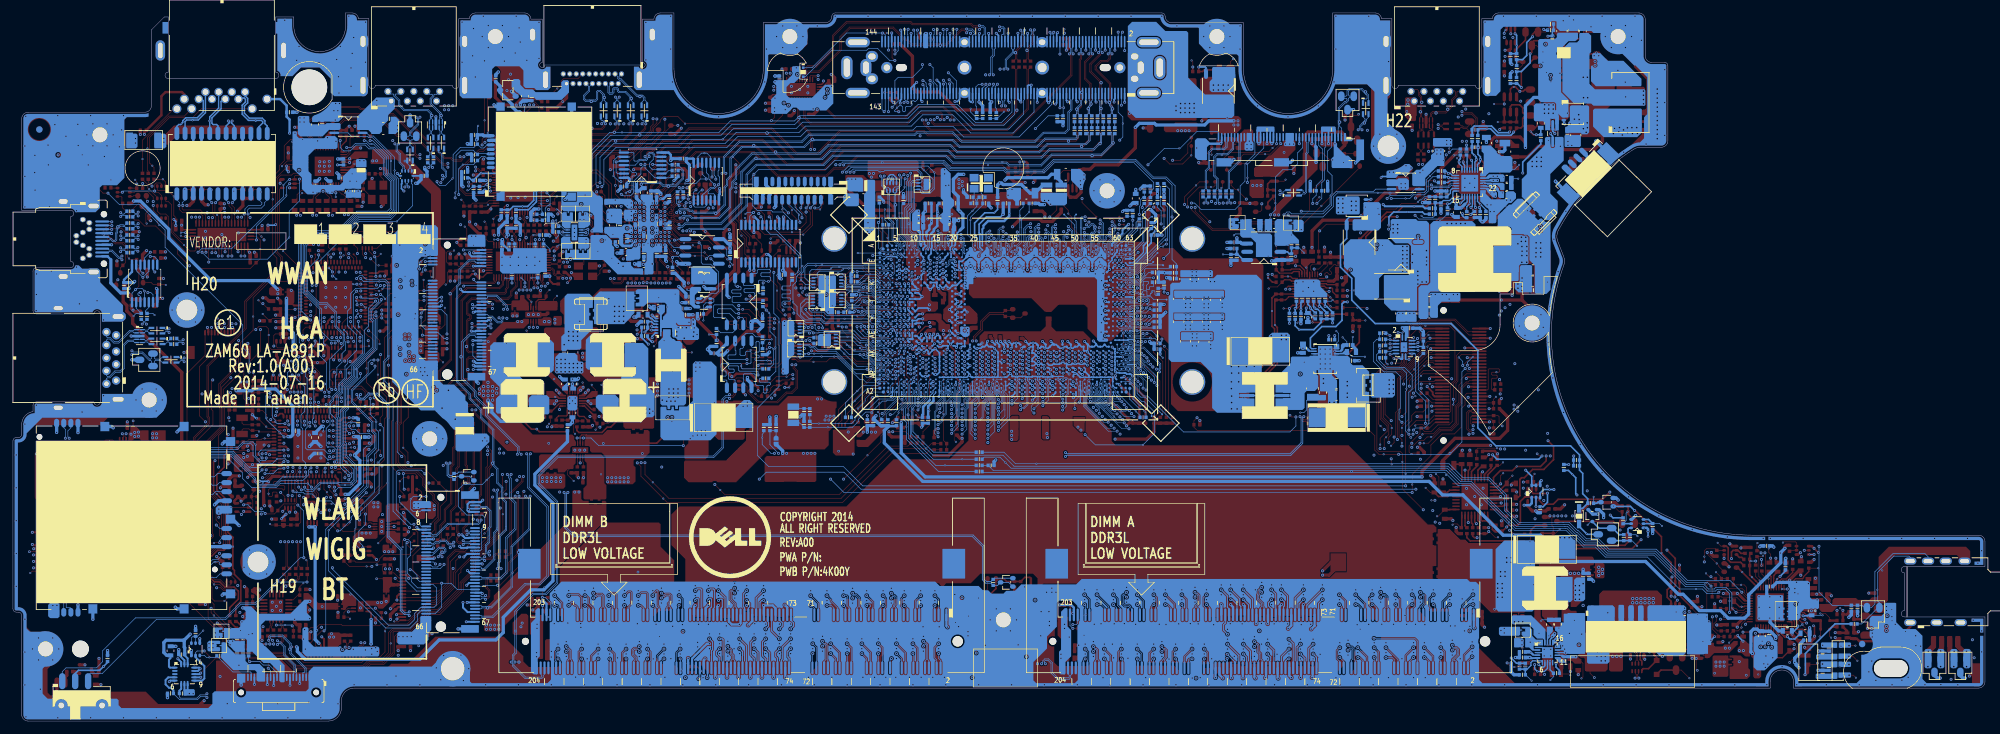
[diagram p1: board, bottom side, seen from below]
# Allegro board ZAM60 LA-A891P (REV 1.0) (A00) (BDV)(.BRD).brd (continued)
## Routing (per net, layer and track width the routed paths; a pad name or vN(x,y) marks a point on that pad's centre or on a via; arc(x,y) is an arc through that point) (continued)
DDR_A_MA9: length 76.4
  IN4 w0.089: v2(146.97,48.29) 146.52,47.84 146.52,47.54 142.53,43.54 142.53,42.1
  IN4 w0.145: 142.53,42.1 142.53,40.75 141.92,40.15 141.92,39.78 141.64,39.49 141.64,39.32 141.92,39.04 141.92,38.86 141.73,38.67 141.53,38.67 141.27,38.92 141.07,38.92 140.86,38.72 140.86,38.51 141.12,38.26 141.12,38.05 140.91,37.85 140.71,37.85 140.45,38.1 140.25,38.1 140.04,37.9 140.04,37.69 140.3,37.44 140.3,37.23 140.09,37.03 139.89,37.03 139.63,37.28 139.43,37.28 139.22,37.08 139.22,36.87 139.48,36.62 139.48,36.41 139.27,36.21 139.07,36.21 138.82,36.46 138.61,36.46 138.41,36.26 138.41,36.05 138.66,35.8 138.66,35.6 138.45,35.39 138.25,35.39 138,35.64 137.79,35.64 137.59,35.44 137.59,35.23 137.84,34.98 137.84,34.78 137.63,34.57 137.43,34.57 137.18,34.82 136.97,34.82 136.77,34.62 136.77,34.41 137.03,34.15 137.03,33.97 136.8,33.74 136.62,33.74 136.34,34.02 136.16,34.02 135.93,33.79 135.93,33.61 136.21,33.33 136.21,33.15 135.98,32.92 135.8,32.92 135.54,33.18 135.33,33.18 135.13,32.98 135.13,32.78 135.38,32.52 135.38,32.32 133.83,30.77 133.83,30.57 133.9,30.5 133.9,30.3 133.7,30.09 133.49,30.09 133.42,30.16 133.22,30.16 133.02,29.95 133.02,29.75 133.08,29.68 133.08,29.48 132.88,29.27 132.67,29.27 132.61,29.34 132.4,29.34 132.2,29.13 132.2,28.93 132.26,28.86 132.26,28.66 132.06,28.45 131.85,28.45 131.79,28.52 131.58,28.52 131.16,28.1 109.94,28.1 105.75,23.91 105.75,20.42 105.63,20.3 v2(105.33,20.3)
  BOTTOM w0.081: UC1.AU40 146.74,52.54 146.4,52.21 146.4,52.04 146.32,51.95 146.32,48.94 v2(146.97,48.29)
  BOTTOM w0.168: v2(105.33,20.3) 106.6,19.02 JDIMM1.85
DDR_A_MA10: length 76.7
  IN4 w0.089: v2(149.66,54.31) 149.29,53.94 149.29,53.51 149.47,53.33 149.47,51.05 149.97,50.55 149.97,48.84 150.07,48.74 150.07,45.82 148.46,44.21 148.46,42.1
  IN4 w0.145: 148.46,42.1 148.46,36.63 144.91,33.08 144.91,32.9 145.86,31.94 145.86,31.74 145.66,31.53 145.45,31.53 144.5,32.49 144.32,32.49 144.09,32.26 144.09,32.08 145.04,31.12 145.04,30.92 144.84,30.72 144.63,30.72 143.96,31.39 143.77,31.39 143.53,31.15 143.53,30.73 143.7,30.57 143.96,30.57 144.22,30.31 144.22,30.1 144.02,29.9 143.65,29.9 143.53,29.78 143.53,29.41 137.41,23.29 137.25,23.29 137,23.54 136.72,23.54 136.61,23.42 136.61,23.12 136.84,22.88 136.84,22.72 136.42,22.3 136.15,22.3 136.01,22.45 136.01,23.38 135.85,23.54 135.58,23.54 135.2,23.15 135.2,23.04 135.43,22.81 135.43,22.45 135.28,22.3 135.06,22.3 134.78,22.58 134.63,22.58 134.35,22.3 116.08,22.3 115.15,21.37 115.15,20.07 115.03,19.94 114.75,19.94 114.62,20.07 v2(114.62,20.3)
  BOTTOM w0.081: v2(149.66,54.31) 149.99,54.64 UC1.AP35
  BOTTOM w0.168: JDIMM1.107 113.2,18.88 v2(114.62,20.3)
DDR_A_MA11: length 75.5
  IN4 w0.089: 141.13,42.1 141.13,42.96 146.14,47.97 146.14,50.72 v2(145.63,51.22)
  IN4 w0.145: v2(105.78,11.9) 105.23,12.45 105.23,16.71 105.36,16.84 105.68,16.84 105.81,16.97 105.81,17.45 105.68,17.58 104.22,17.58 104.09,17.71 104.09,23.38 109.64,28.93 129.95,28.93 141.13,40.11 141.13,42.1
  BOTTOM w0.081: UC1.AW41 145.94,51.53 v2(145.63,51.22)
  BOTTOM w0.168: JDIMM1.84 106.3,11.38 v2(105.78,11.9)
DDR_A_MA12: length 76.1
  IN4 w0.089: v2(145.62,52.52) 146.31,51.82 146.31,47.74 141.52,42.95 141.52,42.1
  IN4 w0.145: 141.52,42.1 141.52,39.94 134.46,32.88 134.46,32.67 134.73,32.41 134.73,32.23 134.5,32 134.32,32 134.05,32.26 133.85,32.26 133.64,32.06 133.64,31.85 133.91,31.59 133.91,31.41 133.68,31.18 133.5,31.18 133.23,31.44 133.03,31.44 132.82,31.24 132.82,31.03 133.09,30.77 133.09,30.59 132.86,30.36 132.68,30.36 132.41,30.62 132.21,30.62 132,30.42 132,30.21 132.27,29.95 132.27,29.77 132.04,29.54 131.86,29.54 131.59,29.8 131.39,29.8 131.18,29.6 131.18,29.39 131.45,29.13 131.45,28.95 131.22,28.72 131.04,28.72 130.77,28.98 130.57,28.98 130.08,28.49 109.77,28.49 105.36,24.08 105.36,23.47 105.25,23.36 104.64,23.36 104.49,23.21 104.49,22.94 104.63,22.8 105.21,22.8 105.36,22.65 105.36,22.36 105.21,22.22 104.63,22.22 104.49,22.07 104.49,21.77 104.63,21.63 104.79,21.63 104.91,21.5 104.91,21.18 104.79,21.05 104.63,21.05 104.49,20.9 104.49,20.61 104.63,20.47 104.77,20.47 104.9,20.34 104.9,20.02 104.77,19.89 104.63,19.89 104.49,19.75 104.49,19.52 104.73,19.28 104.73,19.04 104.49,18.8 104.49,18.28 104.63,18.14 104.85,18.14 105.33,18.62 v2(105.33,18.77)
  BOTTOM w0.081: UC1.AU41 145.93,52.83 v2(145.62,52.52)
  BOTTOM w0.168: v2(105.33,18.77) 106,18.1 JDIMM1.83
DDR_A_MA13: length 77.6
  IN4 w0.089: v2(149.66,53.66) 149.74,53.58 149.74,51.28 150.4,50.62 150.51,50.62 150.94,50.19 150.94,43.55 149.66,42.27 149.66,42.1
  IN4 w0.145: v2(118.02,20.3) 118.83,21.1 136.92,21.1 137.5,21.68 137.7,21.68 138.14,21.24 138.35,21.24 138.55,21.45 138.55,21.65 138.11,22.09 138.11,22.3 138.32,22.5 138.52,22.5 138.96,22.06 139.17,22.06 139.37,22.27 139.37,22.47 138.93,22.91 138.93,23.12 139.14,23.32 139.34,23.32 139.78,22.88 139.99,22.88 140.19,23.08 140.19,23.29 139.75,23.73 139.75,23.94 139.96,24.14 140.16,24.14 140.6,23.7 140.81,23.7 141.01,23.9 141.01,24.11 140.57,24.55 140.57,24.75 140.78,24.96 140.98,24.96 141.42,24.52 141.63,24.52 141.83,24.72 141.83,24.93 141.39,25.37 141.39,25.57 141.63,25.81 141.84,25.81 142.28,25.37 142.48,25.37 142.69,25.58 142.69,25.78 142.24,26.22 142.24,26.43 148.4,32.58 148.4,32.81 147.45,33.76 147.45,33.93 147.79,34.27 147.97,34.27 148.92,33.31 149.13,33.31 149.66,33.84 149.66,34.22 149.57,34.31 148.83,34.31 148.42,34.72 148.42,34.9 148.7,35.18 148.88,35.18 149.18,34.87 149.54,34.87 149.66,34.99 149.66,35.25 149.29,35.63 149.29,35.77 149.66,36.14 149.66,42.1
  BOTTOM w0.081: UC1.AR35 149.99,53.99 v2(149.66,53.66)
  BOTTOM w0.168: JDIMM1.119 116.8,17.33 117.08,17.61 117.08,19.35 v2(118.02,20.3)
DDR_A_MA14: length 76.9
  IN4 w0.089: 140.73,42.1 140.73,42.96 145.96,48.2 145.96,49.06 v2(145.59,49.42)
  IN4 w0.145: 140.73,42.1 140.73,40.27 129.81,29.36 109.51,29.36 103.69,23.55 103.69,17.33 103.84,17.18 104.69,17.18 104.83,17.04 104.83,16.69 104.71,16.56 104.12,16.56 104,16.43 104,16.08 104.12,15.95 104.71,15.95 104.83,15.82 104.83,11.32 v2(105.78,10.38)
  BOTTOM w0.081: UC1.AV42 144.92,51.88 144.92,50.1 v2(145.59,49.42)
  BOTTOM w0.168: JDIMM1.80 105.1,9.7 v2(105.78,10.38)
DDR_A_MA15: length 77.2
  IN4 w0.089: v2(145.59,48.77) 145.59,48.24 140.33,42.97 140.33,42.1
  IN4 w0.145: 140.33,42.1 140.33,40.44 129.66,29.76 109.35,29.76 103.29,23.71 103.29,13.94 103.44,13.79 104.31,13.79 104.43,13.66 104.43,13.34 104.31,13.21 103.44,13.21 103.31,13.08 103.31,12.03 103.44,11.9 v2(103.83,11.9)
  BOTTOM w0.081: v2(145.59,48.77) 145.59,48.76 144.75,49.61 144.75,52.05 144.84,52.14 144.84,52.32 145.16,52.64 UC1.AU42
  BOTTOM w0.168: JDIMM1.78 104.5,11.22 v2(103.83,11.9)
DDR_A_RAS#: length 75.6
  IN4 w0.076: v2(152.46,44.95) 152.46,43.79 150.87,42.19 150.87,42.1
  IN4 w0.145: 150.87,42.1 150.87,32.07 143,24.19 143,24.02 143.85,23.16 143.85,22.96 143.64,22.75 143.44,22.75 142.59,23.61 142.41,23.61 142.18,23.38 142.18,23.2 143.03,22.34 143.03,22.14 142.82,21.93 142.62,21.93 142.37,22.18 142.16,22.18 141.96,21.98 141.96,21.77 142.21,21.52 142.21,21.32 139.94,19.05 139.94,18.21 138.52,16.78 118.98,16.78 116.41,14.21 116.41,11.19 115.59,10.38 v2(114.6,10.38)
  BOTTOM w0.081: v2(152.46,44.95) 150.76,46.65 UC1.AY34
  BOTTOM w0.168: v2(114.6,10.38) 114.1,9.88 JDIMM1.110
DDR_A_WE#: length 77.5
  IN4 w0.089: 150.06,42.1 150.06,42.24 151.37,43.55 151.37,50.55 150.69,51.22 v2(150.35,51.22)
  IN4 w0.145: 150.06,42.1 150.06,33.68 147.83,31.45 147.83,31.24 148.27,30.8 148.27,30.6 148.06,30.39 147.86,30.39 147.42,30.83 147.21,30.83 147.01,30.63 147.01,30.42 147.45,29.98 147.45,29.78 147.25,29.57 147.04,29.57 146.6,30.01 146.39,30.01 146.19,29.81 146.19,29.61 146.63,29.16 146.63,28.96 146.43,28.75 146.22,28.75 145.78,29.2 145.58,29.2 145.37,28.99 145.37,28.79 145.81,28.34 145.81,28.14 145.61,27.93 145.4,27.93 144.96,28.38 144.76,28.38 144.55,28.17 144.55,27.97 144.99,27.52 144.99,27.32 144.79,27.12 144.58,27.12 144.14,27.56 143.94,27.56 143.73,27.35 143.73,27.15 144.17,26.71 144.17,26.5 143.97,26.3 143.76,26.3 143.32,26.74 143.12,26.74 142.91,26.53 142.91,26.33 143.35,25.89 143.35,25.68 138.18,20.51 138.18,17.79 137.97,17.58 117.84,17.58 117.52,17.9 117.52,19.35 v2(116.57,20.3)
  BOTTOM w0.081: UC1.AW34 150.66,51.53 v2(150.35,51.22)
  BOTTOM w0.168: v2(116.57,20.3) 115.17,18.9 115.17,17.9 115,17.73 JDIMM1.113
DDR_B_BS0: length 100.8
  IN1 w0.076: v2(149.66,56.27) 149.27,56.66 149.27,57.86 149.06,58.06 148.5,58.06 148.13,57.7 148.13,53.43 147.89,53.19 147.89,43.27 147.42,42.8 147.42,42.1
  IN1 w0.145: 147.42,42.1 147.42,37.14 148.07,36.49 148.2,36.49 148.41,36.28 148.41,36.15 158.43,26.14 183.1,26.14 184.18,25.05 184.39,25.05 184.64,25.31 190.52,25.31 190.87,24.95 191.08,24.95 191.43,25.31 191.6,25.31 194.57,22.34 194.57,20.26 193.68,19.37 193.68,14.86 194.28,14.26 194.82,14.26 194.92,14.36 195.15,14.36 195.22,14.29 195.22,14 195.32,13.91 195.8,13.91 195.96,14.06 195.96,14.86 195.89,14.93 195.21,14.93 195.12,15.03 195.12,15.42 195.21,15.51 195.85,15.51 195.96,15.62 195.96,15.98 195.85,16.09 195.23,16.09 195.12,16.21 195.12,16.55 195.24,16.67 195.86,16.67 195.96,16.77 195.96,17.16 195.87,17.25 195.23,17.25 195.12,17.36 195.12,17.97 195.25,18.1 195.34,18.1 195.72,18.49 v2(195.72,18.64)
  BOTTOM w0.081: UC1.AL35 149.99,56.59 v2(149.66,56.27)
  BOTTOM w0.168: JDIMM2.109 195.3,17.47 195.12,17.65 195.12,18.71 195.26,18.85 195.52,18.85 v2(195.72,18.64)
DDR_B_BS1: length 100.9
  IN1 w0.076: v2(148.71,55.77) 149.18,55.77 149.29,55.66 149.29,55.48 149.1,55.29 149.1,52.91 149.4,52.61 149.4,49.43 149.27,49.3 148.77,49.3 148.66,49.2 148.66,43.07 148.23,42.64 148.23,42.1
  IN1 w0.145: 148.23,42.1 148.23,38.06 159.36,26.93 183.43,26.93 184.26,26.1 191.93,26.1 196.15,21.88 196.15,21.04 196.23,20.96 196.36,20.96 196.46,20.86 196.46,20.48 196.38,20.4 196.24,20.4 196.15,20.31 196.15,19.21 196.23,19.14 196.37,19.14 196.46,19.05 196.46,18.57 196.38,18.49 196.24,18.49 196.15,18.4 196.15,17.53 196.36,17.32 196.36,17.24 196.54,17.06 197.6,17.06 197.86,16.79 197.86,16.59 197.74,16.48 196.4,16.48 196.28,16.36 196.28,16.22 196.37,16.13 196.37,15.21 196.47,15.12 196.82,15.12 197,15.3 197,15.8 197.1,15.9 197.55,15.9 197.65,15.8 197.65,15.33 197.81,15.16 198.27,15.16 198.37,15.06 198.37,14.51 198.46,14.41 198.93,14.41 199.06,14.28 199.06,13.87 198.95,13.77 197.99,13.77 197.74,14.01 197.74,14.43 197.64,14.54 196.47,14.54 196.36,14.42 196.36,13.9 196.06,13.6 196.06,12.52 195.91,12.37 195.63,12.37 195.55,12.46 v2(195.55,12.72)
  BOTTOM w0.081: v2(148.71,55.77) 148.88,55.94 UC1.AM36
  BOTTOM w0.168: v2(195.55,12.72) 195.15,12.72 195,12.57 JDIMM2.108
DDR_B_BS2: length 97.6
  IN1 w0.076: 140.07,42.1 140.07,42.82 141.71,44.46 141.71,51.65 v2(140.91,52.45)
  IN1 w0.145: v2(186.3,14.24) 186.79,14.73 186.79,15.26 185.82,16.23 182.7,16.23 181.85,15.38 165.05,15.38 164.6,15.83 158.48,15.83 153.53,20.78 153.32,20.78 152.92,20.38 152.05,20.38 146.78,25.64 146.78,25.88 147.52,26.62 147.52,26.79 147.28,27.03 147.11,27.03 145.58,25.5 145.36,25.5 145.16,25.71 145.16,25.9 146.7,27.43 146.7,27.61 146.47,27.84 146.28,27.84 144.76,26.31 144.55,26.31 144.32,26.54 144.32,26.7 145.88,28.26 145.88,28.42 145.64,28.66 145.47,28.66 143.92,27.12 143.75,27.12 143.49,27.37 143.49,27.51 145.07,29.09 145.07,29.24 144.82,29.49 144.65,29.49 143.66,28.5 143.51,28.5 143.39,28.62 143.39,29.05 144.24,29.91 144.24,30.06 140.07,34.23 140.07,42.1
  BOTTOM w0.081: v2(140.91,52.45) 140.91,52.52 141.22,52.83 UC1.AU49
  BOTTOM w0.168: JDIMM2.79 186.3,15.65 185.86,15.21 185.86,14.68 v2(186.3,14.24)
DDR_B_CAS#: length 100.9
  IN1 w0.076: 149.44,42.1 149.44,42.96 149.49,43.01 149.49,45.74 149.59,45.84 150.24,45.84 150.35,45.96 150.35,46.13 150.28,46.2 149.59,46.2 149.49,46.3 149.49,46.45 149.59,46.56 150.26,46.56 150.35,46.65 150.35,46.79 150.24,46.91 149.59,46.91 149.49,47.01 149.49,47.21 149.57,47.28 149.88,47.28 149.97,47.37 149.97,53.2 150.23,53.46 150.23,55.25 150.62,55.64 v2(150.62,55.68)
  IN1 w0.145: v2(197.29,18.64) 197.29,18.43 197.44,18.28 197.61,18.28 197.71,18.38 197.71,19.77 198.48,20.53 198.48,21.55 192.73,27.3 190.44,27.3 190.16,27.58 189.59,27.58 189.49,27.67 189.49,28 189.37,28.13 169.85,28.13 169.36,28.62 164.8,28.62 164.71,28.71 163.97,28.71 163.9,28.78 163.9,29.3 163.78,29.43 163.61,29.43 163.42,29.24 163.17,29.24 163.09,29.32 163.09,30.18 162.78,30.49 162.65,30.49 162.51,30.36 162.51,29.33 162.42,29.24 162.02,29.24 161.93,29.33 161.93,30.77 161.81,30.89 161.46,30.89 161.35,30.79 161.35,29.31 161.28,29.24 160.88,29.24 160.77,29.34 160.77,30.77 160.65,30.89 160.29,30.89 160.2,30.8 160.2,28.24 160.08,28.13 159.86,28.13 159.36,28.63 159.36,28.79 159.62,29.05 159.62,30.76 159.48,30.89 159.16,30.89 159.04,30.77 159.04,29.32 158.95,29.23 158.75,29.23 158.19,29.8 158.19,29.95 158.46,30.22 158.46,30.76 158.33,30.89 158.01,30.89 157.88,30.77 157.88,30.47 157.78,30.37 157.62,30.37 149.44,38.54 149.44,42.1
  BOTTOM w0.081: UC1.AM33 150.88,55.94 v2(150.62,55.68)
  BOTTOM w0.168: v2(197.29,18.64) 197.29,18.85 197.15,18.99 196.95,18.99 196.82,18.86 196.82,17.63 197.1,17.35 JDIMM2.115
DDR_B_D0: length 84.1
  IN1 w0.076: 152.15,42.1 152.15,43.36 153.01,44.22 153.01,46.81 v2(152.46,47.35)
  IN1 w0.089: 152.15,42.1 152.15,39.67 158.22,33.6 163.65,33.6 165.92,31.33 170.48,31.33 170.97,30.84 190.73,30.84 191.56,30.01 193.85,30.01 202.52,21.34 202.52,18.41 202.64,18.29 202.64,12.13 v2(201.64,11.14)
  BOTTOM w0.081: UC1.AY31 152.01,50.75 151.62,50.36 151.62,48.19 v2(152.46,47.35)
  BOTTOM w0.102: JDIMM2.132 202.2,10.58 v2(201.64,11.14)
DDR_B_D1: length 84.9
  IN1 w0.076: 151.83,42.1 151.83,43.29 152.84,44.29 152.84,46.08 152.75,46.16 v2(152.46,46.16)
  IN1 w0.089: v2(201.8,17.88) 201.8,17.31 201.72,17.23 201.52,17.23 201.42,17.13 201.42,16.84 201.52,16.74 201.74,16.74 201.8,16.67 201.8,16.29 201.75,16.24 201.51,16.24 201.42,16.15 201.42,15.82 201.5,15.75 201.71,15.75 201.8,15.65 201.8,14.42 201.9,14.33 202.23,14.33 202.32,14.41 202.32,18.16 202.2,18.27 202.2,21.21 193.72,29.69 191.43,29.69 190.6,30.52 170.84,30.52 170.35,31.01 165.79,31.01 163.52,33.29 158.08,33.29 151.83,39.54 151.83,42.1
  BOTTOM w0.076: UC1.AW31 152.01,51.33 151.81,51.13 151.81,51.11 151.8,51.09 151.8,51.09 151.73,50.95 151.73,50.84 151.72,50.82 151.72,50.73 151.45,50.46 151.45,48.12 151.45,48.12 151.45,47.17 v2(152.46,46.16)
  BOTTOM w0.102: JDIMM2.131 201.9,17.79 v2(201.8,17.88)
DDR_B_D2: length 84
  IN1 w0.076: v2(154.09,45.02) 154.46,44.65 154.46,42.91 154.32,42.77
  IN1 w0.089: v2(204.14,9.61) 204.29,9.61 204.54,9.87 204.54,17.25 205.36,18.07 205.36,20.12 205.27,20.2 205.27,20.83 204.54,21.57 204.54,21.92 194.61,31.85 192.32,31.85 191.49,32.67 171.73,32.67 171.24,33.17 166.68,33.17 164.41,35.44 158.98,35.44 154.32,40.1 154.32,42.77
  BOTTOM w0.076: v2(154.09,45.02) 153.24,45.87 153.24,49.75 153.36,49.87 UC1.AY29
  BOTTOM w0.102: JDIMM2.140 204.6,9.15 v2(204.14,9.61)
DDR_B_D3: length 84.8
  IN1 w0.076: 154.63,42.1 154.63,42.72 154.68,42.77 154.68,45.93 154.53,46.09 154.4,46.09 154.09,45.77 v2(154.09,45.67)
  IN1 w0.089: v2(205.87,19.41) 205.87,19.21 206.34,18.74 206.44,18.74 206.49,18.79 206.49,19.43 206.22,19.7 206.22,19.89 206.49,20.15 206.49,20.42 206.15,20.75 206.01,20.75 205.91,20.65 205.81,20.65 205.58,20.88 205.58,21.02 205.67,21.11 205.67,21.23 205.38,21.53 205.28,21.53 205.2,21.44 205.11,21.44 204.85,21.7 204.85,21.81 204.93,21.89 204.93,21.97 194.74,32.16 192.45,32.16 191.62,32.99 171.86,32.99 171.37,33.48 170.69,33.48 170.6,33.58 170.6,33.87 170.51,33.96 170.19,33.96 170.1,33.87 170.1,33.55 170.03,33.48 169.7,33.48 169.61,33.58 169.61,33.88 169.53,33.96 169.21,33.96 169.11,33.86 169.11,33.57 169.03,33.48 168.7,33.48 168.62,33.57 168.62,33.88 168.54,33.96 168.2,33.96 168.12,33.88 168.12,33.55 168.05,33.48 167.71,33.48 167.63,33.57 167.63,33.9 167.56,33.96 167.21,33.96 167.13,33.88 167.13,33.58 167.03,33.48 166.81,33.48 166.63,33.66 166.63,33.9 166.57,33.96 166.33,33.96 164.54,35.76 159.11,35.76 154.63,40.23 154.63,42.1
  BOTTOM w0.076: v2(154.09,45.67) 153.41,46.35 153.41,49.66 153.52,49.78 153.52,50.63 153.65,50.76 153.65,51 153.36,51.29 UC1.AW29
  BOTTOM w0.102: JDIMM2.141 204.9,17.66 205.08,17.84 205.08,20.08 205.18,20.18 205.28,20.18 205.87,19.59 v2(205.87,19.41)
DDR_B_D4: length 85.1
  IN1 w0.076: v2(152.46,45.51) 152.26,45.51 152.09,45.68 152.09,47.34 152.01,47.43 151.75,47.43 151.61,47.29 151.61,45.11 151.21,44.71 151.21,44.57 151.3,44.48 152.24,44.48 152.33,44.39 152.33,44.15 152.22,44.03 151.28,44.03 151.18,43.93 151.18,43.62 151.28,43.52 151.43,43.52
  IN1 w0.089: v2(201.8,19.41) 201.8,19.17 201.65,19.01 201.48,19.01 201.4,19.09 201.4,20.5 201.48,20.57 201.82,20.57 201.89,20.63 201.89,20.85 201.82,20.92 201.46,20.92 201.4,20.98 201.4,21.56 193.59,29.38 191.3,29.38 190.47,30.2 170.71,30.2 170.22,30.7 165.66,30.7 163.38,32.97 157.95,32.97 151.52,39.41 151.52,43.43 151.43,43.52
  BOTTOM w0.076: UC1.AV31 151.63,51.8 151.63,51.13 151.57,51.03 151.57,51.03 151.55,50.99 151.48,50.85 151.01,50.37 151.01,46.97 v2(152.46,45.51)
  BOTTOM w0.102: JDIMM2.129 201.3,18.9 v2(201.8,19.41)
DDR_B_D5: length 86.8
  IN1 w0.076: 152.47,42.1 152.47,43.43 153.24,44.21 153.24,47.1 v2(152.42,47.92)
  IN1 w0.089: 152.47,42.1 152.47,39.8 158.35,33.92 163.78,33.92 166.05,31.65 170.61,31.65 171.1,31.16 190.86,31.16 191.69,30.33 193.98,30.33 202.84,21.47 202.84,18.54 203.03,18.35 203.03,10.98 201.67,9.61 v2(201.64,9.61)
  BOTTOM w0.076: v2(152.42,47.92) 152.42,47.92 152.84,48.33 152.84,49.92 152.98,50.06 152.98,50.46 152.9,50.54 152.9,50.98 152.93,51.03 152.93,51.03 152.93,51.03 152.98,51.14 152.98,51.27 152.97,51.28 152.97,51.28 152.92,51.38 152.9,51.43 152.9,51.63 152.93,51.68 152.93,51.68 152.97,51.77 152.98,51.79 152.98,51.98 152.96,51.99 152.96,52.37 152.98,52.38 152.98,52.63 152.77,52.83 UC1.AU31
  BOTTOM w0.102: JDIMM2.130 201.6,9.58 v2(201.64,9.61)
DDR_B_D6: length 85.9
  IN1 w0.089: v2(154.09,43.72) 153.72,43.35 153.72,42.85 154,42.57 154,39.97 158.84,35.12 164.28,35.12 166.55,32.85 171.11,32.85 171.6,32.36 191.36,32.36 192.19,31.53 194.48,31.53 204.22,21.79 204.22,21.43 204.95,20.7 204.95,20.07 205.04,19.98 205.04,18.2 203.74,16.9 203.74,11.54 v2(204.14,11.14)
  BOTTOM w0.076: UC1.AV29 153.25,51.84 153.12,51.7 153.07,51.59 153.07,51.46 153.08,51.44 153.08,51.44 153.12,51.36 153.12,51.36 153.14,51.31 153.14,51.1 153.07,50.94 153.07,50.61 153.17,50.51 153.17,49.92 153.07,49.82 153.07,44.74 v2(154.09,43.72)
  BOTTOM w0.102: JDIMM2.142 205.2,10.08 v2(204.14,11.14)
DDR_B_D7: length 86.6
  IN1 w0.076: 154.97,42.3 154.97,46.11 154.76,46.32 v2(154.09,46.32)
  IN1 w0.089: 154.97,42.3 154.97,40.34 159.24,36.07 164.67,36.07 166.47,34.28 171.03,34.28 172,33.31 191.75,33.31 192.58,32.48 194.87,32.48 206.8,20.55 206.8,16.67 206.63,16.5 205.62,16.5 205.47,16.35 205.47,16.15 205.62,16 206.06,16 206.22,15.84 206.22,15.53 206.06,15.37 205.04,15.37 204.86,15.54 204.86,17.12 205.62,17.88 v2(205.87,17.88)
  BOTTOM w0.076: v2(154.09,46.32) 153.58,46.83 153.58,49.58 153.69,49.69 153.69,50.56 153.82,50.69 153.82,51.07 153.65,51.23 153.65,51.65 153.55,51.76 153.55,52.33 153.25,52.62 UC1.AU29
  BOTTOM w0.102: v2(205.87,17.88) 205.5,17.52 JDIMM2.143
DDR_B_D8: length 50.7
  IN4 w0.089: v2(154.09,47.62) 154.51,47.2 154.51,42.86 154.05,42.41 154.05,28.85 159.43,23.47 159.43,22.5 159.58,22.36 160.45,22.36 160.61,22.2 160.61,22 160.48,21.86 159.58,21.86 159.43,21.72 159.43,21.51 159.58,21.37 161.41,21.37 161.55,21.22 161.55,21.02 161.41,20.87 159.58,20.87 159.43,20.73 159.43,20.52 159.58,20.38 161.59,20.38 161.72,20.25 161.72,20.01 161.59,19.88 159.58,19.88 159.43,19.74 159.43,19.54 159.59,19.39 v2(162.28,19.39)
  BOTTOM w0.076: v2(154.09,47.62) 154.65,48.18 154.65,49.19 154.2,49.64 154.2,50.37 154.31,50.48 154.31,50.75 UC1.AY27
  BOTTOM w0.102: JDIMM2.5 161.7,18.82 v2(162.28,19.39)
DDR_B_D9: length 51.3
  IN4 w0.089: v2(154.09,48.27) 153.71,47.89 153.71,42.56 153.66,42.52 153.66,28.62 159.12,23.17 159.12,17.37 159.26,17.22 160.58,17.22 160.72,17.08 160.72,16.87 160.58,16.73 159.26,16.73 159.12,16.58 159.12,16.38 159.26,16.23 160.58,16.23 160.72,16.09 160.72,12.93 v2(161.7,11.96)
  BOTTOM w0.076: v2(154.09,48.27) 154.48,48.66 154.48,49.1 154.03,49.55 154.03,50.44 154.15,50.55 154.15,51 154.44,51.29 UC1.AW27
  BOTTOM w0.102: JDIMM2.6 162,9.48 162.29,9.77 162.29,11.36 v2(161.7,11.96)
DDR_B_D10: length 50.4
  IN4 w0.084: v2(156.05,45.02) 155.35,44.32 155.35,42.81 155.57,42.58
  IN4 w0.089: v2(164.47,17.86) 164.04,18.29 164.04,21.01 155.57,29.47 155.57,31.22 155.72,31.37 156.3,31.37 156.45,31.51 156.45,31.72 156.3,31.86 155.72,31.86 155.57,32.01 155.57,32.21 155.72,32.36 156.3,32.36 156.45,32.5 156.45,32.71 156.3,32.85 155.72,32.85 155.57,33 155.57,33.2 155.72,33.35 156.3,33.35 156.45,33.49 156.45,33.7 156.3,33.84 155.72,33.84 155.57,33.99 155.57,34.19 155.72,34.34 156.3,34.34 156.45,34.48 156.45,34.69 156.3,34.83 155.72,34.83 155.57,34.98 155.57,35.19 155.72,35.33 156.3,35.33 156.45,35.48 156.45,35.68 156.3,35.83 155.72,35.83 155.57,35.97 155.57,36.18 155.72,36.32 156.3,36.32 156.45,36.47 156.45,36.67 156.3,36.82 155.72,36.82 155.57,36.96 155.57,37.17 155.72,37.31 156.3,37.31 156.45,37.46 156.45,37.66 156.3,37.81 155.72,37.81 155.57,37.95 155.57,38.16 155.72,38.3 156.3,38.3 156.45,38.45 156.45,38.65 156.3,38.8 155.72,38.8 155.57,38.94 155.57,42.58
  BOTTOM w0.076: v2(156.05,45.02) 156.44,45.41 156.44,49.08 155.98,49.55 155.96,49.55 155.69,49.82 155.69,49.98 155.69,50.78 UC1.AY25
  BOTTOM w0.102: v2(164.47,17.86) 164.7,17.63 JDIMM2.15
DDR_B_D11: length 51.2
  IN4 w0.089: v2(156.05,44.37) 155.66,43.98 155.66,42.93 155.89,42.69 155.89,39.68 156.78,38.79 156.78,31.69 156.92,31.55 157.86,31.55 158.01,31.4 158.01,31.2 157.86,31.05 155.98,31.05 155.89,30.96 155.89,30.67 156.01,30.55 157.86,30.55 158.01,30.41 158.01,30.2 157.86,30.06 155.99,30.06 155.89,29.96 155.89,29.71 156.04,29.56 157.91,29.56 158.01,29.46 158.01,29.18 157.9,29.07 156.71,29.07 156.63,28.99 156.63,28.87 156.92,28.57 157.91,28.57 158.01,28.47 158.01,27.49 164.87,20.62 164.87,19.79 v2(164.47,19.39)
  BOTTOM w0.076: v2(156.05,44.37) 156.66,44.98 156.66,49.22 155.86,50.02 155.86,50.53 156.08,50.76 156.08,50.94 156.01,51.1 156.01,51.31 UC1.AW25
  BOTTOM w0.102: JDIMM2.17 165.3,18.56 v2(164.47,19.39)
DDR_B_D12: length 51.6
  IN4 w0.089: v2(154.09,48.92) 153.45,48.28 153.45,42.81 153.3,42.66 153.3,28.54 158.8,23.04 158.8,16.03 158.94,15.88 160.26,15.88 160.4,15.74 160.4,15.53 160.26,15.39 158.94,15.39 158.8,15.24 158.8,15.04 158.94,14.89 159.71,14.89 159.89,14.71 159.89,12.24 v2(161.7,10.43)
  BOTTOM w0.076: UC1.AV27 154.55,52.05 154.15,51.65 154.15,51.24 153.98,51.08 153.98,50.62 153.85,50.49 153.85,49.15 v2(154.09,48.92)
  BOTTOM w0.102: JDIMM2.4 161.4,9.39 161.7,9.69 v2(161.7,10.43)
DDR_B_D13: length 52.3
  IN4 w0.089: v2(165.68,11.96) 166.08,12.36 166.08,12.89 165.63,13.33 165.63,20.76 158.64,27.75 158.64,33.11 158.5,33.25 157.56,33.25 157.41,33.4 157.41,33.6 157.56,33.75 158.17,33.75 158.33,33.9 158.33,34.11 158.2,34.24 157.56,34.24 157.41,34.39 157.41,39.05 156.53,39.94 156.53,47.79 v2(156.05,48.27)
  BOTTOM w0.076: UC1.AU27 155.2,52.83 155.41,52.63 155.41,51.79 155.36,51.68 155.33,51.63 155.33,51.43 155.36,51.38 155.4,51.28 155.4,51.28 155.41,51.27 155.41,51.14 155.33,50.98 155.33,48.98 v2(156.05,48.27)
  BOTTOM w0.102: v2(165.68,11.96) 165,11.29 JDIMM2.16
DDR_B_D14: length 51.9
  IN4 w0.089: v2(162.28,17.86) 161.87,18.26 161.87,18.67 161.47,19.07 159.54,19.07 159.43,18.96 159.43,18.72 159.58,18.58 160.86,18.58 160.97,18.47 160.97,18.19 160.86,18.08 159.58,18.08 159.43,17.93 159.43,17.67 159.56,17.54 160.88,17.54 161.2,17.23 162.45,17.23 162.72,17.5 162.72,20.63 154.37,28.98 154.37,42.41 154.68,42.72 154.68,47.56 v2(156.05,48.92)
  BOTTOM w0.076: v2(156.05,48.92) 155.5,49.47 155.5,50.94 155.55,51.05 155.57,51.1 155.57,51.31 155.55,51.36 155.51,51.44 155.51,51.45 155.5,51.46 155.5,51.59 155.55,51.7 155.79,51.94 UC1.AV25
  BOTTOM w0.102: v2(162.28,17.86) 162.3,17.84 JDIMM2.7
DDR_B_D15: length 52.2
  IN4 w0.089: v2(165.68,10.43) 165.26,10.85 165.26,20.68 158.33,27.62 158.33,31.8 158.18,31.94 157.24,31.94 157.1,32.09 157.1,32.29 157.24,32.44 158.18,32.44 158.33,32.58 158.33,32.79 158.18,32.93 157.24,32.93 157.1,33.08 157.1,38.92 156.21,39.81 156.21,42.82 156.05,42.99 v2(156.05,43.72)
  BOTTOM w0.076: v2(156.05,43.72) 156.85,44.52 156.85,49.26 156.02,50.09 156.02,50.46 156.25,50.69 156.25,50.98 156.22,51.03 156.22,51.03 156.17,51.14 156.17,51.7 156.08,51.79 156.08,52.54 UC1.AU25
  BOTTOM w0.102: v2(165.68,10.43) 165.6,10.36 JDIMM2.18
DDR_B_D16: length 92.7
  IN1 w0.076: 155.88,42.1 155.88,42.59 155.33,43.14 155.33,46.24 154.69,46.88 154.69,49.1 152.48,51.31 152.48,55.06 v2(153.03,55.62)
  IN1 w0.089: v2(206.68,11.14) 207.19,11.65 207.19,12.56 207.34,12.71 207.79,12.71 207.92,12.84 207.92,13.05 207.76,13.2 207.34,13.2 207.19,13.35 207.19,13.55 207.34,13.7 207.79,13.7 207.92,13.83 207.92,14.04 207.76,14.2 207.34,14.2 207.19,14.34 207.19,15.21 207.72,15.73 207.72,20.93 195.25,33.39 192.96,33.39 192.13,34.22 172.37,34.22 171.41,35.19 166.85,35.19 165.05,36.99 159.62,36.99 155.88,40.72 155.88,42.1
  BOTTOM w0.081: UC1.AM29 153.36,55.94 v2(153.03,55.62)
  BOTTOM w0.102: v2(206.68,11.14) 206.25,10.71 206.25,9.34 206.4,9.19 JDIMM2.146
DDR_B_D17: length 94.8
  IN1 w0.076: 155.57,42.1 155.57,42.64 155.17,43.04 155.17,46.15 154.5,46.82 154.5,49.04 152.3,51.24 152.3,56.19 v2(153.03,56.92)
  IN1 w0.089: 155.57,42.1 155.57,40.59 159.49,36.67 164.92,36.67 166.71,34.87 171.27,34.87 172.24,33.91 192,33.91 192.83,33.08 195.12,33.08 207.4,20.8 207.4,15.87 206.28,14.75 206.28,14.37 206.14,14.23 205.53,14.23 205.38,14.08 205.38,13.88 205.53,13.73 206.14,13.73 206.28,13.59 206.28,13.38 206.14,13.23 205.53,13.23 205.38,13.09 205.38,12.88 205.53,12.74 206.14,12.74 206.28,12.59 206.28,10.01 v2(206.68,9.61)
  BOTTOM w0.081: UC1.AK29 153.36,57.24 v2(153.03,56.92)
  BOTTOM w0.102: v2(206.68,9.61) 207,9.29 JDIMM2.148
DDR_B_D18: length 93.1
  IN1 w0.076: v2(153.98,56.27) 153.98,56.41 154.09,56.52 154.46,56.52 154.56,56.41 154.56,53.6 154.57,53.59 154.57,53.51 154.79,53.3 154.86,53.3 157.32,50.84 157.32,43.38 158.35,42.36 158.35,42.1
  IN1 w0.089: 158.35,42.1 158.35,41.74 160.64,39.46 166.07,39.46 167.53,38 172.09,38 173.19,36.9 175.89,36.9 176.09,36.69 180.22,36.69 180.42,36.9 188.65,36.9 188.86,36.69 193.16,36.69 193.99,35.86 196.28,35.86 211.28,20.86 211.28,12.87 210.8,12.39 210.8,11.29 210.64,11.14 v2(210,11.14)
  BOTTOM w0.081: v2(153.98,56.27) 154.31,56.59 UC1.AL28
  BOTTOM w0.102: JDIMM2.160 210.6,10.54 v2(210,11.14)
DDR_B_D19: length 93.9
  IN1 w0.076: 158.67,42.1 158.67,42.33 157.5,43.5 157.5,50.93 155.33,53.1 155.33,57 155.04,57.29 154.31,57.29 v2(153.93,56.92)
  IN1 w0.089: 158.67,42.1 158.67,41.88 160.77,39.77 166.2,39.77 167.66,38.31 172.22,38.31 173.32,37.21 176.02,37.21 176.22,37.01 180.08,37.01 180.29,37.21 188.81,37.21 189.01,37.01 193.29,37.01 194.12,36.18 196.41,36.18 211.59,21 211.59,12.74 211.11,12.25 211.11,10.73 v2(210,9.61)
  BOTTOM w0.081: UC1.AK28 154.26,57.24 v2(153.93,56.92)
  BOTTOM w0.102: JDIMM2.158 v2(210,9.61)
DDR_B_D20: length 91.2
  IN1 w0.076: 156.52,42.1 156.52,42.56 155.69,43.4 155.69,49.41 155.28,49.81 155.28,50.18 155.27,50.18 155.27,50.19 155.06,50.39 155.06,50.39 154.4,51.06 154.4,51.34 154.11,51.62 153.8,51.62 153.79,51.64 153.79,51.64 153.58,51.85 153.58,51.85 153.03,52.4 v2(153.03,53.66)
  IN1 w0.089: v2(208.12,17.88) 208.12,15.69 207.8,15.36 207.8,14.78 208.26,14.31 208.26,13.02 208.34,12.94 208.79,12.94 208.89,13.05 208.89,20.65 195.52,34.03 193.23,34.03 192.4,34.86 172.64,34.86 171.33,36.16 166.77,36.16 165.31,37.62 159.88,37.62 156.52,40.98 156.52,42.1
  BOTTOM w0.081: UC1.AR29 153.36,53.99 v2(153.03,53.66)
  BOTTOM w0.102: v2(208.12,17.88) 207.71,17.88 207.3,17.47 JDIMM2.149
DDR_B_D21: length 92
  IN1 w0.076: v2(153.03,54.96) 152.66,54.59 152.66,52.32 152.99,51.98 152.99,51.87 152.66,51.53 152.66,51.38 153.15,50.89 153.3,50.89 153.85,51.43 154.06,51.43 154.23,51.27 154.23,51.11 153.63,50.52 153.63,50.41 153.87,50.16 153.98,50.16 154.36,50.55 154.47,50.55 154.56,50.46 154.56,50.04 154.38,49.86 154.38,49.66 154.86,49.18 154.86,48.85 154.95,48.76 155.41,48.76 155.52,48.64 155.52,48.32 155.44,48.24 154.94,48.24 154.86,48.16 154.86,47.82 154.93,47.74 155.42,47.74 155.52,47.64 155.52,47.33 155.44,47.25 154.95,47.25 154.86,47.15 154.86,46.95 155.06,46.75 155.37,46.75 155.51,46.62 155.51,43.28 156.2,42.59 156.2,42.1
  IN1 w0.089: v2(208.12,19.41) 208.12,19.12 208.2,19.04 208.43,19.04 208.52,19.12 208.52,20.58 208.43,20.66 208.1,20.66 208.04,20.73 208.04,21.06 195.38,33.71 193.09,33.71 192.27,34.54 172.51,34.54 171.54,35.51 171.05,35.51 170.98,35.58 170.98,35.78 170.92,35.84 170.55,35.84 170.49,35.78 170.49,35.58 170.42,35.51 170.06,35.51 169.99,35.58 169.99,35.77 169.92,35.84 169.56,35.84 169.5,35.78 169.5,35.58 169.43,35.51 169.06,35.51 169,35.57 169,35.76 168.92,35.84 168.58,35.84 168.51,35.77 168.51,35.58 168.44,35.51 168.07,35.51 168.01,35.57 168.01,35.77 167.94,35.85 167.59,35.85 167.52,35.77 167.52,35.58 167.45,35.51 167.07,35.51 167,35.57 167,35.78 166.93,35.85 166.64,35.85 165.18,37.3 159.75,37.3 156.2,40.85 156.2,42.1
  BOTTOM w0.081: v2(153.03,54.96) 153.36,55.29 UC1.AN29
  BOTTOM w0.102: v2(208.12,19.41) 207.65,19.87 206.87,19.87 206.7,19.71 JDIMM2.147
DDR_B_D22: length 90.5
  IN1 w0.076: v2(153.98,53.66) 153.98,53.59 153.99,53.59 153.99,53.39 153.82,53.22 153.82,53.12 154.06,52.88 154.19,52.88 154.38,53.07 154.51,53.07 154.72,52.86 154.72,52.72 154.53,52.53 154.53,52.41 154.76,52.18 154.89,52.18 155.08,52.37 155.2,52.37 155.42,52.16 155.42,51.99 154.91,51.48 154.91,51.28 155.09,51.1 155.23,51.1 155.78,51.65 155.93,51.65 156.13,51.45 156.13,51.3 155.57,50.74 155.57,50.62 155.8,50.39 155.92,50.39 156.45,50.92 156.66,50.92 156.97,50.61 156.97,50.32 156.46,49.81 156.46,49.67 156.97,49.16 156.97,43.21 157.72,42.47 157.72,42.1
  IN1 w0.089: v2(210.24,19.41) 210.24,19.11 210.31,19.04 210.57,19.04 210.64,19.11 210.64,20.47 210.54,20.57 210.18,20.57 210.09,20.66 210.09,20.82 210.21,20.94 210.21,21.03 196.01,35.23 193.72,35.23 192.89,36.06 188.48,36.06 188.27,36.26 188.03,36.26 187.82,36.06 187.49,36.06 187.28,36.26 187.04,36.26 186.83,36.06 186.5,36.06 186.29,36.26 186.04,36.26 185.84,36.06 185.51,36.06 185.3,36.26 185.05,36.26 184.85,36.06 184.52,36.06 184.31,36.26 184.06,36.26 183.86,36.06 183.53,36.06 183.32,36.26 183.07,36.26 182.87,36.06 182.54,36.06 182.33,36.26 182.08,36.26 181.88,36.06 181.55,36.06 181.34,36.26 181.09,36.26 180.89,36.06 175.45,36.06 175.25,36.26 174.96,36.26 174.75,36.06 174.47,36.06 174.26,36.26 173.97,36.26 173.77,36.06 173.13,36.06 171.83,37.36 167.27,37.36 165.81,38.82 160.38,38.82 157.72,41.48 157.72,42.1
  BOTTOM w0.081: v2(153.98,53.66) 154.32,53.66 154.37,53.72 UC1.AR28
  BOTTOM w0.102: JDIMM2.157 209.7,17.56 209.18,18.09 209.18,19.9 209.29,20.01 209.63,20.01 v2(210.24,19.41)
DDR_B_D23: length 91.9
  IN1 w0.076: 158.04,42.1 158.04,42.4 157.15,43.29 157.15,50.72 154.75,53.12 154.71,53.12 154.4,53.44 154.4,53.47 154.38,53.49 154.38,53.91 v2(153.98,54.31)
  IN1 w0.089: v2(210.24,17.88) 210.09,17.73 210.09,12.89 210.19,12.79 210.75,12.79 210.96,13 210.96,20.73 196.14,35.55 193.85,35.55 193.03,36.37 188.69,36.37 188.49,36.58 180.55,36.58 180.35,36.37 175.96,36.37 175.75,36.58 173.06,36.58 171.96,37.68 167.4,37.68 165.94,39.14 160.51,39.14 158.04,41.61 158.04,42.1
  BOTTOM w0.081: v2(153.98,54.31) 154.31,54.64 UC1.AP28
  BOTTOM w0.102: v2(210.24,17.88) 210.3,17.82 JDIMM2.159
DDR_B_D24: length 54.5
  IN4 w0.084: 157.89,42.1 157.89,42.47 157.07,43.29 157.07,49.05 154.58,51.55 154.58,54.61 v2(154.94,54.96)
  IN4 w0.089: 157.89,42.1 157.89,40.32 159.88,38.33 159.88,28.49 167.42,20.94 167.42,13.94 167.28,13.79 166.86,13.79 166.71,13.65 166.71,13.44 166.86,13.3 167.28,13.3 167.42,13.15 167.42,11.23 v2(168.22,10.43)
  BOTTOM w0.081: UC1.AN26 155.26,55.29 v2(154.94,54.96)
  BOTTOM w0.102: JDIMM2.24 167.4,9.62 v2(168.22,10.43)
DDR_B_D25: length 53.4
  IN4 w0.084: 157.94,42.69 157.25,43.38 157.25,49.13 156.76,49.61 156.76,50.42 154.94,52.25 v2(154.94,53.66)
  IN4 w0.089: v2(168.22,11.96) 167.77,12.41 167.77,13.27 167.91,13.41 168.48,13.41 168.63,13.56 168.63,13.76 168.48,13.91 167.91,13.91 167.77,14.05 167.77,21.05 160.19,28.62 160.19,38.46 158.21,40.45 158.21,42.41 157.94,42.69
  BOTTOM w0.081: v2(154.94,53.66) 155.26,53.99 UC1.AR26
  BOTTOM w0.102: JDIMM2.22 166.8,10.55 v2(168.22,11.96)
DDR_B_D26: length 52.5
  IN4 w0.089: v2(170.28,19.39) 170.28,19.22 169.86,18.81 169.63,18.81 169.51,18.93 169.51,21.04 161.87,28.68 161.87,28.97 161.98,29.09 163.23,29.09 163.37,29.23 163.37,29.44 163.23,29.58 162.44,29.58 162.3,29.73 162.3,29.93 162.44,30.08 163.23,30.08 163.37,30.22 163.37,30.43 163.23,30.57 162.44,30.57 162.3,30.72 162.3,30.92 162.44,31.07 163.23,31.07 163.37,31.21 163.37,31.42 163.23,31.57 162.44,31.57 162.3,31.71 162.3,31.92 162.44,32.06 162.88,32.06 163.03,32.21 163.03,32.41 162.88,32.56 162.44,32.56 162.3,32.7 162.3,37.06 161.39,37.96 161.39,39 159.5,40.89 159.5,42.57 158.45,43.61 158.45,50.21 155.89,52.78 v2(155.89,53.66)
  BOTTOM w0.081: v2(155.89,53.66) 156.21,53.99 UC1.AR25
  BOTTOM w0.102: JDIMM2.33 170.1,17.43 169.84,17.69 169.84,18.96 v2(170.28,19.39)
DDR_B_D27: length 53.5
  IN4 w0.089: v2(170.28,17.86) 169.89,17.47 169.89,15.68 170.01,15.56 170.43,15.56 170.7,15.82 170.7,20.29 163.71,27.28 163.71,28.12 163.55,28.28 162.72,28.28 162.47,28.52 162.47,28.65 162.59,28.77 163.55,28.77 163.71,28.93 163.71,32.18 162.61,33.27 162.61,37.19 162.29,37.51 162.29,37.67 162.61,37.99 162.61,38.22 162.45,38.39 162.31,38.39 161.91,38 161.81,38 161.71,38.09 161.71,38.5 161.92,38.71 161.92,38.91 159.81,41.03 159.81,42.61 158.68,43.74 158.68,50.31 156.29,52.7 156.29,53.91 v2(155.89,54.31)
  BOTTOM w0.081: v2(155.89,54.31) 156.21,54.64 UC1.AP25
  BOTTOM w0.102: v2(170.28,17.86) 170.7,17.44 JDIMM2.35
DDR_B_D28: length 56.2
  IN4 w0.084: 156.73,42.93 156.73,48.83 154.68,50.88 154.54,50.88 153.57,51.85 153.57,57.05 153.57,57.05 153.57,57.06 153.78,57.27 154.08,57.27 154.09,57.27 154.53,57.27 v2(154.89,56.92)
  IN4 w0.089: v2(167.01,17.86) 167.01,14.36 166.91,14.25 166.37,14.25 166.26,14.35 166.26,21.2 159.24,28.23 159.24,33.35 158.92,33.67 158.92,34.36 158.01,35.27 158.01,39.3 157.13,40.18 157.13,42.52 156.73,42.93
  BOTTOM w0.081: v2(154.89,56.92) 155.21,57.24 UC1.AK26
  BOTTOM w0.102: JDIMM2.21 166.5,17.35 v2(167.01,17.86)
DDR_B_D29: length 54.9
  IN4 w0.084: 157.58,42.1 157.58,42.45 156.9,43.13 156.9,48.92 154.39,51.43 154.39,55.07 v2(154.94,55.62)
  IN4 w0.089: 157.58,42.1 157.58,40.18 158.33,39.43 158.33,38.94 158.43,38.84 158.92,38.84 159.19,38.57 159.19,38.43 159.11,38.34 158.44,38.34 158.33,38.23 158.33,37.96 158.44,37.85 159.46,37.85 159.56,37.74 159.56,37.45 159.46,37.35 158.43,37.35 158.33,37.25 158.33,36.97 158.44,36.86 159.44,36.86 159.56,36.74 159.56,36.47 159.45,36.36 158.43,36.36 158.33,36.26 158.33,35.97 158.43,35.87 159.47,35.87 159.56,35.78 159.56,35.47 159.46,35.37 158.65,35.37 158.56,35.28 158.56,35.17 158.85,34.88 159.46,34.88 159.56,34.77 159.56,34.43 159.47,34.34 159.33,34.34 159.24,34.25 159.24,33.8 159.31,33.73 159.47,33.73 159.56,33.64 159.56,28.36 166.58,21.33 166.58,21.09 166.65,21.02 166.89,21.02 167.08,20.84 167.08,20.72 166.88,20.53 166.65,20.53 166.58,20.46 166.58,19.45 166.65,19.39 v2(167.01,19.39)
  BOTTOM w0.081: v2(154.94,55.62) 155.26,55.94 UC1.AM26
  BOTTOM w0.102: v2(167.01,19.39) 167.44,18.96 167.44,17.69 167.33,17.57 167.33,17.57 167.1,17.35 JDIMM2.23
DDR_B_D30: length 56.1
  IN4 w0.089: v2(155.84,56.92) 156.42,56.33 156.42,56.07 157.29,55.2 157.29,52.39 159.16,50.51 159.16,43.89 160.45,42.61 160.45,41.29 163.25,38.49 163.25,33.54 164.34,32.44 164.34,27.55 171.41,20.48 171.41,12.36 v2(171.01,11.96)
  BOTTOM w0.081: v2(155.84,56.92) 156.16,57.24 UC1.AK25
  BOTTOM w0.102: v2(171.01,11.96) 170.4,11.35 JDIMM2.34
DDR_B_D31: length 55.5
  IN4 w0.089: v2(171.01,10.43) 170.24,11.2 170.24,13.1 171.04,13.9 171.04,20.4 164.02,27.42 164.02,32.31 162.93,33.4 162.93,38.36 160.13,41.16 160.13,42.62 158.92,43.83 158.92,50.41 156.52,52.81 156.52,53.98 156.35,54.15 156.35,55.81 v2(155.89,56.27)
  BOTTOM w0.081: UC1.AL25 156.21,56.59 v2(155.89,56.27)
  BOTTOM w0.102: v2(171.01,10.43) 171,9.67 JDIMM2.36
DDR_B_D32: length 86.3
  IN1 w0.089: v2(158.08,46.32) 158.43,45.97 158.43,45.17 158.44,45.16 158.44,45.15 158.63,44.96 158.63,43.67 161.3,41.01 166.72,41.01 168.17,39.55 172.73,39.55 173.23,39.05 179.1,39.05 179.7,38.45 189.91,38.45 190.11,38.24 193.88,38.24 194.51,37.62 196.72,37.62 213.44,20.89 213.44,13.67 213.09,13.32 212.29,13.32 212.19,13.22 212.19,12.49 211.71,12.01 211.71,10.45 v2(212.54,9.61)
  BOTTOM w0.076: UC1.AY23 157.14,50.62 157.15,50.61 157.15,49.89 157.44,49.61 157.44,48.57 157.68,48.32 157.68,46.71 v2(158.08,46.32)
  BOTTOM w0.102: JDIMM2.166 212.4,9.47 v2(212.54,9.61)
DDR_B_D33: length 87.4
  IN1 w0.089: v2(212.68,17.88) 212.28,17.88 212.19,17.79 212.19,13.76 212.31,13.64 212.96,13.64 213.12,13.8 213.12,20.76 196.58,37.3 194.36,37.3 193.73,37.92 189.98,37.92 189.78,38.13 179.57,38.13 178.96,38.74 173.1,38.74 172.6,39.23 168.04,39.23 166.58,40.69 161.16,40.69 158.45,43.4 158.45,44.7 v2(158.08,45.07)
  BOTTOM w0.076: v2(158.08,45.07) 157.52,45.63 157.52,46.64 157.52,46.64 157.52,48.25 157.27,48.5 157.27,49.54 156.99,49.83 156.99,50.54 156.85,50.68 156.85,50.94 156.94,51.12 156.94,51.13 157.14,51.33 UC1.AW23
  BOTTOM w0.102: JDIMM2.165 212.1,17.69 212.3,17.88 v2(212.68,17.88)
DDR_B_D34: length 86.2
  IN1 w0.089: v2(214.32,9.61) 214.32,9.72 215.07,10.47 215.07,17.21 215.85,17.99 215.85,20.17 215.75,20.27 215.75,21.22 197.52,39.45 195.27,39.45 194.44,40.28 180.46,40.28 179.86,40.89 173.99,40.89 173.49,41.38 168.93,41.38 167.48,42.84 162.06,42.84 161.79,43.1 161.45,43.1 160.06,44.5 160.06,44.67 v2(159.68,45.05)
  BOTTOM w0.076: v2(159.68,45.05) 158.78,45.95 158.78,49.25 158.62,49.4 158.62,50.75 UC1.AY21
  BOTTOM w0.102: JDIMM2.174 214.8,9.13 v2(214.32,9.61)
DDR_B_D35: length 87
  IN1 w0.089: v2(159.68,46.33) 160.07,45.94 160.07,45.36 160.14,45.29 161.18,45.29 161.24,45.23 161.24,44.78 161.16,44.7 160.45,44.7 160.39,44.64 160.39,44.47 160.65,44.21 161.14,44.21 161.24,44.12 161.24,43.62 161.49,43.37 161.98,43.37 162.19,43.16 167.8,43.16 167.94,43.02 167.94,42.66 168.08,42.52 168.37,42.52 168.41,42.56 168.41,43.03 168.54,43.16 168.79,43.16 168.91,43.04 168.91,41.86 169.07,41.7 169.39,41.7 169.5,41.81 169.5,42.89 169.57,42.95 169.96,42.95 170.05,42.86 170.05,41.85 170.2,41.7 175.1,41.7 175.51,41.28 179.91,41.28 180.59,40.6 194.57,40.6 195.4,39.77 197.65,39.77 216.21,21.2 216.21,21.09 216.07,20.94 216.07,20.69 216.19,20.57 216.45,20.57 216.61,20.73 216.69,20.73 216.92,20.5 216.92,20.37 216.76,20.21 216.76,19.95 216.92,19.79 216.92,19.02 216.83,18.94 216.63,18.94 216.36,19.21 v2(216.36,19.41)
  BOTTOM w0.076: UC1.AW21 158.49,51.29 158.79,51 158.79,49.47 158.94,49.31 158.94,47.07 v2(159.68,46.33)
  BOTTOM w0.102: JDIMM2.175 215.1,17.51 215.76,18.17 215.76,18.99 216.17,19.41 v2(216.36,19.41)
DDR_B_D36: length 87.6
  IN1 w0.089: v2(212.68,19.41) 212.68,19.19 212.47,18.99 212.26,18.99 212.19,19.06 212.19,20.4 212.26,20.47 212.41,20.47 212.6,20.65 212.6,20.84 212.47,20.97 212.29,20.97 212.21,21.04 212.21,21.22 196.45,36.98 194.16,36.98 193.54,37.61 189.85,37.61 189.64,37.81 179.1,37.81 179.02,37.9 179.02,38.23 178.83,38.42 178.59,38.42 178.52,38.35 178.52,37.87 178.46,37.81 178.11,37.81 178.03,37.9 178.03,38.3 177.91,38.42 177.62,38.42 177.53,38.33 177.53,37.69 177.44,37.61 177.11,37.61 177.04,37.68 177.04,38.33 176.95,38.42 176.62,38.42 176.54,38.34 176.54,37.88 176.47,37.81 176.13,37.81 176.05,37.9 176.05,38.34 175.97,38.42 175.61,38.42 175.55,38.36 175.55,37.87 175.49,37.81 175.13,37.81 175.05,37.88 175.05,38.34 174.98,38.42 174.62,38.42 174.56,38.36 174.56,37.9 174.47,37.81 174.14,37.81 174.06,37.88 174.06,38.35 174,38.42 173.65,38.42 173.57,38.34 173.57,38.06 173.52,38.01 173.37,38.01 172.47,38.91 167.91,38.91 166.45,40.37 161.03,40.37 158.48,42.92 158.34,42.92 157.7,43.56 157.7,43.99 v2(158.08,44.37)
  BOTTOM w0.076: v2(158.08,44.37) 157.34,45.11 157.34,48.2 157.11,48.43 157.11,49.47 156.82,49.76 156.82,50.47 156.68,50.61 156.68,50.99 156.7,51.03 156.71,51.03 156.76,51.13 156.76,51.8 UC1.AV23
  BOTTOM w0.102: v2(212.68,19.41) 212.29,19.8 211.74,19.8 211.5,19.56 JDIMM2.163
DDR_B_D37: length 88.7
  IN1 w0.089: v2(158.08,46.97) 158.61,46.44 158.61,45.24 158.82,45.03 158.82,43.93 161.43,41.32 166.85,41.32 168.31,39.86 172.87,39.86 173.36,39.37 179.23,39.37 179.83,38.76 190.04,38.76 190.24,38.56 194.01,38.56 194.64,37.93 196.89,37.93 213.76,21.07 213.76,12.35 v2(212.54,11.14)
  BOTTOM w0.076: UC1.AU23 157.91,52.83 158.18,52.55 158.18,52.39 158.09,52.3 158.09,51.99 158.11,51.98 158.11,51.79 158.1,51.77 158.06,51.68 158.06,51.68 158.04,51.63 158.04,51.43 158.1,51.28 158.11,51.28 158.11,51.27 158.11,51.14 158.06,51.03 158.06,51.03 158.04,50.98 158.04,50.69 158.27,50.45 158.27,49.28 158.45,49.11 158.45,47.11 158.3,46.97 v2(158.08,46.97)
  BOTTOM w0.102: JDIMM2.164 211.8,10.4 v2(212.54,11.14)
DDR_B_D38: length 87.7
  IN1 w0.089: v2(159.68,44.49) 161.31,42.86 161.58,42.86 161.92,42.52 167.34,42.52 168.8,41.06 173.36,41.06 173.86,40.57 179.72,40.57 180.33,39.96 194.3,39.96 195.13,39.13 197.39,39.13 215.43,21.09 215.43,20.14 215.54,20.03 215.54,18.17 214.72,17.35 214.72,11.54 v2(214.32,11.14)
  BOTTOM w0.076: UC1.AV21 158.39,51.84 158.25,51.7 158.2,51.59 158.2,51.46 158.21,51.44 158.21,51.44 158.25,51.36 158.28,51.31 158.28,51.1 158.2,50.94 158.2,50.76 158.45,50.51 158.45,49.34 158.61,49.18 158.61,45.56 v2(159.68,44.49)
  BOTTOM w0.102: JDIMM2.176 215.4,10.06 v2(214.32,11.14)
DDR_B_D39: length 88.3
  IN1 w0.076: v2(159.68,46.98) 161.07,46.98 161.42,46.64 161.42,43.75 161.57,43.6 162.2,43.6 162.32,43.47 169.75,43.47 170.47,42.75 170.47,42.34 170.7,42.1
  IN1 w0.089: 170.7,42.1 170.79,42.01 175.23,42.01 175.65,41.6 180.05,41.6 180.64,41 194.62,41 195.53,40.09 197.78,40.09 217.23,20.64 217.23,18.89 216.9,18.55 216.9,17.72 215.87,16.68 215.87,15.24 215.76,15.14 215.49,15.14 215.39,15.24 215.39,17.07 216.2,17.88 v2(216.36,17.88)
  BOTTOM w0.076: v2(159.68,46.98) 159.11,47.55 159.11,49.38 158.95,49.54 158.95,51.07 158.79,51.23 158.79,51.65 158.66,51.78 158.66,52.04 158.68,52.06 158.68,52.3 158.39,52.59 UC1.AU21
  BOTTOM w0.102: v2(216.36,17.88) 216.11,17.88 215.7,17.48 JDIMM2.177
DDR_B_D40: length 49.8
  IN4 w0.089: v2(172.82,19.39) 172.82,19.18 173.04,18.96 173.25,18.96 173.36,19.07 173.36,20.27 165.57,28.06 165.57,33.67 165.43,33.81 164.72,33.81 164.48,34.05 164.48,34.22 164.57,34.31 165.43,34.31 165.57,34.45 165.57,34.66 165.43,34.8 164.64,34.8 164.48,34.96 164.48,35.16 164.61,35.3 165.43,35.3 165.57,35.44 165.57,35.65 165.43,35.79 164.64,35.79 164.48,35.95 164.48,36.15 164.61,36.29 165.43,36.29 165.57,36.43 165.57,36.64 165.43,36.78 164.64,36.78 164.48,36.94 164.48,37.15 164.61,37.28 165.43,37.28 165.57,37.42 165.57,37.64 165.44,37.77 164.63,37.77 164.48,37.92 164.48,39 161.69,41.79 161.69,42.41 160.53,43.57 160.53,48.67 159.87,49.33 v2(159.8,49.33)
  BOTTOM w0.076: UC1.AY19 159.45,50.75 159.45,49.85 159.8,49.5 v2(159.8,49.33)
  BOTTOM w0.102: JDIMM2.39 171.9,17.5 171.84,17.56 171.84,18.41 v2(172.82,19.39)
DDR_B_D41: length 50.9
  IN4 w0.089: v2(172.82,17.86) 173.07,17.61 173.07,13.74 172.87,13.54 172.55,13.54 172.32,13.77 172.32,20.86 165.26,27.93 165.26,32.82 164.16,33.91 164.16,38.87 161.38,41.66 161.38,42.42 160.34,43.45 160.34,48.13 v2(159.69,48.79)
  BOTTOM w0.076: UC1.AW19 159.41,51.53 159.28,51.4 159.28,49.68 159.44,49.52 159.44,49.04 v2(159.69,48.79)
  BOTTOM w0.102: v2(172.82,17.86) 172.57,18.11 172.4,18.11 172.22,17.93 172.22,17.75 172.5,17.47 JDIMM2.41
DDR_B_D42: length 49.3
  IN4 w0.089: v2(161.53,48.92) 162.38,48.08 162.38,45.08 163.87,43.59 163.87,43.15 169.53,37.49 169.53,30.2 169.38,30.06 168.95,30.06 168.8,29.91 168.8,29.71 168.94,29.56 169.38,29.56 169.53,29.42 169.53,29.21 169.38,29.07 168.98,29.07 168.84,28.92 168.84,28.72 168.98,28.57 169.38,28.57 169.53,28.43 169.53,28.03 177.11,20.45 177.11,15.4 176.95,15.24 176.5,15.24 176.39,15.35 v2(176.39,17.86)
  BOTTOM w0.076: v2(161.53,48.92) 161.53,49.1 160.91,49.73 160.91,50.54 160.92,50.56 UC1.AY17
  BOTTOM w0.102: v2(176.39,17.86) 176.1,17.58 JDIMM2.53
DDR_B_D43: length 50.4
  IN4 w0.089: v2(175.84,10.43) 176.24,10.83 176.24,13.17 175.97,13.43 175.97,20.69 168.16,28.49 168.16,37.94 163.21,42.9 163.21,43.43 162.06,44.58 v2(161.79,44.58)
  BOTTOM w0.076: UC1.AW17 160.92,51.28 161.16,51.05 161.16,51.06 161.18,51.01 161.19,51 161.22,50.93 161.22,50.76 161.09,50.63 161.09,49.92 161.93,49.08 161.93,48.04 162.18,47.78 162.18,44.97 161.79,44.58 v2(161.79,44.58)
  BOTTOM w0.102: JDIMM2.52 175.8,10.4 v2(175.84,10.43)
DDR_B_D44: length 51.1
  IN4 w0.089: v2(173.57,10.43) 172.57,10.43 172.01,11 172.01,20.73 164.94,27.8 164.94,32.69 163.85,33.78 163.85,38.74 161.05,41.54 161.05,42.48 160.09,43.43 160.09,47.8 v2(159.72,48.17)
  BOTTOM w0.076: v2(159.72,48.17) 159.27,48.62 159.27,49.45 159.12,49.61 159.12,51.48 159.68,52.05 UC1.AV19
  BOTTOM w0.102: JDIMM2.42 172.8,9.67 v2(173.57,10.43)
DDR_B_D45: length 52.5
  IN4 w0.089: v2(161.53,47.7) 160.84,47.01 160.84,43.51 162.04,42.32 162.04,41.89 165.89,38.04 165.89,28.19 173.68,20.4 173.68,13.36 173.97,13.08 173.97,12.36 v2(173.57,11.96)
  BOTTOM w0.076: v2(161.53,47.7) 161.21,47.7 160.97,47.94 160.97,49.15 160.58,49.55 160.58,50.53 160.47,50.64 160.47,50.98 160.54,51.14 160.54,51.27 160.54,51.28 160.54,51.28 160.49,51.38 160.47,51.43 160.47,51.63 160.49,51.68 160.52,51.75 160.54,51.79 160.54,52.63 160.34,52.83 UC1.AU19
  BOTTOM w0.102: v2(173.57,11.96) 172.2,10.6 JDIMM2.40
DDR_B_D46: length 50.8
  IN4 w0.089: v2(176.39,19.39) 176.79,19.79 176.79,20.32 168.48,28.63 168.48,30.45 168.63,30.6 168.88,30.6 169.02,30.74 169.02,30.95 168.88,31.09 168.63,31.09 168.48,31.24 168.48,31.44 168.63,31.59 169.05,31.59 169.2,31.73 169.2,31.94 169.05,32.08 168.63,32.08 168.48,32.23 168.48,32.44 168.63,32.58 169.05,32.58 169.2,32.73 169.2,32.93 169.05,33.08 168.63,33.08 168.48,33.22 168.48,33.43 168.63,33.57 169.05,33.57 169.2,33.72 169.2,33.92 169.05,34.07 168.63,34.07 168.48,34.21 168.48,34.42 168.63,34.56 169.05,34.56 169.2,34.71 169.2,34.91 169.05,35.06 168.63,35.06 168.48,35.2 168.48,35.41 168.63,35.55 169.05,35.55 169.2,35.7 169.2,35.9 169.05,36.05 168.63,36.05 168.48,36.19 168.48,36.4 168.63,36.54 169.05,36.54 169.2,36.69 169.2,36.89 169.05,37.04 168.63,37.04 168.48,37.18 168.48,38.08 163.54,43.03 163.54,43.51 162.17,44.87 162.17,47.73 161.62,48.28 v2(161.53,48.28)
  BOTTOM w0.076: v2(161.53,48.28) 161.14,48.68 161.14,49.22 160.74,49.62 160.74,50.6 160.63,50.71 160.63,50.94 160.68,51.05 160.71,51.1 160.71,51.31 160.68,51.36 160.68,51.36 160.64,51.44 160.64,51.45 160.63,51.46 160.63,51.59 160.68,51.7 160.92,51.94 UC1.AV17
  BOTTOM w0.102: v2(176.39,19.39) 175.87,19.39 175.75,19.26 175.75,17.74 175.5,17.5 JDIMM2.51
DDR_B_D47: length 52
  IN4 w0.089: v2(161.78,43.97) 162.16,43.97 162.87,43.26 162.87,42.78 167.85,37.81 167.85,28.36 175.65,20.56 175.65,17.75 175.44,17.54 175.44,12.36 v2(175.84,11.96)
  BOTTOM w0.076: UC1.AU17 161.22,52.54 161.22,51.3 161.29,51.16 161.3,51.15 161.3,51.14 161.33,51.08 161.35,51.03 161.35,51.03 161.36,51.03 161.38,50.98 161.38,50.98 161.38,50.98 161.38,50.97 161.38,50.69 161.26,50.56 161.26,49.99 162.09,49.15 162.09,48.11 162.34,47.85 162.34,44.53 v2(161.78,43.97)
  BOTTOM w0.102: JDIMM2.50 175.2,11.33 v2(175.84,11.96)
DDR_B_D48: length 93.6
  IN1 w0.076: v2(158.64,53.66) 158.64,53.49 159.42,52.7 160.34,52.7 163.32,49.73 163.32,47.93 163.51,47.74 163.51,47.65 163.37,47.51 163.37,47.43 163.64,47.17 163.72,47.17 163.84,47.28 163.97,47.28 164.25,47 164.25,46.88 164.13,46.77 164.13,46.67 164.37,46.43 164.49,46.43 164.61,46.54 164.7,46.54 164.95,46.3 164.95,46.18 164.84,46.08 164.84,45.96 165.08,45.72 165.18,45.72 165.3,45.83 165.41,45.83 165.69,45.56 169.56,45.56 170.02,45.1
  IN1 w0.089: v2(221.03,19.41) 221.03,19.18 220.85,19 220.54,19 220.46,19.08 220.46,20.35 220.56,20.45 220.74,20.45 220.96,20.67 220.96,20.79 220.78,20.98 220.55,20.98 220.46,21.06 220.46,21.29 198.92,42.83 197.05,42.83 196.97,42.91 196.97,43.04 196.64,43.37 196.52,43.37 196.38,43.24 196.26,43.24 196.15,43.35 196.15,43.7 196.05,43.8 190.44,43.8 190.34,43.9 190.34,44.38 190.27,44.45 189.93,44.45 189.84,44.36 189.84,43.9 189.74,43.79 189.49,43.79 189.35,43.93 189.35,44.36 189.25,44.45 188.89,44.45 188.73,44.29 187.81,44.29 187.65,44.45 187.25,44.45 187.17,44.37 187.17,44.03 187.09,43.95 186.73,43.95 186.67,44.01 186.67,44.37 186.59,44.45 186.23,44.45 186.17,44.39 186.17,44.03 186.1,43.96 185.74,43.96 185.68,44.02 185.68,44.22 185.6,44.3 185.5,44.3 185.16,43.96 183.42,43.96 183.35,44.03 183.35,44.19 183.2,44.34 182.93,44.34 182.86,44.27 182.86,44.04 182.78,43.95 182.45,43.95 182.36,44.04 182.36,44.25 182.27,44.34 181.95,44.34 181.87,44.27 181.87,44.01 181.81,43.95 181.58,43.95 181.19,44.34 177.86,44.34 177.68,44.53 177.53,44.53 177.35,44.34 177.01,44.34 176.91,44.45 176.91,44.56 177.23,44.88 177.23,44.98 177.1,45.1 176.61,45.1 176.53,45.02 176.53,44.84 176.45,44.76 176.11,44.76 176.03,44.84 176.03,45.03 175.96,45.1 175.31,45.1 175.22,45.01 175.22,44.86 175.13,44.76 174.82,44.76 174.73,44.85 174.73,45.02 174.64,45.1 174.32,45.1 174.23,45.01 174.23,44.85 174.15,44.76 173.81,44.76 173.74,44.84 173.74,45.03 173.66,45.1 170.96,45.1 170.89,45.04 170.89,44.67 170.77,44.55 170.57,44.55 170.4,44.73 170.4,45.03 170.32,45.1 170.02,45.1
  BOTTOM w0.081: UC1.AR21 158.96,53.99 v2(158.64,53.66)
  BOTTOM w0.102: v2(221.03,19.41) 219.9,18.28 JDIMM2.191
DDR_B_D49: length 95
  IN1 w0.076: v2(157.69,53.66) 157.69,52.85 158.91,51.62 159.61,51.62 160.82,50.41 161.41,49.83 161.91,49.83 162.77,48.96 162.77,45.82 163.62,44.98 167.99,44.98 168.62,44.35 170,44.35 170.46,43.89 172.87,43.89 173.2,43.56
  IN1 w0.089: v2(218.86,17.88) 217.76,16.78 217.76,13.46 217.89,13.33 218.44,13.33 218.6,13.5 218.6,16.53 219.26,17.2 219.26,20.8 198.43,41.63 196.17,41.63 195.21,42.59 188.99,42.59 188.49,43.09 187.93,43.09 187.59,42.75 181.08,42.75 180.69,43.15 176.29,43.15 175.87,43.56 173.2,43.56
  BOTTOM w0.081: v2(157.69,53.66) 158.01,53.99 UC1.AR22
  BOTTOM w0.102: v2(218.86,17.88) 218.66,17.88 218.53,18.01 218.53,18.21 218.4,18.33 218.22,18.33 218.1,18.21 218.1,18.05 217.94,17.88 217.77,17.88 217.5,17.61 JDIMM2.183
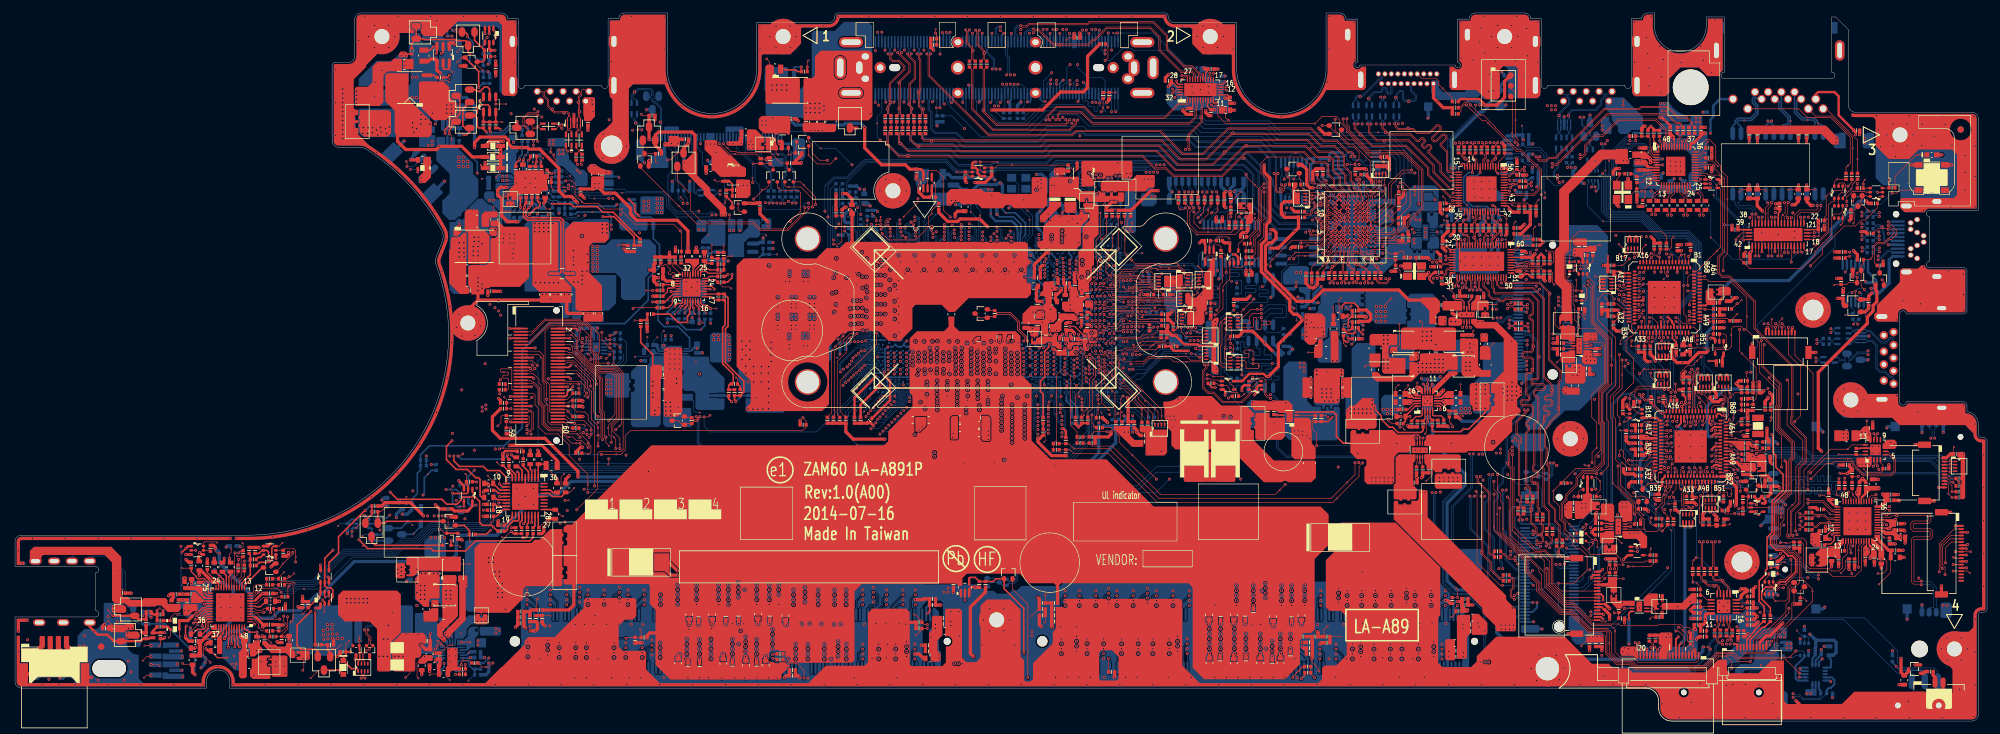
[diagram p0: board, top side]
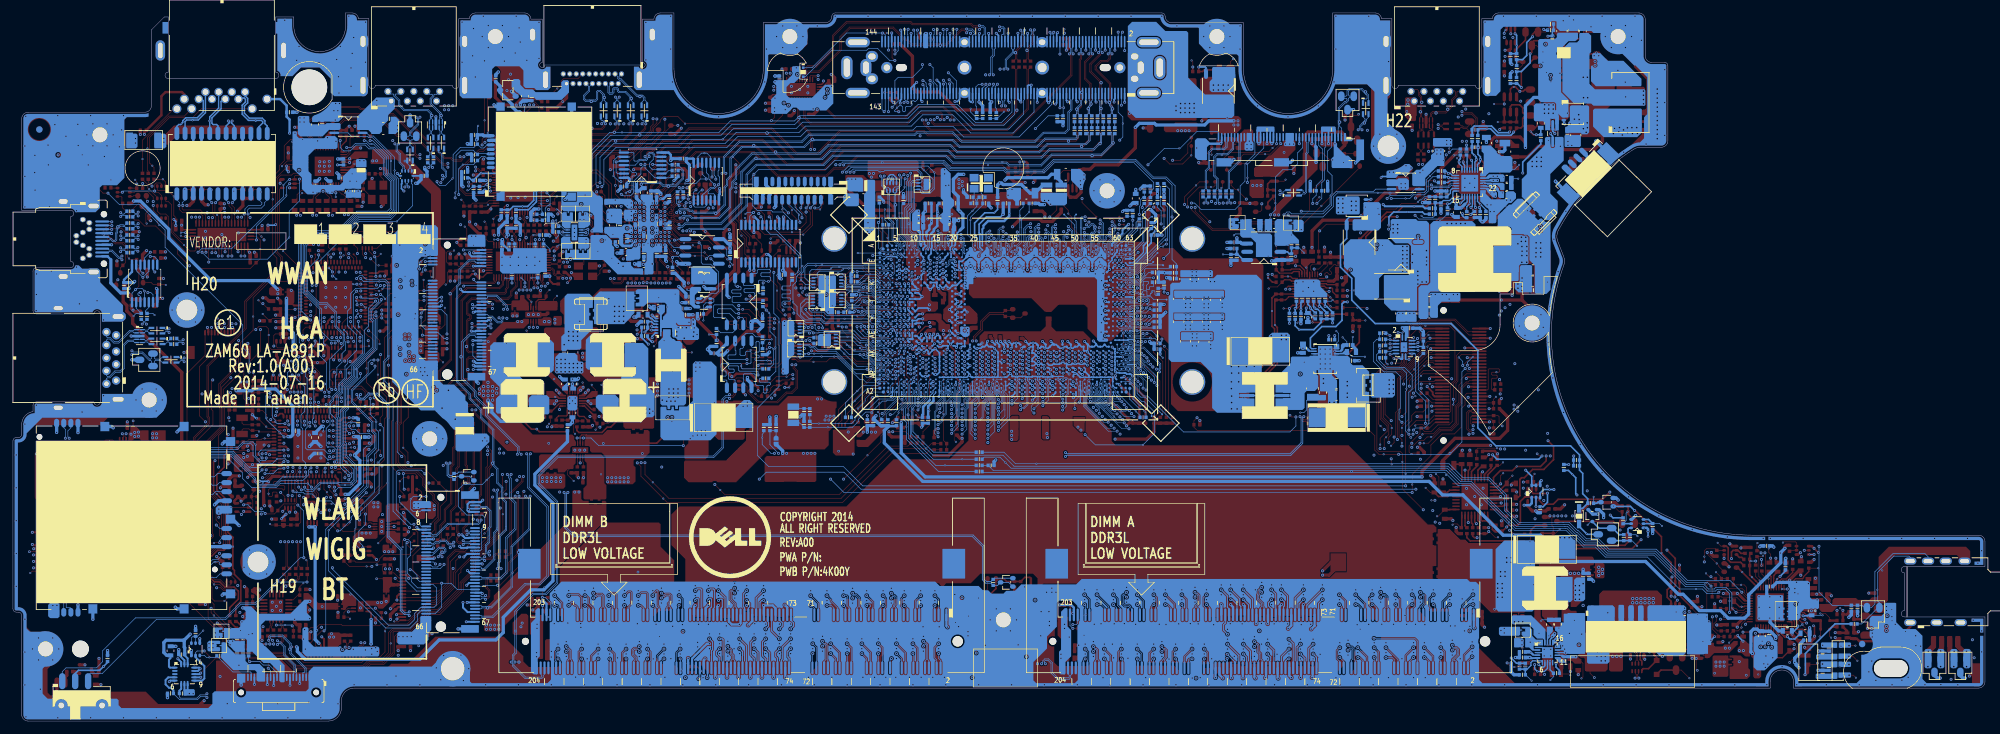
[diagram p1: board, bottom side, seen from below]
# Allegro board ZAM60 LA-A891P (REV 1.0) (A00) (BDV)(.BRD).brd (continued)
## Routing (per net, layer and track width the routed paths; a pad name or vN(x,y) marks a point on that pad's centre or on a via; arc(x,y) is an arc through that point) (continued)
DDR_B_D50: length 96.4
  IN1 w0.076: 173.36,45.74 170.01,45.74 169.23,46.52 165.44,46.52 163.77,48.19 163.77,49.75 163.72,49.81 163.72,49.81 160.53,53 160.52,53 160.44,53.09 159.64,53.09 159.19,53.54 159.19,55.71 v2(158.64,56.27)
  IN1 w0.089: 173.36,45.74 177.36,45.74 178.12,44.98 183.46,44.98 183.84,44.6 184.9,44.6 185.39,45.09 190.55,45.09 191.17,44.46 196.45,44.46 197.44,43.47 199.26,43.47 221.82,20.91 221.82,12.73 221.69,12.6 219.98,12.6 219.75,12.37 219.75,11.26 219.87,11.14 v2(220.52,11.14)
  BOTTOM w0.081: UC1.AL21 158.96,56.59 v2(158.64,56.27)
  BOTTOM w0.102: v2(220.52,11.14) 220.95,10.71 220.95,9.44 220.8,9.29 JDIMM2.194
DDR_B_D51: length 97.5
  IN1 w0.076: v2(157.69,55.62) 156.97,55.62 156.47,55.12 156.47,52.77 157.04,52.2 157.74,52.2 160.46,49.48 161.76,49.48 162.37,48.87 162.37,44.74 163.17,43.94 169.93,43.94 170.94,42.93 173.36,42.93
  IN1 w0.089: v2(216.86,9.61) 217.45,10.2 217.45,12.81 217.3,12.95 216.18,12.95 216.04,13.1 216.04,13.3 216.18,13.45 217.3,13.45 217.45,13.59 217.45,16.97 217.82,17.34 217.82,18.18 218.15,18.51 218.15,21.01 198.16,41 195.91,41 194.95,41.96 188.66,41.96 188.5,42.12 180.82,42.12 180.42,42.51 176.03,42.51 175.61,42.93 173.36,42.93
  BOTTOM w0.081: v2(157.69,55.62) 158.01,55.94 UC1.AM22
  BOTTOM w0.102: v2(216.86,9.61) 216.6,9.36 JDIMM2.180
DDR_B_D52: length 96.1
  IN1 w0.076: v2(157.66,54.98) 157.49,54.98 157.31,54.8 157.31,52.98 158.84,51.45 159.54,51.45 161.34,49.65 161.83,49.65 162.57,48.91 162.57,44.78 163.24,44.11 163.47,44.11 163.56,44.2 163.56,44.72 163.65,44.81 163.98,44.81 164.06,44.73 164.06,44.17 164.12,44.11 164.46,44.11 164.55,44.2 164.55,44.7 164.65,44.81 164.93,44.81 165.05,44.69 165.05,44.2 165.14,44.11 165.45,44.11 165.54,44.2 165.54,44.72 165.63,44.81 165.94,44.81 166.04,44.7 166.04,44.18 166.11,44.11 166.44,44.11 166.53,44.2 166.53,44.73 166.61,44.81 166.95,44.81 167.03,44.73 167.03,44.21 167.13,44.11 167.42,44.11 167.52,44.21 167.52,44.73 167.6,44.81 167.92,44.81 168.02,44.71 168.02,44.17 168.08,44.11 170,44.11 170.39,43.72 170.82,43.72 170.91,43.62 170.91,43.19 171.01,43.1 171.3,43.1 171.38,43.18 171.38,43.65 171.45,43.72 171.8,43.72 171.87,43.65 171.87,43.18 171.96,43.1 172.26,43.1 172.37,43.21 172.37,43.62 172.45,43.7 172.77,43.7 172.86,43.6 172.86,43.39
  IN1 w0.089: v2(218.86,19.41) 218.86,19.14 218.75,19.03 218.59,19.03 218.46,19.15 218.46,20.45 218.54,20.52 218.68,20.52 218.83,20.68 218.83,20.78 218.67,20.94 218.54,20.94 218.46,21.02 218.46,21.15 198.29,41.32 196.04,41.32 195.08,42.27 188.86,42.27 188.36,42.77 188.06,42.77 187.72,42.43 180.95,42.43 180.56,42.83 176.16,42.83 175.74,43.25 173.01,43.25 172.86,43.39
  BOTTOM w0.081: UC1.AN22 157.97,55.29 v2(157.66,54.98)
  BOTTOM w0.102: v2(218.86,19.41) 218.69,19.58 217.36,19.58 216.9,19.13 JDIMM2.181
DDR_B_D53: length 95.1
  IN1 w0.076: 173.36,45.42 169.96,45.42 169.64,45.73 165.85,45.73 163.55,48.03 163.55,49.74 160.39,52.89 159.59,52.89 159.01,53.47 159.01,53.94 v2(158.64,54.31)
  IN1 w0.089: v2(221.03,17.88) 220.56,17.88 220.46,17.79 220.46,13.04 220.59,12.92 221.35,12.92 221.5,13.07 221.5,20.7 199.06,43.15 197.31,43.15 196.35,44.12 191.07,44.12 190.42,44.77 185.52,44.77 185.03,44.28 183.71,44.28 183.33,44.66 177.99,44.66 177.23,45.42 173.36,45.42
  BOTTOM w0.081: UC1.AP21 158.96,54.64 v2(158.64,54.31)
  BOTTOM w0.102: JDIMM2.193 220.5,17.8 220.59,17.88 v2(221.03,17.88)
DDR_B_D54: length 97.8
  IN1 w0.076: v2(158.61,56.92) 158.99,57.29 159.75,57.29 159.97,57.07 159.97,53.52 160.19,53.3 160.48,53.3 164,49.77 164,48.39 165.63,46.76 169.3,46.76 170.01,46.05 173.36,46.05
  IN1 w0.089: v2(220.52,9.61) 220.92,10.01 220.92,11.14 221.06,11.29 221.7,11.29 221.8,11.39 221.8,11.67 221.68,11.79 221.03,11.79 220.92,11.9 220.92,12.17 221.03,12.28 221.82,12.28 222.14,12.6 222.14,21.04 199.39,43.79 197.57,43.79 196.58,44.78 191.3,44.78 190.68,45.4 185.24,45.4 185.13,45.3 178.25,45.3 177.5,46.05 173.36,46.05
  BOTTOM w0.081: UC1.AK21 158.94,57.24 v2(158.61,56.92)
  BOTTOM w0.102: JDIMM2.192 220.2,9.3 v2(220.52,9.61)
DDR_B_D55: length 97.4
  IN1 w0.076: 173.36,42.61 171.01,42.61 169.98,43.64 163.01,43.64 162.16,44.49 162.16,48.81 161.68,49.29 160.4,49.29 157.67,52.03 156.96,52.03 156.29,52.7 156.29,55.18 157.31,56.21 157.31,56.54 v2(157.69,56.92)
  IN1 w0.089: 173.36,42.61 175.47,42.61 175.89,42.19 180.29,42.19 180.69,41.8 188.24,41.8 188.4,41.64 194.82,41.64 195.78,40.68 198.03,40.68 217.83,20.88 217.83,18.64 217.5,18.31 217.5,17.47 216.46,16.43 216.46,14.99 215.67,14.2 215.67,11.37 215.9,11.14 v2(216.86,11.14)
  BOTTOM w0.081: v2(157.69,56.92) 158.01,57.24 UC1.AK22
  BOTTOM w0.102: v2(216.86,11.14) 217.29,10.71 217.29,9.46 217.2,9.37 JDIMM2.182
DDR_B_D56: length 58.6
  IN4 w0.084: 163.06,45.71 163.06,48.61 161.94,49.73 161.55,49.73 161.15,50.14 161.15,50.77 159.23,52.68 159.23,54.61 v2(159.59,54.96)
  IN4 w0.089: v2(178.96,19.39) 178.96,19.12 178.85,19.01 178.44,19.01 178.34,19.12 178.34,20.96 171.75,27.55 171.75,28.28 171.63,28.4 170.9,28.4 170.76,28.54 170.76,28.75 170.91,28.89 171.58,28.89 171.73,29.04 171.73,29.24 171.58,29.39 170.91,29.39 170.76,29.53 170.76,29.74 170.91,29.88 171.58,29.88 171.73,30.03 171.73,30.23 171.58,30.38 170.91,30.38 170.76,30.52 170.76,30.73 170.91,30.87 171.58,30.87 171.73,31.02 171.73,31.22 171.58,31.37 170.91,31.37 170.76,31.51 170.76,31.72 170.91,31.86 171.58,31.86 171.73,32.01 171.73,32.21 171.58,32.36 170.91,32.36 170.76,32.5 170.76,32.71 170.91,32.85 171.58,32.85 171.73,33 171.73,33.2 171.58,33.35 170.91,33.35 170.76,33.49 170.76,33.7 170.91,33.84 171.26,33.84 171.42,34 171.42,34.21 171.29,34.34 170.91,34.34 170.76,34.48 170.76,38.01 163.06,45.71
  BOTTOM w0.081: UC1.AN20 159.92,55.29 v2(159.59,54.96)
  BOTTOM w0.102: v2(178.96,19.39) 178.34,18.77 178.34,18.53 177.3,17.49 JDIMM2.57
DDR_B_D57: length 58.2
  IN4 w0.089: v2(159.59,53.66) 159.59,52.76 163.31,49.05 163.31,46.81 163.31,46.81 163.31,45.91 171.08,38.14 171.08,37.74 171.18,37.65 171.57,37.65 171.79,37.44 171.79,37.25 171.69,37.15 171.19,37.15 171.08,37.05 171.08,36.76 171.18,36.66 171.97,36.66 172.06,36.56 172.06,36.25 171.97,36.16 171.19,36.16 171.08,36.06 171.08,35.78 171.19,35.67 171.92,35.67 172.06,35.52 172.06,35.32 171.92,35.17 171.19,35.17 171.08,35.06 171.08,34.77 171.18,34.68 171.96,34.68 172.06,34.57 172.06,34.24 172.01,34.18 171.87,34.18 171.76,34.07 171.76,33.79 171.87,33.68 172,33.68 172.06,33.62 172.06,27.68 179.4,20.35 179.4,15.74 179.23,15.57 178.5,15.57 178.34,15.73 178.34,17.75 178.45,17.86 v2(178.96,17.86)
  BOTTOM w0.081: v2(159.59,53.66) 159.92,53.99 UC1.AR20
  BOTTOM w0.102: JDIMM2.59 177.9,17.48 178.28,17.86 v2(178.96,17.86)
DDR_B_D58: length 59.9
  IN4 w0.089: v2(160.54,56.92) 160.97,56.49 160.97,56.11 161.38,55.71 161.38,52.51 164.5,49.39 164.5,47.94 174.95,37.49 174.95,36.81 175.1,36.66 175.49,36.66 175.64,36.52 175.64,36.31 175.49,36.17 175.1,36.17 174.95,36.02 174.95,35.81 175.1,35.67 175.49,35.67 175.64,35.52 175.64,35.32 175.49,35.17 175.1,35.17 174.95,35.03 174.95,34.82 175.1,34.68 175.49,34.68 175.64,34.53 175.64,34.33 175.49,34.18 175.1,34.18 174.95,34.04 174.95,33.83 175.1,33.69 175.49,33.69 175.64,33.54 175.64,33.34 175.49,33.19 175.1,33.19 174.95,33.05 174.95,32.84 175.1,32.7 175.49,32.7 175.64,32.55 175.64,32.35 175.49,32.2 175.1,32.2 174.95,32.06 174.95,31.85 175.1,31.71 175.49,31.71 175.64,31.56 175.64,31.36 175.49,31.21 175.1,31.21 174.95,31.07 174.95,30.86 175.1,30.72 175.49,30.72 175.64,30.57 175.64,30.37 175.49,30.22 175.1,30.22 174.95,30.08 174.95,29.87 175.1,29.73 175.49,29.73 175.64,29.58 175.64,29.38 175.49,29.23 175.1,29.23 174.95,29.09 174.95,28.88 175.1,28.74 175.49,28.74 175.64,28.59 175.64,28.39 175.49,28.24 175.1,28.24 174.95,28.1 174.95,27.84 182.2,20.59 182.2,18.59 v2(181.47,17.86)
  BOTTOM w0.081: UC1.AK18 160.87,57.24 v2(160.54,56.92)
  BOTTOM w0.102: JDIMM2.69 180.9,17.44 181.32,17.86 v2(181.47,17.86)
DDR_B_D59: length 59.1
  IN4 w0.089: v2(160.54,56.27) 161.17,55.64 161.17,52.47 164.3,49.34 164.3,47.68 174.63,37.34 174.63,36.35 174.43,36.15 174.43,35.66 174.63,35.46 174.63,35.09 174.55,35 173.98,35 173.9,34.92 173.9,34.6 173.99,34.51 174.52,34.51 174.63,34.39 174.63,34.11 174.53,34.01 173.99,34.01 173.9,33.92 173.9,33.59 173.97,33.52 174.53,33.52 174.63,33.41 174.63,33.12 174.53,33.02 173.97,33.02 173.9,32.94 173.9,32.61 173.99,32.52 174.55,32.52 174.63,32.44 174.63,32.13 174.53,32.03 174,32.03 173.9,31.93 173.9,31.61 173.97,31.53 174.55,31.53 174.63,31.45 174.63,31.15 174.52,31.04 174,31.04 173.9,30.94 173.9,30.63 173.99,30.54 174.53,30.54 174.63,30.44 174.63,30.14 174.55,30.05 173.99,30.05 173.9,29.96 173.9,29.64 173.99,29.55 174.55,29.55 174.63,29.46 174.63,29.16 174.53,29.06 173.99,29.06 173.9,28.97 173.9,28.65 173.99,28.56 174.53,28.56 174.63,28.46 174.63,28.19 174.47,28.03 174.47,27.87 181.88,20.46 181.88,19.53 181.74,19.39 v2(181.47,19.39)
  BOTTOM w0.081: UC1.AL18 160.87,56.59 v2(160.54,56.27)
  BOTTOM w0.102: v2(181.47,19.39) 180.3,18.22 JDIMM2.67
DDR_B_D60: length 60.5
  IN4 w0.084: 162.66,45.22 162.66,48.43 161.76,49.33 161.33,49.33 160.74,49.91 160.74,50.6 159.75,51.59 158.89,51.59 158.25,52.22 158.25,57.06 158.47,57.27 159.23,57.27 v2(159.59,56.92)
  IN4 w0.089: 162.66,45.22 170.13,37.75 170.13,28.27 177.71,20.7 177.71,13.28 177.53,13.1 177.53,11.28 v2(178.38,10.43)
  BOTTOM w0.081: v2(159.59,56.92) 159.92,57.24 UC1.AK20
  BOTTOM w0.102: v2(178.38,10.43) 177.6,9.66 JDIMM2.58
DDR_B_D61: length 59.5
  IN4 w0.084: 162.86,45.46 162.86,48.5 161.83,49.53 161.45,49.53 160.94,50.04 160.94,50.72 159.05,52.61 159.05,55.08 v2(159.59,55.62)
  IN4 w0.089: v2(178.38,11.96) 177.96,12.37 177.96,13.08 178.02,13.15 178.02,13.62 178.17,13.77 178.67,13.77 178.81,13.91 178.81,14.12 178.67,14.26 178.17,14.26 178.02,14.41 178.02,14.61 178.17,14.76 178.67,14.76 178.81,14.9 178.81,15.11 178.67,15.25 178.17,15.25 178.02,15.4 178.02,20.83 170.44,28.41 170.44,37.88 162.86,45.46
  BOTTOM w0.081: UC1.AM20 159.92,55.94 v2(159.59,55.62)
  BOTTOM w0.102: v2(178.38,11.96) 177,10.59 JDIMM2.56
DDR_B_D62: length 55.7
  IN4 w0.089: v2(181.15,10.43) 180.6,10.99 180.6,20.84 173.26,28.18 173.26,36.6 173.36,36.69 173.86,36.69 173.97,36.8 173.97,37.09 173.88,37.19 173.35,37.19 173.26,37.28 173.26,37.8 163.89,47.17 163.89,49.25 160.54,52.59 v2(160.54,53.66)
  BOTTOM w0.081: v2(160.54,53.66) 160.87,53.99 UC1.AR18
  BOTTOM w0.102: v2(181.15,10.43) 181.2,10.39 JDIMM2.70
DDR_B_D63: length 57.5
  IN4 w0.089: v2(160.54,54.31) 160.94,53.92 160.94,52.45 164.09,49.29 164.09,47.42 174.32,37.2 174.32,36.49 174.21,36.38 173.67,36.38 173.58,36.28 173.58,35.97 173.67,35.88 174.01,35.88 174.11,35.78 174.11,35.48 174.02,35.39 173.69,35.39 173.58,35.28 173.58,28.32 180.92,20.98 180.92,13.77 181.55,13.13 181.55,12.36 v2(181.15,11.96)
  BOTTOM w0.081: UC1.AP18 160.87,54.64 v2(160.54,54.31)
  BOTTOM w0.102: v2(181.15,11.96) 180.6,11.41 JDIMM2.68
DDR_B_DQS0: length 84.9
  IN1 w0.076: v2(152.46,49.06) 152.63,49.22 152.82,49.22 153.18,49.59 153.35,49.59 153.55,49.39 153.55,48.6 153.48,48.53 153.03,48.53 152.84,48.33 152.84,48.16 152.84,47.95 153.05,47.74 153.43,47.74 153.52,47.65 153.52,44.13 153.31,43.92 153.31,43.75 153.31,43.48 153.15,43.32 152.92,43.32 152.7,43.1 152.7,42.63 152.86,42.47 153.2,42.47 153.3,42.37 153.3,42.13 153.29,42.12 153.29,42.1
  IN1 w0.102: 153.29,42.1 153.29,41.97 152.97,41.65 152.97,40.95 153.16,40.76 153.21,40.76 153.29,40.68 153.29,40.22 153.17,40.11 153.17,39.81 158.56,34.42 163.99,34.42 166.26,32.15 170.82,32.15 171.31,31.66 191.07,31.66 191.9,30.83 194.19,30.83 203.52,21.5 203.52,21.37 203.34,21.18 203.34,20.79 203.55,20.58 203.84,20.58 203.94,20.49 203.94,20.19 203.82,20.07 203.55,20.07 203.34,19.87 203.34,19.11 203.55,18.9 203.93,18.9 204.26,19.23 204.33,19.23 v2(204.54,19.03)
  BOTTOM w0.076: UC1.AV30 152.46,52.28 152.46,52.1 152.3,51.94 152.3,51.46 152.28,51.42 152.28,51.42 152.22,51.31 152.22,51.1 152.25,51.05 152.25,51.05 152.3,50.94 152.3,50.73 151.84,50.27 151.84,49.46 151.85,49.45 151.85,49.44 152.07,49.23 152.29,49.23 v2(152.46,49.06)
  BOTTOM w0.102: JDIMM2.137 203.7,17.54 203.51,17.73 203.51,18.17 203.21,18.48 203.21,19.33 203.35,19.47 203.86,19.47 204.05,19.28 204.29,19.28 v2(204.54,19.03)
DDR_B_DQS1: length 51.1
  IN4 w0.089: 154.87,42.52 154.87,42.54 154.88,42.55 154.88,45.94 155.61,46.67 155.94,46.67 156.05,46.78 v2(156.05,46.97)
  IN4 w0.102: v2(164.05,11.58) 164.05,11.81 163.89,11.96 163.61,11.96 163.24,12.33 163.24,20.82 154.87,29.19 154.87,42.52
  BOTTOM w0.076: UC1.AW26 154.9,51.64 154.9,51.43 154.87,51.37 154.87,51.37 154.83,51.29 154.82,51.27 154.82,51.14 154.85,51.08 154.87,51.03 154.87,51.03 154.9,50.98 154.9,50.56 154.53,50.19 154.53,49.82 154.98,49.36 154.98,46.99 155.35,46.62 155.7,46.62 v2(156.05,46.97)
  BOTTOM w0.102: JDIMM2.12 163.8,9.31 163.59,9.52 163.59,11.76 163.73,11.9 163.96,11.9 164.05,11.82 v2(164.05,11.58)
DDR_B_DQS2: length 92.6
  IN1 w0.076: 157.02,42.1 157.02,42.11 157.03,42.12 157.03,42.58 156.4,43.22 156.4,43.46 156.4,43.46 156.4,49.24 156.11,49.53 156.11,49.54 155.66,49.99 155.66,50.03 154.56,51.13 154.56,51.87 153.4,53.03 153.4,53.06 153.4,53.06 153.4,55.19 153.58,55.38 153.73,55.38 153.97,55.62 v2(153.98,55.62)
  IN1 w0.102: v2(207.95,11.52) 208.24,11.24 208.44,11.24 209.39,12.19 209.39,20.86 195.72,34.53 193.43,34.53 192.61,35.36 172.85,35.36 171.54,36.66 166.98,36.66 165.52,38.12 160.09,38.12 157.02,41.19 157.02,42.1
  BOTTOM w0.081: v2(153.98,55.62) 154.31,55.94 UC1.AM28
  BOTTOM w0.102: JDIMM2.154 208.8,9.25 208.62,9.44 208.62,9.82 209.05,10.26 209.05,11 208.75,11.3 208.17,11.3 v2(207.95,11.52)
DDR_B_DQS3: length 54.5
  IN4 w0.089: v2(155.89,55.62) 155.89,55.51 155.76,55.38 155.53,55.38 155.33,55.17 155.33,52.43 157.18,50.57 157.18,49.86 157.52,49.52 157.52,43.5 158.44,42.57 158.44,42.56 158.48,42.52
  IN4 w0.102: v2(169.01,19.01) 168.75,19.26 168.59,19.26 168.32,19.53 168.32,21.21 160.7,28.83 160.7,29.3 160.96,29.56 161.45,29.56 161.6,29.71 161.6,29.92 161.45,30.07 160.96,30.07 160.7,30.33 160.7,30.71 160.96,30.97 161.45,30.97 161.6,31.12 161.6,31.33 161.45,31.48 160.96,31.48 160.7,31.74 160.7,32.11 160.96,32.38 161.45,32.38 161.6,32.53 161.6,32.74 161.45,32.89 160.96,32.89 160.7,33.15 160.7,33.52 160.96,33.79 161.45,33.79 161.6,33.93 161.6,34.14 161.45,34.29 160.96,34.29 160.7,34.56 160.7,34.93 160.96,35.19 161.45,35.19 161.6,35.34 161.6,35.55 161.45,35.7 160.96,35.7 160.7,35.96 160.7,36.34 160.96,36.6 161.26,36.6 161.41,36.75 161.41,36.96 161.26,37.11 160.96,37.11 160.7,37.37 160.7,38.71 158.74,40.66 158.74,42.26 158.48,42.52
  BOTTOM w0.081: v2(155.89,55.62) 156.21,55.94 UC1.AM25
  BOTTOM w0.102: v2(169.01,19.01) 169.01,19.07 168.79,19.28 168.62,19.28 168.46,19.12 168.46,18.14 168.72,17.88 168.72,17.63 168.9,17.44 JDIMM2.29
DDR_B_DQS4: length 87.2
  IN1 w0.089: 160.08,43.38 159.73,43.73 159.44,43.73 159.09,44.08 159.09,45.38 159.03,45.44 158.94,45.44 158.8,45.57 158.8,46.29 158.93,46.42 159.07,46.42 159.13,46.49 159.13,46.93 159.02,47.05 158.64,47.05 158.44,47.25 158.44,47.72 158.62,47.9 159.04,47.9 159.11,47.97 159.11,49.74 158.91,49.94 158.35,49.94 158.23,49.81 158.23,49.68 158.66,49.25 158.66,48.62 158.48,48.44 158.25,48.44 v2(158.08,48.27)
  IN1 w0.102: 160.08,43.38 161.64,41.82 167.05,41.82 168.51,40.37 173.07,40.37 173.57,39.87 179.44,39.87 180.04,39.27 194.02,39.27 194.85,38.44 197.1,38.44 214.46,21.08 214.46,20.81 214.26,20.61 214.26,19.39 214.45,19.2 214.86,19.2 v2(215.03,19.03)
  BOTTOM w0.076: v2(158.08,48.27) 157.64,48.71 157.64,49.71 157.32,50.03 157.32,50.64 157.43,50.76 157.43,50.94 157.38,51.05 157.38,51.05 157.36,51.1 157.36,51.31 157.41,51.42 157.41,51.42 157.43,51.46 157.43,51.58 157.38,51.7 157.36,51.75 157.36,51.96 157.42,52.1 157.42,52.11 157.82,52.5 UC1.AV22
  BOTTOM w0.102: JDIMM2.171 213.9,17.43 213.7,17.64 213.7,19.32 213.83,19.46 214.37,19.46 214.58,19.26 214.8,19.26 v2(215.03,19.03)
DDR_B_DQS5: length 50.8
  IN4 w0.089: v2(161.79,46.5) 161.79,46.3 161.68,46.19 161.38,46.19 161.14,45.96 161.14,43.73 161.96,42.91 161.96,42.9 161.97,42.89
  IN4 w0.102: v2(174.99,19.01) 174.99,19.25 174.85,19.39 174.42,19.39 174.18,19.63 174.18,20.66 166.39,28.45 166.39,29.15 166.66,29.42 167,29.42 167.15,29.57 167.15,29.78 167,29.93 166.66,29.93 166.39,30.19 166.39,30.56 166.66,30.82 167,30.82 167.15,30.97 167.15,31.18 167,31.33 166.66,31.33 166.39,31.6 166.39,31.97 166.66,32.23 167,32.23 167.15,32.38 167.15,32.59 167,32.74 166.66,32.74 166.39,33 166.39,33.38 166.66,33.64 167,33.64 167.15,33.79 167.15,34 167,34.15 166.66,34.15 166.39,34.41 166.39,34.78 166.66,35.05 167,35.05 167.15,35.19 167.15,35.41 167,35.55 166.66,35.55 166.39,35.82 166.39,36.27 166.66,36.54 166.86,36.54 167.01,36.69 167.01,36.9 166.86,37.05 166.66,37.05 166.39,37.31 166.39,38.27 162.51,42.15 162.51,42.35 161.97,42.89
  BOTTOM w0.076: UC1.AW18 160.03,51.64 160.03,51.43 160.01,51.37 160,51.37 159.96,51.29 159.95,51.27 159.95,51.14 159.98,51.08 160,51.03 160.01,51.03 160.01,51.03 160.01,51.03 160.03,50.98 160.03,50.69 159.79,50.45 159.79,50.11 160.69,49.2 160.69,47.52 161.28,46.94 161.28,46.4 161.42,46.25 161.54,46.25 v2(161.79,46.5)
  BOTTOM w0.102: JDIMM2.47 174.3,17.48 174.13,17.65 174.13,18.99 174.5,19.37 174.93,19.37 174.99,19.31 v2(174.99,19.01)
DDR_B_DQS6: length 95.4
  IN1 w0.076: v2(158.62,55.69) 158.62,55.48 158.49,55.36 158.27,55.36 158.07,55.16 158.07,53.21 158.68,52.6 158.96,52.6 159.2,52.35 160.15,52.35 162.96,49.54 162.96,47.33 165.11,45.18 169.45,45.18 170.55,44.08 173.33,44.08 173.34,44.07 173.36,44.07
  IN1 w0.102: v2(219.25,10.76) 218.99,11.01 218.17,11.01 217.95,11.24 217.95,11.93 219.77,13.74 219.77,21 198.63,42.14 196.38,42.14 195.42,43.09 189.2,43.09 188.7,43.59 187.72,43.59 187.38,43.25 181.29,43.25 180.9,43.65 176.5,43.65 176.08,44.07 173.36,44.07
  BOTTOM w0.081: v2(158.62,55.69) 158.87,55.94 UC1.AM21
  BOTTOM w0.102: v2(219.25,10.76) 219.25,10.89 219.14,11 218.94,11 218.8,10.86 218.8,9.58 219,9.38 JDIMM2.188
DDR_B_DQS7: length 58
  IN4 w0.089: 166.66,43.41 166.55,43.53 166.55,43.53 165.16,44.91 165.16,45.21 164.64,45.73 163.48,46.89 163.48,49.13 159.99,52.63 159.99,55.18 160.18,55.37 160.3,55.37 v2(160.54,55.62)
  IN4 w0.102: v2(179.65,11.58) 179.44,11.78 179.28,11.78 179.04,12.01 179.04,13.35 179.9,14.21 179.9,20.55 172.57,27.89 172.57,37.51 166.66,43.41
  BOTTOM w0.081: UC1.AM18 160.87,55.94 v2(160.54,55.62)
  BOTTOM w0.102: v2(179.65,11.58) 179.44,11.79 179.24,11.79 179.13,11.68 179.13,9.49 179.4,9.21 JDIMM2.64
DDR_B_DQS#0: length 84.9
  IN1 w0.076: v2(152.46,49.71) 152.46,49.51 152.57,49.4 152.74,49.4 153.11,49.78 153.43,49.78 153.73,49.47 153.73,48.54 153.55,48.36 153.1,48.36 153.01,48.26 153.01,48.23 153.01,48.02 153.12,47.91 153.5,47.91 153.69,47.72 153.69,44.06 153.48,43.85 153.48,43.68 153.48,43.41 153.22,43.15 152.99,43.15 152.87,43.03 152.87,42.7 152.93,42.64 153.27,42.64 153.47,42.44 153.47,42.13 153.48,42.12 153.48,42.1
  IN1 w0.102: v2(204.54,19.79) 204.54,19.51 204.45,19.43 204.18,19.43 203.85,19.1 203.63,19.1 203.54,19.19 203.54,19.79 203.63,19.88 203.9,19.88 204.13,20.11 204.13,20.57 203.92,20.78 203.63,20.78 203.54,20.88 203.54,21.1 203.72,21.28 203.72,21.58 194.27,31.03 191.98,31.03 191.15,31.85 171.39,31.85 170.9,32.35 166.34,32.35 164.07,34.62 158.64,34.62 153.37,39.89 153.37,40.03 153.48,40.14 153.48,40.76 153.29,40.95 153.24,40.95 153.17,41.03 153.17,41.57 153.48,41.89 153.48,42.1
  BOTTOM w0.076: v2(152.46,49.71) 152.46,49.53 152.34,49.41 152.14,49.41 152.03,49.52 152.03,49.52 152.02,49.54 152.02,50.2 152.03,50.21 152.03,50.23 152.47,50.66 152.47,50.98 152.44,51.03 152.44,51.03 152.39,51.14 152.39,51.27 152.44,51.37 152.44,51.37 152.47,51.43 152.47,51.75 152.57,51.85 UC1.AW30
  BOTTOM w0.102: JDIMM2.135 203.1,17.52 203.31,17.73 203.31,18.09 203.01,18.39 203.01,19.41 203.27,19.67 203.94,19.67 204.13,19.48 204.23,19.48 v2(204.54,19.79)
DDR_B_DQS#1: length 51.2
  IN4 w0.089: v2(156.05,46.32) 155.88,46.49 155.69,46.49 155.06,45.86 155.06,42.54 155.07,42.54 155.07,42.52
  IN4 w0.102: v2(164.05,12.34) 163.86,12.16 163.69,12.16 163.44,12.41 163.44,20.9 155.07,29.27 155.07,42.52
  BOTTOM w0.076: v2(156.05,46.32) 155.91,46.46 155.29,46.46 154.82,46.92 154.82,49.29 154.36,49.75 154.36,50.26 154.73,50.63 154.73,50.94 154.68,51.05 154.68,51.05 154.66,51.1 154.66,51.31 154.71,51.42 154.71,51.42 154.73,51.46 154.73,51.94 154.89,52.1 154.89,52.28 UC1.AV26
  BOTTOM w0.102: JDIMM2.10 163.2,9.33 163.39,9.52 163.39,11.84 163.65,12.1 163.88,12.1 164.05,12.27 v2(164.05,12.34)
DDR_B_DQS#2: length 92.5
  IN1 w0.076: v2(153.98,54.96) 153.75,55.2 153.65,55.2 153.57,55.12 153.57,53.1 154.73,51.94 154.73,51.21 155.84,50.11 155.84,50.06 156.18,49.71 156.19,49.71 156.29,49.61 156.29,49.6 156.56,49.32 156.56,49.32 156.57,49.31 156.57,43.39 156.57,43.39 156.57,43.29 157.2,42.65 157.2,42.13 157.22,42.12 157.22,42.1
  IN1 w0.102: 157.22,42.1 157.22,41.27 160.17,38.32 165.6,38.32 167.06,36.86 171.62,36.86 172.93,35.56 192.69,35.56 193.51,34.73 195.8,34.73 209.59,20.94 209.59,12.11 208.52,11.04 208.24,11.04 v2(207.95,10.76)
  BOTTOM w0.081: v2(153.98,54.96) 154.31,55.29 UC1.AN28
  BOTTOM w0.102: v2(207.95,10.76) 207.95,10.98 208.07,11.1 208.67,11.1 208.85,10.91 208.85,10.34 208.42,9.9 208.42,9.44 208.2,9.23 JDIMM2.152
DDR_B_DQS#3: length 54.4
  IN4 w0.089: v2(155.89,54.96) 155.89,55.07 155.76,55.2 155.61,55.2 155.51,55.1 155.51,52.5 157.36,50.65 157.36,49.94 157.7,49.6 157.7,43.57 158.57,42.7 158.58,42.7 158.6,42.68
  IN4 w0.102: v2(169.01,19.77) 169.01,19.63 168.83,19.46 168.67,19.46 168.51,19.61 168.51,21.29 160.89,28.91 160.89,29.22 161.04,29.37 161.53,29.37 161.8,29.63 161.8,30 161.53,30.27 161.04,30.27 160.89,30.42 160.89,30.63 161.04,30.78 161.53,30.78 161.8,31.04 161.8,31.41 161.53,31.67 161.04,31.67 160.89,31.82 160.89,32.03 161.04,32.18 161.53,32.18 161.8,32.45 161.8,32.82 161.53,33.08 161.04,33.08 160.89,33.23 160.89,33.44 161.04,33.59 161.53,33.59 161.8,33.85 161.8,34.23 161.53,34.49 161.04,34.49 160.89,34.64 160.89,34.85 161.04,35 161.53,35 161.8,35.26 161.8,35.63 161.53,35.9 161.04,35.9 160.89,36.04 160.89,36.25 161.04,36.4 161.34,36.4 161.6,36.67 161.6,37.04 161.34,37.3 161.04,37.3 160.89,37.45 160.89,38.79 158.94,40.74 158.94,42.34 158.6,42.68
  BOTTOM w0.081: v2(155.89,54.96) 155.89,55.12 156.06,55.29 UC1.AN25
  BOTTOM w0.102: JDIMM2.27 168.3,17.47 168.52,17.68 168.52,17.8 168.26,18.05 168.26,19.2 168.54,19.48 168.79,19.48 169.01,19.69 v2(169.01,19.77)
DDR_B_DQS#4: length 87.2
  IN1 w0.089: 160.22,43.52 160.21,43.53 160.2,43.53 160.16,43.57 160.15,43.57 159.8,43.92 159.51,43.92 159.27,44.16 159.27,45.45 159.1,45.62 159.01,45.62 158.98,45.65 158.98,46.22 159.01,46.24 159.14,46.24 159.32,46.41 159.32,47.01 159.09,47.23 158.72,47.23 158.63,47.33 158.63,47.64 158.7,47.72 159.12,47.72 159.29,47.89 159.29,49.81 158.99,50.12 158.28,50.12 158.04,49.88 158.04,49.61 158.48,49.17 158.48,48.69 158.4,48.62 158.17,48.62 158.08,48.71 v2(158.08,48.92)
  IN1 w0.102: 160.22,43.52 161.72,42.02 167.14,42.02 168.6,40.56 173.16,40.56 173.65,40.07 179.52,40.07 180.12,39.46 194.1,39.46 194.93,38.63 197.18,38.63 214.65,21.16 214.65,20.73 214.45,20.53 214.45,19.47 214.53,19.39 214.86,19.39 215.03,19.57 v2(215.03,19.79)
  BOTTOM w0.076: UC1.AW22 157.82,51.98 157.74,52.06 157.6,52.06 157.57,52.02 157.52,51.92 157.52,51.79 157.57,51.68 157.6,51.62 157.6,51.43 157.57,51.37 157.57,51.37 157.53,51.29 157.52,51.27 157.52,51.14 157.55,51.08 157.57,51.03 157.57,51.03 157.6,50.98 157.6,50.69 157.48,50.57 157.48,50.1 157.8,49.77 157.8,49.02 157.91,48.92 v2(158.08,48.92)
  BOTTOM w0.102: v2(215.03,19.79) 215.03,19.55 214.94,19.46 214.66,19.46 214.46,19.66 213.75,19.66 213.5,19.41 213.5,17.67 213.3,17.48 JDIMM2.169
DDR_B_DQS#5: length 50.9
  IN4 w0.089: 162.11,43.03 162.1,43.04 162.09,43.04 161.33,43.81 161.33,45.88 161.46,46.01 161.62,46.01 v2(161.79,45.85)
  IN4 w0.102: 162.11,43.03 162.71,42.43 162.71,42.23 166.59,38.35 166.59,37.39 166.74,37.24 166.94,37.24 167.21,36.98 167.21,36.6 166.94,36.34 166.74,36.34 166.59,36.19 166.59,35.9 166.74,35.75 167.08,35.75 167.35,35.49 167.35,35.11 167.08,34.85 166.74,34.85 166.59,34.7 166.59,34.49 166.74,34.34 167.08,34.34 167.35,34.08 167.35,33.71 167.08,33.44 166.74,33.44 166.59,33.29 166.59,33.08 166.74,32.94 167.08,32.94 167.35,32.67 167.35,32.3 167.08,32.04 166.74,32.04 166.59,31.89 166.59,31.68 166.74,31.53 167.08,31.53 167.35,31.26 167.35,30.89 167.08,30.63 166.74,30.63 166.59,30.48 166.59,30.27 166.74,30.12 167.08,30.12 167.35,29.86 167.35,29.49 167.08,29.22 166.74,29.22 166.59,29.07 166.59,28.53 174.38,20.74 174.38,19.71 174.51,19.58 174.8,19.58 v2(174.99,19.77)
  BOTTOM w0.076: UC1.AV18 160.02,52.28 160.02,52.04 159.86,51.88 159.86,51.46 159.84,51.42 159.84,51.42 159.79,51.31 159.79,51.1 159.85,50.96 159.86,50.96 159.86,50.94 159.86,50.76 159.62,50.51 159.62,50.04 160.53,49.13 160.53,47.44 161.1,46.87 161.1,46.33 161.35,46.08 161.56,46.08 v2(161.79,45.85)
  BOTTOM w0.102: JDIMM2.45 173.7,17.46 173.93,17.68 173.93,19.08 174.42,19.57 174.79,19.57 v2(174.99,19.77)
DDR_B_DQS#6: length 95.4
  IN1 w0.076: v2(158.64,54.93) 158.64,55.06 158.51,55.19 158.34,55.19 158.24,55.09 158.24,53.28 158.75,52.77 159.03,52.77 159.27,52.52 160.23,52.52 163.15,49.6 163.15,47.4 165.08,45.47 165.2,45.35 169.52,45.35 170.62,44.25 173.33,44.25 173.34,44.26 173.36,44.26
  IN1 w0.102: 173.36,44.26 176.16,44.26 176.58,43.84 180.98,43.84 181.37,43.45 187.3,43.45 187.64,43.79 188.78,43.79 189.28,43.29 195.5,43.29 196.46,42.33 198.72,42.33 219.96,21.09 219.96,13.66 218.14,11.85 218.14,11.32 218.25,11.21 219.17,11.21 219.25,11.29 v2(219.25,11.52)
  BOTTOM w0.081: UC1.AN21 159,55.29 v2(158.64,54.93)
  BOTTOM w0.102: v2(219.25,11.52) 219.25,11.29 219.16,11.2 218.86,11.2 218.6,10.95 218.6,9.58 218.4,9.38 JDIMM2.186
DDR_B_DQS#7: length 58.1
  IN4 w0.089: 166.7,43.65 166.68,43.66 166.67,43.66 165.35,44.99 165.35,45.28 163.67,46.96 163.67,49.21 160.17,52.7 160.17,55.1 160.26,55.19 160.32,55.19 v2(160.54,54.96)
  IN4 w0.102: 166.7,43.65 166.8,43.55 168.11,42.24 168.11,42.24 172.76,37.59 172.76,27.98 180.1,20.63 180.1,14.13 179.24,13.27 179.24,12.1 179.36,11.98 179.55,11.98 179.65,12.07 v2(179.65,12.34)
  BOTTOM w0.081: UC1.AN18 160.87,55.29 v2(160.54,54.96)
  BOTTOM w0.102: JDIMM2.62 178.8,9.36 178.93,9.49 178.93,11.76 179.15,11.99 179.52,11.99 179.65,12.11 v2(179.65,12.34)
DDR_B_MA0: length 86.3
  IN1 w0.076: v2(146.26,54.31) 145.82,54.31 145.56,54.05 145.21,54.05 144.75,53.59 144.75,49.48 144.52,49.25 144.52,42.1
  IN1 w0.145: v2(192.45,11.19) 192.87,11.61 192.87,11.64 192.87,11.64 192.87,13.66 192.15,14.39 192.15,14.43 189.98,16.59 189.98,21.44 189.26,22.16 182.89,22.16 182.3,22.75 157.71,22.75 144.52,35.93 144.52,42.1
  BOTTOM w0.081: UC1.AP40 146.59,54.64 v2(146.26,54.31)
  BOTTOM w0.168: JDIMM2.98 192,10.75 v2(192.45,11.19)
DDR_B_MA1: length 86
  IN1 w0.089: 145.34,42.1 145.34,43.33 145.59,43.58 145.59,45.8 145.21,46.18 145.21,52.74 146.13,53.66 v2(146.26,53.66)
  IN1 w0.145: 145.34,42.1 145.34,36.28 158.07,23.55 158.65,23.55 158.82,23.72 158.82,23.91 158.95,24.04 159.28,24.04 159.4,23.91 159.4,23.67 159.53,23.55 159.85,23.55 159.98,23.67 159.98,23.91 160.11,24.04 160.43,24.04 160.56,23.91 160.56,23.67 160.69,23.55 161.01,23.55 161.14,23.67 161.14,23.91 161.27,24.04 161.59,24.04 161.72,23.91 161.72,23.67 161.85,23.55 162.17,23.55 162.3,23.67 162.3,23.91 162.42,24.04 162.75,24.04 162.88,23.91 162.88,23.67 163,23.55 163.33,23.55 163.46,23.67 163.46,23.91 163.58,24.04 163.91,24.04 164.03,23.91 164.03,23.67 164.16,23.55 164.49,23.55 164.61,23.67 164.61,23.91 164.74,24.04 165.07,24.04 165.19,23.91 165.19,23.67 165.32,23.55 165.65,23.55 165.77,23.67 165.77,23.91 165.9,24.04 166.22,24.04 166.35,23.91 166.35,23.67 166.48,23.55 166.8,23.55 166.93,23.67 166.93,23.91 167.06,24.04 167.38,24.04 167.51,23.91 167.51,23.67 167.64,23.55 167.96,23.55 168.09,23.67 168.09,23.91 168.22,24.04 168.54,24.04 168.67,23.91 168.67,23.67 168.79,23.55 169.12,23.55 169.25,23.67 169.25,23.91 169.37,24.04 169.7,24.04 169.83,23.91 169.83,23.67 169.95,23.55 170.28,23.55 170.41,23.67 170.41,23.91 170.53,24.04 170.86,24.04 170.98,23.91 170.98,23.67 171.11,23.55 171.44,23.55 171.56,23.67 171.56,23.91 171.69,24.04 172.02,24.04 172.14,23.91 172.14,23.67 172.27,23.55 172.59,23.55 172.72,23.67 172.72,23.91 172.85,24.04 173.17,24.04 173.3,23.91 173.3,23.67 173.43,23.55 182.63,23.55 183.22,22.95 189.92,22.95 190.78,22.1 190.78,19.8 190.87,19.71 191.05,19.71 191.36,20.01 v2(191.36,20.17)
  BOTTOM w0.081: v2(146.26,53.66) 146.59,53.99 UC1.AR40
  BOTTOM w0.168: JDIMM2.97 191.7,17.57 191.83,17.7 191.83,19.69 v2(191.36,20.17)
DDR_B_MA2: length 89
  IN1 w0.076: 144.12,42.1 144.12,42.9 144.28,43.06 144.28,49.52 144.47,49.71 144.47,52.99 143.89,53.56 143.89,54.67 144.02,54.8 145.02,54.8 v2(145.36,54.46)
  IN1 w0.145: 144.12,42.1 144.12,35.74 157.51,22.35 182.13,22.35 182.73,21.76 189.1,21.76 189.58,21.27 189.58,16.43 190.7,15.3 190.7,14.16 191.66,13.2 191.66,12.19 191.77,12.08 191.97,12.08 192.45,12.56 v2(192.45,12.72)
  BOTTOM w0.081: UC1.AP42 145.55,54.64 v2(145.36,54.46)
  BOTTOM w0.168: v2(192.45,12.72) 191.4,11.67 JDIMM2.96
DDR_B_MA3: length 87.5
  IN1 w0.089: v2(145.35,53.67) 144.98,53.3 144.98,46.06 145.37,45.67 145.37,43.73 144.94,43.3 144.94,42.1
  IN1 w0.145: 144.94,42.1 144.94,36.11 157.9,23.15 182.46,23.15 183.06,22.56 189.76,22.56 190.38,21.94 190.38,19.42 190.51,19.3 190.88,19.3 190.99,19.19 190.99,18.9 190.8,18.72 190.51,18.72 190.38,18.59 190.38,18.24 190.48,18.14 190.81,18.14 190.93,18.02 190.93,17.69 190.8,17.56 190.5,17.56 190.38,17.43 190.38,16.76 190.59,16.55 190.74,16.55 191.36,17.17 191.52,17.17 191.67,17.03 191.67,16.66 191.16,16.15 191.16,15.98 191.91,15.23 192.15,15.23 192.26,15.34 192.26,17.74 v2(191.36,18.64)
  BOTTOM w0.081: UC1.AR42 145.52,53.67 v2(145.35,53.67)
  BOTTOM w0.168: JDIMM2.95 191.1,17.47 190.89,17.69 190.89,18.18 v2(191.36,18.64)
DDR_B_MA4: length 93.2
  IN1 w0.076: v2(143.47,53.77) 143.47,50.24 144.04,49.66 144.04,43.37 143.72,43.05 143.72,42.1
  IN1 w0.145: v2(190.21,12.72) 189.65,13.28 189.65,15.79 189.18,16.26 189.18,21.11 188.93,21.36 188.49,21.36 188.32,21.19 188.32,20.42 188.22,20.31 187.85,20.31 187.75,20.42 187.75,21.2 187.59,21.36 187.31,21.36 187.17,21.22 187.17,20.48 187,20.31 186.76,20.31 186.59,20.48 186.59,21.19 186.42,21.36 186.18,21.36 186.01,21.19 186.01,20.44 185.88,20.31 185.54,20.31 185.43,20.42 185.43,21.25 185.32,21.36 184.97,21.36 184.85,21.24 184.85,20.43 184.74,20.31 184.38,20.31 184.27,20.42 184.27,21.24 184.15,21.36 183.82,21.36 183.69,21.24 183.69,20.42 183.59,20.31 183.24,20.31 183.11,20.44 183.11,21.19 182.94,21.36 182.56,21.36 181.97,21.95 157.35,21.95 143.72,35.58 143.72,42.1
  BOTTOM w0.081: UC1.AR45 143.69,53.99 v2(143.47,53.77)
  BOTTOM w0.168: JDIMM2.92 190.2,9.69 190.74,10.23 190.74,12.19 v2(190.21,12.72)
DDR_B_MA5: length 91.6
  IN1 w0.076: v2(143.49,54.4) 143.49,54.41 143.36,54.54 143,54.54 142.88,54.41 142.88,53.08 143,52.96 143.12,52.96 143.24,52.83 143.24,50.16 143.8,49.6 143.8,43.57 143.32,43.1 143.32,42.1
  IN1 w0.145: 143.32,42.1 143.32,35.41 157.18,21.55 170.82,21.55 171.1,21.27 171.1,18.29 171.22,18.17 171.86,18.17 171.99,18.3 171.99,21.28 172.26,21.55 177.04,21.55 177.22,21.37 177.22,18.33 177.38,18.17 177.96,18.17 178.13,18.34 178.13,21.44 178.24,21.55 179.53,21.55 179.65,21.44 179.65,20.75 179.76,20.64 180.13,20.64 180.23,20.74 180.23,21.35 180.43,21.55 181.8,21.55 182.7,20.66 182.7,20.04 182.82,19.91 188.5,19.91 v2(188.75,20.17)
  BOTTOM w0.081: v2(143.49,54.4) 143.73,54.64 UC1.AP45
  BOTTOM w0.168: JDIMM2.91 189.9,19.02 v2(188.75,20.17)
DDR_B_MA6: length 97.7
  IN1 w0.076: 142.53,42.1 142.53,43.16 143.23,43.87 143.23,49.59 142.66,50.16 142.33,50.16 142.11,50.37 142.11,51.16 142.24,51.28 142.36,51.28 v2(142.47,51.17)
  IN1 w0.145: v2(190.21,11.19) 189.25,12.15 189.25,15.62 188.78,16.1 188.78,17.25 188.32,17.71 188.32,18.67 187.87,19.12 183.82,19.12 182.93,18.23 182.21,18.23 181.9,18.54 181.9,20.33 181.47,20.76 181.18,20.76 181.04,20.62 181.04,17.77 180.64,17.37 176.09,17.37 175.96,17.5 175.96,18.01 175.84,18.14 175.51,18.14 175.38,18.01 175.38,17.5 175.26,17.37 174.18,17.37 174.05,17.5 174.05,20.55 173.92,20.68 173.37,20.68 173.24,20.55 173.24,17.52 173.1,17.37 168.71,17.37 168.58,17.5 168.58,20.63 168.45,20.76 156.82,20.76 142.53,35.05 142.53,42.1
  BOTTOM w0.081: UC1.AW46 142.83,51.53 v2(142.47,51.17)
  BOTTOM w0.168: v2(190.21,11.19) 189.6,10.58 JDIMM2.90
DDR_B_MA7: length 96.1
  IN1 w0.076: 141.67,42.1 141.67,42.7 142.96,43.99 142.96,49.33 v2(142.51,49.78)
  IN1 w0.145: v2(188.43,12.72) 188.86,13.14 188.86,15.46 188.38,15.93 188.38,17.08 187.93,17.54 187.93,18.45 187.66,18.72 183.98,18.72 183.1,17.83 182.05,17.83 181.19,16.97 168.31,16.97 168.18,17.1 168.18,17.69 168.05,17.82 167.57,17.82 167.45,17.69 167.45,17.12 167.32,16.99 166.71,16.99 166.58,17.12 166.58,20.14 166.37,20.36 165.22,20.36 164.97,20.1 164.97,17.63 164.77,17.42 164.31,17.42 163.89,17.84 163.89,20.17 163.76,20.29 162.98,20.29 162.85,20.17 162.85,17.84 162.44,17.42 162.11,17.42 161.85,17.69 161.85,20.12 161.61,20.36 156.21,20.36 141.67,34.89 141.67,42.1
  BOTTOM w0.081: UC1.AY46 142.89,50.15 v2(142.51,49.78)
  BOTTOM w0.168: JDIMM2.86 188.4,9.56 188.91,10.07 188.91,12.23 v2(188.43,12.72)
DDR_B_MA8: length 94.3
  IN1 w0.076: v2(142.48,50.53) 142.56,50.53 143.51,49.58 143.51,43.66 142.92,43.08 142.92,42.1
  IN1 w0.145: 142.92,42.1 142.92,35.21 156.98,21.15 170.52,21.15 170.7,20.97 170.7,17.93 170.86,17.77 172.16,17.77 172.39,18 172.39,21.02 172.53,21.15 176.66,21.15 176.82,20.99 176.82,17.97 177.02,17.77 178.32,17.77 178.53,17.98 178.53,21 178.69,21.15 179.13,21.15 179.25,21.04 179.25,20.49 179.38,20.35 179.38,19.74 179.53,19.59 179.97,19.59 180.09,19.47 180.09,19.12 179.99,19.02 179.53,19.02 179.38,18.87 179.38,17.94 179.55,17.77 180.48,17.77 180.64,17.94 180.64,20.98 180.82,21.15 181.64,21.15 182.3,20.49 182.3,18.71 182.37,18.63 182.77,18.63 182.88,18.74 182.88,19.38 183.01,19.51 188.04,19.51 188.75,18.8 v2(188.75,18.64)
  BOTTOM w0.081: v2(142.48,50.53) 142.13,50.88 UC1.AY47
  BOTTOM w0.168: v2(188.75,18.64) 189.02,18.64 189.3,18.36 JDIMM2.89
DDR_B_MA9: length 97.4
  IN1 w0.076: v2(142.53,48.1) 142.53,43.98 141.27,42.72 141.27,42.1
  IN1 w0.145: 141.27,42.1 141.27,34.73 156.04,19.96 160.15,19.96 160.29,19.81 160.29,17.17 160.43,17.03 160.72,17.03 160.87,17.17 160.87,19.81 161.01,19.96 161.31,19.96 161.45,19.82 161.45,17.28 161.7,17.03 162.95,17.03 163.07,17.14 163.07,17.49 163.25,17.67 163.49,17.67 163.72,17.45 163.72,17.18 163.87,17.03 165.13,17.03 165.37,17.26 165.37,19.8 165.52,19.96 166.05,19.96 166.19,19.82 166.19,16.79 166.4,16.58 181.35,16.58 182.21,17.44 184.14,17.44 184.29,17.58 184.29,18.21 184.39,18.32 184.75,18.32 184.87,18.2 184.87,17.58 185.01,17.44 185.73,17.44 185.89,17.59 185.89,18.16 186.05,18.32 187.33,18.32 187.53,18.12 187.53,17.37 187.98,16.92 187.98,14.39 188.13,14.24 v2(188.43,14.24)
  BOTTOM w0.081: v2(142.53,48.1) 141.91,48.72 141.91,50.27 141.59,50.59 141.59,52.01 141.67,52.09 141.67,52.9 141.89,53.12 142.18,53.12 142.31,52.99 142.78,52.99 UC1.AU46
  BOTTOM w0.168: JDIMM2.85 188.1,15.4 187.99,15.29 187.99,14.68 v2(188.43,14.24)
DDR_B_MA10: length 100.7
  IN1 w0.076: v2(148.69,57.07) 148.31,56.69 148.31,43.26 147.83,42.78 147.83,42.1
  IN1 w0.145: v2(195.72,20.17) 195.72,20.01 195.04,19.33 195.04,19.14 195.3,18.89 195.3,18.62 195.16,18.49 194.84,18.49 194.72,18.37 194.72,15.29 194.57,15.15 194.22,15.15 194.08,15.28 194.08,19.2 195.25,20.37 195.25,20.6 194.97,20.88 194.97,21.23 195.09,21.36 195.65,21.36 195.75,21.46 195.75,21.72 195.53,21.94 195.14,21.94 195.01,22.07 195.01,22.46 191.76,25.71 184.09,25.71 183.27,26.53 158.9,26.53 158.76,26.67 158.76,26.77 158.79,26.8 158.79,26.94 158.54,27.19 158.39,27.19 158.25,27.05 158.08,27.05 157.81,27.32 157.81,27.46 157.95,27.6 157.95,27.78 157.72,28.01 157.54,28.01 157.42,27.89 157.24,27.89 157.01,28.12 157.01,28.3 157.13,28.42 157.13,28.6 156.9,28.83 156.72,28.83 156.6,28.71 156.42,28.71 156.19,28.94 156.19,29.12 156.31,29.24 156.31,29.42 156.08,29.65 155.9,29.65 155.78,29.53 155.6,29.53 155.37,29.76 155.37,29.94 155.49,30.06 155.49,30.24 155.26,30.47 155.08,30.47 154.96,30.35 154.78,30.35 154.55,30.58 154.55,30.76 154.67,30.88 154.67,31.06 154.44,31.29 154.26,31.29 154.14,31.17 153.96,31.17 153.73,31.4 153.73,31.58 153.85,31.7 153.85,31.88 153.62,32.11 153.44,32.11 153.32,31.99 153.14,31.99 152.91,32.22 152.91,32.4 153.03,32.52 153.03,32.7 152.8,32.93 152.62,32.93 152.5,32.81 152.32,32.81 152.09,33.04 152.09,33.22 152.21,33.34 152.21,33.52 151.98,33.75 151.8,33.75 151.68,33.63 151.5,33.63 151.27,33.86 151.27,34.04 151.39,34.16 151.39,34.34 151.16,34.57 150.98,34.57 150.86,34.45 150.68,34.45 150.45,34.68 150.45,34.86 150.57,34.98 150.57,35.16 150.34,35.39 150.16,35.39 150.04,35.26 149.86,35.26 149.63,35.5 149.63,35.67 149.75,35.8 149.75,35.98 149.52,36.21 149.34,36.21 149.22,36.08 149.04,36.08 148.81,36.31 148.81,36.49 148.93,36.62 148.93,36.79 148.7,37.02 148.52,37.02 148.39,36.89 148.23,36.89 147.94,37.19 147.94,37.36 148.05,37.48 148.05,37.62 147.83,37.84 147.83,42.1
  BOTTOM w0.081: UC1.AK36 148.86,57.24 v2(148.69,57.07)
  BOTTOM w0.168: JDIMM2.107 194.7,19.15 v2(195.72,20.17)
DDR_B_MA11: length 98.1
  IN1 w0.076: 140.87,42.1 140.87,42.74 142.25,44.12 142.25,47.51 142.14,47.62 142.14,48.26 v2(142.53,48.66)
  IN1 w0.145: v2(188.43,11.19) 187.59,12.03 187.59,16.75 187.13,17.21 187.13,17.74 186.95,17.92 186.41,17.92 186.29,17.8 186.29,17.19 186.14,17.04 182.38,17.04 181.52,16.18 165.41,16.18 164.95,16.63 160.09,16.63 159.89,16.83 159.89,19.46 159.79,19.56 159.45,19.56 159.31,19.42 159.31,16.78 159.16,16.63 158.92,16.63 158.73,16.81 158.73,19.39 158.56,19.56 157.85,19.56 157.66,19.37 157.66,18.3 157.52,18.16 157.28,18.16 157.08,18.36 157.08,19.37 156.89,19.56 155.88,19.56 153.55,21.89 153.31,21.89 152.61,21.19 152.37,21.19 152.2,21.36 152.2,21.6 152.9,22.3 152.9,22.54 152.73,22.71 152.49,22.71 151.79,22.01 151.55,22.01 151.38,22.18 151.38,22.42 152.08,23.12 152.08,23.36 140.87,34.56 140.87,42.1
  BOTTOM w0.081: UC1.AV47 141.76,51.88 141.76,50.69 142.08,50.37 142.08,49.11 v2(142.53,48.66)
  BOTTOM w0.168: JDIMM2.84 187.8,10.57 v2(188.43,11.19)
DDR_B_MA12: length 93.5
  IN1 w0.076: 140.47,42.1 140.47,42.77 141.97,44.27 141.97,47.43 141.91,47.49 141.91,52.19 142.34,52.63 v2(142.49,52.63)
  IN1 w0.145: 140.47,42.1 140.47,34.4 148.18,26.69 148.18,26.42 147.49,25.74 147.49,25.5 147.66,25.33 147.9,25.33 148.59,26.01 148.83,26.01 149,25.84 149,25.6 148.31,24.92 148.31,24.68 148.48,24.51 148.72,24.51 149.41,25.19 149.65,25.19 149.82,25.02 149.82,24.78 149.13,24.1 149.13,23.86 149.3,23.69 149.54,23.69 150.23,24.37 150.47,24.37 150.64,24.2 150.64,23.96 149.95,23.28 149.95,23.04 150.12,22.87 150.36,22.87 151.05,23.55 151.29,23.55 151.46,23.38 151.46,23.14 150.77,22.46 150.77,22.22 152.21,20.78 152.76,20.78 153.31,21.32 153.55,21.32 158.64,16.23 164.78,16.23 165.23,15.78 181.68,15.78 182.54,16.64 186.22,16.64 187.19,15.67 187.19,13.6 v2(186.3,12.72)
  BOTTOM w0.076: 142.44,52.63 142.21,52.63 UC1.AU47
  BOTTOM w0.081: 142.44,52.63 v2(142.49,52.63)
  BOTTOM w0.168: JDIMM2.83 187.5,13.92 v2(186.3,12.72)
DDR_B_MA13: length 101.5
  IN1 w0.076: 149.84,42.1 149.84,42.9 149.76,42.98 149.76,45.45 149.84,45.54 150.25,45.54 150.54,45.84 150.54,47.08 150.66,47.2 150.88,47.2 150.99,47.3 150.99,47.45 150.88,47.55 150.27,47.55 150.2,47.62 150.2,47.83 150.28,47.91 150.88,47.91 150.99,48.01 150.99,48.16 150.88,48.26 150.26,48.26 150.2,48.32 150.2,48.55 150.27,48.62 150.88,48.62 150.99,48.72 150.99,56.58 v2(150.59,56.98)
  IN1 w0.145: 149.84,42.1 149.84,38.71 157.26,31.29 162.54,31.29 164.3,29.54 164.3,29.21 164.4,29.11 164.88,29.11 164.96,29.02 169.52,29.02 170.01,28.53 189.77,28.53 190.6,27.7 192.89,27.7 198.88,21.71 198.88,20.37 198.11,19.6 198.11,18.22 197.9,18 197.9,17.88 198.66,17.12 198.66,16.28 199.62,15.31 199.62,14.85 199.9,14.57 200.03,14.57 200.13,14.67 200.13,16.04 199.98,16.18 199.54,16.18 199.26,16.46 199.26,16.61 199.39,16.74 199.96,16.74 200.13,16.91 200.13,17.64 200.03,17.73 199.76,17.73 199.59,17.56 199.59,17.41 199.46,17.28 199.3,17.28 198.65,17.93 198.65,19.36 199.31,20.01 v2(199.31,20.17)
  BOTTOM w0.081: UC1.AK33 150.85,57.24 v2(150.59,56.98)
  BOTTOM w0.168: v2(199.31,20.17) 199.03,20.45 198.46,20.45 198.3,20.29 JDIMM2.119
DDR_B_MA14: length 98.7
  IN1 w0.076: v2(142.45,53.8) 142.45,53.51 141.77,52.82 140.76,52.82 140.53,52.58 140.53,51.63 140.72,51.44 141.16,51.44 141.51,51.09 141.51,44.79 139.68,42.95 139.68,42.1
  IN1 w0.145: v2(186.3,11.19) 185.64,11.85 185.64,15.43 185.25,15.83 182.86,15.83 182.01,14.98 164.88,14.98 164.43,15.43 158.31,15.43 153.76,19.98 151.88,19.98 151.4,20.46 151.19,20.46 150.71,19.98 150.32,19.98 150.21,20.09 150.21,20.33 150.75,20.87 150.75,21.12 150.58,21.29 150.35,21.29 149.8,20.74 149.56,20.74 149.39,20.91 149.39,21.15 149.94,21.7 149.94,21.93 149.77,22.1 149.52,22.1 148.98,21.56 148.74,21.56 148.57,21.73 148.57,21.97 149.12,22.52 149.12,22.74 148.95,22.91 148.7,22.91 148.16,22.38 147.92,22.38 147.75,22.55 147.75,22.79 148.29,23.33 148.29,23.57 148.12,23.74 147.88,23.74 147.34,23.2 147.1,23.2 146.93,23.37 146.93,23.61 147.48,24.15 147.48,24.39 147.31,24.56 147.06,24.56 146.52,24.02 146.28,24.02 146.11,24.19 146.11,24.43 146.66,24.97 146.66,25.2 146.49,25.37 146.24,25.37 145.7,24.84 145.46,24.84 142.99,27.31 142.99,30.75 139.68,34.07 139.68,42.1
  BOTTOM w0.081: v2(142.45,53.8) 142.79,53.8 UC1.AR46
  BOTTOM w0.168: JDIMM2.80 186.6,9.73 186.88,10.01 186.88,10.62 v2(186.3,11.19)
DDR_B_MA15: length 99.4
  IN1 w0.076: v2(142.47,54.45) 142.08,54.06 142.08,53.42 141.66,53 140.7,53 140.35,52.65 140.35,51.56 140.65,51.26 141.09,51.26 141.31,51.05 141.31,45.03 139.28,42.99 139.28,42.1
  IN1 w0.145: v2(184.57,12.72) 185.25,13.39 185.25,15.07 184.88,15.43 183.03,15.43 182.18,14.58 164.72,14.58 164.27,15.03 158.15,15.03 153.6,19.58 150.15,19.58 147.83,21.91 147.59,21.91 147,21.32 146.83,21.32 146.59,21.55 146.59,21.73 147.18,22.31 147.18,22.55 147.01,22.72 146.77,22.72 146.19,22.14 146.01,22.14 145.78,22.37 145.78,22.55 146.36,23.13 146.36,23.37 146.19,23.54 145.95,23.54 145.37,22.96 145.19,22.96 144.96,23.19 144.96,23.37 145.54,23.95 145.54,24.19 145.37,24.36 145.13,24.36 144.55,23.78 144.37,23.78 144.14,24.01 144.14,24.19 144.72,24.77 144.72,25.01 144.55,25.18 144.31,25.18 143.73,24.6 143.55,24.6 143.32,24.83 143.32,25.01 143.9,25.59 143.9,25.83 143.73,26 143.49,26 143.01,25.52 142.76,25.52 142.59,25.69 142.59,25.92 143.08,26.41 143.08,26.65 142.59,27.14 142.59,30.59 139.28,33.9 139.28,42.1
  BOTTOM w0.081: UC1.AP46 142.79,54.45 v2(142.47,54.45)
  BOTTOM w0.168: v2(184.57,12.72) 185.86,11.43 185.86,9.58 186,9.44 JDIMM2.78
DDR_B_RAS#: length 101.2
  IN1 w0.076: 148.63,42.1 148.63,42.55 148.96,42.87 148.96,47.25 149.59,47.89 149.59,52.66 149.27,52.98 149.27,55.18 149.66,55.57 v2(149.66,55.62)
  IN1 w0.145: 148.63,42.1 148.63,38.23 159.53,27.33 183.6,27.33 184.42,26.5 192.1,26.5 196.55,22.05 196.55,21.33 196.86,21.03 196.86,20.31 196.55,20 196.55,19.52 196.86,19.22 196.86,18.4 196.55,18.09 196.55,17.69 196.79,17.45 197.76,17.45 198.26,16.96 198.26,16.43 198.05,16.22 198.05,15.67 198.16,15.56 198.4,15.56 198.51,15.67 198.7,15.67 199.22,15.14 199.22,14.68 199.5,14.41 199.5,13.72 199.15,13.37 197.82,13.37 197.34,13.85 197.34,14.04 197.25,14.14 196.84,14.14 196.76,14.06 196.76,13.73 196.46,13.43 196.46,11.03 196.73,10.76 198.69,10.76 198.85,10.6 198.85,10.22 198.73,10.1 196.49,10.1 195.55,11.04 v2(195.55,11.19)
  BOTTOM w0.081: UC1.AM35 149.99,55.94 v2(149.66,55.62)
  BOTTOM w0.168: v2(195.55,11.19) 196.01,10.73 196.01,10.24 195.6,9.83 JDIMM2.110
DDR_B_WE#: length 100.5
  IN1 w0.076: 149.03,42.1 149.03,42.34 149.22,42.53 149.22,47.23 149.78,47.78 149.78,53.26 150.05,53.53 150.05,56.52 149.65,56.92 v2(149.64,56.92)
  IN1 w0.145: v2(197.29,20.17) 197.29,20.36 197.46,20.54 197.93,20.54 198.08,20.69 198.08,21.39 197.8,21.67 197.65,21.67 197.34,21.36 197.09,21.36 196.95,21.5 196.95,21.74 197.24,22.03 197.24,22.22 196.88,22.58 196.58,22.58 196.29,22.87 196.3,22.91 196.3,23.17 196.05,23.42 195.99,23.42 195.75,23.42 195.48,23.69 195.48,23.99 195.23,24.24 195.17,24.24 194.93,24.24 194.66,24.51 194.66,24.54 194.66,24.81 194.41,25.06 194.35,25.06 194.11,25.06 193.84,25.33 193.84,25.36 193.84,25.63 193.59,25.87 193.53,25.87 193.29,25.87 193.02,26.15 193.02,26.18 193.02,26.45 192.77,26.69 192.71,26.69 192.47,26.69 192.26,26.9 190.27,26.9 190,27.18 189.79,27.18 189.51,26.9 189.17,26.9 189.07,27 189.07,27.61 188.95,27.73 188.61,27.73 188.49,27.61 188.49,27.01 188.38,26.9 188.03,26.9 187.91,27.02 187.91,27.61 187.8,27.73 187.46,27.73 187.34,27.61 187.34,27.01 187.23,26.9 186.86,26.9 186.76,27.01 186.76,27.6 186.63,27.73 186.29,27.73 186.17,27.61 186.17,26.99 186.08,26.9 185.71,26.9 185.6,27.01 185.6,27.61 185.47,27.73 185.15,27.73 185.02,27.6 185.02,27.03 184.89,26.9 184.59,26.9 184.44,27.05 184.44,27.6 184.31,27.73 169.38,27.73 169.28,27.83 169.28,28.13 169.19,28.22 168.8,28.22 168.7,28.13 168.7,27.82 168.61,27.73 168.2,27.73 168.12,27.81 168.12,28.14 168.04,28.22 167.64,28.22 167.54,28.13 167.54,27.85 167.43,27.73 167.07,27.73 166.96,27.84 166.96,28.1 166.86,28.21 166.47,28.21 166.39,28.12 166.39,27.84 166.27,27.73 165.92,27.73 165.81,27.84 165.81,28.12 165.7,28.22 165.34,28.22 165.23,28.11 165.23,27.83 165.13,27.73 164.76,27.73 164.65,27.84 164.65,28.15 164.49,28.31 164.18,28.31 164.07,28.19 164.07,27.85 163.95,27.73 163.56,27.73 163.49,27.8 163.49,28.75 163.4,28.84 163,28.84 162.91,28.75 162.91,27.82 162.82,27.73 162.41,27.73 162.33,27.81 162.33,28.74 162.23,28.84 161.86,28.84 161.75,28.74 161.75,27.83 161.65,27.73 161.27,27.73 161.17,27.82 161.17,28.73 161.06,28.84 160.7,28.84 160.59,28.74 160.59,27.82 160.51,27.73 159.69,27.73 149.03,38.39 149.03,42.1
  BOTTOM w0.081: UC1.AK35 149.97,57.24 v2(149.64,56.92)
  BOTTOM w0.168: JDIMM2.113 196.5,17.4 196.35,17.56 196.35,20.29 196.49,20.43 197.01,20.43 197.28,20.17 v2(197.29,20.17)
DDR_CKE0_DIMMA: length 73.4
  IN4 w0.089: v2(144.08,52.52) 144.82,51.78 144.82,48.22 139.28,42.68 139.28,42.1
  IN4 w0.145: v2(102.4,18.77) 102.4,18.57 102.27,18.44 102.05,18.44 101.93,18.57 101.93,21.23 102.24,21.54 102.24,21.95 101.93,22.26 101.93,23.83 108.91,30.82 128.11,30.82 128.37,31.08 128.5,31.08 128.74,30.84 128.99,30.84 129.14,30.99 129.14,31.19 128.94,31.39 128.94,31.62 129.13,31.81 129.31,31.81 129.68,31.43 129.84,31.43 130.07,31.66 130.07,31.84 129.7,32.21 129.7,32.41 129.91,32.62 130.11,32.62 130.48,32.25 130.65,32.25 130.88,32.48 130.88,32.66 130.52,33.03 130.52,33.23 130.73,33.44 130.93,33.44 131.29,33.07 131.47,33.07 131.7,33.3 131.7,33.48 131.34,33.84 131.34,34.05 131.54,34.25 131.75,34.25 132.11,33.89 132.29,33.89 132.5,34.09 132.5,34.28 132.12,34.66 132.12,34.83 139.28,41.99 139.28,42.1
  BOTTOM w0.081: UC1.AU43 144.39,52.83 v2(144.08,52.52)
  BOTTOM w0.168: JDIMM1.73 103,18.17 v2(102.4,18.77)
DDR_CKE1_DIMMA: length 73.9
  IN4 w0.089: v2(144.07,51.24) 144.45,50.87 144.45,48.23 138.88,42.66 138.88,42.15 138.83,42.1
  IN4 w0.145: 138.83,42.1 127.94,31.22 108.75,31.22 101.53,24 101.53,17.7 102.64,16.59 102.64,11.56 v2(103.83,10.38)
  BOTTOM w0.081: v2(144.07,51.24) 144.35,51.53 UC1.AW43
  BOTTOM w0.168: JDIMM1.74 103.3,9.85 v2(103.83,10.38)
DDR_CKE2_DIMMB: length 82.9
  IN1 w0.076: 138.53,42.1 138.53,42.73 141.04,45.23 141.04,49.34 140.53,49.85 140.53,50.18 v2(140.91,50.55)
  IN1 w0.145: v2(184.57,14.24) 184.27,14.24 184.15,14.11 184.15,13.25 184.02,13.12 183.72,13.12 183.59,13.25 183.59,14.52 183.47,14.65 183.17,14.65 183.04,14.52 183.04,13.25 182.92,13.12 182.62,13.12 182.49,13.25 182.49,13.8 182.36,13.93 158.33,13.93 153.33,18.93 149.6,18.93 147.86,20.67 146.55,20.67 141.94,25.28 141.94,30.12 138.53,33.53 138.53,42.1
  BOTTOM w0.081: UC1.AY49 141.23,50.88 v2(140.91,50.55)
  BOTTOM w0.168: v2(184.57,14.24) 184.13,14.68 184.13,15.19 184.5,15.56 JDIMM2.73
DDR_CKE3_DIMMB: length 83
  IN1 w0.076: v2(140.65,48.31) 140.65,45.27 138.14,42.75 138.14,42.1
  IN1 w0.145: v2(184.57,11.19) 183.6,11.19 182.09,12.7 182.09,13.4 181.97,13.53 158.16,13.53 153.16,18.53 149.43,18.53 147.69,20.27 146.39,20.27 141.54,25.12 141.54,29.95 138.14,33.36 138.14,42.1
  BOTTOM w0.081: UC1.AU50 140.38,52.49 140.19,52.3 140.19,52.13 140.17,51.86 140.11,51.8 140.06,51.7 140.03,51.63 140.03,51.43 140.05,51.37 140.1,51.27 140.1,51.14 140.03,50.98 140.03,50.16 140.65,49.53 v2(140.65,48.31)
  BOTTOM w0.168: JDIMM2.74 184.8,9.7 185.01,9.91 185.01,10.75 v2(184.57,11.19)
DDR_CS0_DIMMA#: length 75.1
  IN4 w0.089: v2(150.62,54.38) 151.4,54.38 152.08,53.7 152.08,52.17 153.17,51.08 153.17,43.67 151.92,42.42 151.92,42.1
  IN4 w0.145: 151.92,42.1 151.92,31.63 151.12,30.83 146.38,26.09 146.38,25.82 147.13,25.07 147.13,24.75 140.99,18.61 140.99,17.77 138.95,15.73 121.61,15.73 117.78,11.9 v2(117.06,11.9)
  BOTTOM w0.081: UC1.AP33 150.88,54.64 v2(150.62,54.38)
  BOTTOM w0.168: v2(117.06,11.9) 115.3,10.14 JDIMM1.114
DDR_CS1_DIMMA#: length 76.7
  IN4 w0.089: v2(151.57,53.69) 151.57,52.13 152.97,50.73 152.97,43.94 151.52,42.49 151.52,42.1
  IN4 w0.145: v2(117.06,13.42) 118.74,13.42 121.45,16.13 138.79,16.13 140.59,17.94 140.59,18.78 144.88,23.06 144.88,23.26 144.02,24.12 144.02,24.3 144.25,24.53 144.43,24.53 145.28,23.67 145.49,23.67 145.69,23.88 145.69,24.08 144.84,24.94 144.84,25.12 145.07,25.35 145.25,25.35 146.1,24.49 146.31,24.49 146.59,24.78 146.59,25.04 145.81,25.83 145.81,26.08 151.52,31.8 151.52,42.1
  BOTTOM w0.081: v2(151.57,53.69) 151.66,53.69 UC1.AR32
  BOTTOM w0.168: v2(117.06,13.42) 117.66,14.03 117.66,14.9 117.4,15.16 JDIMM1.121
DDR_CS2_DIMMB#: length 91.1
  IN1 w0.076: v2(151.58,55.63) 151.58,55.62 151.94,55.26 151.94,53.52 151.38,52.96 151.38,45.17 151.2,45 150.89,44.68
  IN1 w0.145: 150.89,44.68 150.89,39.15 157.69,32.34 163.13,32.34 165.4,30.07 169.96,30.07 170.45,29.58 190.21,29.58 191.04,28.75 193.33,28.75 200.78,21.3 200.78,14.08 199.42,12.72 v2(197.11,12.72)
  BOTTOM w0.081: UC1.AM32 151.9,55.94 v2(151.58,55.63)
  BOTTOM w0.168: v2(197.11,12.72) 196.63,12.24 196.63,11.05 196.8,10.88 JDIMM2.114
DDR_CS3_DIMMB#: length 89.1
  IN1 w0.076: v2(151.51,57.01) 151.51,56.66 151.18,56.33 151.18,46.98 151.11,46.91 150.8,46.91 150.73,46.85 150.73,46.47 150.81,46.39 151.11,46.39 151.18,46.33 151.18,46.09 151.13,46.04 150.8,46.04 150.73,45.97 150.73,45.66 150.8,45.59 151.11,45.59 151.2,45.51 151.2,45.23 151.14,45.17 150.08,45.17 149.98,45.08 149.98,43.33 150.01,43.3 150.01,43.12 150.11,43.01 150.55,43.01 150.66,42.91 150.66,42.76 150.55,42.66 150.11,42.66 150.04,42.58 150.04,42.38 150.14,42.28 150.38,42.28 150.49,42.16 150.49,42.1
  IN1 w0.145: v2(199.31,18.64) 199.31,18.48 199.4,18.39 200.27,18.39 200.38,18.49 200.38,18.85 200.26,18.97 199.84,18.97 199.73,19.07 199.73,19.43 199.85,19.55 200.28,19.55 200.38,19.65 200.38,20.05 200.29,20.14 200.14,20.14 199.93,20.34 199.93,20.63 200.04,20.74 200.3,20.74 200.38,20.82 200.38,21.13 200.17,21.35 199.67,21.35 199.53,21.48 199.53,21.98 193.16,28.35 190.87,28.35 190.04,29.18 170.28,29.18 169.79,29.67 165.23,29.67 162.96,31.95 157.53,31.95 150.49,38.98 150.49,42.1
  BOTTOM w0.081: v2(151.51,57.01) 151.75,57.24 UC1.AK32
  BOTTOM w0.168: v2(199.31,18.64) 199.31,18.82 199.13,18.99 198.96,18.99 198.84,18.87 198.84,17.53 198.9,17.46 JDIMM2.121
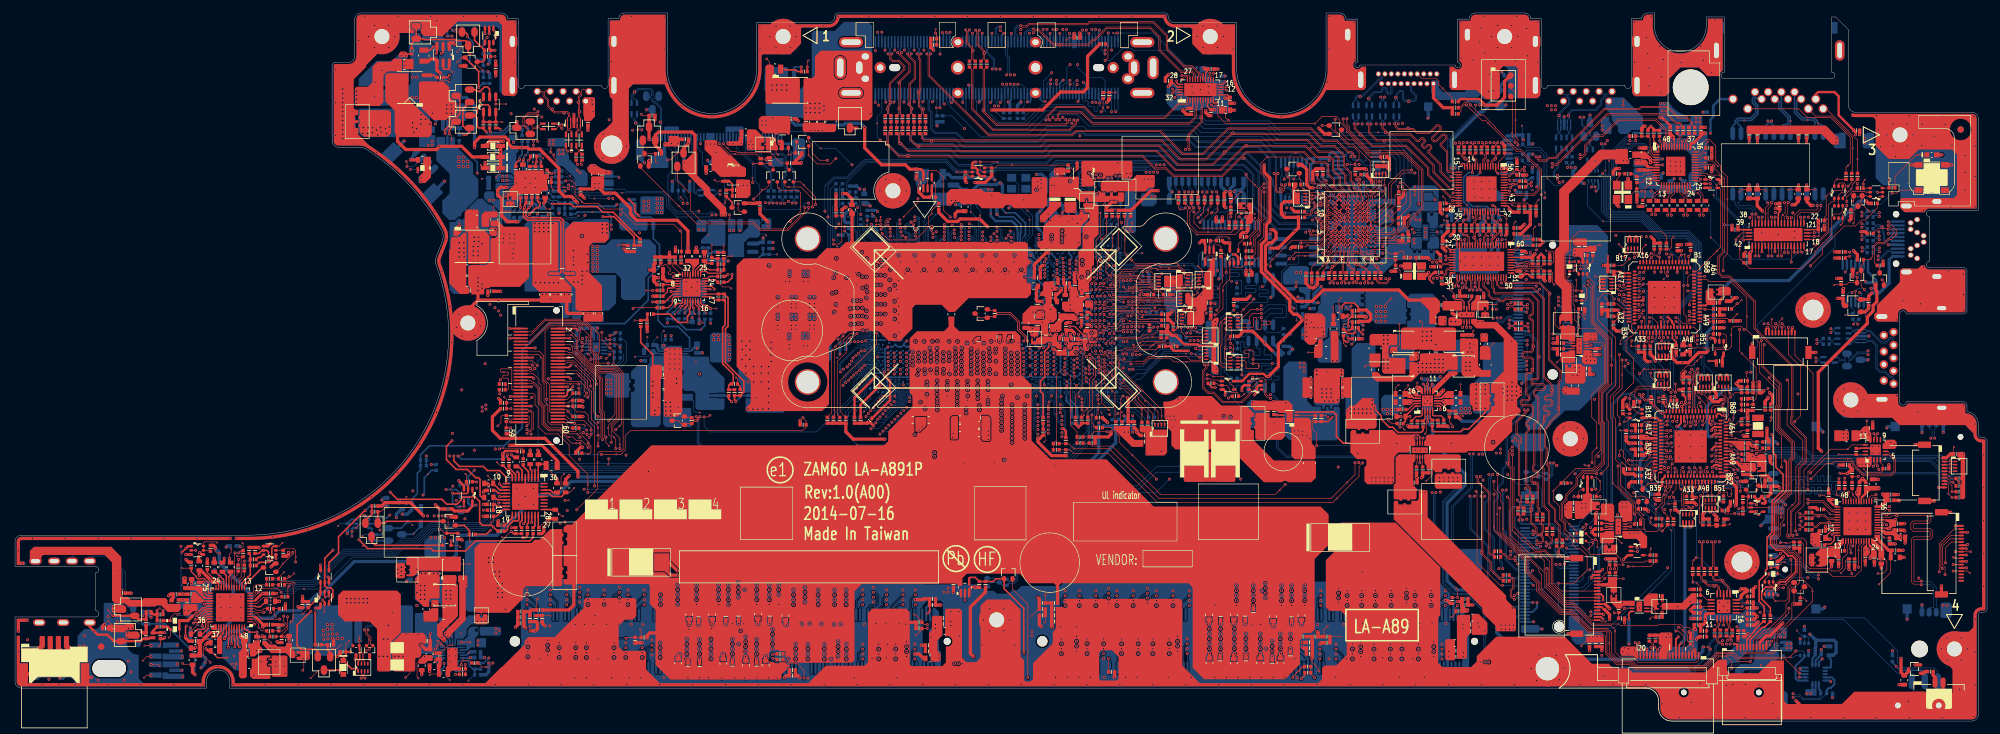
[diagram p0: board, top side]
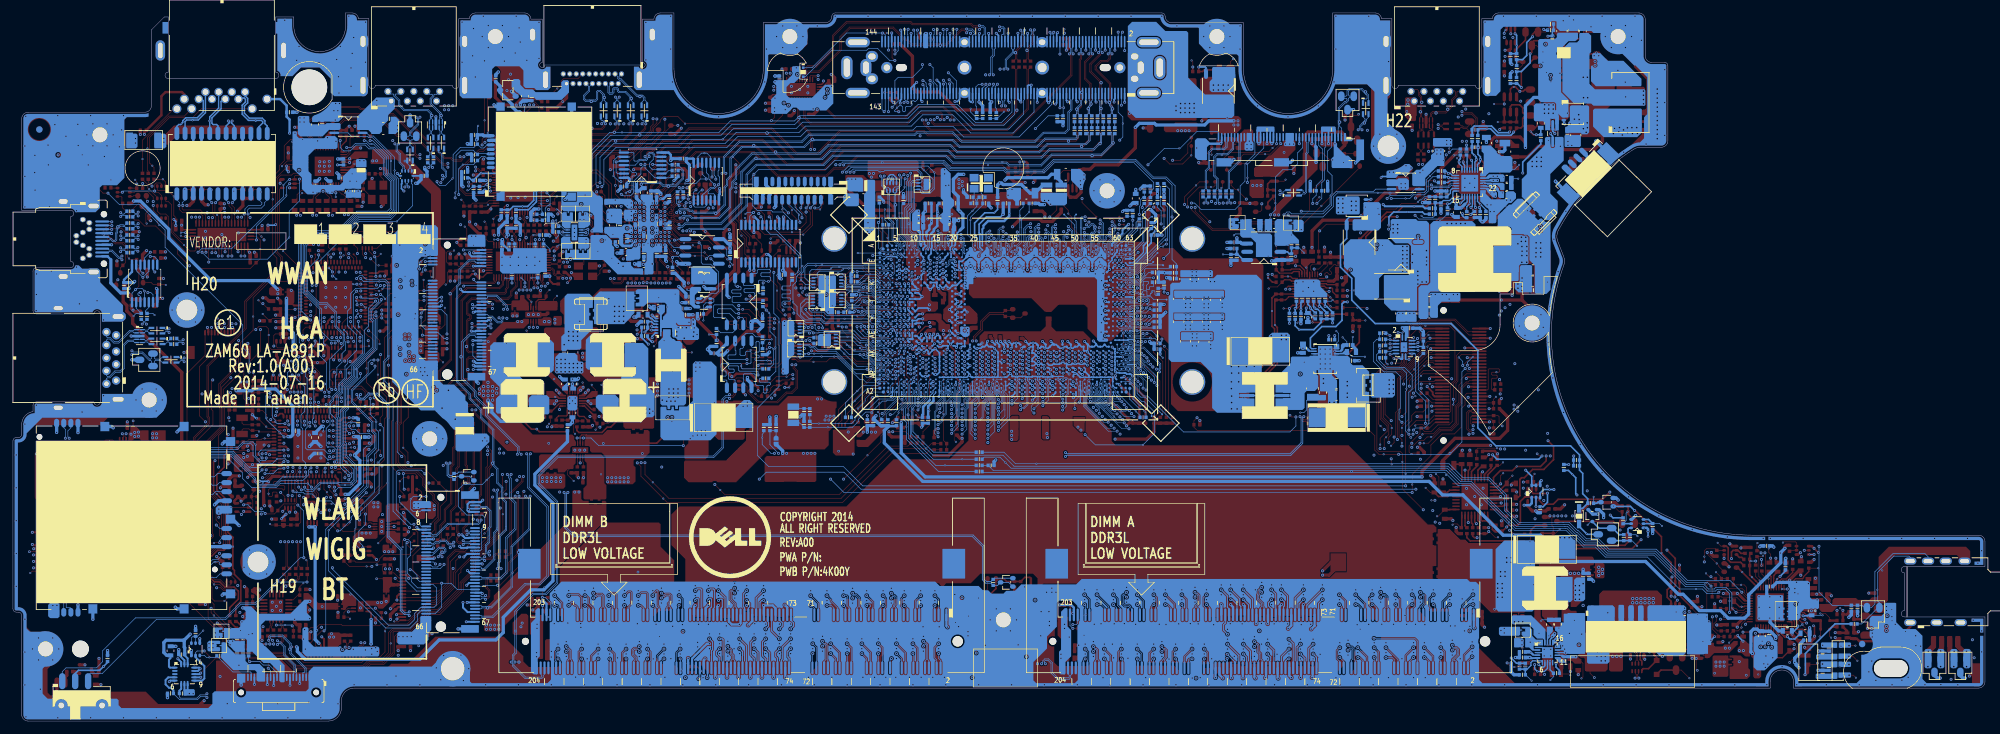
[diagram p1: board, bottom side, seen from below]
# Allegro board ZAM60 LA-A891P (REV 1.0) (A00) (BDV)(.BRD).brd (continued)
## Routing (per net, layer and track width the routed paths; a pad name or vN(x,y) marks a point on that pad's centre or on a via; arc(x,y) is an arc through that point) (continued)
DDR_PG_CTRL: length 53.3
  TOP w0.102: UD1.2 v2(146.8,18.71)
  IN3 w0.122: v2(146.8,18.71) 146.8,20.5 139.06,28.23 v2(139.06,44.3)
  BOTTOM w0.081: UC1.AV61 133.4,52.54 132.32,52.54 132.29,52.5 132.02,52.5 131.32,51.8
  BOTTOM w0.102: v2(139.06,44.3) 137.47,42.71 v1(130.11,42.71) 128.33,44.49 128.33,47.79 129.96,49.42 130.3,49.42 131.32,50.43 131.32,51.8
DDR_XDP_WAN_SMBCLK: length 355.6
  TOP w0.102: v2(79.12,45.07) 79.19,45 79.6,45 79.86,45.26 79.86,47.61 79.64,47.83 79.37,47.83 79.24,47.7 JXDP1.53 ; QC1.1 192.93,51.27 193.1,51.09 193.1,50.46 193.47,50.08 193.82,50.08 v2(194.01,49.89)
  IN1 w0.089: v2(274.78,3.64) 274.96,3.82 275.26,3.82 275.54,4.1 275.54,4.71 275.04,5.21 275.04,7.3 274.6,7.75 274.6,7.76 245.31,7.76 241.15,11.91 229.29,11.91 227.35,9.97 227.35,9.31 v2(227.16,9.13) 227.35,8.95 227.35,8.08 226.67,7.41 146.17,7.41 145.6,7.98 145.6,8.68 v2(145.79,8.86)
  IN4 w0.089: v2(145.79,8.86) 145.6,9.05 145.6,10.26 144.78,11.09 142.04,11.09 140.08,9.13 79.23,9.13 78.62,9.74 78.62,13.74 78.22,14.14 78.22,25.32 83.12,30.22 83.12,42.06 80.2,44.99 79.21,44.99 v2(79.12,45.07)
  BOTTOM w0.102: v2(194.01,49.89) 194.2,50.08 194.54,50.08 194.95,49.67 194.95,42.25 196.45,40.75 220.52,40.75 223.38,37.89 223.38,36.78 220.56,33.96 220.56,21.32 222.34,19.53 224.33,19.53 226.97,16.89 226.97,10.48 227.34,10.12 227.34,9.31 v2(227.16,9.13) 227.34,8.95 227.34,8.62 225.52,6.8 223.11,6.8 223.03,6.88 223.03,7.09 223.2,7.27 JDIMM2.202 ; JDIMM1.202 141.7,7.27 141.52,7.08 141.52,6.79 141.62,6.69 143.28,6.69 144.1,7.51 144.1,9.02 144.69,9.6 145.31,9.6 145.61,9.3 145.61,9.04 v2(145.79,8.86) ; RN4.2 278.99,3.31 276.24,3.31 275.73,3.82 274.95,3.82 v2(274.78,3.64)
  BOTTOM w0.305: UN1.4 280.74,6.76 281.16,6.34 281.16,5.68 280.63,5.14 280.32,5.14 279.96,4.77 RN4.2
DDR_XDP_WAN_SMBDAT: length 357.1
  TOP w0.102: QC1.4 191.53,52.57 192.02,53.06 192.91,53.06 193.33,52.64 193.33,50.55 193.57,50.31 193.85,50.31 v2(194.01,50.48) ; v2(79.12,44.49) 79.4,44.77 79.69,44.77 80.09,45.17 80.09,47.71 79.73,48.06 79.37,48.06 79.24,48.2 JXDP1.51
  IN1 w0.089: v2(274.78,4.22) 274.96,4.04 275.17,4.04 275.32,4.19 275.32,4.62 274.83,5.12 274.83,7.21 274.5,7.54 245.22,7.54 241.06,11.7 229.38,11.7 227.56,9.88 227.56,9.31 v2(227.75,9.13) 227.56,8.95 227.56,7.99 226.76,7.19 146.08,7.19 145.39,7.89 145.39,8.68 v2(145.2,8.86)
  IN4 w0.089: v2(79.12,44.49) 79.4,44.77 80.11,44.77 82.9,41.97 82.9,30.31 78,25.41 78,14.05 78.41,13.65 78.41,9.65 79.14,8.91 140.17,8.91 142.13,10.87 144.69,10.87 145.39,10.17 145.39,9.05 v2(145.2,8.86)
  BOTTOM w0.102: RN3.2 279.03,3.73 278.83,3.54 276.34,3.54 275.83,4.05 274.95,4.05 v2(274.78,4.22) ; JDIMM2.200 222.6,7.25 222.8,7.05 222.8,6.79 223.02,6.57 225.61,6.57 227.57,8.52 227.57,8.95 v2(227.75,9.13) 227.57,9.31 227.57,10.21 227.2,10.58 227.2,16.98 224.42,19.76 222.44,19.76 220.79,21.41 220.79,33.87 223.61,36.69 223.61,37.98 220.61,40.98 196.55,40.98 195.18,42.34 195.18,49.77 194.64,50.31 194.18,50.31 v2(194.01,50.48) ; v2(145.2,8.86) 145.38,9.04 145.38,9.21 145.22,9.37 144.78,9.37 144.33,8.93 144.33,7.42 143.37,6.46 141.52,6.46 141.29,6.7 141.29,7.08 141.1,7.27 JDIMM1.200
  BOTTOM w0.305: RN3.2 279.03,4.7 278.75,4.97 UN1.6
DEW1: length 3
  TOP w0.102: UN2.16 266.68,16.74 RN21.2 RN20.2
DEW2: length 4.1
  TOP w0.102: v1(259.88,21.32) 260.42,20.78 RN19.2 RN18.2 260.73,19.47 261.45,18.74 UN2.6
DGPU_PWROK: length 8.9
  BOTTOM w0.076: 173.36,66.31 173.34,66.29 172.84,66.29 v1(172.7,66.15) 172.67,66.12 172.08,66.12 171.29,65.33 171.03,65.33 170.95,65.25 170.55,65.25 170.37,65.07 169.65,65.07 169.59,65.13 169.2,65.13 UC1.P4
  BOTTOM w0.102: 173.36,66.31 173.37,66.31 173.38,66.32 174.11,66.32 174.19,66.39 175.52,66.39 176.02,65.88 RPC18.8
DH_1.35V: length 7.5
  TOP w1.016: 67.24,13.94 69.15,15.85 69.15,20.68
  vias: v1(69.78,21.08) v2(66.51,13.51) v2(66.87,13.05)
DIMM_DET: length 18.8
  TOP w0.102: RC303.1 RC302.2 185.34,64.63 v2(185.44,64.53)
  IN3 w0.122: v2(172.65,63.88) 172.72,63.95 175.36,63.95 175.72,64.31 180.32,64.31 180.57,64.56 185.41,64.56 v2(185.44,64.53)
  BOTTOM w0.076: UC1.U4 169.21,63.62 169.6,63.62 169.64,63.59 171,63.59 171.14,63.73 172.07,63.73 172.22,63.88 v2(172.65,63.88)
DIS_BAT_PROCHOT#: length 208.2
  TOP w0.102: UE1.B51 259.47,60.92 259.93,60.46 259.93,59.64 v2(260,59.56) ; v1(85.54,34.14) v2(85,34.14)
  TOP w0.254: PR812.1 71.29,37 v2(71.34,36.95)
  IN1 w0.089: v2(85,34.14) 83.8,35.34 77.15,35.34 76.26,36.23 74.48,36.23 73.76,36.95 v2(71.34,36.95)
  IN2 w0.122: v2(260,59.56) 259.5,59.05 259.5,58.55 259.16,58.21 259.02,58.21 255.78,54.97 251.35,54.97 247.41,51.04 242.3,51.04 235.71,44.44 235.71,39.28 231.9,35.47 231.9,34.71 230.88,33.7 228.88,33.7 228.53,33.35 86.9,33.35 86.11,34.14 v2(85,34.14)
DISP_ON: length 13.3
  TOP w0.102: v2(109.47,89.28) 109.47,89.24 v1(110.09,88.62) 110.61,88.1 111.45,88.1 111.63,87.92 116.74,87.92 118.39,86.27 RV2.1 119.36,85.49 DV2.1
  BOTTOM w0.102: JEDP1.22 109.46,89.3 v2(109.47,89.28)
DK_AC_OFF: length 17
  TOP w0.102: PD815.3 68.55,27.19 v1(68.82,26.92)
  TOP w0.254: PU800.25 v2(79.85,30.7) ; PD815.3 v2(67.37,27.91)
  IN1 w0.254: v2(67.37,27.91) 67.97,28.51 77.66,28.51 v2(79.85,30.7)
DK_AC_OFF_EN: length 2.2
  TOP w0.254: PR850.1 78.03,30.16 78.03,30.71 78.35,31.03 PU800.22
DK_CSS_GC: length 81.1
  TOP w0.102: v2(74.85,36.68) 74.85,37.94 v1(74.46,38.33)
  TOP w0.254: PR709.1 74.75,91.72 v2(74.99,91.48) ; v2(74.85,36.68) 75.32,36.22 PU800.11
  IN4 w0.254: v2(74.85,36.68) 76.65,36.68 78.3,38.34 78.3,41.91 76.03,44.18 76.03,50.86 76.58,51.41 76.58,57.09 79.45,59.96 83.01,59.96 86.03,62.98 86.4,62.98 91.59,68.17 91.59,73.95 90.19,75.35 90.19,79.9 84.81,85.28 83.67,85.28 81.28,87.67 81.28,89.85 80.63,90.5 75.97,90.5 v2(74.99,91.48)
DK_PWRBAR: length 5.4
  TOP w0.102: v1(86.43,36.05) 85.74,35.36 PR832.1
  TOP w0.254: PU800.33 82.55,35.22 83.04,34.72 84.45,34.72 PR832.1
DL_1.35V: length 0.5
  TOP w0.102: v2(65.83,11.95) v1(66.22,11.57)
  vias: v2(64.6,17.88) v2(65.21,17.88) v2(65.38,12.32)
DMIC0: length 124.8
  TOP w0.102: v2(103.25,80.05) 103.25,80.61 v1(102.85,81) ; UA1.47 35.06,13.99 v2(35.48,13.57)
  IN3 w0.122: v2(35.48,13.57) 36.39,13.57 38.13,15.31 39.52,15.31 41.08,16.87 43.55,16.87 52.51,25.82 56.84,25.82 58.42,27.41 69.15,27.41 75.86,34.12 75.86,35.68 77.18,36.99 79.13,36.99 81.21,39.08 81.21,53.5 83.18,55.47 89.21,55.47 90.99,57.25 92.39,57.25 93.47,58.33 93.47,62.97 95.5,65 95.5,69.95 103.38,77.83 103.38,79.92 v2(103.25,80.05)
  BOTTOM w0.102: JEDP1.7 101.96,88.72 102.05,88.62 102.05,83.68 102.49,83.24 102.49,82.91 CA6.1 102.49,80.81 v2(103.25,80.05)
DMIC1: length 264.7
  TOP w0.102: v2(232.24,89.09) 232.24,89.97 231.86,90.35 v1(231.86,92.9) 231.86,97.1 231.15,97.81 MIC1.5 ; v2(40.88,15.75) 38.26,15.75 37.44,16.57 UA1.4
  IN3 w0.122: v2(232.24,89.09) 231.97,88.82 226.48,88.82 226.29,88.63 208.96,88.63 208.82,88.49 205.71,88.49 204.95,87.73 177.6,87.73 168.49,96.84 165.96,96.84 165.08,97.71 159.82,97.71 158.67,98.86 156.91,98.86 154.4,96.36 153.49,96.36 153.02,95.88 153.02,94.97 150.97,92.92 146.4,92.92 144.28,90.8 133.15,90.8 132.55,90.21 129.67,90.21 127.39,87.93 124.65,87.93 120.93,84.2 109.59,84.2 104.24,78.85 104.24,75.84 102.42,74.02 101.41,74.02 96.39,69 96.39,63.47 94.36,61.44 94.36,57.7 92.45,55.79 91.5,55.79 89.81,54.1 82.95,54.1 82,53.15 82,51.83 82.74,51.09 82.74,47.73 82.04,47.03 82.04,38.65 81.78,38.39 81.78,34.52 79.88,32.61 75.5,32.61 69.53,26.64 58.99,26.64 57.42,25.08 53.01,25.08 43.84,15.91 42.54,15.91 42.26,15.63 40.99,15.63 v2(40.88,15.75)
DMIC_CLK0: length 120.6
  TOP w0.102: RA14.2 40.74,13.95 CA54.1 41.33,13.94 41.89,14.5 41.89,15.05 41.51,15.43 v2(41.51,16.23)
  IN3 w0.122: v2(103.88,80.05) 103.63,79.79 103.63,77.7 95.76,69.82 95.76,64.87 93.72,62.84 93.72,57.82 92.2,56.3 91.25,56.3 89.55,54.6 82.69,54.6 81.47,53.38 81.47,38.89 79.32,36.74 77.28,36.74 76.11,35.57 76.11,33.98 69.28,27.15 58.73,27.15 57.16,25.57 52.61,25.57 43.58,16.55 41.83,16.55 v2(41.51,16.23)
  BOTTOM w0.102: v2(103.88,80.05) 103.88,80.77 103.35,81.3 CA5.1 103.35,82.8 102.4,83.76 102.4,88.45 102.96,89.01 JEDP1.9
DMIC_CLK1: length 258.9
  TOP w0.102: v2(42.12,16.12) 42.12,14.22 41.21,13.31 CA30.1 41.2,13.06 RA40.2 ; v2(231.81,89.48) 231.81,89.9 231.38,90.33 v1(231.38,90.92) 231.38,96.35 MIC1.4
  IN3 w0.122: v2(231.81,89.48) 231.43,89.87 221.65,89.87 220.67,88.89 208.86,88.89 208.72,88.75 205.62,88.75 204.85,87.99 182.69,87.99 180.4,90.27 175.41,90.27 168.59,97.09 166.06,97.09 165.19,97.96 159.92,97.96 158.78,99.11 156.8,99.11 154.3,96.61 153.39,96.61 152.77,95.99 152.77,95.07 150.87,93.17 146.3,93.17 144.18,91.05 133.04,91.05 132.46,90.46 129.57,90.46 127.29,88.18 124.52,88.18 120.79,84.45 109.43,84.45 103.95,78.97 103.95,75.92 102.8,74.78 101.09,74.78 96.07,69.76 96.07,63.66 94.04,61.63 94.04,57.76 92.33,56.04 91.37,56.04 89.68,54.35 82.82,54.35 81.74,53.27 81.74,38.78 79.45,36.49 77.4,36.49 76.39,35.47 76.39,33.88 69.4,26.9 58.86,26.9 57.29,25.33 52.87,25.33 43.78,16.23 42.24,16.23 v2(42.12,16.12)
DMIC_CLK_L: length 4.7
  TOP w0.102: RA40.1 39.4,13.44 RA14.1 38.15,13.95 v1(37.63,14.47) 37.63,14.98 36.84,15.77 UA1.2
DOCK_AC_OFF: length 133.2
  TOP w0.102: v1(65.72,29.69) 66.37,29.04 PD815.1 66.72,30.06 66.93,30.26 66.93,31.41 v2(66.61,31.72)
  TOP w0.254: PR844.1 68.41,29.04 PD815.1
  IN3 w0.122: v2(132.95,103.68) 132.95,103.42 134.03,102.34 136.76,102.34 137.59,101.52 137.59,99.99 136.38,98.78 133.34,98.78 126.84,92.29 119.09,92.29 114.53,87.73 112.33,87.73 111.58,88.48 96.5,88.48 93.28,85.25 93.28,81.12 93.86,80.54 93.86,79.35 93.22,78.71 93.22,75.22 92.12,74.12 92.12,68.46 83.71,60.06 80.42,60.06 74.23,53.87 74.23,51.68 70.04,47.48 70.04,40.42 69.34,39.73 69.34,34.51 68.64,33.81 68.64,32.8 68.2,32.36 67.05,32.36 66.61,31.91 v2(66.61,31.72)
  BOTTOM w0.102: v2(132.95,103.68) JDOCK1.2
DOCK_AC_OFF_EC: length 217.5
  TOP w0.102: v2(261.11,68.76) UE1.A63 ; v1(75.26,28.42) 75.7,28.42 76.59,29.31 v2(76.69,29.31)
  TOP w0.254: PR850.2 PR858.1 77.01,28.99 v2(76.69,29.31)
  IN2 w0.122: v2(261.11,68.76) 261.11,68.17 260.4,67.46 260.4,65.02 262.22,63.2 262.22,60.7 261.6,60.08 261.6,58.55 261.02,57.96 259.12,57.96 255.88,54.72 251.45,54.72 247.52,50.79 242.41,50.79 235.96,44.35 235.96,37.25 232.16,33.45 229.03,33.45 228.67,33.1 86.8,33.1 86.17,33.72 81.11,33.72 76.71,29.31 v2(76.69,29.31)
DOCK_DCIN_IS+: length 116.2
  TOP w0.102: PQ703.6 72.39,96.05 72.2,95.86 v2(71.75,95.86)
  IN1 w0.089: v2(71.75,95.86) 73.14,95.86 73.62,95.38 73.62,93.98 79.74,87.86 81.34,87.86 85.42,83.77 90.2,83.77 90.78,83.2 96.25,83.2 97.69,84.64 102.2,84.64 103.05,85.48 126.71,85.48 131.47,90.25 137.2,90.25 145.78,98.83 147.14,98.83 149.65,101.33 154.93,101.33 157.06,99.2 158.46,99.2 160.11,100.85 164.55,100.85 165.83,102.13 166.86,102.13 168.07,103.34 168.26,103.34 v2(168.45,103.16)
  BOTTOM w0.102: JDOCK1.134 167.95,103.65 v2(168.45,103.16)
DOCK_DCIN_IS-: length 115
  TOP w0.102: PQ703.4 74.29,96.52 v2(74.29,95.41) v1(75.87,95.41)
  IN1 w0.089: v2(74.29,95.41) 73.92,95.41 73.84,95.33 73.84,94.07 79.83,88.07 81.43,88.07 85.51,83.98 90.29,83.98 90.87,83.41 96.16,83.41 97.6,84.85 102.11,84.85 102.96,85.7 126.62,85.7 131.38,90.46 137.11,90.46 145.69,99.04 147.05,99.04 149.56,101.54 155.02,101.54 157.15,99.42 158.37,99.42 160.02,101.07 164.46,101.07 165.74,102.35 166.77,102.35 167.98,103.56 168.27,103.56 v2(168.45,103.74)
  BOTTOM w0.102: JDOCK1.136 v2(168.45,103.74)
DOCK_DET#: length 317.1
  TOP w0.102: R272.1 168.89,104.36 168.89,102.58 v2(168.46,102.15) ; v2(252.59,62.4) 253,62.4 253.87,61.53 UE1.B41 ; PQ817.2 47.85,16.99 v1(47.72,16.87)
  TOP w0.254: v2(47.55,18.69) 47.85,18.39 PQ817.2
  IN1 w0.254: v2(47.55,18.69) 47.44,18.8 47.44,20.52 55.86,28.94 55.86,29.98 57.73,31.85 v2(57.91,31.85)
  IN3 w0.122: v2(57.91,31.85) 58.01,31.95 59.17,31.95 59.94,31.18 67.46,31.18 68.89,32.61 68.89,33.67 69.59,34.37 69.59,39.6 70.86,40.87 74.27,40.87 75.5,42.1 75.5,48.36 77.22,50.08 77.22,56.09 80.59,59.46 83.82,59.46 92.62,68.26 92.62,73.87 94.36,75.62 94.36,80.75 93.79,81.32 93.79,84.94 96.82,87.97 111.27,87.97 112.04,87.21 114.77,87.21 118.37,90.81 126.16,90.81 130.17,94.82 141.73,94.82 144.93,98.02 144.97,98.02 149.35,102.4 168.21,102.4 v2(168.46,102.15) 168.62,101.99 168.62,100.23 175.97,92.87 181.23,92.87 183.83,90.27 203.96,90.27 204.72,91.03 207.72,91.03 207.86,91.17 219.52,91.17 221.04,92.68 221.06,92.68 221.9,93.52 232.41,93.52 237.11,88.82 237.11,86.41 237.12,86.4 237.12,85.49 237.11,85.48 237.11,84.19 239.46,81.84 239.46,81.21 247.42,73.26 248.18,73.26 248.18,72.49 248.18,71.66 250.5,69.35 250.5,69.06 250.63,68.93 251.89,68.93 252.21,68.61 252.21,62.78 v2(252.59,62.4)
  BOTTOM w0.102: D19.2 182.29,99.64 178.2,103.73 172.81,103.73 172.55,103.99 171.1,103.99 169.26,102.15 v2(168.46,102.15)
  BOTTOM w0.254: v2(57.91,31.85) 57.49,31.43 PR853.1
DOCK_DET_R#: length 18.1
  TOP w0.102: v2(170.37,106.39) 170.37,106.39 v1(169.72,106.39)
  BOTTOM w0.102: v2(170.37,106.39) 175.91,106.39 181.26,101.04 D19.1 ; v2(170.37,106.39) 170.24,106.39 169.95,106.11 JDOCK1.142 ; v2(170.37,106.39) 170.45,106.31 JDOCK1.144
DOCK_HP_DET: length 254.8
  TOP w0.102: UE1.A7 v2(255.62,71.74) ; v2(43.37,24.61) v1(43.37,25.42) 43.37,26.33 43.05,26.64 41.68,26.64 RA29.2 41.44,26.4 QA3.2
  IN2 w0.122: v2(43.37,24.61) 43.63,24.88 49.19,24.88 50.78,26.47 57.37,26.47 62.41,31.51 62.41,31.98 62.91,32.48 67.63,32.48 68.51,31.6 68.51,31.04 69.1,30.45 73.15,30.45 74.42,31.72 78.42,31.72 79.12,32.42 79.12,33.25 80.44,34.57 86.03,34.57 86.99,33.6 228.41,33.6 228.79,33.98 230.76,33.98 231.58,34.8 231.58,35.53 235.46,39.41 235.46,44.54 242.2,51.28 247.31,51.28 252.59,56.56 255.95,56.56 256.78,57.39 256.78,58.66 256.19,59.24 256.19,63.08 255.98,63.3 255.98,68.34 256.27,68.63 256.27,71.09 v2(255.62,71.74)
DOCK_LOM_ACTLED_YEL#: length 149
  TOP w0.102: v1(278.8,75.06) 278.68,74.94 v2(278.04,74.94) 278,74.98 UL4.19
  IN3 w0.122: v2(159.48,106.96) 159.48,106.21 159.85,105.84 167.65,105.84 169.73,107.92 176.59,107.92 180,104.51 180,102.12 181.98,100.14 181.98,99.29 182.33,98.94 182.33,95.84 182.81,95.36 182.81,94.34 184.85,92.3 199.28,92.3 201.49,94.52 232.93,94.52 238.95,88.51 238.95,85.57 240.47,84.05 240.47,81.7 246.38,75.79 247.64,75.79 249.41,74.02 254.72,74.02 255.87,75.16 269.04,75.16 270.43,73.77 276.87,73.77 v2(278.04,74.94)
  BOTTOM w0.102: JDOCK1.100 159.45,106.94 v2(159.48,106.96)
DOCK_LOM_SPD10LED_GRN#: length 166.5
  TOP w0.102: UL4.40 266.9,75.48 v1(266.35,74.93) 265.95,74.52 v2(265.95,74.4)
  IN3 w0.122: v2(133.45,95.23) 136.51,98.28 142.57,98.28 143.76,99.48 146.05,99.48 149.22,102.65 168.98,102.65 172.5,106.18 175.87,106.18 177.6,104.45 177.6,99.42 177.48,99.3 177.48,95.56 179.91,93.13 181.35,93.13 183.96,90.53 203.86,90.53 204.69,91.35 207.69,91.35 207.75,91.42 219.39,91.42 221.75,93.77 232.54,93.77 238.19,88.12 238.19,85.19 239.71,83.67 239.71,81.32 247.52,73.51 255.9,73.51 256.73,74.33 265.88,74.33 v2(265.95,74.4)
  BOTTOM w0.102: JDOCK1.3 v2(133.45,95.23)
DOCK_LOM_SPD100LED_ORG#: length 179.4
  TOP w0.102: UL4.20 278.01,75.48 v2(278.05,75.52)
  IN3 w0.122: v2(278.05,75.52) 278.69,74.89 278.69,74.21 277.99,73.52 270.33,73.52 268.94,74.9 256.95,74.9 255.8,73.76 249.32,73.76 247.54,75.54 246.25,75.54 240.22,81.57 240.22,83.92 238.69,85.45 238.69,88.38 232.8,94.27 221.48,94.27 219.13,91.91 204.54,91.91 203.66,91.03 184.21,91.03 181.61,93.64 180.27,93.64 179.8,94.11 179.8,97.74 178.75,98.78 178.75,104 176.08,106.68 172.29,106.68 170.21,104.59 163.49,104.59 161.81,102.91 144.37,102.91 141.29,105.99 133.82,105.99 v2(133.28,106.53)
  BOTTOM w0.102: JDOCK1.4 133.45,106.36 v2(133.28,106.53) ; v2(278.05,75.52) v1(278.79,75.52)
DOCK_LOM_TRD0+: length 135.4
  TOP w0.094: v2(269.42,77.92) 269.52,77.82 269.52,77.46 269.46,77.4 UL4.36
  IN4 w0.081: v2(269.42,77.92) 269.6,78.11 269.6,78.36 269.1,78.87 252.69,78.87 250.38,81.18 250.38,83.45 249.41,84.42 246.95,84.42 246.11,85.25 242.7,85.25 238.44,89.51 237.05,89.51 231.96,94.6 216.48,94.6 214.97,93.09 206.95,93.09 206.24,92.39 203.24,92.39 200.72,89.87 167.86,89.87 162.37,95.36 162.37,101.93 160.59,103.7 160.59,106.76 v2(160.41,106.94)
  BOTTOM w0.094: v2(160.41,106.94) 160.51,106.84 160.51,106.19 160.45,106.13 JDOCK1.104
DOCK_LOM_TRD0-: length 135.5
  TOP w0.094: UL4.35 269.96,77.45 269.84,77.57 269.84,77.76 v2(270,77.92)
  IN4 w0.081: v2(270,77.92) 269.86,78.07 269.86,78.47 269.2,79.12 252.8,79.12 250.63,81.28 250.63,83.55 249.52,84.67 247.05,84.67 246.22,85.5 242.81,85.5 238.55,89.76 237.16,89.76 232.07,94.85 216.37,94.85 214.86,93.34 206.84,93.34 206.14,92.64 203.14,92.64 200.62,90.12 167.96,90.12 162.62,95.46 162.62,102.03 160.84,103.81 160.84,106.79 v2(160.99,106.94)
  BOTTOM w0.094: v2(160.99,106.94) 160.89,106.84 160.89,106.19 160.95,106.13 JDOCK1.106
DOCK_LOM_TRD1+: length 136.1
  TOP w0.094: v2(271.42,77.92) 271.52,77.82 271.52,77.46 271.46,77.4 UL4.32
  IN4 w0.081: v2(271.42,77.92) 271.57,78.08 271.57,78.18 270.02,79.73 253.13,79.73 251.9,80.96 251.9,83.13 249.19,85.84 246.88,85.84 246.63,86.09 244.68,86.09 240.37,90.4 237.37,90.4 232.09,95.68 224.1,95.68 223.86,95.44 216.13,95.44 214.64,93.96 203.15,93.96 199.9,90.71 168.21,90.71 163.48,95.43 163.48,102 162.08,103.41 162.08,106.77 v2(161.91,106.94)
  BOTTOM w0.094: v2(161.91,106.94) 162.01,106.84 162.01,106.19 161.95,106.13 JDOCK1.110
DOCK_LOM_TRD1-: length 136.2
  TOP w0.094: v2(272,77.92) 271.84,77.76 271.84,77.4 271.96,77.28 UL4.31
  IN4 w0.081: v2(272,77.92) 271.82,78.1 271.82,78.29 270.13,79.98 253.24,79.98 252.16,81.06 252.16,83.24 249.3,86.09 246.99,86.09 246.74,86.34 244.78,86.34 240.47,90.65 237.48,90.65 232.19,95.94 224,95.94 223.76,95.69 216.02,95.69 214.54,94.21 203.05,94.21 199.8,90.96 168.31,90.96 163.74,95.53 163.74,102.1 162.33,103.51 162.33,106.77 v2(162.49,106.94)
  BOTTOM w0.094: JDOCK1.112 162.45,106.13 162.39,106.19 162.39,106.84 v2(162.49,106.94)
DOCK_LOM_TRD2+: length 134.3
  TOP w0.094: v2(273.92,77.86) 274,77.78 274,77.56 273.96,77.52 UL4.27
  IN4 w0.081: v2(273.92,77.86) 274.09,78.03 274.09,78.57 272.07,80.59 254.43,80.59 253.56,81.47 253.56,83.69 251.84,85.4 251.84,86.55 251.26,87.13 250.05,87.13 249.41,87.77 244.19,87.77 240.67,91.29 237.7,91.29 232.47,96.52 223.74,96.52 223.5,96.29 215.02,96.29 213.57,94.84 202.85,94.84 199.56,91.55 175.64,91.55 169.92,97.27 168.1,97.27 165.13,100.23 165.13,106.68 v2(164.97,106.85)
  BOTTOM w0.094: v2(164.97,106.85) 165.03,106.79 165.03,106.15 164.95,106.06 JDOCK1.122
DOCK_LOM_TRD2-: length 134.4
  TOP w0.094: UL4.26 274.46,77.44 274.38,77.53 274.38,77.74 v2(274.5,77.86)
  IN4 w0.081: v2(165.55,106.85) 165.39,106.68 165.39,100.33 168.2,97.52 170.03,97.52 175.75,91.8 199.45,91.8 202.75,95.09 213.47,95.09 214.92,96.54 223.4,96.54 223.63,96.78 232.57,96.78 237.8,91.54 240.78,91.54 244.29,88.03 249.51,88.03 250.15,87.38 251.36,87.38 252.09,86.65 252.09,85.51 253.81,83.79 253.81,81.57 254.53,80.85 272.17,80.85 274.34,78.68 274.34,78.02 v2(274.5,77.86)
  BOTTOM w0.094: v2(165.55,106.85) 165.41,106.71 165.41,105.99 165.45,105.95 JDOCK1.124
DOCK_LOM_TRD3+: length 135.7
  TOP w0.094: UL4.23 275.96,77.52 276.02,77.57 276.02,77.82 v2(275.92,77.92)
  IN4 w0.081: v2(275.92,77.92) 276.03,78.04 276.08,78.09 276.08,79.02 273.52,81.58 259.76,81.58 258.88,82.45 256.07,82.45 253.24,85.28 253.24,87.37 252.64,87.97 250.42,87.97 249.77,88.62 244.61,88.62 241.05,92.18 238.03,92.18 232.84,97.37 229.29,97.37 228.71,97.94 227.14,97.94 226.56,97.37 223.37,97.37 223.14,97.13 214.36,97.13 212.97,95.73 202.55,95.73 199.21,92.39 175.99,92.39 170.17,98.21 168.36,98.21 165.98,100.59 165.98,102.58 166.56,103.16 166.56,106.82 v2(166.41,106.97)
  BOTTOM w0.094: v2(166.41,106.97) 166.51,106.87 166.51,106.19 166.45,106.13 JDOCK1.128
DOCK_LOM_TRD3-: length 135.8
  TOP w0.094: v2(276.5,77.92) 276.4,77.82 276.4,77.46 276.46,77.4 UL4.22
  IN4 w0.081: v2(276.5,77.92) 276.33,78.09 276.33,79.12 273.63,81.83 259.86,81.83 258.99,82.7 256.17,82.7 253.49,85.39 253.49,87.48 252.74,88.22 250.52,88.22 249.88,88.87 244.72,88.87 241.15,92.43 238.14,92.43 232.95,97.62 229.39,97.62 228.82,98.19 227.03,98.19 226.46,97.62 223.27,97.62 223.03,97.38 214.26,97.38 212.86,95.99 202.45,95.99 199.1,92.64 176.1,92.64 170.27,98.46 168.46,98.46 166.23,100.7 166.23,102.47 166.81,103.05 166.81,106.79 v2(166.99,106.97)
  BOTTOM w0.094: v2(166.99,106.97) 166.89,106.87 166.89,106.19 166.95,106.13 JDOCK1.130
DOCK_MIC_DET: length 255.2
  TOP w0.102: UE1.B8 v2(255.37,69.44)
  TOP w0.254: RA26.2 37.7,25.93 38.17,26.4 QA3.5 38.92,26.4 39.18,26.14 v2(39.18,25.12)
  IN2 w0.122: v2(255.37,69.44) 255.71,69.44 256.02,69.13 256.02,68.73 255.73,68.44 255.73,63.19 255.92,63.01 255.92,59.17 256.53,58.55 256.53,57.49 255.85,56.81 252.48,56.81 247.21,51.53 242.1,51.53 235.2,44.64 235.2,39.53 230.76,35.09 229.54,35.09 228.33,33.88 87.07,33.88 86.13,34.82 80.34,34.82 78.87,33.35 78.87,32.53 78.32,31.98 74.29,31.98 73.02,30.71 69.19,30.71 68.77,31.13 68.77,31.72 67.76,32.73 62.81,32.73 62.16,32.09 62.16,31.62 57.26,26.72 50.67,26.72 49.46,25.5 42.03,25.5 41.97,25.56 39.62,25.56 v2(39.18,25.12)
  BOTTOM w0.102: v1(255.94,70.08) 255.37,69.51 v2(255.37,69.44)
DOCK_POR_RST#: length 160.7
  TOP w0.102: v2(252.73,44.46) 252.98,44.21 UE2.A21
  IN2 w0.122: v2(247.39,75.1) 247.71,75.41 254.52,75.41 255.41,74.52 258.66,74.52 262.66,70.52 262.66,66.5 261.81,65.65 261.81,65.1 262.97,63.94 262.97,56.68 262.24,55.95 262.24,54.46 262.37,54.33 262.37,53.16 260.87,51.67 259.84,51.67 259.45,51.27 259.45,48.28 258.59,47.42 258.11,47.42 257.36,46.67 257.36,45.38 256.48,44.51 252.78,44.51 v2(252.73,44.46)
  IN3 w0.122: v2(169.45,103.75) 169.73,103.75 172.4,106.43 175.97,106.43 177.85,104.55 177.85,99.31 177.73,99.2 177.73,95.66 180.01,93.38 181.48,93.38 184.08,90.78 199.86,90.78 199.87,90.77 203.76,90.77 204.65,91.66 219.26,91.66 221.62,94.02 232.67,94.02 238.44,88.25 238.44,85.32 239.96,83.79 239.96,81.44 246.31,75.1 v2(247.39,75.1)
  BOTTOM w0.102: JDOCK1.140 v2(169.45,103.75) ; v2(252.73,44.46) 253.17,44.9 253.17,45.92 252.94,46.15 v1(252.51,46.15) 251.8,46.15 RE277.2
DOCK_PSID: length 125.6
  TOP w0.102: PU1.1 73.93,106.7 v2(74.29,106.34)
  IN1 w0.089: v2(164.21,101.51) 163.76,101.96 162.62,101.96 161.96,101.3 159.87,101.3 158.24,99.67 157.22,99.67 155.13,101.76 149.47,101.76 146.96,99.26 144.56,99.26 136.01,90.72 131.25,90.72 126.49,85.95 102.91,85.95 102.02,85.07 97.51,85.07 96.15,83.71 90.95,83.71 90.36,84.3 86.1,84.3 83.65,86.75 83.65,87.72 83.02,88.36 81.75,88.36 81.22,88.89 81.22,89.77 80.7,90.29 79.02,90.29 75.5,93.81 75.5,95.92 74.93,96.49 74.93,105.7 v2(74.29,106.34)
  BOTTOM w0.102: v1(74.08,106.88) 74.29,106.67 v2(74.29,106.34) ; v2(164.21,101.51) 164.21,101.07 165.72,99.55 167.94,99.55 168.45,99.04 JDOCK1.135
DOCK_PWR_BTN#: length 135.8
  TOP w0.102: RE42.2 268.58,48.94 CE44.1 268.59,49.38 269.06,49.86 269.06,54.64 v1(266.89,56.82) 266.51,57.2 v2(266.51,60.53)
  IN3 w0.122: v2(266.51,60.53) 264.77,62.27 262.76,62.27 262.19,62.84 260.26,62.84 258.74,61.32 251.14,61.32 250.53,61.92 247.6,61.92 247.31,62.21 247.31,64.41 247.16,64.56 247.16,66.63 245.04,68.75 245.04,71.8 236.59,80.25 235.81,80.25 235.33,80.25 233.61,81.97 233.61,83.42 231.9,85.13 231.9,86.4 229.98,88.32 226.69,88.32 226.5,88.13 209.19,88.13 209.05,87.99 205.91,87.99 205.15,87.22 176.18,87.22 169.45,93.96 v2(169.45,94.23)
  BOTTOM w0.102: JDOCK1.139 v2(169.45,94.23)
DOCK_PWR_SW#: length 5.7
  TOP w0.102: RE62.2 RE42.1 CE45.1 266.22,48.05 265.54,47.37 v1(265.54,46.91) 265.54,46.48 264.77,45.71 UE2.A63
DOCK_SMB_ALERT#: length 307.1
  TOP w0.102: UE1.A51 260.79,62.76 v2(261.16,62.4) 261.54,62.78 RE9.2
  TOP w0.254: v2(45.72,16.97) 43.6,14.85 v1(43.6,12.32) 43.6,11.68 44.19,11.09 46.48,11.09 46.78,10.78 PQ1.3
  IN3 w0.122: v2(45.72,16.97) 45.72,16.76 46.2,16.28 47.25,16.28 48.87,17.89 48.87,18.3 50.86,20.29 50.86,21.82 53.85,24.8 57.53,24.8 59.12,26.39 70.1,26.39 72.7,28.99 73.71,28.99 76.82,32.11 80.13,32.11 82.29,34.26 82.29,38.13 84.58,40.42 84.58,52.68 85.5,53.6 90.14,53.6 91.12,54.58 91.99,54.58 94.87,57.46 94.87,61.19 97.34,63.66 97.34,66.66 98.77,68.08 98.77,69.01 103.14,73.39 103.14,73.97 104.74,75.57 104.74,78.62 106.05,79.93 109.07,79.93 110.58,81.43 110.58,82.36 111.92,83.7 121.19,83.7 124.92,87.43 127.6,87.43 129.87,89.7 132.75,89.7 133.35,90.3 144.49,90.3 146.57,92.39 151.14,92.39 157.11,98.36 158.47,98.36 159.61,97.22 164.88,97.22 165.75,96.34 167.81,96.34 168.3,95.85 168.3,95.5 v2(168.88,94.91) 168.88,94.17 176.08,86.97 196.48,86.97 197.19,86.26 204.53,86.26 205.98,87.7 209.12,87.7 209.29,87.88 226.6,87.88 226.79,88.07 229.83,88.07 231.65,86.25 231.65,85 233.36,83.29 233.36,81.85 235.21,80 235.91,80 235.91,80 236.46,80 244.42,72.03 244.42,72 244.42,66.93 247.06,64.29 247.06,62.11 247.49,61.67 250.43,61.67 251.04,61.06 258.84,61.06 260.17,62.4 v2(261.16,62.4)
  BOTTOM w0.102: v2(168.88,94.91) 167.95,95.85 JDOCK1.133
DOCK_SMB_CLK: length 141.2
  TOP w0.102: UE2.B4 261.44,46.79 261.36,46.72 261.36,46.34 v2(260.79,45.77) ; RPE3.2 260.85,51.42 260.59,51.16 260.59,51 v2(260.72,50.87)
  IN1 w0.089: v2(166.47,95.66) 166.58,95.78 166.58,96.29 166.95,96.65 169.3,96.65 173.81,92.15 187.72,92.15 188.85,91.01 201.68,91.01 202.42,91.75 220.74,91.75 221.45,92.46 236.32,92.46 239.59,89.19 242.95,89.19 244.87,87.27 244.87,83.76 245.6,83.03 245.6,71.93 244.4,70.73 244.4,62.31 252.27,54.44 253.05,54.44 253.98,53.51 258.68,53.51 260.59,51.6 260.59,51.17 260.59,51.02 260.58,51.01 v2(260.72,50.87) 260.72,50.78 261.49,50.01 261.49,47.81 261.18,47.5 261.18,46.04 260.91,45.77 v2(260.79,45.77)
  BOTTOM w0.102: v2(166.47,95.66) 166.59,95.79 166.59,95.97 166.45,96.11 JDOCK1.127
DOCK_SMB_DAT: length 137.1
  TOP w0.102: RPE3.1 260.35,51.08 v2(260.14,50.87) 260.54,50.46 261.04,50.46 261.49,50.01 261.49,49.51 261.69,49.32 UE2.A3
  IN1 w0.089: v2(167.05,95.66) 166.8,95.91 166.8,96.2 167.04,96.44 169.21,96.44 173.72,91.93 187.63,91.93 188.76,90.8 201.77,90.8 202.51,91.53 220.83,91.53 221.54,92.24 236.23,92.24 239.5,88.97 242.86,88.97 244.65,87.18 244.65,83.67 245.39,82.94 245.39,72.02 244.18,70.81 244.18,62.22 252.18,54.22 252.96,54.22 253.89,53.29 258.59,53.29 260.37,51.51 260.37,51.11 260.36,51.09 v2(260.14,50.87)
  BOTTOM w0.102: v2(167.05,95.66) 166.82,95.89 166.82,96 166.95,96.13 JDOCK1.129
DOCK_USB3RN1: length 36.7
  TOP w0.102: UI4.22 183.18,99.64 183.12,99.71 183.12,100.16 181.94,101.34 180.69,101.34 178.12,103.91 178.12,106.01 175.98,108.15 165.97,108.15 165.69,107.87 156.64,107.87 156.29,107.53 v2(155.4,107.53)
  BOTTOM w0.102: JDOCK1.84 154.45,107.18 154.79,107.53 v2(155.4,107.53)
DOCK_USB3RP1: length 36.6
  TOP w0.102: v2(155.4,106.94) 155.78,107.32 156.38,107.32 156.72,107.67 165.78,107.67 166.06,107.94 175.89,107.94 177.91,105.92 177.91,103.83 180.61,101.13 181.86,101.13 182.91,100.08 182.91,99.76 182.78,99.63 UI4.23
  BOTTOM w0.102: JDOCK1.86 154.95,106.02 154.87,106.1 154.76,106.1 154.66,106.2 154.66,107.1 154.88,107.32 155.02,107.32 v2(155.4,106.94)
DOCK_USB3TN1: length 35.2
  TOP w0.102: UI4.24 182.38,100.08 181.94,100.52 180.22,100.52 176.96,103.78 176.96,105.81 175.46,107.31 168.69,107.31 166.83,105.45 166.54,105.45 165.8,104.71 161.77,104.71 161.75,104.73 161.15,104.73 161.13,104.71 160.49,104.71 158.19,107.01 v2(157.37,107.01)
  BOTTOM w0.102: JDOCK1.90 155.95,106.46 156.51,107.01 v2(157.37,107.01)
DOCK_USB3TP1: length 35
  TOP w0.102: v2(157.37,106.43) 157.75,106.81 158.1,106.81 160.41,104.5 v4(161.45,104.5) 165.89,104.5 166.63,105.24 166.92,105.24 168.78,107.11 175.37,107.11 176.75,105.73 176.75,103.69 180.13,100.31 181.85,100.31 182.17,99.99 182.17,99.83 181.98,99.64 UI4.25
  BOTTOM w0.102: JDOCK1.92 156.45,106.03 156.35,106.13 156.26,106.13 156.16,106.23 156.16,106.36 156.6,106.8 157.01,106.8 v2(157.37,106.43)
DOCK_USBP0+: length 45.4
  TOP w0.102: UI4.15 186.7,98.04 186.8,97.95 186.99,97.95 v2(187.18,98.14)
  IN1 w0.089: v2(187.18,98.14) 187,97.96 186.74,97.96 186.48,98.22 186.48,101.08 184.77,102.79 182.11,102.79 176.71,108.19 153.73,108.19 152.73,107.18 152.47,107.18 v2(152.29,107.35)
  BOTTOM w0.102: JDOCK1.72 151.45,107.11 151.7,107.35 v2(152.29,107.35)
DOCK_USBP0-: length 45.5
  TOP w0.102: UI4.14 186.74,97.64 186.83,97.74 186.99,97.74 v2(187.18,97.55)
  IN1 w0.089: v2(187.18,97.55) 186.94,97.79 186.67,97.79 186.31,98.15 186.31,101.01 184.7,102.62 182.04,102.62 176.64,108.02 153.8,108.02 152.8,107.01 152.54,107.01 v2(152.29,106.77)
  BOTTOM w0.102: v2(152.29,106.77) 152.29,106.78 151.93,107.14 151.79,107.14 151.66,107.02 151.66,106.25 151.76,106.15 151.89,106.15 151.95,106.08 JDOCK1.74
DOCK_USBP3+: length 112.7
  IN1 w0.089: v2(245.14,89.26) 245.35,89.47 245.35,89.83 244.41,90.77 240.04,90.77 236.57,94.24 222.39,94.24 221.56,95.07 201.93,95.07 199.33,92.47 189.63,92.47 188.45,93.65 174.6,93.65 168.64,99.61 159.9,99.61 158.77,98.48 156.86,98.48 154.79,100.56 153.02,100.56 152.6,100.13 151.49,100.13 151.22,100.4 151.22,100.61 v2(151.01,100.82)
  BOTTOM w0.102: v2(245.14,89.26) 245.33,89.07 245.33,88.19 244.87,87.72 244.87,86.41 244.28,85.83 244.28,85.46 244.14,85.31 UI5.3 ; JDOCK1.66 149.95,104 150.1,103.85 150.1,103.33 151.2,102.22 151.2,101.01 v2(151.01,100.82)
DOCK_USBP3-: length 112.7
  IN1 w0.089: v2(245.73,89.26) 245.52,89.47 245.52,89.9 244.48,90.94 240.11,90.94 236.64,94.41 222.46,94.41 221.63,95.24 201.86,95.24 199.26,92.64 189.7,92.64 188.52,93.82 174.67,93.82 168.71,99.78 159.83,99.78 158.7,98.65 156.93,98.65 154.86,100.73 152.95,100.73 152.52,100.3 151.56,100.3 151.39,100.47 151.39,100.61 v2(151.6,100.82)
  BOTTOM w0.102: JDOCK1.68 150.45,104 150.31,103.85 150.31,103.41 151.41,102.31 151.41,101.01 v2(151.6,100.82) ; v2(245.73,89.26) 245.54,89.07 245.54,88.1 245.07,87.64 245.07,86.32 244.49,85.74 244.49,85.46 244.64,85.31 UI5.4
DOCKED: length 139.5
  TOP w0.102: UL4.13 274.46,72.85 274.49,72.82 v2(274.49,70.97) ; UI4.32 179.65,96.84 v2(179.24,96.44) ; UI4.10 184.78,95.35 v2(184.9,95.23) 185.02,95.1 185.66,95.1 185.85,94.91 185.85,93.65 187.12,92.38 v1(200.89,92.38) 201.98,93.47 204.19,93.47 204.73,92.93 204.73,92.65 205.74,91.64 205.74,91.2 209.26,87.68 214.44,87.68 216.94,85.18 v2(216.94,79.92) ; UE1.A38 253.62,59.3 v2(252.97,58.64)
  IN3 w0.122: v2(274.49,70.97) 269.62,66.1 269.62,60.87 267.97,59.22 262.82,59.22 262,60.05 254.11,60.05 253.6,59.54 253.6,59.28 v2(252.97,58.64) 252.49,58.16 250.8,58.16 250.38,58.58 250.38,59.09 249.93,59.54 248.16,59.54 246.06,61.63 246.06,62.78 239.9,68.94 239.83,68.94 235.31,73.45 220.7,73.45 219.78,74.37 217.9,74.37 216.9,75.37 216.9,75.48 216.33,76.05 v2(215.91,76.05)
  IN4 w0.089: v2(216.94,79.92) 216.94,79.06 215.91,78.03 v2(215.91,76.05)
  IN4 w0.102: v2(184.9,95.23) 183.69,96.44 v2(179.24,96.44)
  BOTTOM w0.102: UV10.3 216.52,75.15 216.48,75.11 216.04,75.11 215.81,75.34 215.81,75.95 v2(215.91,76.05) 216.29,76.05 216.39,75.95 UV10.5
DOCKED_LIO_EN: length 32.8
  TOP w0.102: v2(257.9,67.36) 257.9,62.92 258.34,62.48 258.34,61.84 258.67,61.51 UE1.B52
  BOTTOM w0.102: v2(257.9,67.36) 257.9,70.62 251.26,77.26 v1(245.42,77.26) 243.01,79.67 243.01,82.97 243.14,83.1 UI5.9
DPB_CA_DET: length 110.2
  TOP w0.102: v2(202,92.11) 202.03,92.09 QV9.2 203.09,91.94 206.19,88.84 206.83,88.84 207.71,87.96 207.71,86.97 207.07,86.33 v2(207.07,86.08) v2(205.89,86.08) ; v2(210.74,81.45) 210.53,81.45 UV8.M14
  IN3 w0.122: v2(202,92.11) 200.5,92.11 199.67,91.29 184.34,91.29 181.73,93.89 180.4,93.89 180.05,94.24 180.05,97.84 179,98.88 179,104.1 176.18,106.92 172.19,106.92 170.11,104.84 163.39,104.84 161.71,103.16 144.47,103.16 141.23,106.4 134.07,106.4 v2(133.95,106.53)
  BOTTOM w0.102: v2(210.74,81.45) 210.52,81.23 209.31,81.23 208.85,81.69 208.85,83.46 207.71,84.6 207.71,85.45 v2(207.07,86.08) 207.07,85.53 205.55,84.01 UV11.1 203.11,84.01 RV508.2 ; v2(133.95,106.53) JDOCK1.6 ; UV11.4 205.34,85.96 205.46,86.08 v2(205.89,86.08)
DPB_CA_DET#: length 13.2
  TOP w0.102: v2(211.54,86.47) 211.06,86.95 RV90.2 v1(209.61,87.22) 209.4,87.22 206.77,89.85 206.09,89.85 204.99,90.96 QV9.1
  BOTTOM w0.102: UV11.13 211.35,84.66 211.54,84.86 v2(211.54,86.47) 211.21,86.47 211.06,86.61 UV11.10
DPB_DOCK_AUX: length 90.1
  TOP w0.102: v2(140.91,103.17) 141.1,102.98 141.1,99.82 150.42,90.49 163.39,90.49 164.04,91.14 176.89,91.14 180.45,87.57 183.59,87.57 187.54,91.52 200.22,91.52 202.11,89.64 204.23,89.64 206,87.86 206.52,87.86 206.65,87.73 206.65,87.5 v2(206.44,87.29)
  BOTTOM w0.102: UV11.11 208.59,85.96 207.88,86.66 206.87,86.66 206.68,86.85 206.68,87.04 v2(206.44,87.29) 206.5,87.35 206.5,87.56 206.33,87.73 205.95,87.73 205.8,87.59 205.8,86.84 206.37,86.27 206.37,85.72 205.96,85.31 UV11.3 ; JDOCK1.34 140.95,104.19 141.1,104.04 141.1,103.36 v2(140.91,103.17)
DPB_DOCK_AUX#: length 88.8
  TOP w0.102: v2(141.49,103.17) 141.31,102.98 141.31,99.9 150.51,90.7 163.3,90.7 163.95,91.35 176.97,91.35 180.54,87.78 183.5,87.78 187.45,91.73 200.3,91.73 202.19,89.84 204.31,89.84 206.09,88.07 206.61,88.07 206.86,87.82 206.86,87.5 v2(207.07,87.29)
  BOTTOM w0.102: UV11.8 208.9,87.91 208.79,87.79 208.79,86.72 208.66,86.59 208.25,86.59 207.97,86.87 206.95,86.87 206.89,86.93 206.89,87.11 v2(207.07,87.29) 206.42,87.94 205.86,87.94 205.59,87.67 205.59,87.35 205.5,87.26 UV11.6 ; v2(141.49,103.17) 141.31,103.36 141.31,104.04 141.45,104.19 JDOCK1.36
DPB_DOCK_HPD: length 96.5
  TOP w0.102: v2(204,93.07) 204,91.36 206.15,89.21 206.78,89.21 209.43,86.56 209.43,84.8 210.13,84.1 210.13,83.1 209.84,82.8 208.94,82.8 208.53,82.4 208.53,81.42 UV8.K14 ; R271.1 C311.1 142.43,106.2 v2(142.26,106.37) v1(142.26,106.97)
  IN3 w0.122: v2(142.26,106.37) 142.26,105.73 144.57,103.42 161.61,103.42 163.29,105.09 170,105.09 172.09,107.17 176.28,107.17 179.25,104.2 179.25,101.81 180.74,100.33 180.74,96.3 182.05,94.99 182.05,93.95 184.46,91.54 199.57,91.54 201.1,93.07 v2(204,93.07)
  BOTTOM w0.102: v2(142.26,106.37) 142.26,106.24 142.45,106.05 JDOCK1.40
DPB_DOCK_LANE_N0: length 14.3
  TOP w0.102: v2(135.49,103.17) 135.37,103.04 135.37,102.47 135.68,102.15 136.65,102.15 137.52,101.28 137.52,100.76 135.3,98.53 v4(135.3,95.63) 135.3,95.36 135.03,95.08 135.03,93.93 R261.1
  BOTTOM w0.102: v2(135.49,103.17) 135.31,103.36 135.31,104.04 135.45,104.19 JDOCK1.12
DPB_DOCK_LANE_N1: length 13
  TOP w0.102: v2(136.99,103.36) 136.89,103.26 136.89,103.07 138.34,101.62 138.34,100.39 136.82,98.87 136.82,98.43 136.8,98.41 136.8,93.93 R256.1
  BOTTOM w0.102: JDOCK1.18 136.95,104.19 136.81,104.04 136.81,103.55 v2(136.99,103.36)
DPB_DOCK_LANE_N2: length 12.6
  TOP w0.102: R264.1 138.58,93.93 138.58,95 138.37,95.21 138.37,95.7 138.35,95.72 138.35,98.47 139.16,99.28 139.16,101.96 138.29,102.83 138.29,102.96 v2(138.49,103.17)
  BOTTOM w0.102: JDOCK1.24 138.45,104.19 138.31,104.04 138.31,103.36 v2(138.49,103.17)
DPB_DOCK_LANE_N3: length 12.2
  TOP w0.102: v2(139.99,103.17) 139.81,102.99 139.81,102.47 139.98,102.3 139.98,97.57 139.83,97.42 139.83,96.95 139.81,96.93 139.81,95.08 140.36,94.53 140.36,93.93 R267.1
  BOTTOM w0.102: v2(139.99,103.17) 139.81,103.36 139.81,104.04 139.95,104.19 JDOCK1.30
DPB_DOCK_LANE_P0: length 14.3
  TOP w0.102: R260.1 134.82,93.93 134.82,95.17 135.07,95.42 135.07,95.91 135.09,95.93 135.09,98.62 137.32,100.84 137.32,101.19 136.56,101.94 135.6,101.94 135.16,102.38 135.16,102.92 v2(134.91,103.17)
  BOTTOM w0.102: JDOCK1.10 134.95,104.19 135.1,104.04 135.1,103.36 v2(134.91,103.17)
DPB_DOCK_LANE_P1: length 13.1
  TOP w0.102: v2(136.41,103.36) 136.68,103.09 136.68,102.99 138.13,101.53 138.13,100.48 136.6,98.94 v4(136.6,98.7) 136.6,93.93 R254.1
  BOTTOM w0.102: JDOCK1.16 136.45,104.19 136.6,104.04 136.6,103.55 v2(136.41,103.36)
DPB_DOCK_LANE_P2: length 12.6
  TOP w0.102: R262.1 138.37,93.93 138.37,94.91 138.14,95.15 v4(138.14,95.43) 138.14,98.56 138.95,99.37 138.95,101.87 138.08,102.75 138.08,103 v2(137.91,103.17)
  BOTTOM w0.102: v2(137.91,103.17) 138.1,103.36 138.1,104.04 137.95,104.19 JDOCK1.22
DPB_DOCK_LANE_P3: length 12.2
  TOP w0.102: v2(139.41,103.17) 139.6,102.98 139.6,102.38 139.77,102.22 139.77,97.65 139.6,97.48 v4(139.6,97.23) 139.6,95 140.15,94.45 140.15,93.93 R258.1
  BOTTOM w0.102: v2(139.41,103.17) 139.6,103.36 139.6,104.04 139.45,104.19 JDOCK1.28
DPB_HPD: length 169
  TOP w0.102: QV501.3 288.81,67.97 v2(288.54,68.24)
  IN3 w0.122: v2(166.88,83.86) 168.15,83.86 169.73,85.45 172.59,85.45 173.21,84.82 173.21,83.69 173.87,83.04 190.52,83.04 192.49,81.07 199.34,81.07 199.94,81.67 199.94,84.02 200.52,84.6 209.22,84.6 210.3,85.68 214.49,85.68 215.12,86.31 227.23,86.31 227.31,86.22 228.29,86.22 229.92,84.59 229.92,81.98 232.8,79.11 236.2,79.11 240.09,75.22 240.09,69.12 246.31,62.9 246.31,61.8 247.18,60.93 250.06,60.93 250.68,60.3 262.13,60.3 262.95,59.47 267.84,59.47 269.36,61 269.36,66.66 274.13,71.43 277.56,71.43 281.57,67.41 287.72,67.41 v2(288.54,68.24)
  BOTTOM w0.076: 167.51,76.26 167.51,75.22 166.54,74.25 166.54,73.21 166.25,72.92 UC1.C8
  BOTTOM w0.102: v2(166.88,83.86) 166.97,83.76 v1(166.97,82.6) 166.97,82.36 167.83,81.51 167.83,78.02 167.51,77.7 167.51,76.26
DPB_LANE_N0: length 81
  TOP w0.102: UV8.E14 205.51,81.19 205.51,81.41 204.77,82.15 204.4,82.15 203.94,82.61 203.94,83.73 202.97,84.7 202.97,86.04 202.53,86.48 200.85,86.48 199.24,88.08 190.22,88.08 186.56,84.43 179.04,84.43 177.92,85.55 176.2,85.55 174.33,87.43 v4(137.98,87.43) 136.69,87.43 134.95,89.17 134.95,89.68 134.93,89.7 134.93,91.01 135.02,91.1 135.14,91.1 135.37,90.87 C296.1
DPB_LANE_N0_C: length 0.9
  TOP w0.102: R261.2 C296.2
DPB_LANE_N1: length 80
  TOP w0.102: UV8.F14 206.16,81.19 206.16,81.51 204.83,82.83 204.83,84.18 203.79,85.22 203.79,86.87 203.33,87.33 201.2,87.33 199.53,89 v4(190.27,89) 189.93,89 186.26,85.33 179.37,85.33 176.46,88.25 138.1,88.25 137.11,89.23 137.11,89.26 136.71,89.66 136.71,91.03 136.77,91.09 136.89,91.09 C303.1
DPB_LANE_N1_C: length 0.9
  TOP w0.102: C303.2 R256.2
DPB_LANE_N2: length 79.2
  TOP w0.102: C307.1 138.66,91.1 138.55,91.1 138.49,91.03 138.49,89.95 139.35,89.08 139.89,89.08 139.91,89.06 176.84,89.06 179.76,86.15 185.04,86.15 186.73,87.83 186.73,87.83 186.89,88 v4(186.89,88) 187.06,88.16 187.06,88.16 188.87,89.97 199.71,89.97 201.54,88.15 203.67,88.15 204.61,87.21 204.61,85.57 205.67,84.51 205.67,83.29 206.22,82.74 206.22,82.35 206.82,81.75 206.82,81.18 UV8.G14
DPB_LANE_N2_C: length 0.9
  TOP w0.102: C307.2 R264.2
DPB_LANE_N3: length 78.3
  TOP w0.102: UV8.H14 207.46,81.19 207.46,82.01 206.97,82.49 206.97,83.2 206.51,83.65 206.51,84.84 205.46,85.88 205.46,87.53 203.98,89.01 201.86,89.01 199.96,90.91 v4(188.2,90.91) 187.96,90.91 184.02,86.96 180.15,86.96 177.23,89.88 141.95,89.88 141.93,89.9 141.33,89.9 141.31,89.88 140.57,89.88 140.27,90.18 140.27,91 140.36,91.09 140.45,91.09 C309.1
DPB_LANE_N3_C: length 0.9
  TOP w0.102: R267.2 C309.2
DPB_LANE_P0: length 81.1
  TOP w0.102: C294.1 134.73,90.59 v4(134.73,89.41) 134.73,89.1 136.61,87.22 137.66,87.22 137.69,87.2 138.28,87.2 138.3,87.22 174.24,87.22 176.12,85.34 177.84,85.34 178.96,84.22 186.65,84.22 190.3,87.88 199.15,87.88 200.76,86.27 202.45,86.27 202.76,85.96 202.76,84.61 203.73,83.64 203.73,82.52 204.31,81.94 204.68,81.94 205.3,81.32 205.3,80.75 UV8.E13
DPB_LANE_P0_C: length 0.9
  TOP w0.102: C294.2 R260.2
DPB_LANE_P1: length 80.1
  TOP w0.102: UV8.F13 205.95,80.75 205.95,81.42 204.62,82.75 204.62,84.1 203.59,85.13 203.59,86.78 203.25,87.12 201.11,87.12 199.44,88.8 190.57,88.8 190.55,88.78 190,88.78 186.34,85.12 179.29,85.12 176.37,88.04 138.01,88.04 v4(136.75,89.3) 136.5,89.54 136.5,90.59 C298.1
DPB_LANE_P1_C: length 0.9
  TOP w0.102: C298.2 R254.2
DPB_LANE_P2: length 79.2
  TOP w0.102: C305.1 138.28,90.59 138.28,89.86 139.29,88.86 v4(139.61,88.86) 176.76,88.86 179.68,85.94 185.13,85.94 186.81,87.62 186.84,87.62 187.26,88.05 187.26,88.07 188.95,89.77 199.63,89.77 201.45,87.94 203.59,87.94 204.4,87.12 204.4,85.48 205.47,84.42 205.47,83.2 206.01,82.65 206.01,82.27 206.61,81.67 206.61,80.74 UV8.G13
DPB_LANE_P2_C: length 0.9
  TOP w0.102: C305.2 R262.2
DPB_LANE_P3: length 78.4
  TOP w0.102: C308.1 140.06,90.59 140.06,90.09 140.48,89.67 v4(141.63,89.67) 177.15,89.67 180.06,86.76 184.1,86.76 188.03,90.68 188.48,90.68 188.5,90.7 199.88,90.7 201.78,88.8 203.9,88.8 205.25,87.44 205.25,85.8 206.3,84.75 206.3,83.57 206.76,83.11 206.76,82.41 207.25,81.92 207.25,80.75 UV8.H13
DPB_LANE_P3_C: length 0.9
  TOP w0.102: C308.2 R258.2
DPB_MB_P14: length 4.2
  TOP w0.102: RV503.2 287.95,76.21 v1(288.48,76.21) 289.31,76.21 v2(289.49,76.03)
  BOTTOM w0.102: JMDP1.6 289.51,76.05 v2(289.49,76.03)
DPC_CA_DET: length 99.3
  TOP w0.102: UV8.A14 202.37,81.72 200.14,81.72 199.71,82.15 v2(199.2,82.15) 198.7,82.65 RV509.2 198.7,83.69 198.46,83.93 198.46,84.34 198.46,84.35 QV10.2
  IN3 w0.122: v2(133.71,89.83) 144.36,89.83 146.68,92.14 151.24,92.14 157.22,98.11 158.36,98.11 159.51,96.97 164.77,96.97 165.65,96.09 167.68,96.09 168.05,95.72 168.05,94.65 173.59,89.1 173.59,85.33 174.5,84.43 186.88,84.43 187.26,84.05 192.91,84.05 195.39,81.57 198.62,81.57 199.2,82.14 v2(199.2,82.15)
  BOTTOM w0.102: v2(133.71,89.83) 133.23,90.31 v1(133.23,92.4) 133.23,93.43 133.95,94.15 133.95,96.12 133.95,96.12 JDOCK1.5 ; v2(199.2,82.15) 199.55,81.8 UV12.1 199.55,79.67 199.35,79.48 197.83,79.48 197.6,79.71 UV12.4
DPC_CA_DET#: length 9.2
  TOP w0.102: QV10.1 196.56,84.28 196.71,84.12 v2(196.72,84.12) 196.96,83.88 RV91.2
  BOTTOM w0.102: v2(196.72,84.12) 196.72,85.09 196.95,85.32 UV12.10 196.95,87.26 197.51,87.82 v1(197.9,87.82) 198.35,87.82 198.9,87.27 UV12.13
DPC_DOCK_AUX: length 77.4
  TOP w0.102: v2(194.59,84.69) 194.77,84.5 194.77,82.01 195.09,81.7 195.79,81.7 196.15,82.06 196.15,82.76 v2(196.32,82.93)
  BOTTOM w0.102: JDOCK1.33 140.95,96.19 141.1,96.04 141.1,94.51 141.52,94.09 141.52,91.45 142.12,90.85 145.44,90.85 146.78,89.5 158.17,89.5 159.57,90.91 164.99,90.91 165.33,90.56 181.7,90.56 182.77,89.49 192.44,89.49 194.77,87.16 194.77,84.88 v2(194.59,84.69) ; UV12.11 197.6,84.81 197.2,84.42 197.2,83.81 197.14,83.74 197.13,83.74 v2(196.32,82.93) 196.32,82.64 196.44,82.52 196.96,82.52 197.98,81.51 198.08,81.51 198.25,81.34 UV12.3
DPC_DOCK_AUX#: length 77.1
  TOP w0.102: v2(195.17,84.69) 194.98,84.5 194.98,82.1 195.17,81.91 195.71,81.91 195.95,82.14 195.95,82.73 v2(195.74,82.93)
  BOTTOM w0.102: UV12.8 195.65,85.19 195.78,85.06 195.78,84.35 195.54,84.11 195.54,83.13 v2(195.74,82.93) 196.36,82.32 196.88,82.32 197.32,81.87 197.32,81.64 197.22,81.53 196.45,81.53 196.3,81.38 UV12.6 ; JDOCK1.35 141.45,96.19 141.31,96.04 141.31,94.6 141.73,94.18 141.73,91.54 142.21,91.05 145.53,91.05 146.87,89.71 158.08,89.71 159.49,91.11 165.08,91.11 165.42,90.77 181.78,90.77 182.86,89.7 192.53,89.7 194.98,87.25 194.98,84.88 v2(195.17,84.69)
DPC_DOCK_HPD: length 91.6
  TOP w0.102: v2(193.99,70.33) 193.99,71.03 v1(194.35,71.39) 197.32,74.36 201.67,74.36 202.85,75.54 202.85,75.73 UV8.A6
  IN3 w0.122: v2(193.99,70.33) 191.58,70.33 190.82,71.09 175.19,71.09 173.12,73.16 173.12,77.76 172.37,78.51 171.26,78.51 165.57,84.19 165.57,86.64 167.23,88.29 167.23,94.16 164.67,96.72 158.77,96.72 157.91,95.86 157.16,95.86 153.12,91.82 146.95,91.82 v2(146.74,91.62)
  BOTTOM w0.102: v2(146.74,91.62) 144.77,93.59 R268.1 C310.1 142.45,93.62 JDOCK1.39
DPC_DOCK_LANE_N0: length 3.8
  BOTTOM w0.102: R252.2 135.03,93.93 135.03,94.37 135.05,94.39 135.05,94.91 135.31,95.17 135.31,95.85 135.45,96 JDOCK1.11
DPC_DOCK_LANE_N1: length 3.7
  BOTTOM w0.102: R255.2 136.81,93.93 136.81,94.42 136.83,94.44 136.83,95.04 136.81,95.06 136.81,95.85 136.95,96 JDOCK1.17
DPC_DOCK_LANE_N2: length 3.8
  BOTTOM w0.102: JDOCK1.23 138.45,96 138.31,95.85 138.31,95.28 138.58,95 v4(138.58,94.69) 138.58,93.93 R263.2
DPC_DOCK_LANE_N3: length 3.9
  BOTTOM w0.102: R266.2 140.36,93.93 v4(140.36,94.61) 140.36,94.87 139.81,95.43 139.81,95.95 139.95,96.1 JDOCK1.29
DPC_DOCK_LANE_P0: length 3.8
  BOTTOM w0.102: JDOCK1.9 134.95,96 135.1,95.85 135.1,95.26 134.82,94.98 v4(134.82,94.67) 134.82,93.93 R259.2
DPC_DOCK_LANE_P1: length 3.7
  BOTTOM w0.102: JDOCK1.15 136.45,96 136.6,95.85 v4(136.6,94.72) 136.6,93.94 R253.2
DPC_DOCK_LANE_P2: length 3.8
  BOTTOM w0.102: R257.2 138.37,93.93 138.37,94.39 138.35,94.41 138.35,94.93 138.1,95.19 138.1,95.85 137.95,96 JDOCK1.21
DPC_DOCK_LANE_P3: length 3.9
  BOTTOM w0.102: JDOCK1.27 139.45,96.1 139.6,95.95 139.6,95.34 140.13,94.81 140.13,94.34 140.15,94.32 140.15,93.93 R265.2
DPC_HPD: length 80.5
  TOP w0.102: v2(227.62,86.64) UV7.5
  IN3 w0.122: v2(227.62,86.64) 227.53,86.56 214.84,86.56 214.21,85.93 210.09,85.93 209.01,84.85 200.42,84.85 199.69,84.12 199.69,81.77 199.24,81.32 192.6,81.32 190.63,83.29 174.1,83.29 173.52,83.87 173.52,84.9 172.72,85.7 167.55,85.7 166.47,84.62 v2(166.47,84.36)
  BOTTOM w0.076: UC1.A8 166.12,73.63 166.12,74.11 167.26,75.25 167.26,76.26
  BOTTOM w0.102: v2(166.47,84.36) 166.47,83.63 166.62,83.48 166.62,80.54 RC142.2 167.37,79.79 v1(167.37,78.51) 167.37,77.88 167.26,77.77 167.26,76.26
DPC_LANE_N0: length 81.6
  TOP w0.102: UV8.A7 203.01,76.44 202.94,76.37 202.77,76.37 201.64,75.24 200.31,75.24 200.25,75.3 200.25,75.42 v2(200.63,75.8)
  BOTTOM w0.102: C295.2 135.15,91.05 135.01,91.05 134.93,90.98 134.93,89.31 136.57,87.68 144.27,87.68 145.92,86.03 150.76,86.03 151.17,86.44 159.45,86.44 160.51,87.5 178.1,87.5 179.49,86.11 189.9,86.11 191.46,84.55 191.46,79.72 194.97,76.21 200.22,76.21 v2(200.63,75.8)
DPC_LANE_N0_C: length 0.9
  BOTTOM w0.102: C295.1 R252.1
DPC_LANE_N1: length 78.2
  TOP w0.102: v2(201.82,76.77) 201.82,76.69 201.97,76.55 201.98,76.55 202.07,76.45 202.24,76.45 202.65,76.86 202.65,77.01 202.57,77.1 202.57,77.2 202.68,77.32 202.88,77.32 UV8.A8
  BOTTOM w0.102: v2(201.82,76.77) 201.63,76.57 201.36,76.57 200.9,77.02 195.37,77.02 192.28,80.12 192.28,84.94 190.18,87.03 v4(189.93,87.03) 179.72,87.03 178.44,88.32 160.17,88.32 159.11,87.26 145.85,87.26 144.61,88.5 137.78,88.5 136.71,89.57 136.71,90.88 136.78,90.95 137.03,90.95 C299.2
DPC_LANE_N1_C: length 0.9
  BOTTOM w0.102: C299.1 R255.1
DPC_LANE_N2: length 76.3
  TOP w0.102: UV8.A9 202.9,77.95 202.69,77.95 202.6,77.86 202.6,77.79 202.56,77.75 202.51,77.75 202.1,77.33 202.07,77.33 202.06,77.34 201.59,77.34 201.58,77.33 201.44,77.33 201.37,77.4 201.37,77.49 201.66,77.77 v2(201.66,77.77)
  BOTTOM w0.102: v2(201.66,77.77) 201.65,77.77 201.24,78.18 200.06,78.18 199.77,77.88 195.67,77.88 194.05,79.5 194.05,82.22 193.67,82.59 193.67,83.34 193.13,83.89 193.13,85.29 190.56,87.86 180.08,87.86 178.8,89.14 159.83,89.14 158.77,88.08 146.19,88.08 144.94,89.33 138.99,89.33 138.49,89.82 138.49,90.97 138.55,91.03 138.73,91.03 C306.2
DPC_LANE_N2_C: length 0.9
  BOTTOM w0.102: C306.1 R263.1
DPC_LANE_N3: length 75.2
  TOP w0.102: v2(202.19,78.62) 202.04,78.48 202.04,78.27 202.13,78.19 202.36,78.19 202.52,78.34 202.52,78.34 202.53,78.35 202.67,78.35 202.73,78.42 202.73,78.71 202.82,78.79 203.24,78.79 203.35,78.68 203.35,78.59 203.25,78.49 UV8.A10
  BOTTOM w0.102: v2(202.19,78.62) 201.97,78.84 201.97,78.99 201.71,79.25 200.41,79.25 200.17,79.01 199.74,79.01 199.43,78.7 196.48,78.7 196.46,78.72 195.99,78.72 194.87,79.84 194.87,82.56 194.5,82.93 194.5,83.75 193.96,84.28 193.96,87.06 192.15,88.87 182.53,88.87 181.44,89.95 v4(181.19,89.95) 159.48,89.95 158.42,88.89 146.53,88.89 145.27,90.15 140.51,90.15 140.36,90.3 140.36,90.5 C301.2
DPC_LANE_N3_C: length 0.9
  BOTTOM w0.102: R266.1 C301.1
DPC_LANE_P0: length 81.5
  TOP w0.102: v2(200.05,75.8) 200.05,75.21 200.23,75.03 201.72,75.03 202.86,76.17 203.29,76.17 UV8.B7
  BOTTOM w0.102: v2(200.05,75.8) 199.85,76 194.89,76 191.25,79.63 191.25,84.46 189.81,85.9 179.41,85.9 178.01,87.29 160.6,87.29 159.54,86.23 151.25,86.23 150.85,85.83 145.83,85.83 144.19,87.47 136.49,87.47 134.73,89.23 134.73,90.59 C302.2
DPC_LANE_P0_C: length 0.9
  BOTTOM w0.102: C302.1 R259.1
DPC_LANE_P1: length 78.2
  TOP w0.102: UV8.B8 203.38,76.91 202.99,76.91 202.33,76.24 201.89,76.24 v2(201.82,76.18)
  BOTTOM w0.102: C297.2 136.5,90.59 136.5,89.48 137.69,88.29 144.52,88.29 145.76,87.05 159.2,87.05 160.26,88.11 178.35,88.11 179.64,86.82 189.63,86.82 189.65,86.8 190.11,86.8 192.07,84.85 192.07,80.03 195.28,76.82 200.81,76.82 201.27,76.36 201.65,76.36 v2(201.82,76.18)
DPC_LANE_P1_C: length 0.9
  BOTTOM w0.102: C297.1 R253.1
DPC_LANE_P2: length 76.3
  TOP w0.102: v2(201.07,77.77) 201.17,77.68 201.17,77.31 201.35,77.13 201.66,77.13 201.67,77.13 201.98,77.13 201.99,77.13 202.18,77.13 202.59,77.54 203.36,77.54 UV8.B9
  BOTTOM w0.102: C304.2 138.28,90.59 138.28,89.74 138.9,89.12 144.85,89.12 146.1,87.87 158.86,87.87 159.92,88.93 178.71,88.93 179.99,87.65 190.47,87.65 192.92,85.21 192.92,83.8 193.46,83.26 193.46,82.51 193.84,82.13 193.84,79.42 195.58,77.67 199.86,77.67 200.15,77.97 200.87,77.97 v2(201.07,77.77)
DPC_LANE_P2_C: length 0.9
  BOTTOM w0.102: C304.1 R257.1
DPC_LANE_P3: length 75.1
  TOP w0.102: v2(201.61,78.62) 201.84,78.39 201.84,78.18 202.04,77.98 202.45,77.98 202.6,78.13 202.61,78.13 202.61,78.14 202.96,78.14 203.03,78.21 203.38,78.21 UV8.B10
  BOTTOM w0.102: C300.2 140.15,90.5 140.15,90.22 140.42,89.94 145.19,89.94 146.44,88.69 158.51,88.69 159.57,89.75 180.89,89.75 180.91,89.73 181.38,89.73 182.44,88.67 192.06,88.67 193.76,86.97 193.76,84.19 194.29,83.66 194.29,82.84 194.66,82.47 194.66,79.76 195.92,78.49 v4(196.15,78.49) 199.52,78.49 199.83,78.8 200.26,78.8 200.49,79.04 201.63,79.04 201.76,78.91 201.76,78.77 v2(201.61,78.62)
DPC_LANE_P3_C: length 0.9
  BOTTOM w0.102: C300.1 R265.1
DSWODVREN: length 6.8
  BOTTOM w0.076: UC1.AW7 166.95,51.24 166.95,50.74 166.78,50.57 166.78,49.84 v1(167.57,49.04) 168.51,48.11 169.12,48.11 169.72,47.51 169.72,46.77 RC78.1
EC5048_TX: length 63
  TOP w0.102: UE1.B2 v2(258.37,69.33) ; JDEG1.9 298.57,36.63 298.77,36.43 v1(298.77,35.15) v2(299.34,34.58) RE74.2
  IN1 w0.089: v2(258.37,69.33) 259.58,69.33 261.1,67.82 261.1,65.46 262.87,63.68 262.87,60.22 268.94,54.16 271.25,54.16 284.64,40.77 291.82,40.77 298,34.58 v2(299.34,34.58)
EC_32KHZ_MEC5085: length 56.4
  TOP w0.102: v2(248.01,45.88) 248.01,46.9 247.61,47.29 247.61,49.85 250.12,52.37 v1(250.12,54.53) 250.12,56.06 248.96,57.23 248.96,58.8 249.59,59.44 249.74,59.44 250.42,60.11 250.42,60.22 250.87,60.67 250.87,60.67 UE1.B35 ; v2(262.29,46.4) 262.44,46.55 UE2.B2 ; v2(250.72,26.2) 250.28,26.2 250.17,26.3 UZ11.2
  IN4 w0.089: v2(262.29,46.4) 261.83,46.86 253.64,46.86 253.11,46.33 248.45,46.33 v2(248.01,45.88)
  BOTTOM w0.102: v2(248.01,45.88) 247.52,45.4 247.52,40.8 248.17,40.16 248.17,35.25 251.01,32.41 251.01,31.86 251.75,31.12 251.75,29.91 251.9,29.76 251.9,27.38 v2(250.72,26.2)
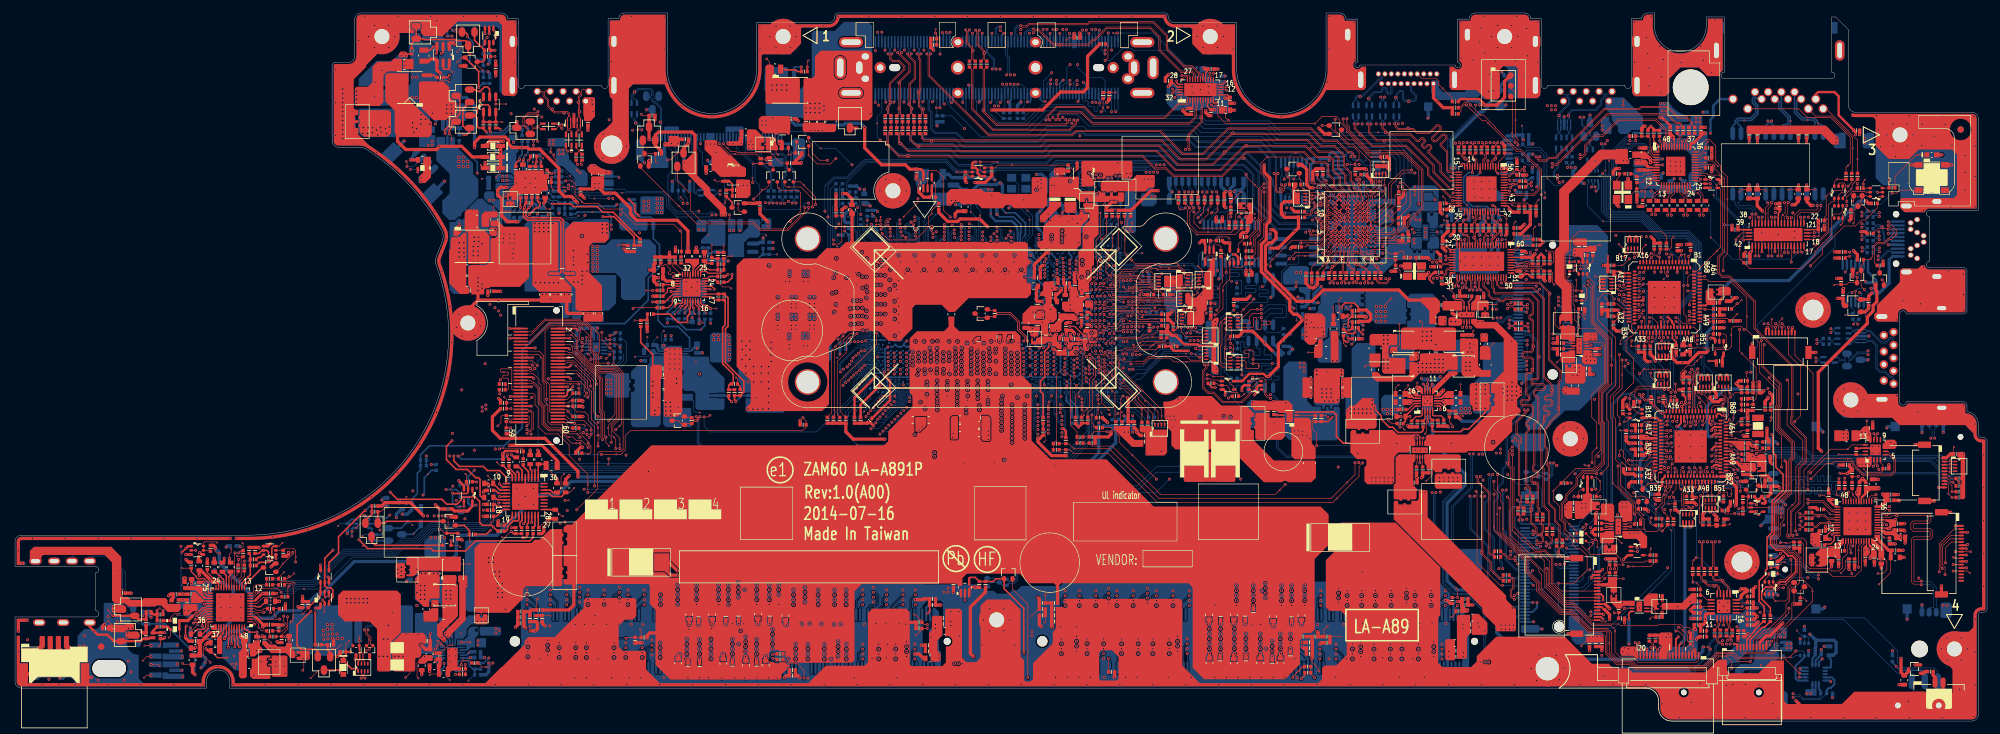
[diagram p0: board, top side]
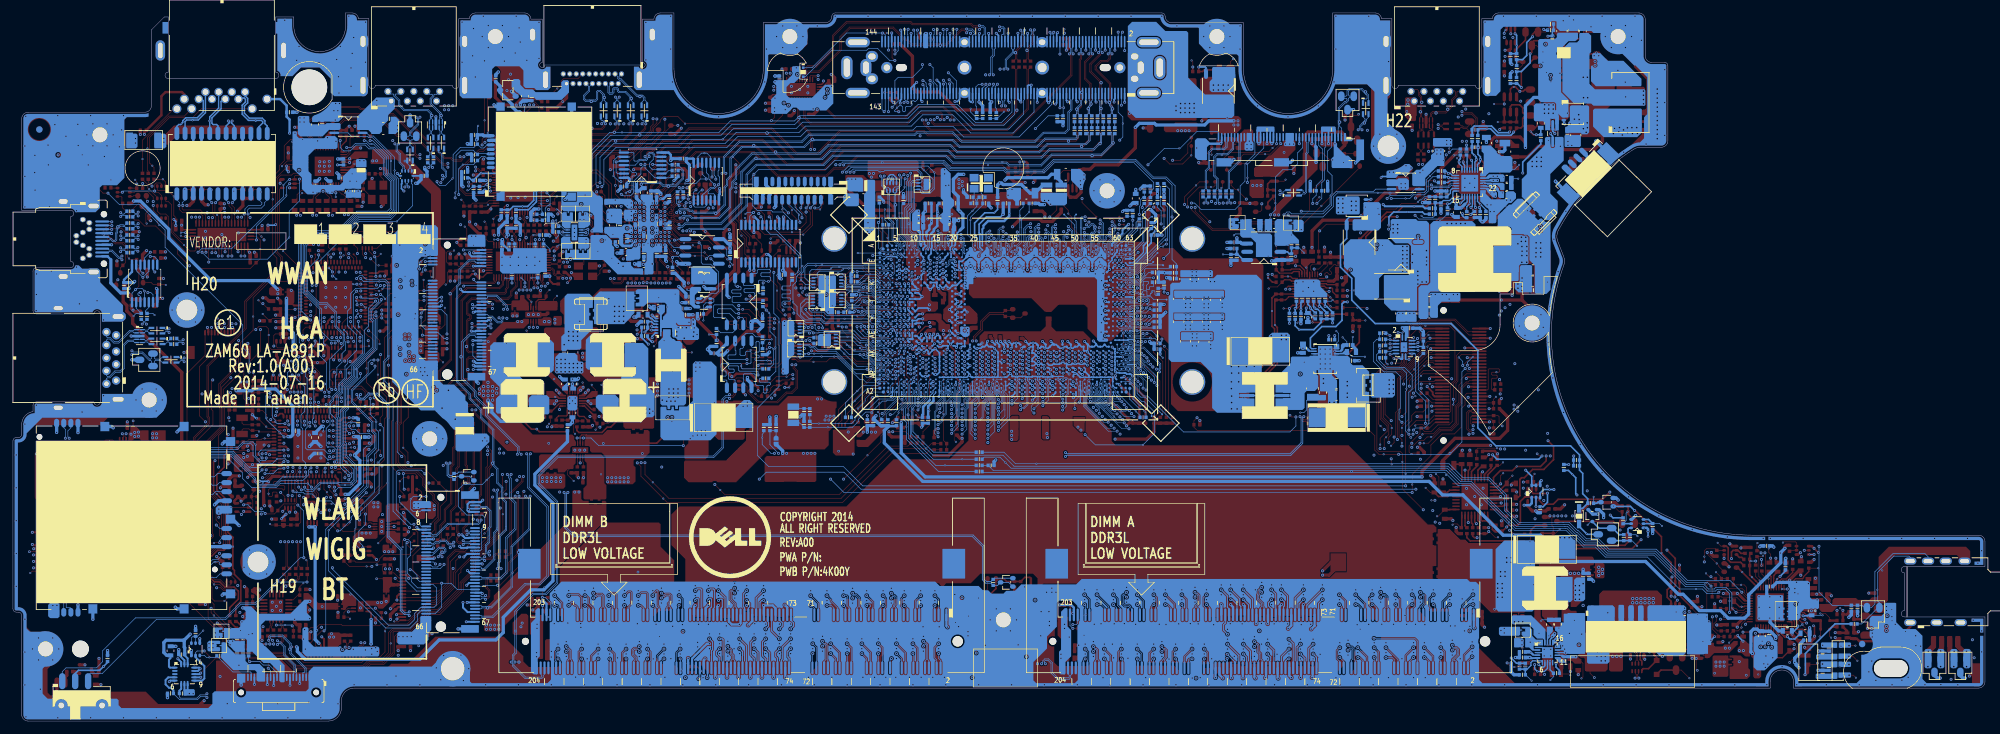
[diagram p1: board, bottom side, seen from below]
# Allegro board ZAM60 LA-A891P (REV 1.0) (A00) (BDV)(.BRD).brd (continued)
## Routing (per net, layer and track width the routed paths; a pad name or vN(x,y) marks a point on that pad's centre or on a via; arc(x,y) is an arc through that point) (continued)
EDP_BIA_PWM: length 76.8
  TOP w0.102: DV1.3 117.8,82.64 v1(117.99,82.45) 118.42,82.02 121.09,82.02 121.41,81.7 121.41,78.84 119.8,77.23 v2(119.8,77.22)
  IN2 w0.122: v2(166.02,84.73) 164.36,86.38 152.38,86.38 149.79,83.79 147.95,83.79 147.7,83.54 147.7,83.22 147.19,82.71 144.02,82.71 141.41,85.32 133.28,85.32 132.84,84.87 128.58,84.87 125.79,82.08 125.79,80.11 123.38,77.7 120.28,77.7 v2(119.8,77.22)
  BOTTOM w0.076: UC1.B8 165.95,72.93 165.95,74.2 167,75.25 167,76.26
  BOTTOM w0.102: v2(166.02,84.73) 166.02,83.7 166.37,83.35 166.37,79.92 167,79.29 167,76.26
EDP_COMP: length 7.3
  TOP w0.076: RC133.2 156.22,68.55 v1(156.04,68.73)
  TOP w0.508: v2(159.78,72.41) 159.34,72.41 157.53,70.6 RC133.2
  BOTTOM w0.254: v2(159.78,72.41) UC1.D20
EDP_CPU_AUX: length 43.3
  IN1 w0.089: v2(143.62,76.18) 143.29,76.51 143.17,76.51 142.88,76.8 142.88,78.21 140.94,80.15 140.94,84.54 139.32,86.16 131.71,86.16 128.48,82.93 118.38,82.93 116.88,81.42 116.88,80.34 v2(117.12,80.1)
  BOTTOM w0.081: 144.06,75.35 144.06,75.34 144.07,75.33 144.07,74.21 143.75,73.89 143.52,73.89 143.25,73.62 143.25,73.39 143.53,73.11 UC1.B45
  BOTTOM w0.102: CV2.1 116.96,80.73 116.96,80.26 v2(117.12,80.1) ; 144.06,75.35 144.06,76.27 143.97,76.35 143.79,76.35 v2(143.62,76.18)
EDP_CPU_AUX#: length 43.5
  IN1 w0.089: v2(143.62,76.77) 143.53,76.68 143.24,76.68 143.05,76.87 143.05,78.28 141.11,80.23 141.11,84.61 139.39,86.33 131.64,86.33 128.41,83.1 118.31,83.1 116.71,81.49 116.71,80.28 v2(116.53,80.1)
  BOTTOM w0.081: 144.27,75.35 144.27,75.33 144.26,75.32 144.26,74.13 143.89,73.76 143.89,73.38 143.78,73.27 143.63,73.27 143.53,73.37 UC1.A45
  BOTTOM w0.102: v2(143.62,76.77) 143.83,76.56 144.06,76.56 144.27,76.36 144.27,75.35 ; CV1.1 116.76,80.69 116.76,80.33 v2(116.53,80.1)
EDP_CPU_AUX#_C: length 9.2
  BOTTOM w0.102: CV1.2 116.73,82.31 116.73,84.89 115.1,86.52 115.1,89.51 114.96,89.65 JEDP1.33
EDP_CPU_AUX_C: length 9.2
  BOTTOM w0.102: CV2.2 116.94,82.31 116.94,84.97 115.31,86.61 115.31,89.57 115.46,89.72 JEDP1.34
EDP_CPU_HPD: length 99.5
  TOP w0.102: v2(113.98,83.29) v1(113.98,84.01)
  IN3 w0.122: v2(171,77.09) 171,78.33 165.33,84.01 165.33,86.74 166.98,88.4 166.98,94.06 164.57,96.47 158.87,96.47 158.01,95.61 157.27,95.61 152.94,91.29 147.95,91.29 145.41,88.75 129.38,88.75 123.92,83.29 v2(113.98,83.29)
  BOTTOM w0.076: UC1.D6 167.64,71.72 167.94,72.02 168.13,72.02 168.34,72.23 168.34,72.33 168.54,72.52 169.94,72.52 170,72.59 170.45,72.59 171,73.15 171,76.26
  BOTTOM w0.102: RC141.2 170.86,77.23 v2(171,77.09) 171,76.26 ; v2(113.98,83.29) 113.97,83.3 113.97,86.09 111.46,88.6 JEDP1.26
EDP_CPU_LANE_N0: length 40.4
  IN1 w0.089: v2(118.91,80.05) 118.66,80.3 118.66,81.14 119.61,82.1 128.61,82.1 132.01,85.5 138.69,85.5 140.27,83.92 140.27,79.64 142.24,77.67 142.24,76.35 142.89,75.7 142.89,75.01 143.17,74.73 143.36,74.73 143.46,74.64 143.48,74.64 143.61,74.51 v2(143.61,74.45)
  BOTTOM w0.081: UC1.C45 143.43,72.31 143.43,72.5 143.03,72.9 143.03,74.05 143.04,74.06 143.04,74.08
  BOTTOM w0.102: 143.04,74.08 143.04,74.27 143.22,74.45 v2(143.61,74.45) ; v2(118.91,80.05) 118.7,80.27 118.7,80.69 CV4.1
EDP_CPU_LANE_N0_C: length 10.9
  BOTTOM w0.102: JEDP1.36 116.46,89.66 116.32,89.52 116.32,88.54 117.1,87.76 118.7,87.76 119.2,87.26 119.2,84.28 118.72,83.79 118.72,82.31 CV4.2
EDP_CPU_LANE_N1: length 40.3
  IN1 w0.089: v2(120.69,80.1) 120.5,79.92 120.5,79.75 120.6,79.65 121.35,79.65 121.78,80.09 121.78,80.21 121.33,80.67 121.33,81.01 121.56,81.24 121.9,81.24 122.34,80.8 122.49,80.8 122.69,81 122.92,81 123.01,81.09 123.01,81.4 123.2,81.58 123.61,81.58 123.8,81.4 123.8,81.09 123.89,81 124.15,81 124.24,81.09 124.24,81.4 124.43,81.58 124.84,81.58 125.03,81.4 125.03,81.09 125.12,81 125.38,81 125.47,81.09 125.47,81.4 125.66,81.58 126.07,81.58 126.26,81.4 126.26,81.09 126.35,81 128.33,81 132.33,85 137.46,85 139.08,83.39 139.08,79.91 141.03,77.95 141.03,75.21 141.27,74.97 141.5,74.97 141.69,75.16 141.71,75.16 141.84,75.3 v2(141.84,75.38)
  BOTTOM w0.081: UC1.A47 142.41,73.43 142.34,73.36 142.22,73.36 142.1,73.49 142.1,73.86 142.49,74.25 142.49,74.91 142.3,75.09 142.13,75.09 142,75.22 v2(141.84,75.38)
  BOTTOM w0.102: CV6.1 120.66,81.05 120.51,80.9 120.51,80.28 v2(120.69,80.1)
EDP_CPU_LANE_N1_C: length 10.9
  BOTTOM w0.102: CV6.2 120.5,82.3 120.5,85.12 120.03,85.59 120.03,88.01 119.45,88.59 117.57,88.59 117.32,88.84 117.32,89.52 117.46,89.65 JEDP1.38
EDP_CPU_LANE_P0: length 40.5
  IN1 w0.089: v2(118.32,80.05) 118.49,80.22 118.49,81.22 119.54,82.27 128.53,82.27 131.94,85.67 138.76,85.67 140.44,83.99 140.44,79.71 142.41,77.74 142.41,76.42 143.06,75.77 143.06,75.08 143.24,74.9 143.51,74.9 v2(143.61,75)
  BOTTOM w0.081: 142.83,74.08 142.83,74.07 142.84,74.06 142.84,72.66 UC1.B46
  BOTTOM w0.102: v2(118.32,80.05) 118.49,80.22 118.49,80.73 CV3.1 ; 142.83,74.08 142.83,74.36 143.13,74.65 143.26,74.65 v2(143.61,75)
EDP_CPU_LANE_P0_C: length 10.9
  BOTTOM w0.102: CV3.2 118.51,82.31 118.51,83.88 119,84.37 119,87.17 118.61,87.55 117.01,87.55 116.11,88.46 116.11,89.5 115.96,89.65 JEDP1.35
EDP_CPU_LANE_P1: length 40.4
  IN1 w0.089: v2(141.84,74.8) 141.2,74.8 140.86,75.14 140.86,77.88 138.9,79.84 138.9,83.32 137.39,84.83 132.4,84.83 128.4,80.83 126.28,80.83 126.09,81.02 126.09,81.33 126,81.41 125.73,81.41 125.64,81.33 125.64,81.02 125.45,80.83 125.05,80.83 124.86,81.02 124.86,81.33 124.77,81.41 124.5,81.41 124.41,81.33 124.41,81.02 124.22,80.83 123.82,80.83 123.63,81.02 123.63,81.33 123.54,81.41 123.27,81.41 123.18,81.33 123.18,81.02 123,80.83 122.76,80.83 122.56,80.63 122.27,80.63 121.83,81.07 121.64,81.07 121.5,80.94 121.5,80.74 121.95,80.29 121.95,80.02 121.42,79.48 120.53,79.48 120.33,79.68 120.33,79.89 120.1,80.12 v2(120.1,80.1)
  BOTTOM w0.081: v2(141.84,74.8) 141.95,74.9 142.23,74.9 142.3,74.83 142.3,74.33 141.91,73.94 141.91,73.41 142.41,72.91 UC1.B47
  BOTTOM w0.102: v2(120.1,80.1) 120.3,80.31 120.3,80.86 120.11,81.05 CV5.1
EDP_CPU_LANE_P1_C: length 11
  BOTTOM w0.102: JEDP1.37 116.96,89.67 117.11,89.51 117.11,88.75 117.48,88.38 119.36,88.38 119.82,87.92 119.82,85.51 120.29,85.04 120.29,82.31 CV5.2
EN: length 11.8
  TOP w0.102: v1(214.72,45.06) 214.5,45.28 PR113.2
  TOP w0.203: PU100.6 220.17,48.71 220.28,48.61 v2(220.28,48.17) ; PU100.20 216.42,48.71 215.44,47.73
  TOP w0.254: PC119.1 214.87,46.39 PR113.2 ; PC119.1 v2(215.58,47.1) ; PC119.1 214.87,47.16 215.44,47.73
  IN3 w0.254: v2(215.58,47.1) 216.14,47.66 219.77,47.66 v2(220.28,48.17)
EN_+V1.05SP: length 19.3
  TOP w0.254: v2(205.97,59.28) 206.13,59.12 PR303.1 ; RZ41.2 RZ42.2 v1(202.92,46.32) v2(203.55,46.95)
  IN4 w0.254: v2(205.97,59.28) 206.39,59.28 207.07,58.6 207.07,50.47 v2(203.55,46.95)
  BOTTOM w0.254: PU300.1 205.47,60.01 205.97,59.51 v2(205.97,59.28)
EN_DK_PWRBAR: length 3.1
  TOP w0.254: PR857.1 PR874.1 74.22,33.51 74.51,33.22 PU800.17
EN_DOCK_PWR_BAR: length 202.5
  TOP w0.102: v2(251.7,62.43) 251.87,62.26 UE1.B37 ; PR857.2 v2(72.37,32.62)
  IN2 w0.122: v2(72.37,32.62) 72.56,32.8 75.18,32.8 79.13,36.75 85.26,36.75 87.38,34.62 223.34,34.62 224.95,36.23 228.65,36.23 229.47,37.06 231.58,37.06 234.44,39.92 234.44,44.93 241.79,52.28 246.9,52.28 251.54,56.92 251.54,60.78 251.83,61.06 251.83,62.31 v2(251.7,62.43)
  BOTTOM w0.102: v2(251.7,62.43) 251.7,62.74 v1(251.44,62.99)
EN_I2S_NB_CODEC#: length 250.6
  TOP w0.102: UE1.B36 v2(251.37,61.8) ; v2(37,14.97) 37,15.09 36.73,15.37 UA1.1
  IN2 w0.122: v2(37,14.97) 37,20.23 37.46,20.68 37.46,24.48 39.05,26.07 40.95,26.07 41.78,26.9 43.55,26.9 44.52,27.87 52.09,27.87 53.27,29.06 57.93,29.06 61.03,32.16 61.03,32.55 62.36,33.88 63.64,33.88 64.34,34.58 64.68,34.58 69,38.9 70.23,38.9 71.69,37.44 75.37,37.44 75.81,37 85.36,37 87.49,34.87 223.24,34.87 224.85,36.49 226.95,36.49 228,37.54 231.68,37.54 234.19,40.04 234.19,45.03 241.68,52.53 245.97,52.53 247.39,53.95 247.39,57.14 251.37,61.11 251.37,61.79 v2(251.37,61.8)
  BOTTOM w0.102: v1(251.22,60.91) 251.37,61.07 v2(251.37,61.8)
EN_INVPWR: length 214.2
  TOP w0.102: RE55.2 251.66,42.02 v2(251.95,42.31) v1(252.49,42.31) 252.75,42.31 252.84,42.21 UE2.A25 ; v2(111.76,79.98) 111.76,79.03 112.03,78.76 QV2.2
  IN2 w0.122: v2(111.76,79.98) 112.14,79.6 113.79,79.6 114.58,80.39 114.58,81.05 115.38,81.85 121.18,81.85 123.82,84.49 123.82,86.52 126.43,89.13 146.43,89.13 147.7,90.4 156.23,90.4 157.31,91.48 182.43,91.48 183.26,90.65 203.9,90.65 204.61,91.37 219.75,91.37 222.15,93.77 233.73,93.77 239.07,88.43 239.07,85.42 240.95,83.54 240.95,80.27 245.3,75.92 254.72,75.92 255.61,75.03 258.85,75.03 263.16,70.72 263.16,65.01 263.47,64.7 263.47,55.88 264.26,55.09 264.26,54.54 264.08,54.37 264.08,53.29 263.26,52.47 263.26,50.38 260.11,47.24 260.11,45.42 259.7,45 258.7,45 257.17,43.47 254.49,43.47 253.49,42.47 252.12,42.47 v2(251.95,42.31)
EN_LCDPWR: length 4.1
  TOP w0.102: DV3.1 120.8,88.82 120.66,88.68 RV3.2 120.16,87.85 119.9,87.58 v1(119.52,87.58) 119.5,87.59 UV24.3
ENVDD_PCH: length 207.3
  TOP w0.102: v2(125.54,86.72) 124.33,86.72 123.19,87.86 123.19,89.13 122.65,89.66 DV3.3 ; UE2.A7 259.69,48.34 259.5,48.52 259.5,51.95 259.66,52.11 259.66,54.07 v2(260.04,54.46) ; v2(167.94,74.53) 168.65,75.24 v1(168.65,76.94) RC139.2
  IN2 w0.122: v2(125.54,86.72) 125.54,87.1 126.81,88.37 146.81,88.37 148.08,89.64 163.7,89.64 v2(164.56,90.49) 182.27,90.49 182.88,89.89 204.28,89.89 205,90.61 220.16,90.61 222.51,92.96 233.41,92.96 238.31,88.05 238.31,85.03 240.19,83.16 240.19,79.89 246.19,73.89 255,73.89 259.24,69.64 261.01,69.64 261.56,69.1 261.56,68.18 260.65,67.27 260.65,65.13 262.47,63.3 262.47,56.88 v2(260.04,54.46)
  IN3 w0.122: v2(167.94,74.53) 167.94,77.4 162.62,82.71 162.62,88.56 v2(164.56,90.49)
  BOTTOM w0.076: v2(167.94,74.53) 167.55,74.14 167.55,73.43 167.01,72.89 UC1.C6
ERC1: length 2.2
  TOP w0.254: PC815.1 79.61,38.97 79.85,38.73 PU800.3
ERC2: length 2.2
  TOP w0.254: PC817.1 74.26,35.67 74.71,35.22 PU800.13
ERC3: length 4
  TOP w0.102: PC816.1 73.9,37.08 v1(73.04,37.95)
  TOP w0.254: PC816.1 74.93,35.72 PU800.12
EXPRESS_DET#: length 5.5
  TOP w0.102: UE1.B15 251.87,69.57 v2(251.69,69.39) ; T97.1 251.52,73.14 v2(251.52,72.3)
  IN1 w0.089: v2(251.69,69.39) 251.87,69.57 251.87,71.95 v2(251.52,72.3)
F-IMAX: length 5.3
  TOP w0.102: v2(102.85,64.12) 102.85,63.78 v1(101.97,62.89)
  TOP w0.203: v2(102.85,64.12) 103.11,64.12 103.55,64.56 PU500.10
  BOTTOM w0.254: PR503.1 102.07,63.47 102.07,63.47 102.71,64.12 v2(102.85,64.12) PR508.2
FAN1_PWM: length 267
  TOP w0.102: v2(60.58,85.76) 60.58,86.44 v3(60.46,86.55) ; UE2.A24 252.91,42.71 v2(252.73,42.89) 252.56,42.72 251.59,42.72 RE48.2
  IN1 w0.089: v2(65.4,31.72) 65.6,31.92 65.6,32.38 65.39,32.59 64.49,32.59 63.79,33.29 63.79,36.52 62.39,37.92 62.39,40.96 64.07,43.54 66.04,47.47 67.5,52.04 68.21,55.22 73,60.01 73,63.47 67.17,69.3 67.17,76.12 66.76,76.53 66.76,78.45 60.58,84.63 v2(60.58,85.76)
  IN2 w0.122: v2(65.4,31.72) 65.4,31.03 66.8,29.63 71.69,29.63 72.95,28.36 76.64,28.36 77.31,27.69 78.77,27.69 80.35,29.28 82.33,29.28 84.29,31.25 230.23,31.25 230.94,31.95 232.96,31.95 243.53,42.53 250.17,42.53 251.19,43.54 252.55,43.54 252.73,43.35 v2(252.73,42.89)
  BOTTOM w0.102: v2(60.58,85.76) 61.6,85.76 JFAN1.2
FAN1_TACH: length 269.7
  TOP w0.102: v2(249.79,44.88) 249.03,44.88 RE51.2 248.04,44.93 v1(248.02,44.96) ; UE2.B22 254.72,44.46 254.72,44.46 255.4,44.46 v2(255.86,44.93)
  IN1 w0.089: v2(249.79,44.88) 251.76,44.88 251.95,45.07 254.7,45.07 254.98,45.34 255.45,45.34 v2(255.86,44.93) ; v2(66.01,31.72) 65.82,31.92 65.82,32.47 65.48,32.8 64.58,32.8 64.01,33.38 64.01,36.61 62.61,38.01 62.61,40.87 64.26,43.41 66.29,47.41 67.61,51.54 68.49,55.19 73.21,59.92 73.21,63.59 67.96,68.84 67.94,68.84 67.4,69.39 67.4,76.24 66.98,76.66 66.98,78.57 61.08,84.47 v2(61.08,85.32)
  IN2 w0.122: v2(249.79,44.88) 245.5,44.88 232.82,32.2 230.84,32.2 230.13,31.5 84.16,31.5 82.19,29.53 80.25,29.53 78.66,27.94 77.42,27.94 76.75,28.61 73.15,28.61 71.88,29.88 66.99,29.88 66.01,30.86 v2(66.01,31.72)
  BOTTOM w0.102: v2(61.08,85.32) 62.92,85.32 JFAN1.3
FB_3V: length 2.5
  TOP w0.203: PR102.2 PR100.2 218.68,46.86 PU100.4
FB_5V: length 4.9
  TOP w0.102: PR101.1 217.6,46.32 218.09,45.82 218.09,44.63 v1(217.89,44.42)
  TOP w0.203: PR104.1 PR101.1 217.88,46.7 PU100.2
FB_+V1.05SP: length 6.4
  TOP w0.102: v1(205.5,61.42) 205.31,61.23 PR309.2
  TOP w0.254: v2(207.1,60.15) 206.89,59.94 205.88,59.94 PR309.2
  BOTTOM w0.254: PU300.4 205.67,61.36 206.08,61.77 PR310.1 PR307.2 206.66,60.58 v2(207.1,60.15)
FFS_INT2: length 161.9
  TOP w0.102: v2(275.19,10.84) 274.23,9.88 266.38,9.88 265.61,10.65 262.95,10.65 260.91,8.61 250.64,8.61 249.82,9.43 247.86,9.43 246.69,10.59 246.69,13.72 246.09,14.33 243.52,14.33 240.6,17.25 239.14,17.25 235.9,20.48 235.9,22.64 235.52,23.02 235.52,23.49 229.93,29.08 v1(229.93,29.77) 229.93,33.63 229.61,33.95 229.61,35.22 229.11,35.72 v2(229.11,38.14)
  IN3 w0.122: v2(174.29,69.51) 174.74,69.95 179.9,69.95 181.43,68.42 184.74,68.42 185.56,67.6 187.89,67.6 188.75,66.74 190.68,66.74 196.15,61.27 196.15,47.99 196.35,47.79 196.35,42.47 199.08,39.75 205.81,39.75 206.07,39.5 214.13,39.5 217.02,36.61 223.39,36.61 225.59,38.81 228.43,38.81 v2(229.11,38.14)
  BOTTOM w0.076: 173.36,69.51 171.42,69.51 170.85,68.94 170.48,68.94 UC1.G2
  BOTTOM w0.102: 173.36,69.51 v2(174.29,69.51) RC158.2 ; v2(275.19,10.84) 276.28,10.84 276.53,10.59 QN1.2
  BOTTOM w0.305: QN1.2 276.53,9.88 275.17,8.52 275.17,6.59 275.5,6.26 UN1.9
FFS_INT2_Q: length 9.9
  BOTTOM w0.102: QN1.3 275.15,10.14 274.86,9.85 v1(274.41,9.85) 273.46,9.85 RN1.2 270.75,7.59 268.06,7.59 267.94,7.48 JSATA1.19
FWP#: length 13.8
  TOP w0.102: RE82.2 RE81.2 271.4,48.03 v2(271.4,46.9) 271.4,46.52 v1(271.28,46.41) ; UE2.B65 262.79,44.96 v2(262.78,44.97)
  IN3 w0.122: v2(271.4,46.9) 270.28,48.02 267.26,48.02 264.21,44.97 v2(262.78,44.97)
GC6_EVENT#_Q: length 18.9
  TOP w0.102: v2(182.33,66.97) 182.33,67.71 182.67,68.05 RPC16.7
  IN1 w0.089: v2(167.24,65.71) 167.63,65.31 170.09,65.31 171.15,66.37 173.49,66.37 173.76,66.65 180.85,66.65 180.98,66.52 181.86,66.52 182.31,66.97 v2(182.33,66.97)
  BOTTOM w0.081: v2(167.24,65.71) 167.24,65.52 UC1.R6
  BOTTOM w0.102: v1(182.71,66.42) 182.33,66.8 v2(182.33,66.97)
GFB: length 4.8
  TOP w0.102: v1(110.7,66.88) 110.45,67.13 109.36,67.13 108.63,67.86 PR532.2
  TOP w0.203: PU500.23 107.17,68.03 107.38,68.24 108.25,68.24 PR532.2
GPIO_PSID_SELECT: length 223.6
  TOP w0.102: v2(255.2,72.24) 255.88,72.24 v1(256,72.12) 256.12,71.99 UE1.A6 ; PU1.6 73.93,105.34 v2(74.29,105.7)
  IN1 w0.089: v2(80.77,89.65) 80.37,90.05 78.92,90.05 75.24,93.73 75.24,95.86 74.67,96.43 74.67,105.32 v2(74.29,105.7)
  IN2 w0.122: v2(80.77,89.65) 81.47,88.96 81.47,88.35 93.14,76.68 100.96,76.68 101.09,76.81 103.63,76.81 104.71,77.89 106.68,77.89 107.63,78.84 114.55,78.84 115.39,79.68 115.39,80.57 115.81,80.99 121.46,80.99 125.98,85.51 125.98,87.1 127,88.11 146.94,88.11 148.21,89.38 174.82,89.38 175.58,90.14 182.24,90.14 183,89.38 204.15,89.38 205.13,90.36 220.29,90.36 222.64,92.71 233.3,92.71 237.11,88.9 237.11,84.11 239.01,82.21 239.01,80.68 246.38,73.32 254.12,73.32 v2(255.2,72.24)
GPU_GC6_FB_EN: length 16.3
  TOP w0.081: 173.36,70.46 173.23,70.46 172.64,69.87 169.94,69.87 169.48,69.4 169.48,68.7 169.15,68.37 168.46,68.37 v2(167.72,67.63)
  TOP w0.102: RPC3.8 181.09,68.93 179.79,70.23 v1(177.02,70.23) 176.79,70.46 173.36,70.46
  BOTTOM w0.081: UC1.L6 167.5,67.41 v2(167.72,67.63)
GPU_SMBCLK: length 14.7
  TOP w0.102: v2(261.53,38.58) 261.94,38.17 UE2.B49 ; v2(261.89,50.87) 261.76,51 261.71,51.05 261.71,51.16 261.85,51.29 RPE3.4
  IN1 w0.089: v2(261.89,50.87) 261.7,50.68 261.7,50.55 262,50.26 262,47.4 261.69,47.09 261.69,39.64 261.88,39.46 261.88,38.92 v2(261.53,38.58)
GPU_SMBDAT: length 14.6
  TOP w0.102: UE2.B48 261.44,38.1 261.11,38.43 261.11,38.86 v2(261.48,39.23) ; RPE3.3 261.35,51.25 261.48,51.12 261.48,51.05 v2(261.3,50.87)
  IN1 w0.089: v2(261.3,50.87) 261.49,50.68 261.49,50.47 261.78,50.17 261.78,47.49 261.48,47.18 v2(261.48,39.23)
GREEN_DOCK: length 88.2
  TOP w0.102: UV8.M7 210.86,76.54 211.64,77.32 212.02,77.32 RV77.1 214.98,80.28 214.98,82.01 v2(214.36,82.64)
  BOTTOM w0.102: JDOCK1.59 148.45,96.1 148.58,95.97 148.58,93.8 150.84,91.54 156.44,91.54 159.25,94.36 164.42,94.36 166.18,92.6 182.72,92.6 183.71,91.62 193.41,91.62 v1(195.07,89.95) 212.14,89.95 214.65,87.45 214.65,82.92 v2(214.36,82.64)
H_CATERR#: length 6.1
  BOTTOM w0.076: 130.69,67.89 130.81,67.78 131.77,67.78 132.02,67.53 132.32,67.53 132.48,67.69 132.48,67.95 132.65,68.12 133.2,68.12 UC1.K61
  BOTTOM w0.102: RC114.2 129.21,69.38 129.72,68.87 129.72,68.87 130.31,68.27 130.31,68.27 130.69,67.89
H_CPU_SVIDALRT#: length 7.7
  BOTTOM w0.102: RC207.1 127.94,65.82 128.14,65.82 128.27,65.95 128.27,66.45 128.34,66.52 128.64,66.52 v1(128.71,66.45) 128.71,66.24 128.79,66.16 128.95,66.16 129,66.12 129,65.86 129.06,65.8 129.44,65.8 129.51,65.87 129.51,66.46 129.59,66.54 130.05,66.54 130.19,66.4 130.19,66.25 130.18,66.25 130.3,66.13 130.67,66.13 130.87,66.33 131.23,66.33 131.3,66.41 131.3,66.69 131.39,66.78 132.51,66.78 UC1.L62
H_CPUPWRGD: length 86.2
  TOP w0.102: v2(74.91,50.58) 74.84,50.66 RC103.1
  IN1 w0.089: v2(131.7,77.44) 131.7,78.02 130.87,78.84 129.73,78.84 129.32,78.43 125.44,78.43 125.28,78.28 116.42,78.28 115.15,77.01 101.47,77.01 96.57,72.11 96.57,63.83 95.36,62.62 94.09,62.62 90.76,59.29 90.76,57.31 89.98,56.52 89.98,55.54 87.94,53.5 87.94,51.66 87.35,51.07 75.4,51.07 v2(74.91,50.58)
  BOTTOM w0.081: UC1.C61 133.78,72.69 133.8,72.71 133.8,73.03 133.94,73.17 134.29,73.17 134.39,73.27 134.39,73.65 133.71,74.33 133.35,74.33 132.39,75.29
  BOTTOM w0.102: RC123.1 CC83.1 v2(131.7,77.44) v1(131.7,76.68) 131.7,75.98 132.39,75.29
H_PROCHOT#: length 251.8
  TOP w0.102: PR534.1 102.98,71.81 PC514.2 102.98,75.64 v2(102.82,75.8) 101.78,76.84 95.8,76.84 93.47,79.17 91.03,79.17 90.16,80.03 87.92,80.03 86.55,81.41 86.55,83.1 86.1,83.54 v2(85.09,83.54) ; UE2.A46 261.69,35.77 v2(261.48,35.56)
  IN1 w0.089: v2(176.96,86.02) 177.43,85.56 193.33,85.56 193.74,85.98 201.91,85.98 202.4,85.5 207.97,85.5 208.4,85.92 213.25,85.92 213.51,86.18 219.55,86.18 220.69,85.04 223.61,85.04 224.11,85.55 228.93,85.55 229.72,84.76 231.07,84.76 234.84,81 234.96,81 240.17,75.78 240.17,65.49 241.43,64.24 242.49,64.24 243.27,63.46 243.27,61.77 246.14,58.9 246.14,57.73 247.63,56.24 248.55,56.24 v2(248.96,55.83) ; v2(102.82,75.8) 103.55,75.8 104.55,76.8 115.25,76.8 116.51,78.05 124.53,78.05 124.63,77.95 v2(125.63,77.95)
  BOTTOM w0.102: PR717.1 84.83,83.29 v2(85.09,83.54) ; CC20.1 RC116.2 RC121.1 124.95,70.7 125.63,71.37 v2(125.63,77.95) 125.63,82.87 126.62,83.87 128.57,83.87 131.3,86.6 143.87,86.6 145.48,84.99 151.19,84.99 151.6,85.39 159.88,85.39 160.94,86.45 176.53,86.45 v2(176.96,86.02) ; v2(248.96,55.83) 249.46,55.83 249.87,55.42 249.87,53.79 252.47,51.2 252.47,49.29 249.36,46.19 249.36,44.82 248.87,44.32 248.87,42.25 250.1,41.02 250.1,36.32 253.45,32.97 254.53,32.97 255.6,34.04 v1(256.61,34.04) 257.42,34.04 258.51,35.12 259.67,35.12 259.89,35.34 261.26,35.34 v2(261.48,35.56)
H_PROCHOT#_R: length 7.8
  BOTTOM w0.076: UC1.K63 132.03,67.82 131.9,67.95 130.99,67.95 130.85,68.1 130.76,68.1 130.39,68.47
  BOTTOM w0.102: RC121.2 126.11,70.02 129.66,70.02 129.91,69.77 v1(129.91,69.32) 129.91,68.95 130.39,68.47
H_THERMTRIP#: length 172.4
  TOP w0.102: v2(248.35,55.83) v1(248.35,53.57) 248.35,51.46 247,50.11 247,47.04 247.32,46.72 247.32,40.44 248.14,39.61 248.14,36.45 249.82,34.77 251.83,34.77 252.17,34.43 252.17,34.31 252.17,34.31 QE4.3
  IN1 w0.089: v2(248.35,55.83) 247.56,55.83 245.87,57.52 245.87,58.84 243.04,61.67 243.04,63.39 242.4,64.02 241.34,64.02 239.92,65.44 239.92,75.68 236.29,79.31 231.73,79.31 231.21,79.83 230.53,79.83 230.01,79.31 224.34,79.31 222.4,81.25 221.99,81.25 217.32,85.93 213.56,85.93 213.34,85.71 208.54,85.71 208.08,85.25 202.34,85.25 201.82,85.76 193.83,85.76 193.42,85.34 177.03,85.34 v2(176.37,86)
  BOTTOM w0.102: RC161.1 RC25.2 128.46,82.32 128.46,83.29 131.51,86.34 143.8,86.34 145.39,84.76 151.29,84.76 151.69,85.17 159.98,85.17 161.04,86.23 176.15,86.23 v2(176.37,86)
H_THERMTRIP#_R: length 13.6
  BOTTOM w0.081: 131.53,74.1 131.57,74.05 132.35,74.05 132.42,73.98 132.42,73.75 132.35,73.67 131.71,73.67 131.63,73.6 131.63,73.38 131.71,73.31 132.37,73.31 132.57,73.11 132.98,73.11 133.14,72.96 133.14,72.73 133.41,72.45 133.41,72.36 133.35,72.3 133.2,72.3 133.13,72.22 133.13,72.06 133.2,71.99 134.17,71.99 134.24,71.92 134.24,71.79 134.15,71.71 UC1.D60
  BOTTOM w0.102: 131.53,74.1 130.55,75.07 130.55,75.98 130.17,76.36 130.17,78.84 128.98,80.03 RC161.2
H_VCCST_PWRGD: length 101.9
  TOP w0.102: UC8.4 141.67,83.46 142.25,82.88 CC24.1 142.25,80.56 RC202.1 141.67,78.98 v1(141.67,78.47) 141.13,77.94 141.13,76.36 139.16,74.4 134.99,74.4 v2(134,75.39) ; RC102.1 74.84,52.62 v2(75.03,52.81)
  IN1 w0.089: v2(75.03,52.81) 75.71,53.49 85.97,53.49 89.37,56.89 89.37,58.65 89.63,58.9 89.63,59.59 90.78,60.74 91.25,60.74 95.37,64.87 95.37,72.62 102.01,79.26 105.99,79.26 106.25,79.01 124.58,79.01 125.69,80.11 132.52,80.11 134.3,78.33 134.3,75.69 v2(134,75.39)
  BOTTOM w0.076: v2(134,75.39) 134,75.16 135.2,73.95 135.2,73.04 135.01,72.86 UC1.B59
H_VCCST_PWRGD_XDP: length 13.3
  TOP w0.102: JXDP1.39 76.9,51.2 76.77,51.33 76.77,54.33 76.64,54.46 75.12,54.46 74.99,54.33 74.99,54.08 75.12,53.95 v1(75.5,53.95) 76.13,53.95 76.26,53.82 76.26,53.62 76.13,53.5 75.5,53.5 75.37,53.37 75.37,53.14 75.5,53.02 76.13,53.02 76.26,52.89 76.26,51.35 76.13,51.23 RC103.2 RC102.2
H_VR_EN: length 69
  TOP w0.102: v2(95.5,63.79) 95.64,63.93 v1(96.99,63.93) PR536.1
  IN1 w0.089: v2(130.22,79.41) 131,79.41 132.39,78.02 132.39,77.38 133.27,76.51 133.27,70.98 v2(133.81,70.45)
  IN4 w0.089: v2(95.5,63.79) 95.5,63.8 95.9,64.19 95.9,71.26 101.16,76.52 114.59,76.52 115.44,75.67 118.93,75.67 120.94,77.67 123.74,77.67 125.78,75.63 125.78,73.67 128.42,71.03 133.22,71.03 v2(133.81,70.45)
  BOTTOM w0.081: UC1.F60 134.11,70.15 v2(133.81,70.45)
  BOTTOM w0.102: RC201.2 130.22,79.73 v2(130.22,79.41)
H_VR_READY: length 54.6
  TOP w0.102: PR539.2 v2(98.54,66.59) v1(97.5,66.59)
  IN1 w0.089: v2(132.33,76.11) 131.76,76.11 130.68,77.19 v2(130.68,78.33) 129.92,78.33 129.03,77.44 124.58,77.44 124.36,77.66 119.17,77.66 117.61,76.1 113.27,76.1 112.96,76.4 104.71,76.4 103.66,75.36 101.71,75.36 100.47,74.11 100.47,68.52 v2(98.54,66.59)
  BOTTOM w0.081: UC1.C59 134.56,72.53 134.56,73.73 132.33,75.96 v2(132.33,76.11)
  BOTTOM w0.102: v2(130.68,78.33) 130.68,79.6 130.49,79.79 130.49,80.62 130.16,80.95 RC201.1 RC199.2
HDD_A_EQ: length 2.7
  TOP w0.102: RN13.2 RN12.1 267.32,17.5 267.06,17.24 UN2.17
HDD_A_EQ2: length 6
  TOP w0.102: v2(266.1,14.59) 266.27,14.43 RN25.2 RN24.2 ; UN2.18 v2(266.9,17.74)
  IN1 w0.089: v2(266.1,14.59) 266.1,16.94 v2(266.9,17.74)
HDD_A_PRE: length 2.8
  TOP w0.102: RN8.1 RN9.2 260.93,17.24 UN2.9
HDD_B_EQ: length 2.7
  TOP w0.102: UN2.19 267.55,18.24 RN14.2 RN16.2
HDD_B_EQ2: length 5.2
  TOP w0.102: v2(261.59,14.72) 261.4,14.53 RN22.2 RN23.2 ; UN2.13 v2(264.04,14.84)
  BOTTOM w0.102: v2(261.59,14.72) 261.72,14.84 v1(262.68,14.84) v2(264.04,14.84)
HDD_B_PRE: length 2.6
  TOP w0.102: RN10.1 RN11.2 260.78,17.63 260.89,17.74 UN2.8
HDD_DET#: length 144.9
  TOP w0.102: v2(265.3,8.17) 265.3,9.18 264.52,9.96 263.3,9.96 261.24,7.9 250.33,7.9 249.48,8.74 247.45,8.74 245.78,10.41 245.78,13.08 245.27,13.59 243.27,13.59 240.37,16.48 238.76,16.48 235.14,20.1 235.14,21.31 233.3,23.15 233.3,24.71 228.56,29.45 v1(228.56,29.95) v2(228.56,35.09)
  IN3 w0.122: v2(172.64,64.84) 172.68,64.84 173.07,64.45 173.76,64.45 173.8,64.48 173.83,64.48 174.55,65.19 187.28,65.19 190.03,62.45 190.03,59.41 193.24,56.19 193.24,49.69 194.35,48.58 194.35,47.32 194.61,47.07 194.61,41.75 200.15,36.21 208.5,36.21 210.85,33.86 227.33,33.86 v2(228.56,35.09)
  BOTTOM w0.076: UC1.U1 170.8,64.06 171.86,64.06 v2(172.64,64.84) 173.05,65.25 173.32,65.25 173.62,64.95 173.62,64.69 173.9,64.41
  BOTTOM w0.102: JSATA1.13 264.94,7.8 v2(265.3,8.17) ; 173.9,64.41 174.12,64.19 175.53,64.19 176.22,64.88 RPC18.6
HDD_DEVSLP: length 150.3
  TOP w0.102: v2(268.16,9.18) 266.32,9.18 265.31,10.19 263.17,10.19 261.11,8.13 250.45,8.13 249.61,8.97 247.59,8.97 246.01,10.55 246.01,13.72 245.86,13.87 243.32,13.87 240.43,16.75 238.87,16.75 235.39,20.23 235.39,21.38 233.55,23.22 233.55,24.79 229.04,29.3 v1(229.04,31.98) 229.04,35.28 228.53,35.79 v2(228.53,37.06)
  IN3 w0.081: 173.24,67.76 172.21,67.76 v2(171.85,68.12)
  IN3 w0.122: 173.24,67.76 173.39,67.92 184.54,67.92 185.35,67.1 187.13,67.1 191.27,62.97 191.27,61.23 195.65,56.84 195.65,47.79 195.86,47.58 195.86,42.27 199.41,38.71 213.61,38.71 216.24,36.08 223.37,36.08 225.61,38.33 226.68,38.33 227.62,37.39 228.2,37.39 v2(228.53,37.06)
  BOTTOM w0.076: UC1.L2 170.52,67.42 170.83,67.42 171.13,67.72 171.49,67.72 171.85,68.08 v2(171.85,68.12)
  BOTTOM w0.102: RN5.2 268.33,9.36 v2(268.16,9.18) 266.6,9.18 266.08,8.66 265.14,8.66 263.94,7.46 JSATA1.11
HDD_FALL_INT: length 161.6
  TOP w0.102: v2(169.15,65.85) 169.49,65.51 170.11,65.51 170.27,65.67 173.5,65.67 173.7,65.48 179.26,65.48 179.85,66.07 RPC9.5 ; v2(229.45,32.94) 229.45,29.22 233.8,24.87 233.8,23.29 235.65,21.45 235.65,20.36 239.01,16.99 240.52,16.99 243.42,14.1 245.98,14.1 246.36,13.72 v1(246.36,12.01) 246.36,10.53 247.69,9.2 249.71,9.2 250.56,8.36 260.98,8.36 263.05,10.42 265.46,10.42 266.25,9.63 273.54,9.63 v2(275.74,7.42)
  IN3 w0.076: 172.79,62.02 173.1,62.33 173.36,62.33
  IN3 w0.081: 172.79,62.02 171.84,62.02 170.89,62.98 170.89,63.07 169.99,63.97 169.69,63.97 169.15,64.52 v2(169.15,65.85)
  IN3 w0.122: v2(229.45,32.94) 229.36,32.94 227.72,31.3 210.93,31.3 207.77,34.46 199.42,34.46 192.86,41.03 192.86,46.18 190.48,48.55 190.48,56.44 187.7,59.22 186.37,59.22 183.03,62.56 175.3,62.56 175.07,62.33 173.36,62.33
  BOTTOM w0.081: v2(169.15,65.85) 168.83,66.16 UC1.N4
  BOTTOM w0.305: UN1.11 275.9,7.26 v2(275.74,7.42)
HDMI_CEC: length 7.8
  TOP w0.102: JHDMI1.13 217.45,99.32 219.68,99.32 220.02,98.97 220.02,98.42 v1(220.63,97.81) 222.11,96.34 RV8.2
HDMI_CLK_AUX: length 36
  TOP w0.102: RV7.1 223.45,94.32 223.45,94.77 223.97,95.29 v2(224.28,95.29) 226.69,92.87 227.25,92.87 v1(227.7,92.43) 232.02,88.11 232.6,88.11 235.65,85.06 235.65,82.49 234.69,81.53 230.76,81.53 230.62,81.68 UV7.48
  IN1 w0.089: v2(224.28,95.29) 224.13,95.14 222.72,95.14 220.62,97.23 220.62,98.69 219.87,99.44 217.97,99.44 217.7,99.71 JHDMI1.15
HDMI_DAT_AUX#: length 36.8
  TOP w0.102: RV9.1 223.2,94.84 224.09,95.73 224.47,95.73 v2(224.91,95.29) v1(226.45,93.75) 226.5,93.7 226.93,93.7 228.81,91.82 228.81,91.71 232.1,88.42 232.67,88.42 235.89,85.2 235.89,82.4 234.76,81.28 UV7.47
  IN1 w0.089: v2(224.91,95.29) 224.51,94.88 222.65,94.88 220.41,97.13 220.41,98.59 219.78,99.21 218.42,99.21 218.2,98.99 JHDMI1.16
HDMI_HPD: length 23.5
  TOP w0.102: UV7.17 222.02,84.08 v2(221.92,84.18)
  IN1 w0.089: JHDMI1.19 220.21,100.07 220.9,99.38 220.9,97.42 222.49,95.83 225.13,95.83 v2(225.71,95.25)
  BOTTOM w0.102: v2(221.92,84.18) 221.41,84.69 221.41,89.8 225.71,94.11 v2(225.71,95.25)
HDMI_LANE_N0: length 20.8
  TOP w0.102: v2(211.68,92.33) 211.42,92.07 211.42,91.74 211.74,91.42 211.76,91.42 212.18,91 212.18,90.98 212.35,90.81 215.7,90.81 216.73,89.78 216.88,89.78 217.31,90.21 217.62,90.21 217.96,89.87 217.96,89.56 217.53,89.12 217.53,88.98 217.75,88.76 217.89,88.76 218.29,89.16 218.67,89.16 218.94,88.89 218.94,88.51 218.54,88.11 218.54,87.97 220.4,86.11 220.4,85.57 220.43,85.55 220.43,84.98 221.82,83.58 222.37,83.58 222.47,83.68 UV7.18
  BOTTOM w0.102: v2(211.68,92.33) 211.48,92.53 211.48,92.79 211.8,93.11 LV3.4
HDMI_LANE_N1: length 20.8
  TOP w0.102: v2(209.55,92.34) 209.38,92.18 209.38,91.01 210.49,89.9 211.3,89.9 211.32,89.92 211.92,89.92 211.94,89.9 215.42,89.9 219.31,86 219.31,84.92 221.85,82.38 222.37,82.38 222.47,82.48 UV7.21
  BOTTOM w0.102: LV6.4 209.7,93.04 209.36,92.7 209.36,92.53 v2(209.55,92.34)
HDMI_LANE_N2: length 23.4
  TOP w0.102: v2(207.54,92.36) 207.16,91.98 207.16,91.65 207.81,91.01 207.83,91.01 208.26,90.59 208.26,90.56 209.76,89.06 215,89.06 218.49,85.57 218.49,84.53 218.8,84.21 218.8,84.18 221.81,81.18 222.49,81.18 222.58,81.28 UV7.24
  BOTTOM w0.102: v2(207.54,92.36) 207.22,92.68 207.22,92.79 207.32,92.9 207.51,92.9 207.61,93 LV10.4
HDMI_LANE_N3: length 23.2
  TOP w0.102: UV7.15 222.47,84.88 222.37,84.78 222.27,84.78 221.99,85.06 221.55,85.06 221.41,85.2 221.41,88.06 220.43,89.04 220.43,89.18 221.3,90.06 221.3,90.48 221,90.78 220.58,90.78 219.56,89.77 219.31,89.77 219.13,89.95 219.13,90.2 220.42,91.49 220.42,91.91 220.12,92.21 219.69,92.21 218.55,91.07 216.69,91.07 216.11,91.65 215.94,91.65 215.59,91.65 215.57,91.67 v4(215.28,91.67) 214.98,91.67 214.96,91.65 213.8,91.65 213.5,91.95 213.5,92.1 v2(213.76,92.37)
  BOTTOM w0.102: v2(213.76,92.37) 213.51,92.62 213.51,92.77 213.64,92.9 213.81,92.9 213.9,92.98 LV12.4
HDMI_LANE_P0: length 21.1
  TOP w0.102: v2(211.1,92.33) 211.21,92.22 211.21,91.64 v4(211.81,91.05) 212.25,90.6 215.62,90.6 216.65,89.57 216.96,89.57 217.39,90 217.54,90 217.75,89.79 217.75,89.64 217.32,89.21 217.32,88.89 217.66,88.56 217.98,88.56 218.38,88.95 218.59,88.95 218.73,88.81 218.73,88.6 218.34,88.2 218.34,87.88 220.2,86.02 220.2,84.91 221.73,83.37 222.37,83.37 222.47,83.28 UV7.19
  BOTTOM w0.102: LV3.1 210.95,93.15 211.27,92.83 211.27,92.51 v2(211.1,92.33)
HDMI_LANE_P1: length 21.1
  TOP w0.102: v2(208.96,92.34) 209.17,92.13 209.17,90.92 210.41,89.69 v4(211.62,89.69) 215.34,89.69 219.1,85.92 219.1,84.84 221.77,82.17 222.37,82.17 222.47,82.08 UV7.22
  BOTTOM w0.102: v2(208.96,92.34) 209.15,92.53 209.15,92.75 208.85,93.04 LV6.1
HDMI_LANE_P2: length 23.3
  TOP w0.102: UV7.25 222.57,80.88 222.48,80.97 221.72,80.97 218.28,84.41 218.28,85.49 214.92,88.85 209.67,88.85 v4(207.88,90.64) 206.96,91.57 v2(206.96,92.36)
  BOTTOM w0.102: LV10.1 206.76,93.11 207.01,92.86 207.01,92.41 v2(206.96,92.36)
HDMI_LANE_P3: length 23.3
  TOP w0.102: UV7.16 222.47,84.48 222.37,84.57 222.28,84.57 222.18,84.57 221.9,84.86 221.46,84.86 221.2,85.12 221.2,87.98 220.22,88.95 220.22,89.27 221.09,90.14 221.09,90.4 220.91,90.58 220.66,90.58 219.65,89.56 219.22,89.56 218.92,89.86 218.92,90.29 220.21,91.57 220.21,91.83 220.03,92.01 219.78,92.01 218.63,90.86 216.6,90.86 216.02,91.44 213.71,91.44 213.28,91.87 213.28,92.27 v2(213.18,92.37)
  BOTTOM w0.102: v2(213.18,92.37) 213.29,92.48 213.29,92.8 213.05,93.04 LV12.1
HOST_ALERT1_R_N: length 12.4
  TOP w0.102: v2(167.04,61.01) 167.45,60.6 168.49,60.6 168.88,61 170,61 170.75,61.75 170.75,61.98 171.1,62.33 171.59,62.33 172.04,61.88 v1(172.33,61.88) 172.4,61.81 176.53,61.81 RC179.2
  BOTTOM w0.076: 167.5,60.55 v2(167.04,61.01)
  BOTTOM w0.081: UC1.AD6 167.5,60.55
HOST_DEBUG_TX: length 53.1
  TOP w0.102: v2(259.52,38.52) 259.44,38.43 UE2.B44 ; RE73.2 v2(299.34,35.47) 299.34,36.36 298.56,37.13 JDEG1.8
  BOTTOM w0.102: v2(299.34,35.47) 300.29,35.47 300.92,36.11 300.92,37.25 300.42,37.76 298.32,37.76 295.95,40.13 275.85,40.13 274.74,41.24 270.94,41.24 267.24,37.54 267.24,37.14 266.72,36.61 264.23,36.61 263.08,37.76 v1(262.72,37.76) 259.7,37.76 259.43,38.03 259.43,38.43 v2(259.52,38.52)
HSYNC_DOCK: length 88
  TOP w0.102: v2(216.33,84.75) 214.55,84.75 212.66,82.86 212.66,80.01 210.48,77.84 UV8.M9
  BOTTOM w0.102: v2(216.33,84.75) 215.57,84.75 215.26,85.07 215.26,87.73 212.39,90.59 v1(202.5,90.59) 195.32,90.59 193.69,92.23 183.96,92.23 182.98,93.21 166.43,93.21 164.67,94.97 159,94.97 156.18,92.15 151.6,92.15 149.95,93.8 JDOCK1.65
HW_GPS_DISABLE2#: length 27
  TOP w0.102: v2(241.23,65.06) 241.24,65.06 DZ6.1 242.62,65.06 242.91,65.35 242.91,66.85 v1(242.43,67.33) ; UE1.A35 252.12,59.54 251.94,59.36 251.94,58.88 v2(252.1,58.72) 251.82,58.44 RE12.2
  IN4 w0.089: v2(241.23,65.06) 241.23,64.3 240.69,63.75 240.69,61.67 241.14,61.21 244.7,61.21 245.3,60.62 245.3,58.78 244.47,57.95 244.47,57.31 244.66,57.12 247.01,57.12 247.85,57.96 251.34,57.96 v2(252.1,58.72)
HW_GPS_DISABLE2#_R: length 4
  TOP w0.102: v1(241.28,68.22) 241.28,67.23 241.23,67.18 v2(241.23,66.55) 242.03,66.55 DZ6.2
  BOTTOM w0.102: v2(241.23,66.55) 241.2,66.59 239.91,66.59 JNGFF2.18
I2C1_SCL_VMM: length 11.6
  TOP w0.076: v2(202.51,72.76) 202.65,72.9 202.71,72.9 203.01,73.2 UV8.A2
  TOP w0.102: v2(200.11,80.17) 199.72,80.57 RPV2.2
  IN1 w0.089: v2(200.11,80.17) 200.99,79.29 202.44,79.29 202.87,78.87 202.87,75.5 202.08,74.71 202.08,73.95 202.41,73.62 202.41,72.86 v2(202.51,72.76)
I2C1_SDA_VMM: length 11.7
  TOP w0.076: v2(202.06,72.38) 202.75,72.38 UV8.A1
  TOP w0.102: RPV2.1 199.58,80.07 200.02,79.63 v2(200.02,79.56)
  IN1 w0.089: v2(202.06,72.38) 202.05,72.38 202.05,73.67 201.86,73.86 201.86,74.8 202.65,75.59 202.65,78.78 202.35,79.08 200.9,79.08 200.42,79.56 v2(200.02,79.56)
I2S_BCLK: length 6.2
  TOP w0.102: v1(34.3,25.58) 34.45,25.42 RA31.2 34.95,25.13 34.95,22.36 34.26,21.67 UA1.16
I2S_DO: length 2.8
  TOP w0.102: RA32.2 34.48,22.73 33.86,22.11 UA1.17
I2S_MCLK: length 2.9
  TOP w0.102: RA30.2 35.43,22.34 v1(34.81,21.72) 34.66,21.57 UA1.15
I_ADP: length 235.4
  TOP w0.102: UE2.A12 257.19,48.39 257.12,48.46 257.12,48.88 v2(257.52,49.28) ; v1(82.79,88.54) v2(82.79,87.96)
  IN2 w0.122: v2(82.79,87.96) 82.79,87.38 92.98,77.19 100.77,77.19 100.9,77.32 103.18,77.32 104.07,78.21 106.61,78.21 107.5,79.1 114.42,79.1 115.11,79.78 115.11,80.73 115.63,81.25 121.35,81.25 124.33,84.24 124.33,86.27 126.68,88.62 146.68,88.62 147.95,89.89 156.43,89.89 157.51,90.97 182.18,90.97 183,90.14 204.15,90.14 204.87,90.87 220.01,90.87 222.35,93.21 233.54,93.21 238.57,88.18 238.57,85.16 240.44,83.29 240.44,80.02 246.31,74.14 258.47,74.14 261.81,70.8 261.81,67.98 260.9,67.07 260.9,65.23 262.72,63.41 262.72,56.78 261.95,56.01 261.95,54.27 262.09,54.13 262.09,53.26 260.93,52.11 259.93,52.11 257.52,49.7 v2(257.52,49.28)
  BOTTOM w0.102: PR716.1 82.3,88.45 v2(82.79,87.96)
I_BATT: length 289.4
  TOP w0.102: v2(269.09,41.36) 269.31,41.59 270.4,41.59 RE64.2
  IN2 w0.122: v2(269.09,41.36) 267.7,41.36 266.51,40.17 265.05,40.17 262.76,37.88 254.76,37.88 253.93,38.71 252.16,38.71 251.14,37.69 239.84,37.69 234.82,32.68 234.82,31.28 233.79,30.25 86.22,30.25 85,29.03 80.46,29.03 78.87,27.44 77.21,27.44 76.54,28.11 72.76,28.11 71.56,29.31 66.61,29.31 64.77,31.15 v2(64.77,31.72)
  IN3 w0.122: v2(64.77,31.72) 64.77,31.8 68.11,35.14 68.11,39.26 69.53,40.68 69.53,47.68 73.72,51.87 73.72,54.06 80.32,60.66 83.61,60.66 91.62,68.67 91.62,74.35 92.71,75.44 92.71,77.76 92.33,78.14 92.33,80.75 v2(92.39,80.81)
  BOTTOM w0.102: v2(92.39,80.81) 91.95,81.25 88.76,81.25 88.32,81.7 86.67,81.7 86.29,82.08 86.29,83.74 v1(85.75,84.29) 84.97,85.06 PR718.1
I_SYS: length 236.2
  TOP w0.102: v2(265.22,42.55) 265.06,42.71 UE2.A57
  IN2 w0.122: v2(265.22,42.55) 265.22,43.55 265.7,44.04 265.7,51.06 265.22,51.55 265.22,58.25 264.95,58.52 264.95,63.29 264.5,63.73 264.5,70.09 259.05,75.54 255.8,75.54 254.91,76.43 245.55,76.43 241.52,80.46 241.52,86.74 234,94.27 221.89,94.27 219.5,91.88 204.37,91.88 203.64,91.16 183.51,91.16 182.69,91.99 157.12,91.99 156.04,90.91 127.44,90.91 123.31,86.78 123.31,84.75 120.94,82.37 115.1,82.37 113.22,80.49 109.92,80.49 109.15,79.73 104.77,79.73 102.87,77.83 100.7,77.83 100.57,77.7 93.18,77.7 91.75,79.12 v2(91.75,80.81)
  BOTTOM w0.102: v2(91.75,80.81) v1(89.55,80.81) 88.89,80.81 88.31,81.38 86.61,81.38 86.04,81.95 86.04,83.48 85.34,84.18 PR720.1
ILIM_SEL: length 5.1
  TOP w0.102: v1(285.7,38.94) 286.15,38.48 288.37,38.48 288.66,38.77 RI13.1 288.66,39.6 288.26,40 UI3.4
ILMT_1.05V: length 4.8
  TOP w0.102: v1(205.67,64.03) 206.19,63.51 206.62,63.51 PR306.2
  TOP w0.254: PR306.2 PR308.1 206.56,62.58 206.04,62.06 v2(206.04,61.05)
  BOTTOM w0.254: PU300.3 205.83,60.91 205.97,61.05 v2(206.04,61.05)
IMON: length 4.6
  TOP w0.102: v1(105.12,62.94) 104.89,63.17 v2(104.89,63.86)
  TOP w0.203: v2(104.89,63.86) 104.75,64 PU500.13
  BOTTOM w0.254: PR501.2 103.6,62.2 104.5,63.1 PC500.2 104.89,63.35 v2(104.89,63.86)
INT_SPK_L+: length 11.9
  TOP w0.203: UA1.42 33.06,12.78 33.06,12.78 32.98,12.7 32.98,11.43 v2(32.95,11.4)
  IN4 w0.762: 33.08,10.59 32.67,10.18 31.1,10.18 30.35,9.44 28.89,9.44 26.34,6.89 v2(25.9,6.89)
INT_SPK_L-: length 10.6
  TOP w0.203: UA1.43 v1(33.46,13.3) 33.46,11.98 v2(33.46,11.98)
  IN4 w0.762: 32,11.66 32.01,11.65 31.13,11.65 29.93,10.45 28.45,10.45 26.81,8.82 v4(25.12,8.82)
INT_SPK_R+: length 12.4
  TOP w0.203: v2(34.67,11.47) 34.43,11.71 v1(34.43,12.34) 34.43,12.65 34.26,12.82 UA1.45
  IN3 w0.762: v4(25.83,9.94) 26.33,9.44 30.26,9.44 30.48,9.65 34.25,9.65 34.6,10.01
INT_SPK_R-: length 12.4
  TOP w0.203: v2(33.97,11.47) 33.97,12.55 33.86,12.66 UA1.44
  IN3 w0.762: v2(25.08,11.72) 25.91,11.72 27.18,10.45 29.84,10.45 30.06,10.67 33.67,10.67 33.73,10.73
INT_SPKR_L+: length 22.2
  TOP w0.102: v4(21,7.09) 20.34,7.09 v1(19.95,6.71)
  IN4 w0.762: v4(2.85,8.42) 3.87,7.4 9.4,7.4 12.2,10.21 17.89,10.21 v4(21,7.09)
  vias: v4(2.85,10.77)
INT_SPKR_L-: length 19.9
  TOP w0.102: v1(22.41,8.46) 22.13,8.74 v4(21.02,8.74)
  IN4 w0.762: v4(21.02,8.74) 18.47,11.28 11.5,11.28 9.46,9.25 5.65,9.25 v4(4.82,8.42)
  vias: v4(4.76,10.77)
INT_SPKR_R+: length 17.5
  TOP w0.102: v4(21.02,10.01) 20.41,10.01 v1(19.72,9.32)
  IN3 w0.762: v4(6.86,8.42) 7.93,7.34 9.59,7.34 12.44,10.2 20.82,10.2 21.02,10 v4(21.02,10.01)
  vias: v4(6.86,10.83)
INT_SPKR_R-: length 14.5
  TOP w0.102: v4(21.02,11.66) v1(20.03,11.66)
  IN3 w0.762: v4(8.82,8.42) 11.68,11.28 20.63,11.28 v4(21.02,11.66)
  vias: v4(8.76,10.77)
INTRUDER#: length 8.8
  BOTTOM w0.076: 170.49,46.76 170.83,47.09 170.83,47.52 v1(171.08,47.78) ; 170.49,46.76 170.49,46.94 169.99,47.45 169.99,47.65 167.7,49.93 167.7,49.99 167.7,51.84 167.73,51.86 167.73,52.55 UC1.AU6 ; 170.49,46.76 RC9.2
IO_LDOSEL: length 6.5
  TOP w0.102: v1(282.2,22.91) 282.84,23.55 282.84,24.71 283.19,25.07 RR6.2 RR8.1 284.41,25.2 284.41,27.24 284.52,27.34 UR1.18
IRQ_SERIRQ: length 153.4
  TOP w0.102: UE2.A28 252.48,40.71 252.03,40.26 v1(249.9,40.26) 249.79,40.36 v2(249.36,40.36) ; RPC15.2 180.7,62.4 180.9,62.59 180.9,63.42 v2(181.15,63.67) ; UE1.B21 251.23,68.01 v2(251.65,68.43)
  IN1 w0.089: v2(249.36,40.36) 248.02,39.01 246.56,39.01 v2(244.66,40.91)
  IN3 w0.076: 172.68,62.27 171.83,62.27 171.16,62.95 171.16,63.34 170.27,64.24
  IN3 w0.081: 170.27,64.24 170.27,65.02 170.15,65.14 170.15,66.08 169.94,66.29 168.99,66.29 v2(168.42,65.71)
  IN3 w0.122: v2(244.66,40.91) 243.88,40.91 242.76,39.79 239.8,39.79 238.63,38.62 236.84,38.62 233.37,35.14 232.55,35.14 231.69,34.29 231.69,34.15 230.92,33.38 229.26,33.38 227.62,31.74 210.85,31.74 207.87,34.71 199.53,34.71 193.11,41.13 193.11,46.28 190.78,48.61 190.78,56.53 187.83,59.47 186.5,59.47 182.8,63.17 181.65,63.17 v2(181.15,63.67) 180.33,62.85 175.24,62.85 174.97,62.58 172.98,62.58 172.68,62.27
  BOTTOM w0.081: UC1.T4 168.83,64.94 168.42,65.36 v2(168.42,65.71)
  BOTTOM w0.102: v2(251.65,68.43) 251.2,68.87 250.76,68.87 250.12,68.24 247.14,68.24 246.63,67.73 246.63,56.11 247.27,55.47 247.27,52.55 245.36,50.65 245.36,41.61 v2(244.66,40.91)
JTAG_CLK: length 44.4
  TOP w0.102: RPE7.3 299.18,39.15 v2(299.11,39.08) 299.06,39.13 JDEG1.4 ; UE2.B56 263.21,40.46 263.14,40.53 262.65,40.53 v2(262.24,40.11)
  BOTTOM w0.102: v2(299.11,39.08) 297.38,40.81 277.68,40.81 276.5,42 270.04,42 269.1,42.94 268.01,42.94 267.65,42.59 267.65,41.08 266.71,40.13 266.71,40.08 266.49,39.86 264.62,39.86 v1(263.93,40.55) 262.68,40.55 v2(262.24,40.11)
JTAG_RST#: length 15.9
  TOP w0.102: v1(265.02,30.48) 264.86,30.32 RE63.2 264,30.24 JTAG1.1 261.88,30.24 RE65.1 CE30.1 260.69,30.32 260.27,30.74 260.27,34.28 260.39,34.39 260.39,34.74 v2(260.5,34.86) ; UE2.B47 260.94,38.2 260.83,38.31 260.83,38.74 v2(260.41,39.16)
  IN1 w0.089: v2(260.5,34.86) 260.63,34.98 260.63,35.64 260.99,36.01 260.99,37.04 260.02,38.02 260.02,38.77 v2(260.41,39.16)
JTAG_TDI: length 42.7
  TOP w0.102: RPE7.1 299.31,40.15 v2(299.11,40.35) 298.89,40.13 JDEG1.2 ; UE2.A51 265.38,39.71 v2(266.25,38.84)
  BOTTOM w0.102: v2(299.11,40.35) 299.59,39.87 299.59,38.26 299.34,38.01 298.51,38.01 296.17,40.36 275.96,40.36 274.84,41.48 270.85,41.48 267.83,38.46 v1(266.9,38.46) 266.63,38.46 v2(266.25,38.84)
JTAG_TDO: length 41.6
  TOP w0.102: RPE7.4 299.29,38.65 v2(299.11,38.47) 298.95,38.63 JDEG1.5 ; UE2.B55 263.35,39.96 263.19,40.12 v2(262.88,40.12)
  BOTTOM w0.102: v2(262.88,40.12) 263.39,39.61 266.21,39.61 266.59,39.22 v1(268.08,39.22) 268.23,39.22 270.72,41.72 274.94,41.72 276.08,40.58 296.7,40.58 298.81,38.47 v2(299.11,38.47)
JTAG_TMS: length 40.5
  TOP w0.102: JDEG1.3 299.03,39.63 v2(299.11,39.72) 299.18,39.65 RPE7.2 ; v2(265.6,40.69) 264.91,40.69 264.88,40.71 UE2.A53
  BOTTOM w0.102: v2(265.6,40.69) 265.6,40.43 265.76,40.28 266.53,40.28 267.26,41 v1(267.26,42.75) 267.68,43.17 269.2,43.17 270.1,42.27 276.61,42.27 277.83,41.04 297.79,41.04 v2(299.11,39.72)
KB_DET#: length 109.1
  TOP w0.102: v2(236.73,23.6) 236.92,23.41 236.92,20.99 239.62,18.28 240.89,18.28 243.58,15.6 JKBTP1.16 244.91,15.6 245.17,15.34 245.76,15.34 v1(245.83,15.42)
  IN3 w0.122: v2(173.85,56.67) 173.85,51.34 176.34,48.85 179.43,48.85 180.42,47.86 180.42,41.78 180.26,41.61 180.26,40.81 193.57,27.5 203.61,27.5 206.76,24.35 227.85,24.35 229.4,22.8 235.94,22.8 v2(236.73,23.6)
  BOTTOM w0.076: UC1.AT3 169.48,53.72 169.78,54.02 169.78,54.4 169.97,54.59 170.37,54.59 170.54,54.75 170.89,54.75 171.13,55 171.67,55 172.74,56.06 173.25,56.06 173.36,56.18
  BOTTOM w0.102: RPC19.1 177.11,58.28 175.5,56.67 v2(173.85,56.67) 173.36,56.18
LAN_ACTLED_YEL#: length 2.6
  TOP w0.102: QL1.6 281.15,83.35 v1(281.58,83.78) RL14.1
LAN_ACTLED_YEL_R#: length 23.5
  TOP w0.102: JLOM1.10 275.62,94.68 276.97,93.33 280.56,93.33 283.61,90.27 283.61,86.27 v1(283.22,85.88) 282.95,85.61 RL14.2
LAN_DISABLE#_R: length 49.2
  TOP w0.102: UE1.B53 v2(258.75,62.01) ; v2(250.45,89.76) RL7.2 250.47,90.45 RL9.1 RL5.2 252.66,90.13 252.66,87.73 253.21,87.19 UL1.3
  BOTTOM w0.102: v2(250.45,89.76) 250.19,89.76 249.65,89.23 v1(249.34,89.23) 249.02,89.23 247.01,87.22 247.01,84.71 245.93,83.63 245.93,79.03 246.63,78.33 251.48,78.33 254.44,75.37 258.47,75.37 260.13,73.71 260.13,63.4 v2(258.75,62.01)
LAN_TEST_EN: length 1.7
  TOP w0.102: UL1.30 260.13,85.59 260.22,85.67 261.18,85.67 RL12.1
LAN_TX0+: length 3.3
  TOP w0.094: RL21.1 253,80.85 253,81.26 v1(253.39,81.65) 253.6,81.86 253.79,81.86 254.43,82.5 UL1.13
LAN_TX0+L: length 22.1
  TOP w0.094: v2(268.92,71.92) 269.02,72.02 269.02,72.74 268.96,72.8 UL4.2 ; RL21.2 253.03,78.59 253.03,78.41 v2(252.93,78.3)
  IN1 w0.081: v2(252.93,78.3) 253.1,78.14 253.1,77.73 255.4,75.42 258.83,75.42 261.36,72.9 268.73,72.9 269.1,72.52 269.1,72.1 v2(268.92,71.92)
LAN_TX0-: length 3.3
  TOP w0.094: RL22.1 253.38,80.85 253.38,81.1 253.76,81.48 253.95,81.48 254.83,82.36 UL1.14
LAN_TX0-L: length 22.1
  TOP w0.094: UL4.3 269.46,72.8 269.4,72.74 269.4,72.02 v2(269.5,71.92) ; RL22.2 253.41,78.66 253.41,78.41 v2(253.51,78.3)
  IN1 w0.081: v2(253.51,78.3) 253.35,78.14 253.35,77.83 255.51,75.67 258.94,75.67 261.46,73.15 268.83,73.15 269.35,72.63 269.35,72.07 v2(269.5,71.92)
LAN_TX1+: length 2.8
  TOP w0.094: UL1.17 256.03,82.06 256.04,82.05 256.04,81.71 v1(255.97,81.65) 255.47,81.15 255.47,80.84 RL23.1
LAN_TX1+L: length 21.7
  TOP w0.094: v2(270.92,71.92) 271.02,72.02 271.02,72.74 270.96,72.8 UL4.6 ; v2(255.37,78.21) 255.48,78.32 255.48,78.63 RL23.2
  IN1 w0.081: v2(270.92,71.92) 271.12,72.12 271.12,72.34 269.73,73.74 261.85,73.74 259.09,76.5 256.55,76.5 255.54,77.51 255.54,78.05 v2(255.37,78.21)
LAN_TX1-: length 2.8
  TOP w0.094: RL24.1 255.85,80.86 255.85,80.99 256.42,81.55 256.42,82.05 256.43,82.06 UL1.18
LAN_TX1-L: length 21.7
  TOP w0.094: v2(255.96,78.21) 255.86,78.32 255.86,78.63 RL24.2 ; UL4.7 271.46,72.8 271.4,72.74 271.4,72.02 v2(271.5,71.92)
  IN1 w0.081: v2(271.5,71.92) 271.37,72.05 271.37,72.44 269.83,73.99 261.96,73.99 259.19,76.75 256.65,76.75 255.79,77.61 255.79,78.05 v2(255.96,78.21)
LAN_TX2+: length 2.9
  TOP w0.094: RL25.1 257.96,80.86 257.96,80.99 257.23,81.71 257.23,82.05 257.23,82.06 UL1.20
LAN_TX2+L: length 21.2
  TOP w0.094: RL25.2 257.95,78.63 257.95,78.32 v2(257.85,78.21) ; v2(272.42,71.92) 272.53,72.02 272.53,72.74 272.46,72.8 UL4.9
  IN1 w0.081: v2(257.85,78.21) 258.02,78.05 258.02,77.7 258.32,77.39 259.4,77.39 261.96,74.84 271.29,74.84 272.53,73.6 272.53,72.04 272.53,72.03 v2(272.42,71.92)
LAN_TX2-: length 2.9
  TOP w0.094: RL26.1 258.34,80.84 258.34,81.15 v1(257.85,81.64) 257.62,81.87 257.62,82.05 257.63,82.06 UL1.21
LAN_TX2-L: length 21.3
  TOP w0.094: v2(258.44,78.21) 258.33,78.32 258.33,78.63 RL26.2 ; UL4.10 272.96,72.8 272.91,72.75 272.91,72.01 v2(273,71.92)
  IN1 w0.081: v2(258.44,78.21) 258.27,78.05 258.27,77.8 258.43,77.64 259.51,77.64 262.06,75.09 271.4,75.09 272.78,73.71 272.78,72.14 v2(273,71.92)
LAN_TX3+: length 4
  TOP w0.094: RL27.1 260.46,80.88 260.46,81.23 v1(260.05,81.64) 259.06,81.64 258.43,82.28 UL1.23
LAN_TX3+L: length 19.9
  TOP w0.094: v2(260.33,78.21) 260.43,78.32 260.43,78.63 RL27.2 ; UL4.11 273.46,72.8 273.53,72.74 273.53,72.53 v2(273.42,72.42)
  IN1 w0.081: v2(273.42,72.42) 273.61,72.61 273.61,75.19 272.87,75.93 262.07,75.93 260.49,77.51 260.49,78.05 v2(260.33,78.21)
LAN_TX3-: length 3.9
  TOP w0.094: RL28.1 260.84,80.82 260.84,81.39 260.21,82.02 259.22,82.02 258.83,82.42 UL1.24
LAN_TX3-L: length 19.9
  TOP w0.094: RL28.2 260.81,78.63 260.81,78.32 v2(260.91,78.21) ; UL4.12 273.96,72.8 273.91,72.75 273.91,72.52 v2(274,72.42)
  IN1 w0.081: v2(260.91,78.21) 260.75,78.05 260.75,77.61 262.18,76.18 272.97,76.18 273.86,75.3 273.86,72.57 v2(274,72.42)
LAN_WAKE#: length 196.2
  TOP w0.081: 173.11,49.66 173.11,50.14 171.46,51.79 170.98,51.79 169.53,53.24 v3(169.53,53.42) 169.53,54.52 168.66,55.39 v2(168.35,55.39)
  TOP w0.102: RC153.1 175.05,47.71 173.11,49.66 ; v2(253.17,88.68) 252.92,88.43 252.92,87.86 253.19,87.59 UL1.2 ; UE2.B27 255.06,41.96 v2(255.23,41.8)
  IN1 w0.089: v2(255.23,41.8) 255.82,42.4 256.14,42.4 258.48,44.73 258.48,47.18 258.37,47.29 258.37,49.72 257.94,50.15 257.94,51.22 257.28,51.88 241.45,51.88 233.77,44.2 207.53,44.2 203.87,47.85 202.74,47.85 200.81,49.78 197.85,49.78 193.12,54.52 188.97,54.52 188.15,55.35 185.27,55.35 184.57,54.65 183.38,54.65 180.32,57.71 175.7,57.71 174.1,56.11 172.31,56.11 171.76,55.56 170.56,55.56 170.03,55.03 169.06,55.03 168.7,55.39 v2(168.35,55.39)
  BOTTOM w0.081: v2(168.35,55.39) 167.92,55.39 UC1.AN5
  BOTTOM w0.102: v2(253.17,88.68) 252.47,88.68 251.84,89.32 250.12,89.32 249.54,88.73 248.9,88.73 247.27,87.1 247.27,84.63 246.19,83.55 246.19,79.16 246.76,78.59 251.55,78.59 254.54,75.6 258.56,75.6 260.36,73.8 260.36,59.94 260.51,59.79 260.51,58.55 259.57,57.61 259.57,53.31 259.29,53.03 259.29,45.39 259.52,45.16 259.52,42.2 259.27,41.95 256.66,41.95 256.09,41.38 255.65,41.38 v2(255.23,41.8)
LANCLK_REQ#: length 198.2
  TOP w0.102: RL4.1 254.17,90.4 v2(254.17,89.77) 254.17,89.58 254.43,89.33 UL1.48
  IN3 w0.122: v2(173.14,61.03) 173.14,61.04 173.63,61.52 175.4,61.52 175.79,61.91 182.92,61.91 186.05,58.78 186.05,57.3 188.93,54.43 188.93,51.1 189.96,50.06 189.96,48.37 192.36,45.97 192.36,39.86 198.26,33.96 207.56,33.96 210.78,30.75 227.87,30.75 228.71,31.59 229.84,31.59 231.5,33.26 232.54,33.26 232.94,33.66 232.94,34.01 237.04,38.12 239.31,38.12 239.96,38.77 243.33,38.77 245.36,40.8 245.36,47.4 249.89,51.93 262.17,51.93 v2(262.32,52.08)
  BOTTOM w0.081: 172.2,60.56 171.13,60.56 170.86,60.29 UC1.AD1
  BOTTOM w0.102: v2(254.17,89.77) 254.17,88.68 253.67,88.18 252.6,88.18 251.71,89.06 250.31,89.06 249.73,88.48 249.03,88.48 247.52,86.97 247.52,84.56 246.43,83.47 246.43,79.29 246.89,78.84 251.62,78.84 254.63,75.83 258.66,75.83 260.59,73.89 260.59,60.15 261.01,59.73 261.01,55.19 262.32,53.89 v2(262.32,52.08) ; RPC6.6 182.28,65.26 v1(182.53,65) 183.07,64.46 183.07,62.81 182.29,62.03 179.97,62.03 179.43,61.48 173.6,61.48 v2(173.14,61.03) 173.14,60.85 172.86,60.56 172.2,60.56
LCD_CBL_DET#: length 95.3
  TOP w0.081: v2(169.26,67.41) 169.34,67.49 169.34,67.6 171,69.26 172.86,69.26 173.36,69.76
  TOP w0.102: 173.36,69.76 173.55,69.95 175.09,69.95 176.31,68.73 RPC4.5
  IN3 w0.081: 169.83,76.26 170.23,75.87 170.23,71.44 169.44,70.66 169.44,69.63 169.48,69.6 169.48,68.58 169.26,68.35 v2(169.26,67.41)
  IN3 w0.122: 169.83,76.26 169.48,76.62 169.48,77.38 164.33,82.53 164.33,87.16 165.97,88.8 165.97,93.66 164.74,94.89 163.83,94.89 163.48,95.24 159.91,95.24 159.56,94.89 158.79,94.89 149.68,85.78 129.59,85.78 v2(129.35,86.02)
  BOTTOM w0.081: v2(169.26,67.41) 169.2,67.47 169.2,68.21 UC1.J3
  BOTTOM w0.102: v2(129.35,86.02) 126.81,88.56 v1(124.52,88.56) 124.39,88.56 121.79,91.16 118.59,91.16 118.46,91.02 JEDP1.40
LCD_TST: length 181.5
  TOP w0.102: UE1.A36 252.62,59.47 v2(252.42,59.26) 252.52,59.16 252.52,58.16 RE20.2
  IN2 w0.122: v2(252.42,59.26) 252.42,60.43 253.02,61.03 253.02,62.79 252.43,63.38 252.43,69.58 251.48,70.53 247.64,70.53 237.99,80.18 237.99,81.7 236.09,83.6 236.09,88.51 232.91,91.69 223.22,91.69 220.88,89.34 205.64,89.34 204.66,88.37 182.5,88.37 181.73,89.13 175.97,89.13 175.21,88.37 148.65,88.37 147.38,87.1 128.71,87.1 122.63,81.01 v2(122.63,80.1)
  BOTTOM w0.102: v2(122.63,80.1) 122.13,80.1 121.13,79.1 115.9,79.1 115.1,79.9 115.1,82.74 114.36,83.48 114.36,86.16 112.82,87.69 112.82,89.55 112.96,89.68 JEDP1.29
LCD_VCC_TEST_EN: length 160.5
  TOP w0.102: DV3.2 v1(122.65,87.48) 123.99,86.14 126,86.14 v2(126.86,87) ; UE1.A40 254.62,59.41 v2(254.75,59.29)
  IN2 w0.122: v2(126.86,87) 127.46,87.6 147.14,87.6 148.41,88.87 175.02,88.87 175.78,89.64 181.99,89.64 182.75,88.87 204.4,88.87 205.38,89.85 220.55,89.85 222.89,92.2 233.11,92.2 236.6,88.71 236.6,83.86 238.49,81.97 238.49,80.44 247.9,71.03 251.69,71.03 252.93,69.79 252.93,63.59 253.53,62.99 253.53,60.58 254.75,59.36 v2(254.75,59.29)
LED_10_GRN#: length 8
  TOP w0.102: v2(283.26,82.72) 283.84,83.31 RL19.1 ; v2(283.07,79.74) 283.07,78.98 282.45,78.36 QL2.6 282.45,77.03 v1(282.13,76.71)
  IN1 w0.089: v2(283.07,79.74) 283.52,80.2 283.52,82.45 v2(283.26,82.72)
LED_10_GRN_R#: length 14.3
  TOP w0.102: JLOM1.11 278.25,93.56 280.67,93.56 283.97,90.26 v1(283.97,88.56) 283.97,85.19 283.84,85.06 RL19.2
LED_100_ORG#: length 3.9
  TOP w0.102: QL1.3 282.45,80.99 v1(283.7,82.24) 283.91,82.45 283.91,82.96 RL20.1
LED_100_ORG_R#: length 12.5
  TOP w0.102: RL20.2 v1(284.73,86.91) 284.73,89.84 279.89,94.68 JLOM1.13
LED_SATA_DIAG_OUT#: length 66.2
  TOP w0.102: v2(272.83,25.93) 272.02,25.12 DZ4.1 ; UE1.A10 v2(254.12,71.74) 253.93,71.74 v1(253.65,72.01)
  IN1 w0.089: v2(272.83,25.93) 271.22,27.55 271.22,33.74 274.18,36.7 274.18,40.94 276.05,42.8 276.05,47.06 274.51,48.6 270.18,48.6 266.12,52.66 266.12,54.26 263.71,56.66 263.71,58.72 262.42,60.02 262.42,63.45 260.61,65.25 260.61,67.59 260.15,68.05 255.2,68.05 254.82,68.43 254.82,71.04 v2(254.12,71.74)
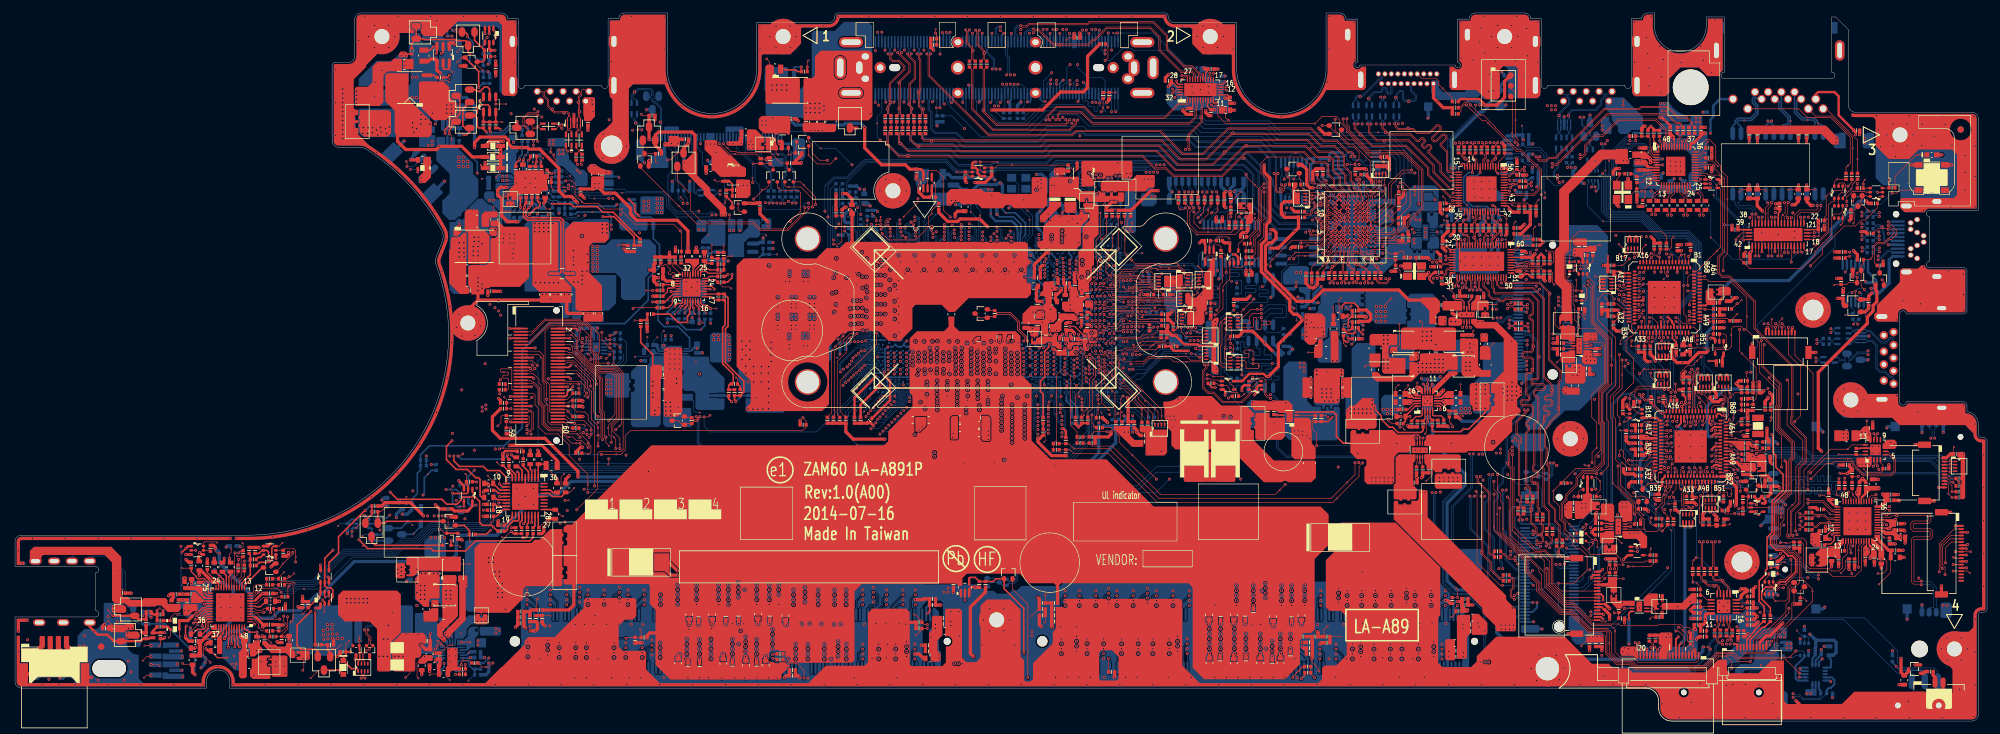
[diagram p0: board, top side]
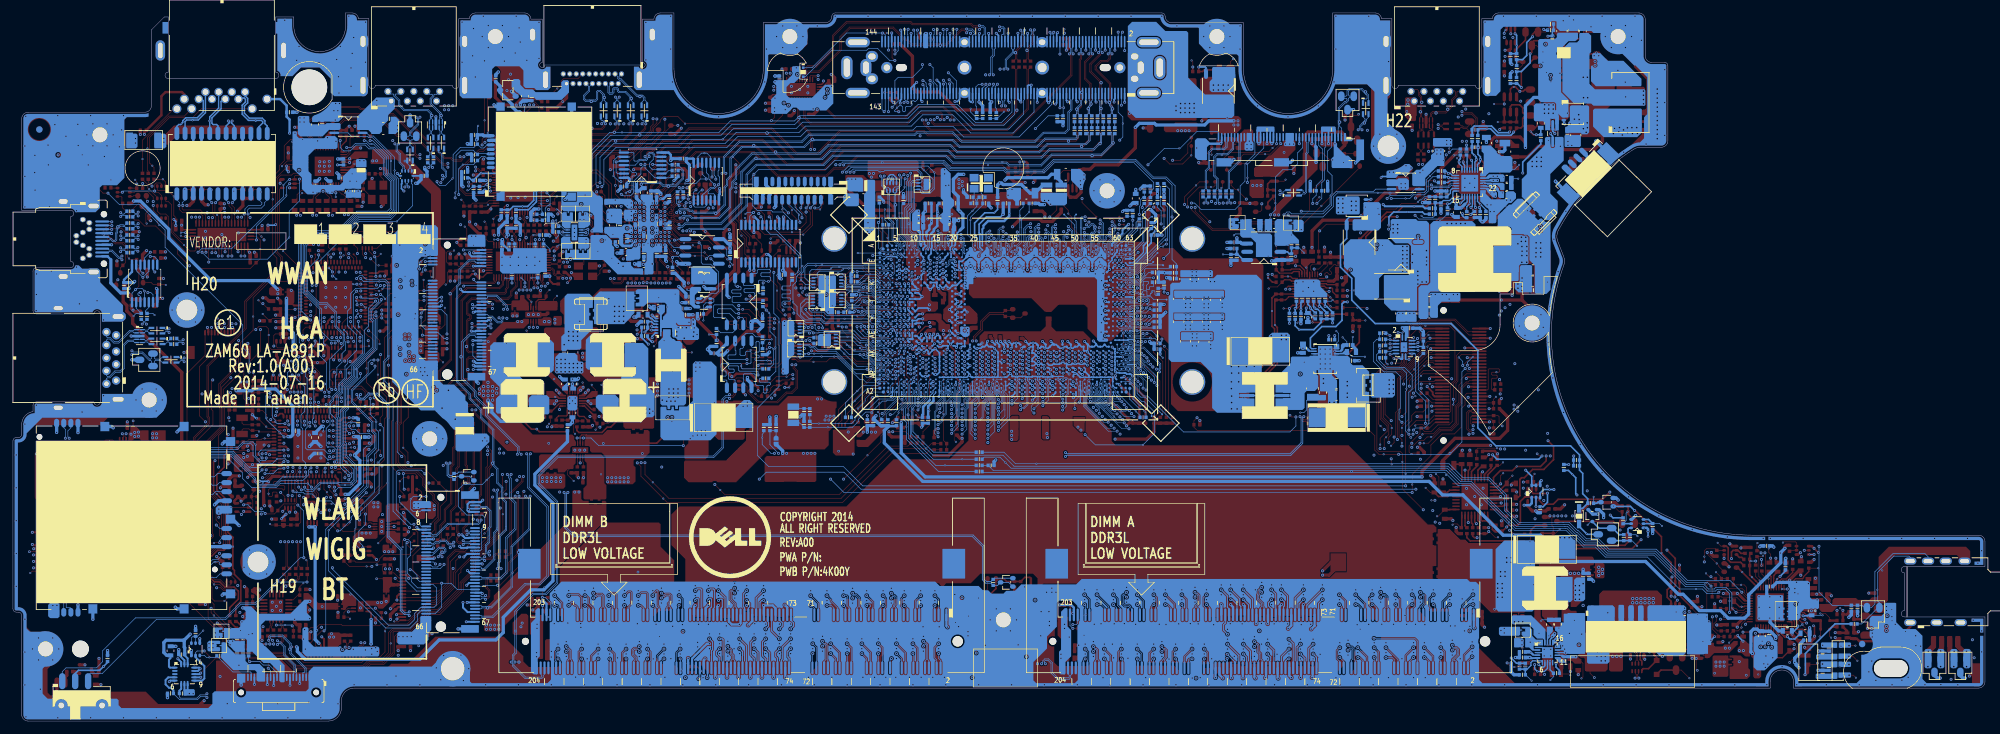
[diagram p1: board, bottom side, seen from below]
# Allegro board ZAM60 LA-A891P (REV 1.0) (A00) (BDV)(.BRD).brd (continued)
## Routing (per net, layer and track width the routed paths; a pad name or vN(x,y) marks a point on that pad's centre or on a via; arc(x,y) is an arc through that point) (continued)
LG_3V:
  vias: v1(221.12,52.88)
LG_5V: length 3.4
  TOP w0.102: v1(216.72,52.35) 216.65,52.27 v2(216.65,51.61)
  IN1 w1.016: 215.88,55.61 215.88,53
  vias: v2(216.72,56.87) v2(216.72,56.26) v2(217.03,51.16)
LID_CL#: length 63.7
  TOP w0.102: v2(264.44,57.99) 264.44,59.63 264.21,59.86 RE26.1 263.38,59.85 UZ10.2 ; v2(274.13,17.44) 274.13,16.75 v1(273.7,16.33) 271.13,13.75 270.44,13.75 269.15,12.46 JLED1.7
  IN1 w0.089: v2(274.13,17.44) 274.56,17.87 274.56,23.84 274.03,24.37 274.03,25.78 271.82,27.99 271.82,33.67 274.61,36.47 274.61,40.76 276.48,42.62 276.48,47.24 274.69,49.03 270.36,49.03 266.55,52.84 266.55,54.44 264.44,56.55 v2(264.44,57.99)
LID_CL_SIO#: length 8.6
  TOP w0.102: v2(261.8,61.77) CE8.1 RE25.2 RE26.2 261.75,59.86 261.48,59.59 v1(261.48,58.95) ; UE1.B54 258.93,62.51 v2(258.73,62.71)
  IN4 w0.089: v2(258.73,62.71) 259.67,61.77 261.8,61.77 v2(261.8,61.77)
LOM_ACTLED_YEL#: length 27
  TOP w0.102: v2(260.47,83.8) 260.28,83.99 UL1.26 ; v2(275.52,72.49) 275.46,72.55 UL4.15
  BOTTOM w0.102: v2(275.52,72.49) 274.46,71.42 265.41,71.42 v1(262.06,74.77) 262.06,78.83 260.47,80.43 v2(260.47,83.8)
LOM_SPD10LED_GRN#: length 14.3
  TOP w0.102: UL4.42 267.2,74.48 v2(267.12,74.39) ; v2(261.98,83.1) UL2.2 260.59,83.1 260.1,83.59 UL1.25
  BOTTOM w0.102: v2(267.12,74.39) 267.12,76.52 262.51,81.13 v1(262.51,81.3) 262.51,82.58 v2(261.98,83.1)
LOM_SPD100LED_ORG#: length 23.9
  TOP w0.102: v2(261.98,83.75) UL2.1 261.23,84.25 261.08,84.39 UL1.27 ; v2(276.15,72.5) 275.96,72.68 UL4.16
  BOTTOM w0.102: v2(261.98,83.75) 262.1,83.75 v1(262.95,82.9) 262.95,81.06 270.99,73.02 275.62,73.02 v2(276.15,72.5)
LP_CTL: length 6.6
  TOP w0.102: UV8.B2 203.34,72.96 203.34,72.54 202.84,72.05 202.26,72.05 v1(200.8,70.59) 200.39,70.18 RV79.1 RV516.1
LP_EN: length 18.2
  TOP w0.102: UV8.A5 202.84,75.24 201.56,73.95 v1(201.06,73.95) v2(198.71,73.95)
  BOTTOM w0.102: v2(198.71,73.95) 198.38,73.62 198.38,70.89 198.14,70.65 196.91,70.65 195.73,69.47 195.73,66.46 196.03,66.15 196.85,66.15 198.32,64.68 QV21.2
LP_EN#: length 5.2
  BOTTOM w0.102: v1(198.05,61.95) RV212.2 198.05,64.3 197.67,64.68 QV21.5 196.62,64.68 196.43,64.87 196.43,65.21 196.54,65.33 QV21.6
LPC_LAD0: length 167.4
  TOP w0.102: v2(270.9,61.46) 271.56,60.8 JLPDE1.3 ; v2(252.85,37.31) 252.41,37.76 v1(252.41,38.33) 252.41,38.81 253.31,39.71 UE2.A30 ; UE1.A27 248.79,64.26 247.86,65.2 v2(247.82,65.2)
  IN1 w0.089: v2(164.89,48.11) 170.55,48.11 171.05,47.61 181.38,47.61 183.06,49.3 185.43,49.3 186.12,48.62 186.12,46.84 186.62,46.33 190.6,46.33 191.55,45.38 198.98,45.38 204.93,39.43 205.45,39.43 211.94,32.94 228.64,32.94 229.21,33.51 233.35,33.51 235.32,35.48 242.77,35.48 243.96,36.68 249.29,36.68 249.92,37.31 v2(252.85,37.31)
  IN4 w0.089: v2(270.9,61.46) 269.18,63.18 262.42,63.18 260.75,64.85 249.98,64.85 249.63,64.5 248.52,64.5 v2(247.82,65.2)
  BOTTOM w0.081: UC1.AU14 163.26,52.52 163.26,51.57 163.37,51.47 163.37,49.9 164.53,48.74 164.53,48.52
  BOTTOM w0.089: 164.53,48.52 164.89,48.15 v2(164.89,48.11)
  BOTTOM w0.102: v2(247.82,65.2) 247.82,64.93 249.34,63.42 249.34,62.28 248.96,61.9 248.96,57.7 251.93,54.73 251.93,53.28 253.56,51.65 253.56,48.67 254.11,48.11 254.11,42.75 253.88,42.51 253.88,39.55 252.41,38.08 252.41,37.76 v2(252.85,37.31)
LPC_LAD1: length 161.1
  TOP w0.102: UE2.B32 254.69,39.46 v2(254.94,39.21) ; JLPDE1.4 v2(272.06,60.87) 271.88,60.87 271.49,61.26 v1(271.49,62.15) ; UE1.A26 248.89,64.76 v2(248.71,64.94)
  IN1 w0.089: v2(254.94,39.21) 249.29,39.21 247.21,37.13 243.75,37.13 242.55,35.94 235.12,35.94 234.31,35.13 232.24,35.13 231.06,33.95 229,33.95 228.43,33.38 212.12,33.38 205.63,39.86 205.11,39.86 199.16,45.81 191.73,45.81 189.82,47.73 187.74,47.73 185.71,49.76 182.86,49.76 181.15,48.05 171.2,48.05 170.28,48.97 166.08,48.97 165.76,49.28 v2(164.89,49.28)
  IN4 w0.089: v2(272.06,60.87) 269.53,63.4 262.51,63.4 260.84,65.07 248.84,65.07 v2(248.71,64.94)
  BOTTOM w0.081: UC1.AW12 163.73,51.53 163.95,51.3 163.95,50.01
  BOTTOM w0.102: v2(248.71,64.94) 248.73,64.94 249.79,63.87 249.79,61.09 250.45,60.43 250.45,56.85 252.38,54.91 252.38,53.47 254.02,51.84 254.02,50.87 254.7,50.19 254.7,46.96 254.57,46.84 254.57,42.54 254.33,42.31 254.33,39.82 v2(254.94,39.21) ; 163.95,50.01 164.68,49.28 v2(164.89,49.28)
LPC_LAD2: length 162.4
  TOP w0.102: v2(252.85,37.95) 252.85,38.88 253.18,39.21 UE2.A31 ; UE1.B26 250.94,65.51 v2(251,65.58) ; v2(272.08,61.45) 272.56,60.98 JLPDE1.5
  IN1 w0.089: v2(164.89,48.74) 165.79,48.74 166.02,48.52 170.47,48.52 171.15,47.83 181.26,47.83 182.96,49.53 185.53,49.53 186.37,48.69 186.37,46.9 186.69,46.58 190.65,46.58 191.64,45.59 199.07,45.59 205.02,39.65 205.54,39.65 212.03,33.16 228.55,33.16 229.12,33.73 233.22,33.73 235.2,35.71 242.66,35.71 243.86,36.91 249.22,36.91 250.25,37.95 v2(252.85,37.95)
  IN4 w0.089: v2(272.08,61.45) 269.92,63.62 262.6,63.62 260.93,65.29 257.54,65.29 256.87,65.96 251.38,65.96 v2(251,65.58)
  BOTTOM w0.081: UC1.AY12 163.66,50.03
  BOTTOM w0.102: v2(252.85,37.95) 252.85,37.96 v1(253.39,38.49) 254.11,39.21 254.11,42.41 254.34,42.65 254.34,46.96 254.47,47.09 254.47,50.09 253.79,50.77 253.79,51.74 252.16,53.38 252.16,54.82 249.18,57.79 249.18,61.77 249.57,62.15 249.57,63.52 248.27,64.81 248.27,65.2 248.46,65.39 250.81,65.39 v2(251,65.58) ; v2(164.89,48.74) 164.85,48.74 163.66,49.92 163.66,50.03
LPC_LAD3: length 164.1
  TOP w0.102: v2(251.63,66.47) 251.18,66.01 UE1.B25 ; JLPDE1.6 v2(273.06,60.88) 272.98,60.88 272.59,61.27 272.59,61.73 v1(273.11,62.25) ; UE2.B33 254.57,38.96 254.76,38.77 255.1,38.77 255.53,39.2 v2(255.53,39.21)
  IN1 w0.089: v2(164.87,49.83) 165.7,49.83 166.35,49.17 170.4,49.17 171.31,48.26 181.01,48.26 182.73,49.99 185.84,49.99 187.84,47.98 189.87,47.98 191.82,46.03 199.25,46.03 205.2,40.08 205.72,40.08 212.21,33.59 228.34,33.59 228.95,34.2 231.01,34.2 232.15,35.34 234.19,35.34 235.01,36.17 242.45,36.17 243.66,37.38 247.14,37.38 249.3,39.53 253.71,39.53 253.82,39.64 255.1,39.64 v2(255.53,39.21)
  IN4 w0.089: v2(251.63,66.47) 252.41,66.47 252.62,66.25 256.88,66.25 257.63,65.5 261.02,65.5 262.69,63.83 270.39,63.83 272.59,61.63 272.59,61.35 v2(273.06,60.88)
  BOTTOM w0.081: UC1.AW11 164.41,51.33 164.71,51.04 164.71,50.42 164.87,50.26 v2(164.87,49.83)
  BOTTOM w0.102: v2(251.63,66.47) 252.16,65.94 252.16,61.01 250.7,59.55 250.7,56.93 253.21,54.41 253.21,52.97 254.25,51.93 254.25,50.97 255.2,50.01 255.2,49.55 255.66,49.1 255.66,47.52 254.8,46.66 254.8,42.44 254.56,42.21 254.56,39.98 254.89,39.65 255.09,39.65 v2(255.53,39.21)
LPC_LDRQ1#: length 3
  TOP w0.102: RPE8.1 247.5,66.86 247.84,66.52 v1(248.17,66.52) 248.7,66.52 248.94,66.76 UE1.A22
LPC_LFRAME#: length 170
  TOP w0.102: v2(255.06,40.06) 254.76,40.06 254.67,39.96 UE2.B31 ; v2(273.07,61.46) 273.56,60.97 JLPDE1.7 ; UE1.A21 249.11,67.26 248.84,66.99 248.32,66.99 v2(247.95,67.36)
  IN1 w0.089: v2(164.02,51.9) 166.53,49.39 170.49,49.39 171.4,48.48 180.89,48.48 182.63,50.22 185.94,50.22 187.92,48.23 189.92,48.23 191.91,46.24 199.34,46.24 205.29,40.29 205.81,40.29 212.29,33.81 228.25,33.81 229.6,35.15 231.26,35.15 232.51,36.4 242.33,36.4 243.56,37.63 247.09,37.63 249.24,39.79 253.66,39.79 253.93,40.06 v2(255.06,40.06)
  IN4 w0.089: v2(247.95,67.36) 248.34,66.97 252.21,66.97 252.71,66.47 256.97,66.47 257.72,65.72 261.11,65.72 262.78,64.05 270.48,64.05 v2(273.07,61.46)
  BOTTOM w0.081: v2(164.02,51.9) 163.74,52.18 UC1.AV12
  BOTTOM w0.102: v2(247.95,67.36) 248.39,66.92 251.76,66.92 252.55,66.13 252.55,63.91 253.04,63.41 253.04,61.11 251.65,59.71 251.65,57.31 253.06,55.9 253.06,55.27 253.44,54.89 253.44,53.06 254.47,52.03 254.47,51.07 255.43,50.11 255.43,49.68 255.89,49.22 255.89,46.91 255.75,46.77 255.75,45.85 256.34,45.26 256.34,42.64 v1(256.09,42.39) 255.23,42.39 254.79,41.95 254.79,40.32 v2(255.06,40.06)
M_CLK_DDR0: length 75.5
  IN4 w0.089: v2(149.03,48.8) 149.41,48.42 149.41,46.4 147.17,44.16 147.17,37.17 142.24,32.24 142.24,29.94 137.12,24.83 135.05,24.83 133.81,23.59 115.55,23.59 115.07,23.12 114.8,23.12 114.33,23.59 114.15,23.59 113.98,23.42 113.98,23.24 114.45,22.77 114.45,22.5 114.13,22.17 113.86,22.17 112.45,23.59 112.27,23.59 112.1,23.42 112.1,23.24 112.39,22.95 112.39,22.68 111.95,22.24 111.95,22.06 112.12,21.89 112.3,21.89 112.74,22.33 113,22.33 113.51,21.82 113.51,21.56 113.33,21.38 113.33,19.64 113.1,19.42 112.42,19.42 112.19,19.64 112.19,20.16 112.07,20.29 112,20.29 111.77,20.06 v2(111.77,19.91)
  BOTTOM w0.081: UC1.AV37 148.06,51.88 148.06,48.96 148.53,48.49 148.88,48.49 149.03,48.63 v2(149.03,48.8)
  BOTTOM w0.102: JDIMM1.101 111.4,17.53 111.57,17.69 111.57,18.2 112.25,18.88 112.25,19.47 112.15,19.57 112.15,20.09 112.05,20.19 111.88,20.19 111.77,20.08 v2(111.77,19.91)
M_CLK_DDR1: length 74.6
  IN4 w0.089: v2(148.79,50.55) 148.79,50.77 148.86,50.84 149.1,50.84 149.45,50.5 149.45,48.74 149.64,48.55 149.64,46.14 147.67,44.16 147.67,36.96 142.73,32.03 142.73,29.74 137.33,24.33 135.25,24.33 134.02,23.1 115.75,23.1 113.83,21.17 113.83,19.44 113.35,18.96 113.35,15.16 113.68,14.83 114.13,14.83 114.26,14.71 114.26,14.47 114.13,14.34 113.6,14.34 113.38,14.11 113.38,13.73 113.6,13.5 113.93,13.5 114.02,13.41 114.02,13.1 113.93,13.01 113.68,13.01 113.49,12.82 113.49,12.12 113.34,11.97 113.21,11.97 v2(112.9,12.28)
  BOTTOM w0.081: v2(148.79,50.55) 149.11,50.88 UC1.AY36
  BOTTOM w0.102: v2(112.9,12.28) 112.62,12 112.44,12 112.2,11.77 112.2,10.75 111.89,10.45 111.89,9.56 111.7,9.37 JDIMM1.102
M_CLK_DDR2: length 91.4
  IN1 w0.089: v2(147.76,54.96) 147.54,55.18 147.37,55.18 147.29,55.1 147.29,53.25 146.82,52.79 146.82,49.33 147.56,48.58 147.56,47.12 147.38,46.93 147.06,46.93 146.94,46.8 146.94,46.56 147.06,46.44 147.38,46.44 147.56,46.25 147.56,45.79 147.38,45.6 147.07,45.6 146.94,45.47 146.94,45.23 147.07,45.11 147.26,45.11 147.49,44.88 147.49,44.35 147.26,44.13 146.92,44.13 146.8,44 146.8,36.88 158.17,25.51 174.24,25.51 174.43,25.32 174.43,25.13 174.56,25.01 174.8,25.01 174.92,25.13 174.92,25.32 175.11,25.51 175.57,25.51 175.76,25.32 175.76,25.13 175.89,25.01 176.13,25.01 176.26,25.13 176.26,25.32 176.44,25.51 176.9,25.51 177.09,25.32 177.09,25.13 177.18,25.04 177.5,25.04 177.59,25.13 177.59,25.32 177.78,25.51 178.23,25.51 178.42,25.32 178.42,25.13 178.51,25.04 178.83,25.04 178.92,25.13 178.92,25.32 179.11,25.51 179.56,25.51 179.75,25.32 179.75,25.13 179.84,25.04 180.16,25.04 180.25,25.13 180.25,25.32 180.44,25.51 180.9,25.51 181.08,25.32 181.08,25.13 181.17,25.04 181.49,25.04 181.58,25.13 181.58,25.28 181.81,25.51 182.25,25.51 182.48,25.28 182.48,25.13 182.6,25.01 183.34,25.01 183.93,24.43 184.65,24.43 184.9,24.68 185.33,24.68 185.59,24.43 185.88,24.43 186.13,24.68 186.56,24.68 186.82,24.43 187.11,24.43 187.36,24.68 187.79,24.68 188.05,24.43 188.34,24.43 188.59,24.68 189.02,24.68 189.28,24.43 189.63,24.43 189.88,24.68 190.26,24.68 190.9,24.05 191,24.05 191.34,24.38 191.64,24.38 192,24.02 192,23.76 191.68,23.44 191.68,23.26 191.85,23.09 192.03,23.09 192.35,23.41 192.62,23.41 192.94,23.08 192.94,22.81 192.24,22.11 192.24,21.93 192.41,21.76 192.59,21.76 193.26,22.44 193.59,22.44 193.86,22.16 193.86,21.84 193.78,21.75 193.78,21.63 193.94,21.47 193.94,20.52 193.58,20.15 193.17,20.15 193.09,20.07 193.09,19.91 v2(193.21,19.79)
  BOTTOM w0.081: UC1.AN38 148.08,55.29 v2(147.76,54.96)
  BOTTOM w0.102: JDIMM2.101 192.9,17.47 193.1,17.67 193.1,18.19 193.76,18.84 193.76,19.93 193.64,20.04 193.46,20.04 v2(193.21,19.79)
M_CLK_DDR3: length 92
  IN1 w0.089: v2(194.28,11.57) 194.28,11.32 194.19,11.24 193.96,11.24 193.87,11.33 193.87,11.55 193.67,11.75 193.67,12.58 193.83,12.74 194.57,12.74 194.75,12.92 194.75,13.39 194.57,13.57 193.83,13.57 193.67,13.73 193.67,13.99 193.06,14.6 193.06,18.58 192.79,18.85 192.27,18.85 192.15,18.97 192.15,20.17 192.37,20.39 192.37,20.73 191.57,21.52 191.57,22.43 190.25,23.75 183.66,23.75 183.07,24.34 173.99,24.34 173.5,24.83 158.62,24.83 158.36,24.57 158.16,24.57 146.13,36.61 146.13,47.11 146.28,47.26 146.28,52.81 146.81,53.34 146.81,55.68 147.2,56.06 147.2,56.34 147.33,56.47 147.72,56.47 147.76,56.43 v2(147.76,56.27)
  BOTTOM w0.081: UC1.AL38 148.08,56.59 v2(147.76,56.27)
  BOTTOM w0.102: v2(194.28,11.57) 194.28,11.38 194.1,11.2 193.89,11.2 193.66,10.97 193.66,10.45 193.4,10.2 193.4,9.54 193.2,9.34 JDIMM2.102
M_CLK_DDR#0: length 75.5
  IN4 w0.089: v2(149.03,48.15) 149.24,47.94 149.24,46.47 147,44.23 147,37.24 142.07,32.31 142.07,30.01 137.05,25 134.98,25 133.74,23.76 115.48,23.76 115,23.29 114.87,23.29 114.4,23.76 114.08,23.76 113.81,23.49 113.81,23.17 114.28,22.7 114.28,22.57 114.06,22.34 113.93,22.34 112.52,23.76 112.19,23.76 111.92,23.49 111.92,23.17 112.22,22.88 112.22,22.75 111.78,22.32 111.78,21.99 112.05,21.72 112.37,21.72 112.81,22.16 112.93,22.16 113.34,21.75 113.34,21.63 113.16,21.45 113.16,19.71 113.03,19.59 112.49,19.59 112.36,19.71 112.36,20.23 112.14,20.46 111.98,20.46 111.77,20.67 v2(111.77,20.68)
  BOTTOM w0.081: UC1.AU37 148.31,52.54 148.07,52.3 148.07,52.12 147.9,51.96 147.9,48.89 148.47,48.32 148.85,48.32 v2(149.03,48.15)
  BOTTOM w0.102: v2(111.77,20.68) 112.05,20.4 112.13,20.4 112.36,20.18 112.36,19.66 112.46,19.55 112.46,18.8 111.78,18.11 111.78,17.73 112,17.5 JDIMM1.103
M_CLK_DDR#1: length 74.6
  IN4 w0.089: v2(112.9,11.52) 113.18,11.8 113.41,11.8 113.66,12.05 113.66,12.75 113.75,12.84 114,12.84 114.19,13.03 114.19,13.48 114,13.67 113.68,13.67 113.55,13.8 113.55,14.04 113.68,14.17 114.2,14.17 114.43,14.4 114.43,14.78 114.2,15 113.75,15 113.52,15.23 113.52,18.89 114,19.37 114,21.1 115.82,22.93 134.09,22.93 135.32,24.16 137.4,24.16 142.9,29.67 142.9,31.96 147.84,36.89 147.84,44.09 149.81,46.07 149.81,48.62 149.62,48.81 149.62,50.57 149.18,51.01 148.98,51.01 v2(148.79,51.2)
  BOTTOM w0.081: UC1.AW36 149.11,51.53 v2(148.79,51.2)
  BOTTOM w0.102: v2(112.9,11.52) 112.62,11.8 112.52,11.8 112.41,11.68 112.41,10.67 112.1,10.36 112.1,9.54 112.3,9.34 JDIMM1.104
M_CLK_DDR#2: length 91.4
  IN1 w0.089: v2(147.76,55.62) 147.75,55.62 147.49,55.35 147.3,55.35 147.12,55.17 147.12,53.32 146.65,52.86 146.65,49.26 147.39,48.51 147.39,47.19 147.3,47.1 146.99,47.1 146.77,46.88 146.77,46.49 146.99,46.27 147.3,46.27 147.39,46.18 147.39,45.86 147.3,45.77 147,45.77 146.77,45.54 146.77,45.16 147,44.94 147.19,44.94 147.32,44.81 147.32,44.42 147.19,44.3 146.85,44.3 146.63,44.07 146.63,36.81 158.1,25.34 174.17,25.34 174.26,25.25 174.26,25.06 174.49,24.84 174.87,24.84 175.09,25.06 175.09,25.25 175.18,25.34 175.5,25.34 175.59,25.25 175.59,25.06 175.82,24.84 176.2,24.84 176.43,25.06 176.43,25.25 176.51,25.34 176.83,25.34 176.92,25.25 176.92,25.05 177.11,24.87 177.57,24.87 177.76,25.05 177.76,25.25 177.85,25.34 178.16,25.34 178.25,25.25 178.25,25.05 178.44,24.87 178.9,24.87 179.09,25.05 179.09,25.25 179.18,25.34 179.49,25.34 179.58,25.25 179.58,25.05 179.77,24.87 180.23,24.87 180.42,25.05 180.42,25.25 180.51,25.34 180.83,25.34 180.91,25.25 180.91,25.05 181.1,24.87 181.56,24.87 181.75,25.05 181.75,25.21 181.88,25.34 182.18,25.34 182.31,25.21 182.31,25.06 182.52,24.84 183.27,24.84 183.85,24.26 184.72,24.26 184.97,24.51 185.26,24.51 185.52,24.26 185.95,24.26 186.2,24.51 186.49,24.51 186.75,24.26 187.18,24.26 187.43,24.51 187.72,24.51 187.98,24.26 188.41,24.26 188.66,24.51 188.95,24.51 189.21,24.26 189.7,24.26 189.95,24.51 190.19,24.51 190.83,23.88 191.07,23.88 191.41,24.21 191.57,24.21 191.83,23.95 191.83,23.83 191.51,23.51 191.51,23.19 191.78,22.92 192.1,22.92 192.42,23.24 192.55,23.24 192.77,23.01 192.77,22.89 192.07,22.18 192.07,21.86 192.34,21.59 192.66,21.59 193.34,22.27 193.51,22.27 193.69,22.09 193.69,21.91 193.61,21.83 193.61,21.56 193.77,21.4 193.77,20.59 193.51,20.32 193.44,20.32 v2(193.21,20.55)
  BOTTOM w0.081: UC1.AM38 148.08,55.94 v2(147.76,55.62)
  BOTTOM w0.102: v2(193.21,20.55) 193.51,20.25 193.73,20.25 193.96,20.01 193.96,18.75 193.31,18.1 193.31,17.68 193.5,17.49 JDIMM2.103
M_CLK_DDR#3: length 92
  IN1 w0.089: v2(147.76,56.92) 147.82,56.86 147.82,56.74 147.72,56.64 147.26,56.64 147.02,56.41 147.02,56.13 146.64,55.75 146.64,53.41 146.11,52.88 146.11,47.33 145.96,47.18 145.96,36.54 158.09,24.4 158.43,24.4 158.69,24.66 173.43,24.66 173.92,24.17 183,24.17 183.59,23.58 190.18,23.58 191.4,22.36 191.4,21.45 192.2,20.65 192.2,20.46 191.98,20.24 191.98,18.9 192.2,18.68 192.72,18.68 192.89,18.51 192.89,14.53 193.5,13.91 193.5,13.66 193.76,13.4 194.49,13.4 194.58,13.31 194.58,12.99 194.5,12.91 193.76,12.91 193.5,12.65 193.5,11.68 193.7,11.48 193.7,11.26 193.89,11.07 194.02,11.07 v2(194.28,10.81)
  BOTTOM w0.081: v2(147.76,56.92) 148.08,57.24 UC1.AK38
  BOTTOM w0.102: v2(194.28,10.81) 194.1,10.99 193.97,10.99 193.87,10.89 193.87,10.37 193.61,10.11 193.61,9.55 193.8,9.36 JDIMM2.104
M_ODT0: length 3.3
  TOP w0.168: v2(117.09,10.33) 117.7,10.33 RD10.2
  BOTTOM w0.168: JDIMM1.116 115.9,9.14 v2(117.09,10.33)
M_ODT1: length 2.2
  TOP w0.168: RD11.2 117.58,9.69 v2(117.1,9.69)
  BOTTOM w0.168: JDIMM1.120 v2(117.1,9.69)
M_ODT2: length 4.2
  TOP w0.168: RD12.2 199.02,8.42 v1(198.37,7.77) 197.47,6.87 v2(197.47,6.71)
  BOTTOM w0.168: v2(197.47,6.71) 197.4,6.78 JDIMM2.116
M_ODT3: length 2.9
  TOP w0.168: RD13.2 199.31,7.08 v2(198.76,6.53)
  BOTTOM w0.168: v2(198.76,6.53) 198.6,6.7 JDIMM2.120
MASK_BASE_LEDS#: length 43.9
  TOP w0.102: v2(267.22,60.53) 266.76,61 265.6,61 265.22,60.62 v1(265.22,59.69) 265.22,57.89 264.8,57.47 262.87,57.47 262.73,57.33 UZ10.4 ; QZ7.5 285.99,81.77 285.86,81.9 283.93,81.9 283.07,81.04 v2(283.07,80.34)
  IN1 w0.089: v2(283.07,80.34) 282,79.27 282,70.79 280.28,69.07 272.57,69.07 267.22,63.72 v2(267.22,60.53)
MASK_SATA_LED#: length 70.6
  TOP w0.102: UE1.B9 254.87,69.32 v2(255.38,68.82) ; v2(273.28,20.61) 272.64,20.61 272.21,20.19 271.32,20.19 271.05,19.92 QZ3.5
  IN1 w0.089: v2(273.28,20.61) 274.3,21.64 274.3,23.76 273.8,24.27 273.8,25.7 271.52,27.98 271.52,33.74 274.4,36.61 274.4,40.85 276.27,42.71 276.27,47.15 274.6,48.81 270.27,48.81 266.33,52.75 266.33,54.35 263.94,56.74 263.94,58.83 262.65,60.12 262.65,63.55 260.87,65.33 260.87,67.72 260.31,68.27 255.92,68.27 v2(255.38,68.82)
  BOTTOM w0.102: v1(254.77,68.35) 255.24,68.82 v2(255.38,68.82)
MCARD_PCIE#_SATA: length 137.6
  TOP w0.102: UE2.B8 259.44,46.75 259.29,46.6 259.29,45.92 258.97,45.6 v2(258.88,45.6)
  IN3 w0.081: 173.36,60.43 173.08,60.43 172.88,60.62 172.27,60.62 v2(171.94,60.96)
  IN3 w0.122: v2(258.88,45.6) 258.88,44.99 257.4,43.51 255.15,43.51 253.53,41.88 251.33,41.88 250.38,40.93 250.38,37.88 249.55,37.06 248.79,37.06 244.57,32.83 244.25,32.83 243.35,31.94 242.2,31.94 240.79,30.53 240.79,27.79 240.28,27.28 238.63,27.28 237.61,26.26 236.94,26.26 236.63,26.58 234.98,26.58 234.98,26.58 234.93,26.58 234.06,27.44 230.43,27.44 229.59,26.6 207.74,26.6 204.59,29.75 196.35,29.75 188.08,38.02 188.08,41.68 185.38,44.39 185.38,49.25 182.69,51.94 182.69,53.7 179.03,57.35 177.9,57.35 174.83,60.43 173.36,60.43
  BOTTOM w0.076: v2(171.94,60.96) 171.55,61.35 171.09,61.35 UC1.AC1
  BOTTOM w0.102: v2(171.94,60.96) 172.7,61.71 179.33,61.71 179.87,62.25 181.75,62.25 v1(182.46,62.97) 182.84,63.35 182.84,63.96 182.04,64.76 RPC6.7
MCP_TESTLOW1: length 8.8
  BOTTOM w0.076: UC1.C35 149.61,72.48 149.51,72.63 149.47,72.79 149.47,72.97 149.48,73 149.49,73 149.53,73.13 149.53,73.23 149.47,73.4 148.92,73.95 148.92,76.26
  BOTTOM w0.102: RC240.1 v1(147.71,78.7) 148.92,77.49 148.92,76.26
MCP_TESTLOW2: length 9
  BOTTOM w0.076: 149.15,76.26 149.15,74.06 149.61,73.59 149.61,73.5 149.62,73.49 149.7,73.26 149.7,73.1 149.67,73.01 149.67,73.01 149.66,73 149.64,72.94 149.64,72.81 149.67,72.71 149.87,72.5 150.05,72.5 150.22,72.33 UC1.C34
  BOTTOM w0.102: 149.15,76.26 v1(149.15,78.16) 149.15,78.98 148.64,79.49 RC241.1
MCP_TESTLOW3: length 11.1
  TOP w0.102: RC242.1 165.78,47.67 166.48,48.37 166.48,52.69 166.99,53.19 166.99,55.75 v1(166.63,56.11) 166.08,56.65 v2(166.08,56.66)
  BOTTOM w0.081: v2(166.08,56.66) 166.48,57.06 UC1.AK8
MCP_TESTLOW4: length 10.6
  TOP w0.102: v2(166.11,56.05) 166.67,55.49 166.67,53.51 166.04,52.88 166.04,48.62 v1(165.61,48.19) 164.83,47.42 RC243.1
  BOTTOM w0.081: UC1.AL8 166.47,56.41 v2(166.11,56.05)
MDP_AUX#_C: length 20.9
  TOP w0.102: RV501.2 283.09,71.86 v2(283.52,71.86)
  IN1 w0.089: v2(287.91,71.33) 287.7,71.54 287.03,71.54 286.76,71.81 284.85,71.81 284.56,72.1 283.77,72.1 v2(283.52,71.86)
  IN4 w0.089: v2(283.91,66.27) 284.29,66.27 284.46,66.45 284.46,67.17 283.4,68.24 283.4,70.97 283.97,71.54 283.97,72 283.87,72.1 283.77,72.1 v2(283.52,71.86)
  BOTTOM w0.102: UV502.8 282.45,71.39 282.92,71.86 v2(283.52,71.86) ; v2(287.91,71.33) 288.1,71.52 288.4,71.52 289.49,72.62 289.87,72.62 290.04,72.45 JMDP1.18 ; v2(283.91,66.27) 283.45,66.27 283.1,65.92 UV502.6
MDP_AUX_C: length 21
  TOP w0.102: v2(283.52,72.5) 282.9,72.5 RV502.2
  IN1 w0.089: v2(283.52,72.5) 283.75,72.27 284.63,72.27 284.92,71.98 286.83,71.98 287.1,71.71 287.7,71.71 v2(287.91,71.92)
  IN4 w0.089: v2(283.52,72.5) 283.75,72.27 283.94,72.27 284.14,72.07 284.14,71.47 283.57,70.9 283.57,68.31 284.63,67.24 284.63,66.68 v2(285.05,66.27)
  BOTTOM w0.102: UV502.11 284.4,71.62 v2(283.52,72.5) ; v2(287.91,71.92) 288.1,71.73 288.31,71.73 289.41,72.83 289.89,72.83 290.12,73.05 JMDP1.16 ; UV502.3 285.05,65.66 285.18,65.79 285.3,65.79 285.43,65.91 285.43,66.14 285.3,66.27 v2(285.05,66.27)
MDP_CA_DET: length 20.9
  TOP w0.102: v2(285.81,66.71) 285.29,67.23 QV502.2 285.29,70.41 285.63,70.75 RV504.1 286.64,71.35 v1(286.82,71.53) 287.08,71.79 287.08,73.44 287.65,74.02 288.84,74.02 289.5,74.68 289.6,74.68 290.26,75.33 290.26,75.84 289.47,76.62 v2(289.47,76.62)
  BOTTOM w0.102: UV502.4 284.4,66.51 284.79,66.9 285.62,66.9 v2(285.81,66.71) 286.35,66.17 UV502.1 ; JMDP1.4 289.51,76.65 v2(289.47,76.62)
MDP_CA_DET#: length 9.2
  TOP w0.102: v2(284.67,68.62) 284.64,68.59 QV502.1 283.36,67.79 283.09,67.53 RV507.2 281.23,67.53 v1(281.14,67.44)
  BOTTOM w0.102: UV502.10 283.75,69.54 v2(284.67,68.62) 285.7,69.65 UV502.13
MDP_HPD: length 12.5
  TOP w0.102: QV501.1 288.16,70.07 RV505.2 287.33,70.89 287.33,73.28 287.34,73.32 287.8,73.79 288.94,73.79 289.6,74.45 289.95,74.45 v1(290.71,75.21) 290.71,75.97 v2(289.48,77.2)
  BOTTOM w0.102: JMDP1.2 289.53,77.25 v2(289.48,77.2)
MDP_LANE_N0_C: length 9.7
  IN1 w0.089: v2(288.09,74.44) 288.25,74.61 291.14,74.61 291.37,74.83 291.37,75.46 291.14,75.68 290.48,75.68 290.36,75.81 290.36,76.34 290.48,76.46 292.53,76.46 JMDP1.5
  BOTTOM w0.102: CV508.1 287.48,74.62 287.91,74.62 v2(288.09,74.44)
MDP_LANE_N1_C: length 9.7
  IN4 w0.089: JMDP1.11 294.29,74.71 292.75,74.71 289.33,78.13 288.2,78.13 v2(288.1,78.04)
  BOTTOM w0.102: CV506.1 287.36,78.18 287.96,78.18 v2(288.1,78.04)
MDP_LANE_N2_C: length 6.4
  IN4 w0.089: JMDP1.17 292.53,72.46 291.46,72.46 291.13,72.79 288.32,72.79 v2(288.11,72.59)
  BOTTOM w0.102: v2(288.11,72.59) 287.93,72.78 287.48,72.78 CV504.1
MDP_LANE_N3_C: length 6.1
  BOTTOM w0.102: CV502.1 287.48,76.46 287.7,76.46 287.78,76.54 288.11,76.54 288.59,76.06 288.59,75.49 288.7,75.38 288.7,74.39 288.96,74.12 289.35,74.12 289.67,74.45 289.75,74.45 289.95,74.25 JMDP1.12
MDP_LANE_P0_C: length 9.8
  IN1 w0.089: v2(288.09,75.03) 288.34,74.78 291.07,74.78 291.2,74.9 291.2,75.39 291.07,75.51 290.41,75.51 290.19,75.74 290.19,76.41 290.41,76.63 292.53,76.63 JMDP1.3
  BOTTOM w0.102: CV507.1 287.48,74.83 287.89,74.83 v2(288.09,75.03)
MDP_LANE_P1_C: length 9.7
  IN4 w0.089: v2(288.1,78.62) 288.42,78.3 289.4,78.3 292.82,74.88 294.78,74.88 JMDP1.9
  BOTTOM w0.102: CV505.1 287.6,78.39 287.87,78.39 v2(288.1,78.62)
MDP_LANE_P2_C: length 6.4
  IN4 w0.089: v2(288.11,73.17) 288.32,72.96 291.2,72.96 291.53,72.63 292.53,72.63 JMDP1.15
  BOTTOM w0.102: v2(288.11,73.17) 287.93,72.98 287.48,72.98 CV503.1
MDP_LANE_P3_C: length 6.1
  BOTTOM w0.102: CV501.1 287.48,76.67 287.61,76.67 287.69,76.75 288.2,76.75 288.27,76.67 288.3,76.67 v4(288.54,76.43) 288.8,76.17 288.8,75.58 288.91,75.47 288.91,74.47 289.05,74.33 289.26,74.33 289.58,74.65 289.75,74.65 289.95,74.85 JMDP1.10
ME_FWP: length 150.8
  TOP w0.102: RC301.1 259.27,21.54 v2(259.31,21.5) ; RC11.1 169.34,45.38 170.62,44.09 170.62,43.17 v1(172.69,41.11) v2(176.39,37.41)
  IN3 w0.122: v2(259.31,21.5) 259.31,19.84 258.62,19.15 242.82,19.15 240.07,16.4 204.22,16.4 202.83,17.79 202.83,20.45 201.05,22.24 190.72,22.24 176.39,36.58 v2(176.39,37.41)
  BOTTOM w0.102: v2(259.31,21.5) 263.74,21.5 267.2,18.04 269.53,18.04 271.85,15.73 282.56,15.73 290.95,7.34 292.86,7.34 293.13,7.07 SW1.3
ME_FWP_EC: length 63.8
  TOP w0.102: RC301.2 259.27,24.73 v1(259.41,24.87) v2(259.8,25.26) ; v2(260.42,38.52) 260.44,38.51 UE2.B46
  IN1 w0.089: v2(260.42,38.52) 260.42,37.92 261.21,37.13 261.21,35.92 260.92,35.63 260.92,33.59 v2(260.73,33.4)
  BOTTOM w0.102: SW1.1 297.13,7.64 296.54,8.23 291.84,8.23 290.89,9.18 290.89,10.87 285.8,15.96 271.95,15.96 269.64,18.27 267.32,18.27 260.33,25.26 v2(259.8,25.26) 259.85,25.31 259.85,32.52 v2(260.73,33.4)
ME_RESET#: length 4.9
  TOP w0.102: v1(187.67,74.6) 187.4,74.87 186.04,74.87 185.65,74.47 RC95.2 RC80.1 184.58,74.14 UC4.2
ME_SUS_PWR_ACK: length 117.7
  TOP w0.102: RC79.2 170.88,46.47 v1(170.88,49.12) 170.88,49.9 v2(171.24,50.27) ; UE2.A8 259.19,48.34 259.27,48.42 259.27,52.04 259.43,52.2 259.43,54.1 v2(259.11,54.42)
  IN1 w0.089: v2(244.09,49.76) 240.66,49.76 231.53,40.62 215.95,40.62 214.8,41.78 205.9,41.78 199.96,47.73 195.28,47.73 193.18,49.82 189.67,49.82 187.5,51.99 185.24,51.99 184.99,51.74 182.55,51.74 181.28,53.01 181.28,53.85 179.51,55.62 176.51,55.62 171.24,50.34 v2(171.24,50.27)
  IN4 w0.089: v2(244.09,49.76) 245.98,49.76 250.78,54.56 258.97,54.56 v2(259.11,54.42)
  BOTTOM w0.081: UC1.AV4 169.13,51.87 169.13,51.4 169.19,51.35 169.19,51.02 169.19,51.02 169.19,50.74 169.19,50.74 169.19,50.67
  BOTTOM w0.102: 169.19,50.67 169.59,50.27 v2(171.24,50.27)
MEC_XTAL1: length 5.9
  TOP w0.102: UE2.A61 266.67,44.71 v1(266.74,44.78) 266.9,44.94 CE28.1 268.04,44.94 268.28,45.19 269.17,45.19 269.35,45.01 YE1.1
MEC_XTAL2: length 3.5
  TOP w0.102: YE1.2 269.35,46.08 269.09,45.82 CE29.1 RE61.2
MEC_XTAL2_R: length 3.1
  TOP w0.102: RE61.1 v1(265.61,45.53) 265.29,45.21 UE2.A62
MEDIACARD_IRQ#: length 176.3
  TOP w0.102: v2(180.22,60.86) 180.22,60.18 180.93,59.46 183.41,59.46 183.81,59.86 RPC5.6 ; v2(283.72,26.01) 283.72,26.45 v1(283.64,26.53) 283.56,26.61 283.56,27.19 283.72,27.34 UR1.16
  IN1 w0.076: 173.36,60.17 173.04,60.17 172.68,59.8 171.04,59.8 169.97,60.88 169.03,60.88 168.52,61.39 168.22,61.39 v2(167.67,61.93)
  IN1 w0.089: v2(180.22,60.86) 179.87,61.2 178.25,61.2 177.23,60.17 173.36,60.17
  IN3 w0.122: v2(283.72,26.01) 283.58,26.01 283,26.58 283,28.6 282.35,29.25 282.35,34.37 280.89,35.83 280.89,36.26 279.82,37.34 279.82,37.94 276.37,41.39 276.37,42.63 270.73,48.27 267.15,48.27 265.09,46.2 263.84,46.2 262.55,47.49 257.55,47.49 257.16,47.09 254.7,47.09 254,46.39 251.01,46.39 250.82,46.58 249.49,46.58 248.41,45.5 248.41,38.71 245.49,35.79 244.92,35.79 243.71,34.58 241.81,34.58 241.04,33.82 241.04,32.71 239.65,31.33 235.58,31.33 232.95,28.7 229.91,28.7 229.07,27.85 209.58,27.85 206.36,31.07 197.06,31.07 189.47,38.66 189.47,42.22 187.32,44.36 187.32,49.43 186.59,50.16 186.59,54.3 184.15,56.74 182.73,56.74 180.22,59.26 v2(180.22,60.86)
  BOTTOM w0.081: v2(167.67,61.93) 167.5,61.75 UC1.AB6
MEDIACARD_PWREN: length 1.6
  TOP w0.102: UR1.14 282.92,27.46 282.71,27.25 RR15.2
MEDIACARD_RST#: length 20.3
  TOP w0.102: v2(183.42,58.89) 183.42,59.15 183.64,59.36 RPC5.7
  IN1 w0.089: v2(183.42,58.89) 183.42,57.95 182.66,57.19 182.29,57.19 181.48,57.99 180.65,57.99 180.45,58.19 174.46,58.19 173.7,57.43 168.92,57.43 167.76,58.59 v2(167.76,59.07)
  BOTTOM w0.081: UC1.AG6 167.5,58.6 167.76,58.85 v2(167.76,59.07)
MEM_SMBCLK: length 38.6
  TOP w0.102: v2(184.36,55.1) 184.19,54.93 184.19,54.56 183.73,54.1 183.73,51.59 184.44,50.88 185.25,50.88 186.69,49.44 189.52,49.44 191.07,50.99 191.07,51.16 190.96,51.27 QC1.6
  IN1 w0.089: v2(181.66,60) 181.46,59.8 181.46,59.67 181.59,59.54 183.68,59.54 184.53,58.69 184.53,56.06 184.18,55.71 184.18,55.28 v2(184.36,55.1)
  IN4 w0.089: v2(181.66,60) 181.25,59.59 180.91,59.59 180.13,58.81 172.5,58.81 170.81,57.12 170.81,55.82 171.27,55.36 v2(171.27,54.62)
  BOTTOM w0.076: UC1.AP2 170.37,54.3 170.66,54.59 171.25,54.59 v2(171.27,54.62)
  BOTTOM w0.102: RPC14.1 182.61,60 182.43,60.18 181.83,60.18 v2(181.66,60)
MEM_SMBDATA: length 37.1
  TOP w0.102: QC1.3 192.16,52.57 191.3,51.7 191.3,50.9 189.61,49.21 186.59,49.21 185.16,50.65 184.34,50.65 183.5,51.49 183.5,54.19 183.96,54.65 183.96,54.91 v2(183.78,55.1)
  IN1 w0.089: v2(181.07,60.02) 181.24,59.85 181.24,59.58 181.5,59.33 183.59,59.33 184.31,58.6 184.31,56.15 183.96,55.8 183.96,55.28 v2(183.78,55.1)
  BOTTOM w0.076: UC1.AH1 170.93,57.89 171.82,57.89 172.76,58.83 173.36,58.83
  BOTTOM w0.102: RPC14.2 182.74,60.5 182.64,60.41 181.46,60.41 v2(181.07,60.02) 180.22,60.02 180.16,60.08 177.14,60.08 177.07,60.02 174.98,60.02 173.78,58.83 173.36,58.83
MIC1_L: length 2.6
  TOP w0.203: UA1.19 33.06,22.33
  TOP w0.254: 33.06,22.33 33.32,22.6 CA43.1
MIC1_R: length 2.7
  TOP w0.203: UA1.20 32.66,22.04
  TOP w0.254: CA44.1 32.66,22.49 32.66,22.04
MMICLK_REQ#: length 171.4
  TOP w0.102: v2(284.01,27.06) 284.12,27.17 UR1.17
  IN3 w0.122: v2(284.01,27.06) 284.01,34.14 281.9,36.25 281.9,36.68 280.82,37.76 280.82,38.62 278.34,41.1 278.34,42.18 271.08,49.44 270.63,49.44 266.15,53.93 262.61,53.93 261.62,52.93 249.47,52.93 244.22,47.68 244.22,42.77 242.25,40.8 236.28,40.8 230.76,35.28 229.36,35.28 227.69,33.61 210.75,33.61 208.39,35.97 200.05,35.97 194.36,41.65 194.36,46.96 194.1,47.22 194.1,48.48 193.96,48.62 192.99,49.59 192.99,56.09 188.59,60.49 188.59,62.56 186.2,64.94 175.78,64.94 175.06,64.23 172.99,64.23 172.76,64.46 172.42,64.46 v2(172.05,64.84)
  BOTTOM w0.076: UC1.U2 170.42,64.32 170.97,64.32 171.05,64.24 171.68,64.24 172.05,64.6 v2(172.05,64.84) 172.68,65.48 173.61,65.48 173.9,65.19
  BOTTOM w0.102: RPC18.7 176.39,65.38 175.43,64.42 174.67,64.42 v1(173.91,65.18) 173.9,65.19
MPCIE_RST#: length 6.4
  BOTTOM w0.076: 173.9,63.96 v1(173.54,63.96) 173.1,63.51 171.17,63.51 170.94,63.29 UC1.V1
  BOTTOM w0.102: RPC18.5 176.05,64.38 175.63,63.96 173.9,63.96
MPHYP_PWR_EN: length 71.1
  TOP w0.102: QZ10.2 149.5,84.91 149.15,85.26 v2(149.15,86.46) v1(151.85,86.46)
  IN3 w0.122: v2(149.15,86.46) 149.66,86.46 158.59,95.39 159.35,95.39 159.7,95.74 163.69,95.74 164.04,95.39 164.95,95.39 166.48,93.85 166.48,88.6 164.83,86.95 164.83,82.79 169.99,77.63 169.99,76.86 170.76,76.09 170.76,65.8 170.9,65.66 170.9,64.66 172.06,63.5 172.82,63.5 173.06,63.74 173.74,63.74 174.12,63.36 v2(174.13,63.36)
  BOTTOM w0.076: 173.36,62.94 173.24,62.94 173,63.18 171.32,63.18 170.97,62.83 170.43,62.83 UC1.Y2
  BOTTOM w0.102: RC155.1 RC171.1 176.23,63.22 175.72,63.73 174.5,63.73 v2(174.13,63.36) 174.13,63.37 173.69,62.94 173.36,62.94
MPHYP_PWR_EN#: length 3.8
  TOP w0.102: RZ16.2 146.87,84.91 QZ10.5 ; RZ16.2 145.57,84.89 v1(145.5,84.96) ; RZ16.2 147.5,84.26 QZ10.6
MSATA_DEVSLP: length 120
  TOP w0.102: RZ39.2 v2(241.65,63.09) 241.77,63.09 v1(242.66,62.2)
  IN3 w0.081: v2(172.2,67.02) 172.62,67.43 173.36,67.43
  IN3 w0.122: 173.36,67.43 176.63,67.43 177.07,66.99 180.1,66.99 180.77,67.67 184.44,67.67 185.3,66.81 187.08,66.81 191.02,62.86 191.02,59.82 195.26,55.58 195.4,55.44 195.4,47.68 195.61,47.48 195.61,42.16 199.32,38.46 213.42,38.46 216.04,35.83 223.66,35.83 224.44,36.61 229.23,36.61 229.93,37.31 230.82,37.31 233.74,40.23 233.74,45.57 235.9,47.73 235.9,58.08 v2(237.68,59.85)
  BOTTOM w0.076: v2(172.2,67.02) 172.2,67 171.2,65.99 170.59,65.99 170.58,65.98 170.58,65.98 UC1.P2
  BOTTOM w0.102: v2(241.65,63.09) 241.15,63.6 JNGFF2.30 238.49,63.6 237.68,62.79 v2(237.68,59.85)
MSCLK: length 51.5
  TOP w0.102: v2(300.42,36.93) 299.96,37.39 RE72.2 299.21,37.5 299.14,37.57 298.58,38.13 JDEG1.6 ; v2(258.7,39.15) 258.7,39.15 259.09,38.77 259.09,38.29 258.94,38.14 UE2.B43
  BOTTOM w0.102: v2(258.7,39.15) 259.09,38.76 259.09,38.05 259.95,37.19 v1(260.92,37.19) 263.33,37.19 264.16,36.36 266.79,36.36 267.47,37.04 267.47,37.4 271.05,40.98 274.55,40.98 275.63,39.9 283.95,39.9 285.39,38.46 296.99,38.46 298.07,37.38 299.97,37.38 v2(300.42,36.93)
MSDATA: length 50.1
  TOP w0.102: RE86.1 258.3,35.16 258.62,35.48 v2(258.62,36.18) 258.69,36.24 UE2.A40 ; RE75.2 299.96,36.44 v2(299.46,36.93) 299.27,36.93 298.57,37.63 JDEG1.7
  BOTTOM w0.102: v2(258.62,36.18) v1(259.19,36.75) 263.45,36.75 264.09,36.11 267.85,36.11 269.28,37.54 269.28,38.38 271.59,40.69 274.47,40.69 275.49,39.67 281.05,39.67 281.65,39.08 284.39,39.08 285.26,38.2 296.86,38.2 298.13,36.93 v2(299.46,36.93)
NB_LAN_TX0+: length 9.4
  BOTTOM w0.229: TL1.13 265.45,92.01 265.81,92.37 265.81,92.82 266.22,93.23 268.22,93.23 268.98,93.99 268.98,95.08 268.48,95.59 268.48,96.28 268.87,96.68 268.87,96.7 268.88,96.71 JLOM1.1
NB_LAN_TX0-: length 9.5
  BOTTOM w0.229: JLOM1.2 269.75,96.34 269.02,96.34 268.82,96.14 268.82,95.73 269.33,95.22 269.33,93.85 268.36,92.89 267.31,92.89 267.24,92.82 ; 267.24,92.82 v1(267.24,92.84) ; 267.24,92.82 267.18,92.89 266.36,92.89 266.15,92.68 266.15,92.47 266.72,91.9 TL1.14
NB_LAN_TX1+: length 7.1
  IN4 w0.241: JLOM1.3 270.92,95.69 271.4,95.22 271.4,94.8 270.96,94.37 270.96,92.88 v2(270.87,92.79)
  BOTTOM w0.229: TL1.17 270.53,92.04 271,92.5 271,92.67 v2(270.87,92.79)
NB_LAN_TX1-: length 7.1
  IN4 w0.241: JLOM1.6 272.44,94.63 271.79,94.63 271.36,94.21 271.36,92.89 v2(271.46,92.79)
  BOTTOM w0.229: v2(271.46,92.79) 271.34,92.67 271.34,92.49 271.8,92.02 TL1.18
NB_LAN_TX2+: length 7
  BOTTOM w0.229: TL1.19 273.07,92.04 273.28,92.25 273.82,92.25 274,92.43 274,93.28 272.59,94.69 272.59,95.81 272.22,96.18 JLOM1.4
NB_LAN_TX2-: length 7
  BOTTOM w0.229: 274.39,92.81 274.34,92.86 274.34,93.42 272.96,94.8 JLOM1.5 ; 274.39,92.81 274.34,92.76 TL1.20 ; 274.39,92.81 v1(274.39,92.81)
NB_LAN_TX3+: length 8.8
  BOTTOM w0.229: JLOM1.7 275,94.07 276.12,92.95 276.96,92.95 277,92.91 ; v1(277,92.89) 277,92.91 ; 277,92.91 277.03,92.95 277.9,92.95 278.15,92.7 TL1.23
NB_LAN_TX3-: length 8.8
  BOTTOM w0.229: JLOM1.8 275.59,96.18 275.34,95.93 275.34,94.21 276.27,93.29 278.04,93.29 278.51,92.82 278.51,92.56 v1(278.65,92.42) 278.83,92.24 279.14,92.24 279.42,91.96 TL1.24
NB_PSID: length 1
  TOP w0.254: PL3.2 60.67,103.16 v2(60.4,102.88)
  vias: v2(59.69,102.88) v3(60.04,103.33)
NB_PSID_TS5A63157: length 5
  TOP w0.254: PU1.3 v2(72.63,106.29)
  BOTTOM w0.254: v2(72.63,106.29) 72.37,106.04 v1(72.37,104.48) PR9.2 PR8.1
NFC_IRQ: length 9.1
  TOP w0.102: RC175.1 176.31,57.43 v1(174.66,57.43) 173.78,57.43 173.48,57.12 172.96,57.12 172.67,56.83 v2(172.67,56.67)
  BOTTOM w0.076: UC1.AN3 169.74,54.75 170.25,54.75 170.49,54.99 170.49,55.17 170.55,55.23 170.66,55.34 171.54,55.34 172.6,56.4 172.61,56.4 172.67,56.45 v2(172.67,56.67)
NGFF_CONFIG_0: length 29.2
  TOP w0.102: v1(247.86,73.74) 248.48,73.12 RPE4.1 249.25,72.82 248.86,72.44 v2(248.85,72.44) ; UE1.B12 v2(253.37,69.41)
  IN3 w0.122: v2(248.85,72.44) 248.86,72.44 249.55,73.13 251.71,73.13 252.22,72.62 252.22,70.56 v2(253.37,69.41)
  IN4 w0.089: v2(248.85,72.44) 242.3,72.44 241.58,71.72 239.19,71.72 235.77,68.3 v2(233.55,68.3)
  BOTTOM w0.102: JNGFF2.13 233.16,67.85 233.55,68.24 v2(233.55,68.3)
NGFF_CONFIG_1: length 34.4
  TOP w0.102: RPE4.2 249.75,72.69 248.86,71.8 v2(248.85,71.8) 248.35,71.8 v1(247.91,72.24) ; UE1.A18 v2(248.66,68.76)
  IN4 w0.089: v2(248.85,71.8) 241.97,71.8 241.67,71.5 240.91,71.5 239.44,70.03 239.44,63.97 v2(233.68,58.2)
  BOTTOM w0.102: v2(248.66,68.76) 248.66,71.6 248.86,71.8 v2(248.85,71.8) ; v2(233.68,58.2) 233.68,56.49 233.04,55.85 JNGFF2.61
NGFF_CONFIG_2: length 51.3
  TOP w0.102: v2(256.78,59.29) 256.62,59.45 UE1.A44 ; RPE4.3 v2(250.25,72.3)
  IN1 w0.089: v2(250.25,72.3) 250.25,72.3 250.7,71.85 250.7,69.18 250.94,68.94 251.7,68.94 252.14,68.5 252.14,61.01 251.57,60.43 251.57,58.68 252.26,57.99 255.65,57.99 256.59,58.93 256.59,59.1 v2(256.78,59.29)
  IN4 w0.089: v2(256.78,59.29) 256.78,58.73 255.79,57.74 248.01,57.74 245.36,55.09 240.7,55.09 240.28,55.51 236.57,55.51 235.41,54.35 v2(233.61,54.35)
  BOTTOM w0.102: v1(256.5,58.17) 256.78,58.44 v2(256.78,59.29) ; v2(233.61,54.35) JNGFF2.67
NGFF_CONFIG_3: length 36.7
  TOP w0.102: v1(248.09,58.32) 248.09,58.83 249.63,60.36 v2(249.81,60.36) 249.81,61.25 250.07,61.51 UE1.B34 ; RPE4.4 250.75,72.16 v2(250.25,71.67)
  IN1 w0.089: v2(250.25,71.67) 250.25,67.67 249.44,66.85 249.44,60.73 v2(249.81,60.36)
  IN4 w0.089: v2(235.14,72.85) 235.31,72.68 238.19,72.68 238.77,73.26 248.66,73.26 v2(250.25,71.67)
  BOTTOM w0.102: v2(235.14,72.85) JNGFF2.1
O-USR: length 5.4
  TOP w0.203: PU500.9 103.15,64.73 103.01,64.59 102.43,64.59 v2(101.96,64.12)
  BOTTOM w0.102: PR509.2 100.99,64.93 v1(100.82,65.1)
  BOTTOM w0.254: PR504.1 100.82,63.23 101.71,64.12 v2(101.96,64.12) PR509.2
OCP-I: length 11.6
  TOP w0.203: v2(104.25,63.86) 104.35,63.96 PU500.12
  TOP w0.254: v2(104.25,63.86) 104.25,62.97 103.92,62.64 v1(103.92,61.65) 102.47,61.65 101.19,62.93 PR524.2
  BOTTOM w0.254: PR506.2 104.63,64.43 104.25,64.05 v2(104.25,63.86) 103.5,63.11 PR501.1
OUT1_CA_DET: length 2.6
  TOP w0.102: UV600.43 v2(227.63,67.74)
  BOTTOM w0.102: v1(228.66,68.48) RV606.2 227.64,67.76 v2(227.63,67.74)
OUT2_CA_DET: length 2.7
  TOP w0.102: UV600.33 v2(223.63,67.74)
  BOTTOM w0.102: v1(224.64,68.54) RV607.2 223.64,67.76 v2(223.63,67.74)
P33ALW: length 3.6
  TOP w0.102: PR859.1 73.91,31.05 v1(73.57,30.71)
  TOP w0.254: PR859.1 74.41,31.67 75.45,32.72 PU800.18
P33ALW2: length 3.6
  TOP w0.102: PR855.2 74.95,39.53 v1(74.48,40)
  TOP w0.254: PU800.9 76.85,38.08 PR855.2
PANEL_BKEN_EC: length 164.2
  TOP w0.102: v2(123.23,79.5) 123.23,80.77 121.41,82.59 v1(119.62,82.59) 119.19,82.59 118.98,82.79 DV2.2 ; UE1.B38 252.37,61.24 252.57,61.44 v2(252.57,61.77)
  IN2 w0.122: v2(123.23,79.5) 123.23,80.01 124.61,81.39 124.61,82.61 128.84,86.84 147.51,86.84 148.78,88.11 175.33,88.11 176.09,88.87 181.61,88.87 182.37,88.11 204.78,88.11 205.76,89.09 221.05,89.09 223.4,91.44 232.75,91.44 234.05,90.14 234.05,85.27 237.74,81.57 237.74,80.05 247.51,70.28 251.38,70.28 252.17,69.49 252.17,62.01 252.41,61.77 v2(252.57,61.77)
PANEL_BKLEN: length 75
  TOP w0.102: v2(123.7,79.88) 123.7,81.06 v1(121.92,82.84) 121.38,83.38 DV2.3
  IN3 w0.122: v2(165.54,74.9) 165.54,78.97 162.12,82.39 162.12,89.41 164.72,92 164.72,93.15 164.22,93.64 163.32,93.64 162.96,94 160.43,94 160.07,93.64 159.31,93.64 150.17,84.51 128.79,84.51 124.37,80.09 123.9,80.09 v2(123.7,79.88)
  BOTTOM w0.076: UC1.A9 165.33,74.69 v2(165.54,74.9)
PBAT_PRES#: length 328.9
  TOP w0.102: UE2.A49 264.92,38.71 265.11,38.52 265.11,38.33 265.81,37.63 v2(266.19,37.63) ; v1(51.61,12.39) 51.13,11.91 PR2.2
  TOP w0.254: v2(70.93,35.15) 70.67,35.41 PU804.1 ; v2(51.81,10.71) PR2.2 51.13,10.21 50.73,9.82 PD4.1 51.99,8.1 52.83,8.1 53.03,7.9 PRP2.1
  IN1 w0.254: v2(51.81,10.71) 52.38,11.28 55.16,11.28 55.62,11.74 55.62,26.07 61.85,32.3 63.31,32.3 63.75,31.85 v2(63.75,31.72) 63.75,31.22 64.26,30.71 67.69,30.71 68.13,31.15 68.13,32.68 67.7,33.11 67.7,34.34 68.03,34.67 70.44,34.67 v2(70.93,35.15)
  IN2 w0.122: v2(266.19,37.63) 254.63,37.63 253.81,38.46 252.28,38.46 251.27,37.44 239.96,37.44 235.07,32.55 235.07,30.96 234.11,30 86.35,30 85.13,28.78 80.56,28.78 78.97,27.2 77.11,27.2 76.44,27.87 72.56,27.87 71.56,28.87 65.85,28.87 63.75,30.96 v2(63.75,31.72)
  IN3 w0.122: v2(63.75,31.72) 63.75,36.61 66.47,39.33 66.47,40.98 68.32,42.84 68.32,48.11 71.56,51.35 71.56,53.36 80.09,61.89 83.31,61.89 90.51,69.08 90.51,73.8 89.51,74.8 89.51,76.77 v2(88.07,78.21)
  BOTTOM w0.102: v2(88.07,78.21) 87.49,77.62 83.88,77.62 PR728.1
PBAT_PRES#_C: length 4.3
  TOP w0.102: v1(53.2,13.06) v2(53.2,12.43) 53.2,12.43 PD2.2
  TOP w0.254: PRP2.8 53.03,9.26 53.27,9.5 53.27,11.01 53.2,11.08 PD2.2
PBAT_SMBCLK: length 241.3
  TOP w0.102: UE2.A56 264.78,42.21 264.93,42.07 265.72,42.07 266.24,41.55 v2(266.24,41.32) 266.8,41.32 RE43.2 ; v2(54.07,6.64) 53.9,6.82 53.9,7.2 54.03,7.34 PRP2.3
  IN1 w0.089: v2(266.24,41.32) 266.75,40.81 266.75,40.24 266.47,39.96 266.16,39.96 265.08,38.89 265.08,37.94 264.15,37.01 264.15,32.64 262.13,30.63 257.48,30.63 252.66,25.81 252.66,19.7 247.11,14.14 243.45,14.14 241.65,12.34 229.02,12.34 224.36,7.67 148.46,7.67 146.71,9.42 144.66,9.42 142.86,7.61 75.32,7.61 74.13,6.43 55.33,6.43 54.61,7.15 54.09,7.15 53.89,6.95 53.89,6.83 v2(54.07,6.64)
PBAT_SMBCLK_C: length 10.7
  TOP w0.102: v2(54.58,14.11) 54.43,13.96 54.43,13.54 55.03,12.94 55.03,12.46 54.92,12.36 54.92,11.91 55.05,11.79 55.17,11.79 PD1.2 55.3,11.55 55.2,11.45 55.01,11.45 54.91,11.35 54.91,11.07 54.7,10.86 54.38,10.86 53.9,10.37 53.9,9.38 54.03,9.25 PRP2.6
  BOTTOM w0.102: v2(54.58,14.11) 54.39,14.3 54.39,14.48 54.51,14.6 55.24,14.6 55.57,14.92 55.57,15.09 56.2,15.72 56.2,16.83
PBAT_SMBDAT: length 244.2
  TOP w0.102: RE37.2 266.54,40.69 v2(266.24,40.69) ; v2(262.88,41.9) 262.94,41.96 UE2.B59 ; v2(53.49,6.64) 53.67,6.82 53.67,7.2 53.53,7.34 PRP2.2
  IN1 w0.089: v2(266.24,40.69) 266.4,40.69 266.53,40.56 266.53,40.33 266.38,40.18 266.07,40.18 264.87,38.98 264.87,38.03 263.93,37.1 263.93,32.73 262.04,30.84 257.4,30.84 252.45,25.9 252.45,19.79 247.02,14.36 243.36,14.36 241.56,12.55 228.93,12.55 224.27,7.89 148.55,7.89 146.8,9.63 144.57,9.63 142.77,7.83 75.23,7.83 74.04,6.64 55.42,6.64 54.7,7.37 54,7.37 53.67,7.04 53.67,6.83 v2(53.49,6.64)
  BOTTOM w0.102: v2(266.24,40.69) 266.76,41.21 266.76,41.57 266.43,41.9 v2(262.88,41.9)
PBAT_SMBDAT_C: length 10.7
  TOP w0.102: v2(53.99,14.11) 54.2,13.9 54.2,13.44 54.7,12.94 v1(54.7,12.6) 54.7,11.94 54.54,11.79 54.42,11.79 PD1.3 54.3,11.55 54.4,11.45 54.58,11.45 54.68,11.35 54.68,11.16 54.61,11.09 54.29,11.09 53.67,10.46 53.67,9.38 53.53,9.25 PRP2.7
  BOTTOM w0.102: v2(53.99,14.11) 54.16,14.28 54.16,14.57 54.43,14.85 55.17,14.85 55.34,15.02 55.34,15.13 54.7,15.76 54.7,16.83
PBATT+_C: length 2.2
  TOP w0.102: v3(60.36,6.73) 61.03,7.4 PL1.1
  vias: v3(60.46,13.44) v3(62.32,13.44) v4(58.58,12.08) v4(58.58,11.38) v4(58.58,10.68) v4(58.68,10.01) v4(58.68,9.31) v4(59.21,12.08) v4(59.21,11.38) v4(59.21,10.68) v4(59.31,10.01) v4(59.31,9.31) v4(59.85,12.08) v4(59.87,11.37) v4(59.85,10.68) v4(59.97,10.01)
PCH_ALW_ON: length 66.9
  TOP w0.102: v2(255.04,35.58) 255.46,36 255.46,36.52 255.69,36.75 UE2.A34 ; UZ8.5 224.73,61.11 v2(224.96,60.88) ; RPE10.4 255.37,52.46 255.76,52.86 255.76,54.03 255.38,54.41 v1(251.73,54.41) v2(251.05,53.73)
  IN4 w0.089: v2(251.05,53.73) 250.25,53.73 245.73,49.21 237.77,49.21 232.61,54.36 232.61,57.52 229.45,60.68 225.16,60.68 v2(224.96,60.88)
  BOTTOM w0.102: v2(255.04,35.58) 254.98,35.58 254.43,36.13 252.58,36.13 251.65,37.06 251.65,39.53 253.19,41.08 253.19,42.93 253.4,43.13 253.4,47.78 252.87,48.3 252.87,51.36 251.05,53.19 v2(251.05,53.73)
PCH_AZ_BITCLK: length 20.8
  BOTTOM w0.081: 166.8,48.37 165.97,49.19 165.97,50.34 165.62,50.69 165.62,51.24 UC1.AW8
  BOTTOM w0.102: RC23.2 v1(160.72,39.54) 162.16,39.54 166.37,43.75 166.37,46.33 166.8,46.76 166.8,48.37
PCH_AZ_CODEC_BITCLK: length 130.5
  TOP w0.102: UA1.6 37.05,17.37 37.28,17.13 38.2,17.13 38.45,17.38 RA17.1 39.48,16.92 v2(39.48,16.8)
  BOTTOM w0.102: RC23.1 CC5.1 153.29,38.78 83.26,38.78 81.18,36.7 79.45,36.7 72.52,29.78 64.8,29.78 64.58,29.78 63.28,28.47 63.17,28.47 61.94,27.24 60.09,27.24 58.52,25.67 51.17,25.67 46.29,20.78 43.54,20.78 42.86,20.1 41.65,20.1 41.4,20.36 40.13,20.36 39.48,19.71 v1(39.48,18.58) v2(39.48,16.8)
PCH_AZ_CODEC_RST#: length 127.5
  TOP w0.102: UA1.11 36.77,19.37 37.14,19.74 37.14,20.12 37.49,20.47 40.59,20.47 v2(41.13,19.92)
  BOTTOM w0.102: RC22.1 154.85,38.46 83.47,38.46 81.41,36.4 79.58,36.4 72.65,29.47 64.72,29.47 63.42,28.17 63.3,28.17 62.04,26.91 60.21,26.91 58.66,25.36 52.16,25.36 47.22,20.42 v1(44.64,20.42) 43.69,20.42 42.99,19.72 41.33,19.72 v2(41.13,19.92)
PCH_AZ_CODEC_SDIN0: length 143.1
  TOP w0.102: RA9.1 42.16,20.7 v2(42.34,20.87)
  BOTTOM w0.081: 165.86,48.55 165.46,48.94 165.46,50.25 165.16,50.55 UC1.AY10
  BOTTOM w0.102: v2(42.34,20.87) 42.9,21.44 46.08,21.44 50.92,26.28 58.24,26.28 59.83,27.86 61.7,27.86 63.01,29.17 63.12,29.17 64.33,30.39 65.05,30.39 72.1,30.39 74.23,32.52 74.23,34.85 76.69,37.31 80.88,37.31 82.98,39.42 150.06,39.42 151.76,41.12 162.59,41.12 v1(163.62,42.14) 165.86,44.38 165.86,48.55
PCH_AZ_CODEC_SDOUT: length 130.4
  TOP w0.102: v2(38.46,16.81) 37.16,16.81 37,16.97 UA1.5
  BOTTOM w0.102: RC19.1 154.66,40.81 152.21,40.81 v1(151.38,39.98) 150.5,39.1 83.09,39.1 81,37.01 79.32,37.01 72.4,30.08 64.93,30.08 64.46,30.08 63.15,28.78 63.04,28.78 61.81,27.55 59.95,27.55 58.38,25.97 51.05,25.97 46.17,21.09 43.4,21.09 42.73,20.42 41.84,20.42 41.59,20.68 40,20.68 39.11,19.79 39.11,17.46 v2(38.46,16.81)
PCH_AZ_CODEC_SYNC: length 129.5
  TOP w0.102: v2(37.58,19.92) 37.58,19.79 36.75,18.97 UA1.10
  BOTTOM w0.102: v2(37.58,19.92) 39.41,21.75 45.97,21.75 50.79,26.58 58.1,26.58 59.7,28.18 61.58,28.18 62.88,29.48 62.97,29.48 64.19,30.69 65.18,30.69 71.97,30.69 73.91,32.63 73.91,34.96 76.57,37.62 80.64,37.62 82.82,39.8 v1(146.61,39.8) 149.82,39.8 151.6,41.57 RC20.1
PCH_AZ_RST#: length 22.9
  BOTTOM w0.081: 167.12,48.37 166.2,49.28 166.2,51.99 166.31,52.1 166.31,52.47 UC1.AU8
  BOTTOM w0.102: 167.12,48.37 167.12,46.63 166.68,46.2 v1(166.68,45.5) 166.68,43.56 161.72,38.59 RC22.2
PCH_AZ_SDIN0_R: length 5.4
  TOP w0.102: RA9.2 40.73,19.22 40.66,19.15 38.35,19.15 37.37,18.17 UA1.8
PCH_AZ_SDOUT: length 23.8
  TOP w0.102: RC11.2 166.42,46.08 v2(166.42,47.35)
  BOTTOM w0.081: UC1.AU11 164.79,52.49 164.79,52.12 164.87,52.04 164.87,51.39 165.05,51.2 165.32,51.2 165.45,51.07 165.45,50.59 165.72,50.32 165.72,49.07 166.42,48.37
  BOTTOM w0.102: RC19.2 v1(158.05,40.49) 162.54,40.49 166.05,44 166.05,46.53 166.42,46.9 v2(166.42,47.35) 166.42,48.37
PCH_AZ_SYNC: length 19
  BOTTOM w0.081: UC1.AV11 164.7,51.93 164.7,51.3 164.88,51.12 164.88,50.56 165.26,50.17 165.26,48.8
  BOTTOM w0.102: RC20.2 162.48,41.57 v1(164.9,43.99) 165.67,44.76 165.67,48.39 165.26,48.8
PCH_BATLOW#: length 13.2
  TOP w0.076: 173.36,50.31 171.39,52.28 v1(171.08,52.28)
  TOP w0.081: v2(169.26,55.42) 169.91,54.77 169.91,53.45 v1(171.08,52.28)
  TOP w0.102: RPC1.8 176.16,46.06 175.83,46.39 175.83,47.53 173.61,49.75 173.61,50.06 173.36,50.31
  BOTTOM w0.081: v2(169.26,55.42) 168.85,55.01 UC1.AN4
PCH_CL_CLK1: length 99.3
  IN4 w0.089: v2(238.14,24.23) 237.81,24.23 237.58,24.46 237.58,25.84 236.91,26.52 235.4,26.52 232.57,29.34 202.07,29.34 190.87,40.55 190.87,43.76 188.86,45.77 186.73,45.77 186.11,46.39 186.11,52.49 185.29,53.31 185.29,54.84 186.05,55.6 186.05,59.41 183.51,61.95 179.19,61.95 177.31,60.07 173.23,60.07 172.93,59.78 169.99,59.78 v2(169.85,59.92)
  BOTTOM w0.081: v2(169.85,59.92) 169.85,59.83 UC1.AF2
  BOTTOM w0.102: JNGFF1.34 238.69,23.6 238.14,24.15 v2(238.14,24.23)
PCH_CL_DATA1: length 98.9
  IN4 w0.089: v2(171.32,60.96) 171.72,60.56 172.84,60.56 172.93,60.46 177.4,60.46 179.14,62.2 183.58,62.2 186.33,59.45 186.33,46.48 186.82,45.99 188.95,45.99 191.08,43.85 191.08,40.64 202.16,29.56 233.66,29.56 233.99,29.9 235,29.9 237.8,27.1 237.8,25.18 v2(238.74,24.23)
  BOTTOM w0.081: v2(171.32,60.96) 171.19,60.96 170.88,60.64 170.69,60.64 170.34,60.29 UC1.AD2
  BOTTOM w0.102: v2(238.74,24.23) 239.15,23.83 239.9,23.83 240.17,24.1 JNGFF1.32
PCH_CL_RST1#: length 99.4
  IN4 w0.089: v2(173.7,61.01) 174.28,61.59 178.22,61.59 179.09,62.46 183.64,62.46 186.54,59.56 186.54,49.13 188.45,47.22 188.45,46.79 191.3,43.94 191.3,40.73 202.25,29.78 233.57,29.78 233.9,30.11 235.09,30.11 238.01,27.19 238.01,25.27 238.54,24.74 239.01,24.74 v2(239.46,24.29)
  BOTTOM w0.076: 173.36,60.34 172.76,59.74 172.28,59.74 171.8,59.25 170.55,59.25 170.54,59.25 170.52,59.25 170.36,59.09 169.67,59.09 169.57,59.18 169.1,59.18 168.83,59.45 UC1.AF4
  BOTTOM w0.102: JNGFF1.30 239.76,24.6 v2(239.46,24.29) ; v2(173.7,61.01) 173.7,60.68 v1(173.41,60.38) 173.36,60.34
PCH_DPWROK: length 120
  TOP w0.102: UE2.A36 256.69,35.85 v1(256.23,35.39) 256.23,35.17 255.65,34.59 v2(255.65,34.58)
  IN3 w0.122: v2(255.65,34.58) 255.63,34.56 255.63,33.64 255.43,33.45 255.43,29.44 253.81,27.81 253.81,26.75 247.73,20.68 242.2,20.68 239.43,17.91 228.55,17.91 225.49,20.97 205,20.97 202.23,23.75 191.35,23.75 177.89,37.2 177.89,38.04 176.58,39.35 176.58,43.1 175.13,44.55 175.13,45.25 173.94,46.44 171.02,46.44 170.43,47.03 v2(170.43,47.55)
  BOTTOM w0.076: v2(170.43,47.55) 168.79,49.19 168.73,49.19 167.87,50.06 167.87,51.77 168.12,52.02 UC1.AV5
PCH_GPIO4: length 17.7
  BOTTOM w0.076: 173.36,70.79 173.23,70.66 171.61,70.66 171.6,70.67 170.55,70.67 170.13,70.25 UC1.F2
  BOTTOM w0.102: 173.36,70.79 181.93,70.79 182.62,70.1 182.62,69.44 182.96,69.11 v1(182.96,68.19) 182.28,67.51 181.71,67.51 181.24,67.05 RPC8.8
PCH_GPIO5: length 17
  BOTTOM w0.076: 173.36,70.43 171,70.43 170.94,70.48 170.62,70.48 170.42,70.28 170.42,69.83 170.33,69.74 169.82,69.74 169.56,69.99 UC1.F3
  BOTTOM w0.102: RPC8.7 181.34,67.55 182.37,68.58 182.37,70.03 181.97,70.43 v1(180.68,70.43) 173.36,70.43
PCH_GPIO6: length 13.5
  BOTTOM w0.076: UC1.G4 169.17,69.66 169.59,69.66 169.67,69.58 171.02,69.58 171.41,69.97 173.36,69.97
  BOTTOM w0.102: RPC8.5 180.53,68.55 180.46,68.62 180.46,69.26 180.15,69.57 176.78,69.57 v1(176.53,69.82) 176.38,69.97 173.36,69.97
PCH_GPIO7: length 13.1
  BOTTOM w0.076: UC1.F1 170.91,70.2 173.36,70.2
  BOTTOM w0.102: RPC8.6 181.46,68.05 181.61,68.19 181.61,69.51 181.31,69.8 178.51,69.8 v1(178.33,69.98) 178.11,70.2 173.36,70.2
PCH_GPIO9: length 18.2
  TOP w0.102: v1(182.38,56.72) 182.84,56.26 v2(183.09,56.26) 183.77,56.94 RPC10.6
  IN1 w0.089: v2(183.09,56.26) 182.91,56.26 181.39,57.78 180.56,57.78 180.41,57.93 174.52,57.93 173.74,57.15 170.75,57.15 169.84,56.23 v2(169.84,55.42)
  BOTTOM w0.081: v2(169.84,55.42) 169.48,55.78 UC1.AM3
PCH_GPIO10: length 4.8
  BOTTOM w0.081: UC1.AM2 170.33,55.8 170.63,56.09 170.97,56.09 171.23,56.35 171.24,56.35 171.25,56.36 172.02,56.36 172.13,56.47 172.13,56.94 172.43,57.23 172.69,57.23 172.96,57.49 173.36,57.49
  BOTTOM w0.102: T27.1 173.66,57.49 173.36,57.49
PCH_GPIO14: length 10.6
  TOP w0.102: v2(168.58,58.4) 168.58,58.43 169.5,59.36 173.99,59.36 174.34,59.71 175.92,59.71 176.59,60.39 v2(176.59,60.93)
  BOTTOM w0.076: UC1.AH4 168.83,58.14 v2(168.58,58.4)
  BOTTOM w0.102: T21.1 176.72,61.06 v2(176.59,60.93)
PCH_GPIO16: length 12.7
  BOTTOM w0.076: 173.36,62.68 173.13,62.68 172.79,63.02 171.4,63.02 170.92,62.54 UC1.Y1
  BOTTOM w0.102: RPC6.8 181.46,64.26 181.67,64.05 181.67,63.58 181.33,63.24 179.48,63.24 178.92,62.68 v1(174.28,62.68) 173.36,62.68
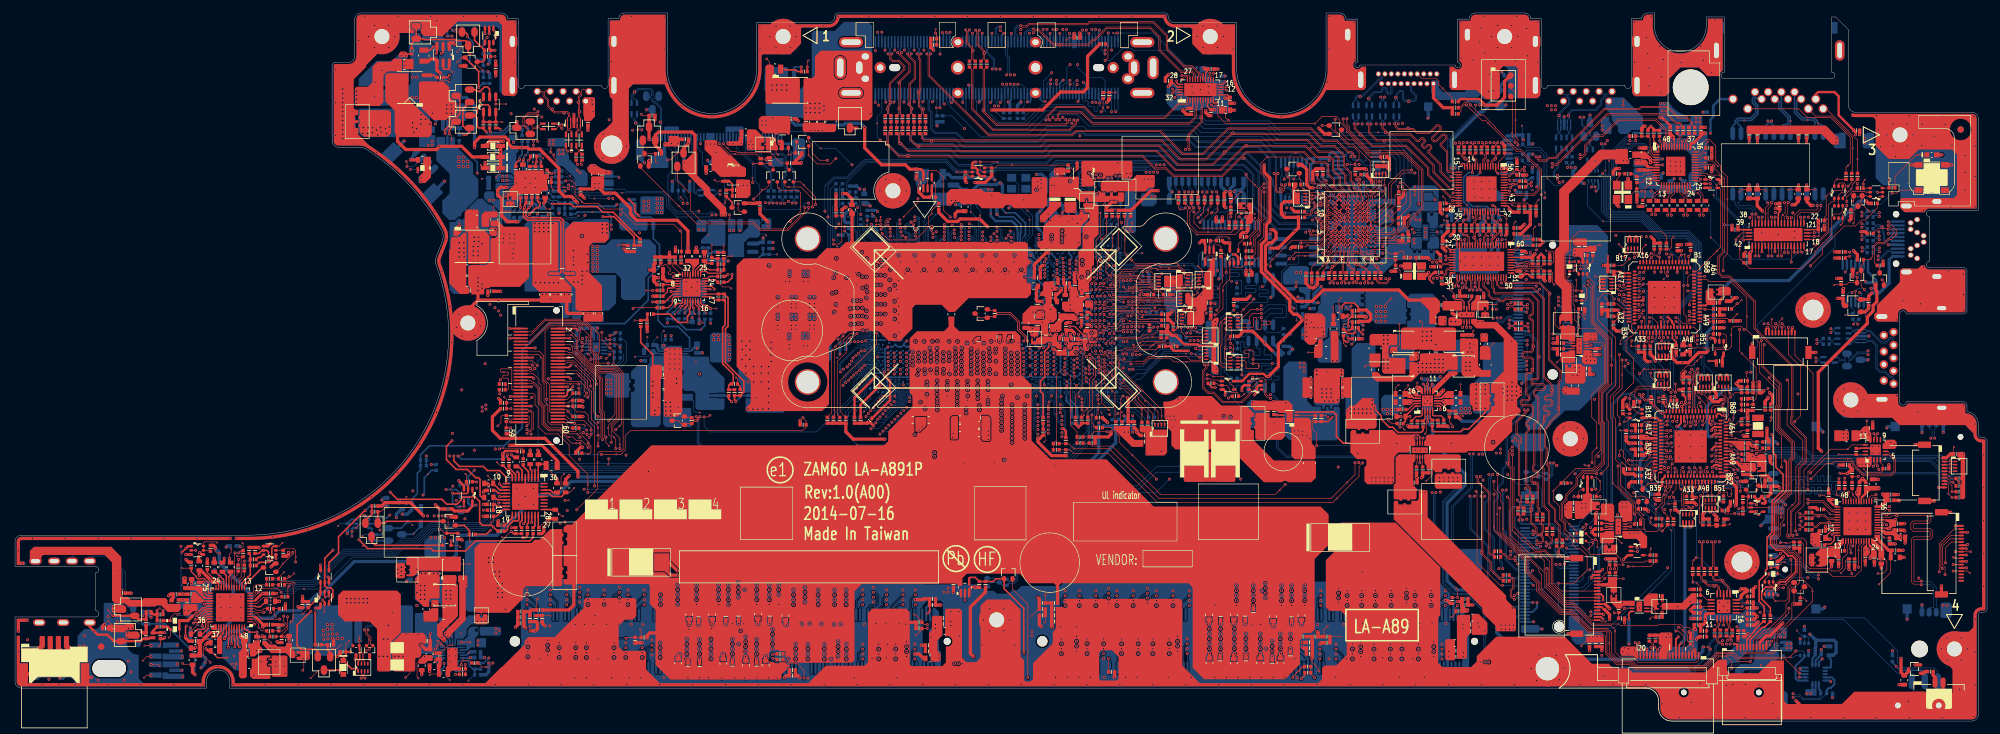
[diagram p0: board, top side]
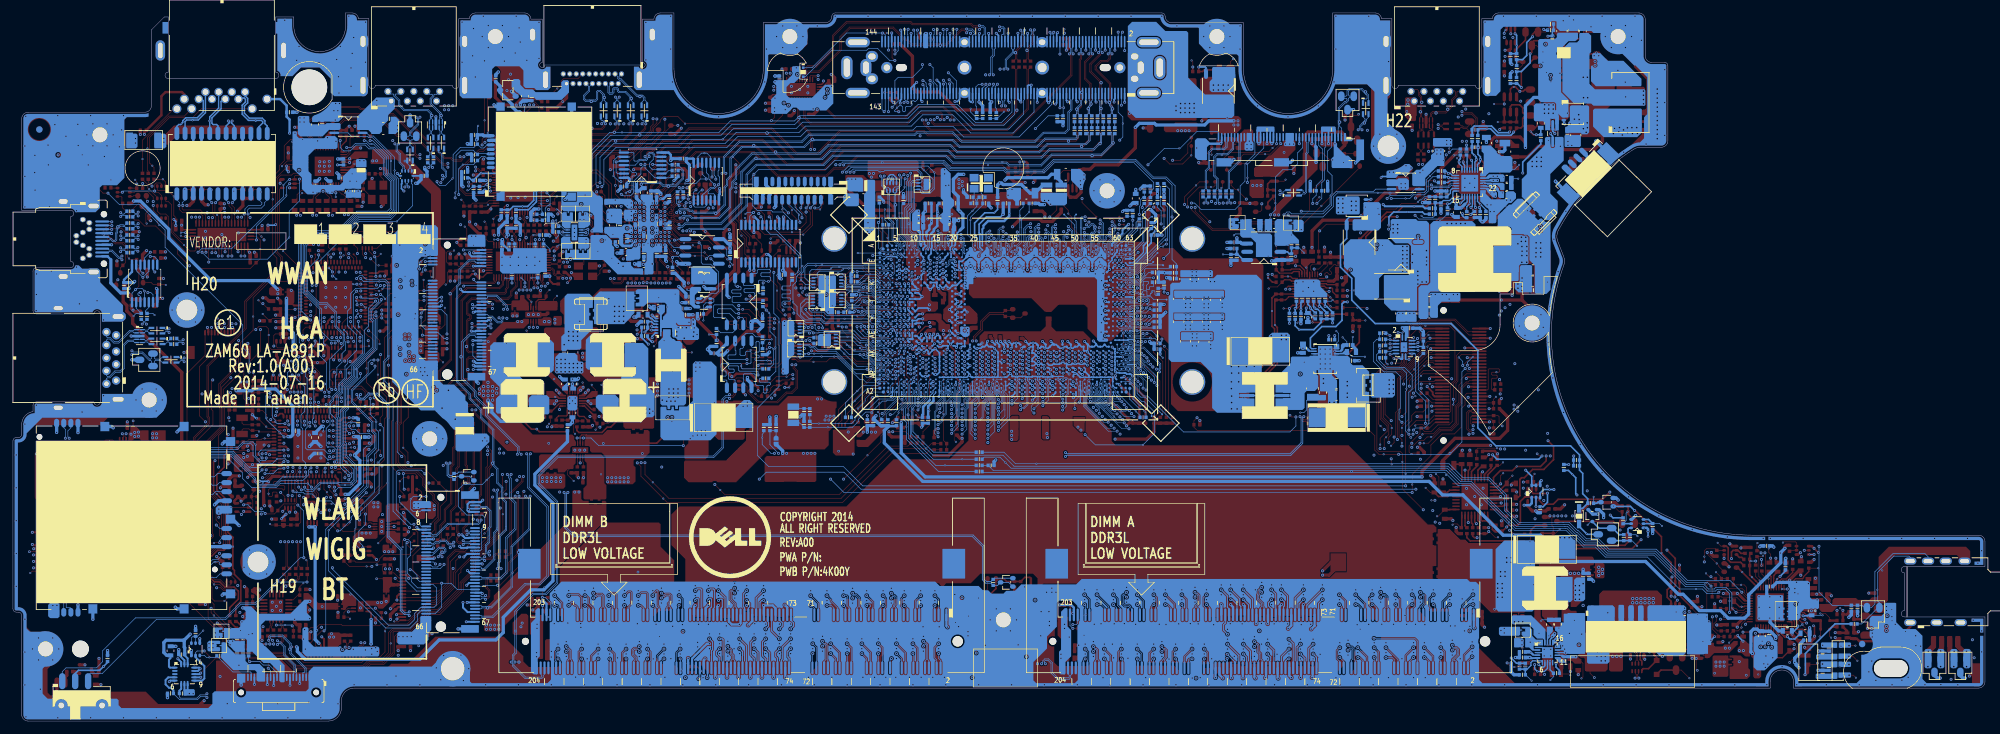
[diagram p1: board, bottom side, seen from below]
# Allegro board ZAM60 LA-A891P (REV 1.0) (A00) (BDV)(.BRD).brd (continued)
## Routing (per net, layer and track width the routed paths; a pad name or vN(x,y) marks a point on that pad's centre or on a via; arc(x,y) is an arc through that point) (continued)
PCH_GPIO19: length 10.5
  TOP w0.081: 173.36,62.38 172.64,63.09 170.79,63.09 170.1,62.4 168.79,62.4 v2(168.31,62.88)
  TOP w0.102: 173.36,62.38 173.4,62.33 173.41,62.33 173.64,62.1 175.19,62.1 175.3,62.2 v1(176.24,62.2) 177.02,62.2 RC66.2
  BOTTOM w0.081: v2(168.31,62.88) 168.33,62.88 168.15,62.71 UC1.Y5
PCH_GPIO44: length 9.8
  BOTTOM w0.076: UC1.AK4 169.14,57.64 169.59,57.64 169.64,57.59 170.54,57.59 170.62,57.67 171.86,57.67 172.68,58.5 173.36,58.5
  BOTTOM w0.102: RPC19.4 177.28,59.78 176.91,59.41 v1(175.78,59.41) 174.88,59.41 173.96,58.5 173.36,58.5
PCH_GPIO46: length 15.8
  TOP w0.102: RPC10.5 182.62,57.44 v2(182.44,57.62)
  IN1 w0.089: v2(169.84,58.42) 170.54,57.72 173.61,57.72 174.3,58.41 181.18,58.41 181.38,58.21 181.85,58.21 v2(182.44,57.62)
  BOTTOM w0.081: UC1.AG3 169.48,58.78 v2(169.84,58.42)
PCH_GPIO49: length 5.5
  TOP w0.081: 173.36,62.75 172.82,63.29 170.16,63.29 v2(169.78,62.91)
  TOP w0.102: 173.36,62.75 173.66,62.45 T22.1
  BOTTOM w0.081: v2(169.78,62.91) 169.48,62.61 UC1.Y3
PCH_GPIO52: length 12.2
  TOP w0.081: 173.36,67.91 173.15,68.12 v2(172.4,68.12)
  TOP w0.102: RPC3.6 181,67.93 180.64,67.56 180.64,67.03 180.51,66.9 176.34,66.9 175.43,67.81 v1(173.8,67.81) 173.45,67.81 173.36,67.91
  BOTTOM w0.076: v2(172.4,68.12) 172.07,67.79 172.02,67.79 171.93,67.7 171.92,67.7 171.73,67.51 171.17,67.51 170.78,67.13 UC1.L1
PCH_GPIO53: length 9.8
  TOP w0.102: v2(171.31,67.14) 171.8,66.65 172.05,66.65 172.05,66.65 173.46,66.65 173.91,67.1 v1(175.22,67.1) 175.45,67.1 176.11,66.45 176.97,66.45 RC140.1
  BOTTOM w0.081: v2(171.31,67.14) 170.92,66.75 170.42,66.75 170.37,66.71 169.13,66.71 UC1.L4
PCH_GPIO57: length 14.8
  TOP w0.081: 173.36,55.22 v2(172.44,55.22)
  TOP w0.102: 173.36,55.22 174.37,55.22 175.26,56.11 178.5,56.11 179.05,55.55 v1(181.04,55.55) 183.4,55.55 183.79,55.94 RPC10.8
  BOTTOM w0.076: v2(172.44,55.22) 172.21,55.22 171.68,54.69 171.68,54.39 171.46,54.18 170.9,54.18 UC1.AP1
PCH_GPIO59: length 8.1
  TOP w0.102: v2(168.32,52.95) 168.32,52.32 v1(169.61,51.03) 169.99,50.65 169.99,46.41 RC245.1
  BOTTOM w0.081: v2(168.32,52.95) 167.88,53.39 UC1.AT5
PCH_GPIO66: length 8.2
  TOP w0.102: v2(169.03,71.35) 170.56,72.88 v1(170.56,73.1) 170.56,75.6 171.45,76.49 RC176.2
  BOTTOM w0.076: v2(169.03,71.35) 169.15,71.47 UC1.D3
PCH_GPIO68: length 9.2
  TOP w0.102: v2(171.88,71.99) 171.51,72.36 v1(171.51,74.45) 171.51,75.93 171.86,76.28 171.86,77.53 RC164.2
  BOTTOM w0.076: v2(171.88,71.99) 171.85,71.97 170.52,71.97 170.35,71.8 170.04,71.8 169.63,72.2 UC1.C3
PCH_GPIO69: length 14.2
  TOP w0.102: RPC16.5 181.87,69.05 181.66,69.26 181.08,69.26 v1(179.75,70.59) 179.6,70.74 175.4,70.74 175.35,70.69 173.15,70.69 v2(172.53,71.32)
  BOTTOM w0.076: v2(172.53,71.32) 170.44,71.32 170.13,71.01 UC1.E2
PCH_GPIO73: length 17.1
  BOTTOM w0.076: UC1.AU4 168.94,52.86 169.27,53.19 169.66,53.19 169.85,53.39 169.85,53.83 170.03,54.02 170.83,54.02 170.83,54.01 171.53,54.01 171.84,54.32 171.84,54.61 172.07,54.84 173.36,54.84
  BOTTOM w0.102: RPC7.8 181.72,58.26 181.4,57.94 180.84,57.94 180.31,57.42 176.88,57.42 v1(176.29,56.82) 174.3,54.84 173.36,54.84
PCH_GPIO76: length 6.7
  BOTTOM w0.076: UC1.P1 171.24,65.54 172.1,66.4 172.38,66.4 172.65,66.67 173.33,66.67 173.36,66.65
  BOTTOM w0.102: 173.36,66.65 v1(173.96,66.65) 175.92,66.65 176.45,67.18 RPC17.5
PCH_GPIO80: length 8.2
  BOTTOM w0.076: 173.36,67.62 172.08,67.62 172,67.54 171.99,67.54 171.67,67.22 171.67,66.95 171.3,66.57 170.55,66.57 170.26,66.29 UC1.N2
  BOTTOM w0.102: 173.36,67.62 173.4,67.62 173.8,67.22 175.85,67.22 176.21,67.58 176.21,68.02 176.36,68.18 RPC17.7
PCH_GPIO85: length 11.4
  TOP w0.081: 173.36,68.47 172.55,68.47 172.55,68.48 171.18,68.48 170.67,67.97 170.67,67.1 170.26,66.69 v2(167.67,66.69)
  TOP w0.102: 173.36,68.47 173.61,68.47 174.04,68.04 175.55,68.04 176.36,67.23 RPC4.8
  BOTTOM w0.081: UC1.N6 167.5,66.52 v2(167.67,66.69)
PCH_GPIO87: length 21.3
  TOP w0.102: v2(181.73,66.97) 181.85,67.08 181.85,67.93 182.47,68.55 RPC16.6 183.37,68.55 183.53,68.71 183.53,69.62 v1(182.76,70.38)
  IN1 w0.089: v2(181.73,66.97) 181.64,66.87 173.68,66.87 173.4,66.59 168.88,66.59 168.54,66.24 167.09,66.24 v2(166.51,65.66)
  BOTTOM w0.081: v2(166.51,65.66) 166.85,65.32 UC1.R7
PCH_INTVRMEN: length 6.4
  BOTTOM w0.076: UC1.AV7 166.62,52.11 166.37,51.86 166.37,49.44 167.89,47.92 v1(167.89,47.7) 167.89,47.51 168.21,47.19 RC1.2
PCH_JTAG_JTAGX: length 86.5
  TOP w0.102: v2(129.51,59.94) 129.05,59.94 128.08,58.97 128.08,58.58 126.62,57.12 v1(126.62,48.11) 126.62,47.1 RC18.1
  IN1 w0.089: v2(129.51,59.94) 128.93,59.94 128.44,60.43 127.23,60.43 126.22,59.42 126.22,58.43 124.35,56.55 120.77,56.55 118.36,54.15 118.36,46.97 116.03,44.63 93.89,44.63 93.02,45.5 92.14,45.5 91.44,46.2 v2(90.1,46.2)
  BOTTOM w0.076: v2(129.51,59.94) 130.05,59.4 131.97,59.4 UC1.AE63
  BOTTOM w0.102: RC112.2 RC115.2 93.97,59.04 94.49,58.52 94.49,55.6 92.89,54 91.04,54 90.36,53.31 90.36,48.36 90.55,48.17 90.55,46.65 v2(90.1,46.2)
PCH_JTAG_TCK: length 74.7
  TOP w0.102: v2(79.09,45.66) 79.45,46.02 79.45,47.01 79.27,47.2 JXDP1.55 75.97,47.2 RC119.2 75.27,47.24 75.09,47.07 75.09,46.13 v3(74.61,45.64)
  IN1 w0.089: v2(127.19,59.07) 127.19,58.66 124.69,56.16 120.93,56.16 118.76,53.99 118.76,46.81 116.19,44.24 92.83,44.24 91.37,45.69 87.69,45.69 86.36,47.03 85.34,47.03 83.97,45.66 v2(79.09,45.66)
  BOTTOM w0.076: 129.47,59.12 131.07,59.12 131.18,59.23 132.46,59.23 UC1.AE62
  BOTTOM w0.102: v2(127.19,59.07) 127.19,58.69 RC21.1 128.2,59.12 129.47,59.12
PCH_JTAG_TDI: length 92.2
  TOP w0.102: v2(89.02,45) 89.02,45.34 87.91,46.46 85.91,46.46 85.17,47.2 JXDP1.56 ; RC14.1 126.17,47.61 126.17,57.31 v3(126.81,57.96) 127.63,58.78 127.63,59.22 v2(127.95,59.54)
  IN1 w0.089: v2(89.02,45) 91.44,45 92.62,43.81 116.37,43.81 119.19,46.63 119.19,53.81 121.11,55.73 125.02,55.73 127.95,58.66 v2(127.95,59.54)
  BOTTOM w0.076: 129.42,60.36 130.41,60.36 130.91,59.86 131.7,59.86 131.88,60.04 132.3,60.04 132.51,60.25 132.51,60.45 132.68,60.62 133.2,60.62 UC1.AD61
  BOTTOM w0.102: 129.42,60.36 128.77,60.36 v2(127.95,59.54) ; RC99.1 93.53,55.73 92.5,54.7 89.71,54.7 88.52,53.5 88.52,51.35 89.02,50.84 v2(89.02,45)
PCH_JTAG_TDO: length 90.3
  TOP w0.102: v3(88.73,43.87) 89.02,44.16 v2(89.02,44.36) ; v2(133.15,60.01) 133.15,58.27 127.51,52.62 127.51,47.87 RC15.1
  IN1 w0.089: v2(89.02,44.36) 89.34,44.68 91.44,44.68 92.52,43.59 116.46,43.59 119.42,46.55 119.42,53.71 121.22,55.51 125.11,55.51 128.82,59.22 130.24,59.22 130.68,59.66 132.26,59.66 132.61,60.01 v2(133.15,60.01)
  BOTTOM w0.081: v2(133.15,60.01) 133.19,59.97 133.46,59.71 UC1.AE61
  BOTTOM w0.102: RC98.1 RC118.2 94.03,56.64 94.03,55.78 92.69,54.44 90.03,54.44 89.41,53.82 89.41,51.09 89.53,50.96 89.53,44.87 v2(89.02,44.36)
PCH_JTAG_TMS: length 89.1
  TOP w0.102: JXDP1.58 85.1,46.7 85.76,46.04 v2(86.47,46.04) ; v2(130.11,59.93) 130.11,59.92 129.6,59.41 129.16,59.41 v3(128.99,59.24) 128.48,58.74 128.48,57.02 127.06,55.6 127.06,47.36 RC16.1
  IN1 w0.089: v2(86.47,46.04) 87.07,45.44 91.31,45.44 92.73,44.03 116.28,44.03 118.97,46.72 118.97,53.9 121.02,55.94 124.78,55.94 127.62,58.79 127.62,59.29 127.51,59.41 127.51,59.79 127.7,59.98 128.14,59.98 128.58,59.54 129.72,59.54 v2(130.11,59.93)
  BOTTOM w0.076: v2(130.11,59.93) 130.48,59.56 131.72,59.56 132.03,59.87 132.47,59.87 132.81,60.21 UC1.AD62
  BOTTOM w0.102: UC7.9 88.1,56.83 88.01,56.74 88.01,51.03 86.47,49.49 v2(86.47,46.04)
PCH_JTAG_TRST#: length 68.1
  TOP w0.102: v3(107.4,47.29) 107.13,47.03 v2(106.49,47.03)
  IN3 w0.122: v2(88.33,45) 89.09,45.76 92.77,45.76 93.41,45.12 105.66,45.12 106.49,45.95 v2(106.49,47.03)
  BOTTOM w0.076: UC1.AU62 132.46,53.19 132.06,53.19 131.81,52.94 131.81,52.8 130.71,51.71
  BOTTOM w0.102: v2(88.33,45) 88.01,45.31 86.61,45.31 85.94,45.99 85.94,49.66 87.56,51.28 87.56,56.09 RC109.2 ; v2(106.49,47.03) 106.49,45.63 107.41,44.71 123.85,44.71 129.41,50.27 130.03,50.27 130.71,50.95 130.71,51.71
PCH_OPI_COMP: length 6.5
  BOTTOM w0.076: RC178.1 164.89,46.98 v1(165.21,47.29)
  BOTTOM w0.081: UC1.AW15 162.16,51.52
  BOTTOM w0.152: 163.07,49.63 163.07,50.27 162.56,50.77 162.56,51.12 162.16,51.52
  BOTTOM w0.381: RC178.1 164.21,47.35 164.11,47.45 164.11,48.59 163.07,49.63
PCH_PCIE_RCOMP: length 9.7
  BOTTOM w0.203: UC1.A27 154.94,74.51
  BOTTOM w0.305: 154.94,74.51 154.94,76.07 154.77,76.24 154.77,76.61
  BOTTOM w0.381: 154.77,76.61 154.06,77.32 151.56,77.32 150.8,78.09 v1(150.8,78.49) RC149.2
PCH_PCIE_WAKE#: length 132.5
  TOP w0.081: 173.36,51.98 170.67,54.66 170.67,55.78 170.15,56.3 169.16,56.3 168.83,56.63 168.24,56.63 168.09,56.79 168.09,57.14 168.09,57.14 168.09,57.58 v2(167.54,58.13)
  TOP w0.102: UE2.A44 260.69,36.27 v2(260.59,36.18) ; 173.36,51.98 177.2,48.13 v1(177.2,47.22) 177.2,46.67 177.66,46.21 RPC1.5 ; RE274.2 v2(240.47,36.8)
  IN1 w0.089: v2(228.91,41.44) 227.33,41.44 227.01,41.76 223.84,41.76 223.39,41.31 216.34,41.31 215.14,42.52 206.13,42.52 200.24,48.41 196.77,48.41 193.81,51.37 191.54,51.37 190.94,51.97 188.57,51.97 187.77,52.77 184.93,52.77 184.62,52.45 182.99,52.45 182.01,53.43 182.01,54.08 179.79,56.3 176.23,56.3 173.31,53.38 170.6,53.38 169.53,52.31 168.07,52.31 166.8,53.58 166.8,56.48 167.36,57.04 167.36,57.57 167.54,57.75 v2(167.54,58.13)
  IN4 w0.089: v2(260.59,36.18) 260.16,36.61 259.46,36.61 259.14,36.3 259.14,35.92 257.39,34.16 254.98,34.16 252.33,36.8 v2(240.47,36.8) 239.98,37.29 235.92,37.29 233.47,39.75 230.1,39.75 228.91,40.93 v2(228.91,41.44)
  BOTTOM w0.081: v2(167.54,58.13) 167.54,58.1 168,57.64 UC1.AJ5
PCH_PLTRST#: length 37.9
  TOP w0.102: RC88.2 190.23,73.57 RC89.2 RC87.2 RC219.2 189.6,70.14 188.59,70.14 188.39,70.35 UC5.2 188.39,71.35 188.26,71.48 187.89,71.48 187.74,71.32 UC5.1 187.74,68.33 186.67,67.27 v1(186.67,66.56) 186.67,63.82 185.66,62.81 v2(185.42,62.81)
  IN1 w0.076: v2(167.21,59.06) 167.64,59.48 169.01,59.48 169.11,59.38 173.36,59.38
  IN1 w0.089: 173.36,59.38 178,59.38 178.69,60.07 179.99,60.07 180.73,60.81 180.73,61.21 181.47,61.95 183.43,61.95 183.65,61.73 184.83,61.73 185.09,61.99 185.09,62.48 v2(185.42,62.81)
  BOTTOM w0.081: v2(167.21,59.06) 167.21,59.05 167.21,58.96 UC1.AG7
PCH_PLTRST#_EC: length 370.1
  TOP w0.102: UE1.B22 250.94,67.51 v2(251,67.58) ; v2(190.24,84.56) 190.24,84.24 v1(191.58,82.91) 192.17,82.31 192.17,77.71 191.7,77.24 191.7,76 190.59,74.88 RC304.1 190.18,74.88 189.04,73.74 UC5.4 ; v2(255.83,40.88) 255.83,40.71 255.58,40.46 UE2.B30 ; v2(275,46.27) 275.93,47.2 275.93,54.81 274.06,56.69 JLPDE1.8 v2(274.06,60.86) ; v2(87.13,51.47) RC106.1
  IN1 w0.089: v2(87.13,51.47) 87.13,51.49 87.69,52.04 87.69,53.57 89.72,55.6 89.72,56.57 90.55,57.4 90.55,59.38 94,62.84 95.27,62.84 96.25,63.82 96.25,72.24 101.24,77.23 115.04,77.23 116.32,78.51 124.83,78.51 v2(125.16,78.83) ; v2(190.24,84.56) 192.93,84.56 193.92,85.55 201.66,85.55 202.34,84.86 213.26,84.86 214.08,85.68 217.18,85.68 221.83,81.03 222.26,81.03 224.23,79.06 230.13,79.06 230.68,79.6 231.11,79.6 231.66,79.06 236.19,79.06 239.67,75.58 239.67,64.47 v2(241.68,62.46) ; v2(255.38,23.71) 259.94,23.71 263.95,27.72 263.95,27.9 268.07,32.02 268.07,36.51 268.92,37.36 268.92,38.4 270.31,39.79 270.31,42.33 271.97,43.99 271.97,45.02 273.23,46.27 v2(275,46.27)
  IN4 w0.089: v2(275,46.27) 274.5,46.27 270.18,41.95 269.09,41.95 268.51,41.38 267.68,41.38 266.77,42.28 265.75,42.28 265.48,42.01 264.79,42.01 264.41,42.39 261.49,42.39 260.61,41.51 257.22,41.51 256.59,40.88 v2(255.83,40.88) ; v2(274.06,60.86) 274.06,61.13 270.19,65 265.55,65 265.36,64.81 263.65,64.81 262.57,65.89 261.55,65.89 259.46,67.98 251.39,67.98 251,67.59 v2(251,67.58) 250.76,67.82 246.95,67.82 245.79,66.66 245.79,65.13 243.12,62.46 v2(241.68,62.46)
  BOTTOM w0.102: UZ1.16 184.38,77.36 185.73,78.71 187.32,78.71 187.58,78.97 189.74,78.97 190.5,79.73 190.5,84.3 v2(190.24,84.56) 189.52,85.28 179.16,85.28 177.76,86.68 160.85,86.68 159.79,85.62 151.5,85.62 151.1,85.22 145.58,85.22 143.94,86.85 131.23,86.85 128.5,84.12 126.5,84.12 125.16,82.78 v2(125.16,78.83) ; JNGFF2.42 241.07,60.6 241.68,61.21 v2(241.68,62.46) ; JNGFF1.44 239.8,21.1 239.32,20.62 239.32,17.95 239.67,17.6 JNGFF1.58 241.74,17.6 242.71,16.63 242.71,15.64 243.52,14.83 246.72,14.83 255.38,23.49 v2(255.38,23.71)
PCH_RSMRST#: length 13.8
  TOP w0.102: v2(265.77,32.11) 265.69,32.03 264.34,32.03 RE88.1 263.81,32.68 262.92,33.57 261.17,33.57 260.92,33.82 v1(260.92,35.48) 260.92,35.7 261.19,35.97 UE2.A45 ; v2(269.11,33.44) 268.87,33.68 UZ6.1
  BOTTOM w0.102: v2(265.77,32.11) 266.09,32.42 267.41,32.42 268.42,33.44 v2(269.11,33.44)
PCH_RSMRST#_Q: length 133.9
  TOP w0.102: v2(269.44,31.94) 269.88,32.38 UZ6.4 ; v2(167.37,49.77) v1(167.37,48.16) 167.37,47.52 167.1,47.26 RC91.2
  IN3 w0.122: v2(269.44,31.94) 268.18,31.94 255.9,19.66 242.61,19.66 239.85,16.9 225.51,16.9 224.82,17.6 224.18,17.6 223.48,16.9 204.43,16.9 203.33,18 203.33,20.66 201.25,22.74 190.93,22.74 176.89,36.78 176.89,37.62 175.57,38.94 175.57,42.59 174.11,44.04 174.11,44.74 173.52,45.33 170.47,45.33 167.37,48.44 v2(167.37,49.77)
  BOTTOM w0.081: v2(167.37,49.77) 166.96,50.18 166.96,50.51 167.11,50.67 167.11,51.23 UC1.AW6
PCH_RTCRST#: length 170.9
  TOP w0.102: v2(299.84,26.19) JAPS1.9 301.99,26.19 301.99,26.19 v3(302.21,26.19)
  IN4 w0.089: v2(299.84,26.19) 300.03,26 300.03,17.75 299.2,16.92 273.44,16.92 272.16,18.2 266.43,18.2 265.41,19.22 236.59,19.22 235.33,20.48 234.5,20.48 234.19,20.8 234.19,21.63 230.88,24.93 230.53,24.93 229.87,25.59 197.71,25.59 186.45,36.85 v2(186.45,41.4) 186.05,41 178.75,41 173.48,46.27 170.94,46.27 169.86,47.35 169.86,48.42 166.62,51.66 166.62,52.17 166.89,52.44 v2(167.03,52.44)
  BOTTOM w0.081: UC1.AU7 166.65,52.83 167.03,52.45 v2(167.03,52.44)
  BOTTOM w0.102: CMOS1.2 CC4.2 RC8.2 187.77,42.72 v2(186.45,41.4)
PCH_RTCX1: length 17.7
  BOTTOM w0.089: 168.53,50.17 168.52,50.18 168.52,51.17 UC1.AW5
  BOTTOM w0.102: 168.53,50.17 168.9,49.8 170.97,49.8 172.52,48.26 173.19,48.26 174.62,46.82 174.62,46.52 175.13,46.01 v1(180.21,46.01) 181.28,46.01 RC7.1 RC4.2
PCH_RTCX1_R: length 2.7
  BOTTOM w0.102: YC1.1 183.86,48.31 CC1.2 RC4.1
PCH_RTCX2: length 19.1
  BOTTOM w0.102: UC1.AY5 168.2,50.12 168.71,49.61 169.66,49.61 169.8,49.47 170.4,49.47 172.09,47.78 172.98,47.78 174.11,46.65 174.11,46.32 175.01,45.43 v1(178.81,45.43) RC7.2 CC2.2 183.18,46.11 YC1.2
PCH_SMB_ALERT#: length 9.3
  BOTTOM w0.076: UC1.AN2 170.59,55.5 171.45,55.5 172.31,56.36 172.31,56.86 172.48,57.03 172.81,57.03 172.81,57.03 172.99,57.2 173.36,57.2
  BOTTOM w0.102: 173.36,57.2 174.79,57.2 v1(175.49,57.9) 176.17,58.58 177.1,58.58 177.29,58.78 RPC19.2
PCH_SPI_CLK: length 45.1
  TOP w0.102: RZ26.1 v1(186.42,76.22) 183.02,76.22 182.18,77.06 182.18,78.08 183,78.9 v2(183,79.36) 182.8,79.57 RC227.2
  IN1 w0.076: 173.36,61.48 171.89,61.48 171.73,61.32 170.69,61.32 170.22,61.79 169.43,61.79 v2(169.06,61.42)
  IN1 w0.089: v2(183,79.36) 184.21,78.16 184.21,77.67 184.66,77.23 184.66,69.06 185.93,67.79 185.93,65.63 183.81,63.51 182.92,63.51 182.35,62.95 180.46,62.95 180.32,62.8 178.32,62.8 177.68,62.17 175.97,62.17 175.29,61.48 173.36,61.48
  BOTTOM w0.081: v2(169.06,61.42) 169.06,61.43 169.46,61.83 UC1.AA3
  BOTTOM w0.102: JSPI1.8 182.88,79.48 v2(183,79.36)
PCH_SPI_CS0#: length 42.2
  TOP w0.102: RC228.2 183.82,79.67 183.64,79.49 183.64,78.65 v1(183.28,78.29) v2(182.81,77.83)
  IN1 w0.076: 173.36,62.87 172.77,62.28 171.76,62.28 170.63,63.42 167.56,63.42 v2(167.02,62.88)
  IN1 w0.089: 173.36,62.87 173.39,62.9 174.89,62.9 175.47,63.47 176.72,63.47 178.05,64.8 183.29,64.8 184.59,66.11 184.59,67.22 182.81,69 182.81,71.44 182.69,71.57 182.11,71.57 182.02,71.66 182.02,71.98 182.11,72.07 182.65,72.07 182.76,72.17 182.76,72.43 182.63,72.56 182.11,72.56 182.02,72.65 182.02,72.9 182.11,72.99 182.69,72.99 182.76,73.06 182.76,73.35 182.69,73.43 182.26,73.43 182.05,73.63 182.05,77.06 v2(182.81,77.83)
  BOTTOM w0.081: v2(167.02,62.88) 167.02,62.58 UC1.Y7
  BOTTOM w0.102: v2(182.81,77.83) 182.81,78.4 183.88,79.47 JSPI1.10
PCH_SPI_CS1#: length 34.4
  TOP w0.102: RC224.2 179.75,79.39 v1(180.02,79.12) 180.62,79.12 v2(180.85,79.35)
  IN1 w0.076: v2(171.95,62.66) 172.63,63.35 172.75,63.35 173.7,64.3
  IN1 w0.089: v2(180.85,79.35) 180.97,79.22 180.97,71.35 182.1,70.23 182.1,68.7 183.35,67.44 183.35,66.48 182.36,65.49 175.28,65.49 174.09,64.3 173.7,64.3
  BOTTOM w0.081: v2(171.95,62.66) 171.31,62.66 170.91,62.27 170.91,62.27 170.9,62.26 170.32,62.26 170.18,62.12 169.4,62.12 169.02,62.5 UC1.Y4
  BOTTOM w0.102: JSPI1.2 179.88,79.73 180.27,79.35 v2(180.85,79.35)
PCH_SPI_CS2#: length 28
  IN4 w0.089: v2(184.07,63.08) 183.8,62.81 178.92,62.81 178.39,62.29 170.51,62.29 169.85,61.63 v2(169.85,61.42)
  BOTTOM w0.081: v2(169.85,61.42) 170.13,61.13 UC1.AC2
  BOTTOM w0.102: v2(184.07,63.08) 184.07,63.6 184.5,64.03 185.62,64.03 185.9,64.31 185.9,64.73 185.7,64.93 184.68,64.93 184.59,65.02 184.59,65.34 184.69,65.44 185.8,65.44 185.9,65.54 185.9,65.95 185.8,66.05 184.69,66.05 184.59,66.15 184.59,66.56 184.69,66.66 185.8,66.66 185.9,66.76 v1(185.9,66.9) 185.9,67.17 185.8,67.27 184.69,67.27 184.59,67.37 184.59,67.92 RZ17.1
PCH_SPI_CS2#_R: length 11
  BOTTOM w0.102: UZ1.22 188.28,75.86 187.7,75.29 186.69,75.29 183.36,71.96 v1(183.36,69.53) 183.8,69.09 RZ17.2
PCH_SPI_DIN: length 47.3
  TOP w0.102: RZ30.1 187.97,75.6 v1(184.36,75.6) 182.75,75.6 181.54,76.81 181.54,78.71 v2(182.18,79.35) 181.78,79.74 RC226.2
  IN1 w0.076: v2(168.32,61.96) 170.29,61.96 170.73,61.52 171.54,61.52 171.84,61.82 173.02,61.82 173.28,62.08 173.36,62.08
  IN1 w0.089: 173.36,62.08 175.04,62.08 175.72,62.76 177.4,62.76 178.75,64.11 183.57,64.11 185.33,65.88 185.33,67.49 184.02,68.81 184.02,77 183.58,77.44 183.58,77.89 182.18,79.29 v2(182.18,79.35)
  BOTTOM w0.081: v2(168.32,61.96) 168.45,61.83 UC1.AA4
  BOTTOM w0.102: v2(182.18,79.35) 181.88,79.64 JSPI1.6
PCH_SPI_DO: length 45.2
  TOP w0.102: RZ29.1 188.54,75.22 v1(182.62,75.22) 181.16,76.68 181.16,78.97 181.53,79.34 v2(181.53,79.35) 180.77,80.11 RC225.2
  IN1 w0.089: v2(172.49,62.66) 172.49,62.84 173.57,63.92 174.3,63.92 175.53,65.15 183.15,65.15 184.21,66.21 184.21,67.09 182.44,68.87 182.44,70.45 181.53,71.36 v2(181.53,79.35)
  BOTTOM w0.081: v2(172.49,62.66) 172.49,62.55 172.22,62.28 171.17,62.28 170.98,62.1 170.98,62.1 170.97,62.09 170.43,62.09 UC1.AA2
  BOTTOM w0.102: v2(181.53,79.35) 180.88,80 JSPI1.4
PCH_SPI_DO2: length 40.5
  TOP w0.102: v2(183.13,77.13) 184.38,78.37 v1(184.38,78.99) 184.38,79.12 184.83,79.58 RC229.2
  IN1 w0.076: v2(167.02,61.93) 167.6,62.51 171.23,62.51 171.66,62.08 172.88,62.08 173.23,62.42 173.36,62.42
  IN1 w0.089: 173.36,62.42 174.9,62.42 175.58,63.11 177.05,63.11 178.4,64.46 183.43,64.46 184.97,66 184.97,67.35 183.64,68.68 183.64,76.62 v2(183.13,77.13)
  BOTTOM w0.081: v2(167.02,61.93) 167.5,62.4 UC1.Y6
  BOTTOM w0.102: v2(183.13,77.13) 183.13,77.38 183.32,77.57 183.32,78.4 184.88,79.96 JSPI1.12
PCH_SPI_DO3: length 37.1
  TOP w0.102: v2(184.91,78.59) 185.57,78.59 185.85,78.87 v1(185.85,79.12) RC230.2
  IN1 w0.089: v2(184.91,78.59) 184.91,77.84 185.29,77.46 185.29,69.63 186.53,68.4 186.53,64.88 185.56,63.92 185.47,63.92 184.24,62.68 183.44,62.68 183.11,62.35 180.96,62.35 180.8,62.19 178.61,62.19 176.95,60.53 173.09,60.53 173.03,60.58 172.28,60.58 v2(171.9,60.19)
  BOTTOM w0.076: v2(171.9,60.19) 171.37,59.67 170.91,59.67 UC1.AF1
  BOTTOM w0.102: v2(184.91,78.59) 185.88,79.56 JSPI1.14
PCI_CLK_LPC_0: length 14.1
  TOP w0.102: RC74.1 RC72.1 160.97,43.42 v1(160.97,47.5) 160.97,53.55 v2(162.22,54.8)
  BOTTOM w0.081: v2(162.22,54.8) 162.53,55.11 UC1.AN15
PCI_CLK_LPC_1: length 12.5
  TOP w0.102: v2(162.21,54.16) 162.22,54.16 163.13,53.25 v1(163.13,47.98) 163.13,45.74 164.12,44.75 RC70.1 RC67.1
  BOTTOM w0.081: v2(162.21,54.16) 162.51,54.45 UC1.AP15
PCIE_PRX_GLANTX_N3: length 125.9
  TOP w0.102: CL2.2 258.69,91.82 259.05,92.17 259.05,92.48 258.32,93.21 256.97,93.21 255.33,94.85 251.36,94.85 251.04,94.53 245.66,94.53 238.1,86.97 237.11,86.97 236.71,86.57 235.5,86.57 235.23,86.84 235.23,87.1 v2(235.06,87.27)
  IN1 w0.089: v2(163.95,69.9) 163.82,70.03 163.61,70.03 163.56,69.97 163.56,68.44 163.52,68.41 163.52,68.4 163.21,68.09 163.21,68.09 163.19,68.08 160.8,68.08 160.79,68.09 160.77,68.09 160.47,68.39 160.47,73.64 160.6,73.77 160.6,76.56 164.69,80.65 167.68,80.65 171.11,84.08 171.11,85.96 172.91,87.75 178.21,87.75 178.7,87.26 203.83,87.26 204.48,87.91 221.31,87.91 221.87,87.34 230.95,87.34 231.79,86.51 235,86.51 235.25,86.75 235.25,87.08 v2(235.06,87.27)
  BOTTOM w0.081: v2(163.95,69.9) 164.26,69.59 UC1.G11
PCIE_PRX_GLANTX_N3_C: length 2.8
  TOP w0.102: CL2.1 258.98,90.6 258.98,90.47 258.91,90.4 258.66,90.4 258.12,89.86 258.12,89.39 258.03,89.29 UL1.39
PCIE_PRX_GLANTX_P3: length 126
  TOP w0.102: v2(235.65,87.27) 235.44,87.05 235.44,86.93 235.58,86.78 236.62,86.78 237.02,87.18 238.01,87.18 245.58,94.74 250.95,94.74 251.27,95.06 255.42,95.06 257.06,93.42 258.4,93.42 259.25,92.57 259.25,92.13 CL1.2
  IN1 w0.089: v2(235.65,87.27) 235.42,87.04 235.42,86.68 235.08,86.34 231.72,86.34 230.88,87.17 221.8,87.17 221.24,87.74 204.55,87.74 203.9,87.09 178.63,87.09 178.14,87.58 172.98,87.58 171.28,85.89 171.28,84.01 167.76,80.48 164.76,80.48 160.77,76.49 160.77,73.7 160.64,73.57 160.64,68.46 160.84,68.26 160.86,68.26 160.87,68.25 163.12,68.25 163.14,68.26 163.14,68.26 163.35,68.48 163.35,68.48 163.39,68.51 163.39,70.04 163.54,70.2 163.74,70.2 163.8,70.26 163.82,70.26 163.95,70.39 v2(163.95,70.64)
  BOTTOM w0.081: v2(163.95,70.64) 164.36,70.24 UC1.F11
PCIE_PRX_GLANTX_P3_C: length 2.8
  TOP w0.102: UL1.38 258.43,89.32 258.33,89.41 258.33,89.78 258.74,90.19 259,90.19 259.19,90.38 259.19,90.52 CL1.1
PCIE_PRX_MMITX_N1: length 149.4
  TOP w0.102: CR27.1 276.43,29.91 276.06,29.91 v2(275.79,29.65)
  IN4 w0.089: v2(161.01,69.82) 161.01,69.94 161.15,70.07 161.36,70.07 161.58,70.29 161.58,71.36 161.55,71.38 161.55,71.7 162.88,73.02 164.81,73.02 166.76,74.98 169.92,74.98 171.12,73.78 172.14,73.78 175.28,70.64 183.6,70.64 185.47,68.76 186.81,68.76 191.93,63.64 191.93,56.97 192.44,56.46 192.44,54.32 192.93,53.83 192.93,53.15 195.53,50.55 195.53,47.92 197.14,46.31 197.14,43.98 204.93,36.19 215.33,36.19 215.6,36.45 223.46,36.45 223.59,36.59 226.68,36.59 226.81,36.45 231.82,36.45 233.56,34.71 236.57,34.71 239.6,31.68 244.02,31.68 244.46,31.24 249.28,31.24 251.44,29.09 253.77,29.09 254.56,28.3 264.37,28.3 265.12,29.05 266.68,29.05 268.34,30.72 274.69,30.72 275.28,30.13 275.42,30.13 275.79,29.76 v2(275.79,29.65)
  BOTTOM w0.081: UC1.G17 161.51,69.71 161.41,69.82 v2(161.01,69.82)
PCIE_PRX_MMITX_N1_C: length 4.5
  TOP w0.102: CR27.2 278.02,29.91 278.38,29.91 278.98,30.52 280.02,30.52 280.04,30.5 280.52,30.5 280.57,30.44 281.07,30.44 281.21,30.31 UR1.8
PCIE_PRX_MMITX_P1: length 149.3
  TOP w0.102: v2(275.79,30.32) 275.99,30.12 276.43,30.12 CR26.1
  IN4 w0.089: v2(275.79,30.32) 275.77,30.3 275.35,30.3 274.77,30.89 268.27,30.89 266.61,29.22 265.05,29.22 264.3,28.47 254.63,28.47 253.84,29.26 251.51,29.26 249.36,31.41 244.53,31.41 244.09,31.86 239.67,31.86 236.64,34.89 233.63,34.89 231.89,36.63 226.88,36.63 226.75,36.76 223.52,36.76 223.39,36.63 215.53,36.63 215.26,36.36 205,36.36 197.31,44.05 197.31,46.38 195.7,47.99 195.7,50.62 193.1,53.22 193.1,53.9 192.61,54.39 192.61,56.53 192.1,57.04 192.1,63.71 186.88,68.94 185.54,68.94 183.67,70.81 175.35,70.81 172.21,73.95 171.19,73.95 169.99,75.15 166.69,75.15 164.73,73.19 162.81,73.19 161.38,71.77 161.38,71.31 161.41,71.29 161.41,70.36 161.29,70.24 161.08,70.24 161.01,70.32 v2(161.01,70.65)
  BOTTOM w0.081: UC1.F17 161.38,70.24 161.01,70.6 v2(161.01,70.65)
PCIE_PRX_MMITX_P1_C: length 4.4
  TOP w0.102: CR26.2 278.02,30.12 278.29,30.12 278.89,30.73 v4(280.35,30.73) 280.59,30.73 280.66,30.65 281.16,30.65 281.21,30.71 UR1.7
PCIE_PRX_SATATX_N6_L0: length 84.4
  IN1 w0.089: v2(229.04,62.36) 229.07,62.36 229.46,62.75 229.46,62.82 229.33,62.95 228.16,62.95 227.6,63.51 222.71,63.51 220.97,65.25 201.16,65.25 199.17,67.24 199.17,70.15 199.39,70.36 199.39,71.5 188.44,82.44 178.7,82.44 178.06,81.81 178.06,79.56 169.31,70.8 168.1,70.8 v2(167.78,70.49)
  BOTTOM w0.076: UC1.F5 168.18,70.36 168.05,70.49 v2(167.78,70.49)
  BOTTOM w0.102: v2(229.04,62.36) 229.04,61.78 229.25,61.58 229.9,61.58 230.73,62.41 231.36,62.41 231.42,62.35 JNGFF2.35
PCIE_PRX_SATATX_N6_L1: length 87.8
  IN1 w0.089: v2(228.34,63.67) 228.36,63.67 228.71,64.02 228.71,64.1 228.59,64.22 222.91,64.22 221.24,65.89 201.43,65.89 199.81,67.5 199.81,69.56 200.03,69.78 200.03,71.81 188.76,83.08 178.4,83.08 177.33,82.02 177.33,81.24 175.58,79.5 174.25,79.5 167.17,72.42 167.17,70.33 167.35,70.15 167.35,69.26 167.12,69.03 167.02,69.03 166.75,68.77 v2(166.75,68.64)
  BOTTOM w0.081: UC1.J6 167.22,68.48 167.05,68.64 v2(166.75,68.64)
  BOTTOM w0.102: JNGFF2.21 229.94,65.85 228.35,64.26 228.35,63.68 v2(228.34,63.67)
PCIE_PRX_SATATX_P6_L0: length 84.4
  IN1 w0.089: v2(229.64,62.36) 229.63,62.36 229.63,62.89 229.4,63.12 228.23,63.12 227.67,63.68 222.78,63.68 221.04,65.42 201.23,65.42 199.34,67.31 199.34,70.08 199.56,70.29 199.56,71.57 188.51,82.61 178.62,82.61 177.89,81.88 177.89,79.63 169.23,70.97 168.05,70.97 v2(167.78,71.25)
  BOTTOM w0.076: v2(167.78,71.25) 168.14,70.89 UC1.E5
  BOTTOM w0.102: v2(229.64,62.36) 229.63,62.36 229.25,61.98 229.25,61.87 229.33,61.78 229.82,61.78 230.65,62.62 231.19,62.62 231.42,62.85 JNGFF2.33
PCIE_PRX_SATATX_P6_L1: length 87.8
  IN1 w0.089: v2(166.75,69.37) 166.75,69.33 166.87,69.2 167.05,69.2 167.18,69.33 167.18,70.08 167,70.26 167,72.49 174.18,79.67 175.51,79.67 177.16,81.31 177.16,82.09 178.32,83.25 188.83,83.25 200.2,71.88 200.2,69.71 199.98,69.49 199.98,67.58 201.5,66.06 221.31,66.06 222.98,64.39 228.66,64.39 228.88,64.17 228.88,63.73 v2(228.93,63.67)
  BOTTOM w0.081: UC1.H6 167.23,69.05 166.91,69.37 v2(166.75,69.37)
  BOTTOM w0.102: v2(228.93,63.67) 228.93,63.68 228.56,64.04 228.56,64.17 230.03,65.64 231.37,65.64 231.43,65.58 231.43,65.44 231.52,65.35 JNGFF2.23
PCIE_PRX_WIGIGTX_N5: length 109.6
  IN4 w0.089: v2(224.82,34.77) 224.95,34.77 225.25,35.08 225.25,35.21 225.16,35.3 224.18,35.3 223.65,34.77 204.53,34.77 195.86,43.45 195.86,45.78 194.25,47.39 194.25,48.82 193.44,49.63 193.44,50.82 191.65,52.62 191.65,53.3 190.65,54.29 190.65,62.94 186.86,66.73 184.97,66.73 184.27,67.43 180.72,67.43 180.3,67.85 177.5,67.85 176.46,68.89 174.08,68.89 169.7,73.28 167.82,73.28 165.46,70.92 165.29,70.92 v2(164.96,70.59)
  BOTTOM w0.081: UC1.F10 165.32,70.36 165.09,70.59 v2(164.96,70.59)
  BOTTOM w0.102: v2(224.82,34.77) 224.82,29.68 227.57,26.93 227.57,20.71 230.78,17.5 v4(231.4,17.5) 232.28,17.5 232.42,17.35 JNGFF1.59
PCIE_PRX_WIGIGTX_P5: length 109.6
  IN4 w0.089: v2(164.91,71.25) 165.07,71.09 165.39,71.09 167.75,73.45 169.77,73.45 174.15,69.06 176.53,69.06 177.57,68.02 180.38,68.02 180.79,67.6 184.34,67.6 185.04,66.9 186.93,66.9 190.82,63.01 190.82,54.36 191.82,53.37 191.82,52.69 193.61,50.89 193.61,49.7 194.42,48.89 194.42,47.46 196.03,45.85 196.03,43.52 204.6,34.94 223.58,34.94 224.11,35.47 225.23,35.47 225.42,35.28 225.42,34.89 v2(225.53,34.77)
  BOTTOM w0.081: v2(164.91,71.25) 164.96,71.25 UC1.E10
  BOTTOM w0.102: v2(225.53,34.77) 225.4,34.77 225.03,34.41 225.03,29.77 227.78,27.02 227.78,20.8 230.87,17.7 231.09,17.7 231.11,17.72 231.7,17.72 231.72,17.7 232.28,17.7 232.42,17.85 JNGFF1.57
PCIE_PRX_WLANTX_N4: length 110.7
  IN4 w0.089: v2(229.86,35.72) 230.27,35.31 230.27,35.16 230.18,35.07 229.7,35.07 228.78,35.98 226.58,35.98 226.45,36.12 223.85,36.12 223.71,35.98 215.9,35.98 215.58,35.66 204.79,35.66 196.67,43.78 196.67,46.12 195.06,47.73 195.06,50.35 192.46,52.95 192.46,53.63 191.97,54.12 191.97,56.26 191.46,56.77 191.46,63.32 187.06,67.73 185.29,67.73 184.72,68.3 181.29,68.3 179.55,70.04 175.21,70.04 172.13,73.13 170.88,73.13 169.87,74.14 167.04,74.14 165.16,72.26 164.12,72.26 163.37,71.51 163.37,70.5 163.27,70.4 163.13,70.4 162.98,70.54 v2(162.98,70.68)
  BOTTOM w0.081: v2(162.98,70.68) 162.98,70.66 163.4,70.24 UC1.F13
  BOTTOM w0.102: JNGFF1.35 231.89,23.35 230.27,24.98 230.27,29.09 229.86,29.5 v2(229.86,35.72)
PCIE_PRX_WLANTX_P4: length 110.7
  IN4 w0.089: v2(162.99,69.95) 162.99,70.07 163.15,70.23 163.34,70.23 163.54,70.43 163.54,71.44 164.19,72.09 165.23,72.09 167.11,73.97 169.8,73.97 170.81,72.96 172.06,72.96 175.14,69.87 179.48,69.87 181.22,68.13 184.65,68.13 185.22,67.56 186.98,67.56 191.29,63.25 191.29,56.7 191.8,56.19 191.8,54.05 192.29,53.56 192.29,52.88 194.89,50.28 194.89,47.66 196.5,46.05 196.5,43.71 204.72,35.49 215.65,35.49 215.97,35.81 223.78,35.81 223.92,35.95 226.38,35.95 226.51,35.81 228.71,35.81 229.63,34.9 230.25,34.9 230.44,35.09 v2(230.44,35.72)
  BOTTOM w0.081: UC1.G13 163.42,69.58 163.42,69.66 163.13,69.95 v2(162.99,69.95)
  BOTTOM w0.102: v2(230.44,35.72) 230.07,35.35 230.07,29.58 230.47,29.17 230.47,25.06 231.98,23.56 232.3,23.56 232.37,23.63 232.37,23.75 232.47,23.85 JNGFF1.33
PCIE_PTX_GLANRX_N3: length 120.2
  TOP w0.102: CL6.1 257.26,91.82 257.34,91.9 257.34,92.29 257.25,92.37 256.64,92.37 255.3,93.72 246.05,93.72 238.28,85.94 237.83,85.94 v2(237.54,85.65)
  IN1 w0.089: v2(153.95,74.19) 154.14,74.37 156.42,74.37 164.47,82.42 166.69,82.42 169.53,85.25 169.53,86.66 171.09,88.22 178.4,88.22 178.9,87.73 203.64,87.73 204.37,88.46 221.61,88.46 222.11,87.95 231.52,87.95 232.03,87.45 233.48,87.45 234.09,88.07 235.74,88.07 236.68,87.13 236.68,86.26 237.09,85.86 237.33,85.86 v2(237.54,85.65)
  BOTTOM w0.081: v2(153.95,74.19) 153.87,74.27 153.53,74.27 153.27,74.01 153.27,72.7 153.56,72.41 UC1.C29
PCIE_PTX_GLANRX_N3_C: length 2.5
  TOP w0.102: CL6.2 257.27,90.54 257.27,90.36 256.95,90.04 256.95,89.56 256.83,89.44 UL1.42
PCIE_PTX_GLANRX_P3: length 120.2
  TOP w0.102: v2(237.54,86.24) 237.62,86.15 238.19,86.15 245.97,93.92 255.39,93.92 256.73,92.58 257.34,92.58 257.54,92.38 257.54,92.06 CL5.1
  IN1 w0.089: v2(237.54,86.24) 237.33,86.03 237.16,86.03 236.85,86.33 236.85,87.2 235.81,88.24 234.02,88.24 233.41,87.62 232.1,87.62 231.59,88.12 222.19,88.12 221.68,88.63 204.3,88.63 203.56,87.9 178.97,87.9 178.47,88.39 171.02,88.39 169.36,86.73 169.36,85.32 166.62,82.59 164.4,82.59 156.35,74.54 154.19,74.54 v2(153.95,74.77)
  BOTTOM w0.081: v2(153.95,74.77) 153.64,74.46 153.45,74.46 153.09,74.09 153.09,72.62 UC1.B30
PCIE_PTX_GLANRX_P3_C: length 2.4
  TOP w0.102: CL5.2 257.48,90.58 257.48,90.27 257.16,89.96 257.16,89.51 257.23,89.44 UL1.41
PCIE_PTX_MMIRX_N1: length 160.6
  TOP w0.102: CR25.1 276.43,31.9 276.01,31.9 v2(275.82,32.09)
  IN4 w0.089: v2(151.74,74.91) 151.94,74.71 152.28,74.71 152.48,74.91 152.48,76.12 152.9,76.53 155.82,76.53 156.27,76.99 162.31,76.99 162.81,76.49 171.32,76.49 171.76,76.94 175.61,76.94 176.48,77.81 179.71,77.81 182.68,74.84 183.28,74.84 187.27,70.85 188.13,70.85 193.89,65.1 193.89,54.92 196.98,51.83 196.98,48.53 206.66,38.85 226.39,38.85 227.61,37.63 231.11,37.63 231.42,37.32 232.97,37.32 234.68,35.61 239.12,35.61 240.42,34.32 244.04,34.32 245.68,32.68 249.01,32.68 251.69,30 256.09,30 256.73,29.36 264.21,29.36 264.75,29.91 266.18,29.91 267.8,31.53 274.8,31.53 275.18,31.9 275.63,31.9 v2(275.82,32.09)
  BOTTOM w0.081: v2(151.74,74.91) 152.27,74.38 152.27,73.94 152.12,73.79 152.12,73.5 152.21,73.26 152.21,73.1 152.18,73.01 152.18,73.01 152.17,73 152.14,72.94 152.14,72.81 152.17,72.71 152.38,72.5 152.56,72.5 152.73,72.33 UC1.C30
PCIE_PTX_MMIRX_N1_C: length 4.4
  TOP w0.102: UR1.5 281.21,31.51 281.12,31.41 280.16,31.41 279.67,31.9 279,31.9 278.98,31.92 278,31.92 CR25.2
PCIE_PTX_MMIRX_P1: length 160.6
  TOP w0.102: CR24.1 276.43,31.69 276.01,31.69 v2(275.82,31.5)
  IN4 w0.089: v2(151.74,74.33) 151.94,74.54 152.35,74.54 152.65,74.84 152.65,76.05 152.97,76.36 155.89,76.36 156.34,76.82 162.24,76.82 162.74,76.32 171.39,76.32 171.84,76.77 175.68,76.77 176.55,77.64 179.64,77.64 182.61,74.67 183.21,74.67 187.2,70.68 188.06,70.68 193.72,65.03 193.72,54.85 196.81,51.76 196.81,48.46 206.59,38.68 226.32,38.68 227.54,37.46 231.04,37.46 231.35,37.15 232.9,37.15 234.61,35.44 239.05,35.44 240.35,34.15 243.97,34.15 245.61,32.51 248.94,32.51 251.62,29.83 256.02,29.83 256.66,29.19 264.28,29.19 264.83,29.74 266.25,29.74 267.87,31.36 274.87,31.36 275.25,31.73 275.59,31.73 v2(275.82,31.5)
  BOTTOM w0.081: v2(151.74,74.33) 151.87,74.46 151.95,74.46 152.09,74.33 152.09,74.02 151.96,73.89 151.96,73.46 151.98,73.4 151.98,73.4 152.04,73.23 152.04,73.13 151.99,73 151.99,73 151.98,72.97 151.98,72.79 152.02,72.63 152.12,72.48 152.12,72.07 152.27,71.92 152.54,71.92 152.58,71.96 152.58,72.14 152.51,72.21 UC1.C31
PCIE_PTX_MMIRX_P1_C: length 4.4
  TOP w0.102: CR24.2 278.02,31.69 v4(278.7,31.69) 279.59,31.69 280.07,31.21 281.11,31.21 281.21,31.11 UR1.6
PCIE_PTX_SATARX_N6_L0: length 91.4
  TOP w0.102: CZ58.1 233.11,61.19 233.52,61.19 v2(233.81,61.48)
  IN1 w0.089: v2(161.93,71.52) 161.93,71.28 161.97,71.23 162.24,71.23 164.4,73.39 165.68,73.39 174.46,82.17 175.89,82.17 177.62,83.89 189.41,83.89 197.63,75.67 197.89,75.67 200.84,72.71 200.84,69.36 203.5,66.7 221.57,66.7 223.23,65.05 228.95,65.05 229.52,64.48 229.52,64.07 230.6,62.98 231.22,62.98 232.43,61.77 233.52,61.77 v2(233.81,61.48)
  BOTTOM w0.081: UC1.C17 161.28,72.31 161.93,71.66 v2(161.93,71.52)
PCIE_PTX_SATARX_N6_L0_C: length 2.8
  TOP w0.102: v2(230.88,61.39) 231.08,61.19 231.57,61.19 CZ58.2
  BOTTOM w0.102: v2(230.88,61.39) 231.06,61.2 231.42,61.2 231.57,61.35 JNGFF2.39
PCIE_PTX_SATARX_N6_L1: length 87.9
  TOP w0.102: CZ32.1 231.5,64.23 230.87,64.23 v2(230.63,64.46)
  IN1 w0.089: v2(161.78,74.66) 161.91,74.53 162.48,74.53 164.06,76.11 167.49,76.11 174.29,82.91 175.56,82.91 177.19,84.53 189.69,84.53 197.91,76.31 198.18,76.31 201.49,73.01 201.49,69.96 203.05,68.39 204.33,68.39 204.33,68.39 210.04,68.39 211.08,67.34 221.84,67.34 223.42,65.76 229.44,65.76 230.18,65.01 230.18,64.32 230.28,64.23 230.4,64.23 v2(230.63,64.46)
  BOTTOM w0.081: v2(161.78,74.66) 161.97,74.46 162.18,74.46 162.37,74.27 162.37,73.32 162.14,73.09 162.14,72.88 162.28,72.75 162.37,72.75 UC1.B14
PCIE_PTX_SATARX_N6_L1_C: length 2.7
  TOP w0.102: v2(233.74,64.41) 233.56,64.24 233.06,64.24 CZ32.2
  BOTTOM w0.102: JNGFF2.27 233.09,64.35 233.24,64.2 233.53,64.2 v2(233.74,64.41)
PCIE_PTX_SATARX_P6_L0: length 91.4
  TOP w0.102: v2(233.81,60.9) 233.72,60.98 233.09,60.98 232.8,60.69 CZ59.1
  IN1 w0.089: v2(233.81,60.9) 233.8,60.9 233.4,61.3 233.4,61.45 233.25,61.6 232.36,61.6 231.15,62.81 230.53,62.81 229.35,64 229.35,64.41 228.88,64.88 223.16,64.88 221.5,66.53 203.43,66.53 200.67,69.29 200.67,72.64 197.82,75.5 197.56,75.5 189.34,83.72 177.69,83.72 175.96,82 174.53,82 165.75,73.22 164.47,73.22 162.31,71.06 162.18,71.06 v2(161.99,70.87)
  BOTTOM w0.081: v2(161.99,70.87) 161.99,70.92 161.62,71.28 161.48,71.28 161.35,71.41 161.35,71.6 UC1.D17
PCIE_PTX_SATARX_P6_L0_C: length 2.8
  TOP w0.102: v2(230.88,60.81) 231.06,60.98 231.52,60.98 CZ59.2
  BOTTOM w0.102: JNGFF2.41 231.62,60.85 231.47,61 231.07,61 v2(230.88,60.81)
PCIE_PTX_SATARX_P6_L1: length 87.9
  TOP w0.102: v2(230.65,63.79) 230.88,64.02 231.47,64.02 CZ33.1
  IN1 w0.089: v2(161.78,74.09) 162.06,74.36 162.55,74.36 164.13,75.94 167.56,75.94 174.36,82.73 175.63,82.73 177.26,84.36 189.62,84.36 197.84,76.14 198.11,76.14 201.32,72.94 201.32,69.89 202.98,68.22 204.16,68.22 204.16,68.22 209.97,68.22 211.01,67.17 221.77,67.17 223.35,65.59 229.36,65.59 230.01,64.94 230.01,64.25 230.21,64.06 230.39,64.06 v2(230.65,63.79)
  BOTTOM w0.081: UC1.C15 162.11,72.57 162.11,72.65 161.95,72.81 161.95,73.17 162.18,73.4 162.18,74.19 162.1,74.28 161.97,74.28 v2(161.78,74.09)
PCIE_PTX_SATARX_P6_L1_C: length 2.8
  TOP w0.102: v2(233.74,63.83) 233.54,64.03 233.1,64.03 CZ33.2
  BOTTOM w0.102: JNGFF2.29 233.08,63.85 233.22,64 233.57,64 v2(233.74,63.83)
PCIE_PTX_WIGIGRX_N5: length 121.8
  TOP w0.102: v2(226.55,34.78) 226.63,34.7 v4(226.63,26.11) 226.63,25.78 227.94,24.46 227.94,23.4 229.4,21.94 229.73,21.94 CZ22.1
  IN4 w0.089: v2(226.55,34.78) 226.84,34.49 226.84,34.4 226.75,34.3 204.34,34.3 195.39,43.25 195.39,45.59 193.78,47.2 193.78,48.62 192.97,49.43 192.97,50.63 190.18,53.42 190.18,62.64 186.74,66.08 184.4,66.08 183.96,66.52 178.11,66.52 176.33,68.3 173.78,68.3 172.63,69.45 169.47,69.45 168.56,70.36 168.56,71.43 168.21,71.77 168.01,71.77 168,71.78 167.56,71.78 167.55,71.77 166.96,71.77 163.44,68.25 160.81,68.25 160.61,68.45 160.61,71.71 161.27,72.37 161.27,75.17 160.81,75.63 159.62,75.63 158.87,74.88 158.49,74.88 158.39,74.98 158.38,74.98 158.24,75.11 v2(158.24,75.24)
  BOTTOM w0.081: UC1.C23 157.74,72.31 157.86,72.43 157.86,72.5 157.68,72.68 157.68,73.08 157.91,73.31 157.91,73.59 157.66,73.85 157.66,74.66 157.84,74.84 157.95,74.84 158.24,75.14 v2(158.24,75.24)
PCIE_PTX_WIGIGRX_N5_C: length 6.2
  TOP w0.102: v2(231.71,18.83) 231.55,18.99 231.3,18.99 231.06,19.23 231.06,20.25 231.45,20.65 231.45,21.95 231.37,22.03 231.24,22.03 CZ22.2
  BOTTOM w0.102: v2(231.71,18.83) 231.88,19 232.28,19 232.42,18.85 JNGFF1.53
PCIE_PTX_WIGIGRX_P5: length 121.9
  TOP w0.102: v2(227.13,34.78) 226.84,34.48 226.84,26.41 226.86,26.39 226.86,25.84 228.15,24.55 228.15,23.48 229.49,22.15 229.86,22.15 229.98,22.27 CZ21.1
  IN4 w0.089: v2(158.24,74.61) 158.34,74.71 158.94,74.71 159.69,75.46 160.74,75.46 161.1,75.1 161.1,72.44 160.44,71.78 160.44,68.38 160.74,68.08 163.51,68.08 167.03,71.6 167.62,71.6 167.63,71.61 167.93,71.61 167.94,71.6 168.14,71.6 168.39,71.36 168.39,70.29 169.4,69.28 172.56,69.28 173.7,68.13 176.26,68.13 178.04,66.35 183.89,66.35 184.33,65.91 186.67,65.91 190.01,62.57 190.01,53.35 192.8,50.56 192.8,49.36 193.61,48.55 193.61,47.13 195.22,45.52 195.22,43.18 204.27,34.13 226.82,34.13 227.01,34.33 227.01,34.65 v2(227.13,34.78)
  BOTTOM w0.081: v2(158.24,74.61) 158.2,74.65 157.92,74.65 157.84,74.58 157.84,73.92 158.1,73.67 158.1,73.24 157.86,73 157.86,72.76 158.05,72.58 158.05,71.78 UC1.C22
PCIE_PTX_WIGIGRX_P5_C: length 6.2
  TOP w0.102: v2(231.71,19.41) 231.5,19.2 231.38,19.2 231.26,19.32 231.26,20.17 231.66,20.57 231.66,22.03 231.45,22.24 231.24,22.24 CZ21.2
  BOTTOM w0.102: v2(231.71,19.41) 231.92,19.2 232.28,19.2 232.42,19.35 JNGFF1.51
PCIE_PTX_WLANRX_N4: length 115.2
  TOP w0.102: v2(225.87,37.82) 225.93,37.76 225.93,37.02 227.74,35.21 227.74,25.97 228.08,25.62 228.4,25.62 CZ14.1
  IN4 w0.089: v2(225.87,37.82) 226.07,37.62 226.07,37.46 226.01,37.4 224.38,37.4 223.57,38.21 206.39,38.21 196.34,48.26 196.34,51.56 193.25,54.65 193.25,64.66 187.7,70.21 186.74,70.21 185.48,71.48 175.59,71.48 172.1,74.97 171.14,74.97 170.31,75.79 162.6,75.79 162.04,76.35 157.11,76.35 156.11,75.35 153.77,75.35 153.6,75.52 153.6,75.58 v2(153.8,75.77)
  BOTTOM w0.081: v2(153.8,75.77) 153.85,75.72 154.19,75.72 154.5,75.4 154.5,73.85 153.56,72.91 UC1.B29
PCIE_PTX_WLANRX_N4_C: length 4.4
  TOP w0.102: CZ14.2 229.9,25.71 230.12,25.71 230.84,24.99 231.68,24.99 v2(231.86,24.82)
  BOTTOM w0.102: v2(231.86,24.82) 232.03,25 232.4,25 232.55,24.85 JNGFF1.29
PCIE_PTX_WLANRX_P4: length 115.2
  TOP w0.102: v2(226.46,37.82) 226.14,37.5 226.14,37.1 227.95,35.29 227.95,26.05 228.17,25.83 228.55,25.83 228.65,25.93 CZ13.1
  IN4 w0.089: v2(153.51,75.1) 153.6,75.18 156.18,75.18 157.18,76.18 161.97,76.18 162.52,75.62 170.24,75.62 171.07,74.8 172.03,74.8 175.52,71.3 185.41,71.3 186.67,70.04 187.62,70.04 193.08,64.59 193.08,54.58 196.17,51.49 196.17,48.19 206.32,38.04 223.5,38.04 224.31,37.23 226.08,37.23 226.24,37.38 226.24,37.59 v2(226.46,37.82)
  BOTTOM w0.081: v2(153.51,75.1) 153.45,75.16 153.45,75.33 153.53,75.41 153.94,75.41 153.96,75.41 154.05,75.51 154.13,75.51 154.32,75.32 154.32,73.93 153.77,73.38 153.69,73.38 UC1.A29
PCIE_PTX_WLANRX_P4_C: length 4.5
  TOP w0.102: v2(231.86,25.41) 231.65,25.2 230.93,25.2 230.21,25.92 229.9,25.92 CZ13.2
  BOTTOM w0.102: v2(231.86,25.41) 232.06,25.2 232.4,25.2 232.55,25.35 JNGFF1.27
PCIE_WAKE#: length 99.7
  TOP w0.102: RE275.1 255.2,74.97 254.51,75.67 241.61,75.67 240.41,74.46 240.41,72.85 239.65,72.09 239.65,68.52 240.79,67.38 240.79,64.43 241.04,64.17 241.04,62.01 241.74,61.32 241.74,60.74 ; v2(241.47,59.67) 241.47,60.48 241.74,60.74 ; v2(238.5,21.31) 240.92,21.31 242.95,23.34 242.95,25.58 241.82,26.71 241.3,26.71 240.66,27.34 240.66,27.84 239.38,29.12 239.38,30.52 238.71,31.2 238.71,33.17 237.74,34.14 v1(237.74,35.61) RE274.1 241.16,39.03 243.77,39.03 244.15,39.41 244.15,40.98 244.98,41.8 244.98,45.79 244.71,46.06 244.71,46.06 244.69,46.08 244.69,51.09 245.83,52.24 245.83,58.95 244.04,60.74 241.74,60.74
  BOTTOM w0.102: JNGFF2.46 241.4,59.6 v2(241.47,59.67) ; JNGFF1.62 239.52,16.6 238.5,17.62 v2(238.5,21.31) 237.04,21.31 236.08,20.35 JNGFF1.47
PCIE_WAKE#_R: length 8.5
  TOP w0.102: v2(254.12,72.36) 254.25,72.49 RE35.2 RE275.2 255.72,72.99 255.99,73.25 255.99,74.57 v1(256.32,74.9) ; UE1.B10 v2(254.37,69.44)
  IN1 w0.089: v2(254.37,69.44) 254.37,70.78 253.68,71.48 253.68,72.17 253.87,72.36 v2(254.12,72.36)
PE_REXT: length 2.5
  TOP w0.102: RR2.2 279.75,32.74 v1(280.43,32.06) 280.58,31.91 UR1.4
PECI_EC: length 281.9
  TOP w0.102: v1(91.68,39.7) 91.75,39.78 v2(91.75,40.55) ; RE60.2 263.53,33.88 v2(263.35,34.05)
  IN1 w0.089: v2(263.35,34.05) 263.09,34.05 261.54,32.5 261.54,32.11 260.84,31.41 257.18,31.41 251.79,26.02 251.79,19.9 246.91,15.02 243.2,15.02 241.28,13.1 228.71,13.1 224.04,8.43 148.89,8.43 147.13,10.2 144.27,10.2 142.45,8.38 94.66,8.38 93.87,9.16 93.87,38.43 v2(91.75,40.55)
  IN3 w0.122: v2(133.16,65.95) 133.92,65.19 134.74,65.19 135.05,64.88 135.05,61.3 133.98,60.24 133.98,54.97 132.52,53.5 132.52,51.98 121.09,40.55 v2(91.75,40.55)
  BOTTOM w0.081: v2(133.16,65.95) 133.16,65.97 UC1.N62
PECI_EC_R: length 10.6
  TOP w0.102: UE2.A48 262.75,37.08 264.31,37.08 264.44,36.95 264.44,36.55 264.31,36.42 262.87,36.42 262.75,36.3 262.75,35.87 262.89,35.72 262.96,35.72 263.16,35.92 265.12,35.92 265.25,35.79 v1(265.25,35.15) 265.25,34.84 265.12,34.71 264.79,34.71 264.67,34.84 264.67,35.28 264.54,35.41 264.06,35.41 263.94,35.28 263.94,34.87 RE60.1
PGOOD_3V_5V: length 4.8
  TOP w0.102: v1(223.77,47.17) 223.49,47.17 222.72,47.94 PR107.1
  TOP w0.203: PR108.2 221.46,47.94 220.28,49.11 PU100.7
  TOP w0.254: PR107.1 PR108.2
PLTRST_LAN#: length 114.4
  TOP w0.102: v2(263.97,69.63) 263.97,71.6 264.6,72.24 v1(264.6,80.68) 264.6,84.18 263.53,85.25 263.53,85.93 262.82,86.64 262.82,88.95 261.83,89.94 261.3,89.94 260.28,88.92 260.28,88.24 260.03,87.99 UL1.36 ; v2(193.04,82.46) 192.63,82.05 192.63,77.52 192.29,77.18 192.29,75.65 191.41,74.77 191.41,73.48 191.15,73.21 RC89.1
  IN1 w0.089: v2(235.57,76.75) 235.57,76.95 233.98,78.54 223.19,78.54 221.42,80.3 221.42,80.52 217.85,84.09 215.75,84.09 215.44,84.4 202.19,84.4 201.48,85.11 196.33,85.11 193.67,82.46 v2(193.04,82.46)
  IN4 w0.089: v2(263.97,69.63) 260.4,73.2 250.49,73.2 249.98,73.71 243.75,73.71 240.71,76.75 v2(235.57,76.75)
PLTRST_MMI#: length 160.9
  TOP w0.102: UR1.15 283.32,27.39 283.14,27.22 283.14,25.88 282.43,25.17 282.43,23.72 281.92,23.22 280.68,23.22 280.34,23.56 277.34,23.56 276.82,24.07 276.82,27.77 276.31,28.28 274,28.28 273.76,28.52 273.76,28.86 273.94,29.03 273.94,32.68 v1(274.67,33.41) 275.21,33.95 275.21,39.31 276.21,40.31 276.21,43.45 273.85,45.81 273.85,47.97 274.04,48.16 274.04,52.58 v2(273.88,52.74) ; v2(193.04,83.1) 192.4,82.46 192.4,77.61 191.96,77.17 191.96,75.84 190.89,74.78 RC88.1
  IN1 w0.089: v2(193.04,83.1) 193.04,83.98 194.38,85.33 201.57,85.33 202.27,84.63 215.56,84.63 215.86,84.34 217.97,84.34 221.66,80.64 221.66,80.4 223.29,78.78 236.12,78.78 239.42,75.48 239.42,58.3 242.44,55.28 245.55,55.28 246,55.73 247.2,55.73 247.63,55.3 v2(249.29,55.3)
  IN4 w0.089: v2(273.88,52.74) 271.14,55.48 261.67,55.48 261.38,55.19 251.35,55.19 251.25,55.3 v2(249.29,55.3)
PLTRST_USH#: length 143
  TOP w0.102: v2(256.68,13.94) 257.05,13.94 257.96,13.03 257.96,11.66 257.67,11.37 JUSH1.6 ; RC87.1 191.64,72.22 191.64,74.54 v1(192.17,75.07) 192.52,75.41 192.52,77.08 193.04,77.6 v2(193.04,81.83)
  IN1 w0.089: v2(193.04,81.83) 193.35,81.83 196.43,84.9 201.39,84.9 202.11,84.18 215.31,84.18 215.65,83.84 217.76,83.84 221.17,80.43 221.17,79.29 222.16,78.29 233.78,78.29 234.93,77.14 234.93,76.69 235.77,75.86 237.8,75.86 239.2,74.45 239.2,58.2 242.38,55.03 245.68,55.03 246.12,55.47 247.08,55.47 247.66,54.89 v2(248.8,54.89)
  BOTTOM w0.102: v2(256.68,13.94) 256.41,14.21 256.41,29.65 249.87,36.19 249.87,40.87 248.64,42.1 248.64,44.44 249.12,44.92 249.12,46.27 252.24,49.39 252.24,51.1 248.8,54.54 v2(248.8,54.89)
PLTRST_VMM2320#: length 33.2
  TOP w0.102: RC219.1 192.08,71.72 192.08,74.02 192.92,74.85 192.92,76.91 193.48,77.47 193.48,83.75 192.53,84.7 192.53,86.27 v1(193.48,87.22) 198.9,87.22 200.05,86.08 200.05,83.46 200.45,83.06 201.83,83.06 203.32,81.57 203.32,80.75 UV8.A13
PM_APWROK: length 100.4
  TOP w0.102: RC26.1 187.81,50.24 v2(187.51,49.95) ; UE2.A9 258.69,48.54 v2(258.77,48.62)
  IN3 w0.122: v2(258.77,48.62) 258.76,48.62 258.11,49.27 258.11,49.29 257.66,49.73 257.36,49.73 257.06,49.43 257.06,48.62 256.7,48.26 248.05,48.26 246.38,46.58 246.38,38.58 245.36,37.57 243.65,37.57 242.44,36.36 238.12,36.36 238.12,36.36 237.77,36.36 234.7,33.28 234.7,32.93 233.27,31.5 232.23,31.5 230.57,29.83 229.44,29.83 228.6,28.99 210.05,28.99 206.83,32.21 197.53,32.21 190.6,39.13 190.6,45.24 188.03,47.82 188.03,49.43 v2(187.51,49.95)
PM_APWROK_L: length 6.1
  TOP w0.102: v1(190,50.62) 189.62,50.24 RC26.2 189.06,50.6 188.83,50.82 187.94,50.82 187.64,51.13 187.64,51.49 187.21,51.92 UC6.2 185.99,51.92 185.67,52.23 RC27.2
PM_APWROK_R: length 32.6
  TOP w0.102: v2(184.24,53.57) 184.76,53.57 185.07,53.25 v1(185.2,53.25) 186.79,53.25 188.4,51.64 UC6.4
  IN4 w0.089: v2(167.68,61.01) 168.21,60.48 168.34,60.48 168.65,60.16 168.65,59.75 168.93,59.47 177.39,59.47 179.36,61.44 183.26,61.44 185.54,59.16 185.54,55.79 184.78,55.03 184.78,54.11 v2(184.24,53.57)
  BOTTOM w0.076: v2(167.68,61.01) 168.12,61.45 UC1.AB5
PM_LANPHY_ENABLE: length 169.8
  TOP w0.076: v2(167.46,56.29) 167.95,55.8 167.95,54.77 168.08,54.65 168.08,54.62 168.25,54.46 168.48,54.46 168.73,54.2 168.73,53.47 170.81,51.38 171.31,51.38 172.64,50.05 172.64,49.55 173.36,48.84
  TOP w0.102: RL7.1 249.54,89.78 v2(249.55,89.76) ; 173.36,48.84 174.14,48.06 v1(174.14,47.42) RC92.2
  IN1 w0.089: v2(167.46,56.29) 167.87,55.89 167.87,54.7 168.1,54.47 169.2,54.47 169.63,54.04 171.26,54.04 172.07,54.85 172.6,54.85 173.11,55.35 173.95,55.35 175.88,57.28 180.14,57.28 182.95,54.47 182.95,54.47 183.28,54.14 184.71,54.14 185.46,54.89 187.97,54.89 188.85,54.01 191.92,54.01 193.42,52.52 194,52.52 197.16,49.35 200.63,49.35 202.56,47.42 203.69,47.42 207.64,43.47 215.64,43.47 216.18,42.94 224.79,42.94 225.03,42.7 229.73,42.7 229.87,42.84 232.72,42.84 241.17,51.28 252.7,51.28 253.15,50.84 v2(255.9,50.84)
  BOTTOM w0.081: UC1.AM7 167.25,56.08 v2(167.46,56.29)
  BOTTOM w0.102: v2(249.55,89.76) 249.17,89.76 246.76,87.35 246.76,84.78 245.7,83.73 245.7,78.92 246.53,78.09 251.4,78.09 254.36,75.13 258.38,75.13 259.9,73.61 259.9,66.23 257.35,63.68 257.35,56.5 256.27,55.42 256.27,51.21 v2(255.9,50.84)
PM_TEST_RST: length 4.9
  TOP w0.076: RC300.2 165.17,62.84 CC100.2 165.68,62.14 166.38,61.44 v1(167.43,61.44) 167.9,61.44 v2(168.34,61)
  BOTTOM w0.076: UC1.AC4 v2(168.34,61)
POA_WAKE#: length 6.2
  TOP w0.102: RPE5.3 264.27,50.32 264.74,49.84 v1(264.74,49.3) 264.74,47.23 263.97,46.46 UE2.B68
POWER_SW#_MB: length 98.5
  TOP w0.102: v2(299.59,25.31) 299.72,25.19 JAPS1.11 ; RE33.2 267.71,51.7 CE10.1 267.71,53.14 267.6,53.25 v3(267.6,53.9) 267.64,53.94 v2(268.25,53.94) ; SW3.4 SW3.2 291.29,82.1 290.83,81.64 v2(290.07,81.64)
  IN1 w0.089: v2(268.25,53.94) 271.15,53.94 284.54,40.55 291.65,40.55 298.26,33.95 298.26,26.64 299.59,25.31 v2(299.59,25.31)
  BOTTOM w0.102: v2(290.07,81.64) 288.29,79.86 285.18,79.86 281.24,75.92 281.24,73.27 269.24,61.27 269.24,57.78 268.25,56.79 v2(268.25,53.94)
POWER_SW_IN#: length 10.4
  TOP w0.102: v2(262.71,45.99) 262.88,45.99 262.9,45.96 UE2.B67 ; v2(265.08,50.1) 265.75,50.77 CE12.1 RE33.1 RE31.2
  BOTTOM w0.102: v2(262.71,45.99) 263.92,45.99 v1(264.22,46.28) 264.22,46.53 264.63,46.94 264.63,49.65 v2(265.08,50.1)
PROC_OPI_RCOMP: length 4.4
  BOTTOM w0.152: 162.49,50.08 162.49,50.39 162.16,50.72 UC1.AY15
  BOTTOM w0.381: RC187.1 v1(163.32,48.18) 163.32,48.68 162.49,49.5 162.49,50.08
PROCHOT_GATE: length 6.7
  TOP w0.102: UE1.A50 260.61,62.26 260.91,61.96 261.37,61.96 261.68,62.26 264.65,62.26 RE83.2 265.1,61.89 v1(266.15,62.94)
PS8338_AUX: length 28
  TOP w0.102: v2(221.09,71.91) 221.34,71.67 221.59,71.67 221.59,71.66 221.62,71.69 UV600.24 ; v2(233.26,85.66) 233.07,85.47 232.86,85.47 232.41,85.02 232.37,85.02 RV514.2 231.74,84.95 231.48,84.95 230.91,84.38 230.8,84.38 230.71,84.48 UV7.55
  IN4 w0.089: v2(221.09,71.91) 221.35,71.66 221.59,71.66 221.77,71.84 221.77,74.39 223.25,75.87 228.65,75.87 232.33,79.55 232.33,85.12 232.63,85.42 233.02,85.42 v2(233.26,85.66)
PS8338_AUX#: length 27.9
  TOP w0.102: v2(233.26,85.07) 233.07,85.26 232.95,85.26 232.5,84.81 232.46,84.81 RV515.2 231.76,84.75 231.57,84.75 231,84.17 230.8,84.17 230.71,84.08 UV7.54 ; UV600.25 221.67,71.29 221.57,71.39 221.5,71.46 221.25,71.46 221.25,71.46 221.23,71.46 v2(221.09,71.33)
  IN4 w0.089: v2(233.26,85.07) 233.08,85.25 232.7,85.25 232.5,85.05 232.5,79.48 228.72,75.7 223.32,75.7 221.94,74.32 221.94,71.77 221.66,71.49 221.25,71.49 v2(221.09,71.33)
PS8338_CFG0: length 3.9
  TOP w0.102: UV600.59 231.65,72.49 232.72,73.57 v1(233.56,73.57) RV601.2
PS8338_HPD: length 8.4
  TOP w0.102: v2(229.8,74.46) 229.63,74.28 UV600.3 ; v2(225.31,77.88) 225.22,77.97 UV7.32
  IN1 w0.089: v2(225.31,77.88) 226.88,76.3 227.99,76.3 229.8,74.48 v2(229.8,74.46)
  BOTTOM w0.102: v2(229.8,74.46) v1(230.4,74.46)
PS8338_N0: length 2.8
  TOP w0.102: UV7.39 228.02,78.33 228.11,78.24 228.11,77.72 228.6,77.24 228.9,77.24 229,77.14 229,77.04 CV607.1
PS8338_N0_C: length 2.7
  TOP w0.102: CV607.2 229,75.44 229,75.4 v4(228.48,74.88) 228.24,74.64 228.12,74.52 228.12,74.16 228.03,74.07 UV600.7
PS8338_N1: length 2.4
  TOP w0.102: UV7.36 226.82,78.28 226.93,78.16 226.93,77.51 227.22,77.22 227.22,77.04 CV609.1
PS8338_N1_C: length 2.5
  TOP w0.102: CV609.2 227.22,75.44 227.22,75.18 226.92,74.89 226.92,74.16 226.83,74.07 UV600.10
PS8338_N2: length 2.4
  TOP w0.102: UV7.33 225.62,78.31 225.71,78.21 225.71,77.61 225.45,77.34 225.45,77.04 CV611.1
PS8338_N2_C: length 2.5
  TOP w0.102: UV600.13 225.63,74.09 225.72,74.19 225.72,74.27 225.45,74.55 v4(225.45,74.75) 225.45,75.44 CV611.2
PS8338_N3: length 2.8
  TOP w0.102: CV613.1 223.67,77.04 223.67,77.35 223.94,77.62 224.29,77.62 224.51,77.84 224.51,78.21 224.42,78.31 UV7.30
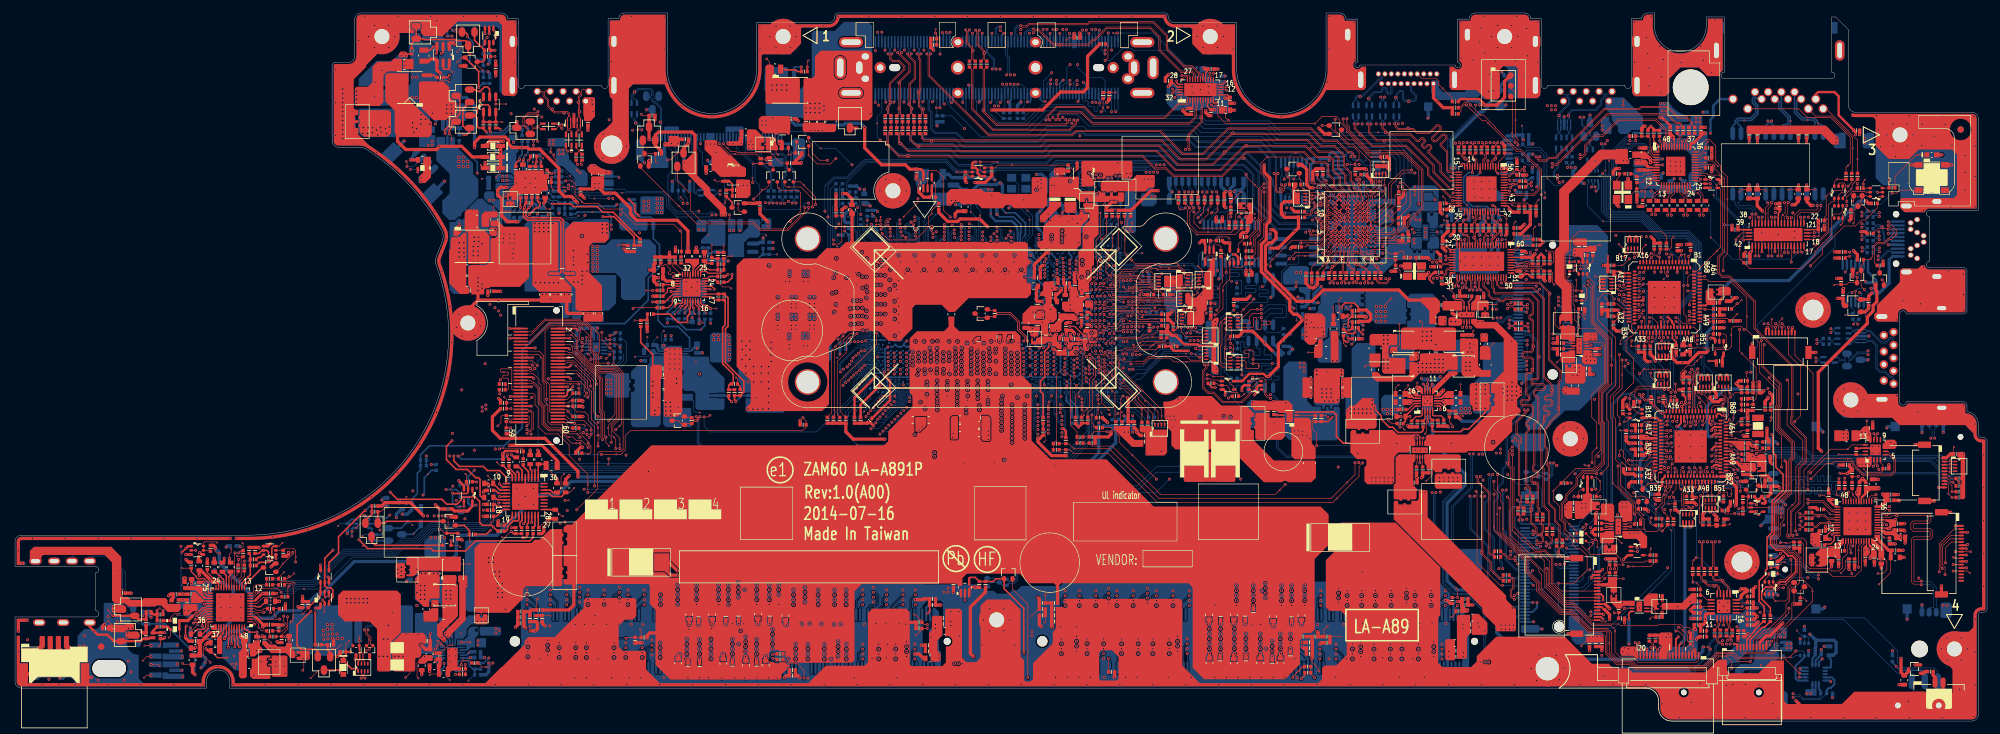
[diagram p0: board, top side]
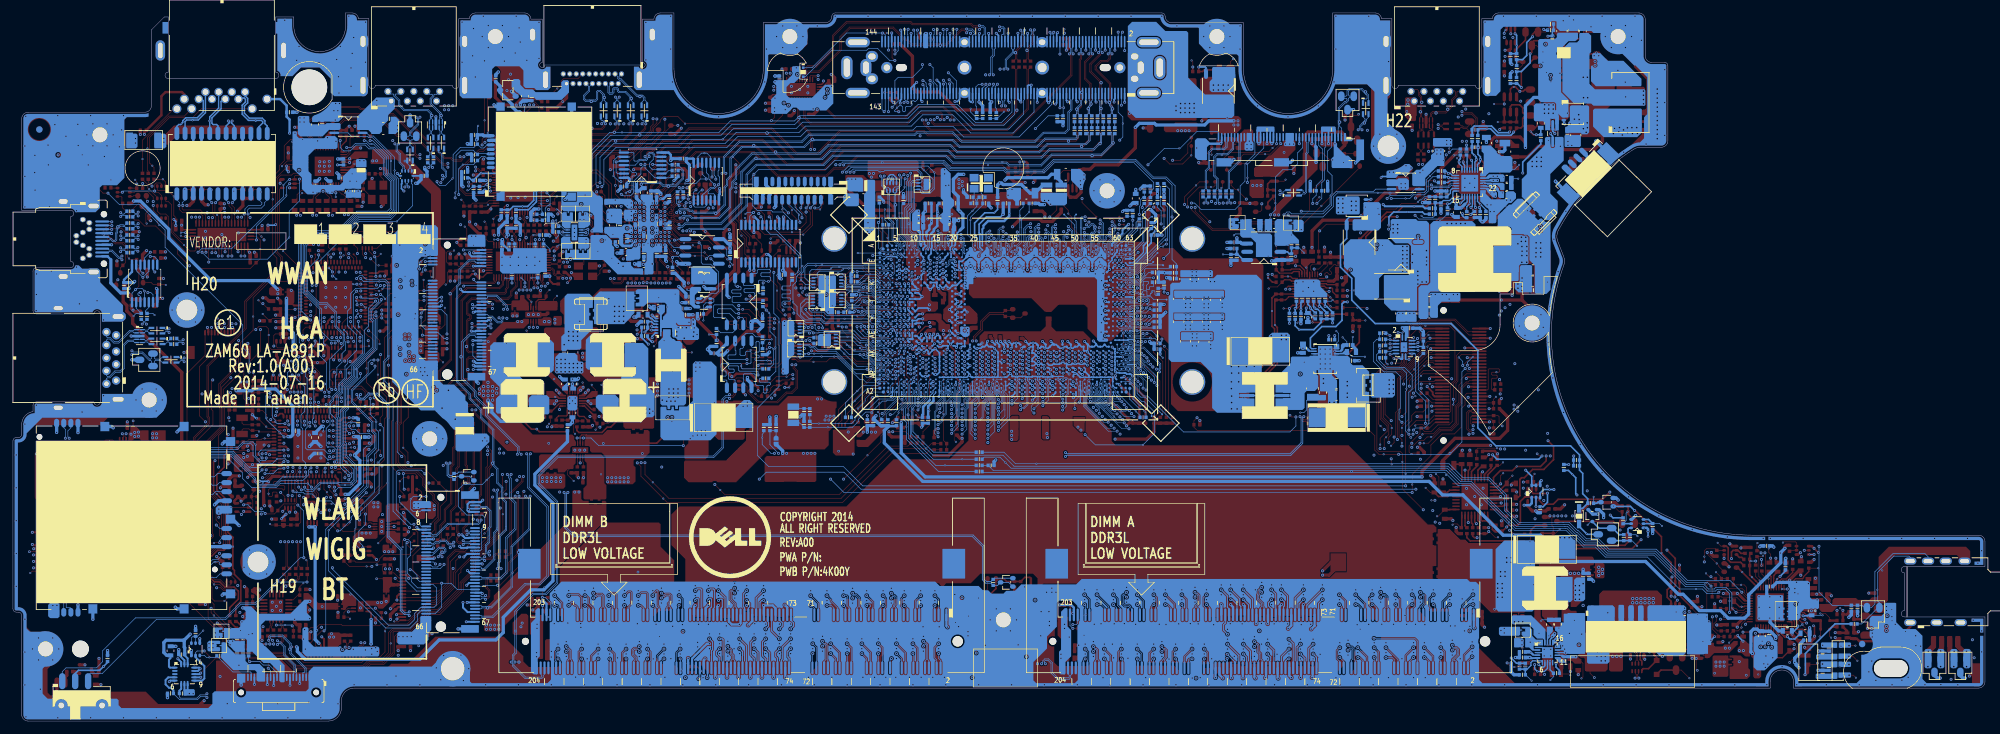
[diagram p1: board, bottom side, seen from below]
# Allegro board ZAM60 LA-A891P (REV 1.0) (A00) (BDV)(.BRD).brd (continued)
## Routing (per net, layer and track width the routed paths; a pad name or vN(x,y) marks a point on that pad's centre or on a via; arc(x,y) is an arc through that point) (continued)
PS8338_N3_C: length 3
  TOP w0.102: UV600.16 224.43,74.02 224.52,74.11 224.52,74.81 224.32,75.01 223.88,75.01 223.67,75.22 223.67,75.44 CV613.2
PS8338_P0: length 2.8
  TOP w0.102: CV606.1 229.21,77.04 229.21,77.22 228.99,77.44 228.69,77.44 228.32,77.81 228.32,78.24 228.42,78.33 UV7.40
PS8338_P0_C: length 2.8
  TOP w0.102: CV606.2 229.21,75.44 229.21,75.31 228.86,74.97 228.86,74.93 228.43,74.5 228.4,74.5 228.33,74.43 228.33,74.16 228.43,74.07 UV600.6
PS8338_P1: length 2.4
  TOP w0.102: CV608.1 227.43,77.04 227.43,77.3 227.14,77.59 227.14,78.23 227.22,78.3 UV7.37
PS8338_P1_C: length 2.5
  TOP w0.102: CV608.2 227.73,75.78 227.43,75.48 227.43,75.1 227.13,74.8 227.13,74.16 227.23,74.07 UV600.9
PS8338_P2: length 2.4
  TOP w0.102: CV610.1 225.65,77.04 225.65,77.26 225.92,77.53 225.92,78.21 226.02,78.31 UV7.34
PS8338_P2_C: length 2.5
  TOP w0.102: CV610.2 225.65,75.44 225.65,75.06 225.67,75.04 225.67,74.61 225.93,74.36 225.93,74.19 226.03,74.09 UV600.12
PS8338_P3: length 2.8
  TOP w0.102: CV612.1 223.88,77.04 223.88,77.27 224.02,77.41 224.38,77.41 224.72,77.75 224.72,78.21 224.82,78.31 UV7.31
PS8338_P3_C: length 3
  TOP w0.102: UV600.15 224.83,74.01 224.73,74.11 224.73,74.89 224.41,75.22 223.96,75.22 223.88,75.31 223.88,75.44 CV612.2
PS8338_SW: length 2.7
  TOP w0.102: UV600.18 223.63,74.22 v2(223.39,74.46)
  BOTTOM w0.102: v1(224.34,75.16) RV602.2 223.34,74.51 v2(223.39,74.46)
PS8338B_P0: length 6.3
  TOP w0.102: UV600.60 231.58,72.89 233.14,74.46 RV615.2 234.62,76.14 v1(234.93,76.45)
PS8338B_P1: length 4.7
  TOP w0.102: UV600.1 230.43,74.01 230.57,74.14 231.26,74.14 231.63,74.51 RV603.2 RV100.1 231.63,76.99 v1(231.87,77.23)
PS8338B_PC10: length 4.7
  TOP w0.102: UV600.56 231.76,71.29 232.26,70.8 v1(232.7,70.8) 233.02,70.8 233.25,71.03 233.91,71.03 234.24,70.7 RV614.2 RV620.1
PS8338B_PC11: length 10.3
  TOP w0.102: v1(236.59,72.77) 236.69,72.67 237.55,72.67 237.77,72.45 237.77,71.02 237.45,70.7 RV613.2 RV619.1 235.85,70.27 234.12,70.27 234.02,70.37 234.02,70.56 233.8,70.78 233.45,70.78 233.14,70.47 232.49,70.47 232.4,70.56 232.15,70.56 231.82,70.89 UV600.55
PS8338B_PC20: length 9
  TOP w0.102: v1(237.88,67.49) 237.63,67.74 237.63,69.35 237.4,69.58 RV612.2 RV618.1 235.82,70.04 234.02,70.04 233.91,69.93 233.46,69.93 233.14,70.24 232.39,70.24 232.31,70.33 231.96,70.33 231.8,70.49 UV600.54
PS8338B_PC21: length 4.5
  TOP w0.102: RV617.1 RV611.2 v1(233.59,69.58) 233.47,69.58 233.04,70.01 232.28,70.01 232.2,70.09 UV600.53
PS8338B_PEQ: length 3.2
  TOP w0.102: UV600.8 v2(227.63,74.45)
  BOTTOM w0.102: v1(227.63,75.01) v2(227.63,74.45) 227.2,74.02 RV616.1 RV610.2
PS8339B_DP_CFG0: length 3.4
  TOP w0.102: UV7.44 231.11,80.08 v1(231.34,79.84) 231.56,79.62 RV52.1 RV51.2
PS8339B_DP_CFG1: length 4.8
  TOP w0.102: v1(220.46,76.69) RV61.1 RV54.2 222.37,76.97 223.64,78.24 223.87,78.24 224.02,78.39 UV7.29
PS8339B_IN_CA_DET: length 10
  TOP w0.203: UV7.11 v2(225.22,84.81)
  BOTTOM w0.254: RV68.2 225.09,79.07 v1(224.4,79.76) 223.86,80.3 223.86,84.07 224.6,84.81 v2(225.22,84.81)
PS8339B_INPUT_EQ: length 12.4
  TOP w0.203: UV7.8 v2(226.42,84.82)
  BOTTOM w0.254: v2(226.42,84.82) 225.89,84.29 224.76,84.29 224.27,83.79 224.27,80.52 225.21,79.58 v1(226.01,79.58) 227.45,79.58 227.98,79.06 RV58.2 RV65.1
PS8339B_MODE: length 5.1
  TOP w0.102: v2(230.99,83.63) 230.94,83.68 UV7.53
  BOTTOM w0.102: v2(230.99,83.63) 231.94,82.68 RV63.1 RV57.2 233.72,82.68 234.31,82.08 v1(234.53,82.08)
PS8339B_MODE_SW: length 6.5
  TOP w0.102: UV7.45 231.18,80.48 231.56,80.1 233.7,80.1 RV511.2 RV510.1 235.06,80.22 v1(235.46,80.62)
PS8339B_OUT_CA_DET: length 3
  TOP w0.102: UV7.42 229.22,78.29 229.35,78.16 230.02,78.16 v1(230.5,77.67) RV67.2
PS8339B_TMDS_DDCBUF: length 7.2
  TOP w0.203: v2(229.17,84.7) 228.82,85.05 UV7.2
  BOTTOM w0.254: RV60.2 234.21,84 233.82,83.6 RV66.1 233.55,83.65 232.51,84.7 v1(232.41,84.7) v2(229.17,84.7)
PS8339B_TMDS_PRE: length 6.7
  TOP w0.102: UV7.20 v2(222.23,82.88)
  BOTTOM w0.102: RV64.1 RV56.2 222.93,78.76 223.02,78.85 223.02,79.87 v1(223.12,79.97) 223.12,81.99 v2(222.23,82.88)
PS8339B_TMDS_RT: length 6.9
  TOP w0.102: UV7.23 v2(222.23,81.68)
  BOTTOM w0.102: RV62.1 RV55.2 222.82,77.44 222.49,77.77 222.49,79.31 222.04,79.76 v1(221.85,79.76) 221.74,79.87 221.74,81.18 v2(222.23,81.68)
PS_ID: length 265.7
  TOP w0.102: v2(255.9,44.04) 255.32,43.46 UE2.B24 ; v2(83.25,87.56) 83.25,87.12 v1(83.7,86.66) ; v2(72.96,105.7) 72.63,105.37 PU1.4
  IN1 w0.089: v2(72.96,105.7) 73.59,105.07 73.59,96.88 74.74,95.73 74.74,93.62 79.87,88.49 81.31,88.49 82.25,87.56 v2(83.25,87.56)
  IN2 w0.122: v2(83.25,87.56) 83.25,87.28 93.08,77.44 100.67,77.44 100.8,77.57 103.06,77.57 104.84,79.35 114.25,79.35 114.83,79.93 114.83,80.9 115.52,81.58 121.3,81.58 124.08,84.37 124.08,86.4 126.55,88.87 146.56,88.87 147.83,90.14 156.33,90.14 157.41,91.22 182.31,91.22 183.13,90.4 204.02,90.4 204.75,91.12 219.89,91.12 222.29,93.52 233.6,93.52 238.82,88.3 238.82,85.29 240.69,83.42 240.69,80.14 245.17,75.67 254.62,75.67 255.51,74.78 258.76,74.78 262.91,70.62 262.91,66.4 262.06,65.55 262.06,65.2 263.22,64.05 263.22,55.95 262.49,55.23 262.49,54.61 262.65,54.46 262.65,53.07 260.99,51.42 259.95,51.42 259.7,51.17 259.7,48.18 258.64,47.12 258.16,47.12 257.61,46.57 257.61,45.28 256.37,44.04 v2(255.9,44.04)
PS_USBP1_D+: length 22.3
  TOP w0.102: UI3.10 287.76,43.82 287.64,43.95 287.64,44.22 v2(287.84,44.43)
  IN4 w0.089: v2(287.84,44.43) 287.84,45.2 287.21,45.83 280.97,45.83 279.69,47.11 279.69,55.56 279.21,56.04 278.4,56.04 v2(278.29,56.15)
  BOTTOM w0.102: v2(278.29,56.15) 278.48,55.97 278.79,55.97 279.11,56.29 LI7.1
PS_USBP1_D-: length 22.3
  TOP w0.102: UI3.11 287.26,43.82 287.43,43.99 287.43,44.26 v2(287.26,44.43)
  IN4 w0.089: v2(287.26,44.43) 287.67,44.84 287.67,45.13 287.14,45.66 280.9,45.66 279.52,47.03 279.52,55.49 279.14,55.87 278.6,55.87 v2(278.29,55.57)
  BOTTOM w0.102: v2(278.29,55.57) 278.48,55.76 278.78,55.76 279.1,55.44 LI7.4
PSID_DISABLE#: length 229
  TOP w0.102: PR13.2 v2(74.17,102.78) ; v2(253,59.29) 253.12,59.41 UE1.A37
  IN1 w0.089: v2(74.17,102.78) 74.17,102.77 73.85,102.45 73.85,96.94 74.99,95.8 74.99,93.68 79.01,89.65 v2(80.12,89.65)
  IN2 w0.122: v2(80.12,89.65) 81.21,88.56 81.21,88.26 93.1,76.37 101.04,76.37 101.22,76.56 103.82,76.56 104.77,77.51 114.27,77.51 115.62,78.85 120.88,78.85 122.21,80.19 122.21,80.97 128.58,87.35 147.25,87.35 148.52,88.62 175.11,88.62 175.88,89.38 181.86,89.38 182.62,88.62 204.53,88.62 205.51,89.6 220.72,89.6 223.07,91.95 233.01,91.95 236.34,88.61 236.34,83.73 238.24,81.83 238.24,80.31 247.77,70.78 251.58,70.78 252.68,69.68 252.68,63.48 253.27,62.89 253.27,60.93 253,60.66 v2(253,59.29)
  BOTTOM w0.102: v1(253.6,60.5) 253,59.9 v2(253,59.29)
PWM1: length 12.7
  TOP w0.203: v2(101.36,66.43) PU500.6
  IN1 w0.254: v2(101.36,66.43) 101.36,65.42 100,64.05 100,58.31 v2(100.22,58.08)
  BOTTOM w0.102: v2(100.22,58.08) 100.22,58.43 99.88,58.78 99.88,59.94 v1(100.24,60.3)
PWR_SRC_ON: length 5.9
  TOP w0.102: v1(108.09,83.72) 108.33,83.48 QV1.3
  TOP w0.254: CV11.2 109.97,82.14 RV5.1 ; CV11.2 110.86,83.04 110.42,83.48 QV1.3 ; CV11.2 RV4.2
RED_DOCK: length 90.7
  TOP w0.102: UV8.M6 211.21,75.89 211.88,76.56 212.43,76.56 213.71,77.83 RV76.1 215.59,79.65 215.59,82.27 214.61,83.25 v2(214.04,83.25)
  BOTTOM w0.102: v2(214.04,83.25) 214.04,87.17 211.89,89.32 194.69,89.32 193,91.01 v1(188.27,91.01) 183.27,91.01 182.29,91.99 165.92,91.99 164.17,93.75 159.54,93.75 156.73,90.93 150.2,90.93 146.95,94.18 JDOCK1.53
REGCTL_PNP10:
  vias: v1(251.98,86.16) v2(250.5,86.65) v2(251.14,86.65)
REM_DIODE1_N: length 130.3
  TOP w0.127: v2(256.79,46.35) 256.94,46.5 UE2.B13 ; v2(156.46,58.78) 156.31,58.93 156.31,59.45 155.19,60.57 155.19,61.82 153.87,63.15 151.73,63.15 CE35.1 150.44,63.48 QE3.3 ; v2(256.35,48.93) 256.35,49 255.89,49.45 CE24.1 255.89,50.19 v2(255.9,50.2)
  IN1 w0.127: v2(256.35,48.93) 256.79,48.49 v2(256.79,46.35) ; v2(255.9,50.2) 256.07,50.04 256.07,49.86 255.92,49.71 255.09,49.71 253.36,47.98 239.9,47.98 231.93,40.01 218.96,40.01 218.45,39.5 216.12,39.5 214.46,41.16 205.65,41.16 199.7,47.11 192.27,47.11 190.2,49.19 189.29,49.19 187.37,51.1 182.29,51.1 180.53,49.35 171.53,49.35 169.78,51.1 165.93,51.1 164.25,52.78 163.56,52.78 163.03,53.31 163.03,56.57 162.54,57.05 162.08,57.05 160.14,58.98 159.42,58.98 158.99,58.55 156.68,58.55 v2(156.46,58.78)
REM_DIODE1_P: length 130.6
  TOP w0.127: v2(256.49,50.2) 256.8,49.89 CE24.2 256.8,48.67 256.69,48.55 UE2.A13 ; QE3.1 149,62.37 QE3.2 150.44,62.56 CE35.2 151.73,62.89 153.76,62.89 154.94,61.72 154.94,60.46 156.06,59.34 156.06,58.94 v2(155.89,58.78)
  IN1 w0.127: v2(256.49,50.2) 256.32,50.04 256.32,49.75 256.02,49.45 255.2,49.45 253.47,47.73 240.01,47.73 232.03,39.75 219.06,39.75 218.56,39.25 216.01,39.25 214.35,40.91 205.54,40.91 199.6,46.86 192.17,46.86 190.09,48.93 189.19,48.93 187.27,50.85 182.39,50.85 180.64,49.09 171.42,49.09 169.67,50.85 165.83,50.85 164.14,52.53 163.46,52.53 162.77,53.21 162.77,56.46 162.44,56.79 161.97,56.79 160.04,58.73 159.53,58.73 159.1,58.3 156.37,58.3 v2(155.89,58.78)
REM_DIODE2_N: length 139.1
  TOP w0.127: v2(255.12,48.69) 254.75,49.06 CE26.1 254.65,49.4 v2(253.98,49.4) ; UE2.B14 256.44,46.62 v2(256.15,46.34)
  IN1 w0.127: v2(256.15,46.34) 256.15,47.65 v2(255.12,48.69) ; v2(237.8,39.91) 237.64,39.75 237.64,38.67 236.61,37.64 232.77,37.64 231.34,36.2 225.14,36.2 223.52,34.59 219.5,34.59 219.19,34.91 219.19,35.16 v2(219,35.35)
  IN4 w0.127: v2(237.8,39.91) 237.61,40.09 237.61,45.53 238.93,46.84 247.42,46.84 248.12,47.54 251.26,47.54 253.29,49.57 253.82,49.57 v2(253.98,49.4)
  BOTTOM w0.127: QE5.3 153.08,22.09 CE37.2 153.6,21.57 154.31,21.57 154.68,21.95 154.68,27.09 156.37,28.77 218.02,28.77 219.19,29.93 219.19,35.16 v2(219,35.35) ; v2(237.8,39.91) 237.65,39.76 237.65,38.01 237.35,37.7 236.91,37.7 CE46.2 236.1,37.85 QE7.1 234.17,37.85 QE7.2
REM_DIODE2_P: length 137.2
  TOP w0.127: UE2.A14 256.19,48.22 255.23,49.17 255.23,49.73 CE26.2 254.52,49.99 v2(253.98,49.99)
  IN1 w0.127: v2(219.58,35.35) 219.44,35.21 219.44,35.01 219.61,34.84 223.42,34.84 225.03,36.46 231.23,36.46 232.67,37.89 236.5,37.89 237.38,38.77 237.38,39.73 v2(237.21,39.91)
  IN4 w0.127: v2(253.98,49.99) 253.82,49.82 253.18,49.82 251.16,47.8 248.02,47.8 247.31,47.09 238.82,47.09 237.36,45.63 237.36,40.05 v2(237.21,39.91)
  BOTTOM w0.127: v2(237.21,39.91) 237.4,39.72 237.4,38.11 237.24,37.95 236.91,37.95 CE46.1 236.08,38.28 235.86,38.5 QE7.3 ; QE5.2 150.88,21.44 QE5.1 152.58,20.99 CE37.1 153.6,21.32 154.42,21.32 154.94,21.84 154.94,26.98 156.47,28.52 218.13,28.52 219.44,29.83 219.44,35.21 219.5,35.27 219.5,35.28 v2(219.58,35.35)
REM_DIODE4_N: length 208.8
  TOP w0.127: UE2.A16 255,47.73 254.51,47.73 253.36,48.87 253.36,49.64 CE27.1 252.47,49.77 251.93,49.77 251.5,50.19 251.5,50.39 v2(251.62,50.5) ; v2(105.27,47.08) 105.43,46.91 105.43,46.71 105.29,46.57 104.93,46.57 CE39.1 103.63,46.91 QE6.3
  IN3 w0.127: v2(142.1,40.93) 142.26,41.09 163.45,41.09 187.97,16.58 189.59,16.58 190.59,15.58 202.03,15.58 204.9,12.71 221.47,12.71 222.21,11.98 223.41,11.98 224.18,11.21 230.76,11.21 231.26,11.72 241.58,11.72 242.63,12.77 242.63,15.98 243.12,16.47 243.34,16.47 v2(243.51,16.3)
  BOTTOM w0.127: v2(243.51,16.3) 243.69,16.49 244.26,16.49 244.89,17.12 244.89,26.45 246.9,28.46 246.9,48.84 248.5,50.44 249.69,50.44 250.47,49.67 251.14,49.67 251.45,49.98 251.45,50.34 v2(251.62,50.5) ; v2(105.27,47.08) 105.43,46.91 105.43,42.94 107.28,41.09 141.93,41.09 v2(142.1,40.93)
REM_DIODE4_P: length 210.4
  TOP w0.127: UE2.B17 254.94,47.36 254.82,47.47 254.4,47.47 253.11,48.76 253.11,48.98 CE27.2 252.58,49.51 251.83,49.51 251.25,50.09 251.25,50.28 v2(251.03,50.5) ; QE6.1 102.49,46.46 103.14,45.81 QE6.2 103.63,46 CE39.2 104.9,46.32 105.39,46.32 105.69,46.61 105.69,46.91 v2(105.85,47.08)
  IN3 w0.127: v2(142.1,41.51) 142.21,41.4 142.26,41.35 163.56,41.35 188.07,16.83 189.7,16.83 190.7,15.83 202.13,15.83 205,12.97 221.57,12.97 222.31,12.23 223.52,12.23 224.28,11.47 230.65,11.47 231.16,11.98 241.48,11.98 242.38,12.88 242.38,16.08 243.02,16.72 243.34,16.72 v2(243.51,16.89)
  BOTTOM w0.127: v2(251.03,50.5) 251.2,50.34 251.2,50.09 251.03,49.92 250.57,49.92 249.8,50.7 248.39,50.7 246.64,48.95 246.64,28.56 244.64,26.55 244.64,17.22 244.16,16.74 243.65,16.74 v2(243.51,16.89) ; v2(105.85,47.08) 105.69,46.91 105.69,43.04 107.39,41.35 141.93,41.35 v2(142.1,41.51)
RES_BIAS: length 5.2
  TOP w0.102: RL13.1 251.9,80.89 v1(251.9,81.81) 251.9,82.4 252.35,82.84 253.59,82.84 254.06,83.31 254.06,83.51 253.99,83.59 UL1.12
RESET_OUT#: length 186.7
  TOP w0.102: v2(256.3,34.6) 256.52,34.38 RE56.2 v1(255.51,33.59) ; v2(256.49,39.11) 256.58,39.11 256.93,38.76 256.93,38.15 256.94,38.15 UE2.B39 ; v2(144.52,77.95) 143.44,79.03 143.44,84.11 142.43,85.13 141.28,85.13 141.02,84.87 UC8.2
  IN1 w0.089: v2(256.49,39.11) 256.47,39.11 256.14,38.79 256.14,38.2 256.31,38.04 256.31,34.6 v2(256.3,34.6)
  IN3 w0.122: v2(256.3,34.6) 256.3,29.52 254.31,27.53 254.31,26.55 247.93,20.17 242.4,20.17 239.64,17.41 226.47,17.41 225.49,18.39 224.24,18.39 223.28,17.42 204.65,17.42 203.92,18.15 203.92,21.34 202.02,23.24 191.14,23.24 177.39,36.99 177.39,37.83 176.08,39.14 176.08,42.84 174.62,44.3 174.62,45 173.73,45.88 170.68,45.88 v2(169.17,47.39) 168.46,48.1 168.46,50.27 167.89,50.84 160.52,50.84 160.13,51.23 160.13,57.14 158.81,58.46 158.05,58.46 156.72,59.79 156.72,60.36 149.22,67.86 149.22,70.45 145.67,74 145.67,76.81 v2(144.52,77.95)
  BOTTOM w0.076: v2(169.17,47.39) 168.79,47.39 166.61,49.57 166.61,50.83 UC1.AY7
RING2:
  vias: v1(28.83,18.36)
RING2_R: length 8.3
  TOP w0.102: v1(14.36,15.52) v2(15.24,14.64)
  IN3 w1.27: 25.79,16.13 24.56,14.9 19.24,14.9
  vias: v2(15.24,14.01) v2(17.52,14.33) v2(18.16,14.33) v2(26.24,17.06) v2(26.82,17.06)
RSMRST#: length 7.2
  TOP w0.102: RZ22.2 267.89,34.37 267.69,34.16 267.69,33.03 UZ6.2 v1(271.05,33.03) ; RZ22.2 RZ51.2 ; RZ22.2 267.89,35.09 267.51,35.47 UZ5.3
RUN_ON: length 96.6
  TOP w0.102: QE2.2 250.84,47.54 249.54,48.84 v2(249.54,49.89) 249.54,50.44 v1(249.79,50.7) 250.89,51.79 253.81,51.79 253.87,51.85 RPE10.1 ; v2(216.58,43.77) 216.69,43.66 UZ9.5 ; v2(201.15,42.59) 201.15,44.45 200.49,45.11 200.49,46.66 200.95,47.12 RZ41.1 199.76,47.23 199.7,47.29 UZ7.3 ; UZ9.3 217.49,43.69 v2(217.57,43.77) ; v2(254.57,29.41) 255.41,30.25 RE280.2 RE279.2
  IN4 w0.089: v2(249.54,49.89) 249.36,49.89 248.79,49.31 248.17,49.31 246.57,47.71 235.87,47.71 232.57,44.41 218.21,44.41 v2(217.57,43.77)
  BOTTOM w0.102: v2(201.15,42.59) 214.23,42.59 215.41,43.77 v2(216.58,43.77) v2(217.57,43.77) ; v2(249.54,49.89) 249.54,47.45 248.65,46.56 248.65,45.11 248.23,44.69 248.23,41.92 248.87,41.29 248.87,35.43 251.74,32.56 251.74,32.3 252.41,31.62 252.41,31.19 254.19,29.41 v2(254.57,29.41)
RUN_ON#: length 3.6
  TOP w0.102: QE2.5 248.47,47.54 RE68.2 249.1,46.89 QE2.6 248.93,46.28 v1(248.6,46.28)
RUN_ON_EC: length 17.7
  TOP w0.102: v2(258.88,46.19) 258.94,46.24 UE2.B9 ; RE279.1 255.86,31.72 v2(255.86,32.61)
  IN1 w0.089: v2(258.88,46.19) 258.88,46.18 259.29,45.77 259.29,45.24 257.67,43.61 257.67,40.18 257.17,39.69 257.17,37.76 257.03,37.62 257.03,35.38 257.24,35.18 257.24,33.98 v2(255.86,32.61)
RUNPWROK: length 272.8
  TOP w0.102: UE2.B26 255.39,42.46 v2(255.93,43.01) ; v2(86.8,32.68) 90.04,35.92 v1(90.04,40.08) 90.04,41.38 90.36,41.69 93.66,41.69 93.98,42.01 93.98,53.89 92.45,55.41 92.45,57.18 v2(91.93,57.7) 90.7,58.94 v2(90.7,60.1) ; QE2.3 251.2,48.19 251.08,48.32 RE67.2 250.32,50.14 250.32,50.87 250.8,51.35 254.8,51.35 v2(254.88,51.26) ; UE1.A4 257.12,71.7 v2(257.51,72.09)
  IN1 w0.089: v2(255.93,43.01) 256.63,43.7 256.63,44.28 257.62,45.28 257.62,47.17 258.15,47.7 258.15,49.59 257.72,50.02 257.72,51.13 257.19,51.66 255.28,51.66 v2(254.88,51.26)
  IN2 w0.122: v2(254.88,51.26) 248.41,51.26 247.69,50.54 242.51,50.54 236.22,44.25 236.22,37.12 232.3,33.2 230.42,33.2 229.72,32.49 86.98,32.49 v2(86.8,32.68)
  IN3 w0.122: v2(87.69,59.16) 87.57,59.16 87.12,58.71 87.12,57.63 87.42,57.33 v2(87.61,57.33)
  IN4 w0.122: v2(90.7,60.1) 89.77,59.16 v2(87.69,59.16)
  BOTTOM w0.102: v2(87.69,59.16) 88.02,58.83 UC7.13 ; UC7.10 v2(87.61,57.33) ; v2(257.51,72.09) 257.51,71.6 259.22,69.9 259.22,66.51 257.39,64.69 256.2,64.69 254.78,63.27 254.78,61.1 253.49,59.81 253.49,58.76 253.38,58.66 253.38,57.35 253.89,56.83 253.89,55.49 254.7,54.69 254.7,53.58 254.88,53.39 v2(254.88,51.26) ; v2(90.7,60.1) 90.26,60.1 90.03,59.87 UC7.1 ; v2(91.93,57.7) 91.8,57.83 UC7.4
S5_1.35V: length 5.4
  TOP w0.102: PR207.2 69.61,7.24 PC215.1 69.59,8.11 v2(69.59,8.74)
  BOTTOM w0.203: PU200.8 67.61,8.14 68.08,7.67 v1(69.17,7.67) 69.59,8.09 v2(69.59,8.74)
SATA2_PCIE6_L1: length 192.5
  TOP w0.081: 173.36,64.47 173.35,64.46 171.97,64.46 171.55,64.05 168.82,64.05 168.65,64.21 168.05,64.21 v2(167.67,63.84)
  TOP w0.102: v2(272.98,39.28) 272.98,44.16 272.07,45.08 272.07,48.7 272.25,48.88 272.25,51.28 269.62,53.91 269.62,58.46 267.63,60.45 v1(267.63,62.56) 267.63,65.46 265.11,67.98 261.74,67.98 261.46,68.26 UE1.A62 ; 173.36,64.47 173.47,64.47 173.8,64.79 179.53,64.79 179.75,64.57 RPC9.8
  IN3 w0.081: 173.36,57.77 172.7,57.77 172.4,58.07 172.4,58.74 172.09,59.05 171.08,59.05 170.21,59.93 170.21,61.57 169.62,62.15 169.13,62.15 168.67,62.61 168.67,63.13 168.51,63.29 168.22,63.29 v2(167.67,63.84)
  IN3 w0.122: v2(272.98,39.28) 272.46,38.75 267.16,38.75 266.65,39.26 264.1,39.26 263.72,39.64 261.7,39.64 261.12,40.22 255.84,40.22 255.25,39.63 253.65,39.63 251.71,37.69 251.71,35.03 249.36,32.68 247.39,32.68 245.09,30.37 243.32,30.37 242.88,29.93 242.88,28.14 242.43,27.69 242.43,26.63 239.46,23.66 237.74,23.66 237.11,24.29 233.99,24.29 233,23.3 231.9,23.3 230.35,24.85 206.96,24.85 203.81,28 195.63,28 183.26,40.36 183.26,41.94 180.93,44.28 180.93,48.06 179.64,49.35 176.55,49.35 174.69,51.21 174.69,57 173.92,57.77 173.36,57.77
  BOTTOM w0.081: v2(167.67,63.84) 167.5,63.66 UC1.V6
SATA_ACT#: length 179.5
  TOP w0.102: QZ3.4 270.4,19.9 270.92,20.42 272.12,20.42 272.82,21.12 v1(273.66,21.12) 275.49,22.95 275.49,25.12 274.76,25.84 274.12,25.84 273.24,26.72 272.29,26.72 271.63,27.39 271.63,28.27 272.26,28.9 272.26,33.58 274.08,35.39 274.08,40.37 274.49,40.78 274.49,42.98 272.3,45.17 272.3,48.61 272.49,48.8 272.49,51.65 271.08,53.06 v2(271.08,53.1)
  IN3 w0.122: v2(271.08,53.1) 268.09,53.1 266.98,54.2 263.08,54.2 262.41,54.87 257.08,54.87 255.39,53.18 249.37,53.18 243.96,47.78 243.96,42.9 242.12,41.06 236.15,41.06 231.26,36.17 229.72,36.17 229.45,35.91 228.76,35.91 228.15,35.31 228.15,35.21 227.05,34.11 210.95,34.11 208.6,36.46 200.25,36.46 194.86,41.86 194.86,47.17 194.6,47.43 194.6,48.68 194.46,48.83 193.59,49.69 193.59,51.82 194.08,52.3 194.08,53.78 193.53,54.32 193.53,56.26 190.27,59.51 190.27,62.56 187.39,65.44 174.43,65.44 173.83,64.84 v2(173.21,64.84)
  BOTTOM w0.076: v2(173.21,64.84) 172.86,64.49 172.54,64.49 171.95,63.89 171.07,63.89 170.93,63.75 169.73,63.75 UC1.U3
SATA_COMP: length 8.3
  BOTTOM w0.127: 163.57,74.97 163.57,74.54 163.35,74.31 163.35,73.28 163.67,72.96 UC1.C12
  BOTTOM w0.381: 163.57,74.97 163.57,75.6 163.13,76.05 163.13,76.62 162.8,76.95 v1(162.8,77.24) 162.8,79.98 RC17.1
SATA_LED: length 16
  TOP w0.102: QZ4.3 274.93,18.53 274.58,18.19 274.58,15.86 271.87,13.14 v1(271.87,12.8) 271.87,10.92 271.59,10.64 267.4,10.64 267.15,10.89 JLED1.3
SATA_LED#: length 6.3
  TOP w0.102: QZ3.6 271.7,18.92 v1(272.06,18.57) 273.61,18.57 273.99,18.95 273.99,20.67 274.75,21.43 QZ4.2
SATA_PRX_DKTX_N0: length 7.4
  TOP w0.102: C313.2 148.04,102.38 v4(148.04,103.71) 148.04,104.08 147.24,104.88 147.24,106.63 v2(147.49,106.88)
  BOTTOM w0.102: v2(147.49,106.88) 147.31,106.69 147.31,106.25 147.45,106.1 JDOCK1.56
SATA_PRX_DKTX_N0_C: length 53.4
  TOP w0.102: C313.1 148.04,100.78 148.04,94.68 151.21,91.52 162.96,91.52 163.82,92.38 163.82,92.76 v2(163.63,92.95)
  IN3 w0.112: v2(167.74,68.57) 167.74,68.66 167.18,69.22 167.18,70.25 166.86,70.57 166.86,72.66 162.67,76.85 162.67,80.79 161.31,82.15 161.31,89.59 163.82,92.1 163.82,92.76 v2(163.63,92.95)
  BOTTOM w0.081: v2(167.74,68.57) 168.02,68.29 UC1.J5
SATA_PRX_DKTX_P0: length 7.3
  TOP w0.102: C312.2 147.83,102.38 147.83,103.41 147.81,103.43 147.81,104.02 147.03,104.8 147.03,106.76 v2(146.91,106.88)
  BOTTOM w0.102: JDOCK1.54 146.95,106.1 147.1,106.25 147.1,106.69 v2(146.91,106.88)
SATA_PRX_DKTX_P0_C: length 53.5
  TOP w0.102: C312.1 147.83,100.78 147.83,94.6 151.12,91.31 163.05,91.31 164.03,92.29 164.03,92.76 v2(164.22,92.95)
  IN3 w0.112: v2(164.22,92.95) 164.03,92.75 164.03,92.01 161.51,89.5 161.51,82.24 162.87,80.87 162.87,76.94 167.07,72.75 167.07,70.65 167.39,70.33 167.39,69.32 167.49,69.22 v2(167.72,69.22)
  BOTTOM w0.081: UC1.H5 168,68.94 v2(167.72,69.22)
SATA_PRX_DTX_N1: length 127.3
  TOP w0.102: v2(260.9,27.73) 260.79,27.62 260.79,23.86 CN25.1
  IN4 w0.089: v2(260.9,27.73) 260.79,27.62 260.79,27.22 260.59,27.01 254.81,27.01 253.37,28.45 246.05,28.45 243.45,31.04 239.34,31.04 236.31,34.07 233.12,34.07 232.55,34.65 231.76,34.65 231.19,34.07 230.2,34.07 230.07,34.21 227.95,34.21 227.24,33.49 204,33.49 194.58,42.92 194.58,45.25 192.61,47.22 192.61,48.53 190.69,50.45 190.69,51.53 188.96,53.25 188.96,62.1 186.11,64.95 178.49,64.95 175.95,67.49 171.47,67.49 171.46,67.5 171.16,67.5 171.15,67.49 170.69,67.49 170.17,68.01 166.61,68.01 166.21,68.41 166.21,68.85 166.13,68.94 165.92,68.94 v2(165.8,68.82)
  BOTTOM w0.081: v2(165.8,68.82) 166.28,68.34 UC1.J8
SATA_PRX_DTX_N1_C: length 5.1
  TOP w0.102: CN25.2 260.72,22.34 260.72,22.05 v4(261.16,21.61) 261.71,21.06 262.28,21.06 262.3,21.08 262.89,21.08 262.91,21.06 263.05,21.06 263.4,20.72 263.4,20.46 263.4,20.34 263.54,20.2 UN2.4
SATA_PRX_DTX_N1_RP: length 2
  TOP w0.102: UN2.12 263.54,15.23 263.4,15.09 263.4,14.76 263.21,14.58 263.21,14.4 CN18.2
SATA_PRX_DTX_N1_RP_C: length 8.8
  TOP w0.102: CN18.1 263.19,12.82 263.19,12.36 263.32,12.24 263.69,12.24 v2(263.88,12.43)
  BOTTOM w0.102: v2(263.88,12.43) 263.69,12.24 263.39,12.24 262.68,11.53 262.68,10.25 261.12,8.68 261.12,7.56 260.94,7.38 JSATA1.5
SATA_PRX_DTX_P1: length 127.3
  TOP w0.102: CN26.1 260.58,24.01 260.58,27.47 v2(260.32,27.73)
  IN4 w0.089: v2(260.32,27.73) 260.62,27.43 260.62,27.29 260.52,27.18 254.88,27.18 253.44,28.62 246.12,28.62 243.52,31.22 239.41,31.22 236.38,34.25 233.19,34.25 232.62,34.82 231.69,34.82 231.12,34.25 230.27,34.25 230.14,34.38 227.88,34.38 227.17,33.66 204.07,33.66 194.75,42.99 194.75,45.32 192.78,47.29 192.78,48.6 190.86,50.52 190.86,51.6 189.13,53.32 189.13,62.17 186.18,65.13 178.56,65.13 176.02,67.66 171.54,67.66 171.53,67.67 171.09,67.67 171.08,67.66 170.76,67.66 170.24,68.18 166.68,68.18 166.38,68.48 166.38,68.92 166.2,69.11 166.03,69.11 165.95,69.18 165.93,69.18 165.8,69.32 v2(165.8,69.41)
  BOTTOM w0.081: UC1.H8 166.27,68.94 v2(165.8,69.41)
SATA_PRX_DTX_P1_C: length 5.1
  TOP w0.102: CN26.2 260.51,22.34 260.51,21.97 260.79,21.68 260.79,21.65 261.21,21.23 261.24,21.23 261.62,20.86 v4(262.6,20.86) 262.97,20.86 263.19,20.63 263.19,20.55 263.19,20.34 263.04,20.2 UN2.5
SATA_PRX_DTX_P1_RP: length 2
  TOP w0.102: CN17.2 263,14.43 263,14.66 263.19,14.85 263.19,15.1 263.04,15.25 UN2.11
SATA_PRX_DTX_P1_RP_C: length 8.8
  TOP w0.102: v2(263.88,11.84) 263.69,12.03 263.23,12.03 262.99,12.28 262.99,12.82 CN17.1
  BOTTOM w0.102: v2(263.88,11.84) 263.69,12.03 263.48,12.03 262.89,11.44 262.89,10.16 261.33,8.6 261.33,7.43 261.44,7.32 JSATA1.6
SATA_PTX_DKRX_N0: length 7.3
  TOP w0.102: C315.1 149.82,102.38 v4(149.82,103.35) 149.82,103.68 148.85,104.65 148.85,106.66 v2(149.02,106.83)
  BOTTOM w0.102: JDOCK1.62 148.95,106.03 148.83,106.15 148.83,106.2 148.83,106.65 v2(149.02,106.83)
SATA_PTX_DKRX_N0_C: length 44.5
  TOP w0.102: C315.2 149.82,100.78 149.82,94.76 149.84,94.74 149.84,94.22 151.72,92.34 162.32,92.34 162.57,92.59 162.57,92.81 v2(162.39,92.99)
  IN3 w0.112: v2(162.39,92.99) 162.58,92.8 162.58,91.84 160.07,89.33 160.07,84.15 160.61,83.61 160.61,81.58 161.78,80.41 161.78,76.53 162.21,76.1 162.21,75.67 162.14,75.6 162.02,75.6 v2(161.81,75.81)
  BOTTOM w0.081: v2(161.81,75.81) 161.81,75.74 161.6,75.54 161.32,75.54 161.15,75.37 161.15,73.88 161.51,73.52 UC1.B15
SATA_PTX_DKRX_P0: length 7.4
  TOP w0.102: v2(148.43,106.83) 148.64,106.63 148.64,104.57 149.59,103.61 149.59,103.07 149.61,103.05 149.61,102.38 C314.1
  BOTTOM w0.102: JDOCK1.60 148.45,105.94 148.62,106.11 148.62,106.65 v2(148.43,106.83)
SATA_PTX_DKRX_P0_C: length 44.6
  TOP w0.102: v2(162.97,92.99) 162.78,92.8 162.78,92.51 162.4,92.13 151.64,92.13 149.61,94.15 v4(149.61,94.46) 149.61,100.78 C314.2
  IN3 w0.112: v2(162.97,92.99) 162.78,92.8 162.78,91.75 160.27,89.24 160.27,84.24 160.82,83.69 160.82,81.66 161.99,80.49 161.99,76.62 162.42,76.19 162.42,75.59 162.22,75.39 161.97,75.39 v2(161.81,75.22)
  BOTTOM w0.081: v2(161.81,75.22) 161.68,75.35 161.39,75.35 161.33,75.29 161.33,73.96 161.79,73.51 UC1.A15
SATA_PTX_DRX_N1: length 143.6
  TOP w0.102: CN30.1 262.35,23.94 262.35,27.54 v2(262.16,27.73)
  IN4 w0.089: v2(160.19,75.1) 160.4,74.89 160.47,74.89 160.57,74.89 160.75,74.72 160.75,72.62 160.13,72 160.13,67.91 160.37,67.67 165.79,67.67 166.23,67.23 168.65,67.23 169.25,66.62 173.57,66.62 173.76,66.82 175.91,66.82 178.31,64.43 184.46,64.43 184.76,64.13 186.16,64.13 188.49,61.8 188.49,53.06 190.17,51.38 190.17,49 194.11,45.06 194.11,42.72 203.81,33.02 227.58,33.02 228.29,33.74 229.81,33.74 229.94,33.6 236.11,33.6 239.14,30.57 241.11,30.57 242.83,28.86 244.92,28.86 245.85,27.92 253.02,27.92 254.42,26.52 261.67,26.52 262.37,27.23 262.37,27.52 v2(262.16,27.73)
  BOTTOM w0.081: UC1.A17 161.09,73.38 160.96,73.25 160.88,73.25 160.77,73.37 160.77,74.71 160.58,74.9 160.39,74.9 v2(160.19,75.1)
SATA_PTX_DRX_N1_C: length 4.8
  TOP w0.102: UN2.2 264.54,20.13 264.69,20.28 264.69,20.65 263.95,21.38 263.92,21.38 263.61,21.7 262.64,21.7 262.35,21.99 262.35,22.34 CN30.2
SATA_PTX_DRX_N1_RP: length 2
  TOP w0.102: UN2.14 264.54,15.2 264.69,15.06 264.69,14.76 264.82,14.63 264.82,14.41 CN20.2
SATA_PTX_DRX_N1_RP_C: length 11.8
  TOP w0.102: CN20.1 264.85,13.16 264.92,13.09 264.92,12.77 v2(264.64,12.49)
  BOTTOM w0.102: JSATA1.3 259.94,7.48 259.89,7.53 259.71,7.53 259.65,7.59 259.65,8.11 261.97,10.43 v4(261.97,11.11) 261.97,11.9 263.17,13.1 264.9,13.1 265.01,12.98 265.01,12.86 v2(264.64,12.49)
SATA_PTX_DRX_P1: length 143.6
  TOP w0.102: v2(262.75,27.73) 262.56,27.54 262.56,23.94 CN23.1
  IN4 w0.089: v2(262.75,27.73) 262.54,27.52 262.54,27.16 261.74,26.35 254.35,26.35 252.95,27.75 245.78,27.75 244.84,28.68 242.76,28.68 241.04,30.4 239.07,30.4 236.04,33.43 229.87,33.43 229.74,33.57 228.36,33.57 227.65,32.85 203.74,32.85 193.94,42.65 193.94,44.99 190,48.93 190,51.31 188.32,52.99 188.32,61.73 186.09,63.96 184.69,63.96 184.39,64.26 178.23,64.26 175.84,66.65 173.83,66.65 173.64,66.45 169.18,66.45 168.58,67.06 166.16,67.06 165.72,67.5 160.3,67.5 159.96,67.84 159.96,72.07 160.58,72.69 160.58,74.65 160.5,74.72 160.4,74.72 v2(160.19,74.51)
  BOTTOM w0.081: UC1.B17 160.74,73.13 160.58,73.29 160.58,74.63 160.5,74.71 160.39,74.71 v2(160.19,74.51)
SATA_PTX_DRX_P1_C: length 4.8
  TOP w0.102: CN23.2 262.56,22.34 262.56,22.08 262.73,21.91 263.72,21.91 v4(263.89,21.74) 264.9,20.73 264.9,20.28 265.04,20.13 UN2.1
SATA_PTX_DRX_P1_RP: length 2
  TOP w0.102: CN19.2 265.03,14.42 265.03,14.71 264.9,14.85 264.9,15.02 265.04,15.17 UN2.15
SATA_PTX_DRX_P1_RP_C: length 11.7
  TOP w0.102: CN19.1 265.13,12.91 265.13,12.58 v2(265.22,12.49)
  BOTTOM w0.102: v2(265.22,12.49) 265.22,13.07 264.98,13.31 263.08,13.31 261.76,11.99 261.76,11.43 261.74,11.41 261.74,10.81 261.76,10.79 261.76,10.52 259.44,8.2 JSATA1.2
SATACLK_REQ#: length 115.5
  TOP w0.102: v2(173.83,65.9) 173.83,66.12 v1(174.1,66.4)
  IN3 w0.122: v2(173.83,65.9) 173.83,65.98 174.22,66.37 184.65,66.37 184.72,66.3 186.88,66.3 190.52,62.66 190.52,59.61 193.79,56.35 193.79,54.53 194.9,53.42 194.9,47.48 195.11,47.27 195.11,41.96 200.35,36.71 208.7,36.71 211.06,34.36 225.71,34.36 226.01,34.66 226.01,35.06 226.3,35.36 226.3,35.5 227.07,36.26 229.33,36.26 229.99,36.93 230.82,36.93 233.99,40.11 233.99,45.44 236.15,47.6 236.15,57.63 v2(237.68,59.16)
  BOTTOM w0.076: UC1.T2 170.37,64.79 170.49,64.91 170.49,64.91 170.66,65.08 170.67,65.08 171.02,65.08 171.1,65.16 171.36,65.16 171.96,65.76 173.18,65.76 173.32,65.9
  BOTTOM w0.102: JNGFF2.44 239.08,60.1 238.14,59.16 v2(237.68,59.16) ; RC68.2 174.59,64.99 173.83,65.76 v2(173.83,65.9) 173.32,65.9
SD/MMCCD#: length 23.5
  TOP w0.102: UR1.21 285.72,27.34 285.33,26.95 285.33,23.37 284.33,22.36 280.9,22.36 280.13,23.13 277.11,23.13 276.42,23.82 276.42,27.31 276.06,27.67 RR11.1 CR35.1 274.37,27.67 274.22,27.52 v1(273.68,27.52) 273.62,27.58 v2(272.81,27.58)
  BOTTOM w0.102: JSD1.18 272.35,28.37 272.81,27.91 v2(272.81,27.58)
SD/MMCCLK: length 20.2
  TOP w0.102: RR1.2 CR23.1 283.92,37.84 v2(284.84,37.84)
  IN1 w0.089: v2(273.33,30.31) 273.33,31.5 274.2,32.37 274.2,34.14 276.83,36.77 283.91,36.77 284.84,37.7 v2(284.84,37.84)
  BOTTOM w0.102: v2(273.33,30.31) 272.78,29.77 JSD1.5
SD/MMCCLK_R: length 2.3
  TOP w0.102: UR1.43 284.52,34.41 284.02,34.91 v1(284.02,35.05) 283.89,35.18 RR1.1
SD/MMCCMD: length 20.8
  TOP w0.102: UR1.45 283.72,34.45 283.32,34.85 v2(283.32,35.41)
  BOTTOM w0.102: JSD1.2 273.46,35.47 273.86,35.07 274.68,35.07 275.1,35.5 275.1,36.08 275.23,36.21 275.48,36.21 275.61,36.08 275.61,35.25 275.74,35.12 275.99,35.12 276.12,35.25 276.12,36.08 276.25,36.21 276.5,36.21 276.63,36.08 276.63,35.25 276.75,35.12 277.47,35.12 277.57,35.22 277.57,36.07 277.67,36.17 277.98,36.17 278.08,36.07 278.08,35.22 278.18,35.12 278.49,35.12 278.59,35.22 278.59,36.07 278.69,36.17 278.99,36.17 279.1,36.07 279.1,35.22 279.2,35.12 283.03,35.12 v2(283.32,35.41)
SD/MMCDAT0: length 32.9
  TOP w0.094: v2(289.23,30.33) 288.79,30.77 288.35,30.77 288.29,30.71 UR1.30 ; UR1.38 286.52,34.31 286.53,34.32 286.53,34.59 286.86,34.92 287.46,34.92 v2(287.58,35.03)
  IN4 w0.081: v2(278.71,22.59) 278.53,22.4 278.31,22.4 278.23,22.48 278.23,22.74 280.07,24.59 280.72,24.59 283.61,27.48 287.28,27.48 289.14,29.34 289.14,30.25 v2(289.23,30.33) 289.23,30.35 289.03,30.54 289.03,31.32 288.48,31.88 288.48,34.47 288.1,34.84 287.77,34.84 v2(287.58,35.03)
  BOTTOM w0.094: JSD1.7 272.5,25.57 273.05,25.02 273.83,25.02 274.23,24.62 275.97,24.62 278.01,22.59 v2(278.71,22.59)
SD/MMCDAT1: length 31.8
  TOP w0.094: v2(287.58,34.4) 287.44,34.54 287.01,34.54 286.92,34.44 286.92,34.32 286.92,34.31 UR1.37 ; v2(288.59,30.35) 288.55,30.31 UR1.29
  IN4 w0.081: v2(278.7,21.97) 278.7,22.03 278.58,22.15 278.2,22.15 277.98,22.38 277.98,22.85 279.97,24.84 280.61,24.84 283.51,27.73 287.18,27.73 288.89,29.44 288.89,30.11 288.65,30.35 v2(288.59,30.35) 288.78,30.54 288.78,31.22 288.23,31.77 288.23,34.36 288,34.59 287.77,34.59 v2(287.58,34.4)
  BOTTOM w0.094: JSD1.8 272.73,24.17 272.81,24.25 272.81,24.51 272.93,24.64 273.68,24.64 274.07,24.24 275.81,24.24 277.85,22.2 278.54,22.2 278.7,22.05 v2(278.7,21.97)
SD/MMCDAT2: length 2.8
  TOP w0.102: UR1.48 282.52,34.32 282,34.84 281.65,34.84 v1(281.47,35.01) 281.47,35.58 RR4.1
SD/MMCDAT2_R: length 16.6
  TOP w0.102: RR4.2 v2(281.86,37.51)
  BOTTOM w0.102: JSD1.9 273.15,38.27 273.64,37.77 276.79,37.77 276.92,37.65 276.92,37.19 277.05,37.06 277.92,37.06 278.02,37.16 278.02,37.85 278.15,37.97 278.4,37.97 278.53,37.85 278.53,37.16 278.63,37.06 278.94,37.06 279.04,37.16 279.04,37.85 279.16,37.97 279.42,37.97 279.55,37.85 279.55,37.16 279.65,37.06 279.95,37.06 280.05,37.16 280.05,37.83 280.18,37.95 280.43,37.95 280.56,37.83 280.56,37.15 280.69,37.02 281.73,37.02 281.86,37.15 v2(281.86,37.51)
SD/MMCDAT3: length 2.1
  TOP w0.102: UR1.47 282.92,34.71 282.75,34.87 v1(282.75,35.06) RR3.1
SD/MMCDAT3_R: length 18.9
  TOP w0.102: RR3.2 v2(282.75,37.57)
  BOTTOM w0.102: JSD1.1 272.85,36.87 273.25,36.47 273.93,36.47 274.82,37.37 275.15,37.37 275.28,37.24 275.28,36.74 275.41,36.61 275.66,36.61 275.79,36.74 275.79,37.24 275.92,37.37 276.17,37.37 276.3,37.24 276.3,36.74 276.42,36.61 280.64,36.61 280.74,36.51 280.74,35.66 280.86,35.53 281.24,35.53 281.37,35.66 281.37,36.49 281.49,36.61 281.87,36.61 282,36.49 282,35.66 282.13,35.53 282.62,35.53 282.75,35.66 v2(282.75,37.57)
SD_REXT: length 2.3
  TOP w0.102: RR5.1 288.9,28.31 v1(288.8,28.4) 288.8,28.43 288.12,29.11 UR1.26
SD_UHS2_D0N: length 34.2
  TOP w0.094: v2(289.68,32.59) 289.57,32.7 289.19,32.7 288.81,32.32 288.34,32.32 288.33,32.31 UR1.34
  IN4 w0.081: v2(289.68,32.59) 289.69,32.59 294.3,32.59 296.64,34.93 296.64,38.36 296.36,38.63 294.43,38.63 294.31,38.76 294.31,39.08 294.43,39.2 296.49,39.2 296.77,39.48 296.77,40.05 296.49,40.32 294.36,40.32 294.23,40.45 294.23,40.82 294.36,40.94 296.56,40.94 296.83,41.22 296.83,41.81 296.56,42.08 294.68,42.08 294.55,42.21 294.55,42.52 294.68,42.65 296.37,42.65 296.64,42.92 296.64,43.73 v2(296.64,43.73)
  BOTTOM w0.094: v2(296.64,43.73) 296.64,45.11 296.9,45.37 JSD1.12
SD_UHS2_D0P: length 34.2
  TOP w0.094: UR1.35 288.18,32.71 288.19,32.7 288.65,32.7 289.03,33.08 289.6,33.08 v2(289.68,33.17)
  IN4 w0.081: v2(296.06,43.73) 296.39,43.4 296.39,43.03 296.26,42.9 294.57,42.9 294.3,42.63 294.3,42.11 294.57,41.83 296.45,41.83 296.58,41.71 296.58,41.32 296.45,41.2 294.25,41.2 293.98,40.92 293.98,40.34 294.25,40.07 296.39,40.07 296.52,39.94 296.52,39.58 296.39,39.46 294.33,39.46 294.06,39.18 294.06,38.66 294.33,38.38 296.26,38.38 296.39,38.25 296.39,35.04 294.19,32.84 290.01,32.84 v2(289.68,33.17)
  BOTTOM w0.094: v2(296.06,43.73) 296.26,43.94 296.26,44.87 295.8,45.33 JSD1.11
SD_UHS2_D1N: length 34.2
  TOP w0.094: v2(294.6,21.65) 294.5,21.55 293.58,21.55 293.46,21.68 293.46,27.98 293.58,28.1 295.99,28.1 296.34,28.45 296.34,29.38 295.99,29.73 293.47,29.73 293.34,29.86 293.34,30.43 293.47,30.56 295.71,30.56 296.06,30.91 296.06,31.8 295.71,32.15 289.92,32.15 289.67,31.9 v4(289.21,31.9) 288.45,31.9 288.44,31.91 UR1.33
  BOTTOM w0.094: v2(294.6,21.65) 294.7,21.55 296.05,21.55 296.9,20.7 296.9,17.31 296.9,17.31 JSD1.15
SD_UHS2_D1P: length 34.2
  TOP w0.094: v2(294.6,21.07) 294.5,21.17 293.43,21.17 293.08,21.52 293.08,28.14 293.43,28.49 295.83,28.49 295.96,28.61 295.96,29.22 295.83,29.35 293.31,29.35 292.96,29.7 292.96,30.59 293.31,30.94 295.55,30.94 295.68,31.06 295.68,31.64 295.55,31.77 v4(290.79,31.77) 290.07,31.77 289.82,31.52 288.45,31.52 288.44,31.51 UR1.32
  BOTTOM w0.094: JSD1.16 295.8,17.44 295.88,17.53 296.43,17.53 296.52,17.61 296.52,20.54 295.89,21.17 294.7,21.17 v2(294.6,21.07)
SDWP: length 19.1
  TOP w0.102: UR1.20 285.32,27.5 284.91,27.08 v1(284.91,26.39) v2(284.91,23.79)
  IN4 w0.089: v2(277.05,22.17) 277.7,21.53 283,21.53 284.91,23.43 v2(284.91,23.79)
  BOTTOM w0.102: JSD1.19 272.75,22.77 273.34,22.17 v2(277.05,22.17)
SIO_EXT_SCI#: length 127.4
  TOP w0.081: 173.36,66.4 168.32,66.4 167.78,65.86 v2(167.78,65.7)
  TOP w0.102: v2(255.05,36.18) 255.19,36.31 UE2.A33 ; 173.36,66.4 173.53,66.4 173.88,66.75 175.17,66.75 RC156.1 ; v1(242.55,39.62) 242.71,39.47 v2(243.2,39.47)
  IN3 w0.081: v2(167.78,65.7) 168.29,65.2 168.52,65.2 168.82,64.9 168.82,64.59 169.65,63.76 169.95,63.76 170.72,63 170.72,62.39 170.91,62.2 170.91,61.78 171.15,61.54 172.28,61.54 172.51,61.77 173.08,61.77
  IN3 w0.122: 173.08,61.77 173.67,61.77 173.86,61.96 175.22,61.96 175.51,62.25 182.95,62.25 186.43,58.78 186.43,57.61 188.28,55.76 189.58,55.76 190.23,55.1 190.23,48.45 192.61,46.07 192.61,40.92 199.32,34.21 207.67,34.21 210.88,31 227.77,31 228.61,31.84 229.73,31.84 231.4,33.51 232.44,33.51 232.69,33.76 232.69,34.11 236.94,38.37 239.18,38.37 240.28,39.47 v2(243.2,39.47)
  IN4 w0.089: v2(255.05,36.18) 255.05,36.77 253.01,38.81 247.45,38.81 246.79,39.47 v2(243.2,39.47)
  BOTTOM w0.081: UC1.N5 167.78,65.85 v2(167.78,65.7)
SIO_EXT_SMI#: length 133
  TOP w0.102: RPC5.5 183.5,60.36 183.29,60.15 v1(182.71,60.15) 182.64,60.15 182.33,60.45 181.65,60.45 181.24,60.86 v2(181.24,60.86) ; v2(260.37,49.25) 259.96,48.85 259.96,48.5 260.19,48.27 UE2.A6
  IN1 w0.089: v2(181.24,60.86) 181.24,60.76 179.47,58.99 172.81,58.99 172.73,59.07 v2(168.3,59.07)
  IN3 w0.122: v2(181.24,60.86) 181.24,60.86 180.63,60.25 180.63,59.24 181.83,58.04 182.69,58.04 183.73,57 184.27,57 187.67,53.6 187.67,50.55 188.53,49.69 188.53,48.02 191.11,45.45 191.11,39.34 197.74,32.71 207.04,32.71 210.26,29.5 228.39,29.5 229.23,30.34 230.36,30.34 232.03,32.01 233.06,32.01 234.19,33.14 234.19,33.49 237.56,36.86 239.83,36.86 240.28,37.31 242.63,37.31 245.87,40.55 245.87,47.15 248.16,49.44 252.61,49.44 253.11,48.95 254.47,48.95 255.03,49.5 256.4,49.5 257.14,50.25 259.38,50.25 v2(260.37,49.25)
  BOTTOM w0.081: v2(168.3,59.07) 168.3,59.06 168.15,58.9 UC1.AG5
SIO_EXT_WAKE#: length 126.3
  TOP w0.102: UE2.B5 260.94,46.56 v2(260.78,46.4)
  IN3 w0.122: v2(260.78,46.4) 259.96,47.22 257.64,47.22 257.26,46.84 254.92,46.84 254.23,46.14 250.89,46.14 250.7,46.33 249.62,46.33 248.66,45.38 248.66,38.58 245.62,35.53 245.04,35.53 243.84,34.33 241.93,34.33 241.3,33.69 241.3,32.59 239.79,31.08 235.68,31.08 233.05,28.45 230.02,28.45 229.18,27.61 209.47,27.61 208.21,28.87 206.26,30.82 196.96,30.82 189.22,38.56 189.22,42.02 186.39,44.85 186.39,49.68 183.69,52.38 183.69,54.4 181.78,56.31 v2(181.78,56.81)
  BOTTOM w0.076: UC1.AU2 170.24,52.86 170.57,53.18 172.84,53.18 173.36,53.7
  BOTTOM w0.102: RPC7.6 182.88,57.26 182.43,56.81 v2(181.78,56.81) v1(180.93,56.81) 177.53,56.81 176.1,55.39 176.1,55.38 174.42,53.7 173.36,53.7
SIO_PWRBTN#: length 245.9
  TOP w0.102: v2(262.18,41) 262.64,41.46 UE2.B58 ; JXDP1.41 80.05,50.7 80.36,50.39 80.36,48.89 80.94,48.31 80.94,45.45 81.98,44.4 83.9,44.4 85.63,42.68 85.63,41.04 88.52,38.15 v1(88.52,36.58) v2(88.52,35.34)
  IN3 w0.122: v2(254.94,32.71) 254.82,32.6 254.82,30.35 252.22,27.75 252.22,26.12 247.28,21.18 242,21.18 239.9,19.09 233.2,19.09 232.52,18.41 228.78,18.41 225.72,21.47 205.21,21.47 202.32,24.37 191.44,24.37 v2(178.4,37.41) 178.4,38.25 177.08,39.56 177.08,44.06 173.16,47.98 171.99,47.98 167.51,52.46 167.51,52.68 166.54,53.65 166.54,56.74 v2(167,57.2)
  IN4 w0.089: v2(254.94,32.71) 255.72,33.5 257.49,33.5 259.34,35.36 260.66,35.36 261.08,35.77 261.08,39.44 261.74,40.11 261.74,40.57 v2(262.18,41)
  BOTTOM w0.081: UC1.AL7 167.04,57.16 v2(167,57.2)
  BOTTOM w0.102: v2(178.4,37.41) 176.33,35.34 v2(88.52,35.34)
SIO_RCIN#: length 135.8
  TOP w0.076: v2(168.33,63.84) 171.71,63.84 171.87,63.99
  TOP w0.081: 173.9,64.3 173.61,64.3 173.57,64.26 172.14,64.26 171.87,63.99
  TOP w0.102: UE2.A27 252.67,41.21 v2(252.59,41.13) ; 173.9,64.3 178.05,64.3 v1(178.14,64.21) 179.14,64.21 179.8,63.55 179.8,62.22 180.12,61.9 RPC15.3
  IN3 w0.081: 173.36,58.71 173.2,58.71 172.69,59.22 171.15,59.22 170.38,60 170.38,61.64 169.66,62.36 169.16,62.36 168.85,62.66 168.85,63.31 v2(168.33,63.84)
  IN3 w0.122: 173.36,58.71 174.24,58.71 177.09,55.86 178.76,55.86 181.43,53.19 181.43,44.56 183.77,42.23 183.77,40.57 195.84,28.5 204.02,28.5 207.17,25.35 230.56,25.35 232.11,23.8 232.79,23.8 233.79,24.8 239.27,24.8 239.33,24.74 239.77,24.74 241.89,26.86 241.89,30.17 242.62,30.9 244.85,30.9 245.93,31.98 245.93,32.61 248.09,34.77 250.33,34.77 251.2,35.64 251.2,38.9 252.59,40.28 v2(252.59,41.13)
  BOTTOM w0.081: UC1.V4 168.83,63.33 v2(168.33,63.84)
SIO_SLP_A#: length 170.1
  TOP w0.102: v2(255.81,41.8) 255.39,41.38 254.91,41.38 254.82,41.46 UE2.B28 ; v2(298.32,24.49) 298.36,24.52 298.36,26.82 299.22,27.69 JAPS1.6 ; v2(184.21,52.93) 184.62,52.93 184.81,52.74 185.89,52.74 186.06,52.57 UC6.1
  IN1 w0.089: v2(229.55,42.07) 227.39,42.07 227.24,42.23 224.84,42.23 224.6,42.47 215.95,42.47 215.41,43 206.32,43 200.44,48.88 196.96,48.88 193.8,52.04 191.58,52.04 191.13,52.49 188.74,52.49 187.97,53.26 184.71,53.26 184.38,52.93 v2(184.21,52.93) 183.17,52.93 182.48,53.63 182.48,54.28 179.99,56.77 176.03,56.77 172.96,53.7 170.46,53.7 169.3,52.54 168.16,52.54 167.08,53.62 167.08,56.44 167.73,57.09 v2(167.73,57.22)
  IN3 w0.122: v2(255.81,41.8) 256.29,41.32 260.99,41.32 261.76,40.54 263.53,40.54 264.3,39.77 266.36,39.77 266.82,40.23 267.89,40.23 268.87,39.25 272.23,39.25 272.77,39.79 274.13,39.79 275.95,37.97 277.99,37.97 279.06,36.9 279.06,34.86 281.6,32.33 281.6,28.94 282.25,28.29 282.25,26.17 283.66,24.77 287.5,24.77 287.62,24.65 298.16,24.65 v2(298.32,24.49)
  IN4 w0.089: v2(255.81,41.8) 255.28,42.33 252.6,42.33 251.89,41.62 243.2,41.62 239.81,38.23 236.31,38.23 233.86,40.69 230.62,40.69 230.06,41.25 230.06,41.76 229.74,42.07 v2(229.55,42.07)
  BOTTOM w0.081: v2(167.73,57.22) 167.73,56.88 UC1.AL5
SIO_SLP_LAN#: length 159.8
  TOP w0.102: v2(256.09,39.8) 255.94,39.65 255.94,38.86 255.93,38.85 255.93,38.18 255.94,38.17 UE2.B37 ; UZ2.5 243.25,58.42 243.42,58.58 245.26,58.58 245.61,58.24 245.61,52.42 243.66,50.47 243.66,46.96 244.43,46.19 v1(244.43,42.27) 243.71,41.54 v2(243.71,39.98)
  IN3 w0.076: v2(166.41,58.09) 166.81,58.5 166.82,58.5 166.83,58.5 167.71,58.5 167.92,58.29 167.92,57.67 168.09,57.5 168.09,56.83 168.56,56.36 170.18,56.36 170.94,55.6 172.59,55.6 173.23,54.97 173.23,51.21 173.36,51.08
  IN3 w0.122: 173.36,51.08 176.08,48.35 179.19,48.35 179.92,47.62 179.92,41.98 179.76,41.82 179.76,40.61 193.36,27 203.4,27 206.55,23.85 227.42,23.85 228.98,22.29 236.91,22.29 237.49,22.87 239.81,22.87 243.11,26.18 243.31,26.18 246.76,29.63 246.76,30.68 247.58,31.51 248.96,31.51 252.25,34.8 252.25,35.56 254.44,37.76 255.37,37.76 256.03,38.42 256.03,39.74 v2(256.09,39.8)
  IN4 w0.089: v2(243.71,39.98) 244.02,40.29 248.31,40.29 249.36,39.24 253.64,39.24 254.05,39.65 255.94,39.65 v2(256.09,39.8)
  BOTTOM w0.081: v2(166.41,58.09) 166.85,57.65 UC1.AJ7
SIO_SLP_S0#: length 180.2
  TOP w0.102: v1(302.07,22.9) 301.78,23.19 JAPS1.15 v2(299.53,23.19)
  IN3 w0.081: v2(171.3,60.2) 171.7,59.8 173.26,59.8 173.36,59.9
  IN3 w0.122: v2(299.53,23.19) 298.96,23.76 298.96,24.65 297.75,25.86 285.98,25.86 285.56,25.44 283.7,25.44 282.75,26.38 282.75,28.5 282.1,29.15 282.1,32.54 279.57,35.07 279.57,37.84 276.66,40.75 273.28,40.75 272.84,40.31 271.19,40.31 271.07,40.18 268.68,40.18 267.03,41.83 264.4,41.83 263.7,42.53 261.96,42.53 261.27,41.83 256.88,41.83 256.37,42.34 254.62,42.34 253.91,41.63 251.52,41.63 250.7,40.8 250.7,36.87 249.49,35.66 247.84,35.66 245.04,32.87 245.04,32.23 244.49,31.67 242.31,31.67 241.11,30.47 241.11,27.34 240.03,26.26 238.06,26.26 237.8,26.01 236.79,26.01 236.47,26.33 234.88,26.33 234.88,26.32 234.83,26.32 233.96,27.19 230.54,27.19 229.7,26.35 207.64,26.35 204.49,29.5 196.25,29.5 184.77,40.99 184.77,42.67 182.44,45 182.44,53.6 179.17,56.86 177.81,56.86 174.77,59.9 173.36,59.9
  BOTTOM w0.076: UC1.AF3 169.74,59.25 170.25,59.25 170.49,59.49 170.49,59.66 170.66,59.83 170.93,59.83 v2(171.3,60.2)
SIO_SLP_S3#: length 185.4
  TOP w0.102: JAPS1.2 299.65,29.69 297.37,27.41 v2(297.37,23.09) ; UE2.A35 256.19,36.58 v2(255.88,36.27) 255.85,36.24 255.85,35.75 255.25,35.15 255.25,34.82 254.95,34.52 254.95,33.6 254.52,33.17 254.52,32.52 254.84,32.21 v1(254.87,32.21) 255.41,31.67 RE280.1
  IN3 w0.122: v2(297.37,23.09) 297.33,23.05 283.22,23.05 282.98,23.3 282.98,24.11 281.88,25.21 281.16,25.21 279.81,26.56 279.81,28.83 280.22,29.24 280.22,32.65 277.94,34.92 276.99,34.92 274.44,37.47 271.79,37.47 270.88,36.57 270.88,36.35 269.11,34.58 264.92,34.58 262.83,36.68 256.29,36.68 v2(255.88,36.27) 255.52,36.63 254.82,36.63 254.21,36.02 254.21,33.48 254.04,33.3 254.04,30.65 251.02,27.63 250.27,27.63 246.84,24.2 243.54,24.2 239.32,19.98 233.11,19.98 232.69,20.4 231.37,20.4 231.01,20.04 228.47,20.04 226.29,22.22 205.52,22.22 202.63,25.12 192.59,25.12 177.83,39.87 177.83,44.45 173.35,48.93 171.97,48.93 168.77,52.14 168.77,53.11 v2(168.35,53.52)
  BOTTOM w0.081: v2(168.35,53.52) 168.37,53.51 UC1.AT4
SIO_SLP_S4#: length 191.7
  TOP w0.102: v2(254.84,34.99) 254.54,34.7 254.54,33.72 T9.1 253.58,32.75 RE282.1 ; v2(298.26,22.64) 298.26,23.79 297.88,24.17 297.88,27.03 299.04,28.19 JAPS1.5 ; UE2.B36 v2(255.44,38.53)
  IN1 w0.089: v2(254.84,34.99) 254.62,35.21 254.62,37.71 v2(255.44,38.53)
  IN3 w0.081: 167.35,56.9 167.38,56.93 167.38,57.75 v2(166.98,58.15)
  IN3 w0.122: v2(298.26,22.64) 298.23,22.67 296.91,22.67 296.81,22.77 282.03,22.77 281.26,23.53 281.26,24.12 279.36,26.02 279.36,30.34 276.64,33.06 276.64,34.91 274.34,37.22 271.89,37.22 271.13,36.46 271.13,36.25 269.21,34.33 264.86,34.33 264.03,33.5 262.13,33.5 261.55,34.07 258.44,34.07 257.36,35.15 255,35.15 v2(254.84,34.99) 254.84,33.73 254.31,33.21 254.31,30.57 251.12,27.38 250.38,27.38 246.95,23.95 244.64,23.95 243.63,22.95 242.8,22.95 239.57,19.72 232.98,19.72 232.55,20.15 231.5,20.15 231.14,19.79 228.29,19.79 226.11,21.97 205.42,21.97 202.53,24.87 192.49,24.87 177.58,39.77 177.58,44.27 173.37,48.49 171.96,48.49 167.89,52.55 167.89,52.81 167,53.7 167,56.55 167.35,56.9
  BOTTOM w0.081: v2(166.98,58.15) 166.98,58.14 167.47,57.64 UC1.AJ6
SIO_SLP_S5#: length 204.3
  TOP w0.102: UE2.A18 252.79,45.71 v2(252.73,45.65) ; v2(297.81,23.6) 297.62,23.79 297.62,27.22 299.09,28.69 JAPS1.4 ; T8.1 167.9,49.24 167.9,54.57 167.51,54.97 v2(167.51,55.06)
  IN3 w0.081: 169.29,54.46 168.11,54.46 v2(167.51,55.06)
  IN3 w0.122: 169.29,54.46 170.24,53.5 170.24,52.43 178.08,44.58 178.08,39.98 192.69,25.37 202.73,25.37 205.63,22.47 226.4,22.47 228.57,20.29 230.88,20.29 231.23,20.64 232.88,20.64 233.3,20.23 239.21,20.23 243.43,24.45 246.74,24.45 250.17,27.88 250.92,27.88 253.77,30.73 253.77,33.23 v2(253.47,33.53) 253.88,33.93 253.88,36.05 254.76,36.93 262.93,36.93 265.02,34.84 269.01,34.84 270.63,36.46 270.63,36.67 271.68,37.72 274.54,37.72 277.09,35.17 278.05,35.17 280.46,32.75 280.46,29.13 280.06,28.73 280.06,26.66 281.01,25.71 282,25.71 283.45,24.26 285.12,24.26 285.69,23.69 287.67,23.69 288.12,24.14 296.63,24.14 297.18,23.6 v2(297.81,23.6)
  BOTTOM w0.081: UC1.AP5 167.79,54.78 v2(167.51,55.06)
  BOTTOM w0.102: v2(252.73,45.65) 252.73,45.37 252.47,45.12 251.83,45.12 251.17,44.46 249.62,44.46 249.27,44.12 249.27,42.79 249.54,42.52 250.06,42.52 250.55,42.03 250.55,36.45 v2(253.47,33.53)
SIO_SLP_SUS#: length 119.1
  TOP w0.102: UE2.B52 263.98,38.46 264.08,38.36 264.72,38.36 266.13,36.96 v1(266.13,36.85) 266.62,36.36 v2(266.62,35.54)
  IN1 w0.089: v2(228.41,43.13) 228.32,43.22 216.21,43.22 215.71,43.73 207.69,43.73 203.78,47.64 202.65,47.64 200.72,49.57 197.25,49.57 194.09,52.73 193.55,52.73 192.01,54.27 188.91,54.27 188.06,55.12 185.35,55.12 184.63,54.39 183.33,54.39 183.16,54.56 183.16,54.56 180.23,57.49 175.79,57.49 174.15,55.85 172.31,55.85 171.83,55.38 170.64,55.38 170.1,54.84 v2(168.38,54.84)
  IN4 w0.089: v2(228.41,43.13) 228.41,40.74 229.87,39.28 233.28,39.28 235.73,36.82 239.79,36.82 240.32,36.3 247.99,36.3 251.2,33.09 253.6,33.09 254.91,31.79 260.01,31.79 261.61,33.38 263.4,33.38 265.56,35.54 v2(266.62,35.54)
  BOTTOM w0.081: UC1.AP4 168.83,54.39 v2(168.38,54.84)
SIO_SLP_WLAN#: length 189.9
  TOP w0.102: UE1.A14 252.12,71.55 v2(252.85,72.28)
  IN1 w0.089: v2(269.17,35.75) 269.17,36.25 271.57,38.65 273.19,38.65 273.97,39.42 273.97,41.03 275.83,42.89 275.83,46.97 274.42,48.38 269.04,48.38 265.36,52.06 265.36,54.71 263.46,56.61 263.46,58.65 260.36,61.75 260.36,67.49 260.01,67.84 254.91,67.84 253.91,68.84 253.91,70.68 253.41,71.17 253.41,71.93 253.06,72.28 v2(252.85,72.28)
  IN3 w0.122: v2(168.33,55.93) 169.97,55.93 170.74,55.17 170.74,52.38 178.33,44.78 178.33,40.08 192.79,25.62 202.83,25.62 205.73,22.72 226.53,22.72 228.7,20.55 230.76,20.55 231.1,20.89 233.02,20.89 233.43,20.48 239.11,20.48 243.58,24.95 244.12,24.95 245.78,26.62 248.56,26.62 250.07,28.13 250.81,28.13 253.52,30.83 253.52,32.77 253,33.3 253,35.55 254.63,37.19 263.08,37.19 265.14,35.13 268.55,35.13 v2(269.17,35.75)
  BOTTOM w0.081: UC1.AM5 168.03,55.93 v2(168.33,55.93)
SKIP#: length 2.9
  TOP w0.203: PR520.2 100.46,64.82 v1(101.17,65.52) 101.68,66.03 PU500.7
SKIP#1: length 12.3
  TOP w0.254: PR520.1 v2(98.54,64.82)
  BOTTOM w0.203: 104.25,57.77 104.07,57.59 PU501.1
  BOTTOM w0.254: v2(98.54,64.82) 99.04,64.82 99.36,64.5 v1(99.36,63.88) 99.36,61.96 100.31,61.01 102.47,61.01 104.25,59.23 104.25,57.77
SL_BAT_PRES#: length 4
  TOP w0.254: PU800.21 77.85,31.11 77.69,30.95 76.99,30.95 v1(76.48,30.44) 76.12,30.08 76.12,29.64 75.87,29.38 PR854.1
SLATE_MODE: length 18.3
  TOP w0.081: v2(168.45,56.99) 168.78,57.33 169.3,57.33 169.45,57.17 169.45,56.72 169.68,56.49 170.37,56.49 171.26,55.6 173.31,55.6 173.36,55.65
  TOP w0.102: 173.36,55.65 174.42,55.65 175.13,56.36 v1(179.79,56.36) 181.06,56.36 181.62,55.8 183.27,55.8 183.91,56.44 RPC10.7
  BOTTOM w0.076: UC1.AL4 168.45,56.89 v2(168.45,56.99)
SLEEVE: length 18.2
  TOP w0.203: v2(29.25,18.07) 29.23,18.07 29.33,18.17 UA1.29
  TOP w0.406: v2(26.41,25.76) 26.42,25.75 QA2.3
  TOP w0.508: v2(23.75,19.38) 23.99,19.62 RA6.1 24.44,19.11 24.2,18.87 LA11.1
  IN1 w0.508: v2(23.75,19.38) 25.05,18.07 v2(29.25,18.07)
  IN2 w0.508: v2(26.41,25.76) 26.08,25.76 25.27,24.94 25.27,21.18 23.75,19.66 v2(23.75,19.38)
  BOTTOM w0.127: v2(26.41,25.76) v1(27.12,25.76)
SLEEVE_R:
  vias: v1(15.89,23.29)
SLEWA: length 4.6
  TOP w0.102: v1(106.87,63.04) 106.6,63.31 v2(106.6,63.8)
  TOP w0.203: PU500.15 105.55,64.53 106.28,63.8 v2(106.6,63.8)
  BOTTOM w0.254: PR510.2 106.41,63.99 v2(106.6,63.8) PR500.1
SLICE_BAT_ON: length 289
  TOP w0.102: RE17.2 247.42,62.59 v2(247.76,62.94) 248.43,62.26 UE1.A31
  TOP w0.254: PR845.2 80.06,28.37 79.55,27.86 71.18,27.86 69.63,26.31 v1(66.15,26.31) 64.63,26.31 64.27,26.67 54.52,26.67 v2(53.15,28.04)
  IN1 w0.254: v2(96.51,75.49) 96.51,74.55 94.69,72.73 94.69,64.97 91.02,61.3 89.89,61.3 89.07,60.48 89.07,59.13 88.82,58.88 88.82,57.12 85.74,54.04 74.95,54.04 74.04,53.12 74.04,44.61 73.49,44.07 73.49,39.9 71.38,37.79 68.11,37.79 67.65,37.34 v2(67.65,36.32)
  IN2 w0.122: v2(247.76,62.94) 246.97,62.94 246.62,63.29 246.62,70.79 237.49,79.91 237.49,81.44 233.74,85.19 233.74,85.48 233.75,85.49 233.75,85.83 233.74,85.84 233.74,90.03 232.58,91.19 223.55,91.19 221.19,88.84 205.89,88.84 204.66,87.6 148.65,87.6 147.63,86.59 128.97,86.59 124.86,82.49 124.86,80.45 123,78.59 115.76,78.59 114.42,77.25 104.9,77.25 103.95,76.3 101.47,76.3 100.96,75.79 96.81,75.79 v2(96.51,75.49)
  IN2 w0.254: v2(67.65,36.32) 67.65,36.03 65.88,34.26 64.59,34.26 63.89,33.56 62.49,33.56 61.35,32.42 61.35,31.95 57.44,28.04 v2(53.15,28.04)
SLICE_BAT_PRES#: length 306
  TOP w0.102: UE1.B33 250.77,62.01 251.04,62.28 v2(251.04,62.59) ; RE5.2 247.12,61.71 v2(247.76,62.35)
  TOP w0.254: PR854.2 74.54,29.38 v2(73.91,30.01) 73.65,30.27 72.24,30.27 71.8,30.71 71.8,33.96 71.12,34.65 69.2,34.65 68.89,34.34 68.89,34.14 68.3,33.54 66.71,33.54 65.96,34.29 59.09,34.29 v2(57.97,35.41) ; v2(46.39,16.76) v1(46.39,15.8) PR6.1
  IN3 w0.122: v2(251.04,62.59) 250.62,62.17 247.94,62.17 v2(247.76,62.35) 248.21,62.79 248.21,63.97 247.41,64.77 247.41,66.73 245.94,68.2 245.94,71.28 236.72,80.49 235.44,80.49 233.86,82.08 233.86,83.55 232.53,84.87 232.53,86.99 230.95,88.57 226.59,88.57 226.39,88.38 209.09,88.38 208.95,88.24 205.81,88.24 205.05,87.48 176.29,87.48 170.11,93.65 v2(170.11,94.23) 169.43,94.92 169.43,95.55 168.39,96.59 165.85,96.59 164.98,97.46 159.72,97.46 158.57,98.61 157.01,98.61 151.04,92.64 146.47,92.64 144.38,90.55 133.25,90.55 132.65,89.95 129.77,89.95 127.49,87.68 124.79,87.68 121.06,83.95 111.81,83.95 110.32,82.46 110.32,81.61 108.89,80.18 105.92,80.18 104.49,78.75 104.49,75.7 102.9,74.11 102.9,73.49 98.52,69.12 98.52,68.19 97.09,66.75 97.09,63.79 94.61,61.32 94.61,57.57 91.88,54.84 90.99,54.84 90,53.85 83.34,53.85 v2(82.42,52.93) 83.06,52.3 83.06,47.6 82.29,46.84 82.29,38.52 82.03,38.26 82.03,34.39 80,32.36 76.72,32.36 74.37,30.01 v2(73.91,30.01)
  IN4 w0.254: v2(46.39,16.76) 46.58,16.76 47.04,17.22 47.04,19.84 47.81,20.61 47.81,23.98 57.97,34.14 v2(57.97,35.41)
  BOTTOM w0.102: JDOCK1.143 170.45,94.57 v2(170.11,94.23) 169.95,94.4 JDOCK1.141
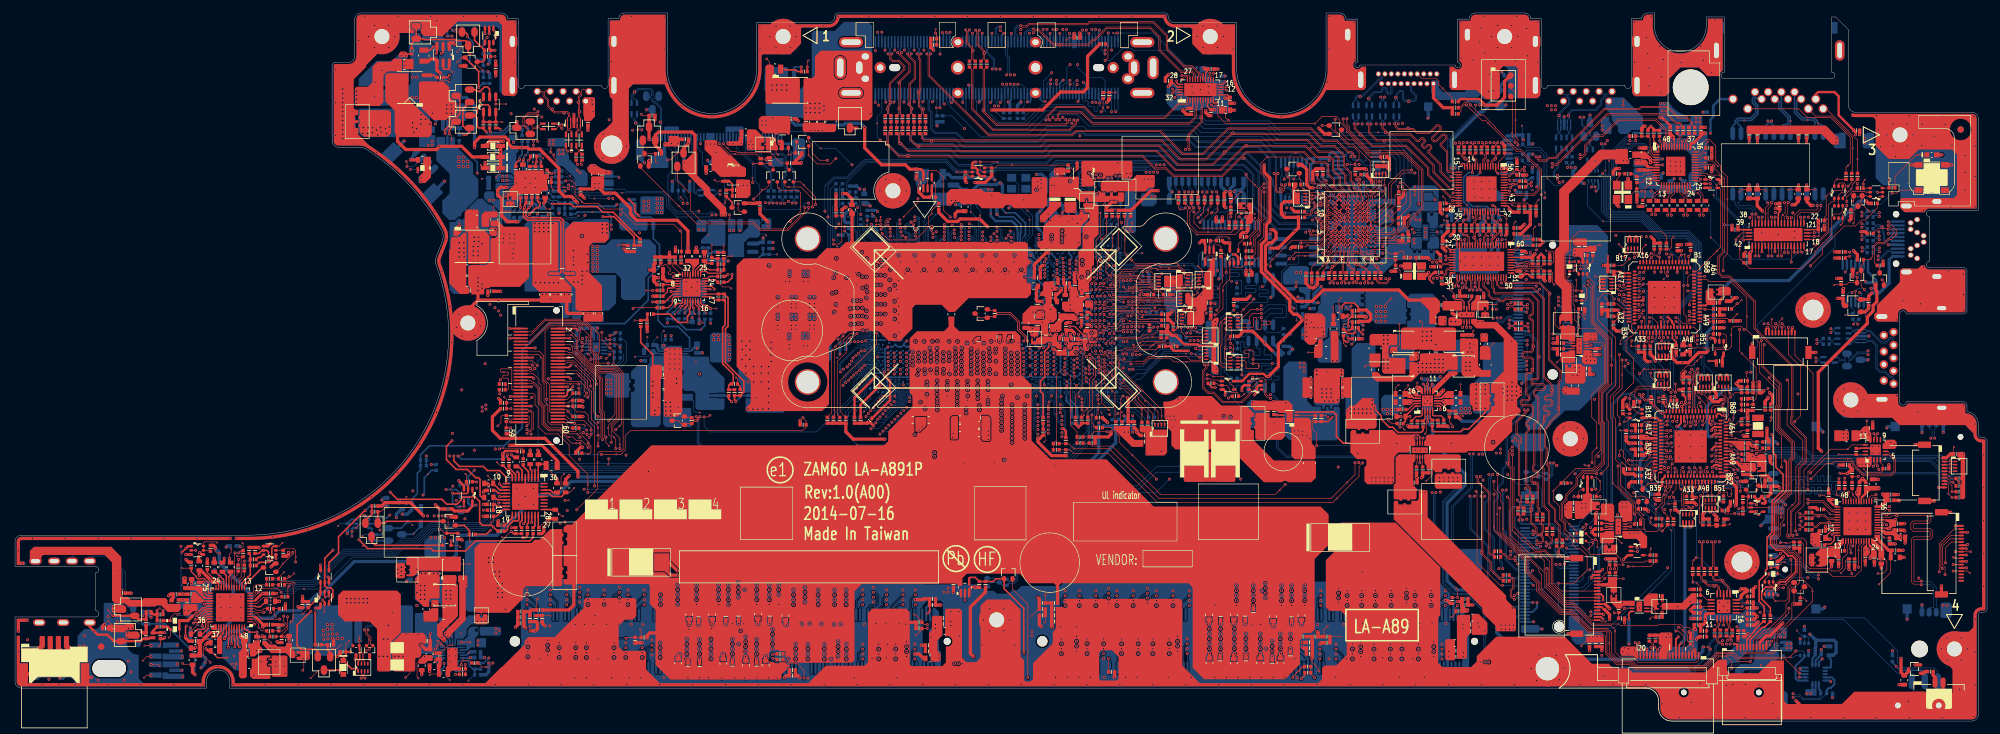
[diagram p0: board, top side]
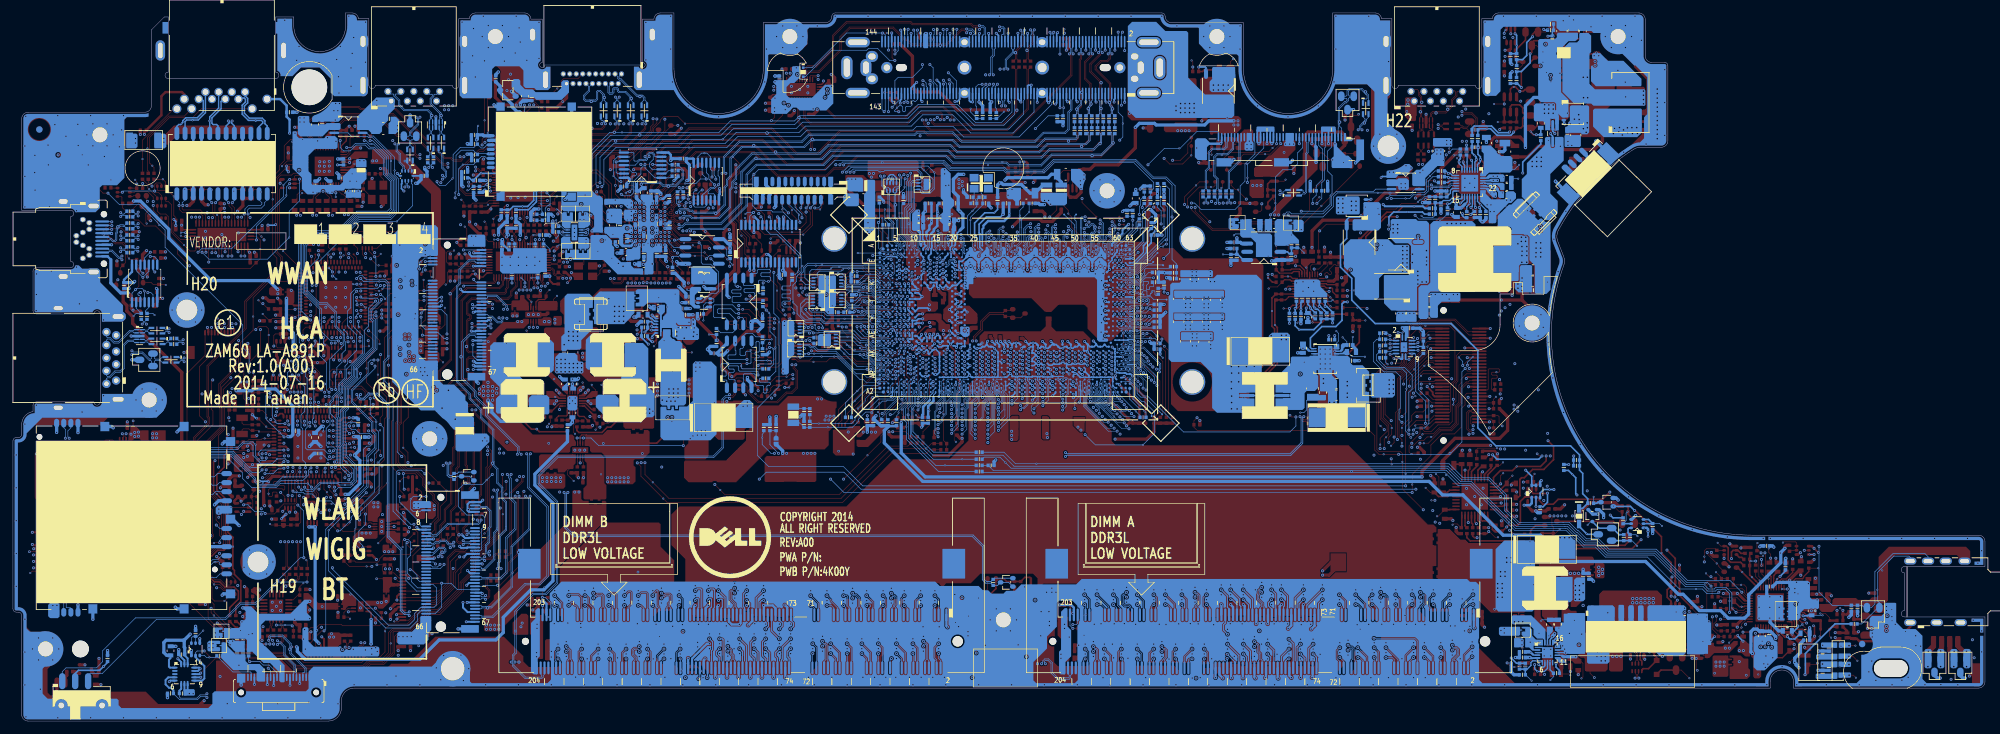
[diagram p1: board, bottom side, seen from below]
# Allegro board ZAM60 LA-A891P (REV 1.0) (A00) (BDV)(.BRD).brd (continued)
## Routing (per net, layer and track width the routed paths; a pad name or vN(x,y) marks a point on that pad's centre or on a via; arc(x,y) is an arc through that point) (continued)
SM_RCOMP0: length 8.8
  TOP w0.381: RC130.1 v1(133.51,47.88) 135.21,49.59 135.21,52.56 v2(134.37,53.4)
  BOTTOM w0.229: v2(134.37,53.4) 134.37,53.4 134.37,52.98 UC1.AU60
SM_RCOMP1: length 6.8
  TOP w0.381: RC131.1 130.68,48.93 v1(131.62,49.87) v2(133.74,52)
  BOTTOM w0.229: v2(133.74,52) 133.93,52.18 UC1.AV60
SM_RCOMP2: length 8.2
  TOP w0.381: RC132.1 129.73,50 v1(131.98,52.25) v2(133.03,53.3)
  BOTTOM w0.229: v2(133.03,53.3) 133.22,53.11 UC1.AU61
SMART_DET#: length 1.4
  TOP w0.102: UE1.A15 251.62,71.69 T99.1
SML0_SMBCLK: length 204.4
  TOP w0.102: UL1.28 260.18,84.79 260.25,84.72 261.39,84.72 261.68,84.43 263.33,84.43 263.9,83.86 263.9,72.55 263.14,71.79 263.14,69.25 263.78,68.62 264.92,68.62 268.71,64.82 268.71,60.69 274.53,54.87 274.53,47.12 274.37,46.96 274.37,46.01 276.62,43.76 276.62,40.15 275.61,39.14 275.61,33.73 274.34,32.46 274.34,30.44 274.34,30.43 274.34,28.86 v2(274.17,28.69)
  IN4 w0.089: v2(173.26,56.67) 173.26,57.39 173.55,57.67 181.31,57.67 182,58.36 182,58.6 v2(182.23,58.83) 182.06,59 182.06,59.08 182.26,59.29 183.59,59.29 183.82,59.06 183.82,58.72 183.07,57.97 183.07,57.51 182.09,56.53 182.09,52.65 185.39,49.35 185.39,46.05 186.39,45.05 188.57,45.05 190.13,43.49 190.13,40.3 201.78,28.65 232.27,28.65 235.12,25.8 235.91,25.8 236.32,25.39 236.32,24.66 237.13,23.85 237.13,23.44 238.06,22.52 245.99,22.52 246.29,22.82 260.89,22.82 265.7,27.62 271.84,27.62 273.31,29.1 274.25,29.1 274.35,28.99 274.35,28.87 v2(274.17,28.69)
  BOTTOM w0.076: UC1.AN1 170.9,55.16 171.6,55.16 172.67,56.23 172.67,56.23 172.77,56.32 172.92,56.32 v2(173.26,56.67)
  BOTTOM w0.102: RC33.2 181.76,59.29 v2(182.23,58.83)
SML0_SMBDATA: length 204.2
  TOP w0.102: v2(274.75,28.69) 274.57,28.87 274.57,30.34 274.57,30.34 274.57,32.36 275.84,33.63 275.84,39.05 276.84,40.05 276.84,43.86 274.6,46.11 274.6,46.86 274.76,47.03 274.76,54.96 268.94,60.78 268.94,64.92 265.01,68.85 263.87,68.85 263.37,69.35 263.37,71.7 264.16,72.49 264.16,83.93 262.7,85.39 262.7,85.86 262.46,86.11 261.94,86.11 261.89,86.06 260.78,86.06 260.71,85.99 UL1.31
  IN4 w0.089: v2(274.75,28.69) 274.57,28.87 274.57,29.08 274.34,29.31 273.23,29.31 271.75,27.84 265.61,27.84 260.8,23.03 246.2,23.03 245.9,22.73 238.15,22.73 237.35,23.53 237.35,23.94 236.53,24.75 236.53,25.48 236,26.02 235.21,26.02 232.36,28.86 201.87,28.86 190.34,40.38 190.34,43.58 188.66,45.26 186.48,45.26 185.61,46.14 185.61,49.44 182.31,52.74 182.31,56.44 183.28,57.42 183.28,57.88 184.04,58.63 184.04,59.15 183.68,59.51 182.17,59.51 181.84,59.17 181.84,59.06 v2(181.62,58.84) 181.78,58.68 181.78,58.45 181.22,57.89 173.08,57.89 172.87,58.1 v2(172.87,58.13)
  BOTTOM w0.081: v2(172.87,58.13) 172.86,58.15 172.73,58.15 172,57.42 170.91,57.42 UC1.AK1
  BOTTOM w0.102: RC34.2 181.18,58.4 v2(181.62,58.84)
SML1_SMBCLK: length 115.4
  TOP w0.102: v2(259.7,45.78) 260.33,46.42 260.33,46.59 260.44,46.7 UE2.B6
  IN1 w0.089: v2(182.45,60.86) 182.29,61.02 182.29,61.13 182.46,61.3 183.14,61.3 185.84,58.6 185.84,57.29 186.76,56.36 191.65,56.36 197.96,50.05 200.94,50.05 202.87,48.12 203.98,48.12 207.62,44.49 233.54,44.49 241.19,52.14 257.39,52.14 258.24,51.3 258.24,50.93 259.3,49.87 259.3,46.18 v2(259.7,45.78)
  IN4 w0.089: v2(182.45,60.86) 182.45,60.22 181.54,59.31 181.05,59.31 180.27,58.52 172.69,58.52 172.22,58.05 172.22,56.2 171.83,55.81 171.83,54.76 v2(172.2,54.39)
  BOTTOM w0.076: UC1.AU3 169.64,52.86 170.04,53.26 170.29,53.26 170.42,53.39 170.42,53.66 170.59,53.83 171.77,53.83 172.2,54.26 v2(172.2,54.39)
  BOTTOM w0.102: RPC14.3 182.59,61 v2(182.45,60.86)
SML1_SMBDATA: length 109.3
  TOP w0.102: UE2.A5 260.69,48.53 v2(260.52,48.69)
  IN1 w0.089: v2(181.85,60.86) 182.08,61.09 182.08,61.22 182.37,61.51 183.23,61.51 186.05,58.69 186.05,57.38 186.85,56.58 191.74,56.58 198.05,50.27 201.03,50.27 202.96,48.34 204.07,48.34 207.7,44.7 233.45,44.7 241.1,52.36 257.48,52.36 258.45,51.39 258.45,51.02 259.51,49.95 259.51,49.19 260.02,48.69 260.49,48.69 v2(260.52,48.69)
  BOTTOM w0.076: UC1.AH3 169.74,57.75 170.25,57.75 170.49,57.99 170.49,58.16 170.65,58.32 170.9,58.32 170.9,58.32 170.91,58.32 171.12,58.11 171.14,58.09 171.76,58.09 172.85,59.17 173.36,59.17
  BOTTOM w0.102: RPC14.4 182.49,61.5 v2(181.85,60.86) 181.44,61.26 v1(180.78,61.26) 180.78,60.68 180.46,60.36 176.91,60.36 176.88,60.34 174.72,60.34 173.56,59.17 173.36,59.17
SNB_1.05V: length 1.4
  TOP w0.102: PR305.2 v1(199.84,57)
SNUB_1.35V:
  vias: v1(63.46,15.57)
SNUB_3V: length 1.8
  TOP w0.102: v1(228.48,58.42) 227.7,57.63 PC111.1
SNUB_5V: length 1.7
  TOP w0.102: PC114.1 208.82,55.04 v1(208.59,54.81)
SOFT_START_GC: length 94.9
  TOP w0.254: PU800.2 v2(80.35,38.8)
  IN4 w0.254: v2(68.2,106.96) 68.51,106.64 68.51,104.27 68.02,103.77 68.02,100.49 71.64,96.88 71.96,96.88 77.56,91.27 80.97,91.27 82.04,90.2 82.04,87.99 83.98,86.04 85.19,86.04 93.41,77.83 93.41,75.3 92.76,74.65 92.76,66.89 89.48,63.61 89.48,62.79 88.42,61.73 86.4,61.73 83.49,58.82 79.92,58.82 77.72,56.62 77.72,51.01 77.93,50.8 77.93,44.03 79.37,42.58 79.82,42.58 80.2,42.2 80.2,38.96 v2(80.35,38.8)
  BOTTOM w0.254: v2(68.2,106.96) 68.08,106.84 PR17.2
SPI_CLK32: length 17
  TOP w0.102: v2(191.32,55.28) 192.08,55.28 192.21,55.16 v1(192.21,54.9) 192.21,54.65 192.08,54.52 190.37,54.52 190.24,54.65 190.24,55.47 189.99,55.73 RPC12.7
  BOTTOM w0.102: v2(191.32,55.28) 190.81,55.28 190.69,55.41 190.69,57.06 190.81,57.19 191.39,57.19 191.51,57.06 191.51,56.68 191.64,56.55 192.28,56.55 192.4,56.68 192.4,57.51 192.28,57.63 192.01,57.63 191.88,57.76 UC3.6 191.88,59.55 191.51,59.92 190.43,59.92 189.94,59.42 RC61.2
SPI_CLK64: length 17.1
  TOP w0.102: RPC11.6 189.23,61.39 189.34,61.51 190.64,61.51 v3(190.76,61.63) 190.76,62.56 191.23,63.03 v2(192.59,63.03)
  BOTTOM w0.102: RC62.2 195.37,60.05 193.55,60.05 193.15,60.44 UC2.6 193.15,62.15 194.01,63 195.73,63 195.86,63.13 195.86,63.63 195.73,63.75 193.79,63.75 193.06,63.03 v2(192.59,63.03)
SPI_CLKTPM: length 3.8
  TOP w0.102: v2(187.88,77.96) 187.89,77.98 RZ35.2 187.73,78.57 187.41,78.26 187.41,77.37 RZ26.2
  BOTTOM w0.102: UZ1.21 187.63,77.72 v2(187.88,77.96)
SPI_DIN32: length 13
  TOP w0.102: v2(189.61,53.52) 189.61,54.27 189.14,54.73 RPC12.5
  BOTTOM w0.102: UC3.2 193.15,52.68 193.28,52.81 194.05,52.81 194.18,52.93 194.18,53.8 194.05,53.93 193.42,53.93 193.29,54.05 193.29,54.31 193.42,54.43 194.05,54.43 194.18,54.56 194.18,54.81 194.07,54.93 192.72,54.93 192.59,54.8 192.59,54.23 192.47,54.1 189.74,54.1 189.61,53.97 v2(189.61,53.52)
SPI_DIN64: length 13.2
  TOP w0.102: v2(191.45,65.25) v3(189.88,63.68) 189.49,63.3 189.49,62.72 189.16,62.39 RPC11.8
  BOTTOM w0.102: UC2.2 191.88,67.46 191.78,67.36 190.24,67.36 190.12,67.23 190.12,66.98 190.24,66.85 191.64,66.85 191.77,66.72 191.77,66.4 191.64,66.27 190.24,66.27 190.12,66.14 190.12,65.38 190.24,65.25 v2(191.45,65.25)
SPI_DINTPM: length 6.7
  TOP w0.102: RZ30.2 188.59,78.27 189.2,78.88 190.08,78.88 v2(190.31,78.65)
  BOTTOM w0.102: UZ1.26 190.88,78.08 v2(190.31,78.65) 191.31,78.65 v1(191.55,78.41)
SPI_DO32: length 13.2
  TOP w0.102: RPC12.6 189.35,55.23 v2(189.61,54.97)
  BOTTOM w0.102: UC3.5 190.61,57.89 190.48,57.76 190.05,57.76 189.93,57.89 189.93,58.58 189.8,58.71 189.54,58.71 189.42,58.58 189.42,57.19 189.54,57.06 189.95,57.06 190.08,56.93 190.08,56.71 189.95,56.58 189.55,56.58 189.43,56.46 189.43,56.29 189.55,56.17 189.98,56.17 190.08,56.07 190.08,55.86 189.98,55.76 v1(188.15,55.76) 187.69,55.76 187.56,55.63 187.56,55.34 187.69,55.21 189.48,55.21 189.61,55.09 v2(189.61,54.97)
SPI_DO64: length 13.4
  TOP w0.102: RPC11.7 189.23,61.89 191.01,63.66 v3(191.98,63.66) v2(192.59,63.66)
  BOTTOM w0.102: v2(192.59,63.66) 192.83,63.66 193.53,64.36 196.34,64.36 196.47,64.24 196.47,62.52 196.34,62.39 194.69,62.39 194.42,62.13 UC2.5
SPI_DOTPM: length 2.3
  TOP w0.102: RZ29.2 189.54,77.6 v2(189.16,77.98)
  BOTTOM w0.102: v2(189.16,77.98) 188.93,77.75 UZ1.23
SPI_PCH_CLK: length 35.1
  TOP w0.102: RPC12.2 187.26,55.73 186.94,56.04 v1(186.94,57.76) 187.13,57.95 v2(187.13,60.68) 187.13,60.87 187.65,61.39 RPC11.3 ; RC227.1 v2(182.8,81.83)
  IN1 w0.089: v2(187.13,60.68) 187.74,61.29 187.74,63.8 188.21,64.27 188.21,71.22 187.83,71.6 187.83,73.19 188.3,73.66 188.3,78.82 187.07,80.05 186.37,80.05 185.93,80.49 184.66,80.49 183.87,81.28 183.35,81.28 v2(182.8,81.83)
  BOTTOM w0.102: v2(182.8,81.83) 182.8,82.09 182.38,82.51 JSPI1.7
SPI_PCH_CS0#: length 22.1
  TOP w0.102: RC228.1 183.82,81.42 v2(184.22,81.83)
  IN1 w0.089: v2(188.81,67.76) 188.81,73.09 189.54,73.82 189.54,75.67 189.84,75.96 189.84,78.17 189.9,78.23 189.9,78.71 189.65,78.97 189.04,78.97 187.32,80.68 186.69,80.68 186.28,81.09 184.96,81.09 v2(184.22,81.83)
  BOTTOM w0.102: v2(184.22,81.83) 184.22,81.88 183.38,82.72 JSPI1.9 ; RC35.1 188.83,67.73 v2(188.81,67.76)
SPI_PCH_CS0#_R: length 12.9
  BOTTOM w0.102: UC2.1 190.61,69.09 190.51,69.19 189.86,69.19 189.74,69.32 189.74,69.7 189.61,69.82 187.83,69.82 187.7,69.7 187.7,69.44 187.83,69.32 189.04,69.32 189.16,69.19 189.16,68.87 189.04,68.74 187.83,68.74 187.7,68.62 187.7,68.11 187.83,67.98 v3(188.01,67.98) 188.4,67.98 188.59,68.17 189.42,68.17 189.54,68.05 189.54,66.2 189.42,66.07 RC35.2
SPI_PCH_CS1#: length 36.2
  TOP w0.102: v2(179.89,81.83) 179.75,81.68 RC224.1
  IN1 w0.089: v2(179.89,81.83) 181.72,80 183.26,80 184.16,79.1 185.16,79.1 186.12,78.14 186.12,71.41 186.31,71.22 186.31,69.13 186.87,68.56 186.87,64.74 186.18,64.05 186.18,59.4 v2(187.83,57.76)
  BOTTOM w0.102: JSPI1.1 179.38,82.33 v2(179.89,81.83) ; RC50.1 187.21,55.19 v1(187.21,57.51) 187.46,57.76 v2(187.83,57.76)
SPI_PCH_CS1#_R: length 12.9
  BOTTOM w0.102: RC50.2 192.02,54.46 192.15,54.58 192.15,55.16 192.28,55.28 v2(194.29,55.28) 195.2,55.28 195.32,55.16 195.32,54.27 195.2,54.14 194.66,54.14 194.54,54.01 194.54,53.44 194.64,53.34 195.2,53.34 195.32,53.21 195.32,52.87 195.2,52.74 194.55,52.74 194.42,52.62 UC3.1
SPI_PCH_DIN: length 36.7
  TOP w0.102: RPC11.1 187.24,62.39 v2(187.05,62.2) 186.88,62.2 v1(186.34,61.66) 186.17,61.49 186.17,58.41 185.93,58.17 185.93,55.41 186.6,54.73 RPC12.4 ; RC226.1 181.78,81.62 v2(181.99,81.83)
  IN1 w0.089: v2(187.05,62.2) 187.05,63.95 187.58,64.48 187.58,70.97 187.13,71.41 187.13,76.24 187.39,76.49 187.39,78.33 186.88,78.84 186.43,78.84 185.42,79.86 184.4,79.86 183.58,80.68 182.88,80.68 181.99,81.57 v2(181.99,81.83)
  BOTTOM w0.102: v2(181.99,81.83) 181.99,81.95 181.38,82.56 JSPI1.5
SPI_PCH_DO: length 36.8
  TOP w0.102: RPC12.3 186.61,55.23 186.31,55.53 186.31,58.01 186.52,58.23 186.52,61.35 186.75,61.57 v2(187.07,61.57) 187.39,61.89 RPC11.2 ; v2(180.77,81.83) RC225.1
  IN1 w0.089: v2(187.07,61.57) 186.53,62.11 186.53,63.91 187.21,64.6 187.21,68.73 186.75,69.19 186.75,76.43 187,76.68 187,78.21 186.75,78.46 186.31,78.46 185.29,79.48 184.29,79.48 183.42,80.34 182.25,80.34 v2(180.77,81.83)
  BOTTOM w0.102: JSPI1.3 180.38,82.21 v2(180.77,81.83)
SPI_PCH_DO2: length 39.1
  TOP w0.102: v2(185,81.83) 185,81.19 RC229.1 ; RC29.2 v2(188.34,63.55)
  IN1 w0.089: v2(188.34,63.55) 189.42,64.63 189.42,73.06 190.75,74.4 190.75,78.78 188.47,81.06 186.81,81.06 186.44,81.44 185.39,81.44 v2(185,81.83)
  BOTTOM w0.102: RC38.1 188.34,63.59 v2(188.34,63.55) 187.93,63.14 v1(187.94,63.14) 187.77,62.97 187.77,60.26 186.85,59.35 186.85,54.09 RC55.1 ; JSPI1.11 184.38,82.44 v2(185,81.83)
SPI_PCH_DO2_32: length 13.1
  BOTTOM w0.102: RC55.2 189.29,53 189.42,52.87 189.42,52.53 189.29,52.4 187.83,52.4 187.7,52.27 187.7,52.02 187.83,51.89 188.14,51.89 188.24,51.79 v1(188.24,51.16) 188.24,50.84 188.37,50.71 188.62,50.71 188.75,50.84 188.75,51.79 188.85,51.89 189.86,51.89 189.99,52.02 189.99,52.93 190.05,53 190.05,53.57 190.18,53.7 191.75,53.7 191.88,53.57 UC3.3
SPI_PCH_DO2_64: length 13.1
  BOTTOM w0.102: RC38.2 189.11,64.74 193.48,64.74 193.61,64.87 193.61,65.53 193.48,65.66 192.36,65.66 192.24,65.79 192.24,66.04 192.36,66.17 193.55,66.17 193.67,66.29 193.67,66.55 193.55,66.67 192.36,66.67 192.24,66.8 192.24,67.06 192.36,67.18 v2(192.76,67.18) 193.02,67.18 193.15,67.31 UC2.3
SPI_PCH_DO3: length 36.6
  TOP w0.102: RPC11.4 187.94,60.89 188.02,60.81 188.02,59.7 RC31.2 187.8,58.43 v2(187.83,58.4) 187.95,58.4 188.27,58.08 v1(188.27,57.51) 188.27,56.51 187.99,56.23 RPC12.1 ; v2(185.67,81.84) 185.85,81.66 RC230.1
  IN1 w0.089: v2(185.67,81.84) 186.55,81.84 186.94,81.44 188.59,81.44 191.13,78.9 191.13,74.27 189.8,72.94 189.8,62.01 187.83,60.05 v2(187.83,58.4)
  BOTTOM w0.102: v2(185.67,81.84) 185.38,82.12 JSPI1.13
SPI_PCH_DO3_32: length 12.8
  TOP w0.102: v2(191.32,55.92) 191.32,57.25 191.2,57.38 v1(190.75,57.38) 190.12,57.38 189.99,57.25 189.99,56.93 190.12,56.81 190.56,56.81 190.69,56.68 190.69,56.36 190.56,56.23 RPC12.8
  BOTTOM w0.102: UC3.7 193.15,57.38 193.02,57.25 193.02,56.74 193.15,56.62 194.12,56.62 194.24,56.49 194.24,56.04 194.12,55.92 v2(191.32,55.92)
SPI_PCH_DO3_64: length 12.9
  TOP w0.102: RPC11.5 191.25,60.89 191.37,61.02 191.37,62.29 191.5,62.42 191.75,62.42 191.88,62.29 191.88,60.68 192.01,60.55 192.47,60.55 192.59,60.68 192.59,61.23 192.69,61.33 v3(193.28,61.33) 193.93,61.33 194.05,61.46 194.05,61.71 193.93,61.84 192.69,61.84 192.59,61.94 v2(192.59,62.39)
  BOTTOM w0.102: UC2.7 191.88,62.25 192.02,62.39 v2(192.59,62.39)
SPKR: length 225.1
  TOP w0.102: v2(42.67,15.37) 42.99,15.68 v1(42.99,16.1) 42.99,20.95 42.63,21.31 41.9,21.31 RA12.2 ; v2(173.53,63.36) 173.53,63.23 173.86,62.9 RC180.2
  IN3 w0.122: v2(173.53,63.36) 173.46,63.29 171.88,63.29 170.67,64.5 170.67,65.48 170.54,65.61 170.54,75.95 169.73,76.76 169.73,77.51 164.58,82.66 164.58,87.05 166.23,88.71 166.23,93.75 164.84,95.14 163.94,95.14 163.58,95.49 159.81,95.49 159.45,95.14 158.69,95.14 149.58,86.03 130.93,86.03 130.5,86.46 127.89,86.46 123.76,82.33 114.83,82.33 111.34,78.84 106.42,78.84 104.99,77.41 104.99,75.44 103.39,73.84 103.39,73.28 99.02,68.91 99.02,67.98 97.6,66.56 97.6,63.54 95.12,61.06 95.12,57.36 92.09,54.33 91.25,54.33 90.27,53.35 85.63,53.35 84.83,52.55 84.83,40.3 82.54,38 82.54,34.13 80.26,31.85 76.95,31.85 73.84,28.74 72.83,28.74 70.23,26.14 59.31,26.14 57.72,24.55 53.97,24.55 51.13,21.71 51.13,20.17 49.15,18.19 49.15,17.78 47.38,16.01 44.36,16.01 43.93,15.58 42.89,15.58 v2(42.67,15.37)
  BOTTOM w0.076: 173.36,63.35 171.24,63.35 170.89,63 170.56,63 170.27,63.29 UC1.V2
  BOTTOM w0.102: 173.36,63.35 173.52,63.35 v2(173.53,63.36)
SRCDET: length 5.3
  TOP w0.102: RV84.1 201.28,69.58 v1(202.08,70.38) 204,72.29 204,72.97 UV8.C2
SRTCRST#: length 30.5
  IN4 w0.089: v2(187.07,41.4) 187.07,41.5 186.7,41.87 179.26,41.87 173.91,47.22 v2(172.72,47.22) 171.57,48.36 170.24,48.36 167.03,51.57 v2(167.03,51.87)
  BOTTOM w0.081: v2(167.03,51.87) 167.1,51.87 167.41,52.18 UC1.AV6
  BOTTOM w0.102: v2(187.07,41.4) 187.6,41.4 188.96,42.76 v1(188.96,43.84) 188.96,44.35 188.72,44.59 RC10.2 ; CC3.2 v2(172.72,47.22)
STSTART_DCBLOCK_GC: length 113.3
  TOP w0.102: PU800.16 v2(74.76,33.72) ; v2(122.42,101.14) 122.42,101.97 v1(122.62,102.16)
  TOP w0.254: v2(122.42,101.14) PR811.2
  IN1 w0.089: v2(68.18,34.11) 74.37,34.11 v2(74.76,33.72)
  IN3 w0.122: v2(68.18,34.11) 68.37,34.11 69.07,34.81 69.07,39.84 69.78,40.55 69.78,47.58 73.97,51.77 73.97,53.96 80.32,60.31 83.61,60.31 91.87,68.57 91.87,74.23 92.96,75.32 92.96,78.81 93.61,79.46 93.61,80.44 93.02,81.02 93.02,85.38 96.38,88.73 111.68,88.73 112.42,88 114.4,88 121.49,95.08 121.49,95.68 122.42,96.62 v2(122.42,101.14)
SUS_ON: length 243.4
  TOP w0.102: v3(256.58,52.13) v2(256.58,50.85) 256.54,50.85 255.72,51.67 254.56,51.67 254.37,51.86 RPE10.2 ; 251.75,29.68 251.75,29.67 252.08,29.34 253.76,29.34 254.49,30.07 RE281.2 RE282.2 ; 251.75,29.68 251.76,29.68 UL3.3 ; 251.75,29.68 251.75,31.18 250.71,32.22 250.66,32.22 250.39,32.49 250.39,33.62 247.72,36.29 v2(247.72,39.45) ; PR207.1 68.08,7.23 v2(68.07,7.21)
  IN1 w0.089: v2(247.72,39.45) 248.66,40.39 248.66,42.96 249.22,43.52 252.99,43.52 253.92,44.45 256.49,44.45 257.41,45.37 257.41,47.26 257.93,47.79 257.93,49.5 v2(256.58,50.85)
  IN2 w0.122: v2(247.72,39.45) 247.18,38.9 240.66,38.9 234.57,32.81 234.57,31.41 233.66,30.5 85.64,30.5 85.47,30.33 84.52,30.33 v2(84.26,30.58)
  IN3 w0.122: v2(84.26,30.58) 84.26,27.47 78.04,21.25 78.04,14.52 77.47,13.94 75.75,13.94 69.02,7.21 v2(68.07,7.21)
SUS_ON_EC: length 19.8
  TOP w0.102: UE2.B23 255.18,43.96 255.23,44.01 v2(255.23,44.02) ; RE281.1 253.02,30.28 252.7,30.59 v1(252.7,30.73) 252.7,31.28 v2(252.84,31.42)
  IN1 w0.089: v2(255.23,44.02) 254.67,43.46 254.67,41.66 255,41.33 256.02,41.33 256.41,40.93 256.41,40.47 256.93,39.95 256.93,37.85 256.8,37.72 256.8,35.23 256.98,35.05 256.98,34.21 256.12,33.35 254.77,33.35 v2(252.84,31.42)
SUS_STAT#/LPCPD#: length 8.8
  TOP w0.102: v2(169.26,58.42) 169.93,59.09 174.42,59.09 174.61,59.28 v1(174.99,59.28) 175.02,59.26 RC82.2
  BOTTOM w0.081: UC1.AG4 168.88,58.83 169.26,58.46 v2(169.26,58.42)
SUSACK#: length 134.9
  TOP w0.102: RC81.2 177.43,58.69 174.03,58.69 v1(173.84,58.5) 173.03,57.7 171.55,57.7 171.18,57.32 170.23,57.32 v2(169.84,56.93) ; v2(252.11,43.12) 252.29,43.3 253.03,43.3 253.12,43.21 UE2.A23
  IN1 w0.089: v2(252.11,43.12) 252.11,42.74 254.39,40.46 255.23,40.46 255.61,40.08 255.61,39.71 255.95,39.37 255.95,38.92 255.8,38.77 255.8,38.11 255.47,37.78 255.47,35.01 253.93,33.48 253.93,32.87 252.91,31.84 251.03,31.84 250.72,31.53 248.43,31.53 248.04,31.92 v2(247.65,31.92)
  IN3 w0.081: v2(169.84,56.93) 170.31,56.93 170.86,56.37 172.46,56.37 173.36,55.47
  IN3 w0.122: v2(247.65,31.92) 246.44,30.72 246.44,30.08 244.86,28.5 244.07,28.5 242.98,27.41 242.98,26.42 239.68,23.12 237.33,23.12 236.76,22.55 229.12,22.55 227.56,24.1 206.66,24.1 203.51,27.25 193.47,27.25 180.01,40.71 180.01,41.72 180.17,41.88 180.17,47.75 179.32,48.6 176.24,48.6 173.45,51.39 173.45,55.38 173.36,55.47
  BOTTOM w0.081: UC1.AK2 170.13,57.23 v2(169.84,56.93)
SUSCLK: length 119.6
  TOP w0.102: v2(175.98,60.93) 175.4,60.35 RC136.2 ; v2(242.78,30.43) 242.78,29.78 242.17,29.17 242.17,27.09 243.49,25.77 247.41,25.77 248.1,25.07 248.1,24.82 248.35,24.57 251.76,24.57 251.94,24.75 RZ56.1
  IN3 w0.122: v2(241.08,38.24) 240.14,38.24 239.52,37.61 237.25,37.61 233.44,33.8 233.44,33.45 232.75,32.76 231.71,32.76 230.05,31.09 228.92,31.09 228.08,30.25 210.57,30.25 207.36,33.46 198.05,33.46 191.86,39.65 191.86,45.76 189.43,48.19 189.43,49.87 188.42,50.88 188.42,54 185.55,56.88 185.55,58.4 182.54,61.41 176.42,61.41 175.98,60.97 v2(175.98,60.93)
  BOTTOM w0.102: v2(242.78,30.43) 243.27,30.43 v1(244.1,31.27) 245.51,32.68 245.51,38.51 245.22,38.8 241.65,38.8 v2(241.08,38.24)
SUSCLK_R: length 8.9
  TOP w0.102: v2(167.65,60.03) 168.02,60.39 168.83,60.39 169.09,60.64 170.32,60.64 171.1,61.43 175.16,61.43 RC136.1
  BOTTOM w0.081: v2(167.65,60.03) 167.5,59.87 UC1.AE6
SW1: length 5.2
  IN1 w1.016: 214.99,49.83 211.86,52.97 211.86,53.7
  vias: v1(211.87,57.02) v2(215.44,49.07) v2(215.87,49.47) v4(211.52,59.6) v4(211.52,58.97) v4(211.52,58.33) v4(211.52,55.85) v4(211.52,55.22) v4(211.52,54.58) v4(212.15,59.6) v4(212.15,58.97) v4(212.15,58.33) v4(212.15,55.85) v4(212.15,55.22) v4(212.15,54.58)
SW2: length 4.4
  IN1 w1.016: 221.83,50.12 224.52,52.81 224.52,53.45
  vias: v1(225.51,58.19) v2(220.75,49.52) v2(221.08,49.04) v4(224.2,56.43) v4(224.2,55.48) v4(224.2,54.85) v4(224.2,54.21) v4(224.52,57.07) v4(224.84,58.34) v4(224.84,57.7) v4(224.84,56.43) v4(224.84,55.48) v4(224.84,54.85) v4(224.84,54.21) v4(225.15,57.07)
SW_1.35V:
  vias: v1(65.85,14.38) v2(65.96,12.94) v2(66.34,12.49) v4(66.33,17.88) v4(66.55,21.12) v4(66.61,20.17) v4(66.61,19.53) v4(66.61,18.9) v4(66.99,17.88) v4(67.18,21.12) v4(67.31,20.17) v4(67.31,19.53) v4(67.31,18.9) v4(67.65,17.88) v4(67.82,21.12)
SW_10_GRN#: length 27.6
  TOP w0.102: QL2.1 282.45,78.86 281.99,78.4 281.13,78.4 280.75,78.02 280.75,75.25 278.14,72.64 278.14,71.96 276.14,69.96 268.1,69.96 RL30.2 266.53,71.52 v1(266.53,72.97) 266.53,74.4 267.12,74.98 UL4.41
SW_100_ORG#: length 12.9
  TOP w0.102: QL1.4 282.45,82.15 282.32,82.02 280.78,82.02 v1(279.89,81.14) 279.89,78.18 279.59,77.87 RL29.2 280.02,76.97 280.02,75.64 278.86,74.48 UL4.18
SW_+V1.05SP:
  vias: v1(204.12,58.83) v4(203.62,55.68) v4(204.25,55.68)
SW_ACTLED_YEL#: length 11.5
  TOP w0.102: UL4.17 276.46,72.88 276.65,72.69 277.39,72.69 v1(278.3,73.6) 280.25,75.54 280.25,79.84 280.72,80.31 281.05,80.31 281.15,80.41 QL1.1
SW_DPB_AUX: length 14
  TOP w0.102: RV75.1 207.45,84.15 207.45,83.96 v2(207.27,83.77) 207.64,83.4 v4(207.64,83.01) 207.64,82.09 207.86,81.88 207.86,81.03 208.08,80.8 208.28,80.8 208.34,80.75 208.34,80.56 UV8.J13
  BOTTOM w0.102: CV119.2 201.78,85.32 201.55,85.32 201.34,85.1 201.34,83.92 202.35,82.91 203.17,82.91 203.19,82.93 203.74,82.93 203.76,82.91 204.24,82.91 204.67,83.34 207.34,83.34 207.45,83.45 207.45,83.59 v2(207.27,83.77)
SW_DPB_AUX#: length 14.1
  TOP w0.102: RV82.1 207.66,84.17 207.66,83.96 v2(207.85,83.77) 207.85,83.3 207.87,83.28 207.87,82.85 207.85,82.83 207.85,82.18 208.07,81.96 208.07,81.23 UV8.J14
  BOTTOM w0.102: v2(207.85,83.77) 207.66,83.58 207.66,83.37 207.42,83.13 204.75,83.13 204.32,82.7 v4(203.46,82.7) 202.26,82.7 201.13,83.83 201.13,85.19 CV120.2
SW_DPB_AUX#_C: length 1.9
  BOTTOM w0.102: UV11.5 203.89,86.61 203.31,86.02 CV120.1
SW_DPB_AUX_C: length 1.9
  BOTTOM w0.102: CV119.1 203.39,85.14 203.87,84.66 UV11.2
SW_DPC_AUX: length 7.1
  TOP w0.102: UV8.B11 203.32,79.48 202.78,79.48 202.22,80.05 202.02,80.05 v2(201.79,80.28) 201.51,80 201.27,80 v4(200.92,79.65) 200.26,78.99 200.26,78.59 200.11,78.44 199.6,78.44 RV74.1
  BOTTOM w0.102: CV122.2 201.17,80.64 201.53,80.28 v2(201.79,80.28)
SW_DPC_AUX#: length 6.9
  TOP w0.102: UV8.A11 203.01,79.1 202.91,78.99 202.7,78.99 202.63,79.07 202.63,79.35 202.18,79.79 201.88,79.79 v2(201.78,79.69) 201.68,79.79 201.39,79.79 200.87,79.27 200.84,79.27 200.47,78.9 200.47,78.51 200.2,78.24 199.6,78.24 RV85.1
  BOTTOM w0.102: v2(201.78,79.69) 201.94,79.84 201.99,79.84 202.19,80.05 202.19,80.78 CV123.2
SW_DPC_AUX#_C: length 9.1
  IN4 w0.089: v2(201.79,82.51) 201.79,82.46 201.6,82.26 201.6,81.93 201.37,81.7 199.72,81.7 198.67,80.64 197.83,80.64 v2(196.54,79.36)
  BOTTOM w0.102: UV12.5 196.95,79.85 196.54,79.44 v2(196.54,79.36) ; v2(201.79,82.51) 201.64,82.35 201.64,82.12 201.91,81.84 CV123.1
SW_DPC_AUX_C: length 9.1
  IN4 w0.089: v2(201.2,82.51) 201.25,82.51 201.43,82.33 201.43,82 201.3,81.87 199.65,81.87 198.6,80.81 197.93,80.81 197.85,80.89 197.85,82 197.97,82.12 v2(198.23,82.12)
  BOTTOM w0.102: v2(198.23,82.12) 198.36,82.12 198.9,81.58 UV12.2 ; CV122.1 201.24,81.84 201.38,81.98 201.38,82.36 201.23,82.51 v2(201.2,82.51)
SW_LAN_TX0+: length 7
  TOP w0.094: v2(268.42,78.4) 268.52,78.3 268.52,77.58 268.46,77.52 268.46,77.4 UL4.38
  BOTTOM w0.094: v2(268.42,78.4) 268.52,78.51 268.52,79.01 268.21,79.32 266.36,79.32 265.9,79.78 265.9,80.15 265.45,80.59 TL1.12
SW_LAN_TX0-: length 7
  TOP w0.094: UL4.37 268.96,77.58 268.9,77.64 268.9,78.3 v2(269,78.4)
  BOTTOM w0.094: TL1.11 266.72,80.59 266.28,80.15 266.28,79.94 266.52,79.7 268.37,79.7 268.9,79.17 268.9,78.51 v2(269,78.4)
SW_LAN_TX1+: length 5
  TOP w0.094: v2(270.85,80.16) 270.98,80.04 270.98,79.83 270.52,79.38 v1(270.52,78.49) 270.52,77.65 270.46,77.59 270.46,77.4 UL4.34
  BOTTOM w0.094: TL1.8 270.53,80.48 v2(270.85,80.16)
SW_LAN_TX1-: length 5
  TOP w0.094: v2(271.43,80.16) 271.36,80.08 271.36,79.67 270.9,79.22 270.9,77.64 270.96,77.58 UL4.33
  BOTTOM w0.094: v2(271.43,80.16) 271.8,80.53 TL1.7
SW_LAN_TX2+: length 5
  TOP w0.094: UL4.29 272.96,77.52 273.02,77.58 273.02,78.08 v1(273.19,78.25) 273.54,78.61 273.54,80.06 v2(273.44,80.16)
  BOTTOM w0.094: v2(273.44,80.16) 273.07,80.53 TL1.6
SW_LAN_TX2-: length 5
  TOP w0.094: v2(274.03,80.16) 273.92,80.06 273.92,78.45 273.4,77.93 273.4,77.46 273.46,77.4 UL4.28
  BOTTOM w0.094: v2(274.03,80.16) 274.34,80.48 TL1.5
SW_LAN_TX3+: length 7.9
  TOP w0.094: v2(278.49,79.73) 278.6,79.63 278.6,79.21 278.41,79.03 275.79,79.03 275.02,78.27 275.02,77.64 274.96,77.58 UL4.25
  BOTTOM w0.094: v2(278.49,79.73) 278.6,79.83 278.6,80.15 278.15,80.59 TL1.2
SW_LAN_TX3-: length 7.9
  TOP w0.094: v2(279.08,79.73) 278.98,79.63 278.98,79.06 278.57,78.65 275.94,78.65 275.4,78.11 275.4,77.64 275.46,77.58 UL4.24
  BOTTOM w0.094: v2(279.08,79.73) 278.98,79.83 278.98,80.15 279.42,80.59 TL1.1
SW_MDP_AUX#_C: length 3.3
  BOTTOM w0.102: v1(282.86,62.79) 283.12,63.04 CV513.1 284.29,63.3 284.29,63.41 283.75,63.95 UV502.5
SW_MDP_AUX_C: length 3.4
  BOTTOM w0.102: UV502.2 285.7,63.82 CV512.1 285.71,63.04 v1(286.12,62.64)
SW_USB3RN1: length 113.5
  TOP w0.102: v2(85.39,88.13) 85.15,88.38 LI1.4 ; UI4.26 181.58,99.69 181.44,99.83 180.35,99.83 v2(180.32,99.8)
  IN1 w0.089: v2(180.32,99.8) 180.53,99.59 180.7,99.59 180.79,99.68 180.79,102.04 176.24,106.59 172.42,106.59 170.85,105.02 162.84,105.02 160.77,102.94 144.77,102.94 142.4,100.57 140.59,100.57 136.47,96.45 132.86,96.45 124.36,87.94 115.33,87.94 114.54,87.16 112.73,87.16 111.95,87.94 96.85,87.94 94.63,85.72 90.73,85.72 89.22,87.22 85.91,87.22 85.6,87.54 85.6,87.93 v2(85.39,88.13)
SW_USB3RP1: length 113.3
  TOP w0.102: LI1.1 86,88.1 v2(85.98,88.08) ; v2(180.32,99.22) 180.72,99.62 181.13,99.62 181.18,99.56 UI4.27
  IN1 w0.089: v2(85.98,88.08) 85.97,88.08 85.84,87.95 85.77,87.88 85.77,87.61 85.98,87.39 89.29,87.39 90.8,85.89 94.56,85.89 96.78,88.11 112.02,88.11 112.8,87.33 114.47,87.33 115.26,88.11 124.29,88.11 132.79,96.62 136.4,96.62 140.52,100.74 142.33,100.74 144.7,103.11 160.7,103.11 162.77,105.19 170.78,105.19 172.35,106.76 176.31,106.76 180.96,102.11 180.96,99.61 180.77,99.42 180.53,99.42 v2(180.32,99.22)
SW_USB3TN1: length 112.5
  TOP w0.102: UI4.30 179.53,97.64 179.34,97.45 179.15,97.45 v2(178.89,97.71) ; v2(86.93,86.08) 86.71,86.29 CI4.2
  IN1 w0.089: v2(178.89,97.71) 179.17,97.43 179.44,97.43 179.53,97.52 179.53,97.88 178.8,98.61 178.8,103.11 175.97,105.95 172.69,105.95 171.12,104.38 163.11,104.38 161.03,102.3 145.04,102.3 142.67,99.93 140.95,99.93 135.01,93.99 131.31,93.99 124.56,87.24 115.83,87.24 115.1,86.52 111.99,86.52 111.26,87.24 97.52,87.24 94.47,84.2 91.17,84.2 90.48,84.89 87.82,84.89 87.17,85.55 87.17,85.84 v2(86.93,86.08)
SW_USB3TP1: length 112.7
  TOP w0.102: CI5.2 87.54,86.74 87.35,86.55 87.35,86.19 87.47,86.08 v2(87.51,86.08) ; v2(178.89,97.12) 179.02,97.24 UI4.31
  IN1 w0.089: v2(87.51,86.08) 87.34,85.9 87.34,85.62 87.89,85.06 90.55,85.06 91.24,84.37 94.4,84.37 97.44,87.41 111.33,87.41 112.06,86.69 115.03,86.69 115.76,87.41 124.49,87.41 131.24,94.16 134.93,94.16 140.88,100.1 142.6,100.1 144.97,102.47 160.96,102.47 163.04,104.55 171.05,104.55 172.62,106.12 176.04,106.12 178.97,103.18 178.97,98.68 179.7,97.95 179.7,97.45 179.51,97.26 179.03,97.26 v2(178.89,97.12)
SW_USBP0+: length 116.8
  TOP w0.102: v2(184.64,100.18) 184.64,99.87 184.38,99.61 UI4.19 ; LI3.4 83.56,91.54 83.96,91.94 84.2,91.94 v2(84.5,91.64)
  IN1 w0.089: v2(84.5,91.64) 84.91,92.05 93.29,92.05 96.69,88.64 112.25,88.64 113.05,87.84 114.29,87.84 115.09,88.64 120.48,88.64 121.03,89.19 124.7,89.19 132.61,97.1 136.22,97.1 140.33,101.21 142.14,101.21 144.51,103.58 160.4,103.58 162.55,105.73 170.56,105.73 172.13,107.3 176.44,107.3 181.84,101.9 184.51,101.9 184.85,101.57 184.85,100.39 v2(184.64,100.18)
SW_USBP0-: length 116.8
  TOP w0.102: LI3.1 83.61,92.39 83.84,92.15 84.43,92.15 v2(84.5,92.23) ; UI4.18 184.78,99.63 185.23,100.07 v2(185.23,100.18)
  IN1 w0.089: v2(84.5,92.23) 84.51,92.22 93.36,92.22 96.77,88.81 112.32,88.81 113.12,88.01 114.22,88.01 115.02,88.81 120.41,88.81 120.96,89.36 124.63,89.36 132.54,97.27 136.15,97.27 140.26,101.38 142.07,101.38 144.44,103.75 160.33,103.75 162.48,105.9 170.49,105.9 172.06,107.47 176.51,107.47 181.91,102.07 184.59,102.07 185.02,101.64 185.02,100.39 v2(185.23,100.18)
SW_USBP3+: length 1.8
  BOTTOM w0.102: UI5.1 243.11,85.28 243.27,85.44 243.27,85.89 242.97,86.19 LI4.1
SW_USBP3-: length 1.8
  BOTTOM w0.102: LI4.4 243.82,86.22 243.48,85.88 243.48,85.44 243.64,85.28 UI5.2
SYS_LED_MASK#: length 120.8
  TOP w0.102: v2(259.08,58.97) 259.08,58.68 258.87,58.48 RE21.2 259.27,57.7 v1(261.2,57.7) 263.83,57.7 264.03,57.91 UZ10.1 ; QZ3.2 271.05,21.17 271.2,21.03 271.87,21.03 272.67,21.83 273.48,21.83 274.48,22.83 274.48,24.98 v2(274.43,25.03) ; QZ7.2 v2(287.84,81.77) ; QL2.2 QL1.2 281.8,81.27 282.3,81.77 282.65,81.77 v2(282.84,81.96) 282.84,82.97 282.61,83.2 281.96,83.2 281.8,83.04 QL1.5 ; UE1.B48 257.37,61.25 256.85,61.77 v2(256.66,61.77)
  IN1 w0.089: v2(270.29,61.43) 270.09,61.63 270.09,65.21 272.92,68.05 280.53,68.05 282.89,70.41 282.89,77.85 285.04,80 285.04,80.82 285.98,81.77 v2(287.84,81.77) ; v2(256.66,61.77) 257.18,61.25 257.18,58.51 257.54,58.15 258.54,58.15 259.08,58.68 v2(259.08,58.97)
  IN4 w0.089: v2(256.66,61.77) 257.12,61.32 266.99,61.32 267.23,61.56 270.16,61.56 v2(270.29,61.43) 270.29,60.55 276.77,54.08 276.77,40.8 277.92,39.65 277.92,31.86 277.07,31.01 277.07,30.27 275.78,28.98 275.78,27.07 274.43,25.72 v2(274.43,25.03)
  BOTTOM w0.102: v2(287.84,81.77) 287.65,81.96 v2(282.84,81.96)
SYS_PWROK: length 251.3
  TOP w0.102: UE2.B7 259.94,46.61 v2(259.7,46.37) ; CC22.1 75.95,49.2 JXDP1.47 ; CC22.1 RC120.1 v2(76.63,48.31) ; CC22.1 75.94,49.77 v1(75.58,50.14)
  IN1 w0.089: v2(76.63,48.31) 76.63,47.44 75.97,46.77 75.97,44.08 79.44,40.61 82.43,40.61 87.2,35.85 v2(87.94,35.85)
  IN3 w0.122: v2(259.7,46.37) 259.35,46.71 257.88,46.71 257.49,46.32 257.49,45.44 257.17,45.12 256.47,45.12 256.22,45.38 253.62,45.38 253.34,45.1 252.05,45.1 250.25,43.3 250.25,41.76 249.81,41.31 249.81,38.07 249.3,37.57 248.54,37.57 244.31,33.34 243.99,33.34 243.1,32.45 241.98,32.45 238.27,28.74 236.22,28.74 235.79,28.31 234.96,28.31 234.6,27.94 230.23,27.94 229.38,27.1 209.1,27.1 205.95,30.25 196.57,30.25 189.41,37.42 ; 189.41,37.42 v2(189.41,37.41) ; 189.41,37.42 188.59,38.23 188.59,41.88 185.88,44.59 185.88,49.48 183.19,52.17 183.19,54.14 179.48,57.86 178.11,57.86 174.96,61 v2(174.31,61)
  BOTTOM w0.076: UC1.AG2 170.32,58.79 170.61,59.09 171.94,59.09 172.34,59.49 173.19,59.49
  BOTTOM w0.102: 173.19,59.49 174.31,60.6 v2(174.31,61) ; v2(189.41,37.41) 188.34,38.48 176.33,38.48 173.7,35.85 v2(87.94,35.85)
SYS_RESET#: length 195.8
  TOP w0.102: v2(185.72,63.55) 186.19,64.02 186.19,67.5 186.62,67.93 v1(186.62,68.91) 186.62,71.58 RC77.2 186.29,71.92 184.21,71.92 183.93,71.64 UC4.4 ; JAPS1.13 v2(299.53,24.19)
  IN3 w0.122: v2(299.53,24.19) 299.53,24.79 297.46,26.86 285.14,26.86 284.79,26.52 283.78,26.52 283.5,26.79 283.5,28.81 282.85,29.46 282.85,34.58 281.4,36.04 281.4,36.47 280.32,37.55 280.32,38.15 277.46,41.01 277.46,42.3 270.89,48.87 270.44,48.87 268.17,51.15 266.39,51.15 264.95,52.58 262.03,52.58 261.88,52.43 249.68,52.43 244.73,47.47 244.73,42.52 242.5,40.3 239.6,40.3 238.42,39.12 235.81,39.12 231.12,34.42 231.12,34.29 230.71,33.88 229.04,33.88 227.63,32.47 210.82,32.47 208.08,35.21 199.73,35.21 193.61,41.34 193.61,46.65 193.35,46.91 193.35,48.17 192.24,49.28 192.24,49.9 192.24,49.9 192.24,55.77 187.83,60.19 187.83,62.2 186.78,63.26 186.01,63.26 v2(185.72,63.55) 184.72,63.55 184.59,63.68 v2(182.23,63.68)
  BOTTOM w0.081: UC1.AC3 169.74,60.75 170.25,60.75 170.49,60.99 170.49,61.16 170.73,61.4 170.88,61.4 171,61.52 172.03,61.52 172.27,61.76
  BOTTOM w0.102: v2(182.23,63.68) 182.23,63.44 181.52,62.74 179.66,62.74 179.12,62.2 172.71,62.2 172.27,61.76
TDI_IREF: length 7.9
  BOTTOM w0.127: 162.87,75.35 163.08,75.14 163.08,73.24 163.31,73 UC1.B12
  BOTTOM w0.381: RC186.2 161.91,79.76 v1(161.91,78.84) 161.91,76.57 162.43,76.05 162.43,75.79 162.87,75.35
TDI_XDP_R: length 3.8
  BOTTOM w0.102: UC7.5 91.61,57.33 91.8,57.13 RC118.1 RC99.2 92.62,55.47 v1(92.31,55.17)
TDO_XDP: length 21.7
  TOP w0.102: v2(91.93,58.97) 91.48,58.97 v1(91.27,59.18) ; RC117.2 85.47,47.84 v2(85.47,47.92) 85.19,48.2 JXDP1.52
  IN1 w0.089: v2(85.47,47.92) 86.55,49 88.75,49 90.48,50.73 90.48,53.5 92.43,55.45 92.43,58.48 v2(91.93,58.97)
  BOTTOM w0.102: RC98.2 RC115.1 92,59.04 v2(91.93,58.97) 91.79,58.83 UC7.2
THERMATRIP2#: length 7
  TOP w0.102: CE36.1 RE69.2 251.34,36.03 QE4.1 252.09,36.42 252.11,36.42 v1(252.41,36.73) 253.86,36.73 253.93,36.8 253.93,38.34 254.06,38.46 UE2.B34
THERMATRIP3#: length 18
  TOP w0.102: RPE6.1 262.73,34.7 v2(263.38,35.35) ; UE2.A2 262.19,48.43 262.53,48.78 263.63,48.78 v2(263.95,48.45)
  IN1 w0.089: v2(263.38,35.35) 263.38,37.26 264.37,38.25 264.37,46.44 263.61,47.21 263.61,48.11 v2(263.95,48.45)
THSEL_STRAP: length 3.4
  TOP w0.102: UE2.B29 254.6,40.96 254.7,40.87 v2(255.25,40.87)
  BOTTOM w0.102: v2(255.25,40.87) 255.69,40.42 v1(256.07,40.42) 257.02,41.38 RE78.1
TMDS_CON_CLK: length 9.3
  BOTTOM w0.102: JHDMI1.10 215.63,98.14 215.63,97.41 216.38,96.66 216.38,96.2 216.2,96.02 215.7,96.02 215.67,96.04 215.08,96.04 215.06,96.02 214.77,96.02 214.59,96.21 214.59,97.32 214.39,97.53 213.97,97.53 213.37,96.92 v4(213.37,96.42) 213.37,95.98 213.05,95.66 LV12.2
TMDS_CON_CLK#: length 9.3
  BOTTOM w0.102: LV12.3 213.9,95.65 213.57,95.97 213.57,96.1 213.6,96.12 213.6,96.72 213.57,96.74 213.57,96.84 214.06,97.32 214.3,97.32 214.38,97.24 214.38,96.12 214.69,95.82 v4(215.38,95.82) 216.29,95.82 216.59,96.12 216.59,96.75 215.83,97.5 215.83,98.2 JHDMI1.12
TMDS_CON_N0: length 9.1
  IN4 w0.089: JHDMI1.9 214.28,99.66 214.28,99.5 214.03,99.24 210.84,99.24 210.55,98.95 210.55,98.23 211.47,97.32 211.47,96.66 v2(211.64,96.48)
  BOTTOM w0.102: LV3.3 211.8,95.63 211.48,95.95 211.48,96.32 v2(211.64,96.48)
TMDS_CON_N1: length 7.7
  BOTTOM w0.102: LV6.3 209.7,95.69 209.4,95.99 209.4,96.45 210.12,97.17 211.13,97.17 211.36,97.39 211.36,97.65 211.45,97.74 211.8,97.74 211.87,97.68 211.87,97.2 212.14,96.92 212.53,96.92 212.8,97.2 212.8,98.17 JHDMI1.6
TMDS_CON_N2: length 7.4
  BOTTOM w0.102: JHDMI1.3 211.3,99.67 211.3,99.36 211.05,99.11 210.86,99.11 208.32,96.57 v4(207.86,96.57) 207.51,96.57 207.29,96.35 207.29,95.99 207.61,95.67 LV10.3
TMDS_CON_P0: length 9.1
  IN4 w0.089: JHDMI1.7 214.11,99.66 214.11,99.57 213.96,99.41 210.77,99.41 210.38,99.02 210.38,98.16 211.29,97.25 211.29,96.72 v2(211.06,96.48)
  BOTTOM w0.102: v2(211.06,96.48) 211.27,96.27 211.27,95.93 210.95,95.61 LV3.2
TMDS_CON_P1: length 7.7
  BOTTOM w0.102: JHDMI1.4 212.6,98.17 212.6,97.28 212.44,97.13 212.23,97.13 212.07,97.28 212.07,97.76 211.89,97.95 211.36,97.95 211.15,97.74 211.15,97.48 211.05,97.38 210.04,97.38 209.18,96.52 v4(209.18,96.28) 209.18,95.95 208.85,95.63 LV6.2
TMDS_CON_P2: length 7.4
  BOTTOM w0.102: LV10.2 206.76,95.69 207.08,96.01 207.08,96.44 207.42,96.78 207.54,96.78 207.56,96.8 208.25,96.8 210.77,99.32 210.96,99.32 211.1,99.45 211.1,99.67 JHDMI1.1
TOUCH_PANEL_INTR#: length 131.3
  TOP w0.081: v2(172.75,67.04) 173.19,67.48 173.36,67.48
  TOP w0.102: RPC3.5 180.94,67.43 180.87,67.36 180.87,66.94 180.6,66.67 176.21,66.67 175.4,67.48 173.36,67.48
  IN3 w0.081: 170.96,76.26 170.94,76.26 170.94,76.18 170.95,76.17 170.95,66.83 171.18,66.59 172.3,66.59 v2(172.75,67.04)
  IN3 w0.122: v2(105.66,78.84) 105.92,79.1 110.28,79.1 113.77,82.59 123.57,82.59 129.48,88.49 145.54,88.49 148.08,91.03 153.04,91.03 157.37,95.36 158.12,95.36 158.98,96.22 164.46,96.22 166.73,93.95 166.73,88.5 165.08,86.85 165.08,82.93 170.24,77.76 170.24,76.99 170.96,76.27 170.96,76.26
  BOTTOM w0.076: v2(172.75,67.04) 172.36,66.65 172.11,66.65 171.29,65.83 170.66,65.83 170.49,65.66 170.49,65.48 170.25,65.24 169.74,65.24 UC1.P3
  BOTTOM w0.102: v2(105.66,78.84) 102.28,78.84 101.2,79.92 101.2,81.29 100.9,81.6 100.9,84.37 101.6,85.06 101.6,88.14 100.96,88.78 JEDP1.5
TOUCH_SCREEN_PD#: length 6.4
  TOP w0.102: v2(259.38,59.54) 259.5,59.43 259.5,58.72 T96.1 ; UE1.B55 259.07,63.01 v2(258.73,63.35)
  IN1 w0.089: v2(258.73,63.35) 259.15,62.94 259.15,59.78 v2(259.38,59.54)
TOUCHPAD_INTR#: length 14.5
  TOP w0.081: 173.3,65.26 170.86,65.26 170.6,65 169.15,65 168.54,64.39 167.09,64.39 167,64.48 v2(167,64.78)
  TOP w0.102: RPC9.7 179.64,65.07 179.59,65.02 173.56,65.02 173.32,65.26 173.3,65.26
  BOTTOM w0.081: v2(167,64.78) 166.85,64.63 UC1.U7
TP_DC_TEST_B2: length 4.8
  BOTTOM w0.102: UC1.B2 170.32,73.04 RC192.2 170.32,77.67 v1(170.42,77.77)
TP_LAN_JTAG_TCK: length 3.2
  TOP w0.102: v1(261.6,89.6) 261.29,89.28 RL2.2 260.26,87.59 UL1.35
TP_LAN_JTAG_TDI: length 1.6
  TOP w0.102: UL1.32 261.21,86.39 T88.1
TP_LAN_JTAG_TDO: length 1.9
  TOP w0.102: UL1.34 260.25,87.19 260.92,87.86 T89.1
TP_LAN_JTAG_TMS: length 4.2
  TOP w0.102: v1(263.17,85.8) 262.35,86.61 261.77,86.61 RL1.2 260.72,87.1 260.41,86.79 UL1.33
TPM_PIRQ#: length 44.4
  TOP w0.102: v2(179.63,60.79) 179.32,60.49 RC247.1
  IN1 w0.076: v2(169.81,64.43) 169.6,64.22 166.2,64.22 165.99,64.01 165.99,60.81 166.33,60.46 169.89,60.46 170.77,59.58 172.78,59.58 173.01,59.8 173.36,59.8
  IN1 w0.089: 173.36,59.8 177.61,59.8 178.6,60.79 v2(179.63,60.79)
  BOTTOM w0.076: v2(169.81,64.43) 169.48,64.75 UC1.T3
  BOTTOM w0.102: UZ1.20 186.98,76.09 182.94,72.05 182.94,69.45 183.64,68.75 183.64,67.98 184.21,67.41 v1(184.21,64.74) 183.58,64.11 183.58,62.99 182.2,61.62 180.11,61.62 179.63,61.14 v2(179.63,60.79)
TRST#_XDP: length 23.5
  TOP w0.102: JXDP1.54 82.77,47.7 82.57,47.9 82.57,52.09 81.91,52.74 81.91,60.3 82.74,61.12 v1(86.47,61.12) 86.93,61.12 87.44,60.62 87.44,60.17 87.21,59.94 87.21,58.94 v2(87.63,58.52)
  BOTTOM w0.102: UC7.12 87.82,58.33 v2(87.63,58.52)
UG_3V: length 9.2
  TOP w0.102: v1(225.38,60.38) 225.28,60.27 v2(225.28,59.57)
  IN1 w1.016: 223.88,59.1 223.25,58.47 223.25,53.41 221.58,51.74
  vias: v2(220.34,50.74) v2(220.77,51.16) v2(224.68,59.57)
UG_5V: length 9.7
  TOP w0.102: v1(213.93,61.39) 213.93,58.17 213.43,57.67 PQ101.4
  IN1 w1.016: 213.22,56.18 213.22,53.39 215.06,51.54
  vias: v2(212.65,57.09) v2(213.24,57.09) v2(215.85,51.18) v2(216.28,50.77)
UIM_CLK: length 35.9
  IN4 w0.089: v2(238.5,65.54) 238.5,65.54 234.92,65.54 232.83,67.63 232.83,77.97 235.77,80.91 v2(236.41,80.91)
  BOTTOM w0.102: JNGFF2.24 239.29,65.1 238.85,65.54 v2(238.5,65.54) ; v2(236.41,80.91) v1(236.41,81.71) 236.28,81.84 236.28,87.46 235.47,88.28 233.63,88.28 CZ66.1 232.84,87.74 231.65,87.74 231.6,87.7 JSIM1.4
UIM_DATA: length 34
  IN4 w0.089: v2(238.5,64.95) 238.4,65.06 234.85,65.06 232.44,67.47 232.44,78.14 235.72,81.42 v2(235.86,81.42)
  BOTTOM w0.102: JSIM1.3 231.51,87 231.84,87.32 232.31,87.32 CZ65.1 233.59,86.04 v1(235.23,86.04) 235.86,85.41 v2(235.86,81.42) ; v2(238.5,64.95) 238.74,64.95 239.09,64.6 JNGFF2.26
UIM_RESET: length 33.8
  IN1 w0.089: v2(241.23,65.7) 240.61,66.32 240.61,82.03 v2(239.21,83.43)
  BOTTOM w0.102: v2(241.23,65.7) 241.14,65.6 JNGFF2.22 ; JSIM1.6 231.51,89.1 231.99,88.62 232.39,88.62 CZ67.1 233.53,88.68 235.64,88.68 236.73,87.59 236.73,84 v1(236.82,83.9) 237.88,82.84 238.86,82.84 239.21,83.2 v2(239.21,83.43)
USB3RN1: length 53.9
  TOP w0.102: v2(161.44,92.99) 161.27,93.16 161.27,93.75 161.53,94.01 164.81,94.01 166.52,92.29 181.51,92.29 182.55,93.33 182.55,94.46 182.67,94.59 182.67,95.48 182.78,95.59 UI4.5
  IN3 w0.112: v2(159.13,69.22) 158.92,69 158.36,69 157.92,69.44 157.92,73.13 157.36,73.68 157.36,87.32 161.26,91.22 161.26,92.81 v2(161.44,92.99)
  BOTTOM w0.081: v2(159.13,69.22) 159.41,69.22 159.61,69.42 UC1.G20
USB3RN1_D-: length 10.5
  TOP w0.102: JUSB1.5 81.5,97.37 81.6,97.27 81.6,96.64 82.26,95.97 82.26,95.08 82.65,94.69 82.65,94.66 83.07,94.24 83.1,94.24 83.31,94.03 v4(84.83,94.03) 85.33,94.03 85.51,93.85 85.51,93.45 85.37,93.31 DI1.9 DI1.1 85.37,91.36 85.15,91.14 LI1.3
USB3RN2: length 191.4
  IN4 w0.089: v2(159.32,71.53) 159.32,71.41 159.67,71.06 159.67,66.96 161.64,64.99 163.57,64.99 165.38,63.18 165.38,61.32 166,60.71 166,58.95 166.26,58.69 167.77,58.69 168.13,58.34 168.13,57.97 168.31,57.78 169.75,57.78 170.37,57.16 170.37,54.76 171.12,54.01 171.75,54.01 176.44,49.33 179.17,49.33 183.92,44.58 188.3,44.58 189.66,43.22 189.66,40.1 201.58,28.18 232.06,28.18 234.58,25.65 234.58,25.18 237.72,22.05 239.42,22.05 239.86,21.61 246.75,21.61 247.49,22.35 264.4,22.35 265.19,21.56 268.03,21.56 270.26,23.79 272.35,23.79 273.05,24.49 273.92,24.49 274.48,23.93 274.93,23.93 276.27,25.27 276.27,28.8 277.71,30.24 277.71,30.96 278.39,31.64 278.39,39.85 277.77,40.47 277.77,54.11 277.02,54.86 277.02,58.79 277.84,59.61 279.21,59.61 280.08,60.47 280.42,60.47 v2(280.62,60.66)
  BOTTOM w0.081: v2(159.32,71.53) 159.5,71.36 159.96,71.36 160.14,71.18 160.14,70.72 160.33,70.52 160.46,70.52 160.56,70.62 UC1.E18
  BOTTOM w0.102: LI6.1 281.44,60.8 281.12,60.47 280.8,60.47 v2(280.62,60.66)
USB3RN2_D-: length 9
  BOTTOM w0.102: JUSB3.5 290.3,59.42 290.16,59.28 289.71,59.28 289.08,58.66 288.47,58.66 286.73,60.4 286.12,60.4 285.99,60.53 DI4.1 DI4.9 284.39,60.53 284.31,60.45 283.93,60.45 283.58,60.8 LI6.2
USB3RN4: length 97.6
  IN1 w0.089: v2(161.99,70.32) 161.99,70.21 161.9,70.11 161.86,70.11 161.69,69.94 161.6,69.94 161.55,70 161.55,70.43 161.55,71.04 161.55,71.05 161.55,71.61 161.42,71.75 161.42,76.19 162.06,76.83 165.15,76.83 171.44,83.12 172.39,83.12 173.02,83.75 173.02,85.72 174.11,86.81 178.01,86.81 178.37,86.45 202.53,86.45 202.93,86.05 204.27,86.05 204.78,86.55 210.63,86.55 210.94,86.87 220.96,86.87 221.35,86.48 223.57,86.48 223.99,86.07 230.48,86.07 232.69,83.86 234.99,83.86 235.34,84.21 237.96,84.21 v2(238.38,83.8)
  BOTTOM w0.081: v2(161.99,70.32) 162.07,70.24 UC1.F15
  BOTTOM w0.102: LI9.1 238.13,87.9 238.3,87.73 238.3,85.59 237.72,85.02 237.72,84.22 237.95,83.98 238.19,83.98 v2(238.38,83.8)
USB3RN4_D-: length 8.8
  BOTTOM w0.102: JUSB2.5 239.25,96.92 239.6,96.92 239.7,96.82 239.7,96.57 240.07,96.19 240.07,95.5 238.65,94.07 238.57,93.99 v4(238.57,93.62) 238.57,93.24 238.39,93.07 DI6.1 DI6.9 238.39,91.36 238.54,91.21 238.54,90.93 238.13,90.52 LI9.2
USB3RP1: length 54.2
  TOP w0.102: v2(160.86,92.99) 161.06,93.2 161.06,93.84 161.44,94.22 164.89,94.22 166.61,92.5 181.43,92.5 182.34,93.41 182.34,94.55 182.46,94.68 182.46,95.47 182.38,95.55 UI4.4
  IN3 w0.112: v2(159.13,68.67) 159,68.8 158.28,68.8 157.72,69.36 157.72,73.04 157.16,73.6 157.16,87.4 161.06,91.31 161.06,92.78 v2(160.86,92.99)
  BOTTOM w0.081: v2(159.13,68.67) 159.24,68.57 159.42,68.57 159.61,68.76 UC1.H20
USB3RP1_D+: length 11
  TOP w0.102: JUSB1.6 82.56,97.51 82.05,97.51 81.81,97.27 81.81,96.73 82.47,96.06 82.47,95.16 v4(83.02,94.61) 83.4,94.24 84.52,94.24 84.54,94.26 85.13,94.26 85.15,94.24 85.41,94.24 85.71,93.94 85.71,93.49 85.87,93.34 DI1.8 DI1.2 85.87,91.68 85.81,91.62 85.68,91.62 85.58,91.52 85.58,91.38 85.67,91.29 85.91,91.29 86,91.21 LI1.2
USB3RP2: length 191.4
  IN4 w0.089: v2(280.62,60.08) 280.39,60.3 280.15,60.3 279.29,59.44 277.91,59.44 277.19,58.72 277.19,54.93 277.94,54.18 277.94,40.54 278.56,39.92 278.56,31.57 277.88,30.89 277.88,30.17 276.44,28.73 276.44,25.2 275,23.76 274.41,23.76 273.85,24.31 273.12,24.31 272.42,23.62 270.33,23.62 268.1,21.39 265.12,21.39 264.33,22.18 247.56,22.18 246.82,21.44 239.79,21.44 239.35,21.88 237.64,21.88 234.41,25.11 234.41,25.58 231.99,28.01 201.51,28.01 189.49,40.03 189.49,43.15 188.23,44.41 183.85,44.41 179.1,49.16 176.37,49.16 171.68,53.84 171.05,53.84 170.2,54.69 170.2,57.09 169.68,57.61 168.24,57.61 167.95,57.9 167.95,58.27 167.7,58.52 166.19,58.52 165.83,58.88 165.83,60.63 165.21,61.25 165.21,63.11 163.5,64.82 161.57,64.82 159.5,66.89 159.5,70.99 159.4,71.09 159.18,71.09 v2(159.11,71.03)
  BOTTOM w0.081: UC1.F18 160.47,70.33 160.26,70.33 159.95,70.64 159.95,71.1 159.88,71.17 159.26,71.17 v2(159.11,71.03)
  BOTTOM w0.102: LI6.4 281.41,59.95 281.09,60.27 280.8,60.27 v2(280.62,60.08)
USB3RP2_D+: length 9
  BOTTOM w0.102: LI6.3 283.63,59.95 283.93,60.24 284.25,60.24 284.46,60.03 DI4.8 DI4.2 286.05,60.03 286.21,60.19 286.64,60.19 288.38,58.45 289.17,58.45 289.79,59.08 290.14,59.08 290.3,58.92 JUSB3.6
USB3RP4: length 97.8
  IN1 w0.089: v2(238.38,84.38) 235.27,84.38 234.92,84.03 232.76,84.03 230.55,86.24 224.06,86.24 223.64,86.65 221.42,86.65 221.03,87.04 210.87,87.04 210.56,86.72 204.71,86.72 204.2,86.22 203,86.22 202.6,86.62 178.44,86.62 178.08,86.98 174.04,86.98 172.85,85.79 172.85,83.82 172.32,83.29 171.37,83.29 165.08,77 161.99,77 161.25,76.26 161.25,71.68 161.38,71.54 161.38,71.12 161.37,71.11 161.37,70.8 161.38,70.8 161.38,70.5 161.37,70.5 161.37,69.93 161.53,69.77 161.99,69.77 v2(162.01,69.75)
  BOTTOM w0.081: v2(162.01,69.75) 162.17,69.59 UC1.G15
  BOTTOM w0.102: v2(238.38,84.38) 238.19,84.19 238.04,84.19 237.93,84.3 237.93,84.94 238.5,85.51 238.5,87.73 238.63,87.86 238.88,87.86 238.98,87.95 LI9.4
USB3RP4_D+: length 8.7
  BOTTOM w0.102: LI9.3 238.98,90.52 238.75,90.75 238.75,91.24 238.89,91.38 DI6.8 DI6.2 238.89,93.04 238.78,93.16 238.78,93.31 238.8,93.33 238.8,93.93 238.85,93.99 240.28,95.41 240.28,96.28 239.91,96.65 239.91,96.82 240.01,96.92 240.36,96.92 JUSB2.6
USB3TN1: length 52.3
  TOP w0.102: v2(159.9,92.95) 159.69,93.16 159.69,93.54 161,94.85 165.21,94.85 166.86,93.2 177.72,93.2 179.88,95.36 181.34,95.36 181.58,95.6 UI4.2
  IN3 w0.112: v2(149.51,75.02) 149.29,74.8 149.17,74.8 149.02,74.95 149.02,82.32 158.61,91.91 159.12,91.91 159.59,92.38 159.59,92.63 v2(159.9,92.95)
  BOTTOM w0.081: v2(149.51,75.02) 149.66,74.87 149.91,74.87 150.16,74.62 150.16,74.1 150.42,73.84 150.42,73.44 150.77,73.08 150.77,72.66 151.06,72.38 UC1.C33
USB3TN1_C: length 1.6
  TOP w0.102: CI4.1 87.04,88 87.04,88.29 86.75,88.59 LI2.4
USB3TN1_D-: length 7.5
  TOP w0.102: LI2.3 86.75,91.16 86.87,91.29 DI1.4 DI1.7 86.87,93.25 87.04,93.42 87.04,93.89 87.02,93.91 87.02,94.51 87.04,94.53 v4(87.04,95.68) 87.04,96.53 87.36,96.84 87.36,97.22 87.2,97.37 JUSB1.8
USB3TN2: length 194.3
  IN4 w0.089: v2(278.44,58.97) 278.24,58.76 277.95,58.76 277.66,58.48 277.66,55.13 278.43,54.37 278.43,41.27 279.05,40.64 279.05,31.34 278.48,30.77 278.48,30.1 276.92,28.54 276.92,24.91 274.27,22.27 269.65,22.27 268.29,20.91 237.95,20.91 233.92,24.94 233.92,25.4 231.78,27.54 201.32,27.54 189.02,39.83 189.02,42.3 187.38,43.94 183.11,43.94 178.74,48.31 176.55,48.31 171.58,53.28 170.9,53.28 169.12,55.06 169.11,55.06 168.89,55.27 168.89,56.24 168.54,56.59 168.15,56.59 167.92,56.83 166.72,56.83 166.35,57.2 165.54,57.2 165.34,57.4 165.34,58.55 164.9,58.99 164.9,60.03 163.71,61.22 163.71,61.82 156.91,68.62 156.91,69.21 154.56,71.56 154.33,71.56 152.21,73.68 151.88,73.68 151.37,74.18 151.37,74.19 151.36,74.2 151.36,74.47 151.18,74.66 151,74.66 v2(150.8,74.86)
  BOTTOM w0.081: UC1.B33 151.06,73.02 151.37,73.34 151.37,74.47 151.18,74.66 151,74.66 v2(150.8,74.86)
  BOTTOM w0.102: v2(278.44,58.97) 278.63,58.78 279.05,58.78 CI16.2
USB3TN2_C: length 1.6
  BOTTOM w0.102: LI5.1 281.23,59.14 280.91,58.82 280.69,58.82 CI16.1
USB3TN2_D-: length 12.4
  BOTTOM w0.102: LI5.2 283.77,59.14 284.06,58.85 284.29,58.85 284.47,59.03 DI4.7 DI4.4 286,59.03 286.13,58.9 287.01,58.9 287.77,58.15 287.77,54.59 288.21,54.15 288.99,54.15 289.85,53.28 290.14,53.28 290.3,53.44 JUSB3.8
USB3TN4: length 105.4
  IN1 w0.089: v2(151.74,76.38) 151.74,76.18 151.66,76.1 151.57,76.1 151.38,75.91 151.25,75.91 151.04,76.12 151.04,76.64 151.53,77.13 151.94,77.13 153.36,78.54 156.62,78.54 168.22,90.14 186.88,90.14 188.02,89.01 202.89,89.01 203.62,89.74 221.71,89.74 222.24,90.28 235.53,90.28 238.98,86.82 239.77,86.82 240.33,86.26 240.33,86.02 v2(239.91,85.61)
  BOTTOM w0.081: UC1.B31 152.53,72.95 152.68,72.95 152.9,73.18 152.9,74.35 152.52,74.73 152.52,75.96 152.22,76.26 151.86,76.26
  BOTTOM w0.102: CI28.2 240.09,86 240.09,85.78 v2(239.91,85.61) ; 151.86,76.26 v2(151.74,76.38)
USB3TN4_C: length 1.6
  BOTTOM w0.102: CI28.1 240.12,87.6 240.12,87.92 239.78,88.26 LI8.1
USB3TN4_D-: length 12.4
  BOTTOM w0.102: LI8.2 239.78,90.52 240.06,90.8 240.06,91.22 239.89,91.39 DI6.7 DI6.4 239.89,92.63 239.89,93.01 240.04,93.16 v4(240.04,93.64) 240.04,94.01 240.61,94.59 244.24,94.59 244.96,95.31 244.96,96.01 245.68,96.73 245.68,96.86 245.58,96.96 245.21,96.96 JUSB2.8
USB3TP1: length 52.3
  TOP w0.102: v2(159.32,92.95) 159.48,93.11 159.48,93.63 160.91,95.06 165.3,95.06 166.95,93.41 177.63,93.41 179.79,95.57 181.1,95.57 181.18,95.64 UI4.1
  IN3 w0.112: v2(149.51,74.38) 149.3,74.59 149.08,74.59 148.82,74.86 148.82,82.4 158.52,92.11 159.03,92.11 159.38,92.46 159.38,92.88 v2(159.32,92.95)
  BOTTOM w0.081: v2(149.51,74.38) 149.51,74.56 149.6,74.65 149.82,74.65 149.97,74.51 149.97,74.02 150.23,73.77 150.23,73.36 150.59,73 150.59,72.9 150.49,72.81 150.24,72.81 150.19,72.76 150.19,72.6 150.3,72.49 150.45,72.49 UC1.B34
USB3TP1_C: length 1.6
  TOP w0.102: CI5.1 87.25,88.03 87.25,88.31 87.6,88.65 LI2.1
USB3TP1_D+: length 9
  TOP w0.102: LI2.2 87.6,91.16 87.51,91.25 87.14,91.25 87.08,91.32 87.08,91.5 87.13,91.55 87.32,91.55 87.37,91.6 DI1.5 DI1.6 87.37,93.29 87.25,93.41 v4(87.25,94.21) 87.25,95.36 87.27,95.38 87.27,95.98 87.25,96 87.25,96.45 87.56,96.76 87.56,97.51 87.69,97.64 88.43,97.64 JUSB1.9
USB3TP2: length 194.1
  IN4 w0.089: v2(150.8,74.28) 151.01,74.49 151.11,74.49 151.19,74.4 151.19,74.13 151.2,74.12 151.2,74.11 151.8,73.51 152.14,73.51 154.26,71.39 154.49,71.39 156.74,69.14 156.74,68.55 163.54,61.75 163.54,61.15 164.73,59.96 164.73,58.92 165.17,58.48 165.17,57.33 165.47,57.03 166.28,57.03 166.65,56.65 167.85,56.65 168.08,56.42 168.47,56.42 168.72,56.16 168.72,55.2 169.04,54.89 169.05,54.89 170.83,53.11 171.51,53.11 176.48,48.14 178.67,48.14 183.04,43.77 187.31,43.77 188.85,42.23 188.85,39.76 201.25,27.37 231.71,27.37 233.75,25.33 233.75,24.87 237.88,20.74 268.36,20.74 269.72,22.1 274.34,22.1 277.09,24.84 277.09,28.47 278.65,30.03 278.65,30.7 279.22,31.27 279.22,40.72 278.6,41.34 278.6,54.44 277.83,55.2 277.83,58.41 278.02,58.59 278.24,58.59 v2(278.44,58.38)
  BOTTOM w0.081: UC1.A33 151.06,73.39 150.96,73.29 150.8,73.29 150.71,73.38 150.71,73.56 150.99,73.83 151.12,73.83 151.18,73.9 151.18,74.39 151.1,74.47 150.99,74.47 v2(150.8,74.28)
  BOTTOM w0.102: v2(278.44,58.38) 278.63,58.57 279.14,58.57 CI13.2
USB3TP2_C: length 1.6
  BOTTOM w0.102: LI5.4 281.21,58.29 280.89,58.62 280.69,58.62 CI13.1
USB3TP2_D+: length 12.5
  BOTTOM w0.102: JUSB3.9 290.3,52.94 290.17,53.07 289.77,53.07 288.9,53.94 288.12,53.94 287.56,54.51 287.56,58.06 286.93,58.69 286.11,58.69 285.95,58.53 DI4.5 DI4.6 284.43,58.53 284.34,58.62 283.98,58.62 283.65,58.29 LI5.3
USB3TP4: length 105.7
  IN1 w0.089: v2(151.74,75.74) 151.18,75.74 150.87,76.05 150.87,76.71 151.46,77.3 151.87,77.3 153.29,78.71 156.55,78.71 168.15,90.31 186.96,90.31 188.09,89.18 202.82,89.18 203.55,89.91 221.64,89.91 222.17,90.45 235.6,90.45 239.05,86.99 239.84,86.99 240.5,86.34 v2(240.5,85.61)
  BOTTOM w0.081: v2(151.74,75.74) 151.74,75.8 152.01,76.08 152.14,76.08 152.33,75.89 152.33,74.65 152.72,74.27 152.72,73.26 152.6,73.14 152.45,73.14 152.38,73.22 152.38,73.44 152.44,73.5 UC1.A31
  BOTTOM w0.102: CI27.2 240.29,85.97 240.29,85.81 v2(240.5,85.61)
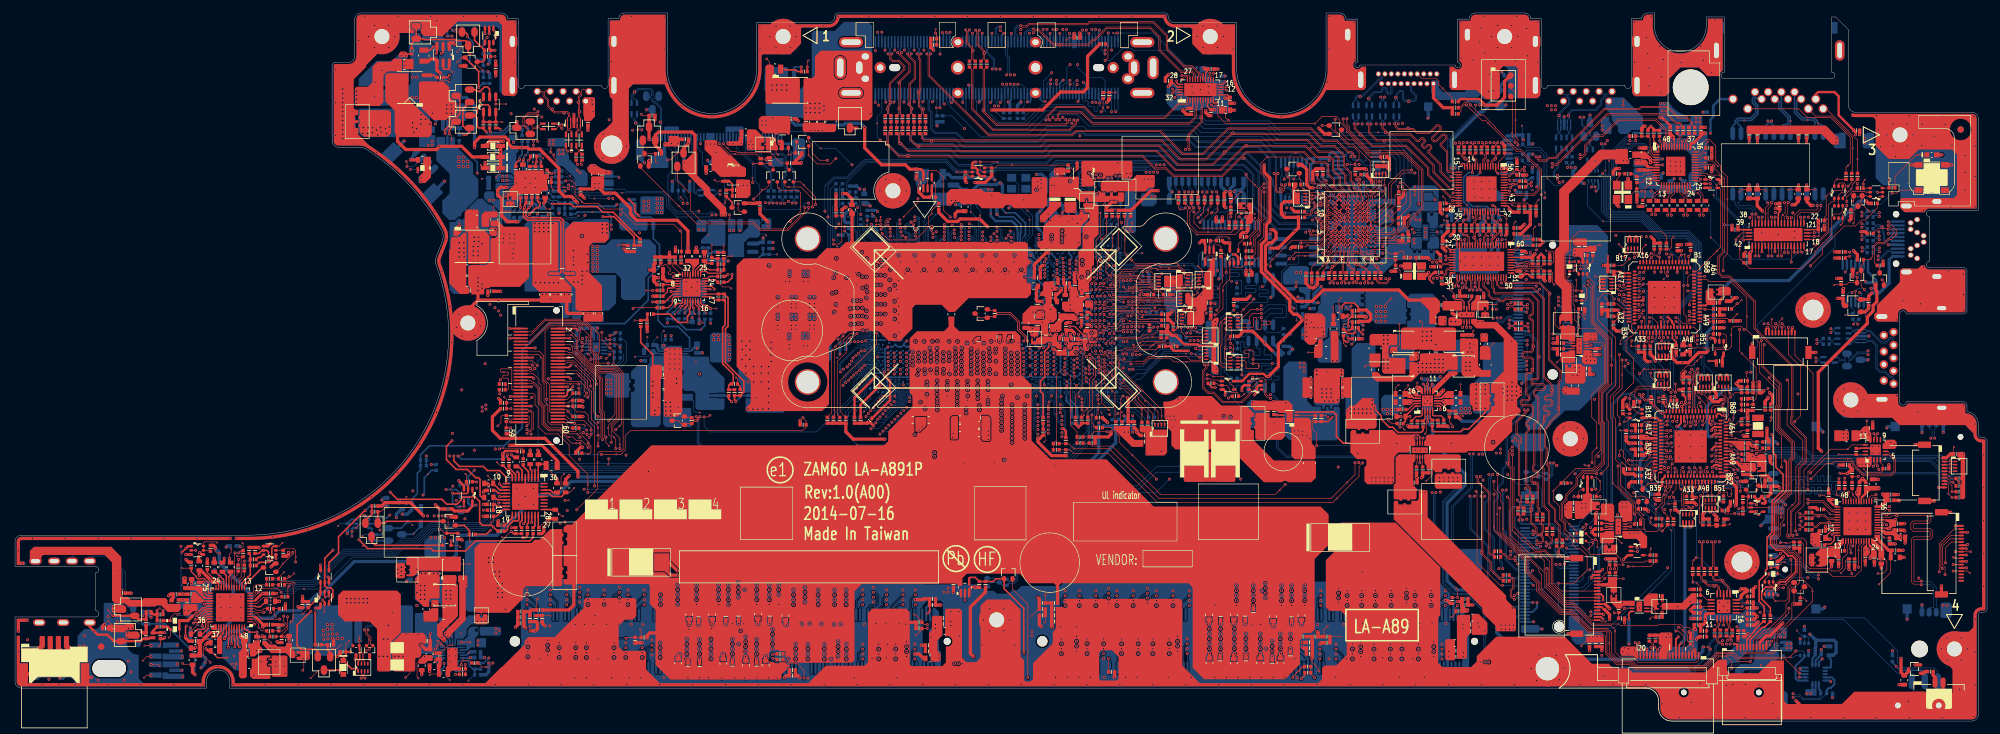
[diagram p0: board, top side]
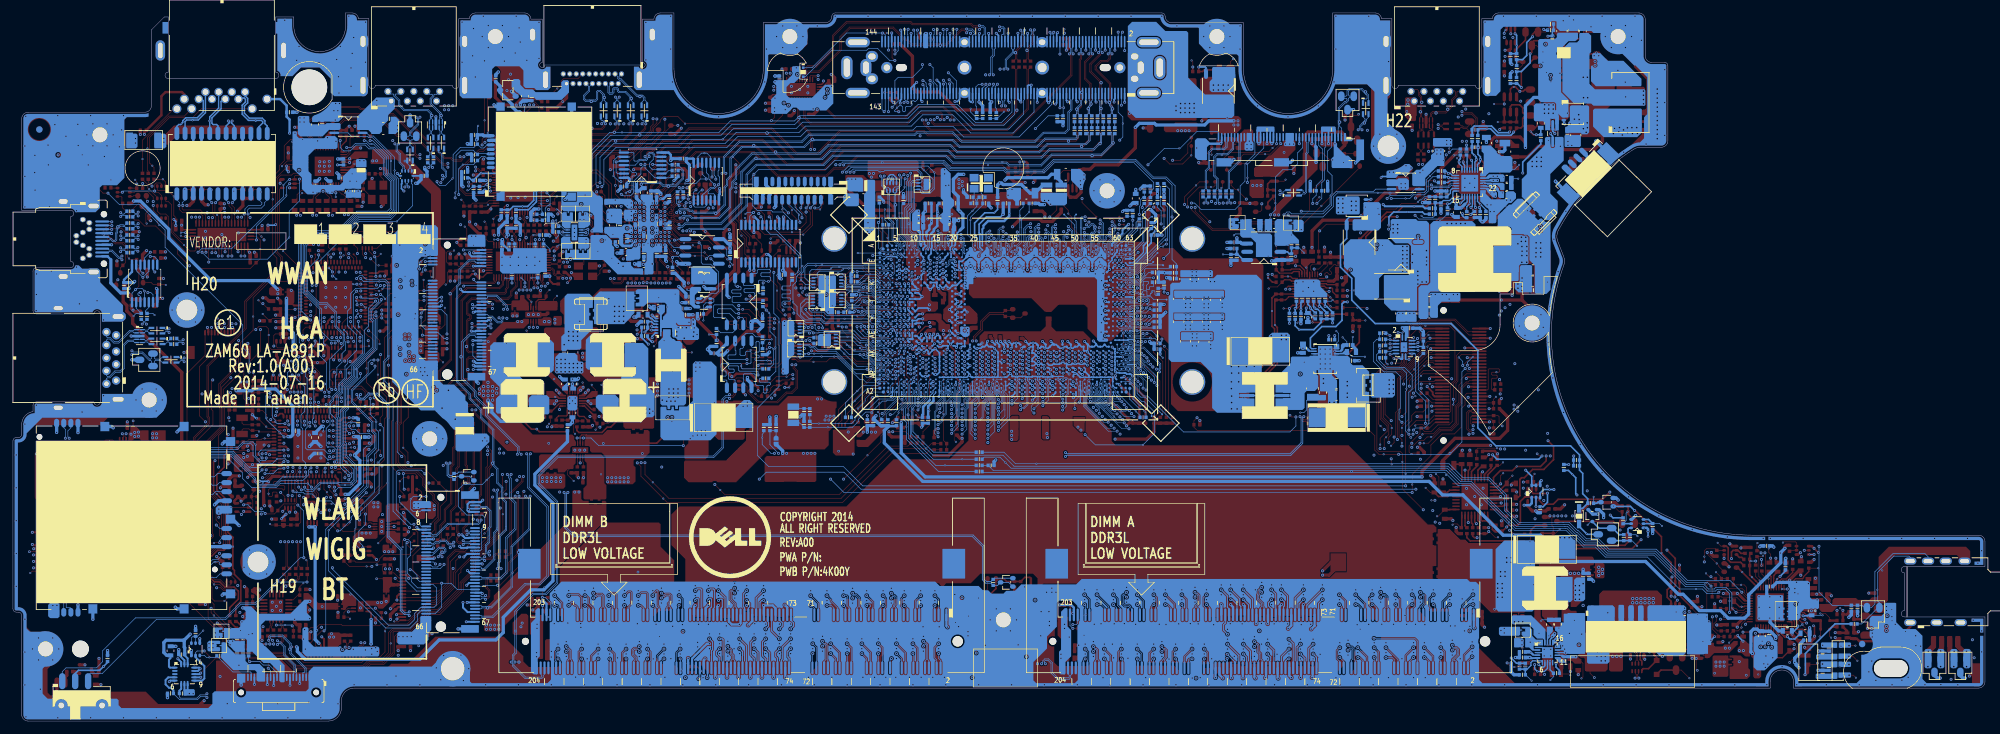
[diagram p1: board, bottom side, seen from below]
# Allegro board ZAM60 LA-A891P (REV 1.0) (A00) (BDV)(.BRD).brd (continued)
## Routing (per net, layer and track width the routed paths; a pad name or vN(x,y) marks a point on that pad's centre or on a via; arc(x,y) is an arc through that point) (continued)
USB3TP4_C: length 1.6
  BOTTOM w0.102: CI27.1 240.32,87.57 240.32,87.92 240.63,88.23 LI8.4
USB3TP4_D+: length 12.5
  BOTTOM w0.102: JUSB2.9 246.4,96.96 245.99,96.96 245.89,96.86 245.89,96.64 245.17,95.92 245.17,95.22 244.33,94.38 240.7,94.38 240.26,93.94 240.26,93.93 240.26,93.34 240.26,93.33 240.26,93.08 240.39,92.94 DI6.5 DI6.6 240.39,91.43 240.27,91.31 240.27,90.86 240.63,90.49 LI8.3
USB_DB_DET#: length 1.2
  TOP w0.102: T98.1 258.02,71.63 258.12,71.53 UE1.A2
USB_OC0#: length 145.2
  IN3 w0.076: 168.97,59.24 168.59,59.63 168.59,60.62 168.73,60.76 168.73,61.18 168.46,61.44 166.13,61.44 165.97,61.6 165.97,65.65 166.4,66.08 168.25,66.08 168.89,66.71 168.89,68.38 168.64,68.62 168.64,72.16 169.12,72.64
  IN3 w0.122: v2(171.78,56.75) 171.78,57.37 169.9,59.24 168.97,59.24 ; 169.12,72.64 169.12,76.21 168.84,76.49 168.84,77.25 163.83,82.27 163.83,87.36 165.47,89 165.47,93.45 164.53,94.39 163.63,94.39 163.27,94.74 160.12,94.74 159.76,94.39 159,94.39 149.89,85.28 128.51,85.28 125.05,81.83 115.97,81.83 111.97,77.83 108.14,77.83 v2(107.69,78.27)
  BOTTOM w0.076: 173.36,57.76 172.93,57.76 172.63,57.47 172.32,57.47 171.78,56.92 v2(171.78,56.75) 171.42,57.11 171.06,57.11 170.79,56.84 170.66,56.84 170.49,56.67 170.49,56.45 170.3,56.26 169.73,56.26 UC1.AL3
  BOTTOM w0.102: 173.36,57.76 173.39,57.76 173.7,58.06 174.17,58.06 175,58.9 176.91,58.9 177.29,59.28 RPC19.3 ; UI1.5 88.09,82.26 88.66,81.68 v1(93.84,81.68) 100.05,81.68 100.71,81.03 100.71,79.55 102.31,77.95 107.38,77.95 v2(107.69,78.27)
USB_OC1#: length 163.1
  TOP w0.102: UI3.13 283.88,42.71 v1(283.22,42.04) 280.56,42.04 277.06,38.55 v2(277.06,35.79)
  IN3 w0.122: v2(277.06,35.79) 274.88,37.97 270.81,37.97 268.96,36.12 266.05,36.12 264.72,37.44 254.51,37.44 252.75,35.68 252.75,33.19 253.27,32.67 253.27,30.94 250.71,28.38 249.96,28.38 248.46,26.87 245.68,26.87 244.05,25.23 243.48,25.23 239.98,21.74 238.17,21.74 237.84,21.41 228.45,21.41 226.89,22.97 205.83,22.97 202.94,25.86 192.9,25.86 178.58,40.18 178.58,44.91 172.78,50.72 172.78,54.37 v2(172.75,54.4)
  BOTTOM w0.076: UC1.AT1 170.79,53.5 171.85,53.5 v2(172.75,54.4)
  BOTTOM w0.081: 173.36,54.4 v2(172.75,54.4)
  BOTTOM w0.102: 173.36,54.4 174.79,54.4 177.58,57.19 180.46,57.19 180.99,57.72 181.5,57.72 181.82,58.03 182.6,58.03 182.87,57.76 RPC7.7
USB_OC2#: length 177.3
  TOP w0.102: RPC5.8 184.02,58.86 183.64,58.48 183.23,58.48 182.83,58.89 v2(182.82,58.89)
  IN1 w0.089: v2(182.82,58.89) 182.82,58.74 182.51,58.43 181.47,58.43 181.2,58.69 v2(171.85,58.69)
  IN3 w0.122: v2(255.47,51.26) 255.06,50.84 253.63,50.84 253.56,50.92 249.23,50.92 245.62,47.3 245.62,40.68 242.5,37.57 240.18,37.57 239.73,37.11 237.46,37.11 233.94,33.59 233.94,33.24 232.96,32.25 231.92,32.25 230.25,30.59 229.13,30.59 228.29,29.74 210.36,29.74 207.15,32.96 197.84,32.96 191.35,39.45 191.35,45.55 188.78,48.13 188.78,49.79 187.92,50.65 187.92,53.71 182.82,58.8 v2(182.82,58.89)
  BOTTOM w0.076: UC1.AH2 170.14,58.04 170.6,58.5 170.96,58.5 171.19,58.27 171.43,58.27 v2(171.85,58.69)
  BOTTOM w0.102: UI2.5 250.11,90.95 249.62,90.46 249.04,90.46 245.77,87.18 v1(245.77,85.14) 245.77,84.45 245.2,83.88 245.2,78.74 246.35,77.58 251.26,77.58 254.17,74.67 258.2,74.67 259.44,73.42 259.44,66.42 257.48,64.46 256.29,64.46 255.01,63.18 255.01,61.01 253.72,59.72 253.72,58.67 253.61,58.56 253.61,58.16 255.79,55.98 255.79,51.58 v2(255.47,51.26)
USB_OC3#: length 15.9
  BOTTOM w0.076: 173.36,52.82 172.84,52.31 171.17,52.31 170.97,52.52 170.5,52.52 170.47,52.55 169.82,52.55 UC1.AV3
  BOTTOM w0.102: 173.36,52.82 173.87,52.82 177.41,56.36 v1(177.84,56.36) 182.41,56.36 182.81,56.76 RPC7.5
USB_PWR_EN1#: length 201.9
  TOP w0.102: UE1.B44 255.37,61.72 v2(255.42,61.77) ; RPE9.2 255,58.08 254.95,58.12 v2(254.95,58.47)
  IN1 w0.089: v2(255.42,61.77) 255.42,60.72 255.84,60.29 255.84,59.12 255.58,58.87 255.35,58.87 v2(254.95,58.47)
  IN2 w0.122: v2(108.33,78.27) 108.84,77.76 114.17,77.76 115.52,79.11 120.71,79.11 121.94,80.34 121.94,81.09 126.24,85.38 126.24,86.97 127.12,87.86 147.04,87.86 148.31,89.13 174.92,89.13 175.68,89.89 182.12,89.89 182.88,89.13 204.28,89.13 205.25,90.11 220.42,90.11 222.77,92.45 233.2,92.45 236.85,88.81 236.85,83.98 238.74,82.1 238.74,80.57 246.31,73 252.85,73 253.55,72.3 253.55,70 253.87,69.68 253.87,63.98 254.87,62.97 254.87,62.31 v2(255.42,61.77)
  BOTTOM w0.102: v2(108.33,78.27) 107.88,78.71 107.44,78.71 107.16,78.43 102.3,78.43 100.96,79.77 100.96,81.18 100.23,81.91 94.49,81.91 94.14,82.26 UI1.4
USB_PWR_EN2#: length 59
  TOP w0.102: v2(254.46,58.77) 254.46,58.25 254.5,58.22 RPE9.3 ; UE1.A33 v2(251.12,59.34)
  IN4 w0.089: v2(254.46,58.77) 254.34,58.89 253.88,58.89 253.67,59.1 253.67,59.42 253.36,59.72 251.51,59.72 v2(251.12,59.34)
  BOTTOM w0.102: UI2.4 252.97,90.95 252.41,90.4 249.95,90.4 249.76,90.21 249.17,90.21 246.34,87.38 v1(246.34,86.61) 246.34,84.7 245.45,83.81 245.45,78.84 246.46,77.84 251.33,77.84 254.27,74.9 258.29,74.9 259.67,73.52 259.67,66.33 257.07,63.72 257.07,60.22 255.74,58.88 254.57,58.88 v2(254.46,58.77)
USB_PWR_SHR_EN#: length 87.3
  TOP w0.102: v2(277.52,37.46) 279.87,39.82 v1(280.84,39.82) 281.17,40.16 283.69,40.16 283.96,39.89 283.96,39.59 285.62,37.92 289.98,37.92 290.61,38.55 290.61,40.51 289.41,41.71 UI3.6 ; RPE9.4 254,58.38 v2(254.01,58.39) ; UE2.B38 256.44,38.43 v2(256.53,38.52)
  IN3 w0.122: v2(277.52,37.46) 275.74,37.46 274.7,38.5 270.99,38.5 269.15,36.66 266.2,36.66 265.11,37.76 257.28,37.76 v2(256.53,38.52)
  IN4 w0.089: v2(277.52,37.46) 276.03,38.95 276.03,53.95 270.46,59.52 263.04,59.52 262.28,60.28 257.05,60.28 256.14,59.37 256.14,58.4 255.71,57.97 254.43,57.97 v2(254.01,58.39)
USB_PWR_SHR_VBUS_EN: length 67
  TOP w0.102: v2(277.48,38.38) 279.66,40.56 v1(283.19,40.56) 283.61,40.56 284.19,39.99 284.19,39.69 285.67,38.2 289.88,38.2 290.36,38.68 290.36,40.38 289.53,41.21 UI3.5 ; RPE9.1 255.5,58.07 255.54,58.11 v2(255.54,58.44) ; v2(256.65,62.38) 256.83,62.38 257.7,61.51 258.24,61.51 258.37,61.38 UE1.B50
  IN1 w0.089: v2(256.65,62.38) 256.08,61.81 256.08,59.05 255.54,58.51 v2(255.54,58.44)
  IN4 w0.089: v2(277.48,38.38) 276.25,39.61 276.25,54.04 270.55,59.74 263.13,59.74 262.37,60.5 256.96,60.5 255.93,59.46 255.93,58.83 v2(255.54,58.44)
USBP0+: length 74.9
  TOP w0.102: UI4.6 183.18,95.62 183.24,95.56 183.32,95.56 183.37,95.5 183.37,94.93 183.28,94.84 v4(183.28,93.34) 183.28,92.72 181.26,90.7 181.26,88.76 180.88,88.39 v2(180.88,88.39)
  IN1 w0.089: v2(166.02,55.51) 166.02,55.41 165.65,55.03 165.4,55.03 165.21,55.22 165.21,56.75 165.29,56.83 165.29,65.58 163.39,67.48 160.7,67.48 160.13,68.05 160.13,71.48 157.99,73.62 153.6,73.62 152.78,74.43 152.78,75.54 153.94,76.7 157.16,76.7 158.35,77.89 158.35,77.89 169.32,88.86 181.11,88.86 181.17,88.8 181.17,88.68 v2(180.88,88.39)
  BOTTOM w0.081: UC1.AM8 166.48,55.52 166.37,55.41 166.13,55.41 v2(166.02,55.51)
USBP0-: length 74.9
  TOP w0.102: UI4.7 183.58,94.85 183.49,94.75 183.49,93.66 183.51,93.64 183.51,93.05 183.49,93.03 183.49,92.64 181.46,90.62 v2(181.46,88.39)
  IN1 w0.089: v2(165.99,54.86) 165.33,54.86 165.04,55.15 165.04,56.82 165.12,56.9 165.12,65.51 163.32,67.31 160.63,67.31 159.96,67.98 159.96,71.41 157.92,73.45 153.53,73.45 152.61,74.36 152.61,75.62 153.87,76.87 157.09,76.87 158.28,78.06 158.28,78.06 169.25,89.03 181.18,89.03 181.34,88.87 181.34,88.52 v2(181.46,88.39)
  BOTTOM w0.081: UC1.AN8 166.23,55.11 v2(165.99,54.86)
USBP0_D+: length 14.7
  TOP w0.102: v2(80.83,94.26) 80.62,94.06 79.27,94.06 78.47,93.26 78.47,92.11 78.87,91.71 79.08,91.71 79.33,91.45 79.33,90.91 79.46,90.78 DI2.2 79.63,91.17 80.09,91.64 80.64,91.64 80.82,91.82 80.95,91.82 81.23,91.54 LI3.3
  IN4 w0.089: v2(80.83,94.26) 81.02,94.07 84.22,94.07 84.61,94.46 84.61,95.24 83.99,95.87 JUSB1.3
USBP0_D-: length 14.5
  TOP w0.102: v2(80.83,93.68) 80.66,93.85 79.35,93.85 78.68,93.17 78.68,92.2 78.96,91.92 79.2,91.92 79.36,92.07 79.36,92.56 79.51,92.71 DI2.3 79.63,92.23 80.01,91.85 80.55,91.85 80.73,92.02 80.92,92.02 81.28,92.39 LI3.2
  IN4 w0.089: JUSB1.2 84.91,95.87 84.78,95.74 84.78,94.39 84.29,93.9 81.05,93.9 v2(80.83,93.68)
USBP1+: length 156.8
  TOP w0.102: UI3.3 287.76,39.92 287.63,39.79 287.63,39.61 v2(287.8,39.44)
  IN4 w0.089: v2(167.49,53.86) 167.73,53.86 167.78,53.8 167.78,52.67 169.09,51.37 171.48,51.37 179.84,43.01 187.16,43.01 188.21,41.96 188.21,36.86 198.34,26.73 231.41,26.73 233.09,25.05 233.09,23.56 236.9,19.75 265.54,19.75 265.87,19.43 269.28,19.43 271.31,21.45 275.64,21.45 279.38,25.19 279.38,30.47 279.87,30.97 279.87,38.32 280.34,38.78 287.42,38.78 287.65,39.01 287.65,39.28 v2(287.8,39.44)
  BOTTOM w0.081: UC1.AT7 167.04,53.74 167.21,53.9 167.44,53.9 v2(167.49,53.86)
USBP1-: length 156.7
  TOP w0.102: UI3.2 287.26,39.99 287.43,39.82 287.43,39.68 v2(287.16,39.41)
  IN4 w0.089: v2(287.16,39.41) 287.27,39.41 287.48,39.21 287.48,39.08 287.35,38.95 280.27,38.95 279.7,38.39 279.7,31.04 279.21,30.54 279.21,25.26 275.57,21.62 271.24,21.62 269.21,19.6 265.94,19.6 265.61,19.92 236.97,19.92 233.26,23.63 233.26,25.12 231.48,26.9 198.41,26.9 188.38,36.93 188.38,42.03 187.24,43.18 179.91,43.18 171.55,51.54 169.16,51.54 167.95,52.74 167.95,53.98 v2(167.51,54.42)
  BOTTOM w0.081: v2(167.51,54.42) 167.22,54.13 UC1.AR7
USBP1_R_D+: length 10.9
  IN4 w0.089: v2(286.37,57.26) 286.58,57.05 287.14,57.05 287.95,56.24 288.71,56.24 288.8,56.32 JUSB3.3
  BOTTOM w0.102: LI7.2 281.67,56.29 281.99,55.97 282.75,55.97 282.85,56.07 282.85,56.57 DI5.3 283.36,56.57 283.36,56.07 283.46,55.97 283.62,55.97 284.72,57.07 286.18,57.07 v2(286.37,57.26)
USBP1_R_D-: length 10.9
  IN4 w0.089: JUSB3.2 288.8,55.98 288.71,56.06 287.88,56.06 287.07,56.88 286.58,56.88 v2(286.37,56.67)
  BOTTOM w0.102: LI7.3 281.66,55.44 281.98,55.76 282.75,55.76 282.85,55.66 282.85,55.15 DI5.2 283.36,55.15 283.36,55.66 283.46,55.76 283.7,55.76 284.8,56.86 286.18,56.86 v2(286.37,56.67)
USBP2+: length 91
  IN4 w0.089: v2(231.09,26.26) 230.88,26.04 230.4,26.04 230.22,26.23 198.04,26.23 187.74,36.53 187.74,41.77 187,42.51 179.52,42.51 172.97,49.06 171.51,49.06 169.67,50.9 168.78,50.9 167.57,52.11 167.57,52.68 166.88,53.38 166.88,53.76 166.57,54.06 166.28,54.06 v2(166.02,54.32)
  BOTTOM w0.081: UC1.AP8 166.16,54.45 v2(166.02,54.32)
  BOTTOM w0.102: v2(231.09,26.26) 231.26,26.09 231.38,26.09 231.53,26.23 231.53,27.17 231.12,27.57 231.12,29.75 230.87,30.01 230.87,32.51 231.56,33.2 232.47,33.2 232.61,33.35 JNGFF1.3
USBP2-: length 90.9
  IN4 w0.089: v2(231.09,25.67) 230.89,25.87 230.33,25.87 230.15,26.06 197.97,26.06 187.57,36.46 187.57,41.7 186.93,42.34 179.45,42.34 172.9,48.89 171.44,48.89 169.6,50.73 168.71,50.73 167.4,52.04 167.4,52.61 166.71,53.31 166.71,53.69 166.5,53.89 166.22,53.89 v2(166.02,53.7)
  BOTTOM w0.081: v2(166.02,53.7) 166.13,53.8 UC1.AR8
  BOTTOM w0.102: v2(231.09,25.67) 231.27,25.85 231.43,25.85 231.73,26.15 231.73,27.25 231.33,27.66 231.33,29.84 231.07,30.1 231.07,32.42 231.65,33 232.47,33 232.61,32.85 JNGFF1.5
USBP3+: length 136
  IN1 w0.089: v2(243.6,82.58) 243.82,82.36 243.82,82.27 243.68,82.13 242.55,82.13 239.44,85.25 239.44,85.57 236.12,88.88 233.08,88.88 232.8,88.59 232.15,88.59 231.8,88.95 222.43,88.95 222.1,89.27 203.89,89.27 203.15,88.54 187.82,88.54 186.69,89.67 168.41,89.67 156.57,77.83 153.78,77.83 152.13,76.17 152.13,73.4 152.82,72.71 157.39,72.71 158.16,71.94 158.16,67.56 161.32,64.4 161.32,59.38 161.58,59.12 162.22,59.12 163.42,57.92 163.42,56.8 163.77,56.45 164.39,56.45 164.51,56.32 164.51,56.25 164.51,53.59 164.84,53.26 165.36,53.26 v2(165.55,53.07)
  BOTTOM w0.081: v2(165.55,53.07) 165.14,53.48 UC1.AT10
  BOTTOM w0.102: v2(243.6,82.58) 243.78,82.77 243.78,83.14 243.64,83.28 UI5.8
USBP3-: length 136
  IN1 w0.089: v2(244.18,82.58) 243.99,82.4 243.99,82.2 243.75,81.96 242.48,81.96 239.27,85.18 239.27,85.5 236.05,88.71 233.15,88.71 232.87,88.42 232.08,88.42 231.73,88.78 222.35,88.78 222.03,89.1 203.96,89.1 203.22,88.37 187.75,88.37 186.62,89.5 168.48,89.5 156.64,77.65 153.85,77.65 152.3,76.1 152.3,73.47 152.89,72.88 157.46,72.88 158.33,72.01 158.33,67.63 161.49,64.47 161.49,59.45 161.65,59.29 162.29,59.29 163.59,57.99 163.59,56.87 163.84,56.62 164.46,56.62 164.68,56.39 164.68,56.18 164.68,53.66 164.91,53.43 165.39,53.43 165.4,53.44 165.48,53.44 165.55,53.5 165.55,53.74 v2(165.49,53.8)
  BOTTOM w0.081: UC1.AR10 165.3,54.13 165.49,53.94 v2(165.49,53.8)
  BOTTOM w0.102: v2(244.18,82.58) 243.99,82.77 243.99,83.14 244.14,83.28 UI5.7
USBP3_D+: length 10.7
  IN4 w0.089: v2(241.85,93.38) 242.08,93.6 242.08,94.47 242.72,95.11 242.72,95.78 242.63,95.87 JUSB2.3
  BOTTOM w0.102: v2(241.85,93.38) 242.04,93.19 242.04,92.21 243.28,90.98 243.28,90.55 243.17,90.44 DI3.3 242.99,89.87 243.17,89.87 243.28,89.77 243.28,88.95 242.97,88.64 LI4.2
USBP3_D-: length 10.7
  IN4 w0.089: JUSB2.2 242.98,95.87 242.89,95.78 242.89,95.04 242.25,94.4 242.25,93.56 v2(242.44,93.38)
  BOTTOM w0.102: v2(242.44,93.38) 242.25,93.19 242.25,92.3 243.48,91.06 243.48,90.55 243.58,90.44 DI3.2 243.77,89.87 243.58,89.87 243.48,89.77 243.48,88.98 243.82,88.64 LI4.3
USBP4+: length 92.1
  IN4 w0.076: 161.85,55.91 162.08,55.91
  IN4 w0.089: v2(96.28,91.43) 96.48,91.63 96.48,91.85 96.89,92.26 97.69,92.26 99.37,90.58 99.37,87.6 106.11,80.87 109.8,80.87 111.07,82.14 124.32,82.14 133.74,72.72 149.69,72.72 150.68,71.73 150.68,71.28 151.87,70.1 151.87,69.08 154.75,66.2 155.55,66.2 157.89,63.87 157.89,59.42 158.47,58.85 160.09,58.85 161.81,57.13 161.81,55.95 161.85,55.91 ; 162.08,55.91 v2(162.25,56.08)
  BOTTOM w0.081: v2(162.25,56.08) 162.34,56.08 162.64,56.38 UC1.AL15
  BOTTOM w0.102: LV27.3 95.27,93.36 95.59,93.04 95.59,92.8 v4(95.9,92.49) 96.46,91.92 96.46,91.61 v2(96.28,91.43)
USBP4-: length 92.1
  IN4 w0.089: v2(162.25,55.37) 162.29,55.41 162.29,55.65 162.23,55.72 162.1,55.72 162.08,55.74 161.78,55.74 161.64,55.88 161.64,57.05 160.02,58.68 158.4,58.68 157.72,59.35 157.72,63.8 155.48,66.03 154.68,66.03 151.7,69.01 151.7,70.03 150.51,71.21 150.51,71.66 149.62,72.55 133.67,72.55 124.25,81.97 111.14,81.97 109.87,80.7 106.04,80.7 99.2,87.53 99.2,90.5 97.62,92.09 96.96,92.09 96.65,91.78 96.65,91.63 v2(96.86,91.43)
  BOTTOM w0.081: v2(162.25,55.37) 162.64,55.76 UC1.AM15
  BOTTOM w0.102: v2(96.86,91.43) 96.67,91.61 96.67,92.01 96.29,92.39 96.29,92.43 95.86,92.86 95.82,92.86 95.8,92.88 95.8,93.11 96.12,93.43 LV27.2
USBP4_D+: length 14.5
  BOTTOM w0.102: JEDP1.3 99.96,91.7 99.94,91.72 99.94,92.3 99.96,92.32 99.96,92.92 99.94,92.94 99.94,94.82 98.96,95.79 98.8,95.79 98.59,96 98.59,96.18 98.69,96.28 99.29,96.28 99.48,96.47 DV4.3 98.77,96.62 98.59,96.79 98.59,97.49 98.27,97.82 96.26,97.82 v4(95.73,97.29) 95.27,96.83 LV27.4
USBP4_D-: length 14.2
  BOTTOM w0.102: LV27.1 96.12,96.01 95.93,96.19 95.59,96.19 95.49,96.29 95.49,96.76 95.65,96.92 95.68,96.92 96.1,97.34 96.1,97.37 96.34,97.61 98.18,97.61 98.38,97.41 98.38,96.82 98.18,96.62 DV4.2 97.74,96.43 98.21,96.43 98.33,96.3 98.33,95.95 98.7,95.58 98.88,95.58 99.73,94.73 v4(99.73,92.62) 99.73,91.98 99.46,91.7 JEDP1.2
USBP5+: length 76.5
  IN4 w0.089: v2(108.95,82) 108.67,81.72 108.53,81.72 108.38,81.88 108.38,82.4 109.78,83.79 123.33,83.79 133.79,73.34 150.23,73.34 150.99,72.57 151.73,72.57 154.2,70.11 154.2,69.11 158.04,65.26 158.92,65.26 160.42,63.76 160.42,59.49 161.11,58.8 162.57,58.8 163.41,57.96 163.41,56.99 162.96,56.53 162.96,55.71 163.22,55.45 163.69,55.45 163.8,55.33 163.8,55.2 v2(163.65,55.05)
  BOTTOM w0.081: v2(163.65,55.05) 163.26,55.43 UC1.AN13
  BOTTOM w0.102: LZ1.4 108.11,82.12 108.43,81.8 108.74,81.8 v2(108.95,82)
USBP5-: length 76.6
  IN4 w0.089: v2(163.65,55.81) 163.45,55.62 163.29,55.62 163.13,55.78 163.13,56.46 163.58,56.92 163.58,58.03 162.64,58.97 161.18,58.97 160.59,59.56 160.59,63.83 158.99,65.43 158.11,65.43 154.37,69.18 154.37,70.18 151.8,72.75 151.06,72.75 150.3,73.51 133.86,73.51 123.4,83.96 109.71,83.96 108.21,82.47 108.21,81.81 108.46,81.55 108.82,81.55 v2(108.95,81.42)
  BOTTOM w0.081: v2(163.65,55.81) 163.36,55.81 163.21,55.97 UC1.AM13
  BOTTOM w0.102: v2(108.95,81.42) 108.78,81.59 108.46,81.59 108.14,81.27 LZ1.1
USBP5_D+: length 9.9
  BOTTOM w0.102: JEDP1.13 104.96,89.62 104.81,89.48 104.81,87.98 105.03,87.76 105.03,81.86 105.18,81.71 105.28,81.71 105.38,81.81 105.38,82.06 105.43,82.12 LZ1.3
USBP5_D-: length 10.1
  BOTTOM w0.102: LZ1.2 105.71,81.27 105.48,81.5 105.1,81.5 104.82,81.78 104.82,87.67 104.6,87.89 104.6,89.48 104.46,89.62 JEDP1.12
USBP6+: length 111.1
  TOP w0.102: JUSH1.18 251.67,10.67 251.53,10.81 251.53,11.3 251.16,11.66 250.92,11.66 250.81,11.77 250.81,11.96 v2(250.97,12.12)
  IN4 w0.089: v2(250.97,12.12) 250.71,12.38 250.71,13.54 249.48,14.77 240.34,14.77 235.14,19.98 234.31,19.98 233.68,20.61 233.68,21.12 229.68,25.12 197.21,25.12 182.99,39.33 179.65,39.33 173.48,45.5 170.88,45.5 169.41,46.97 168.91,46.97 166.43,49.45 166.43,51.07 165.03,52.46 165.03,54.84 164.7,55.17 164.41,55.17 v2(164.15,55.44)
  BOTTOM w0.081: v2(164.15,55.44) 164.48,55.11 UC1.AN11
USBP6-: length 110.9
  TOP w0.102: JUSH1.19 251.17,10.71 251.32,10.86 251.32,11.21 251.07,11.45 250.84,11.45 250.61,11.68 250.61,11.9 v2(250.39,12.12)
  IN4 w0.089: v2(250.39,12.12) 250.54,12.27 250.54,13.47 249.41,14.6 240.27,14.6 235.07,19.81 234.24,19.81 233.51,20.54 233.51,21.05 229.61,24.95 197.14,24.95 182.92,39.16 179.58,39.16 173.41,45.33 170.81,45.33 169.34,46.8 168.84,46.8 166.26,49.38 166.26,51 164.86,52.39 164.86,54.77 164.63,55 164.27,55 164.15,54.88 v2(164.15,54.74)
  BOTTOM w0.081: v2(164.15,54.74) 164.43,54.45 UC1.AP11
USBP7+: length 136.6
  IN4 w0.089: v2(229.89,23.57) 229.8,23.66 229.8,24.03 229.41,24.43 227.97,24.43 227.69,24.15 197.27,24.15 182.73,38.69 176.47,38.69 169.49,45.68 168.68,45.68 168.23,46.13 168.23,46.53 165.86,48.91 165.86,50.89 164.32,52.43 164.32,54.03 164.05,54.3 163.81,54.3 v2(163.64,54.47)
  BOTTOM w0.081: v2(163.64,54.47) 163.52,54.47 UC1.AP13
  BOTTOM w0.102: v2(229.89,23.57) 229.89,24.46 229.64,24.71 229.64,28.65 228.66,29.63 228.66,33.82 229.25,34.41 229.25,36.06 229.99,36.8 229.99,38.92 230.63,39.56 v4(230.63,39.88) 230.63,45.01 232.5,46.88 232.5,48.07 234.27,49.84 234.27,50.52 236.22,52.47 236.22,67.28 235.84,67.67 235.84,69.82 234.31,71.35 JNGFF2.7
USBP7-: length 136.5
  IN4 w0.089: v2(163.64,53.85) 163.64,54 163.77,54.13 163.98,54.13 164.15,53.96 164.15,52.36 165.69,50.82 165.69,48.84 168.06,46.46 168.06,46.06 168.61,45.51 169.41,45.51 176.4,38.52 182.66,38.52 197.2,23.98 227.76,23.98 228.04,24.26 229.33,24.26 229.63,23.96 229.63,23.89 v2(229.31,23.57)
  BOTTOM w0.081: UC1.AR13 163.36,54.13 v2(163.64,53.85)
  BOTTOM w0.102: v2(229.31,23.57) 229.62,23.88 229.62,24.44 229.43,24.63 229.43,28.56 228.45,29.54 228.45,33.91 229.04,34.49 229.04,36.14 229.79,36.89 229.79,39.01 230.4,39.62 230.4,40.15 230.42,40.17 230.42,45.09 232.29,46.96 232.29,48.16 234.06,49.92 234.06,50.61 236.01,52.56 236.01,67.2 235.63,67.58 235.63,69.74 234.22,71.14 233.41,71.14 233.33,71.06 233.33,70.95 233.23,70.85 JNGFF2.9
USBRBIAS: length 12.6
  TOP w0.102: v2(164.72,57.69) 165.29,57.13 v1(165.29,57) 165.29,56.74 164.91,56.36 164.91,51.41 163.89,50.39 RC152.1
  BOTTOM w0.254: UC1.AJ11 164.41,57.38 v2(164.72,57.69) 165.04,57.38 UC1.AJ10
USH_DET#: length 139.5
  TOP w0.102: JUSH1.1 260.17,9.42 259.81,9.07 250.85,9.07 250.03,9.89 248.06,9.89 247.25,10.7 v1(247.25,13.88) 247.25,14.18 246.64,14.78 243.72,14.78 240.75,17.75 239.39,17.75 236.41,20.74 236.41,22.9 236.03,23.28 236.03,23.33 230.9,28.46 230.9,34.38 v2(230.63,34.65) ; RPC15.1 180.5,62.9 180.64,63.04 180.64,63.54 v2(180.51,63.67)
  IN3 w0.076: 172.83,62.83 173.36,62.83
  IN3 w0.081: 172.83,62.83 172.64,63.02 171.83,63.02 170.44,64.41 170.44,65.23 170.35,65.32 170.35,70.15 170.08,70.42 v2(169.8,70.42)
  IN3 w0.122: v2(230.63,34.65) 229.09,34.65 227.81,33.36 210.64,33.36 208.29,35.72 199.94,35.72 194.11,41.55 194.11,46.86 193.85,47.12 193.85,48.38 192.74,49.49 192.74,49.69 192.74,55.98 188.34,60.39 188.34,62.46 186.69,64.11 184.99,64.11 184.92,64.18 181.03,64.18 v2(180.51,63.67) 180.36,63.82 176.72,63.82 176.22,63.32 175.36,63.32 174.86,62.83 173.36,62.83
  BOTTOM w0.076: UC1.E3 169.48,70.74 v2(169.8,70.42)
USH_PWR_STATE#: length 78.8
  TOP w0.102: JUSH1.5 258.17,11.14 RZ10.2 258.43,12.42 258.43,13.39 v3(257.79,14.03) 257.31,14.5 v2(257.06,14.5) ; v2(251.13,58.76) 251.62,59.25 UE1.A34
  IN1 w0.089: v2(257.06,14.5) 257.29,14.73 257.29,20.48 264.39,27.58 264.39,27.75 268.46,31.83 268.46,36.33 269.35,37.22 269.35,38.28 270.7,39.63 270.7,42.17 272.37,43.84 272.37,44.7 273.11,45.44 275.02,45.44 275.4,45.83 275.4,46.76 274.21,47.95 268.86,47.95 264.92,51.88 264.92,54.4 262.46,56.87 260.78,56.87 259.86,57.78 252.12,57.78 251.15,58.76 v2(251.13,58.76)
USH_SMBCLK: length 38.8
  TOP w0.102: RZ8.2 252.98,11.94 252.98,11.53 252.82,11.37 ; UE2.A50 265.24,39.21 v2(265.62,38.84) ; JUSH1.16 252.67,10.66 253.02,11.01 253.02,11.16 252.82,11.37 ; 252.82,11.37 v2(252.81,11.37)
  IN1 w0.089: v2(252.81,11.37) 252.81,11.54 253.06,11.79 253.06,12.22 253.82,12.98 253.82,25.22 257.78,29.18 261.07,29.18 264.42,32.53 264.42,36.37 265.4,37.36 265.4,38.62 v2(265.62,38.84)
USH_SMBDAT: length 40.5
  TOP w0.102: JUSH1.15 253.17,10.83 253.25,10.91 253.25,11.28 v2(253.4,11.43) 253.2,11.63 253.2,12.04 RZ9.2 ; UE2.B53 263.02,38.96 v2(262.88,39.11)
  IN1 w0.089: v2(265.81,38.26) 265.62,38.07 265.62,37.27 264.63,36.28 264.63,32.44 261.15,28.97 257.87,28.97 254.04,25.13 254.04,12.89 253.27,12.13 253.27,11.75 253.4,11.62 v2(253.4,11.43)
  BOTTOM w0.102: v2(262.88,39.11) 263.7,39.11 264.54,38.26 v2(265.81,38.26)
VCI_IN2#: length 10.2
  TOP w0.102: RPE5.4 264.77,50.92 v2(265,50.68) ; UE2.B63 262.84,43.96 v2(262.86,43.95)
  BOTTOM w0.102: v2(265,50.68) 265.27,50.68 265.67,50.28 265.67,46.76 v1(263.54,44.63) v2(262.86,43.95)
VCT_LAN_R1: length 1.9
  TOP w0.203: v2(254.59,86) 254.58,85.99 UL1.6
  BOTTOM w0.254: v2(254.59,86) RL3.2
VFB: length 2.2
  TOP w0.203: PU500.24 107,68.43 107.32,68.75 v1(107.72,68.75) PR531.2
VGA_ID: length 10.8
  TOP w0.102: v1(266.81,65.07) 266.29,64.55 v2(266.13,64.55) 265.3,63.73 RE84.1 ; v2(258.76,64.36) 258.76,64.81 258.97,65.01 UE1.B59
  IN3 w0.122: v2(258.76,64.36) 265.94,64.36 v2(266.13,64.55)
VIDALERT_N: length 31.7
  TOP w0.102: PR528.2 101.29,70.99 101.45,70.99 101.56,70.88 101.56,70.41 102.68,69.3 v2(102.68,69.07) PU500.32
  IN1 w0.089: v2(102.68,69.07) 102.68,69.86 103.27,70.46 104.77,70.46 105.81,69.42 106.83,69.42 109.42,66.83 126.36,66.83 v2(126.86,66.33)
  BOTTOM w0.102: RC207.2 127.29,66.92 127.24,66.96 RC204.2 v2(126.86,66.33)
VIDSCLK: length 33.5
  TOP w0.102: PU500.31 103.55,69.78 v2(103.67,69.9) 102.97,69.9 PR527.2
  IN1 w0.089: v2(131.68,66.4) 130.17,66.4 129.39,65.61 125.98,65.61 125.31,66.28 109.14,66.28 106.56,68.86 105.55,68.86 104.51,69.9 v2(103.67,69.9)
  BOTTOM w0.102: UC1.N63 132.09,66.4 v2(131.68,66.4)
VIDSOUT: length 48.9
  TOP w0.102: PR529.2 99.52,70.55 99.52,70.48 99.61,70.4 100.2,70.4 100.39,70.59 100.6,70.59 101.28,69.9 101.28,69.7 100.96,69.37 100.96,69.19 101.13,69.03 101.31,69.03 101.63,69.35 101.81,69.35 102.02,69.15 102.02,68.97 v2(101.72,68.68) 101.97,68.43 PU500.1
  IN1 w0.089: v2(101.72,68.68) 101.01,69.39 101.01,70.17 101.86,71.02 105.04,71.02 106.08,69.98 107.09,69.98 109.69,67.37 131.4,67.37 v2(131.59,67.19)
  BOTTOM w0.102: UC1.L63 131.7,67.08 v2(131.59,67.19) 131.35,67.43 130.67,67.43 130.59,67.35 130.59,66.79 130.51,66.71 130.16,66.71 130.08,66.79 v1(130.08,67.41) 130.08,67.91 130.01,67.98 129.36,67.98 129.28,67.91 129.28,67.67 129.58,67.37 129.58,66.79 129.51,66.71 129.21,66.71 129.13,66.79 129.13,67.08 129.05,67.16 128.58,67.16 128.5,67.23 128.5,67.7 RC208.2
VMM2320_AUX: length 15.5
  TOP w0.102: UV600.28 221.69,70.09 221.65,70.05 221.38,70.05 221.06,69.73 221.06,69.24 220.93,69.11 220.75,69.11 RV608.2 220.37,69.38 219.87,68.88 219.61,68.88 v2(219.19,68.47) ; v2(212.42,68.42) 212.3,68.31 212.3,67.97 211.94,67.6 210.77,67.6 210.42,67.96 210.42,68.17 CV110.1
  IN1 w0.089: v2(219.19,68.47) 219.35,68.31 219.35,68.09 219.24,67.98 212.28,67.98 212.21,68.05 212.21,68.21 v2(212.42,68.42)
VMM2320_AUX#: length 15.5
  TOP w0.102: CV111.1 210.85,68.63 210.7,68.63 210.63,68.55 210.63,68.04 210.86,67.81 211.85,67.81 212.1,68.05 212.1,68.18 211.85,68.42 v2(211.84,68.42) ; UV600.29 221.71,69.69 221.56,69.84 221.47,69.84 221.27,69.65 221.27,69.15 221.02,68.9 220.87,68.9 RV604.2 220.19,68.78 220.09,68.78 v2(219.77,68.47)
  IN1 w0.089: v2(219.77,68.47) 219.75,68.47 219.52,68.24 219.52,68.02 219.31,67.81 212.21,67.81 212.04,67.98 212.04,68.22 v2(211.84,68.42)
VMM2320_AUX#_C: length 5.6
  TOP w0.102: CV111.2 210.81,69.59 210.81,69.97 v4(210.46,70.32) 209.27,71.51 208.94,71.51 207.93,72.52 207.93,72.92 UV8.H2
VMM2320_AUX_C: length 5.6
  TOP w0.102: UV8.H1 207.49,72.56 207.49,72.35 207.55,72.29 207.87,72.29 208.86,71.3 209.19,71.3 210.11,70.38 210.11,70.35 210.6,69.86 210.6,69.33 210.46,69.19 210.32,69.19 CV110.2
VMM2320_HPD: length 21.9
  TOP w0.102: UV8.J1 208.43,72.64 208.98,72.09 209.82,72.09 v2(210.44,71.47) ; UV600.38 v2(225.63,67.74)
  IN1 w0.089: v2(225.63,67.74) 224.79,68.58 223.12,68.58 222.16,69.54 218.91,69.54 218.34,70.12 218.34,71.08 218.11,71.31 210.6,71.31 v2(210.44,71.47)
  BOTTOM w0.102: v1(226.2,68.55) 225.63,67.99 v2(225.63,67.74)
VMM2320_N0: length 23.4
  TOP w0.102: UV600.39 226.03,68.15 226.12,68.05 226.12,66.84 v2(225.94,66.65) ; CV103.1 208.73,68.08 208.73,67.93 v2(208.54,67.74)
  IN4 w0.089: v2(208.54,67.74) 208.75,67.95 208.75,68.13 208.95,68.33 209.94,68.33 211.64,66.62 219.82,66.62 221.55,64.9 224.79,64.9 226.15,66.25 226.15,66.44 v2(225.94,66.65)
VMM2320_N0_C: length 5.6
  TOP w0.102: CV103.2 208.73,69.68 208.73,69.81 208.47,70.07 208.11,70.07 207.58,70.61 v4(207.32,70.61) 207.02,70.61 206.59,71.04 206.59,72.8 206.91,73.12 UV8.G2
VMM2320_N1: length 24.1
  TOP w0.102: CV105.1 206.95,68.08 206.95,67.98 v2(206.77,67.79) ; v2(224.74,66.65) 224.92,66.84 224.92,68.05 224.83,68.15 UV600.36
  IN4 w0.089: v2(206.77,67.79) 206.98,68 206.98,68.37 207.58,68.98 210.48,68.98 212.18,67.28 220.08,67.28 221.81,65.54 224.45,65.54 224.94,66.03 224.94,66.44 v2(224.74,66.65)
VMM2320_N1_C: length 4.7
  TOP w0.102: CV105.2 206.86,69.59 206.86,69.73 206.78,69.81 206.59,69.81 205.94,70.46 v4(205.94,70.69) 205.94,72.8 206.26,73.12 UV8.F2
VMM2320_N2: length 24.8
  TOP w0.102: v2(223.66,66.99) 223.85,67.18 223.85,67.36 224.12,67.64 224.12,68.1 224.03,68.2 UV600.34 ; v2(204.99,67.74) 205.18,67.93 205.18,68.08 CV107.1
  IN4 w0.089: v2(204.99,67.74) 205.19,67.95 205.19,68.29 206.54,69.64 211.16,69.64 211.68,69.11 212.68,69.11 213.87,67.93 220.33,67.93 222.08,66.18 223.58,66.18 223.85,66.45 223.85,66.8 v2(223.66,66.99)
VMM2320_N2_C: length 4.3
  TOP w0.102: CV107.2 205.08,69.59 205.08,70.91 205.28,71.1 205.28,72.95 UV8.E2
VMM2320_N3: length 28.1
  TOP w0.102: v2(203.21,67.74) 203.4,67.93 203.4,68.08 CV109.1 ; UV600.31 222.83,68.2 222.92,68.1 222.92,67.99 222.69,67.75 222.69,67.44 v2(222.5,67.25)
  IN4 w0.089: v2(203.21,67.74) 203.42,67.95 203.42,68.65 205.04,70.28 212.6,70.28 214.3,71.99 219.45,71.99 220.3,71.13 220.3,69.96 221.26,69.01 221.26,67.9 222.34,66.82 222.6,66.82 222.72,66.94 222.72,67.03 v2(222.5,67.25)
VMM2320_N3_C: length 4.7
  TOP w0.102: UV8.D2 204.96,73.05 204.64,72.73 204.64,71.35 v4(203.56,70.27) 203.31,70.01 203.31,69.59 CV109.2
VMM2320_P0: length 23.4
  TOP w0.102: UV600.40 226.43,68.15 226.33,68.05 226.33,66.84 v2(226.52,66.65) ; CV102.1 208.94,68.08 208.94,67.93 v2(209.13,67.74)
  IN4 w0.089: v2(226.52,66.65) 226.32,66.45 226.32,66.18 224.86,64.73 221.48,64.73 219.75,66.45 211.57,66.45 209.87,68.16 209.02,68.16 208.93,68.06 208.93,67.94 v2(209.13,67.74)
VMM2320_P0_C: length 5.6
  TOP w0.102: UV8.G1 207.21,72.64 207.3,72.55 207.3,72.42 207.21,72.33 206.9,72.33 206.8,72.23 206.8,71.13 207.09,70.84 207.64,70.84 208.2,70.28 208.55,70.28 208.94,69.9 208.94,69.68 CV102.2
VMM2320_P1: length 24.1
  TOP w0.102: CV104.1 207.16,68.08 207.16,67.98 v2(207.35,67.79) ; UV600.37 225.23,68.15 225.13,68.05 225.13,66.84 v2(225.32,66.65)
  IN4 w0.089: v2(225.32,66.65) 225.11,66.44 225.11,65.96 224.52,65.37 221.74,65.37 220,67.11 212.11,67.11 210.41,68.81 207.66,68.81 207.15,68.3 207.15,67.99 v2(207.35,67.79)
VMM2320_P1_C: length 4.6
  TOP w0.102: CV104.2 207.25,69.09 207.15,69.09 207.07,69.16 207.07,69.82 206.87,70.02 206.68,70.02 206.17,70.52 206.17,71.04 206.15,71.06 206.15,72.53 UV8.F1
VMM2320_P2: length 24.8
  TOP w0.102: v2(205.57,67.74) 205.38,67.93 205.38,68.08 CV106.1 ; v2(224.24,66.99) 224.06,67.18 224.06,67.28 224.33,67.55 224.33,68.1 224.43,68.2 UV600.35
  IN4 w0.089: v2(224.24,66.99) 224.02,66.77 224.02,66.38 223.65,66.01 222.01,66.01 220.26,67.76 213.79,67.76 212.61,68.94 211.61,68.94 211.09,69.47 206.61,69.47 205.36,68.22 205.36,67.95 v2(205.57,67.74)
VMM2320_P2_C: length 4.1
  TOP w0.102: CV106.2 205.53,69.14 205.34,69.14 205.29,69.19 205.29,70.82 205.49,71.02 205.49,72.51 UV8.E1
VMM2320_P3: length 28.1
  TOP w0.102: v2(223.08,67.25) 222.9,67.44 222.9,67.67 223.13,67.9 223.13,68.1 223.23,68.2 UV600.32 ; CV108.1 203.61,68.08 203.61,67.93 v2(203.79,67.74)
  IN4 w0.089: v2(223.08,67.25) 222.89,67.05 222.89,66.87 222.67,66.65 222.27,66.65 221.09,67.83 221.09,68.94 220.13,69.89 220.13,71.06 219.38,71.82 214.37,71.82 212.67,70.11 205.11,70.11 203.59,68.58 203.59,67.95 v2(203.79,67.74)
VMM2320_P3_C: length 4.6
  TOP w0.102: UV8.D1 204.85,72.53 204.85,71.27 203.91,70.33 203.91,70.3 203.51,69.9 203.51,69.2 203.58,69.14 203.75,69.14 CV108.2
VMM2320_VGA_DET: length 5.5
  TOP w0.102: RV88.2 214.95,73.82 v1(211.57,73.82) 210.28,73.82 UV8.M3
VMM2320_VGA_IREF: length 4.8
  TOP w0.102: RV89.1 213.78,76.15 212.86,75.24 v1(212.04,75.24) UV8.M5
VMM2320_VGA_NC: length 4
  TOP w0.102: UV8.L5 209.86,75.59 212.72,75.59 T108.1
VMM_DPB_CTRLCLK: length 12.6
  TOP w0.102: RPV1.1 210.31,84.25 210.36,84.19 210.36,82.79 v2(209.44,81.86) 209.44,82.19 209.35,82.28 209.05,82.28 208.91,82.14 208.91,81.51 209.2,81.22 209.2,80.78 UV8.K13
  BOTTOM w0.102: v1(210.04,81.64) 209.81,81.86 v2(209.44,81.86) 209.08,82.23 209.08,84.2 208.98,84.3 208.57,84.3 208.38,84.49 208.38,84.71 208.53,84.86 209.06,84.86 209.52,85.31 UV11.12
VMM_DPB_CTRLDAT: length 9.9
  TOP w0.102: UV8.L14 209.51,81.39 210.81,82.68 v2(210.81,83.42) RPV1.2
  BOTTOM w0.102: v2(210.81,83.42) 211.08,83.42 v1(211.95,84.29) 211.95,86.64 211.32,87.26 UV11.9
VMM_DPC_CTRLCLK: length 17.6
  TOP w0.102: RPV2.4 199.87,81.57 200.14,81.3 v2(200.39,81.3) 202.32,81.3 202.73,80.89 202.73,80.28 202.9,80.11 203.34,80.11 UV8.B12
  IN1 w0.089: v2(197.61,83.82) 197.22,83.82 197.03,83.64 197.03,82.42 198.37,81.09 200.18,81.09 v2(200.39,81.3)
  BOTTOM w0.102: UV12.12 198.25,84.58 197.61,83.95 v2(197.61,83.82) 198.51,83.82 199.2,83.13 v1(200.87,83.13)
VMM_DPC_CTRLDAT: length 14.1
  TOP w0.102: UV8.A12 202.8,79.79 202.54,80.05 202.54,80.81 202.25,81.1 202.12,81.1 202.03,81.02 202.03,80.82 201.91,80.7 201.74,80.7 201.63,80.82 201.63,80.95 201.52,81.05 200.95,81.05 v1(200.85,80.95) 200.62,80.72 v2(200.39,80.72) 200.19,80.72 199.84,81.07 RPV2.3
  IN1 w0.089: v2(196.13,83.8) 196.82,83.11 196.82,82.33 198.28,80.87 200.23,80.87 v2(200.39,80.72)
  BOTTOM w0.102: v2(196.13,83.8) 196.13,84.16 196.39,84.42 196.39,85.4 196.3,85.5 UV12.9
VMM_GPIO4: length 4.4
  TOP w0.076: 202.39,82.85 203.66,81.58 UV8.B14
  TOP w0.102: 202.39,82.85 201.23,84.01 RV518.2
VMM_GPIO5: length 5.1
  TOP w0.076: 203.02,82.85 203.97,81.9 203.97,80.87 203.66,80.56 UV8.B13
  TOP w0.102: 203.02,82.85 v1(202.78,83.09) 202.52,83.09 202.13,83.48 RV519.2
VMM_GPIO6: length 4.3
  TOP w0.102: UV8.C1 204.31,72.29 202.61,70.58 202.61,70.08 202.17,69.64 RV83.1
VMM_GPIO7: length 5.7
  TOP w0.102: RPV1.3 211.31,84.28 211.21,84.18 211.21,82.73 209.8,81.32 209.8,80.14 UV8.M12
VMM_GPIO8: length 5.2
  TOP w0.102: UV8.M13 210.62,80.44 211.64,81.46 v3(211.64,82.83) 211.64,83.78 211.81,83.95 RPV1.4
VMM_GPIO9: length 5.4
  TOP w0.102: UV8.L3 209.84,74.26 213.08,74.26 v1(213.22,74.4) 213.99,75.17 RV73.1
VMM_SPI_CLK: length 9.2
  TOP w0.102: v2(197.6,71.48) 198.05,71.93 v1(199.39,71.93) 200.66,71.93 202.33,73.61 203.31,73.61 203.64,73.94 UV8.B3
  BOTTOM w0.102: v2(197.6,71.48) 197.09,71.99 UV9.6
VMM_SPI_CS#: length 6.5
  TOP w0.102: RV86.2 199.44,73.32 v1(199.69,73.57) 201.67,73.57 202.47,74.37 v2(202.52,74.37) 202.74,74.59 UV8.A4
  BOTTOM w0.102: v2(202.52,74.37) 202.12,74.37 201.97,74.52 UV9.1
VMM_SPI_DIN: length 3.6
  TOP w0.102: UV8.B4 v2(203.34,74.26)
  BOTTOM w0.102: v2(203.34,74.26) 203.34,73.97 202.63,73.25 200.83,73.25
VMM_SPI_DO: length 8.7
  TOP w0.102: UV8.A3 202.33,73.94 200.86,72.47 v1(197.88,72.47) v2(196.9,71.48)
  BOTTOM w0.102: v2(196.9,71.48) 196.14,70.72 195.66,70.71
VMM_SPI_HOLD: length 4.1
  BOTTOM w0.102: 195.66,73.25 194.75,73.25 194.43,72.94 194.43,72.03 RV87.2 193.93,70.95 v1(193.53,70.56)
VMM_SPI_WP#: length 4.9
  TOP w0.102: v2(202.83,71.68) 203.66,72.51 UV8.B1
  BOTTOM w0.102: RV517.2 v1(202.83,71.07) v2(202.83,71.68) 202.69,71.82 201.91,71.82 201.75,71.98 UV9.3
VR_HOT#: length 2.9
  TOP w0.102: PR534.2 103.13,70.84 103.31,70.66 103.93,70.66 104.25,70.34 104.25,69.8 103.95,69.5 PU500.30
VREF: length 31.6
  TOP w0.203: v2(106.54,70.4) 105.84,70.4 105.15,69.71 PU500.27
  TOP w0.254: v2(106.54,70.4) PC507.2 106.93,70.77 PR521.2
  IN4 w0.254: v2(100.49,59.61) 100.82,59.94 v2(100.82,61.58) 100.82,62.66 100.19,63.29 100.19,70.09 101.2,71.1 105.84,71.1 v2(106.54,70.4)
  BOTTOM w0.254: PR500.2 106.6,61.13 v1(106,60.53) 103.71,60.53 102.6,61.64 PR502.2 PR503.2 PR504.2 v2(100.82,61.58) ; v2(100.49,59.61) PH500.1
VSET_5085: length 3.3
  TOP w0.102: RE77.1 CE38.1 251.89,46.33 v1(252.44,46.33) 252.8,46.33 252.92,46.21 UE2.A17
VSYNC_DOCK: length 86.9
  TOP w0.102: v2(215.82,85.2) 214.42,85.2 212.25,83.03 212.25,80.18 210.2,78.13 209.8,78.13 UV8.L9
  BOTTOM w0.102: JDOCK1.67 150.45,95.99 150.36,95.9 150.36,94.18 151.99,92.56 156,92.56 158.82,95.37 164.84,95.37 166.6,93.62 183.14,93.62 183.96,92.8 193.87,92.8 195.64,91.03 v1(210.63,91.03) 212.52,91.03 215.82,87.74 v2(215.82,85.2)
WIGIG_32KHZ: length 15.3
  TOP w0.102: RZ57.2 RZ56.2 252.77,23.91 v1(250.1,23.91) v2(249.29,23.91)
  IN4 w0.089: v2(243.37,23.41) 243.93,23.96 249.23,23.96 v2(249.29,23.91)
  BOTTOM w0.102: v2(243.37,23.41) 243.15,23.41 242.3,22.55 242.3,21.98 241.92,21.6 JNGFF1.42
WIGIG_32KHZ_R: length 2.2
  TOP w0.102: v1(252.82,26.69) 252.69,26.57 RZ57.1 UZ11.4
WIGIG_AUX: length 56.2
  TOP w0.102: v2(233.22,48.12) 233.45,47.89 233.45,47.82 231.93,46.3 231.93,44.42 232.61,43.74 232.61,43.11 232.33,42.83 232.33,34.95 232.61,34.67 232.61,33.84 232.52,33.75 232.52,33.2 CV149.1 ; UV600.26 221.63,70.89 221.53,70.79 220.63,70.79 RV609.2 220.05,71.37 219.47,71.37 v2(219.06,70.97)
  IN1 w0.089: v2(219.06,70.97) 219.14,70.89 219.14,70.46 219.38,70.21 222.93,70.21 223.66,69.48 226.99,69.48 229.45,67.01 232.3,67.01 235.25,64.06 235.25,52.09 233.46,50.3 233.46,48.35 v2(233.22,48.12)
WIGIG_AUX#: length 55.9
  TOP w0.102: v2(233.81,48.12) 233.66,47.97 233.66,47.73 232.14,46.21 232.14,44.51 232.82,43.83 232.82,43.03 232.53,42.75 232.53,35.04 232.82,34.76 232.82,33.76 232.72,33.66 232.72,33.07 232.85,32.95 CV150.1 ; UV600.27 221.66,70.49 221.57,70.59 220.61,70.59 RV605.2 220.29,70.32 v2(219.64,70.97)
  IN1 w0.089: v2(233.81,48.12) 233.63,48.3 233.63,50.23 235.42,52.02 235.42,64.13 232.37,67.18 229.52,67.18 227.06,69.65 223.73,69.65 223,70.38 219.45,70.38 219.31,70.53 219.31,70.65 219.63,70.97 v2(219.64,70.97)
WIGIG_AUX#_C: length 11
  TOP w0.102: v2(232.99,31.09) 232.72,31.35 232.72,31.97 232.79,32.04 CV150.2
  BOTTOM w0.102: JNGFF1.12 240.22,29.1 239.93,28.81 239.36,28.81 237.58,30.59 232.88,30.59 232.74,30.73 232.74,30.84 v2(232.99,31.09)
WIGIG_AUX_C: length 10.8
  TOP w0.102: CV149.2 232.52,31.79 232.52,31.2 v2(232.41,31.09)
  BOTTOM w0.102: v2(232.41,31.09) 232.53,30.96 232.53,30.64 232.8,30.38 237.5,30.38 239.28,28.6 JNGFF1.14
WIGIG_HPD: length 58.4
  TOP w0.102: UV600.48 229.63,67.84 v2(229.74,67.73)
  IN2 w0.122: v2(229.74,67.73) 233.93,67.73 236.09,65.57 236.09,47.36 233.93,45.2 233.93,40.27 231.9,38.24 230.79,38.24 v2(230.68,38.12)
  BOTTOM w0.102: JNGFF1.23 232.51,26.35 232.34,26.52 232.34,29.69 231.84,30.2 231.84,31.51 232.18,31.85 234.62,31.85 235.91,33.15 235.91,35.8 235.16,36.55 232.26,36.55 v1(231.55,37.25) v2(230.68,38.12)
WIGIG_LANE_N0: length 49.3
  TOP w0.102: CV156.1 238.57,28.33 238.57,30.18 237.89,30.86 237.89,32.63 236.92,33.6 236.92,39.33 236.6,39.65 236.6,42.16 236.33,42.43 236.33,45.04 237.1,46.06 237.1,46.27 238.44,47.61 v4(238.44,48.39) 238.44,52.53 238.74,52.83 238.74,54.07 236.98,55.83 236.98,65.78 236.96,65.8 236.96,66.25 235.54,67.67 230.36,67.67 230.12,67.9 230.12,68.04 230.03,68.14 UV600.49
WIGIG_LANE_N0_C: length 7
  TOP w0.102: v2(238.44,25.41) v4(238.44,26.12) 238.44,26.88 CV156.2
  BOTTOM w0.102: v2(238.44,25.41) 238.63,25.6 238.63,25.74 238.44,25.93 238.12,25.93 237.84,26.21 237.84,26.61 238.12,26.89 238.95,26.89 239.73,26.1 JNGFF1.24
WIGIG_LANE_N1: length 50.3
  TOP w0.102: CV152.1 236.96,30.03 236.96,32.41 236.11,33.26 236.11,38.99 235.78,39.31 235.78,41.82 235.5,42.1 235.5,45.32 236.19,46.26 236.19,46.37 236.17,46.39 236.17,46.96 236.19,46.99 236.19,47.18 236.38,47.37 236.86,47.37 237,47.52 237,47.72 236.86,47.86 236.47,47.86 236.24,48.09 236.24,48.67 236.47,48.89 237.36,48.89 237.46,48.99 237.46,49.4 237.36,49.5 236.63,49.5 236.35,49.78 236.35,50.17 236.63,50.45 237.36,50.45 237.46,50.55 v4(237.46,51.14) 237.46,51.84 236.15,53.15 236.15,65.25 234.56,66.85 229.53,66.85 228.92,67.45 228.92,68.05 228.83,68.15 UV600.46
WIGIG_LANE_N1_C: length 7.2
  TOP w0.102: CV152.2 237.37,28.2 237.37,27.83 237.02,27.47 236.81,27.47 v2(236.62,27.66)
  BOTTOM w0.102: v2(236.62,27.66) 236.84,27.44 237.39,27.44 237.47,27.52 237.47,27.66 237.79,27.98 238.72,27.98 238.97,27.73 239.51,27.73 239.8,27.44 240.02,27.44 240.18,27.6 JNGFF1.18
WIGIG_LANE_N2: length 49.9
  TOP w0.102: CV147.1 235.38,32.17 235.38,32.83 235.21,33 235.21,36.69 235.14,36.76 v4(234.81,36.76) 234.49,36.76 234.24,37.01 234.24,37.63 234.49,37.88 235.16,37.88 235.29,38.01 235.29,38.41 235.18,38.52 234.81,38.52 234.51,38.82 234.51,39.49 234.68,39.66 234.68,45.91 235.3,46.54 235.3,49.92 235.12,50.11 234.98,50.11 234.65,50.43 234.65,51.03 234.98,51.35 236.15,51.35 236.33,51.53 236.33,51.78 236.15,51.96 234.5,51.96 234.27,52.19 234.27,52.77 234.5,52.99 235.2,52.99 235.3,53.09 235.3,56.01 235.28,56.03 235.28,56.62 235.3,56.64 235.3,64.95 234.22,66.03 228.71,66.03 228.46,66.28 228.46,66.75 228.22,66.99 228.22,67.99 228.03,68.17 UV600.44
WIGIG_LANE_N2_C: length 6.9
  TOP w0.102: CV147.2 235.53,31.08 235.63,30.97 235.63,30.54 235.84,30.33 235.94,30.33 235.98,30.29 235.98,29.33 235.82,29.17 v4(235.82,28.8) 235.82,28.47 236.02,28.27 236.02,27.87 235.84,27.69 235.6,27.69 235.56,27.65 235.41,27.65 v2(235.17,27.89)
  BOTTOM w0.102: JNGFF1.17 234.08,27.85 234.22,27.7 234.98,27.7 v2(235.17,27.89)
WIGIG_LANE_N3: length 48.6
  TOP w0.102: CV145.1 234.04,35.17 234.04,35.93 233.42,36.55 233.42,44.63 233.86,45.06 233.86,45.36 233.76,45.47 233.73,45.47 233.43,45.77 233.43,46.19 233.73,46.49 233.76,46.49 234.45,47.19 234.45,48.51 234.25,48.72 232.89,48.72 232.69,48.91 232.69,49.52 232.9,49.73 233.79,49.73 233.88,49.81 233.88,50.11 233.43,50.56 233.43,53.72 233.63,53.92 234.26,53.92 234.45,54.12 v4(234.45,54.36) 234.45,55.89 234.25,56.1 233.17,56.1 232.86,56.4 232.86,56.84 233.17,57.15 234.25,57.15 234.45,57.35 234.45,57.63 234.43,57.65 234.43,58.2 234.45,58.22 234.45,61.88 234.34,62 234.17,62 233.94,62.22 233.94,62.7 234.17,62.93 234.35,62.93 234.45,63.03 234.45,64.56 233.8,65.21 230.36,65.21 230.26,65.11 230.26,65.04 230.03,64.82 229.45,64.82 229.23,65.04 229.23,65.11 229.13,65.21 228.22,65.21 227.64,65.78 227.64,66.41 226.83,67.22 UV600.41
WIGIG_LANE_N3_C: length 7.3
  TOP w0.102: v2(234.6,29.41) 234.79,29.22 234.92,29.22 235.01,29.31 235.01,29.78 234.15,30.64 234.15,32.38 234.13,32.4 234.13,33 234.15,33.02 234.15,33.39 234.1,33.45 234.1,33.77 233.98,33.88 CV145.2
  BOTTOM w0.102: v2(234.6,29.41) 234.4,29.2 234.22,29.2 234.08,29.35 JNGFF1.11
WIGIG_LANE_P0: length 49.3
  TOP w0.102: CV157.1 238.78,28.35 238.78,30.27 238.1,30.94 238.1,32.72 237.13,33.69 237.13,39.41 236.81,39.74 236.81,42.25 236.53,42.52 236.53,44.97 237.27,45.93 237.31,45.97 237.31,46.19 238.65,47.53 238.65,48.09 238.67,48.11 238.67,48.67 238.65,48.69 238.65,52.44 238.95,52.74 238.95,54.15 237.19,55.91 v4(237.19,66.08) 237.19,66.31 235.63,67.87 230.45,67.87 230.33,67.99 230.33,68.1 230.43,68.2 UV600.50
WIGIG_LANE_P0_C: length 7.1
  TOP w0.102: CV157.2 238.65,26.61 238.65,26.44 238.67,26.42 238.67,25.83 238.65,25.81 238.65,25.78 238.85,25.58 238.85,25.58 239.01,25.41 v2(239.02,25.41)
  BOTTOM w0.102: JNGFF1.26 239.97,25.6 239.68,25.89 239.65,25.89 238.86,26.68 238.2,26.68 238.05,26.52 238.05,26.3 238.2,26.14 238.53,26.14 238.84,25.83 238.84,25.6 v2(239.02,25.41)
WIGIG_LANE_P1: length 50.3
  TOP w0.102: CV153.1 237.17,30.21 237.17,32.49 236.31,33.35 236.31,39.07 235.99,39.4 235.99,41.91 235.71,42.19 235.71,45.25 236.4,46.19 v4(236.4,46.68) 236.4,47.09 236.47,47.16 236.95,47.16 237.21,47.43 237.21,47.81 236.95,48.07 236.55,48.07 236.45,48.17 236.45,48.58 236.55,48.68 237.44,48.68 237.67,48.9 237.67,49.48 237.44,49.71 236.72,49.71 236.56,49.86 236.56,50.08 236.72,50.24 237.44,50.24 237.67,50.46 237.67,50.84 237.69,50.87 237.69,51.42 237.67,51.44 237.67,51.93 236.36,53.23 236.36,65.34 234.65,67.06 229.62,67.06 229.13,67.54 229.13,68.05 229.23,68.15 UV600.47
WIGIG_LANE_P1_C: length 7.3
  TOP w0.102: CV153.2 237.58,28.84 237.58,27.74 237.1,27.26 236.81,27.26 v2(236.62,27.07)
  BOTTOM w0.102: v2(236.62,27.07) 236.78,27.23 237.47,27.23 237.68,27.44 237.68,27.57 237.88,27.77 238.63,27.77 238.88,27.52 239.42,27.52 239.72,27.23 240.04,27.23 240.17,27.1 JNGFF1.20
WIGIG_LANE_P2: length 49.9
  TOP w0.102: UV600.45 228.43,68.17 228.42,68.17 228.42,67.08 228.67,66.83 228.67,66.36 228.8,66.24 234.31,66.24 235.51,65.03 v4(235.51,56.32) 235.51,53 235.29,52.78 234.58,52.78 234.48,52.68 234.48,52.27 234.58,52.17 236.24,52.17 236.54,51.87 236.54,51.45 236.24,51.14 235.06,51.14 234.86,50.94 234.86,50.52 235.06,50.32 235.2,50.32 235.51,50.01 235.51,46.45 234.88,45.83 234.88,39.57 234.72,39.41 234.72,38.9 234.9,38.72 235.26,38.72 235.5,38.49 235.5,37.92 235.25,37.68 234.58,37.68 234.45,37.55 234.45,37.1 234.56,36.99 235.2,36.99 235.42,36.78 235.42,33.09 235.59,32.92 235.59,32.49 CV148.1
WIGIG_LANE_P2_C: length 7
  TOP w0.102: v2(235.17,27.31) 235.31,27.44 235.65,27.44 235.69,27.48 235.93,27.48 236.23,27.79 236.23,28.36 236.05,28.54 236.05,29.1 236.19,29.23 236.19,30.38 236.03,30.54 235.93,30.54 235.84,30.63 235.84,30.84 236.08,31.08 CV148.2
  BOTTOM w0.102: v2(235.17,27.31) 234.98,27.5 234.22,27.5 234.08,27.35 JNGFF1.19
WIGIG_LANE_P3: length 48.8
  TOP w0.102: CV146.1 234.37,34.79 234.25,34.91 234.25,36.02 233.63,36.64 233.63,44.54 234.07,44.98 234.07,45.45 233.84,45.67 233.82,45.67 233.64,45.85 233.64,46.11 233.82,46.28 233.84,46.28 234.66,47.1 234.66,48.6 234.34,48.92 232.97,48.92 232.9,49 232.9,49.44 232.98,49.52 233.88,49.52 234.09,49.73 234.09,50.2 233.64,50.65 233.64,53.63 233.72,53.72 234.35,53.72 234.66,54.03 234.66,54.06 234.68,54.08 234.68,54.63 234.66,54.66 234.66,55.98 234.34,56.3 233.25,56.3 233.07,56.49 233.07,56.75 233.25,56.94 234.34,56.94 234.66,57.27 v4(234.66,57.92) 234.66,61.97 234.42,62.21 234.25,62.21 234.15,62.31 234.15,62.62 234.25,62.72 234.44,62.72 234.66,62.94 234.66,64.65 233.89,65.42 230.27,65.42 230.05,65.2 230.05,65.13 229.95,65.03 229.54,65.03 229.44,65.13 229.44,65.2 229.22,65.42 228.3,65.42 227.85,65.87 227.85,66.49 227.04,67.31 227.04,67.75 227.23,67.94 UV600.42
WIGIG_LANE_P3_C: length 7.3
  TOP w0.102: v2(234.6,28.82) 234.79,29.01 235,29.01 235.21,29.22 235.21,29.87 234.36,30.72 v4(234.36,32.7) 234.36,33.69 CV146.2
  BOTTOM w0.102: v2(234.6,28.82) 234.42,29 234.22,29 234.08,28.85 JNGFF1.13
WIGIGCLK_REQ#: length 160.1
  TOP w0.081: 173.42,65.47 170.63,65.47 170.36,65.2 168.77,65.2 v2(168.35,64.78)
  TOP w0.102: RPC9.6 179.68,65.57 179.36,65.25 173.63,65.25 173.42,65.47
  IN3 w0.081: 173.36,59.61 171.38,59.61 170.74,60.26 170.74,61.76 170.5,61.99 170.5,62.97 169.9,63.57 169.57,63.57 v2(168.35,64.78)
  IN3 w0.122: 173.36,59.61 174.61,59.61 177.61,56.61 179.07,56.61 182.18,53.5 182.18,44.9 184.52,42.57 184.52,40.88 196.15,29.25 204.38,29.25 207.53,26.1 229.8,26.1 230.64,26.94 233.86,26.94 234.73,26.07 236.32,26.07 236.64,25.76 237.93,25.76 238.19,26.01 240.15,26.01 241.39,27.24 241.39,30.39 242.42,31.42 244.61,31.42 245.3,32.11 245.3,32.74 247.86,35.31 v2(250.15,35.31)
  BOTTOM w0.081: v2(168.35,64.78) 168.15,64.58 UC1.U5
  BOTTOM w0.102: v2(250.15,35.31) 250.16,35.31 v1(255.97,29.5) 255.97,23.22 247.14,14.39 243.33,14.39 242.25,15.47 242.25,16.51 241.66,17.1 JNGFF1.60
WIRELESS_LED#: length 98.7
  TOP w0.102: QZ7.1 288.03,81.12 287.91,81 287.91,80.16 RZ31.2 287.79,79.35 285.91,77.47 285.33,77.47 284.41,76.56 282.7,76.56 279.33,73.19 279.33,72.26 v2(277.48,70.4) ; QZ2.3 244.23,35.8 v2(244.28,35.85) ; UE1.A47 258.12,59.6 v2(258.45,59.28) ; QZ11.6 242.95,68.8 244,67.75 244,61.76 246.73,59.03 v1(246.73,56.46) v2(246.73,55.03) 246.73,52.13 245.37,50.78 245.37,46.37 245.67,46.08 245.67,39.77 244.41,38.52 v2(244.41,38.26) 242.61,38.26 242.35,38 QZ2.6
  IN3 w0.122: v2(258.45,59.28) 258.45,58.89 258.91,58.43 267.56,58.43 269.87,60.74 269.87,65.65 274.62,70.4 v2(277.48,70.4)
  IN4 w0.089: v2(246.73,55.03) 246.73,56.15 248.1,57.53 255.88,57.53 257.63,59.28 v2(258.45,59.28)
  BOTTOM w0.102: v2(244.41,38.26) 244.41,35.98 v2(244.28,35.85)
WLAN_DISBL#: length 15.2
  TOP w0.102: UE1.B68 259.83,69.51 v1(262.99,72.68) 263.56,73.25 263.56,82.23 263.34,82.45 UL2.4
WLAN_LED: length 90.1
  TOP w0.102: v2(269.87,58.84) 269.87,54.88 272.72,52.04 272.72,48.71 272.53,48.51 272.53,45.27 274.71,43.08 274.71,40.69 274.3,40.28 274.3,35.29 272.53,33.51 272.53,28.8 271.85,28.13 271.85,27.48 272.39,26.95 273.33,26.95 274.2,26.09 274.86,26.09 275.77,25.18 275.77,21.39 275.09,20.71 274.57,20.71 274.22,20.36 274.22,18.58 273.68,18.05 273.68,16.9 v1(271.09,14.31) 270.85,14.07 270.32,14.07 268.65,12.4 JLED1.6 ; v2(283.97,80.37) 284.14,80.54 QZ9.3
  IN1 w0.089: v2(269.87,58.84) 269.36,59.35 269.36,65.51 272.71,68.85 280.4,68.85 282.24,70.7 282.24,78.29 283.97,80.02 v2(283.97,80.37)
WLAN_LED#: length 9
  TOP w0.102: QZ2.1 241.98,35.8 241.59,35.4 RZ14.1 v2(240.92,34.72)
  BOTTOM w0.102: v2(240.92,34.72) 242.89,34.72 v1(243.29,34.31) 243.29,32.79 242.91,32.41 241.82,32.41 241.63,32.6 JNGFF1.6
WLAN_LED_Q#: length 4.3
  TOP w0.102: v1(286.59,78.8) 285.25,80.14 285.25,80.52 285.45,80.71 QZ9.2 286.12,81.23 286.22,81.12 QZ7.6
WLAN_WIGIG60GHZ_DIS#: length 66.1
  TOP w0.102: UE1.A1 v2(258.62,71.86) 258.94,72.18 RE8.2 ; DZ1.1 241.33,27.85 v1(240.36,28.82) 239.61,29.57 239.61,30.62 238.95,31.28 238.95,33.68 239.61,34.34 239.61,34.99 241.23,36.61 241.23,37.69 242.31,38.77 243.9,38.77 245.21,40.08 245.21,45.89 244.94,46.15 244.92,46.18 244.92,50.97 246.06,52.12 246.06,59.05 243.54,61.57 243.54,66.96 v2(243.06,67.44)
  IN4 w0.089: v2(243.06,67.44) 244.01,68.39 244.01,69.77 245.11,70.87 257.63,70.87 v2(258.62,71.86)
WLAN_WIGIG60GHZ_DIS#_R: length 12.2
  TOP w0.102: v1(243.19,26.62) 243.84,27.26 v2(243.84,27.62) 242.99,27.62 DZ1.2
  BOTTOM w0.102: v2(243.84,27.62) 244.02,27.44 244.02,21.74 242.37,20.1 JNGFF1.48
WLANCLK_REQ#: length 103.2
  TOP w0.102: v2(229.87,20.99) 229.49,20.99 v1(227.54,22.94) 225.94,24.54 225.94,35.37 v2(225.79,35.52)
  IN3 w0.081: 173.36,67.02 v2(173.32,67.06)
  IN3 w0.122: 173.36,67.02 173.75,66.62 180.65,66.62 181.44,67.42 184.33,67.42 185.2,66.55 186.98,66.55 190.77,62.76 190.77,59.72 195.15,55.33 195.15,47.58 195.36,47.38 195.36,42.06 199.22,38.2 213.32,38.2 216.66,34.87 224.04,34.87 224.7,35.52 v2(225.79,35.52)
  BOTTOM w0.076: v2(173.32,67.06) 172.95,67.42 172.12,67.42 172.06,67.37 172.05,67.37 171.84,67.15 171.84,66.87 171.25,66.29 UC1.N1
  BOTTOM w0.081: 173.36,67.02 v2(173.32,67.06)
  BOTTOM w0.102: JNGFF1.45 232.15,20.85 232.01,20.99 v2(229.87,20.99) ; 173.36,67.02 173.38,66.99 175.94,66.99 176.63,67.68 RPC17.6
WWAN_LED#: length 5.8
  TOP w0.102: v2(241.03,70.4) 242.68,70.4 242.95,70.67 QZ11.1 242.96,71.05 RZ37.1
  BOTTOM w0.102: JNGFF2.10 240.83,70.6 v2(241.03,70.4) 241.03,70.38 241.48,69.94 v1(241.48,69.43)
WWAN_PWR_EN: length 6.6
  TOP w0.102: RZ43.2 243.84,71.11 242.66,69.93 v2(241.91,69.93)
  BOTTOM w0.102: v2(241.91,69.93) 241.91,70.83 v1(241.78,70.95) 241.13,71.6 JNGFF2.6
WWAN_RADIO_DIS#: length 33.9
  TOP w0.102: RE10.2 262.44,63.67 v2(261.16,63.67) 261.07,63.76 UE1.A53 ; v2(241.04,69.76) 240.86,69.57 DZ5.1 240.22,68.86 v1(240.04,68.68)
  IN4 w0.089: v2(241.04,69.76) 241.68,69.12 241.68,64.36 240.9,63.59 240.9,61.89 241.28,61.52 248.64,61.52 250.11,62.99 252.59,62.99 252.87,63.27 256.95,63.27 257.47,63.79 261.04,63.79 v2(261.16,63.67)
WWAN_RADIO_DIS#_R: length 3.1
  TOP w0.102: v1(240.29,72.01) 240.22,71.93 DZ5.2 240.65,70.97 240.73,71.05 v2(241.03,71.05)
  BOTTOM w0.102: v2(241.03,71.05) 240.98,71.1 JNGFF2.8
WWAN_WAKE#: length 33.2
  TOP w0.102: v2(249.84,58.83) 249.74,58.72 v1(249.74,57.96) RE276.2 ; v2(254.37,62.43) 254.87,61.93 UE1.B43
  IN3 w0.122: v2(235.1,67.26) 241.2,67.26 242.19,66.27 242.19,65.13 248.49,58.83 v2(249.84,58.83)
  IN4 w0.089: v2(254.37,62.43) 254.59,62.43 254.9,62.13 254.9,61.01 254.06,60.17 251.19,60.17 v2(249.84,58.83)
  BOTTOM w0.102: v2(235.1,67.26) 235.01,67.35 JNGFF2.15
XDP_DBRESET#: length 156.2
  TOP w0.102: UC4.1 185.23,73.53 185.34,73.64 186.04,73.64 186.36,73.32 RC77.1 187.17,71.95 v2(187.17,69.38) ; JXDP1.48 85.46,49.2 85.84,49.58 CC21.1 RC122.2 86.2,48.45 86.85,47.8 88.05,47.8 88.58,47.27 88.58,46.47 89.53,45.52 v1(89.53,38.23) v2(89.53,36.37)
  BOTTOM w0.102: v2(89.53,36.37) 173.43,36.37 176.4,39.34 187.96,39.34 189.67,41.05 189.67,48.42 186.37,51.72 186.37,62.27 187.17,63.07 v2(187.17,69.38)
XDP_OBS0_R: length 76.6
  TOP w0.102: v2(80.71,54.98) 80.69,54.98 79.97,55.7 JXDP1.21
  IN4 w0.089: v2(80.71,54.98) 80.72,54.98 80.99,55.25 83.85,55.25 84.47,54.63 90.17,54.63 91.4,55.85 92.34,55.85 94.33,57.85 94.33,61.07 96.33,63.07 96.33,71.08 100.44,75.18 116.84,75.18 120.73,71.29 125.49,71.29 126.2,70.59 128.87,70.59 v2(130.37,69.09)
  BOTTOM w0.076: v2(130.37,69.09) 130.37,68.75 130.82,68.3 130.95,68.3 131.09,68.16 131.92,68.16 131.97,68.12 132.4,68.12 132.58,68.29 133.29,68.29 133.33,68.24 133.81,68.24 UC1.J60
  BOTTOM w0.102: v2(80.71,54.98) 80.71,55.63 v1(81.32,56.24)
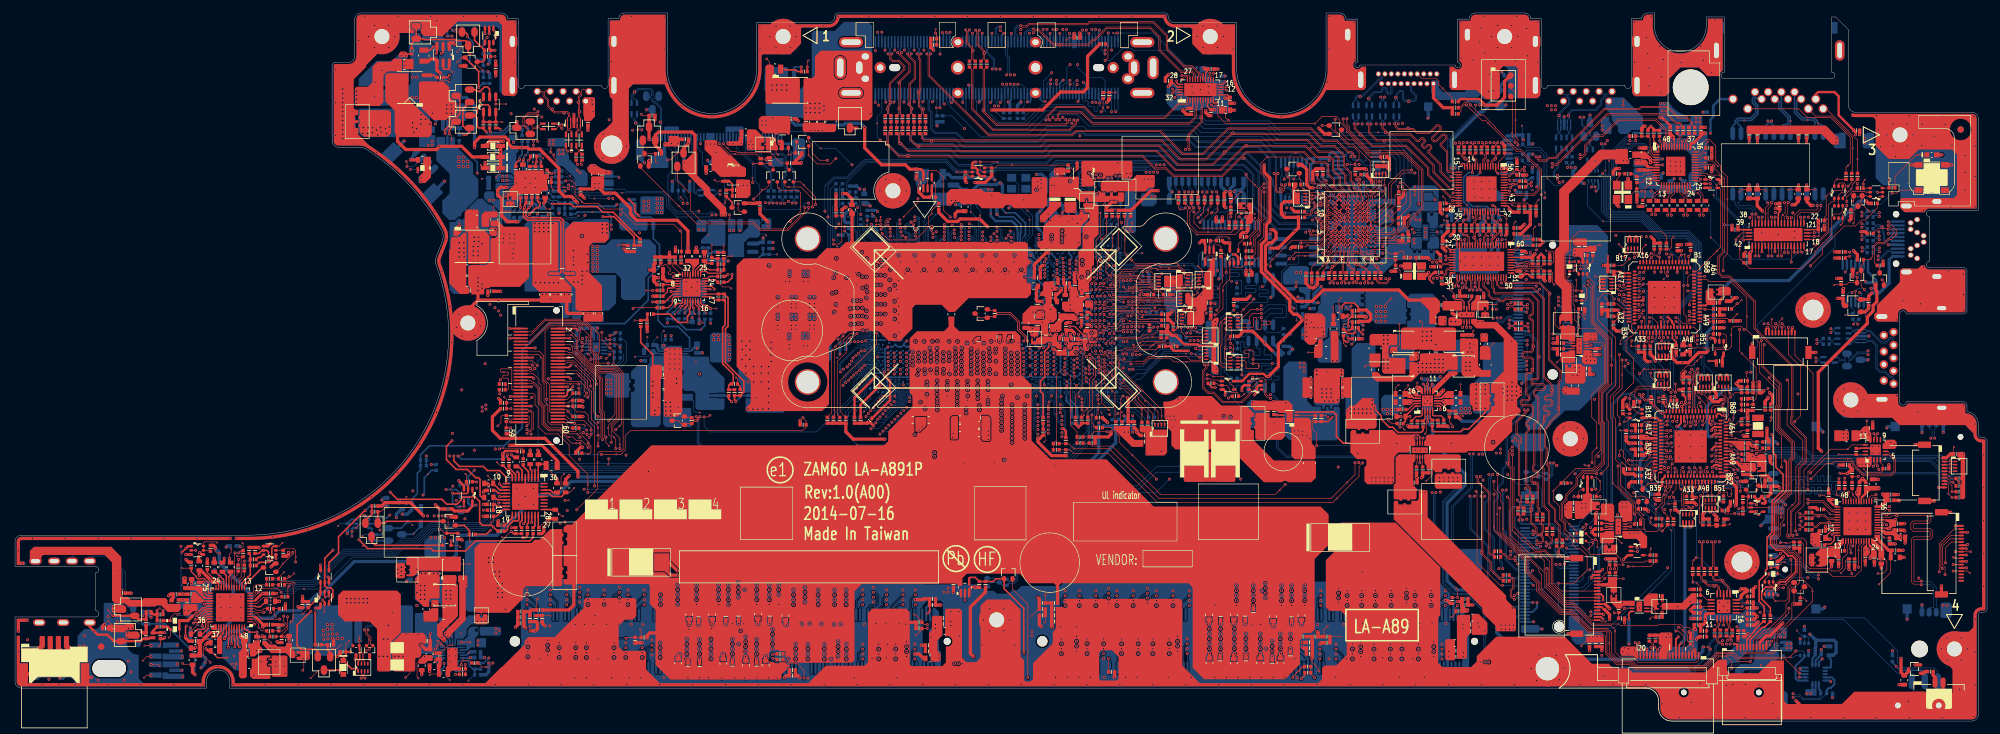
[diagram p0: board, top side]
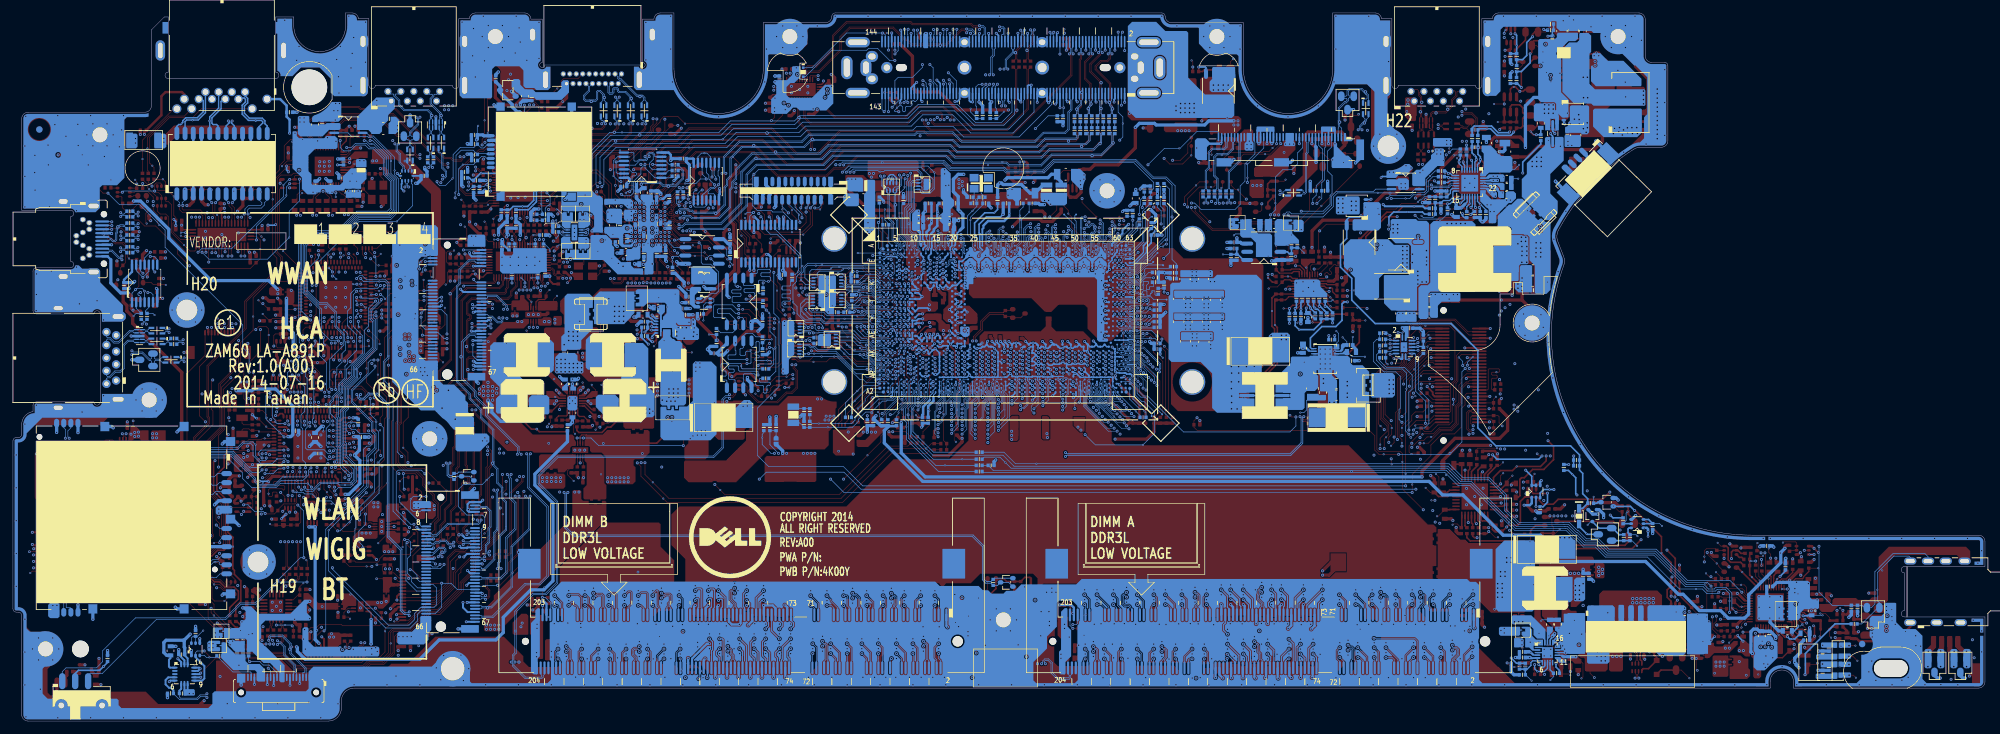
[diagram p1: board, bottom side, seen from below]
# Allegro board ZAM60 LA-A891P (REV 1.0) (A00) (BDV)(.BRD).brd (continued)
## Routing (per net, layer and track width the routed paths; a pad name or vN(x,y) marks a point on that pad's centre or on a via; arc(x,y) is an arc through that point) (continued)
XDP_OBS1_R: length 76
  TOP w0.102: JXDP1.23 79.82,55.2 v2(79.99,55.02)
  IN4 w0.089: v2(79.99,55.02) 80.62,55.65 84.01,55.65 84.23,55.43 88.38,55.43 88.69,55.12 90.35,55.12 91.31,56.08 92.26,56.08 94.12,57.94 94.12,61.16 96.12,63.16 96.12,71.17 100.35,75.4 116.93,75.4 120.82,71.51 125.59,71.51 126.29,70.81 131.94,70.81 v2(133.81,68.95)
  BOTTOM w0.081: v2(133.81,68.95) 134.11,69.25 UC1.H60
  BOTTOM w0.102: v1(79.16,56.31) 79.99,55.47 v2(79.99,55.02)
XDP_OBS2_R: length 6.2
  BOTTOM w0.076: UC1.H61 133.2,69.62 132.69,69.62 132.48,69.4 132.48,69.24 132.28,69.04 132.04,69.04 131.81,69.27 131.09,69.27 129.59,70.78
  BOTTOM w0.102: T10.1 128.75,70.78 129.59,70.78
XDP_OBS3_R: length 6.7
  BOTTOM w0.076: 129.42,70.51 129.42,70.5 129.54,70.38 129.66,70.38 130.95,69.09 131.75,69.09 131.96,68.87 132.35,68.87 UC1.H62
  BOTTOM w0.102: 129.42,70.51 129.39,70.54 127.06,70.54 T11.1
XDP_OBS4_R: length 11.8
  TOP w0.081: 134.05,76.26 v2(133.86,76.07)
  TOP w0.102: T12.1 134.74,77.65 134.45,77.36 134.45,76.67 134.05,76.26
  IN3 w0.122: v2(135.17,68.22) 135.17,69.01 134.86,69.32 134.86,70.15 135.11,70.4 135.11,72.44 134.43,73.12 134.43,75.79 134.15,76.07 v2(133.86,76.07)
  BOTTOM w0.081: v2(135.17,68.22) 134.81,67.86 UC1.K59
XDP_OBS5_R: length 5.6
  BOTTOM w0.076: 129.54,71.16 131.24,69.46 132.02,69.46 UC1.H63
  BOTTOM w0.102: T13.1 128.84,71.42 128.84,71.35 129.03,71.16 129.54,71.16
XDP_OBS6_R: length 12.2
  TOP w0.102: T14.1 133.77,77.86 133.73,77.83 v2(133.73,77.38)
  IN3 w0.122: v2(133.8,67.44) 133.8,67.69 132.46,69.03 132.46,72.43 133.16,73.13 133.16,76.81 v2(133.73,77.38)
  BOTTOM w0.081: v2(133.8,67.44) 134.11,67.74 UC1.K60
XDP_OBS7_R: length 9.7
  TOP w0.102: v2(133.79,76.77) T15.1
  IN3 w0.122: v2(133.16,68.95) 133.16,69.6 132.72,70.04 132.72,72.24 133.41,72.94 133.41,76.39 v2(133.79,76.77)
  BOTTOM w0.081: UC1.J61 133.46,68.65 v2(133.16,68.95)
XDP_RST#_R: length 2.8
  TOP w0.102: RC106.2 86.22,50.63 85.28,49.7 JXDP1.46
XTAL24_IN: length 12.4
  BOTTOM w0.102: UC1.A25 156.07,74.58 156.78,75.29 v1(156.78,77.51) 156.78,77.9 154.87,79.81 CC8.2 154.87,80.66 RC63.2 155.13,81.61 155.13,82.9 YC2.3
XTAL24_OUT: length 9.4
  BOTTOM w0.102: RC63.1 155.8,80.65 RC65.1 155.8,79.57 v1(156.46,78.9) 157.26,78.1 157.26,75.21 156.5,74.45 156.5,73.43 156.07,73 UC1.B25
XTAL24_OUT_R: length 2.5
  BOTTOM w0.102: RC65.2 156.37,80.4 CC11.2 156.21,81.16 YC2.1
XTALI: length 6.6
  TOP w0.102: UL1.10 253.01,84.39 252.85,84.24 252.41,84.24 v1(251.64,83.47) 251.44,83.27 RL11.2 CL14.2 249.31,80.96 YL1.1
XTALO: length 4.4
  TOP w0.102: UL1.9 252.83,84.79 252.66,84.62 v1(252.33,84.62) 251.9,84.62 251.47,84.19 RL11.1 250.43,84.19 250,84.62 RL10.2
XTALO_R: length 2.8
  TOP w0.102: YL1.3 247.51,83.78 247.91,84.19 CL13.2 RL10.1
Z2805: length 2.2
  TOP w0.381: RL18.1 v2(276.88,89.43)
  BOTTOM w0.381: TL1.22 v2(276.88,89.43)
Z2806: length 2.2
  TOP w0.381: RL16.1 v2(269.26,89.45)
  BOTTOM w0.381: TL1.16 v2(269.26,89.45)
Z2807: length 2.2
  TOP w0.381: RL17.1 v2(275.61,89.45)
  BOTTOM w0.381: TL1.21 v2(275.61,89.45)
Z2808: length 2.2
  TOP w0.381: RL15.1 v2(267.99,89.45)
  BOTTOM w0.381: TL1.15 v2(267.99,89.45)
N15115: length 5.6
  TOP w0.102: T16.1 173.38,60.59 171.16,60.59 170.88,60.31 169.54,60.31 v2(169.15,59.92)
  BOTTOM w0.081: UC1.AD4 168.83,60.23 v2(169.15,59.92)
N19253: length 6.9
  BOTTOM w0.102: T28.1 128.78,47.63 129.89,48.74 130.55,48.74 131.63,49.82 131.63,51.73 132.08,52.17 UC1.AV63
N19255: length 7.9
  BOTTOM w0.076: 131.02,51.76 132.09,52.83 UC1.AU63
  BOTTOM w0.102: T29.1 129.79,50.08 130.43,50.08 131.02,50.67 131.02,51.76
N19263: length 7.5
  BOTTOM w0.102: UC1.C63 131.86,72.19 129.98,74.07 129.98,75.6 129.47,76.11 129.47,77.39 128.88,77.99 T30.1
N19267: length 8.2
  BOTTOM w0.081: UC1.C62 132.41,72.52 131.91,72.52 131.63,72.8
  BOTTOM w0.102: 131.63,72.8 130.17,74.26 130.17,75.73 129.73,76.17 129.73,78.7 T31.1
N19275: length 5.2
  BOTTOM w0.081: UC1.A51 140.14,73.75 140.14,73.93 140.45,74.23 140.45,76.26
  BOTTOM w0.102: T33.1 140.65,78.14 140.65,77.51 140.45,77.3 140.45,76.26
N19277: length 6.5
  BOTTOM w0.081: 140.67,76.26 140.67,74.19 140.32,73.83 140.32,73.28 UC1.B51
  BOTTOM w0.102: T34.1 140.67,76.71 140.67,76.26
N19281: length 4.7
  BOTTOM w0.081: UC1.L60 133.79,66.72 133.31,66.72 133.2,66.61 132.69,66.61 132.52,66.44 132.52,66.27 132.29,66.03 131.93,66.03 131.88,65.99 131.43,65.99 131.29,66.13 130.96,66.13 130.77,65.95 T35.1
N21871: length 6.3
  BOTTOM w0.076: UC1.P60 134.11,65.52 133.8,65.22 133.37,65.22 133.26,65.11 132.02,65.11 131.8,64.88 131.33,64.88 130.92,65.3
  BOTTOM w0.102: 130.92,65.3 130.81,65.4 129.37,65.4 129.17,65.2 129.17,64.78 T74.1
N21873: length 7.6
  BOTTOM w0.076: UC1.P61 133.19,65.27 131.91,65.27 131.72,65.08 131.39,65.08 130.87,65.61
  BOTTOM w0.102: 130.87,65.61 128.89,65.61 128.47,65.19 126.49,65.19 T75.1
N21875: length 20.4
  TOP w0.102: v2(139.53,80.8) 139.53,80.18 137.37,78.02 T76.1
  IN3 w0.122: v2(139.53,80.8) 139.13,80.8 135.69,77.36 135.69,67.87 135.19,67.37 v2(135.19,66.74)
  BOTTOM w0.081: UC1.N59 134.82,66.36 v2(135.19,66.74)
N21877: length 14.3
  TOP w0.102: T77.1 133.09,77.8 v2(133.09,77.38)
  IN3 w0.122: v2(133.09,77.38) 132.9,77.19 132.9,73.32 132.21,72.62 132.21,67.69 133.79,66.11 v2(133.79,65.95)
  BOTTOM w0.081: UC1.N61 133.79,66.03 v2(133.79,65.95)
N33048: length 2.6
  TOP w0.102: v1(204.83,13.06) CD36.2
  TOP w0.508: CD36.2 RD21.1
N33050: length 2.1
  TOP w0.102: v1(159.09,15.24) 159.2,15.35 RD25.1
  TOP w0.508: RD25.1 CD54.2
N40459: length 3.3
  TOP w0.102: v1(109.66,80.09) 109.74,80.16 109.74,80.44 109.92,80.62 109.92,81.13
  TOP w0.254: QV2.1 110.81,80.24 109.92,81.13 RV5.2
N43975: length 4.2
  BOTTOM w0.102: v1(275.35,13.99) 276.23,13.11 RN2.2 ; RN2.2 276.92,13.11 277.18,12.86 QN1.6 ; RN2.2 QN1.5
N70745: length 8.6
  TOP w0.102: v2(262.88,42.97) 262.88,42.96 UE2.B61 ; RE64.1 269.71,41.82 v2(268.39,41.82)
  IN4 w0.089: v2(262.88,42.97) 263.03,42.97 263.18,43.12 266.87,43.12 268.17,41.82 v2(268.39,41.82)
N70747: length 2.5
  TOP w0.102: RE66.2 CE34.1 249.38,38.97 v1(248.37,39.98)
N70757: length 5.9
  TOP w0.102: RE57.1 269.17,43.16 RE58.1 268.64,43.17 268.28,43.53 266.39,43.53 266.2,43.71 v1(265.85,43.71) UE2.A59
N73962: length 1.6
  TOP w0.102: CZ45.1 217.53,40.11 217.49,40.16 UZ9.12
N73964: length 1.6
  TOP w0.102: UZ9.10 216.69,40.11 216.58,40 CZ46.1
N75571: length 5.4
  TOP w0.102: RZ24.2 273.14,24.56 v1(273.48,24.56) ; RZ24.2 272.41,23.71 DZ3.2 271.93,22.77 271.7,22.54 QZ3.1 ; RZ24.2 271.89,23.77 271.84,23.72 DZ4.2
N75595: length 1.5
  TOP w0.102: QZ3.3 270.4,21.87 271.01,22.48 DZ3.1
N525777: length 2.1
  TOP w0.203: CZ42.1 225.12,65.32 v1(224.63,64.83) 224.63,64.53 224.73,64.43 UZ8.10
N588510: length 4.2
  TOP w0.102: v1(221.83,66.66) 222.36,66.13 CZ41.1
  TOP w0.203: UZ8.12 223.93,64.8 223.54,65.19 222.59,65.19 222.36,65.42 CZ41.1
N5261056: length 105.3
  TOP w0.102: RD10.1 RD11.1 118.86,9.51 119.5,8.86 120.9,8.86 121.92,7.85 v2(121.92,6.64) ; v2(156.51,6.71) 156.51,18.05 v1(155.53,19.02) 154.14,20.42 QD1.3 ; RD12.1 RD13.1 200.23,7.32 v2(200.83,6.71)
  IN3 w0.122: v2(200.83,6.71) 200.83,7.67 200.71,7.79 157.59,7.79 v2(156.51,6.71) 156.45,6.71 155.94,7.22 122.12,7.22 121.92,7.02 v2(121.92,6.64)
N10757881: length 2.2
  TOP w0.102: v1(82.76,16.31) RD7.1
  TOP w0.508: RD7.1 CD21.2
N15438178: length 7.2
  TOP w0.102: v1(74.33,84.07) 75.05,84.79 PD702.1
  TOP w0.508: PD702.1 75.05,87.22 PD704.1 75.04,88.04 v2(75.05,88.05) PD705.1
  BOTTOM w0.508: v2(75.05,88.05) 74.44,88.05 74.19,88.3 PR708.1
N15438627: length 5.1
  TOP w0.102: PR710.1 81.26,87.36 v1(81.59,87.02)
  TOP w0.254: PC711.1 PR711.1 80.45,86.29 v2(80.63,86.47) 80.58,86.52 PR710.1
  BOTTOM w0.203: v2(80.63,86.47) 80.63,86.19 80.43,85.99 PU700.6
N15439163: length 2.4
  BOTTOM w0.203: PU700.5 v1(80.03,86.46) 80.03,87.44 PR714.2
N15439291: length 4.4
  TOP w0.254: PC718.2 81.26,85.85 v2(81.26,86.46)
  BOTTOM w0.102: PR716.2 82.03,87.54 v1(82.1,87.46)
  BOTTOM w0.203: v2(81.26,86.46) 81.26,86.19 80.83,85.76 PU700.7
  BOTTOM w0.254: PR716.2 81.07,86.96 81.26,86.77 v2(81.26,86.46)
N15439295: length 3.6
  TOP w0.102: v1(83.47,84.7) 82.94,84.7 v2(82.93,84.68)
  TOP w0.254: PC719.2 82.24,85.2 82.76,84.68 v2(82.93,84.68)
  BOTTOM w0.203: PR718.2 83.31,85.06 v2(82.93,84.68) 82.61,84.68 82.29,84.36 PU700.8
N15439512: length 4
  TOP w0.102: v1(83.2,82.16) 82.88,82.47 PR788.2 82.88,83.41
  TOP w0.254: 82.88,83.41 82.88,84 v2(82.93,84.05)
  BOTTOM w0.203: PU700.9 82.46,83.96 82.55,84.05 v2(82.93,84.05) 83.06,84.18 PR720.2
N15440461: length 2
  BOTTOM w0.203: PR717.2 82.99,83.29 82.72,83.56 v1(82.69,83.56) PU700.10
N15441413: length 2.5
  BOTTOM w0.203: PR722.1 80.08,79.54 v1(79.63,80) PU700.18
N15441884: length 6.2
  TOP w0.102: v2(81.72,80.11) 81.72,79.63 82.18,79.17 v1(82.71,79.17)
  TOP w0.508: v2(81.72,80.11) 81.91,80.3 PC729.1
  BOTTOM w0.203: 80.36,79.95 80.03,80.28 PU700.17
  BOTTOM w0.508: v2(81.72,80.11) 81.72,79.48 PR723.1 80.96,79.35 80.36,79.95
N15442134: length 20
  TOP w0.254: PR721.3 84.16,69.2 84.35,69.39 84.35,77.2 v1(84.22,77.33) 84.1,77.46 79.09,77.46 78.57,77.98 78.57,79.11 78.74,79.27 v2(78.74,79.41) 78.74,79.87 PC727.1 78.99,80.12 PC726.2
  BOTTOM w0.203: v2(78.74,79.41) 78.83,79.5 PU700.20
N15442185: length 20.2
  TOP w0.254: PR721.2 84.99,69.2 84.74,69.44 84.74,77.39 84.3,77.84 79.27,77.84 78.97,78.14 78.97,78.89 v1(79.09,79.02) 79.09,79.07 v2(79.44,79.41) 79.89,79.87 PC727.2 79.88,80.12 PC728.1
  BOTTOM w0.203: PU700.19 79.23,79.62 v2(79.44,79.41)
N17156946: length 22.6
  TOP w0.102: v2(67.55,105.9) v1(66.67,105.9)
  TOP w0.254: PC5.1 64.13,103.76 64.68,104.31 PQ6.4 65.2,103.33 v2(65.07,103.2)
  IN3 w0.254: v2(67.55,105.9) 65.07,103.43 v2(65.07,103.2) 65.07,102.86 64.49,102.27 64.49,92.79 v2(64.95,92.33)
  BOTTOM w0.254: PR18.1 PR17.1 66.85,106.66 PR14.2 67.51,105.94 v2(67.55,105.9) ; PQ4.4 65.09,92.47 v2(64.95,92.33)
N17156948: length 3.6
  TOP w0.102: v1(67.75,100.3) 67.64,100.3 67.1,100.84 67.1,100.86
  TOP w0.254: PQ6.1 67.1,100.86 67.06,100.82 66.3,100.82 66.15,100.98 PQ6.2
N17639884: length 3.8
  TOP w0.203: PU500.2 101.5,68.03
  TOP w0.508: PC505.2 PR519.2 100.66,68.03 101.5,68.03
N17640254: length 7.5
  TOP w0.102: PR535.1 109.8,71.53 110.14,71.88 v1(110.78,71.88)
  TOP w0.203: PR535.1 109.53,71.52 PR523.1 PC506.1 109.03,69.26 107.11,69.26 106.85,69.51 106.03,69.51 105.95,69.43 PU500.25
N17640267: length 1.9
  TOP w0.102: v1(109.52,73.5) PR535.2
  TOP w0.203: PR535.2 PC512.1
N17640270: length 8.4
  TOP w0.102: PR521.1 v1(107.68,73.61)
  TOP w0.203: PC512.2 108.62,71.39 PR523.2 PC506.2 107.3,69.77 107.17,69.9 105.9,69.9 105.55,69.54 PU500.26
  TOP w0.254: PR521.1 107.83,71.53 PC512.2
N17645088: length 3.7
  TOP w0.254: v2(110.74,49.38) 110.3,49.82 PR512.2
  BOTTOM w0.254: PL500.3 109.78,50.34 v2(110.74,49.38)
N17680637: length 3.5
  TOP w0.203: PR536.2 100.95,63.93 v1(101.14,64.12) 101.58,64.56 101.58,65.32 101.9,65.63 PU500.8
N17680665: length 3.3
  TOP w0.203: PR539.1 PR516.1 101.66,67.48 101.81,67.63 PU500.3
N18325201: length 3.4
  TOP w0.102: v1(278.2,82.21) CL16.1
  TOP w0.381: v2(276.88,82.91) 276.91,82.89 CL16.1
  BOTTOM w0.381: TL1.3 v2(276.88,82.91)
N18325205: length 3.7
  TOP w0.102: CL17.1 274.05,82.21 v1(274,82.17)
  TOP w0.381: v2(275.61,82.91) 275.57,82.87 CL17.1
  BOTTOM w0.381: TL1.4 v2(275.61,82.91)
N18325209: length 3.6
  TOP w0.102: CL20.1 270.35,82.21 v1(270.62,81.94)
  TOP w0.381: CL20.1 269.22,82.87 v2(269.26,82.91)
  BOTTOM w0.381: TL1.9 v2(269.26,82.91)
N18325213: length 3.8
  TOP w0.102: CL21.1 266.86,82.21 v1(266.46,81.81)
  TOP w0.381: CL21.1 267.95,82.87 v2(267.99,82.91)
  BOTTOM w0.381: TL1.10 v2(267.99,82.91)
N18490882: length 4.2
  TOP w0.102: v1(281.8,41.24) RI14.2 285.21,41.24 285.25,41.21 UI3.16
N18609334: length 5.3
  TOP w0.102: v1(99.13,86.37) 98.98,86.52 RV6.2 98.98,87.73 QV7.1 97.01,88 QV8.2
N18733659: length 2.7
  BOTTOM w0.102: UV10.12 219.92,75.15 CV116.1 220.4,75.1 v1(220.79,74.71)
N18733661: length 2.7
  BOTTOM w0.102: v1(220.8,77.45) 220.8,76.92 CV117.1 220.07,76.52 219.49,75.95 UV10.10
N18749305: length 8.5
  TOP w0.102: v2(108.83,89.28) 110.44,87.67 v1(111.24,87.67) 114.55,87.67 LV1.1
  BOTTOM w0.102: JEDP1.21 108.96,89.41 v2(108.83,89.28)
N18779979: length 2.8
  BOTTOM w0.102: C43.1 R41.2 155.83,93.24 156.75,94.17 v1(156.75,94.69)
N18779981: length 2.6
  BOTTOM w0.102: C42.1 R6.2 152.65,93.18 v1(151.6,94.23)
N19516037: length 3
  TOP w0.102: RZ35.1 CZ9.1 187.93,80.35 v1(189.39,81.81)
N19540333: length 1.4
  TOP w0.102: CZ23.1 239.97,58.47 240.01,58.42 UZ2.10
N19540335: length 1.4
  TOP w0.102: CZ49.1 240.14,57.58 240.19,57.62 UZ2.12
N19544058: length 2.1
  BOTTOM w0.102: CC10.2 RC62.1 v1(197.18,59.78)
N19544059: length 2.5
  BOTTOM w0.102: CC9.2 RC61.1 188.91,58.52 188.4,59.03 v1(187.51,59.03)
N19638635: length 2.2
  TOP w0.203: PU100.19 216.25,49.11 215.31,48.18 PR114.1
N19651849: length 2.1
  TOP w0.102: v1(245.73,65.51) 246.16,65.08 RE27.2 245.23,64.5 CE9.1
N19651850: length 6.6
  TOP w0.102: v2(249.48,71.48) 248.46,70.47 v1(248.24,70.47) RE24.1 ; UE1.B19 250.73,69.01 v2(251.1,69.39)
  IN3 w0.122: v2(249.48,71.48) 249.48,71.01 v2(251.1,69.39)
N20106358: length 3.3
  TOP w0.102: v1(220.69,81.13) 221.1,80.72 221.1,80.13 RV50.1 222.3,80.06 222.32,80.08 UV7.27
N20106372: length 3.4
  TOP w0.102: v1(231.12,87.85) CV60.1 230.17,87.36 229.22,86.4 UV7.1
N20173859: length 3.2
  TOP w0.102: QZ4.1 275.88,20.13 RZ27.1 276.37,19.04 v1(276.83,18.58)
N20174013: length 3.7
  TOP w0.102: v1(284.08,76.94) 284.21,77.06 284.21,78.51 283.72,79.01 RZ33.1 284.21,79.04 QZ9.1
N20249193: length 6.4
  TOP w0.102: CA29.1 27.18,13.83 v1(28.2,14.86)
  TOP w0.203: UA1.35 29.78,15.77 29.45,15.44 29.45,14.5 29.14,14.2 28.18,14.2 27.42,13.44 CA29.1
N20249194: length 3
  TOP w0.203: UA1.36 29.91,15.37 29.83,15.29 29.83,14.31 28.95,13.44 CA29.2
N20249196: length 5.6
  TOP w0.203: UA1.31 29.7,17.37 29.49,17.16 29.12,17.16 28.24,16.28 v2(28.1,16.28)
  BOTTOM w0.102: CA25.1 v1(25.11,16.36)
  BOTTOM w0.254: CA25.1 27.34,16.36 27.42,16.28 v2(28.1,16.28)
N20249200: length 3.7
  TOP w0.102: v1(43.19,21.28) 42.94,21.54 41.13,21.54 40.74,21.14 RA12.1 CA27.1
N20249201: length 2.3
  TOP w0.102: CA28.1 RA13.1 40.74,22.19 v1(41.56,23.02)
N20249202: length 4.5
  TOP w0.102: RA21.2 30.07,26.4 QA2.5 QA2.6 29.13,27.57 29.27,27.71 31.11,27.71 v1(31.23,27.6)
N20249205: length 2.3
  TOP w0.102: CA33.1 RA17.2 39.94,17.15 40.04,17.04 40.04,16.41 v1(40.29,16.15)
N20249232: length 3.3
  TOP w0.102: DA5.1 24,15.97 24.65,16.62 v1(25.45,16.62)
  TOP w0.381: DA5.1 RA25.2
N20249233: length 2.7
  TOP w0.102: v1(23.78,12.9) 24,13.12 DA4.1
  TOP w0.381: RA24.2 23.62,14.58 DA4.1
N20249314: length 6.6
  TOP w0.102: QA3.3 40.8,27.05 v1(41.31,27.56)
  TOP w0.254: RA27.2 37.77,24.55 39.3,24.55 39.68,24.93 39.68,26.77 39.96,27.05 QA3.3
N20249315: length 1.4
  TOP w0.254: QA3.6 37.97,25.31 37.58,25.31 RA28.2
N20360585: length 4.5
  TOP w0.203: v2(28.95,14.71) 28.95,15.42 29.71,16.17 UA1.34
  BOTTOM w0.102: v1(28.22,15.01) 28.52,14.71 v2(28.95,14.71)
  BOTTOM w0.254: CA49.2 29.47,13.94 28.95,14.46 v2(28.95,14.71)
N20364102: length 7.3
  TOP w0.102: CA35.2 v1(25.76,23.64)
  TOP w0.203: UA1.25 29.98,19.77 29.89,19.86 29.89,21.39 29.27,22.01 28.19,22.01 28.05,22.15 28.05,22.31 27.23,23.13 CA35.2
N20364110: length 4.6
  TOP w0.203: UA1.21 32.26,21.8 v1(32.11,21.95) 32.11,21.95 31.69,22.37 v2(31.67,22.37) 30.95,23.1 CA51.1
  BOTTOM w0.254: RA44.1 30.83,23.21 v2(31.67,22.37)
N20364112: length 2.6
  BOTTOM w0.254: CA52.1 29.39,12.7 v1(29.77,12.7) 30.19,12.7 v2(30.54,13.06)
N20364114: length 2.9
  TOP w0.203: UA1.7 37.15,17.77 37.25,17.68 v1(37.61,17.68) 37.93,17.68 38.78,18.52 CA53.1
N20384906: length 1.4
  TOP w0.254: UZ7.6 195.14,47.29 195.02,47.4 CZ64.1
N20711035: length 3.8
  TOP w0.102: 205.31,58.97 205.31,58.36 v1(205.7,57.96)
  TOP w0.254: v2(205.92,58.66) 205.61,58.66 205.31,58.97 PR309.1
  BOTTOM w0.254: v2(205.92,58.66) 206.07,58.66 206.66,59.26 206.66,59.33 PC304.2
N20813044: length 81.8
  TOP w0.254: v2(94.87,80.7) 95.76,79.81 v1(95.76,79.48) 95.76,78.8 v2(96.42,78.14)
  BOTTOM w0.254: v2(94.87,80.7) 94.92,80.65 PQ826.4 ; PD813.1 62.19,32.88 PR822.1 61.39,34.38 62.16,35.15 62.16,38.3 62.66,38.8 PC809.2 PR818.1 62.66,41.17 64.04,42.56 75.59,42.56 78.37,45.34 78.37,57.33 82.51,61.47 94.23,61.47 97.85,65.09 97.85,68.45 99.59,70.19 99.59,73.66 98.64,74.61 PQ815.4 98.64,77.52 98.23,77.93 96.63,77.93 v2(96.42,78.14)
N20813052: length 60.9
  IN1 w0.254: v2(63.56,41) 64.39,40.17 70.74,40.17 71.63,41.06 71.63,53.4 75.32,57.1 77.02,57.1 79.5,59.58 84.92,59.58 87.39,62.04 87.39,63.2 93.09,68.91 93.09,75.4 93.65,75.96 v2(93.65,78.36)
  BOTTOM w0.254: v2(63.56,41) 63.57,40.98 PR818.2 PC809.1
  vias: v1(93.81,79.22)
N20813067: length 4.3
  TOP w0.102: PR828.2 70.22,28.12 70.32,28.02 v1(70.32,27.74)
  TOP w0.254: PR828.2 70.22,29.46 69.42,30.26 PQ832.2
N20813069: length 13.6
  TOP w0.102: PR830.2 56.51,32.37 v1(57.39,33.25)
  TOP w0.254: PQ832.1 66.1,30.91 66.08,30.89 57.44,30.89 57.17,30.61 PQ829.2 PR830.2
N20813073: length 12
  TOP w0.254: PQ829.1 55.1,27.74 55.66,27.18 v1(56.77,27.18) 66.06,27.18 PD815.2
N20813075: length 4.9
  TOP w0.102: v1(52.64,29.82) 53.43,30.61 PQ829.3
  TOP w0.254: PR895.2 PR830.1 55.15,32.02 54.14,31 PQ829.3
N20813085: length 6.1
  TOP w0.254: PC807.2 118.93,100.82 119.06,100.69 v1(120.2,100.69) 120.65,100.69 120.91,100.44 PR811.1 v2(121.51,101.14)
  BOTTOM w0.254: v2(121.51,101.14) 120.51,101.14 120.38,101.01 PQ810.4
N20813089: length 3.4
  BOTTOM w0.102: 55.91,30.53 55.46,30.98 55.46,32.16 v1(55.23,32.38)
  BOTTOM w0.254: PR853.2 55.91,30.53 PQ813.5
N20826302: length 3.1
  TOP w0.102: 62.74,9.17 62.35,9.17 62.13,8.94 62.13,6.83 v1(62.35,6.6)
  vias: v2(63.27,9.96)
N20843375: length 1.6
  TOP w0.203: CZ37.1 245.26,29.61 246.17,29.61 246.24,29.68 UL3.12
N20843456: length 1.6
  TOP w0.203: CL24.1 246.24,30.59 246.34,30.48 UL3.10
N20857922: length 66.5
  TOP w0.254: v2(90.84,77.99) 92.58,77.99 95.68,74.89 PR815.2 96.17,73.53 96.25,73.61 PR816.1
  IN3 w0.254: v2(90.84,77.99) 90.24,77.39 90.24,75.13 91.3,74.08 91.3,68.81 83.53,61.04 80.25,61.04 73.34,54.13 73.34,52.04 69.09,47.79 69.09,40.74 66.61,38.26 v2(66.61,35.8)
  BOTTOM w0.254: v2(66.61,35.8) v1(67.29,35.8) 68.2,35.8 68.74,35.26 PQ806.3
N20862119: length 2.9
  TOP w0.102: PR518.2 v1(95.76,61.95)
  TOP w0.254: PR518.2 97.08,61.95 97.13,62 PR525.1 97.66,62.38 97.74,62.46 PR524.1
N20899585: length 3.2
  TOP w0.102: v2(222.76,74.46) 222.83,74.39 UV600.20
  BOTTOM w0.102: v1(221.79,72.67) 221.79,72.99 222.58,73.77 RV600.1 v2(222.76,74.46)
N20899609: length 2.7
  TOP w0.102: UV600.17 v2(224.03,74.45)
  BOTTOM w0.102: v1(225.14,73.77) CV605.1 224.03,74.44 v2(224.03,74.45)
N20935195: length 2.9
  BOTTOM w0.203: PU700.21 78.43,80.36 v1(77.98,79.91) 77.12,79.06 PR799.1
N20970248: length 5
  TOP w0.102: v2(140.97,14.92) 140.51,14.92 RD15.2 140.15,15.43 139.13,16.46 v1(138.9,16.46)
  BOTTOM w0.102: JDIMM1.197 140.2,15.1 140.38,14.92 v2(140.97,14.92)
N20970250: length 4.5
  TOP w0.102: v2(140.95,14.34) 140.17,14.34 RD16.2 140.15,14.19 v1(139.23,13.26)
  BOTTOM w0.102: v2(140.95,14.34) 141.4,14.78 JDIMM1.201
N20987678: length 6.6
  BOTTOM w0.102: PD817.1 60.89,30.85 v1(61.4,30.34)
  BOTTOM w0.254: PR827.2 56.53,28.82 57.54,29.83 PQ814.3 59.65,29.83 PD817.1
N20987955: length 54.7
  TOP w0.102: v2(93.94,73.64) 93.22,73.64 v1(93.11,73.53)
  TOP w0.254: PR813.2 94.4,73.53 94.28,73.64 v2(93.94,73.64)
  IN1 w0.254: v2(70.98,38.8) 72.73,40.55 72.73,44.52 73.25,45.05 73.25,53.7 76.26,56.71 77.17,56.71 79.66,59.2 85.08,59.2 88.02,62.14 90.68,62.14 93.47,64.93 93.47,73.17 v2(93.94,73.64)
  BOTTOM w0.254: v2(70.98,38.8) 70.04,37.86 PQ806.6 PQ806.5
N20988471: length 6.1
  TOP w0.102: v1(44.41,16.53) 45.32,17.45 PR819.1
  TOP w0.254: PU806.1 47.21,20.67 47.2,20.66 PQ817.6 47.2,19.44 PR819.1
N21259653: length 5.9
  TOP w0.102: RD28.1 222.92,19.11 v2(222.94,19.12) 222.94,20.35 v1(222.64,20.65)
  BOTTOM w0.102: v2(222.94,19.12) 222.49,19.12 221.7,18.33 JDIMM2.197
N21259657: length 3.6
  TOP w0.102: v1(222.01,16.08) 222.67,16.74 RD27.1 222.67,17.61 v2(222.9,17.85)
  BOTTOM w0.102: JDIMM2.201 v2(222.9,17.85)
N21719420: length 3.5
  TOP w0.102: v1(252.65,15.82) 252.91,16.08 CN4.1 253.6,16.79 252.94,17.45 UN3.6
N21789942: length 7.1
  BOTTOM w0.254: SW1.2 295.13,7.36 294.64,7.85 291.35,7.85 v2(290.74,8.46) 290.13,9.07 RC2.2
N21984822: length 16.8
  BOTTOM w0.102: RA1.2 19.05,15.02 16.55,17.53 DA2.2 16.32,18.3 16.63,18.62 v1(16.63,20.29) 16.63,22.96 14.09,25.5 11.74,25.5 11.55,25.31 JHP1.5
N22207973: length 4.1
  TOP w0.203: UA1.22 31.86,21.55 31.44,21.97 30.73,21.97 29.72,22.98 RA45.1
N22988375: length 2
  TOP w0.102: R273.2 C319.1 v1(170.11,97.21)
N23890107: length 2.5
  TOP w0.102: QE4.2 250.87,33.58 250.87,33.58 250.87,32.76 RE70.2 250.87,32.63 v1(251.65,31.85)
N24544483: length 20.9
  TOP w0.102: v1(68.31,103.48) 69.3,104.47 PQ2.1
  TOP w0.254: PD5.2 PD5.3 ; PD5.3 61.3,104.83 PL3.1 ; PD5.3 62.98,105.52 63.1,105.4 67.98,105.4 68.17,105.21 69.7,105.21 70.04,104.86 PQ2.1 70.04,103.43 v2(70.29,103.17)
  BOTTOM w0.254: PR10.2 72.39,100.43 PR7.1 71.64,100.44 70.29,101.79 v2(70.29,103.17)
N24607258: length 1.9
  BOTTOM w0.254: PU300.5 205.57,61.81 206.03,62.27 206.18,62.27 206.68,62.76 PC309.1
N48705653: length 9.1
  TOP w0.102: v1(67.55,106.91) 67.9,106.55 PQ2.3
  TOP w0.254: v2(69.92,105.82) 69.92,106.18 69.56,106.55 PQ2.3
  BOTTOM w0.254: v2(69.92,105.82) 70.81,104.93 70.81,102.92 71.45,102.28 PR9.1 PR7.2
N48705663: length 9
  TOP w0.102: PQ3.2 69.04,102.61 v1(68.31,101.88)
  TOP w0.254: v2(71.65,97.98) 71.65,100.49 PQ3.2
  BOTTOM w0.254: PR12.2 PR10.1 72.27,98.6 v2(71.65,97.98)
N48705665: length 7.9
  TOP w0.102: v1(72.3,100.61) 71.43,101.48 PQ3.1
  TOP w0.254: PQ3.1 72.26,101.96 72.57,102.26 PR13.1 PR11.2 71,105.3 PQ2.2
N48708367: length 3.9
  TOP w0.102: PR210.2 70.22,9.37 v1(69.25,9.37) 68.96,9.08 v2(68.96,8.74)
  BOTTOM w0.203: PU200.7 68.01,8.54 68.2,8.36 68.58,8.36 v2(68.96,8.74)
N48708425: length 3.1
  BOTTOM w0.102: PR206.2 66.69,6.83 v1(67.17,6.35)
  BOTTOM w0.203: PR206.2 67.21,7.93 PU200.9
N48716673: length 3.4
  TOP w0.102: PR838.1 84.49,31.67 v1(84.69,31.67)
  TOP w0.254: PU800.28 82.7,32.72 82.74,32.68 PR838.1
N48716693: length 2
  TOP w0.254: PU800.26 80.35,30.2 PR845.1
N49522072: length 9.8
  TOP w0.254: PQ702.2 69.21,94.68 69.21,92.05 69.54,91.72 PQ701.2 70.25,91.12 69.8,90.66 v2(69.34,90.66)
  BOTTOM w0.102: v1(70.22,91.19) 69.7,90.66 v2(69.34,90.66)
  BOTTOM w0.254: v2(69.34,90.66) PR702.2 PC700.2
N49522215: length 6
  TOP w0.102: v1(75.3,92.63) PR709.2
  TOP w0.254: PQ703.3 74.29,92.64 PR709.2 PR706.2 PR707.2 72.39,92.64 PQ703.1
N49522242: length 6.1
  TOP w0.254: PC703.1 77.4,86.27 v2(77.98,86.84)
  BOTTOM w0.203: v2(77.98,86.84) 77.98,86.5 v1(78.17,86.31) 78.43,86.05 PU700.1
  BOTTOM w0.254: PR705.2 78.36,89.63 PC702.2 78.36,87.64 77.98,87.26 v2(77.98,86.84)
N49522275: length 5.7
  TOP w0.254: PC701.2 78.48,86.72 v2(78.61,86.85)
  BOTTOM w0.203: v2(78.61,86.85) 78.61,86.66 78.83,86.45 PU700.2
  BOTTOM w0.254: v2(78.61,86.85) 78.61,87.21 v1(78.91,87.5) 79.27,87.86 PC702.1 79.26,88.78 PR704.2
N49522729: length 5.2
  TOP w0.102: v2(67.12,90.84) 67.47,90.49 v1(67.47,89.79)
  TOP w0.254: PQ701.1 67.62,92.68 67.5,92.56 67.5,91.83 67.12,91.45 v2(67.12,90.84)
  BOTTOM w0.254: v2(67.12,90.84) 67.12,90.74 66.81,90.44 66.81,89.55 PR701.2
N49522731: length 8.9
  TOP w0.254: PQ702.1 68.73,96.13 68.73,93.87 68.31,93.45 67.6,93.45 67.12,92.96 67.12,92.1 v1(66.42,91.4) 66.39,91.38 66.39,90.93 v2(66.48,90.84)
  BOTTOM w0.254: PR701.3 66.8,91.22 66.48,90.91 v2(66.48,90.84)
N49522780: length 3.8
  TOP w0.102: v1(67.08,98.86) 66.86,99.07 65.73,99.07 PR700.1
  TOP w0.254: PR700.1 65.05,99.53 64.72,99.86 PQ700.4
N61500733: length 3.3
  TOP w0.203: PR513.1 100.82,66.39 100.82,66.85 100.95,66.98 v1(101.25,66.98) 101.8,66.98 102.06,67.23 PU500.4
N61500909: length 0.6
  TOP w0.203: 104.75,69.7 PU500.28
  vias: v1(104.89,70.13)
N61500999: length 2.1
  TOP w0.102: v1(111.44,53.12) 111.66,52.91 PH501.2
  TOP w0.254: PR515.1 112.07,51.7 PH501.2
N61501245: length 13.1
  TOP w0.102: v2(105.71,63.67) 105.71,62.14 v1(106.26,61.59)
  TOP w0.203: PU500.14 105.15,64.42 105.71,63.86 v2(105.71,63.67)
  IN4 w0.254: v2(101.41,59.61) 101.41,60.76 103.81,63.16 105.2,63.16 v2(105.71,63.67)
  BOTTOM w0.254: v2(101.41,59.61) PH500.2 ; PC501.1 v2(105.71,63.67) 105.71,64.74 PR505.2
N61501462: length 3.9
  TOP w0.102: v2(107.49,63.8) v1(108.39,63.8)
  TOP w0.203: PU500.16 105.95,64.64 106.28,64.31 106.98,64.31 v2(107.49,63.8)
  BOTTOM w0.203: PR511.2 v2(107.49,63.8)
N66971793: length 2.9
  TOP w0.203: PU100.5 219.08,47.33 219.22,47.19 220.43,47.19 220.77,46.84 PR105.2
N66972075: length 2.7
  TOP w0.203: PU100.1 217.48,47.37 217.22,47.1 216.51,47.1 PR106.2
N78957489: length 2.2
  BOTTOM w0.102: PR822.2 v1(60.47,34.67)
  BOTTOM w0.254: PQ816.1 59.83,33.84 59.99,33.68 PR822.2
N78967043: length 15.2
  TOP w0.254: v2(54.14,32.56) 54.04,32.56 50,28.51 v1(50,26) 48.51,24.51 PU806.4
  BOTTOM w0.254: PQ816.2 54.78,33.2 v2(54.14,32.56)
N78985854: length 8.4
  TOP w0.102: PR812.2 69.76,38.08 v1(69.61,38.23)
  TOP w0.254: v2(67.61,35.24) 67.66,35.19 69.8,35.19 70.02,35.41 PU804.2 70.02,36.41 69.76,36.68 PR812.2
  BOTTOM w0.254: v2(67.61,35.24) 67.61,33.82 68.29,33.14 PR810.2
N79002827: length 3
  TOP w0.102: v1(68.54,33.07) 68.66,33.19 v2(69.39,33.19)
  TOP w0.254: v2(69.39,33.19) 69.37,33.21 PU804.4
  BOTTOM w0.254: v2(69.39,33.19) PQ806.2
N79023703: length 2.1
  TOP w0.254: PR863.1 75.68,30.27 76.85,31.45 PU800.19
N79030038: length 4.7
  BOTTOM w0.102: PR829.2 50.28,30.54 v1(49.92,30.17)
  BOTTOM w0.254: PQ813.3 51.99,31.18 PR829.2 51.37,30.53 PQ813.2
N79030087: length 2.8
  BOTTOM w0.102: PR826.2 53.92,28.82 v1(53.71,28.6)
  BOTTOM w0.254: PQ813.6 54.99,29.88 55.17,29.7 55.17,29.12 PR826.2
N79030091: length 4.3
  BOTTOM w0.102: PR826.1 54.56,27.9 v1(53.76,27.1)
  BOTTOM w0.254: PQ814.2 PR827.1 PR826.1
N79030745: length 3.8
  BOTTOM w0.254: PD813.2 62.72,30.12 v1(61.59,28.99) 61.48,28.87 59.78,28.87 PQ814.1
N79114795: length 5.5
  TOP w0.102: v1(50.31,11.77) 49.77,11.23 48.91,11.23 48.35,11.79 PC4.1
  TOP w0.254: PQ1.2 48.71,10.62 48.31,11.02 PC4.1 47.31,11.79 PR6.2
N79114801: length 5.9
  TOP w0.102: v1(45.68,6.63) 46.94,7.89 PQ1.1
  TOP w0.254: PQ1.1 50.07,7.89 PD4.2
N80905978: length 5
  BOTTOM w0.102: v1(117.76,72.16) PC402.1
  BOTTOM w0.254: PC402.1 115.63,72.16 PR401.1 ; PR401.1 115.62,73.05 PR400.2 ; PR401.1 115.48,72.17 114.6,71.29 PU400.8
N80906026: length 5
  BOTTOM w0.102: PC403.2 105.99,73.18 v1(105.22,72.41)
  BOTTOM w0.254: PC403.2 PR402.2 PR403.1 107.5,72.26 107.81,72.56 PU400.2

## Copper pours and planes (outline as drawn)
1.05V_LP_EN on BOTTOM (solid shape): 200.16,66.85 200.16,64.49 199.48,63.8 198.63,63.8 198.54,63.89 198.54,64.17 198.69,64.32 199.17,64.32 199.37,64.53 199.37,65.86 198.99,66.24 198.7,66.24 198.4,66.54 198.4,67.04 198.51,67.14 199.87,67.14
1.5VSP on BOTTOM (solid shape): 109.78,77.26 109.78,73.71 109.58,73.51 107.68,73.51 107.36,73.83 106.03,73.83 106.03,74.4 107.04,75.42 107.04,76.75 107.62,76.75 107.62,77.26 107.04,77.26 107.04,77.52 107.11,77.58 109.46,77.58
1.35V_B+ on TOP (solid shape): 68.89,23.28 68.77,23.15 65.91,23.15 65.78,23.28 62.54,23.28 61.66,22.39 60.45,22.39 60.45,22.71 61.02,22.71 61.02,24.1 60.45,24.1 60.45,25.18 60.7,25.44 68.89,25.44
+0.9V_LAN on TOP (solid shape): 256.04,90.93 256.52,90.45 256.52,88.29 256.47,88.24 256.37,88.24 256.32,88.29 256.32,89.69 255.51,90.5 255.51,91.13 256.04,91.13
+0.9V_LAN on TOP (solid shape): 252.09,85.34 252.96,85.34 252.97,85.33 254.11,85.33 254.17,85.26 254.17,85.14 254.11,85.07 252.62,85.07 252.49,84.94 250.64,84.94 250.49,85.08 250.49,85.37 250.63,85.5 251.93,85.5
+0.9V_LAN on TOP (solid shape): 261.4,91.03 261.4,90.73 261.27,90.6 260.97,90.6 259.52,89.15 259.22,89.15 259.09,89.03 259.09,88.42 258.91,88.24 258.79,88.24 258.73,88.29 258.73,89.41 258.89,89.56 259.29,89.56 260.26,90.53 260.26,91.13 260.28,91.16 261.27,91.16
+0.9V_LAN on BOTTOM (solid shape): outline of 135 points within 250.11,81.44 261.56,91.2
+0.675V_DDR_VTT on TOP (solid shape): 143.32,16.15 143.32,13.26 142.57,12.51 142.57,10.87 143.05,10.4 143.05,9.44 142.79,9.18 141.7,9.18 141.47,9.41 141.47,10.25 141.25,10.47 141.25,13.64 141.68,14.08 141.68,16.07 141.89,16.28 143.19,16.28
+0.675V_DDR_VTT on TOP (solid shape): 224.87,16.4 224.87,13.48 224.36,12.97 224.36,9.77 224.22,9.63 222.88,9.63 222.82,9.69 222.82,16.17 223.07,16.42 224.85,16.42
+0.675V_DDR_VTT on BOTTOM (solid shape): 75.12,14.39 75.12,13.44 74.86,13.18 72.01,13.18 71.82,13.37 71.82,14.58 74.93,14.58
+0.675V_DDR_VTT on BOTTOM (solid shape): 142.78,16.91 142.78,11.05 143.1,10.73 143.1,7.47 142.84,7.21 142.24,7.21 142.11,7.34 142.11,9.12 141.22,10.01 141.22,14.08 141.8,14.66 141.8,17.38 141.88,17.45 142.24,17.45
+0.675V_DDR_VTT on BOTTOM (solid shape): 224.03,17.12 224.03,15.83 224.7,15.16 224.7,7.64 224.28,7.21 223.77,7.21 223.64,7.34 223.64,8.29 223.65,8.3 223.65,9.7 223.33,10.02 223.33,17.31 223.45,17.44 223.71,17.44
+0.675V_DDR_VTT on IN4 (solid shape): 75.42,14.4 75.42,12.55 75.44,12.54 75.44,12.29 75.37,12.23 73.91,12.23 73.91,12.55 73.9,12.55 73.9,14.4 74.15,14.65 75.17,14.65
+0.675V_DDR_VTT on IN4 (solid shape): 143.43,10.4 143.43,8.81 143.7,8.55 143.7,7.09 141.92,7.09 141.91,7.1 141.91,8.62 142.1,8.81 142.1,10.4 142.29,10.59 143.24,10.59
+0.675V_DDR_VTT on IN4 (solid shape): 224.14,15.03 224.14,8.41 223.14,7.4 221.68,7.4 221.68,8.93 221.93,8.93 222.69,9.69 222.69,14.96 222.95,15.21 223.96,15.21
+0.675V_P on BOTTOM (solid shape): 71.61,14.33 71.04,14.33 71.04,13.82 71.61,13.82 71.61,13.32 71.04,12.75 71.04,11.41 70.47,11.41 69.94,10.88 68.78,10.88 68.7,10.95 68.7,11.03 68.77,11.09 69.66,11.09 69.74,11.18 69.74,11.61 69.67,11.69 68.37,11.69 68.31,11.75 68.31,12.53 68.37,12.59 69.39,12.59 69.97,13.18 69.97,14.13 70.42,14.58 71.61,14.58
+1.2V_LDO on TOP (solid shape): 280.16,28.49 280.29,28.36 280.6,28.36 280.73,28.23 280.73,27.98 280.6,27.85 279.46,27.85 279.46,28.74 280.16,28.74
+1.2V_LDO on TOP (solid shape): 288.27,36.18 288.27,35.86 288.08,35.67 286.75,35.67 285.42,34.34 285.42,33.55 285.37,33.5 285.26,33.5 285.21,33.55 285.21,34.69 285.73,35.21 285.73,36.24 285.86,36.37 288.08,36.37
+1.2V_LDO on TOP (solid shape): 289.68,35.28 289.68,33.82 289.25,33.82 288.43,32.99 287.4,32.99 287.33,33.06 287.33,33.27 287.44,33.38 288.19,33.38 288.73,33.92 288.73,34.58 288.35,34.96 288.35,35.22 288.48,35.34 289.62,35.34
+1.2V_LDO on TOP (solid shape): 290.81,31.29 290.81,30.88 290.7,30.77 290.7,30.14 290.57,30.01 290.13,30.01 289.94,29.82 289.94,29.63 289.82,29.51 289.28,29.51 289.05,29.74 288.26,29.74 288.18,29.81 287.37,29.81 287.32,29.86 287.32,29.97 287.37,30.02 288.22,30.02 288.25,29.99 288.34,29.99 288.36,29.97 289.43,29.97 289.63,30.17 289.63,30.6 289.45,30.78 289.2,30.78 288.97,31.01 287.37,31.01 287.32,31.06 287.32,31.13 287.4,31.21 290.31,31.21 290.52,31.41 290.69,31.41
+1.05V_M on TOP (solid shape): 200.31,46.51 200.31,45.03 200.39,44.96 200.39,42.94 200.8,42.53 200.8,42.51 200.87,42.37 201,42.27 201,40.65 200.81,40.46 197.75,40.46 197.24,40.97 197.24,45.73 197.66,46.15 197.66,46.84 197.72,46.91 199.91,46.91
+1.05V_M on TOP (solid shape): 172.68,86.5 172.68,84.25 172.29,83.86 171.04,83.86 170.95,83.92 170.97,84.03 170.95,84.56 170.41,84.55 170.38,84.54 170.34,84.55 170,84.63 169.76,84.38 169.71,84.31 169.62,84.31 169.43,84.34 169.25,84.26 169.19,84.23 169.12,84.26 168.73,84.3 168.54,83.96 168.51,83.89 168.44,83.86 167.23,83.86 167.23,83.9 167.21,83.97 167.18,84.04 167.17,84.12 167.22,84.18 167.26,84.2 167.3,84.23 167.38,84.25 167.45,84.21 168.14,84.4 167.49,84.71 167.41,84.68 167.34,84.71 167.05,84.85 166.77,84.7 166.71,84.66 166.64,84.67 166.55,84.7 166.47,84.71 166.4,84.73 166.37,84.79 165.74,84.95 166.02,84.37 166.08,84.35 166.12,84.29 166.23,84.09 166.43,84 166.5,83.96 166.52,83.89 166.59,83.64 166.82,83.51 166.86,83.5 166.86,83.01 166.51,82.65 164.85,82.65 164.8,82.7 164.8,86.46 164.99,86.65 172.53,86.65
+1.05V_M on BOTTOM (solid shape): outline of 98 points within 196.01,43.42 204.71,55.61
+1.05V_M on IN2 (solid shape): outline of 2406 points within 162.25,53.7 199.63,62.08
+1.05V_M on IN3 (solid shape): 199.75,53.83 199.56,53.64 198.48,53.64 198.23,53.89 198.23,56.94 199.75,56.94
+1.05V_M on IN3 (solid shape): 172.71,84.9 172.71,82.54 172.51,82.34 171.18,82.34 171.05,82.47 171.05,84.18 171.07,84.28 171.05,84.39 171.05,84.88 171.16,84.98 172.62,84.98
+1.05V_MODPHY on TOP (solid shape): outline of 141 points within 159.83,80.26 171.42,84.18
+1.05V_MODPHY_PCH on TOP (solid shape): outline of 290 points within 164.14,65.89 167.45,80.67
+1.05V_MP on TOP (solid shape): 205.36,54.33 205.36,53.44 205.23,53.31 204.89,53.31 204.71,53.13 204.71,49.43 204.4,49.12 201.04,49.12 200.71,49.45 200.71,53.12 200.71,53.13 200.71,54.26 200.97,54.52 205.17,54.52
+1.05V_MP on BOTTOM (solid shape): 205.42,54.27 205.42,53.44 205.23,53.25 204.91,53.25 204.71,53.05 204.71,49.06 204.44,48.79 203.6,48.79 203.6,48.27 203.57,48.23 203.18,48.23 203.17,48.25 203.17,48.79 202.42,48.79 202.42,48.27 202.4,48.25 202.02,48.25 201.98,48.28 201.98,48.79 201.04,48.79 200.72,49.11 200.72,54.27 200.97,54.52 205.17,54.52
+1.05V_RUN on TOP (solid shape): 176.13,84.33 176.13,82.69 175.91,82.46 175.22,82.46 174.66,81.9 167.9,81.9 167.79,82.02 167.79,83.26 168.13,83.6 172.49,83.6 173.34,84.45 176.01,84.45
+1.05V_RUN on TOP (solid shape): 163.83,69.57 163.94,69.54 164.05,69.56 164.08,69.57 164.21,69.44 164.21,69.25 164.02,69.06 164.02,68.25 164.02,68.11 164.08,68.05 164.08,67.54 163.52,67.54 163.45,67.6 163.45,69.44 163.58,69.57 163.82,69.57
+1.05V_RUN on TOP (solid shape): 160.96,60.04 161.1,60.05 161.22,59.92 161.22,59.66 161.03,59.47 161.03,58.71 161.16,58.58 161.6,58.58 161.73,58.46 161.73,57.57 161.67,57.51 161.16,57.51 160.72,57.95 160.33,57.95 160.21,58.08 160.21,58.52 160.08,58.65 159.57,58.65 159.19,58.27 157.16,58.27 157.03,58.39 157.03,59.28 157.29,59.28 157.29,58.71 157.79,58.71 157.79,59.28 158.24,59.28 158.43,59.47 159.79,59.47 160.19,59.37 160.42,59.72 160.41,59.74 160.72,60.05 160.89,60.05
+1.05V_RUN on TOP (solid shape): 159.51,83.79 159.51,79.79 159,79.29 154.37,79.29 153.86,79.79 153.16,79.79 152.65,79.29 149.41,79.29 148.78,79.92 146.3,79.92 145.98,80.24 145.16,80.24 144.59,79.67 144.14,79.67 143.95,79.86 143.95,81.64 144.59,82.27 149.35,82.27 149.79,81.83 152.14,81.83 152.46,81.51 157.03,81.51 157.1,81.57 157.1,82.17 157.5,82.17 157.5,82.12 157.51,82.06 157.53,82.01 157.55,81.97 157.58,81.92 157.62,81.88 157.66,81.85 157.7,81.82 157.75,81.8 157.81,81.79 157.86,81.79 157.91,81.79 157.96,81.8 158.01,81.82 158.06,81.85 158.1,81.88 158.14,81.92 158.17,81.97 158.19,82.01 158.21,82.06 158.21,82.12 158.21,82.17 158.21,82.22 158.19,82.27 158.17,82.32 158.14,82.37 158.1,82.4 158.06,82.44 158.01,82.46 157.96,82.48 157.91,82.5 157.86,82.5 157.81,82.5 157.75,82.48 157.7,82.46 157.66,82.44 157.62,82.4 157.58,82.37 157.55,82.32 157.53,82.27 157.51,82.22 157.5,82.17 157.1,82.17 157.1,83.92 157.29,84.11 159.19,84.11
+1.05V_RUN on TOP (solid shape): outline of 203 points within 177.45,36.93 201.04,50.27
+1.05V_RUN on BOTTOM (solid shape): 175.96,83.86 175.96,82.33 175.51,81.89 173.35,81.89 173.35,83.79 173.61,84.05 175.77,84.05
+1.05V_RUN on BOTTOM (solid shape): 217.41,74.83 217.41,74.17 217.41,73.07 217.38,73.04 215.9,73.04 215.69,73.25 215.69,74.56 216,74.86 217.37,74.86
+1.5V_RUN on BOTTOM (solid shape): 106.88,77.51 106.88,75.75 106.75,75.62 105.46,75.62 105.28,75.79 105.28,77.25 105.56,77.53 106.86,77.53
+1.05V_RUN on BOTTOM (solid shape): 199.95,70.08 199.95,67.73 199.73,67.51 198.19,67.51 198.14,67.56 197.82,67.56 197.77,67.51 196.14,67.51 195.93,67.72 195.93,69.25 197.05,70.37 199.65,70.37
+1.05V_RUN on BOTTOM (solid shape): 145.92,81.63 145.92,80.51 145.65,80.25 145.03,80.25 144.52,79.73 142.17,79.73 141.86,80.05 141.86,81.7 144.07,81.7 144.07,81.71 145.84,81.71
+1.05V_RUN on VCC (solid shape): outline of 8157 points within 157.65,46.01 182.81,72.11
+1.5V_RUN on IN2 (solid shape): 107.57,75.48 108.01,75.48 108.01,74.9 105.03,74.9 105.03,75.86 105.41,76.24 106.8,76.24
+1.05V_RUN on IN2 (solid shape): 199.63,69.92 199.63,69.03 199.49,68.88 197.81,68.88 197.66,69.03 197.66,69.99 197.69,70.01 199.54,70.01
+1.05V_RUN on IN2 (solid shape): outline of 276 points within 215.96,73.28 219.14,80.37
+1.05V_RUN on IN2 (solid shape): outline of 1974 points within 126.62,68.23 211.39,88.43
+1.05V_RUN on IN3 (solid shape): 179.48,47.18 179.48,46.17 179.32,46.01 179.32,45.06 178.81,45.06 178.81,45.25 177.54,46.52 177.54,47.22 177.73,47.41 179.26,47.41
+1.05V_RUN on IN3 (solid shape): outline of 2195 points within 157.8,58.15 166.62,84.05
+1.05V_RUN on IN4 (solid shape): outline of 798 points within 197.23,68.99 217.51,76
+1.5V_RUN_AUDIO on TOP (solid shape): 32.36,14.9 32.36,13.58 32.34,13.56 31.96,13.18 31.96,12.52 32.04,12.45 32.04,10.44 31.98,10.38 31.34,10.38 31.22,10.49 31.22,12.88 32.15,13.81 32.15,14.9 32.2,14.96 32.31,14.96
+1.05V_RUN_UZ7 on TOP (solid shape): 193.85,47.1 194.04,46.91 196.2,46.91 196.26,46.84 196.26,44 195.74,43.48 191.91,43.48 191.65,43.74 191.65,43.95 191.66,43.96 191.66,47.48 191.85,47.67 193.85,47.67
+1.05V_RUN_VMM on BOTTOM (solid shape): outline of 119 points within 207.37,69.07 219.41,75.16
+1.05V_VCCST on TOP (solid shape): 156.91,61 158.3,61 158.3,60.43 158.11,60.24 158.11,59.54 158.05,59.47 157.03,59.47 156.91,59.6 156.91,59.92 156.33,60.49 155.7,60.49 155.7,61.12 156.78,61.12
+1.05V_VCCST on BOTTOM (solid shape): 157.43,61 157.44,60.98 157.48,60.95 157.52,60.92 157.57,60.9 157.62,60.89 157.67,60.89 157.72,60.89 157.77,60.9 157.81,60.92 157.86,60.95 157.89,60.98 157.91,61 158.24,61 158.37,60.87 158.37,60.08 158.35,60.05 158.34,60 158.34,59.94 158.34,59.89 157.86,59.41 157.22,59.41 156.91,59.73 156.91,60.42 157.35,60.42 157.35,60.37 157.36,60.32 157.37,60.27 157.4,60.23 157.43,60.18 157.46,60.15 157.5,60.12 157.55,60.1 157.59,60.08 157.64,60.07 157.69,60.07 157.74,60.08 157.79,60.1 157.84,60.12 157.88,60.15 157.91,60.18 157.94,60.23 157.96,60.27 157.98,60.32 157.99,60.37 157.99,60.42 157.98,60.47 157.96,60.51 157.94,60.56 157.91,60.6 157.88,60.63 157.84,60.66 157.79,60.69 157.74,60.7 157.69,60.71 157.64,60.71 157.59,60.7 157.55,60.69 157.5,60.66 157.46,60.63 157.43,60.6 157.4,60.56 157.37,60.51 157.36,60.47 157.35,60.42 156.91,60.42 156.91,60.81 157.1,61
+1.5V_VIN on BOTTOM (solid shape): 115.11,75.1 114.79,74.78 113.47,74.78 112.65,73.96 112.65,71.79 110.17,71.79 110.17,75.1 110.46,75.4 112.31,75.4 113.33,76.41 113.33,77.58 115.11,77.58
+1.05V_VMM_UV10 on BOTTOM (solid shape): 220.06,74.6 220.06,73.17 219.93,73.04 218.23,73.04 218.23,73.91 218.49,74.17 218.56,74.17 218.62,74.23 218.62,74.85 218.69,74.92 218.72,74.92 219.28,74.92 219.33,74.92 219.39,74.94 219.72,74.94
+1.05V_VMM_VDD on BOTTOM (solid shape): outline of 382 points within 204.42,69.07 208.14,81.44
+1.05V_VMM_VDD on IN2 (solid shape): outline of 1423 points within 202.56,72.3 211.83,82.08
+1.05V_VMM_VDDTX on BOTTOM (solid shape): 210.34,78.9 210.34,77.61 209.99,77.27 209.06,77.27 208.91,77.42 208.91,78.41 208.8,78.52 208.33,78.52 208.27,78.57 208.27,79 208.35,79.09 210.15,79.09
+1.05V_VMM_VDDTX on BOTTOM (solid shape): 208.11,73.88 208.19,73.84 208.21,73.74 208.33,73.33 208.76,73.34 208.8,73.36 209.16,73 209.8,73 209.99,72.81 209.99,71.22 208.84,71.22 208.72,71.35 208.02,71.35 207.77,71.6 207.77,73.3 207.67,73.4 207.67,73.76 207.79,73.88
+1.05V_VMM_VDDTX on IN3 (solid shape): outline of 1588 points within 201.73,71.55 211.32,82.49
+1.8V_RUN_CARD on TOP (solid shape): 288.86,26.52 288.86,24.99 288.73,24.87 288.1,24.87 287.97,24.99 287.97,26.33 286.81,27.48 286.81,28.24 286.88,28.3 287.07,28.3
+1.8V_RUN_CARD on BOTTOM (solid shape): 299.31,17.97 299.31,16.22 299.01,15.91 297.8,15.91 297.55,16.17 297.55,18.07 297.8,18.33 298.96,18.33
+1.8V_RUN_CARD on IN2 (solid shape): outline of 149 points within 286.69,17.56 299.27,26.85
+1.35V_MEM on TOP (solid shape): outline of 14180 points within 84.77,6.4 203.01,62.53
+1.35V_MEN_P on TOP (solid shape): 84.58,29.63 84.58,21.06 84.39,20.87 78.99,20.87 78.55,20.42 78.55,18.96 76.32,16.74 71.24,16.74 70.99,16.99 70.99,26.71 71.82,27.53 79.81,27.53 80.32,28.05 81.07,28.05 82.72,29.69 84.52,29.69
+1.35V_MEN_P on BOTTOM (solid shape): 75.63,26.58 75.63,17.37 75.18,16.93 69.97,16.93 69.53,17.37 69.53,27.66 69.78,27.91 74.29,27.91
+1.35V_MEN_P on BOTTOM (solid shape): 71.27,9.54 69.91,9.54 69.85,9.61 68.81,9.61 68.73,9.68 68.73,9.84 68.78,9.89 69.97,9.89 70.19,10.1 71.27,10.1
+3.3V_ALW on TOP (solid shape): 265.16,66.88 265.16,66 264.95,65.8 263.34,65.8 263.18,65.96 263.18,66.91 263.43,67.16 264.87,67.16
+3.3V_ALW on TOP (solid shape): 244.54,59.92 244.54,58.97 244.41,58.84 243.22,58.84 243.1,58.71 242.41,58.71 242.34,58.78 242.34,59.85 242.6,60.11 244.35,60.11
+3.3V_ALW on TOP (solid shape): 223.01,62.21 223.57,62.21 223.63,62.15 223.63,61.39 223.37,61.12 221.68,61.12 221.49,61.32 221.49,62.2 221.74,62.46 222.76,62.46
+3.3V_ALW on TOP (solid shape): 119.82,93.38 119.82,91.33 119.81,91.32 119.81,91.02 119.66,90.87 115.67,90.87 115.19,91.35 115.19,91.35 114.93,91.6 114.93,93.13 115.38,93.57 119.63,93.57
+3.3V_ALW on TOP (solid shape): 252.23,28.52 252.23,26.91 252.04,26.72 251.28,26.72 251.01,26.99 251.01,27.73 250.57,28.18 248.65,28.18 248.4,28.43 248.4,29.32 248.46,29.38 251.37,29.38
+3.3V_ALW on TOP (solid shape): 301.37,41.38 301.37,34.52 301.18,34.33 300.61,34.33 300.61,36.55 300.8,36.74 300.8,37.19 300.67,37.31 300.67,40.36 300.16,40.87 300.16,41.63 301.11,41.63
+3.3V_ALW on TOP (solid shape): 243.46,57.32 243.58,57.32 243.77,57.12 243.77,56.3 243.84,56.24 244.28,56.24 244.47,56.04 244.47,55.35 244.28,55.16 242.5,55.16 242.12,55.54 242.12,56.43 242.38,56.68 242.38,57.28 242.43,57.33 243.45,57.33
+3.3V_ALW on TOP (solid shape): 249.93,33.44 249.93,32.11 249.92,32.02 249.93,31.92 249.93,31.03 249.81,30.9 249.21,30.9 249.09,30.78 248.46,30.78 248.4,30.84 248.4,31.41 248.03,31.78 248.03,32.11 247.77,32.36 247.77,33.69 248.16,34.07 249.3,34.07
+3.3V_ALW on TOP (solid shape): 268.22,41.42 268.6,41.42 268.74,41.28 268.99,41.02 269.33,41.11 269.35,41.11 269.52,41.27 270.31,41.27 270.62,40.97 270.62,38.65 270.49,38.53 269.22,38.53 269.22,38.78 269.8,38.78 269.8,39.29 269.22,39.29 269.22,39.86 268.97,40.11 267.51,40.11 267.51,41.57 267.54,41.59 268.05,41.59
+3.3V_ALW on TOP (solid shape): outline of 99 points within 217.79,41.5 232.87,62.2
+3.3V_ALW on BOTTOM (solid shape): 205.22,63.99 205.22,63.25 204.75,62.78 204.75,61.61 204.49,61.61 204.49,62.76 204.01,63.24 204.01,64.37 204.83,64.37
+3.3V_ALW on IN1 (solid shape): 226.52,62.28 227.03,62.28 227.22,62.08 227.22,61.45 227.03,61.26 221.74,61.26 221.57,61.44 221.57,62.15 221.76,62.34 226.46,62.34
+3.3V_ALW on IN2 (solid shape): 272.54,51.09 272.54,50.52 271.14,50.52 270.7,50.96 270.7,51.54 270.82,51.66 271.97,51.66
+3.3V_ALW on IN3 (solid shape): outline of 304 points within 236.09,74.59 253.04,95.41
+3.3V_ALW on VCC: 91.25,89.45 91.25,96.53 92.44,97.08 92.92,98.3 92.92,107.33 93.25,107.33 94.25,108.23 99.53,108.23 99.53,100.85 107.7,92.68 115.87,100.85 115.87,106.73 125.7,106.73 127.01,107.14 127.84,108.23 177.06,108.23 177.89,107.14 179.2,106.73 187.53,106.73 187.53,100.85 195.7,92.68 203.87,100.85 203.87,108.23 204.7,108.23 205.7,107.28 206.18,107.28 206.18,102.53 206.27,100.27 208.53,100.18 221.87,100.18 224.13,100.27 224.22,102.53 224.22,107.28 224.7,107.28 225.7,108.23 233.25,108.23 234.25,107.33 234.58,107.33 234.58,98.3 235.66,96.67 237.58,97.03 248.02,97.03 248.57,96.66 249.22,96.53 249.22,93.5 248.73,93 233.72,93 230.42,96.3 224.81,96.3 223.67,95.16 205.31,95.16 199.92,89.76 189.08,89.76 186.28,92.56 159.11,92.56 156.88,94.78 123.59,94.78 118.26,89.45
+3.3V_ALW on VCC: 248.31,27.22 246.43,29.11 246.43,36.77 251.08,41.4 251.08,49.04 250.61,49.5 249.76,49.5 249.38,49.12 229.46,49.12 229.04,49.55 229.04,54.86 236.2,62.01 238.49,62.02 238.5,62.01 245.53,62.01 246.44,62.92 246.44,74.61 246.93,75.09 259.42,75.09 267.76,66.74 267.76,55.44 271.45,51.76 271.45,28.6 270.07,27.22
+3.3V_ALW_DEG on TOP (solid shape): 299.78,41.02 299.15,41.02 298.61,40.49 297.77,40.49 297.7,40.56 297.7,40.89 297.8,41 298.41,41 299.02,41.6 299.78,41.6
+3.3V_ALW_PCH on TOP (solid shape): 227.82,63.1 227.82,62.53 227.69,62.4 226.68,62.4 226.55,62.53 226.55,63.1 226.68,63.23 227.69,63.23
+3.3V_ALW_PCH on TOP (solid shape): 172.34,44.17 173.03,43.47 174.37,43.47 174.37,42.58 174.18,42.39 172.59,42.39 169.86,45.12 169.86,45.63 172.34,45.63
+3.3V_ALW_PCH on TOP (solid shape): 186.01,62.31 186.01,61.77 185.86,61.62 185.86,61.61 185.8,61.54 185.8,60.73 185.59,60.53 185.59,54.97 185.85,54.72 185.85,54.71 185.99,54.57 185.99,53.83 185.84,53.68 185.26,53.68 184.9,54.07 184.9,61.85 185.07,62.03 185.07,62.03 185.44,62.39 185.93,62.39
+3.3V_ALW_PCH on TOP (solid shape): 163.83,62.88 163.84,62.86 163.93,62.7 164.09,62.61 164.11,62.61 164.37,62.35 164.37,62 164.33,61.92 164.25,61.9 164.12,61.89 163.99,61.84 163.5,61.84 163.32,62.01 162.18,62.01 161.73,61.57 161.73,60.49 161.43,60.18 160.66,60.18 160.59,60.11 159.89,60.11 159.76,60.23 159.76,60.49 159.89,60.62 159.95,60.68 159.95,61.32 160.02,61.38 160.52,61.38 161.22,62.08 161.22,62.84 161.41,63.03 163.68,63.03
+3.3V_ALW_PCH on BOTTOM (solid shape): 180.13,59.79 180.15,59.79 180.38,59.56 180.38,58.13 180.25,58 178.47,58 178.33,58.14 178.33,59.82 178.37,59.85 180.06,59.85
+3.3V_ALW_PCH on BOTTOM (solid shape): 184.43,61.95 184.69,61.84 184.96,61.95 185.73,61.95 185.93,61.76 185.93,53.7 185.8,53.57 185.1,53.57 184.85,53.82 184.85,55.85 184.01,56.69 184.01,61.51 184.01,61.52 184.01,61.75 184.21,61.95
+3.3V_ALW_PCH on IN2 (solid shape): 186.04,62.15 186.04,61.2 185.85,61.01 185.21,61.01 184.96,61.26 184.96,61.83 185.66,62.53
+3.3V_ALW_PCH on IN2 (solid shape): 227.76,63.42 227.76,62.59 227.63,62.47 226.74,62.47 226.62,62.59 226.62,63.67 226.81,63.86 227.31,63.86
+3.3V_ALW_PCH on IN2 (solid shape): 186.12,54.58 186.12,53.44 186.62,52.93 186.62,52.36 186.12,52.36 185.42,53.06 185.42,54.58 185.54,54.71 185.99,54.71
+3.3V_ALW_PCH on IN2 (solid shape): 171.32,44.93 172.21,44.93 172.34,44.81 172.34,44.17 172.46,44.04 172.46,43.6 171.83,43.6 170.88,44.55 170.88,45 171,45.12 171.13,45.12
+3.3V_ALW_PCH on IN2 (solid shape): outline of 124 points within 159.81,57.32 162.61,60.81
+3.3V_ALW_PCH_UZ8 on TOP (solid shape): 226.37,65.76 226.37,65.19 226.5,65.06 227.51,65.06 227.69,64.88 227.69,63.48 227.44,63.48 227.44,64.05 226.93,64.05 226.93,63.48 225.09,63.48 225.03,63.55 225.03,64.5 225.03,64.5 225.03,64.67 225.68,65.32 225.68,65.76 225.8,65.89 226.25,65.89
+3.3V_ALW_UE1 on TOP (solid shape): 262.46,66.84 262.46,65.79 262.48,65.77 262.48,65.71 262.54,65.71 262.75,65.51 262.75,64.4 262.68,64.33 261.69,64.33 261.26,64.76 261.26,66.48 261.68,66.9 262.41,66.9
+3.3V_ALW_UE2 on TOP (solid shape): 252.97,41.86 252.97,41.55 252.4,41.55 252.16,41.31 252.16,41.06 251.97,40.87 251.08,40.87 251.08,41.44 251.71,41.44 252.16,41.88 252.94,41.88
+3.3V_ALW_UE2 on TOP (solid shape): 265.48,43.35 267.13,43.35 267.19,43.29 267.19,41.89 267.13,41.83 266.43,41.83 265.52,42.73 265.47,42.8 265.4,42.86 265.32,42.93 264.94,42.93 264.81,43.06 264.08,43.06 264.03,43.11 264.03,43.29 264.09,43.35 265.48,43.35
+3.3V_ALW_UE2 on TOP (solid shape): 265.41,40.3 266.18,40.3 266.56,39.92 268.91,39.92 269.03,39.8 269.03,38.59 266.82,38.59 266.7,38.71 266.7,39.02 265.79,39.92 264.91,39.92 264.78,40.05 264.08,40.05 264.02,40.11 264.02,40.3 264.08,40.37 265.35,40.37
+3.3V_ALW_UE2 on TOP (solid shape): 251.94,44.31 252.11,44.25 252.28,44.27 252.63,43.92 253.74,43.92 253.87,43.8 253.87,43.67 253.74,43.54 253.17,43.54 253.11,43.48 252.34,43.48 251.16,43.48 250.97,43.68 250.97,44.2 251.08,44.31 251.64,44.31
+3.3V_ALWP on TOP (solid shape): 227.89,52.06 227.89,48.16 227.71,47.98 225.42,47.98 225.23,48.17 225.23,48.62 224.79,49.06 224.79,51.98 225.1,52.3 227.64,52.3
+3.3V_ALWP on BOTTOM (solid shape): 231.01,58.01 231.01,53.12 229.55,51.66 229.55,50.39 230.12,49.82 230.12,47.79 229.88,47.54 225.6,47.54 225.28,47.86 225.28,52.17 226.82,53.71 226.82,58.27 227.14,58.58 230.44,58.58
+3.3V_HDD on TOP (solid shape): 262.7,16.8 262.7,16.55 262.57,16.42 261.68,16.42 261.43,16.17 260.98,16.17 260.98,16.55 261.3,16.87 262.63,16.87
+3.3V_HDD on TOP (solid shape): 259.85,19.74 259.85,18.34 259.7,18.19 259.17,18.19 258.2,17.22 254.49,17.22 254.47,17.25 254.47,18.26 257.57,18.26 259.09,19.79 259.8,19.79
+3.3V_HDD on BOTTOM (solid shape): 261.88,16.6 266.81,16.6 267.97,17.75 269.3,17.75 269.43,17.63 269.43,17.37 269.3,17.25 269.05,17.25 268.79,16.99 268.79,15.79 268.98,15.6 269.49,15.6 269.62,15.47 269.62,14.64 269.87,14.39 272.14,14.39 272.14,12.87 272.02,12.75 268.84,12.75 268.59,12.49 268.59,10.71 267.76,10.71 266.01,8.97 265.01,8.97 263.56,7.52 263.56,6.18 263.37,5.99 262.85,5.99 262.77,6.07 262.77,8.62 265.72,11.57 265.92,11.67 266.02,11.87 266.24,12.09 266.61,12.38 266.38,12.78 266.38,14.37 266.46,14.59 266.38,14.81 266.38,14.9 265.74,15.53 258.89,15.53 258.7,15.72 258.7,16.1 259.33,16.74 259.33,18.01 259.08,18.26 258.82,18.26 258.63,18.45 258.63,18.64 258.76,18.77 259.71,18.77
+3.3V_LAN on TOP (solid shape): 249.26,88.3 249.26,86.97 249.49,86.74 249.49,86.27 249.35,86.13 247.43,86.13 247.25,86.31 247.25,88.21 247.52,88.48 249.08,88.48
+3.3V_LAN on TOP (solid shape): 240.54,63.41 240.66,63.28 240.66,61.32 240.34,61.32 240.34,61.89 239.84,61.89 239.84,61.89 238.88,61.89 238.88,61.32 238.63,61.32 238.63,62.65 239.01,63.03 239.01,64.04 239.96,64.04 239.97,64.05 240.54,64.05
+3.3V_LAN on IN2 (solid shape): outline of 1403 points within 248.28,69.91 279.27,92.18
+3.3V_LAN_OUT on TOP (solid shape): 252.98,87.03 252.98,86.21 252.85,86.08 252.6,86.08 252.47,86.21 252.47,86.72 252.28,86.91 251.4,86.91 251.21,87.09 249.96,87.09 249.93,87.12 249.93,88.06 249.96,88.09 251.93,88.09
+3.3V_LAN_OUT on IN2 (solid shape): outline of 244 points within 251.91,81.04 261.17,87.53
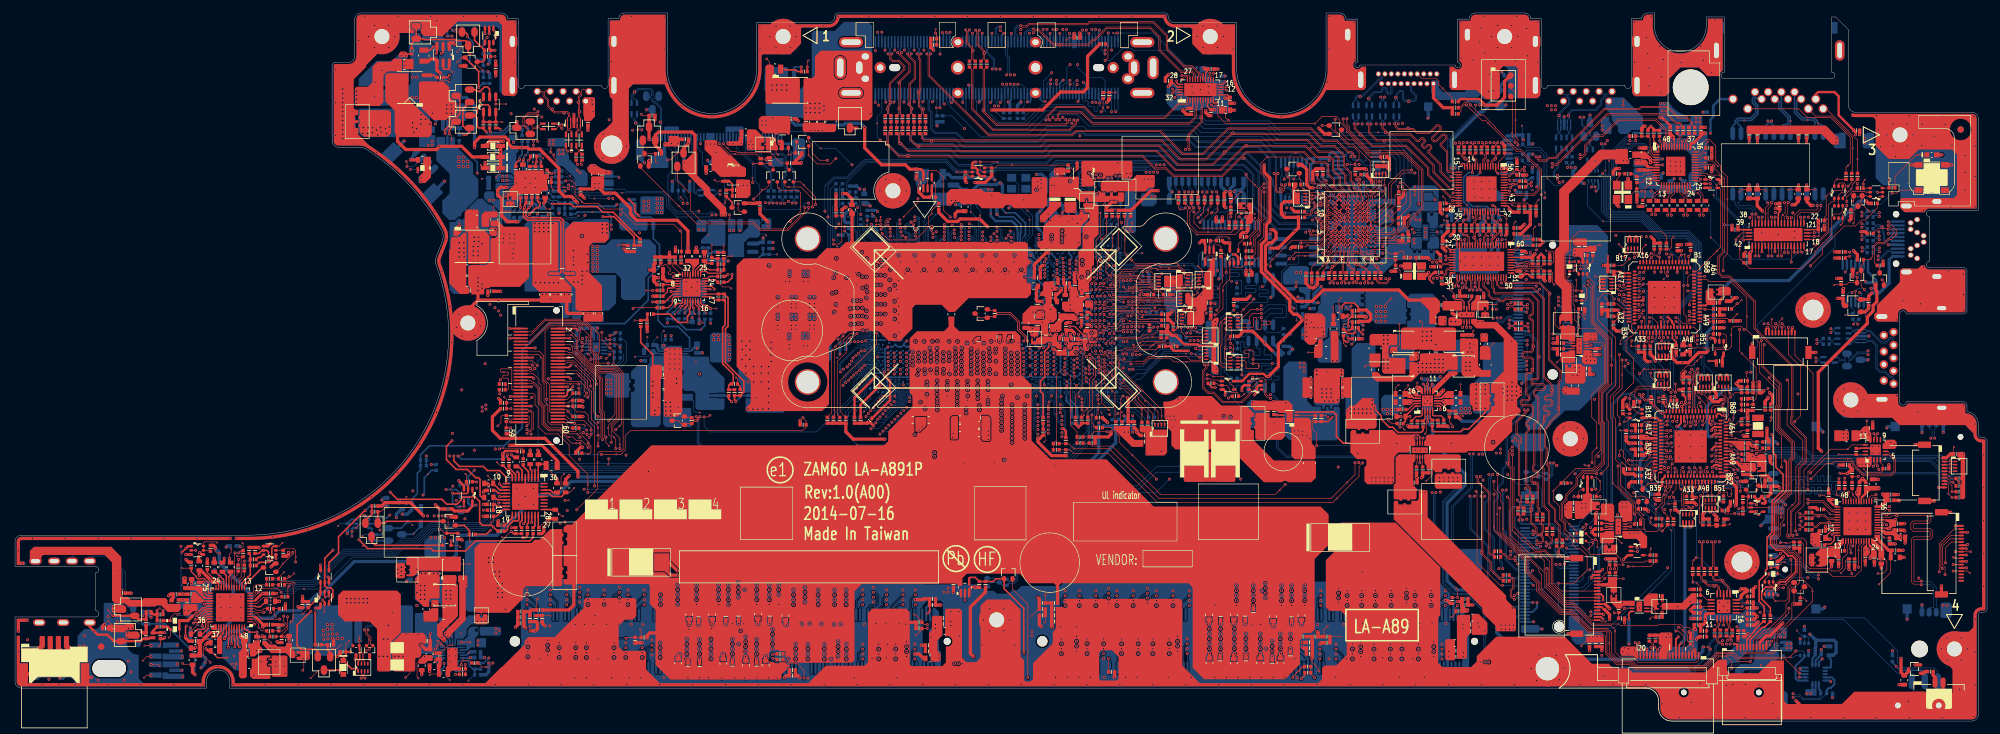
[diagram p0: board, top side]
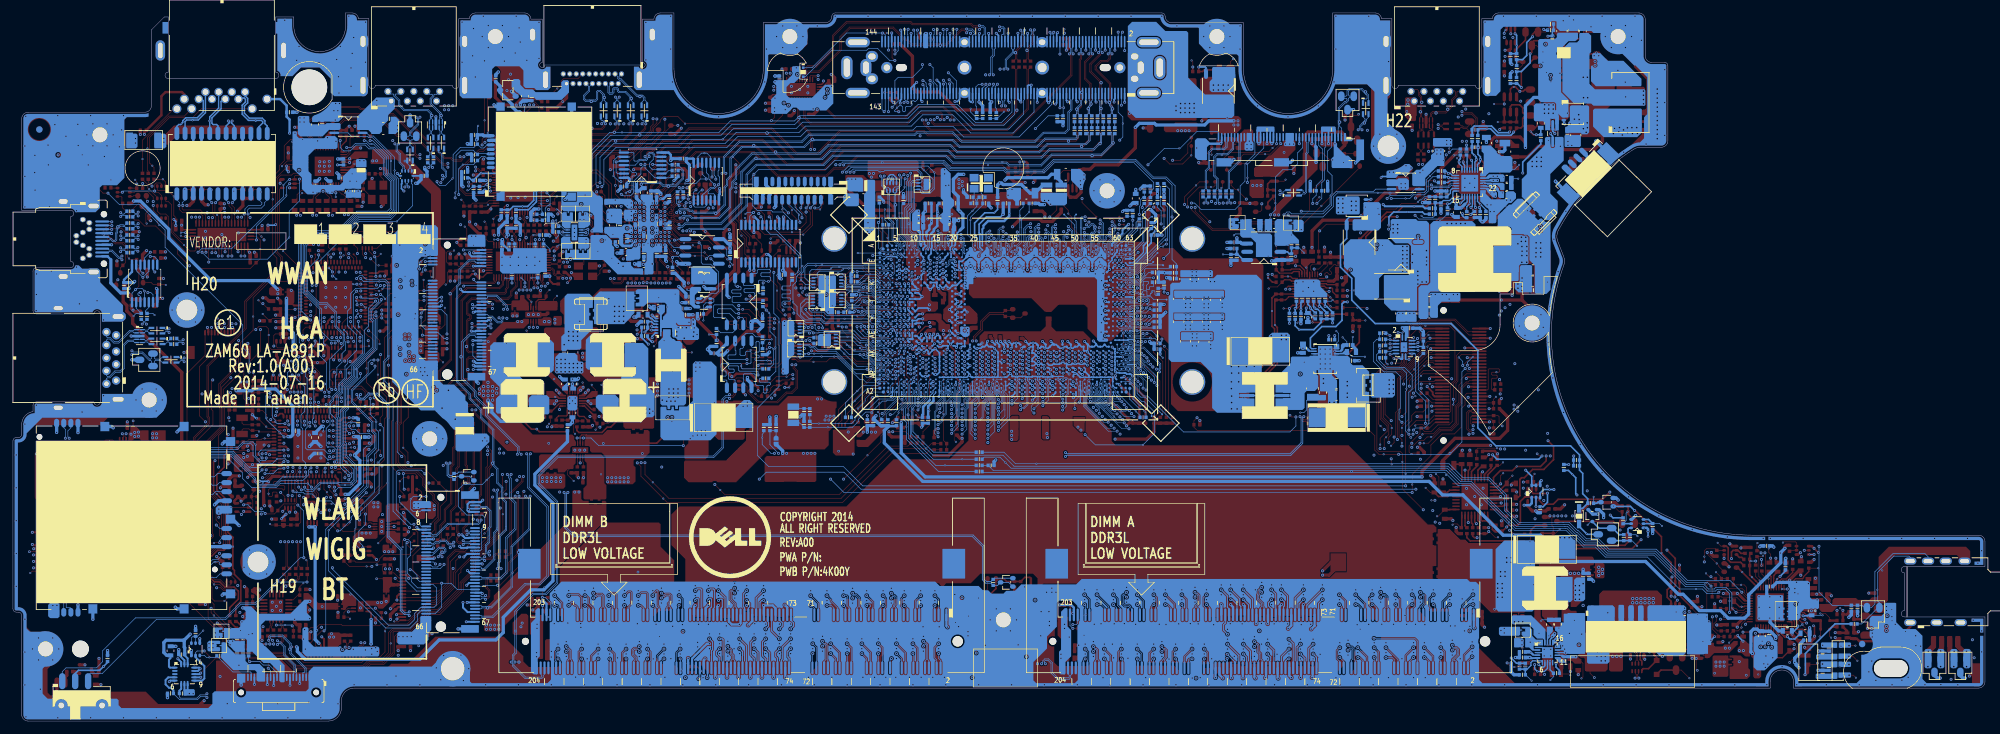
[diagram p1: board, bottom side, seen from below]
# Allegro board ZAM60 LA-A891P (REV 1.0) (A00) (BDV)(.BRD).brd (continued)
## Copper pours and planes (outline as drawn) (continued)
+3.3V_LAN_UZ2 on TOP (solid shape): 241.1,60.94 241.1,60.75 241.1,60.74 241.1,58.74 241.06,58.71 240.26,58.71 239.96,59.01 238.92,59.01 238.88,59.05 238.88,60.74 238.63,61 238.63,61.12 240.92,61.12
+3.3V_M on TOP (solid shape): 190.24,79.92 189.67,79.92 189.67,79.41 190.24,79.41 190.24,79.21 188.99,79.21 188.85,79.35 188.85,80.05 188.97,80.17 190.24,80.17
+3.3V_M on TOP (solid shape): 220.19,64.95 220.19,63.36 219.64,62.81 219.64,61.45 219.58,61.39 218.64,61.39 218.55,61.49 218.55,63.49 217.29,64.74 217.29,65.38 217.43,65.52 219.62,65.52
+3.3V_M on IN2 (solid shape): outline of 278 points within 165.68,61.68 171.93,63.63
+3.3V_M_TPM on TOP (solid shape): 191.32,79.92 191.32,77.19 191.01,76.87 190.24,76.87 190.24,77.57 189.99,77.83 189.99,78.08 190.12,78.21 190.5,78.21 190.69,78.4 190.69,78.97 190.43,79.22 190.43,80.17 191.07,80.17
+3.3V_M_TPM on BOTTOM (solid shape): 186.5,70.01 186.56,69.95 186.56,68.43 186.31,68.17 185.93,68.17 185.86,68.24 185.86,68.55 186.05,68.74 186.05,69.32 186.18,69.44 186.18,71.6 186.5,71.6
+3.3V_M_UZ8 on TOP (solid shape): 223.64,64.76 223.64,63.56 223.53,63.45 222.46,63.45 222.43,63.49 220.74,63.49 220.58,63.64 220.58,64.79 220.75,64.96 223.44,64.96
+3.3V_MMI on TOP (solid shape): 285.29,35.05 285.04,34.79 285.04,33.57 284.97,33.51 284.84,33.51 284.81,33.55 284.81,34.59 284.39,35.01 284.39,35.49 284.57,35.67 284.57,36.12 284.69,36.24 285.29,36.24
+3.3V_MMI on TOP (solid shape): 286.62,28.24 286.62,27.41 287.72,26.31 287.72,25.32 287.59,25.2 287.06,25.2 286.8,24.94 286.55,24.94 286.45,25.04 286.45,25.48 286.8,25.83 286.8,26.64 286.42,27.03 286.42,28.24 286.47,28.3 286.57,28.3
+3.3V_MMI on TOP (solid shape): 282.61,28.27 282.61,27.44 282.06,26.9 282.06,25.12 281.45,25.12 281.19,25.38 280.27,25.38 280.1,25.2 280.1,24.29 279.71,23.91 278.25,23.91 278.25,24.17 278.83,24.17 278.83,25.56 278.25,25.56 278.25,25.95 279.02,26.71 279.98,26.71 280.35,27.08 280.98,27.08 281.51,27.6 281.71,27.6 282.43,28.32 282.56,28.32
+3.3V_MMI on TOP (solid shape): 290.83,29.76 290.83,29.06 291.02,28.87 291.46,28.87 291.65,28.68 291.65,28.17 291.46,27.98 290.38,27.98 290.38,28.49 290.13,28.74 288.98,28.74 288.31,29.41 287.37,29.41 287.32,29.46 287.32,29.56 287.37,29.61 288.9,29.61 289.13,29.37 289.94,29.37 290.13,29.57 290.13,29.76 290.19,29.82 290.76,29.82
+3.3V_MMI on IN1 (solid shape): outline of 124 points within 279.38,23.22 291.65,35.78
+3.3V_RUN on TOP (solid shape): 221.24,62.52 221.24,61.32 221.07,61.16 220.09,61.16 219.92,61.32 219.92,62.52 220.05,62.64 221.11,62.64
+3.3V_RUN on TOP (solid shape): 278.05,23.92 277.62,23.92 277.61,23.91 277.5,23.91 277.2,24.21 277.2,25.67 277.42,25.89 278.05,25.89
+3.3V_RUN on TOP (solid shape): 109.92,79.35 109.92,78.71 110.04,78.59 110.04,78.14 109.92,78.02 109.03,78.02 108.9,78.14 108.9,79.54 109.73,79.54
+3.3V_RUN on TOP (solid shape): 180.46,68.98 180.46,67.64 180.46,67.64 180.46,67.34 180.21,67.09 177.67,67.09 177.61,67.16 177.61,68.81 177.67,68.87 179.38,68.87 179.58,69.06 180.38,69.06
+3.3V_RUN on TOP (solid shape): 45.54,10.69 45.54,9.68 45.3,9.44 43.69,9.44 43.49,9.63 43.49,9.94 44.07,9.94 44.07,10.45 43.49,10.45 43.49,10.77 43.56,10.83 45.4,10.83
+3.3V_RUN on TOP (solid shape): 223.63,38.02 223.63,36.11 223.43,35.92 219.71,35.92 219.39,36.23 219.39,38.01 219.64,38.26 219.89,38.26 219.9,38.27 223.38,38.27
+3.3V_RUN on TOP (solid shape): 166.62,64.87 166.62,64.75 166.62,63.73 166.49,63.6 166.24,63.6 166.15,63.69 166.15,63.86 166.1,63.91 165.44,63.91 165.35,63.99 165.35,64.93 165.48,65.06 166.43,65.06
+3.3V_RUN on TOP (solid shape): 105.44,87.83 105.44,84.4 106.55,83.29 106.55,82.65 105.79,82.65 103.12,85.32 103.12,86.63 103.32,86.83 103.74,86.83 104.84,87.92 105.34,87.92
+3.3V_RUN on TOP (solid shape): 223.9,19.15 223.9,17.75 224.22,17.44 224.6,17.44 224.72,17.31 224.72,16.99 224.47,16.74 223.39,16.74 223.33,16.8 223.33,18.07 223.14,18.26 222.82,18.26 222.69,18.39 222.69,18.58 222.82,18.71 223.2,18.71 223.33,18.83 223.33,19.15 223.39,19.21 223.83,19.21
+3.3V_RUN on TOP (solid shape): 246.81,19.09 247.32,19.09 247.32,19.54 247.38,19.6 247.57,19.6 247.57,18.69 247.65,18.62 250.25,18.62 250.3,18.57 250.3,17.91 250.23,17.83 248.57,17.83 248.35,17.6 248.35,17.47 248.27,17.4 247.55,17.4 246.75,18.21 246.74,18.21 246.55,18.4 246.55,19.54 246.62,19.6 246.81,19.6
+3.3V_RUN on TOP (solid shape): outline of 90 points within 180.83,61.25 185.42,71.49
+3.3V_RUN on BOTTOM (solid shape): 164.02,83.79 164.02,82.14 163.95,82.08 163.38,82.08 162.87,82.59 162.87,83.67 163.07,83.86 163.95,83.86
+3.3V_RUN on BOTTOM (solid shape): 278.39,4.86 278.39,4 278.32,3.92 276.76,3.92 276.64,4.04 276.64,4.79 276.79,4.94 278.32,4.94
+3.3V_RUN on BOTTOM (solid shape): 90.28,60.94 90.28,60.69 89.65,60.05 89.65,58.85 89.58,58.78 89.46,58.78 89.39,58.85 89.39,59.1 89.07,59.42 89.07,61.07 90.15,61.07
+3.3V_RUN on BOTTOM (solid shape): 116.9,77.64 116.9,76.22 116.71,76.03 115.53,76.03 115.3,76.26 115.3,76.82 115.87,76.82 115.87,77.32 115.3,77.32 115.3,77.64 115.43,77.77 116.77,77.77
+3.3V_RUN on BOTTOM (solid shape): 273.86,14.33 273.86,12.94 273.67,12.75 272.59,12.75 272.34,13 272.34,13.63 272.91,13.63 272.91,14.14 272.34,14.14 272.34,14.4 272.4,14.46 273.73,14.46
+3.3V_RUN on BOTTOM (solid shape): 216.08,78.7 216.49,78.7 216.49,78.14 216.93,78.14 216.93,78.7 217.24,78.7 217.38,78.56 217.38,76.34 217.25,76.21 216.38,76.21 216.37,76.23 216.35,76.23 216.24,76.33 216.12,76.33 216.11,76.34 216.03,76.39 215.93,76.4 215.91,76.4 215.54,76.78 215.54,77.87 215.57,77.88 215.78,78.12 215.73,78.42 216.01,78.71 216.08,78.71
+3.3V_RUN on BOTTOM (solid shape): 180.27,68.76 180.27,64.17 180.21,64.11 180.02,64.11 178.81,62.9 177.86,62.9 177.86,63.92 177.57,64.21 177.57,65.98 178.71,65.98 178.71,65.92 178.72,65.87 178.74,65.82 178.76,65.77 178.79,65.73 178.82,65.69 178.87,65.66 178.91,65.63 178.96,65.61 179.01,65.6 179.07,65.59 179.12,65.6 179.17,65.61 179.22,65.63 179.27,65.66 179.31,65.69 179.35,65.73 179.38,65.77 179.4,65.82 179.42,65.87 179.42,65.92 179.42,65.98 179.42,66.03 179.4,66.08 179.38,66.13 179.35,66.17 179.31,66.21 179.27,66.25 179.22,66.27 179.17,66.29 179.12,66.3 179.07,66.31 179.01,66.3 178.96,66.29 178.91,66.27 178.87,66.25 178.82,66.21 178.79,66.17 178.76,66.13 178.74,66.08 178.72,66.03 178.71,65.98 177.57,65.98 177.57,68.74 177.73,68.9 180.13,68.9
+3.3V_RUN on IN4 (solid shape): outline of 334 points within 272.13,3.34 282.06,15.06
+3.3V_RUN on IN4 (solid shape): outline of 791 points within 161.41,63.28 176.34,67.08
+3.3V_RUN on VCC: outline of 100 points within 43.74,9.44 286.26,107.99 ; 4 cut-outs
+3.3V_RUN_AUDIO on TOP (solid shape): 38.4,15.18 39.14,15.18 39.14,14.62 38.73,14.62 38.4,14.29 38.2,14.29 38.05,14.45 38.05,14.88 36.85,16.07 35.91,16.07 35.86,16.12 35.86,16.23 35.91,16.28 37.31,16.28
+3.3V_RUN_AUDIO on TOP (solid shape): 39.14,19.98 39.14,19.57 39.14,19.57 39.14,19.52 39.06,19.44 38.19,19.44 37.21,18.46 35.91,18.46 35.86,18.51 35.86,18.64 35.91,18.69 36.85,18.69 38.17,20.01 39.11,20.01
+3.3V_RUN_AUDIO on TOP (solid shape): 39.37,11.85 40.26,11.85 40.57,11.53 41.72,11.53 41.91,11.72 41.91,12.1 42.8,12.1 42.8,11.21 43.3,10.71 43.3,9.75 42.61,9.75 41.84,10.52 39.56,10.52 38.22,11.85 38.22,12.36 38.86,12.36
+3.3V_RUN_CARD on TOP (solid shape): 286.22,28.24 286.22,27 286.65,26.57 286.65,25.91 286.19,25.45 285.62,25.45 285.62,26.86 286.01,27.25 286.01,28.24 286.06,28.3 286.17,28.3
+3.3V_RUN_CARD on BOTTOM (solid shape): 273.4,32.96 273.4,32.12 273.19,31.9 272.65,31.9 272.49,32.07 271.03,32.07 270.86,32.23 270.86,33.11 271.05,33.3 273.06,33.3
+3.3V_RUN_CARD on IN2 (solid shape): 286.7,26.64 286.7,26.14 285.37,24.8 284.73,24.8 284.73,25.82 285.75,26.83 286.51,26.83
+3.3V_RUN_CARD on IN2 (solid shape): 273.67,32.66 273.67,31.44 273.44,31.21 271.96,31.21 271.83,31.34 271.83,32.41 272.46,33.05 273.29,33.05
+3.3V_RUN_UN3 on TOP (solid shape): 253.91,19.58 253.91,18.11 253.76,17.96 253.76,17.27 253.71,17.22 253.48,17.22 252.89,17.8 251.8,17.8 251.7,17.91 251.7,19.02 252.41,19.74 253.76,19.74
+3.3V_RUN_UZ9 on TOP (solid shape): 223.44,41 223.44,38.63 223.26,38.46 222.56,38.46 222.56,39.03 220.53,39.03 220.53,38.46 219.52,38.46 219,38.97 218.23,38.97 218.11,39.1 218.11,39.54 217.79,39.86 217.79,41.19 217.85,41.26 223.19,41.26
+3.3V_RUN_VDDA on BOTTOM (solid shape): outline of 102 points within 208.29,73.25 213.34,76.81
+3.3V_RUN_VDDA on IN1 (solid shape): outline of 1185 points within 202.76,72.67 211.19,82.35
+3.3V_RUN_VDDIO on BOTTOM (solid shape): 213.34,80.69 213.34,79.86 212.55,79.86 212.52,79.9 210.95,79.9 210.75,79.96 210.56,79.9 210.39,79.9 209.72,79.23 209,79.23 208.92,79.31 208.92,80.39 209.31,80.78 213.25,80.78
+3.3V_RUN_VDDIO on IN4 (solid shape): outline of 1483 points within 198.96,73.1 211.45,81.05
+3.3V_RUN_VMM on TOP (solid shape): 198.18,83.22 198.18,82.65 197.86,82.33 197.86,81.82 197.98,81.71 198.48,81.71 198.55,81.64 198.55,80.06 198.42,79.93 197.6,79.93 197.47,80.06 197.15,80.06 197.15,80.56 197.36,80.77 197.36,82.33 197.36,82.34 197.36,83.23 197.42,83.29 198.12,83.29
+3.3V_RUN_VMM on TOP (solid shape): 212.65,87.17 212.65,85.14 212.52,85.01 212.28,85.01 211.81,85.48 210.22,85.48 210.14,85.56 210.14,86.11 210.18,86.15 211.38,86.15 211.39,86.15 211.54,86.11 211.69,86.15 211.7,86.15 212.03,86.15 212.15,86.27 212.15,86.78 211.96,86.97 211.71,86.97 211.71,87.48 212.34,87.48
+3.3V_RUN_VMM on BOTTOM (solid shape): outline of 99 points within 213.6,75.54 220.01,82.85
+3.3V_RUN_VMM on IN2 (solid shape): 199.69,76.22 199.78,76.16 199.76,76.06 199.73,76.02 199.71,75.98 199.66,75.93 199.59,75.93 199.14,75.47 199.78,75.4 199.83,75.45 199.9,75.45 200.11,75.43 200.3,75.52 200.34,75.53 200.37,75.52 200.64,75.42 200.94,75.55 200.97,75.54 201.33,75.46 201.57,75.74 201.61,75.81 201.7,75.82 202.04,75.87 202.21,76.18 202.21,76.22 203.29,76.22 203.42,76.09 203.44,75.98 203.01,75.7 203.09,75.31 203.12,75.24 203.09,75.17 202.99,74.96 203.03,74.73 203.04,74.63 202.95,74.57 202.82,74.57 202.52,74.73 202.23,74.57 197.69,74.57 197.33,74.93 197.33,75.96 197.6,76.22
+3.3V_SUS on TOP (solid shape): 187.26,94.91 187.26,94.08 187.13,93.95 186.12,93.95 186.05,94.02 186.05,94.97 186.12,95.03 187.13,95.03
+3.3V_SUS on TOP (solid shape): 246.11,26.72 246.62,26.72 246.62,27.29 247.49,27.29 247.64,27.14 247.64,26.19 247.45,26 245.6,26 245.47,26.12 245.47,27.1 245.67,27.29 246.11,27.29
+3.3V_SUS on TOP (solid shape): 256.12,13.51 256.12,11.16 255.86,10.91 255.61,10.91 255.34,10.64 255.34,9.77 255.15,9.58 254.06,9.58 254,9.64 254,10.72 254.16,10.89 254.18,11.12 254.18,11.16 254.21,11.18 254.22,11.19 254.46,11.4 254.35,11.69 254.24,11.79 254.09,11.83 254.03,11.86 254,11.93 254,13.39 254.33,13.72 255.92,13.72
+3.3V_SUS on BOTTOM (solid shape): outline of 318 points within 177.97,93.89 187.59,101.26
+3.3V_SUS on IN2 (solid shape): 187.51,94.91 187.51,94.46 188.15,93.83 188.15,93.13 187.45,93.13 186.5,94.08 186.5,94.97 186.69,95.16 187.26,95.16
+3.3V_SUS on IN2 (solid shape): 255.92,14.78 255.92,13.42 256.05,13.28 256.05,12.55 255.9,12.4 254.33,12.4 254.14,12.6 254.14,14.63 254.39,14.88 255.81,14.88
+3.3V_SUS on IN2 (solid shape): 250.68,27.99 250.68,27.41 250,26.73 250,25.69 249.99,25.7 245.54,25.7 245.45,25.79 245.45,26.64 246.29,27.48 247.7,27.48 247.7,27.48 248.79,27.48 249.55,28.24 250.43,28.24
+3.3V_SUS_UL3 on TOP (solid shape): 247.13,29.32 247.13,27.73 246.87,27.48 245.09,27.48 244.9,27.67 244.9,29.13 245.47,29.13 245.73,29.38 247.06,29.38
+3.3V_TP on TOP (solid shape): 247.57,19.85 246.57,19.85 246.57,20.55 246.31,20.81 245.73,20.81 245.73,21.32 245.98,21.32 246.17,21.51 246.17,22.21 246.24,22.27 247.57,22.27
+3.3V_TSP on BOTTOM (solid shape): 99.06,90.87 99.06,89.72 98.99,89.66 97.91,89.66 97.79,89.79 97.79,90.04 97.91,90.17 98.61,90.17 98.74,90.3 98.74,90.87 98.8,90.93 98.99,90.93
+3.3V_VMM_UV10 on BOTTOM (solid shape): 219.92,78.51 219.92,76.63 219.48,76.19 218.76,76.19 218.76,76.19 218.65,76.19 218.57,76.26 218.57,76.9 218.2,77.27 218.2,78.59 218.29,78.68 218.69,78.68 218.7,78.67 218.7,78.13 218.71,78.12 219.16,78.12 219.17,78.12 219.17,78.2 219.17,78.2 219.17,78.7 219.73,78.7
+3.3V_WLAN on TOP (solid shape): 245.5,13.11 245.5,12.17 242.95,12.17 242.82,12.29 242.82,13.12 243.01,13.31 245.3,13.31
+3.3V_WLAN on TOP (solid shape): 243.22,37.92 243.22,35.33 243.32,35.23 243.5,35.23 243.7,35.03 243.7,34.14 243.89,33.95 244.71,33.95 244.9,33.76 244.9,33.38 244.33,33.38 244.33,32.87 244.9,32.87 244.9,32.62 243.7,32.62 242.36,31.29 241.16,31.29 241.04,31.41 241.04,34.02 242.05,34.02 242.24,34.21 242.24,35.03 242.33,35.12 242.71,35.12 242.77,35.19 242.77,37.94 242.85,38.02 243.12,38.02
+3.3V_WLAN on BOTTOM (solid shape): 242.95,33.88 242.95,32.93 242.82,32.8 241.93,32.8 241.79,32.94 240.27,32.94 240.14,33.07 240.14,33.83 240.33,34.02 242.81,34.02
+3.3V_WLAN on BOTTOM (solid shape): 241.81,16.1 241.81,15.09 243.08,13.82 245.11,13.82 245.36,13.56 245.36,12.1 245.11,11.85 241.23,11.85 240.54,12.55 240.54,13.63 240.09,14.07 240.09,16.1 240.22,16.23 241.68,16.23
+3.3V_WLAN on IN2 (solid shape): 242.94,14.45 243.25,14.14 245.09,14.14 245.35,13.89 245.35,12.81 245.22,12.68 241.58,12.68 240.9,13.36 240.9,15.6 241.11,15.6 241.11,15.6 242.94,15.6
+3.3V_WLAN on IN2 (solid shape): 243.19,33.7 243.19,32.62 241.93,31.36 241.93,29.88 242,29.82 242,28.42 241.93,28.36 240.54,28.36 240.03,28.87 240.03,33.06 240.86,33.89 243,33.89
+3.3V_WLAN_UL3 on TOP (solid shape): 247.13,33.32 247.13,30.84 247.06,30.78 246.36,30.78 246.17,30.97 245.67,30.97 245.47,31.16 244.9,31.16 244.9,31.85 245.09,32.05 245.09,33.57 245.16,33.64 246.81,33.64
+3.3V_WWAN on TOP (solid shape): 241.11,55.22 242,55.22 242.38,54.84 242.69,54.84 242.69,52.49 242.38,52.17 239.77,52.17 239.52,52.43 239.52,55.11 239.63,55.23 239.95,55.23 239.95,54.66 240.46,54.66 240.46,55.23 241.09,55.23
+3.3V_WWAN on TOP (solid shape): 244.4,73.41 244.4,72.76 244.19,72.55 242.57,72.55 242.38,72.36 242.38,71.6 242.5,71.48 242.5,70.78 242.44,70.71 242.12,70.71 242.06,70.78 242.06,71.54 241.81,71.79 240.85,71.79 240.73,71.92 240.73,73 240.92,73.19 242.78,73.19 243.11,73.52 244.28,73.52
+3.3V_WWAN on BOTTOM (solid shape): outline of 911 points within 233.5,45.06 246.15,76.69
+3.3V_WWAN on IN2 (solid shape): outline of 525 points within 238.88,53.19 243.08,73.13
+3.3V_WWAN_UZ2 on TOP (solid shape): 241.1,57.26 241.1,55.56 240.93,55.39 239.07,55.39 238.85,55.61 238.85,56.9 239.02,57.08 239.95,57.08 240.21,57.33 241.03,57.33
+3V5V_PWR_SRC on TOP (solid shape): 222.69,60.62 222.69,57.5 222.69,57.5 222.69,57.44 222.5,57.25 219.2,57.25 219.01,57.44 214.31,57.44 214.18,57.57 214.18,60.55 214.5,60.87 222.44,60.87
+3V5V_PWR_SRC on BOTTOM (solid shape): 219.52,65.63 219.52,59.93 220.01,59.44 220.01,57.38 219.88,57.24 219.28,57.24 219.09,57.44 217.17,57.44 216.91,57.7 216.91,58.9 215.13,60.69 215.13,61.92 215.68,61.92 215.69,61.93 215.69,63.89 215.15,63.89 215.12,63.91 215.12,65.56 215.64,66.08 219.07,66.08
+5V_ALW on TOP (solid shape): 290.78,43.17 290.78,42.39 290.47,42.09 290.47,42.08 288.65,42.08 288.59,42.15 288.59,42.78 289.33,43.52 290.43,43.52
+5V_ALW on TOP (solid shape): 91.04,82.4 90.85,82.21 89.41,82.21 89.03,82.59 89.03,84.06 89.21,84.25 91.04,84.25
+5V_ALW on TOP (solid shape): 286.93,40.87 286.93,39.68 286.85,39.58 286.81,39.46 286.59,39.23 284.99,39.23 284.57,39.65 284.57,40.66 284.64,40.74 286.32,40.74 286.5,40.92 286.88,40.92
+5V_ALW on TOP (solid shape): 207.25,44.43 209.28,44.43 209.28,45 212.91,45 213.61,44.3 216.2,44.3 216.33,44.17 216.36,44.1 216.33,44.03 216.23,43.73 216.39,43.47 216.39,42.59 216.33,42.53 215.76,42.53 215.57,42.34 215.57,41.76 215.31,41.51 213.79,41.51 213.15,40.88 213.15,36.94 212.84,36.62 208.97,36.62 208.53,37.06 208.53,39.26 208.84,39.56 208.84,40.28 208.63,40.49 207.38,40.49 206.36,41.51 206.36,44.75 206.61,45 207.25,45
+5V_ALW on BOTTOM (solid shape): 260.73,93.38 260.73,90.8 260.33,90.41 256.9,90.41 255.89,91.42 254.3,91.42 254.11,91.61 254.11,92.33 254.24,92.46 256.29,92.46 256.47,92.28 258.63,92.28 258.94,92.59 258.94,93.44 259.08,93.57 260.54,93.57
+5V_ALW on BOTTOM (solid shape): 90.85,83.74 92.38,83.74 92.5,83.61 92.5,82.85 92.38,82.72 90.79,82.72 90.68,82.61 90.68,82.27 90.55,82.14 89.21,82.14 89.02,82.33 89.02,83.6 89.34,83.92 90.67,83.92
+5V_ALW on IN2 (solid shape): 213.36,38.26 213.36,36.68 212.98,36.3 207.77,36.3 207.77,38.33 213.29,38.33
+5V_ALW on IN2 (solid shape): 86.61,42.84 89.28,40.17 89.28,38.46 88.07,38.46 84.58,41.95 84.58,43.03 84.71,43.15 86.61,43.15
+5V_ALW on IN2 (solid shape): 79.44,48.23 79.88,48.23 79.88,46.2 77.34,46.2 76.64,46.9 72.26,46.9 71.94,47.22 71.94,48.33 76.28,48.33 76.28,48.28 76.29,48.23 76.3,48.17 76.33,48.13 76.36,48.08 76.39,48.04 76.43,48.01 76.48,47.98 76.53,47.96 76.58,47.95 76.63,47.95 76.69,47.95 76.74,47.96 76.79,47.98 76.84,48.01 76.88,48.04 76.91,48.08 76.94,48.13 76.97,48.17 76.98,48.23 76.99,48.28 76.99,48.33 76.98,48.38 76.97,48.44 76.94,48.48 76.91,48.53 76.88,48.57 76.84,48.6 76.79,48.63 76.74,48.65 76.69,48.66 76.63,48.66 76.58,48.66 76.53,48.65 76.48,48.63 76.43,48.6 76.39,48.57 76.36,48.53 76.33,48.48 76.3,48.44 76.29,48.38 76.28,48.33 71.94,48.33 71.94,48.93 72.45,49.44 78.23,49.44
+5V_ALW on VCC: outline of 1485 points within 1.27,1.27 303.48,108.23 ; 1 cut-out
+5V_ALWP on TOP (solid shape): 209.99,49.82 209.99,47.84 210.42,47.41 210.42,45.51 210.11,45.19 205.85,45.19 205.66,45.38 205.66,48.11 206.35,48.81 207.07,48.81 208.21,49.95 209.86,49.95
+5V_ALWP on BOTTOM (solid shape): 210.25,58.33 210.25,53.76 210.75,53.25 210.75,47.28 210.44,46.96 205.93,46.96 205.6,47.3 205.6,50.72 206.56,51.68 206.56,57.63 207.39,58.46 210.12,58.46
+5V_HDD on BOTTOM (solid shape): 272.53,9.7 270.69,7.86 267.36,7.86 267.09,7.59 267.09,6.32 266.88,6.11 265.85,6.11 265.78,6.17 265.78,7.99 266.62,8.83 268.33,8.83 268.8,9.3 268.8,10.23 268.91,10.33 270.37,10.33 271.64,11.6 271.64,11.92 271.89,12.17 272.53,12.17
+5V_RUN on TOP (solid shape): 64.28,87.16 64.28,84.07 63.41,83.2 62.52,83.2 62.47,83.25 62.47,84.21 63.08,84.82 63.08,87.08 63.27,87.27 64.17,87.27
+5V_RUN on TOP (solid shape): 42.1,9.95 42.1,6.98 41.95,6.83 39.85,6.83 39.64,7.04 39.64,8.59 39.63,8.6 39.13,8.6 39.1,8.64 39.1,8.83 39.12,8.85 39.64,8.85 39.66,8.87 39.66,9.38 39.63,9.41 39.15,9.41 39.1,9.46 39.1,9.61 39.14,9.65 39.62,9.65 39.66,9.69 39.66,10.09 39.71,10.14 41.91,10.14
+5V_RUN on TOP (solid shape): 218.31,35.53 218.31,31.53 230.44,19.41 230.44,18.77 231.96,17.25 231.96,14.07 231.77,13.88 228.98,13.88 228.79,14.07 228.79,14.71 226.76,16.74 226.76,17.5 213.04,31.22 213.04,33.88 213.23,34.07 213.74,34.07 213.74,33.5 215.77,33.5 215.77,34.07 216.66,34.07 216.91,34.33 216.91,35.53 217.1,35.72 218.12,35.72
+5V_RUN on BOTTOM (solid shape): 222.88,86.27 222.88,85.42 222.65,85.19 221.71,85.19 221.68,85.23 221.68,86.16 221.87,86.35 222.81,86.35
+5V_RUN on BOTTOM (solid shape): 105.84,57.64 105.65,57.45 104.92,57.45 104.57,57.09 103.32,57.09 103.27,57.14 103.27,57.25 103.32,57.3 104.21,57.3 104.95,58.03 104.95,58.67 105.84,58.67
+5V_RUN on BOTTOM (solid shape): 65.43,85.71 65.43,85.48 64.45,84.51 64.27,84.51 62.93,83.16 62.48,83.16 62.29,83.35 62.29,84.11 62.76,84.58 63.21,84.58 64.68,86.05 65.08,86.05
+5V_RUN on BOTTOM (solid shape): 274.7,12.17 274.7,10.96 274.51,10.77 272.99,10.77 272.99,10.77 272.85,10.77 272.72,10.91 272.72,11.41 273.29,11.41 273.29,11.92 272.72,11.92 272.72,12.3 272.84,12.43 274.44,12.43
+5V_RUN on IN2 (solid shape): 223.33,85.13 223.33,84.49 223.26,84.43 222.63,84.43 221.49,85.57 221.49,85.89 221.61,86.02 222.44,86.02
+5V_RUN on IN2 (solid shape): 218.18,36.8 218.44,36.55 218.44,36.17 218.18,35.92 218.18,35.28 218.06,35.15 217.17,35.15 217.04,35.28 217.04,36.17 217.74,36.87 218.18,36.87
+5V_RUN on IN2 (solid shape): outline of 3171 points within 39.81,3.47 274.7,29.81
+5V_RUN on IN4 (solid shape): 64.62,84.29 64.62,83.25 64.17,82.8 62.71,82.8 62.43,83.08 62.43,84.31 62.54,84.43 64.48,84.43
+5V_RUN on IN4 (solid shape): 42.22,10.32 42.22,9.94 41.84,9.56 41.84,8.99 41.72,8.86 40.84,8.86 40.71,8.99 40.71,9.83 41.59,10.71 41.84,10.71
+5V_RUN_AUDIO on TOP (solid shape): 39.48,9.82 38.91,9.82 38.91,8.43 39.48,8.43 39.48,6.63 39.37,6.51 36.75,6.51 36.3,6.96 36.3,7.92 36.57,8.19 36.57,9.58 36.62,9.63 37.26,9.63 37.77,10.14 39.48,10.14
+5V_RUN_PVDD on TOP (solid shape): 32.76,14.89 32.76,13.15 32.76,12.99 32.6,12.83 32.6,12.6 32.55,12.55 32.19,12.55 32.12,12.62 32.12,12.88 32.56,13.32 32.56,14.89 32.61,14.94 32.71,14.94
+5V_RUN_PVDD on TOP (solid shape): 34.77,14.9 34.77,13.7 35.28,13.19 35.87,13.19 36.07,12.99 36.07,12.33 35.84,12.1 35.84,11 36.15,10.68 36.15,9.99 35.82,9.66 35.82,6.86 35.56,6.6 34.87,6.6 34.59,6.88 34.59,10.66 35.05,11.12 35.05,11.85 34.94,11.96 34.94,12.57 34.57,12.94 34.57,14.93 34.62,14.98 34.69,14.98
+5V_RUN_UZ9 on TOP (solid shape): 216.41,41.18 216.41,40.23 216.09,39.92 216.09,36.49 216.6,35.98 216.6,34.45 216.41,34.26 213.23,34.26 213.04,34.45 213.04,36.5 213.34,36.8 213.34,40.75 213.85,41.26 216.33,41.26
+5V_USB_CHG_PWR on TOP (solid shape): 286.61,45.47 286.61,44.82 286.88,44.55 286.88,43.1 286.81,43.03 286.62,43.03 285.99,43.67 285.23,43.67 284.84,43.29 283.83,43.29 283.83,44.94 285.1,44.94 285.73,45.57 286.51,45.57
+5V_USB_CHG_PWR on IN2 (solid shape): outline of 138 points within 278.32,42.77 289.37,54.97
+GND_CHASSIS on TOP (solid shape): 281.81,90.14 281.81,89.32 281.62,89.13 280.79,89.13 279.16,90.76 267.78,90.76 267.59,90.95 267.59,91.89 267.78,92.08 279.87,92.08
+GND_CHASSIS on BOTTOM (solid shape): 282.89,88.56 281.3,88.56 281.05,88.81 281.05,90.59 281.3,90.84 282.89,90.84
+V1.05S_APLLOPI on TOP (solid shape): 159.06,63.28 159.06,62.27 158.94,62.14 157.92,62.14 157.79,62.27 157.79,63.16 158.11,63.47 158.87,63.47
+V1.05S_APLLOPI on BOTTOM (solid shape): 172.97,83.6 172.97,81.7 173.23,81.45 173.23,75.67 173.03,75.48 171.7,75.48 171.51,75.67 171.51,83.57 171.64,83.69 172.88,83.69
+V1.05S_APLLOPI on IN2 (solid shape): outline of 1510 points within 157.73,62.2 173.03,76.49
+V1.05SP_B+ on BOTTOM (solid shape): 208.53,66.52 208.53,66.05 208.01,66.05 207.96,66 207.96,65.49 208.52,65.49 208.52,65.29 208.51,65.28 207.96,65.28 207.96,64.69 208.51,64.69 208.53,64.67 208.53,64.11 207.26,64.11 206.68,64.69 204.01,64.69 203.76,64.43 203.76,63.04 204.26,62.53 204.26,61.64 202.31,61.64 201.89,61.23 200.09,61.23 200.05,61.26 200.05,62.19 200.12,62.27 200.81,62.27 201,62.46 201,63.1 201.41,63.51 201.41,64.2 201.75,64.54 201.75,66.53 201.99,66.78 208.28,66.78
+VCC_CORE on TOP (solid shape): outline of 4258 points within 111.5,47.92 157.02,74.3
+VCC_CORE on BOTTOM (solid shape): outline of 181 points within 111.76,47.67 126.17,69.01
+VCC_CORE on BOTTOM (solid shape): outline of 1365 points within 135.52,58.65 158.01,71.67
+VCC_CORE on IN1 (solid shape): outline of 479 points within 111.82,47.85 125.22,64.8
+VCC_CORE on IN1 (solid shape): outline of 1191 points within 134.24,58.58 157.16,73.06
+VCC_CORE on IN2 (solid shape): outline of 5341 points within 111.19,47.54 157.19,72.69
+VCC_CORE on IN3 (solid shape): outline of 280 points within 136.01,58.84 146.24,71.22
+VCC_CORE on IN3 (solid shape): outline of 900 points within 111.5,47.66 125.66,71.28
+VCC_CORE on VCC: 112.93,47.67 112.37,48.23 109.85,50.75 109.85,69.97 111.99,72.11 117.98,72.11 120.2,69.89 124.65,69.89 126.87,72.11 157.16,72.11 157.16,71.92 157.15,71.91 157.15,58.85 135.28,58.85 134.65,59.48 128.72,59.48 124.66,55.42 121.87,55.42 121.45,55.33 120.86,55.02 120.84,55.01 120.53,54.76 119.68,53.91 119.68,48.03 119.32,47.67
+VCC_PWR_SRC on TOP (solid shape): 100.01,54.93 100.01,53.07 99.74,52.81 99.74,47.46 99.44,47.15 98.36,47.15 98.15,47.36 98.15,52.69 98.16,52.69 98.16,54.71 98.56,55.12 99.82,55.12
+VCC_PWR_SRC on BOTTOM (solid shape): 100.63,53.64 99.81,52.81 99.81,45.89 99.36,45.45 95.55,45.45 95.17,45.83 95.17,50.91 95.74,50.91 95.74,52.94 95.17,52.94 95.17,54.02 96.18,55.03 97.7,55.03 98.09,55.42 98.09,56.12 98.47,56.5 100.63,56.5
+VDDA_AVDD1 on TOP (solid shape): 29.01,20.67 29.01,19.66 29.57,19.1 30.59,19.1 30.65,19.03 30.65,18.92 30.6,18.87 29.23,18.87 27.86,20.24 26.06,20.24 25.96,20.34 25.96,20.8 26.03,20.87 28.81,20.87
+VDDA_PVDD on TOP (solid shape): 31.57,14.9 31.57,14.04 31.04,13.51 30.39,13.51 28.92,12.04 28.92,9.86 28.88,9.82 26.98,9.82 26.98,10.45 28.06,10.45 28.25,10.64 28.25,11.85 28.06,12.04 28.06,12.61 28.13,12.67 28.78,12.67 29.12,13.02 29.12,13.06 29.55,13.49 29.63,13.49 30.06,13.92 31.14,13.92 31.37,14.14 31.37,14.9 31.42,14.96 31.52,14.96
GND on TOP (solid shape): 85.96,66.09 85.96,64.69 81.14,64.69 81.14,66.02 81.33,66.21 85.84,66.21
GND on TOP (solid shape): 200.52,53 200.52,50.15 200.39,50.02 198.99,50.02 198.99,53.13 200.39,53.13
GND on TOP (solid shape): 206.42,50.02 205.03,50.02 204.9,50.15 204.9,53 205.03,53.13 206.42,53.13
GND on TOP (solid shape): 17.19,17.63 17.19,16.97 16.98,16.75 15.15,16.75 14.93,16.97 14.93,17.78 15.09,17.93 16.89,17.93
GND on TOP (solid shape): 19.24,13.52 19.24,12.9 19.07,12.74 17.32,12.74 17.08,12.98 17.08,13.64 17.27,13.83 18.93,13.83
GND on TOP (solid shape): 61.6,102.29 61.6,100.94 61.47,100.8 60.2,100.8 59.96,101.04 59.96,102.2 60.16,102.39 61.5,102.39
GND on TOP (solid shape): 77.21,80.24 77.21,79.6 77.09,79.48 76.01,79.48 75.88,79.6 75.88,80.24 76.01,80.37 77.09,80.37
GND on TOP (solid shape): 90.85,63.1 90.85,61.89 90.73,61.77 87.87,61.77 87.87,63.1 88.03,63.27 90.69,63.27
GND on TOP (solid shape): 222.53,12.45 222.53,9.51 222.4,9.38 221.25,9.38 221.01,9.62 221.01,12.46 221.22,12.67 222.3,12.67
GND on TOP (solid shape): 227.54,15.22 227.54,13.56 227.31,13.33 225.22,13.33 225.1,13.44 225.1,16.29 225.41,16.6 226.16,16.6
GND on TOP (solid shape): 242.88,74.52 242.88,73.57 242.82,73.51 240.92,73.51 240.79,73.63 240.79,74.52 240.92,74.65 242.76,74.65
GND on TOP (solid shape): 125.37,92.33 126.81,92.33 126.89,92.25 126.89,91.35 126.6,91.06 122,91.06 121.71,91.36 121.71,92.4 121.86,92.55 125.15,92.55
GND on TOP (solid shape): 140.84,45.69 139.89,44.74 139.25,44.74 139.13,44.87 139.13,47.03 140.84,47.03
GND on TOP (solid shape): 227.64,59.79 227.64,58.78 227.52,58.65 226.57,58.65 226.44,58.78 226.44,59.85 226.57,59.98 227.45,59.98
GND on TOP (solid shape): 283.4,44.74 283.4,43.54 283.14,43.28 282.71,43.28 282.7,43.29 281.23,43.29 281.16,43.35 281.16,44.93 283.21,44.93
GND on TOP (solid shape): 145.73,47.09 145.73,43.73 145.54,43.54 144.71,43.54 144.59,43.66 144.59,46.9 144.84,47.15 145.67,47.15
GND on TOP (solid shape): 240.12,51.57 241.61,51.57 241.81,51.38 241.81,50.57 241.69,50.46 239.46,50.46 239.01,50.9 239.01,51.35 239.52,51.85 239.84,51.85
GND on TOP (solid shape): 240.66,31.41 240.54,31.28 239.84,31.28 239.39,31.72 239.39,33.38 240.03,34.01 240.66,34.01
GND on TOP (solid shape): 279.14,29.12 279.02,28.99 279.02,26.96 277.94,26.96 277.43,27.47 277.43,28.99 277.56,29.12 278.38,29.12 278.57,29.31 278.57,29.69 279.14,29.69
GND on TOP (solid shape): 112.52,89.09 112.39,88.96 110.17,88.96 109.98,89.15 109.98,89.53 110.11,89.66 111.7,89.66 111.82,89.77 111.82,90.28 111.89,90.36 112.52,90.36
GND on TOP (solid shape): 118.81,89.7 118.81,88.37 118.68,88.24 118.26,88.24 118.14,88.36 118.14,88.97 117.85,89.26 117.85,89.76 117.98,89.89 118.61,89.89
GND on TOP (solid shape): 150.75,46.84 150.75,43.5 150.56,43.31 149.6,43.31 149.35,43.56 149.35,47.15 149.41,47.22 150.37,47.22
GND on TOP (solid shape): 250.84,11.15 250.84,9.73 250.72,9.61 250.58,9.61 250.37,9.83 250.37,9.84 250.11,10.1 248.36,10.1 248.05,10.4 248.05,11.16 248.42,11.53 250.45,11.53
GND on TOP (solid shape): 103.12,57.51 103.12,47.78 102.41,47.07 100.47,47.07 100.26,47.27 100.26,57.44 100.58,57.76 102.87,57.76
GND on TOP (solid shape): 65.59,22.96 65.59,19.09 65.47,18.96 64.32,18.96 64.01,18.64 64.01,17.69 63.12,17.69 61.85,18.96 61.85,22.14 62.8,23.09 65.47,23.09
GND on TOP (solid shape): 68.39,11.15 68.39,8.48 68.51,8.36 68.96,8.36 68.96,7.78 67.5,7.78 67.24,7.53 67.24,6.83 66.61,6.83 66.55,6.9 66.55,8.29 66.8,8.55 66.8,11.21 66.93,11.34 68.2,11.34
GND on TOP (solid shape): 102.74,90.23 102.74,89.09 102.49,88.84 100.33,88.84 100.2,88.96 100.2,89.41 100.33,89.53 100.9,89.53 101.03,89.66 101.03,90.42 101.09,90.49 102.49,90.49
GND on TOP (solid shape): 193.55,49.44 194.18,49.44 194.31,49.57 196.72,49.57 197.42,48.87 197.42,46.27 196.53,46.27 196.53,47.54 196.4,47.66 195.26,47.66 194.88,48.04 191.58,48.04 191.01,48.62 191.01,49.44 191.13,49.57 193.42,49.57
GND on TOP (solid shape): 186.06,41.52 186.06,41.1 186.17,41 188.27,41 188.59,40.68 188.59,37.12 188.47,36.99 180.78,36.99 180.59,37.19 180.59,41.44 180.78,41.63 185.95,41.63
GND on TOP (solid shape): 162.43,85.32 163.05,85.32 163.09,85.28 163.09,84.8 163.04,84.75 162.28,84.75 161.91,84.37 160.64,84.37 160.53,84.49 160.53,85.45 160.65,85.57 162.18,85.57
GND on TOP (solid shape): 37.84,12.36 37.84,11.98 37.84,11.98 37.84,11.66 38.22,11.28 38.22,10.71 38.03,10.52 37.59,10.52 37.08,10.01 36.38,10.01 36.32,10.07 36.32,11.07 35.99,11.4 35.99,11.92 36.05,11.98 36.58,11.98 37.14,12.55 37.65,12.55
GND on TOP (solid shape): 199.89,63.05 201.86,63.05 202.49,62.42 202.49,59.42 202.36,59.29 201.39,59.29 201.39,59.29 201.32,59.29 201.23,59.2 201.23,58.73 200.71,58.21 200.01,58.21 199.99,58.23 199.84,58.23 199.39,58.69 199.39,58.7 199.25,58.84 199.25,62.88 199.43,63.05 199.88,63.05
GND on TOP (solid shape): 162.49,57.7 162.49,57.12 162.56,57.06 162.56,56.55 162.49,56.49 161.03,56.49 160.91,56.62 160.91,57.06 160.72,57.25 160.27,57.25 160.14,57.38 160.14,57.63 160.27,57.76 160.65,57.76 161.01,57.4 161.01,57.39 161.02,57.39 161.1,57.31 161.86,57.31 161.99,57.44 161.99,57.7 162.11,57.82 162.37,57.82
GND on TOP (solid shape): 222.93,56.43 222.93,54.46 222.81,54.34 221.41,54.34 220.84,53.77 217.09,53.77 215.82,52.5 210.36,52.5 209.72,53.13 209.72,53.96 210.61,53.96 211.18,53.39 215.25,53.39 215.5,53.64 215.5,55.29 215.63,55.42 216.77,55.42 217.09,55.73 217.09,56.62 217.34,56.88 222.49,56.88
GND on TOP (solid shape): 89.64,86.14 90.76,85.43 92.05,85.14 92.19,85.01 92.19,84.63 92.05,84.49 89.09,84.49 88.45,85.13 88.45,85.64 88.96,86.14
GND on TOP (solid shape): 75.58,76.45 79.06,76.45 79.44,76.07 79.44,68.57 78.01,67.14 73.48,67.14 73.26,66.93 72.72,66.93 72.53,66.74 72.53,66.08 72.4,65.95 70.6,65.95 70.5,66.05 70.5,66.81 70.04,67.27 70.04,70.23 70.34,70.54 72.84,70.54 73.51,71.2 73.51,74.5 73.73,74.73 74.28,74.73 74.58,75.03 74.58,76.38 74.44,76.52 73.59,76.52 73.47,76.64 73.47,77.29 73.59,77.42 74.61,77.42
GND on TOP (solid shape): 163.19,67.35 163.45,67.09 164.14,67.09 164.14,66.62 164.34,66.43 164.34,65.89 164.42,65.8 164.42,65.76 164.46,65.76 164.53,65.7 165.2,65.7 165.26,65.76 165.45,65.95 166.05,65.95 166.05,65.38 165.54,65.38 165.03,64.87 165.03,63.22 164.4,63.22 164.4,62.74 164.16,62.74 163.61,63.28 162.24,63.28 161.8,63.73 161.8,64.74 161.92,64.87 162.68,64.87 162.94,65.13 162.94,66.4 162.75,66.59 162.75,67.98 163.19,67.98
GND on TOP (solid shape): 160.53,67.41 160.72,67.22 161.03,67.22 161.22,67.03 161.22,66.78 160.97,66.52 160.4,66.52 160.21,66.33 160.21,64.43 160.97,63.66 160.97,62.14 160.46,61.63 159.95,61.63 159.64,61.32 159.64,60.05 159.76,59.92 160.08,59.92 160.14,59.85 160.14,59.6 160.08,59.54 159.95,59.54 159.83,59.66 158.62,59.66 158.43,59.85 158.43,60.24 158.56,60.36 158.56,61.12 158.3,61.38 155.89,61.38 155.7,61.57 155.7,62.97 155.94,63.21 157.67,63.21 157.67,62.21 157.87,62.01 158.99,62.01 159.19,62.21 159.19,63.34 158.93,63.6 158.06,63.6 157.67,63.21 155.94,63.21 156.97,64.24 158.87,64.24 159.26,64.62 159.26,65.44 159,65.7 158.49,65.7 158.37,65.82 158.37,66.14 158.87,66.65 158.87,67.73 159.13,67.98 160.53,67.98
GND on TOP (solid shape): 295.11,70.46 295.37,70.02 295.85,69.84 299.91,69.84 299.91,69.85 301.15,69.85 301.32,69.77 301.4,69.6 301.4,63.45 301.32,63.28 301.15,63.2 299.91,63.2 299.91,63.21 296.36,63.21 296.36,63.2 292.46,63.2 291.62,63.69 291,62.95 291,61.76 287.78,61.76 287.33,62.2 287.33,62.9 287.72,63.28 287.72,64.3 291.27,67.86 291.27,69.63 291.59,69.95 294.07,69.95 294.58,70.46
GND on TOP (solid shape): 233.25,109.24 233.75,109.05 233.99,108.57 234.02,108.34 235.59,108.34 235.59,98.3 235.62,98.09 235.71,97.9 235.71,96.75 235.26,96.3 232.32,96.3 232.21,96.42 232.21,100.95 231.9,101.26 229.99,101.26 229.46,100.73 229.46,100.61 229.37,100.37 229.46,100.14 229.46,96.48 229.12,96.14 227.31,96.14 225.87,97.57 222.06,97.57 221.68,97.95 221.68,101.19 222.35,101.19 223.41,100.99 223.21,102.05 223.21,108.29 224.94,108.29 224.96,108.54 225.19,109.04 225.7,109.24
GND on TOP (solid shape): 253.09,107.5 257.35,103.24 261.61,107.5 261.61,108.62 263.89,108.62 263.89,100.56 263.5,100.23 263.4,99.73 261.56,99.73 260.22,101.07 257.36,101.07 255.65,99.35 255.65,97.19 255.08,96.62 250.38,96.62 250.01,96.99 250.01,108.34 251.58,108.34 251.61,108.57 251.85,109.05 252.34,109.24 253.09,109.24
GND on TOP (solid shape): outline of 159 points within 283.79,78.69 303.15,94.03
GND on TOP (solid shape): outline of 229 points within 157.99,72.81 165.8,79.1
GND on TOP (solid shape): 100.54,100.85 107.7,93.69 114.86,100.85 114.86,107.74 125.7,107.74 126.59,108.11 127.03,109.17 127.2,109.24 177.7,109.24 177.87,109.17 178.31,108.11 179.2,107.74 188.54,107.74 188.54,100.85 195.7,93.69 202.86,100.85 202.86,109.24 204.7,109.24 205.21,109.04 205.44,108.54 205.46,108.29 207.19,108.29 207.19,102.05 206.99,100.99 208.05,101.19 208.79,101.19 208.79,97.95 208.4,97.57 202.62,97.57 194.02,93.38 188.04,100.85 188.04,102.95 187.89,103.1 183.51,103.1 181.92,104.69 181.92,106.98 181.67,107.24 179.2,107.24 178.05,107.67 177.46,108.74 127.44,108.74 126.85,107.67 125.7,107.24 121.61,107.24 121.47,107.1 121.47,104.75 121.11,104.39 121.11,104.39 119.82,103.1 115.57,103.1 115.36,102.89 115.36,100.85 108.91,93.28 100.42,98.46 95.5,98.46 94.87,97.83 94.87,88.49 94.8,88.43 89.85,88.43 89.85,90.14 92.33,92.62 92.33,96.11 91.91,96.53 91.91,108.34 93.48,108.34 93.51,108.57 93.75,109.05 94.24,109.24 100.54,109.24
GND on TOP (solid shape): outline of 120 points within 33.97,27.99 77.49,109.25
GND on TOP (solid shape): outline of 4305 points within 0.25,0.25 304.5,51.66
GND on BOTTOM (solid shape): 234.48,75.03 234.48,73.38 231.75,73.38 231.75,75.03 231.94,75.22 234.29,75.22
GND on BOTTOM (solid shape): 253.3,81.89 253.3,80.94 250.95,80.94 250.95,81.95 251.14,82.14 253.04,82.14
GND on BOTTOM (solid shape): 287.21,88.56 285.75,88.56 285.49,88.81 285.49,90.65 285.68,90.84 287.21,90.84
GND on BOTTOM (solid shape): 63.5,21.82 63.5,18.64 63.37,18.52 62.1,18.52 61.78,18.83 61.78,22.2 63.12,22.2
GND on BOTTOM (solid shape): 26.03,8.04 26.03,7.66 25.97,7.59 23.87,7.59 23.87,8.1 25.97,8.1
GND on BOTTOM (solid shape): 72.75,11.41 71.48,11.41 71.29,11.6 71.29,12.62 71.48,12.81 72.75,12.81
GND on BOTTOM (solid shape): 90.98,63.1 90.98,61.77 87.87,61.77 87.87,63.1 88.06,63.29 90.79,63.29
GND on BOTTOM (solid shape): 102.61,91.82 102.61,91.25 102.49,91.12 100.39,91.12 100.33,91.19 100.33,91.82 100.45,91.95 102.49,91.95
GND on BOTTOM (solid shape): 110.7,59.52 110.7,55.8 110.35,55.45 107.62,55.45 107.4,55.66 107.4,59.69 107.77,60.06 110.17,60.06
GND on BOTTOM (solid shape): 176.45,81.19 176.45,80.12 175.92,79.59 174.25,79.59 174.02,79.82 174.02,81.46 174.16,81.59 176.04,81.59
GND on BOTTOM (solid shape): 193.51,47.95 193.51,45.58 193.25,45.32 190.45,45.32 190.36,45.4 190.36,49.11 190.9,49.65 191.82,49.65
GND on BOTTOM (solid shape): 214.68,50.08 214.68,48.56 213.41,47.29 211.5,47.29 211.12,47.67 211.12,49.89 211.69,50.46 214.3,50.46
GND on BOTTOM (solid shape): 219.06,50.02 219.06,48.24 218.87,48.05 217.73,48.05 217.53,48.24 217.53,50.08 217.73,50.27 218.8,50.27
GND on BOTTOM (solid shape): 35.18,19.34 35.18,15.79 34.99,15.6 31.18,15.6 31.18,19.34 31.3,19.47 35.05,19.47
GND on BOTTOM (solid shape): 66.61,28.49 66.61,25.56 66.16,25.12 63.31,25.12 63.31,27.91 63.38,27.99 63.49,27.99 64.18,28.68 66.42,28.68
GND on BOTTOM (solid shape): 213.04,78.97 213.04,77.25 212.79,77 211.64,77 211.45,76.81 210.63,76.81 210.63,79.03 210.82,79.22 212.79,79.22
GND on BOTTOM (solid shape): 225.03,49.96 225.03,47.54 224.9,47.42 222.05,47.42 221.87,47.6 221.87,50.02 222.25,50.4 224.58,50.4
GND on BOTTOM (solid shape): 85.3,90.06 85.3,89.04 85.05,88.8 82.41,88.8 82.31,88.9 82.31,89.58 82.32,89.59 82.32,89.92 82.55,90.16 85.2,90.16
GND on BOTTOM (solid shape): 106.75,68.07 106.75,65.63 106.66,65.54 101.68,65.54 101.63,65.6 101.63,66.1 102.69,67.17 102.69,67.97 103.01,68.29 106.54,68.29
GND on BOTTOM (solid shape): 112.58,91.82 112.58,91.19 112.52,91.12 109.85,91.12 109.79,91.19 109.79,91.82 109.92,91.95 112.46,91.95
GND on BOTTOM (solid shape): 246.38,92.75 246.69,92.43 246.69,90.78 245.62,90.78 245.04,91.35 245.04,92.94 245.55,93.45 246.38,93.45
GND on BOTTOM (solid shape): 25.97,11.02 25.97,10.64 25.91,10.58 24.67,10.58 24.65,10.56 23.81,10.56 23.8,10.58 23.8,11.07 23.82,11.09 25.91,11.09
GND on BOTTOM (solid shape): 111.31,77.51 111.31,75.73 111.19,75.6 110.3,75.6 110.17,75.73 110.17,77.57 110.23,77.63 111.19,77.63
GND on BOTTOM (solid shape): 112.46,75.86 112.19,75.6 111.83,75.6 111.63,75.8 111.63,77.63 112.46,77.63
GND on BOTTOM (solid shape): 124.32,69.7 124.32,68.68 124.28,68.64 119.42,68.64 119.31,68.76 119.31,69.58 119.45,69.72 124.31,69.72
GND on BOTTOM (solid shape): 64.98,90.51 64.98,88.88 64.86,88.77 62.61,88.77 62.45,88.93 62.45,90.47 62.6,90.61 64.87,90.61
GND on BOTTOM (solid shape): 125.28,66.52 125.28,65.52 125.2,65.43 117.75,65.43 117.58,65.6 117.58,66.48 117.67,66.57 118.21,66.57 118.21,66.58 125.23,66.58
GND on BOTTOM (solid shape): 271.65,12.42 271.65,12.23 271.4,11.98 271.4,11.72 270.38,10.71 268.92,10.71 268.92,12.36 270.38,12.36 270.57,12.55 271.52,12.55
GND on BOTTOM (solid shape): 85.84,66.04 85.84,62.64 85.54,62.34 84.68,62.34 84.54,62.48 84.54,64.24 83.93,64.85 81.29,64.85 81.06,65.07 81.06,66.14 81.15,66.23 85.65,66.23
GND on BOTTOM (solid shape): 151.19,82.33 151.19,80.94 150.94,80.68 150.24,80.68 149.86,80.3 149.86,79.73 149.29,79.73 149.29,80.43 148.97,80.75 148.97,82.46 151.06,82.46
GND on BOTTOM (solid shape): 124.27,60.04 124.27,58.98 124.14,58.85 119.46,58.85 119.32,58.99 119.32,60.04 119.43,60.14 124.16,60.14
GND on BOTTOM (solid shape): 125.28,62.09 125.2,62 117.69,62 117.56,62.13 117.56,62.94 117.64,63.02 118.22,63.02 118.23,63.03 125.28,63.03
GND on BOTTOM (solid shape): 227.45,73.06 227.45,72.24 227.71,71.98 228.66,71.98 228.91,72.24 228.91,73.13 229.49,73.13 229.49,69.57 229.11,69.19 223.39,69.19 223.14,69.44 222.25,69.44 222.25,72.94 222.44,73.13 227.39,73.13
GND on BOTTOM (solid shape): 65.48,11.73 65.48,11.26 65.66,11.09 66.42,11.09 66.48,11.02 66.48,10.96 66.42,10.9 64.87,10.9 64.73,11.04 64.73,11.42 65.15,11.84 65.38,11.84
GND on BOTTOM (solid shape): 236.35,44.39 236.35,41.96 236.09,41.7 232.57,41.7 231.7,42.56 231.64,42.64 231.56,42.7 231.12,43.15 231.12,44.02 231.56,44.47 236.27,44.47
GND on BOTTOM (solid shape): 103.04,53.7 102.79,53.45 102.79,51.1 102.66,50.97 101.77,50.97 101.52,50.72 101.52,49 102.16,48.37 104.44,48.37 104.5,48.31 104.5,45.45 100.57,45.45 100.12,45.89 100.12,52.69 100.89,53.45 100.89,58.02 103.04,58.02
GND on BOTTOM (solid shape): 122.11,89.78 122.11,87.2 121.66,86.74 120.29,86.74 120.27,86.77 120.27,88.71 119.89,89.09 118.04,89.09 117.92,89.22 117.92,89.34 118.04,89.47 119.8,89.47 120.45,90.13 121.76,90.13
GND on BOTTOM (solid shape): 141.22,83.6 139.76,82.14 139.42,82.14 139.3,82.97 139,83.74 139,84.56 139.82,85.38 141.22,85.38
GND on BOTTOM (solid shape): 220.91,56.3 220.91,53.89 220.79,53.77 216.78,53.77 216.6,53.95 216.6,55.41 216.79,55.6 217.29,55.6 217.55,55.85 217.55,56.56 217.91,56.92 220.29,56.92
GND on BOTTOM (solid shape): 100.64,89.41 100.64,87.34 100.95,87.03 100.95,85.62 100.84,85.51 97.89,85.51 97.79,85.61 97.79,86.83 98.4,87.44 98.75,87.44 100.12,88.81 100.12,89.27 100.33,89.47 100.58,89.47
GND on BOTTOM (solid shape): 71.9,70.26 71.9,68.05 72.05,67.89 72.55,67.89 72.64,67.8 72.64,66.84 72.08,66.28 70.01,66.28 69.96,66.33 69.96,70.33 70.13,70.5 71.66,70.5
GND on BOTTOM (solid shape): 165.8,78.46 165.8,75.98 165.61,75.79 165.16,75.79 164.68,75.31 164.68,73.53 164.53,73.38 164.34,73.38 164.21,73.51 164.21,74.08 164.4,74.27 164.4,75.73 164.59,75.92 164.59,78.97 164.72,79.1 165.16,79.1
GND on BOTTOM (solid shape): 77.56,75.45 77.56,71.18 77.35,70.98 76.46,70.98 76.39,71.04 76.39,73.2 76.04,73.55 76.03,73.55 75.92,73.67 74.46,73.67 74.24,73.89 74.24,75.45 74.74,75.95 77.06,75.95
GND on BOTTOM (solid shape): 161.38,85.31 161.38,80.83 161.03,80.49 161.03,78.69 161.55,78.17 161.55,77.34 161.05,76.83 161.05,75.74 161.03,75.73 160.27,75.73 160.08,75.92 160.08,76.62 159.83,76.87 159.83,79.16 159.32,79.67 159.32,80.56 159.83,81.06 159.83,84.7 160.64,85.51 161.17,85.51
GND on BOTTOM (solid shape): 188.65,10.85 188.7,10.77 188.7,10.16 188.19,9.65 188.19,9.28 188.18,9.26 188.1,9.23 188.03,9.26 188.01,9.28 188.01,10.48 188.37,10.84 188.4,10.84 188.48,10.84 188.56,10.86
GND on BOTTOM (solid shape): 199.9,62.13 199.9,61.19 200.04,61.06 201.97,61.06 202.32,61.41 204.75,61.41 204.75,59.48 204.52,59.48 204.52,60.78 202.87,60.78 202.87,59.48 202.68,59.29 202.38,59.29 202.02,58.93 198.94,58.93 198.72,59.14 198.72,60.61 199.18,61.07 199.18,61.96 199.5,62.28 199.76,62.28
GND on BOTTOM (solid shape): 255.66,95.55 255.66,95.54 256.77,94.37 258.22,93.67 258.49,93.39 258.49,92.69 254.43,92.69 254.01,93.11 254.01,95.58 254.17,95.74 255.47,95.74
GND on BOTTOM (solid shape): 190.48,10.88 190.53,10.79 190.53,10.32 189.99,9.78 189.99,9.28 189.98,9.26 189.9,9.23 189.83,9.26 189.81,9.28 189.81,10.5 190.16,10.84 190.18,10.84 190.28,10.84 190.38,10.88
GND on BOTTOM (solid shape): 78.01,81.99 78.01,80.37 76.97,79.32 76.87,79.32 76.71,79.16 76.71,77.11 76.56,76.97 75.7,76.97 75.5,77.16 75.5,78.2 73.6,80.1 73.19,80.1 72.48,80.82 72.48,81.58 72.82,81.92 73.83,81.92 74.09,81.66 74.09,80.89 74.29,80.69 76.29,80.69 77.15,81.55 77.15,82.04 77.18,82.07 77.94,82.07
GND on BOTTOM (solid shape): 89.65,86.13 90.88,85.38 92.29,85.14 92.31,85.14 92.49,84.96 92.49,84.07 92.43,84.01 91.06,84.01 90.57,84.49 89.41,84.49 88.48,85.41 88.48,85.67 88.96,86.14 89.64,86.14
GND on BOTTOM (solid shape): 107.11,10.84 107.18,10.93 107.29,10.9 107.43,10.81 107.59,10.78 107.61,10.79 108.49,9.91 108.49,9.28 108.48,9.26 108.4,9.23 108.33,9.26 108.31,9.28 108.31,9.34 107.87,9.78 107.87,9.79 107.6,9.97 107.29,9.85 107.18,9.82 107.11,9.92
GND on BOTTOM (solid shape): 97.26,11.09 97.32,11 97.32,10.18 97.26,10.09 97.15,10.1 96.86,10.18 96.62,10.01 96.54,10.01 95.92,9.39 95.92,9.3 95.9,9.28 95.88,9.26 95.8,9.23 95.73,9.26 95.7,9.28 95.68,9.3 95.68,9.85 96.83,11.01 96.86,11 97.02,11.01 97.15,11.08
GND on BOTTOM (solid shape): 52.14,17.69 52.14,11.91 51.45,11.23 51.43,11.23 50.3,10.1 50.19,10.1 49.84,10.36 49.5,10.1 46.67,10.1 46.29,10.48 46.29,16.42 46.74,16.81 46.21,17.07 46.17,17.11 46.17,17.56 46.53,17.92 51.91,17.92
GND on BOTTOM (solid shape): 178.69,11.68 178.75,11.59 178.75,10.8 178.69,10.71 178.59,10.72 178.19,10.74 178.03,10.37 178.03,10.34 177.42,9.74 177.42,9.3 177.4,9.28 177.38,9.26 177.3,9.23 177.23,9.26 177.2,9.28 177.18,9.3 177.18,10.51 178.28,11.61 178.31,11.61 178.46,11.61 178.59,11.67
GND on BOTTOM (solid shape): 87.88,11.02 87.94,11.12 88.05,11.1 88.2,11.01 88.37,11 88.39,11.01 89.32,10.08 89.32,9.3 89.3,9.28 89.28,9.26 89.2,9.23 89.13,9.26 89.1,9.29 89.07,9.31 88.65,9.74 88.65,9.76 88.47,10.14 88.05,10.08 87.94,10.06 87.88,10.16
GND on BOTTOM (solid shape): 295.11,70.46 295.37,70.02 295.85,69.84 299.76,69.84 299.76,69.85 301.15,69.85 301.32,69.77 301.4,69.6 301.4,63.45 301.32,63.28 301.15,63.2 299.76,63.2 299.76,63.21 296.98,63.21 296.98,63.2 292.46,63.2 291.62,63.69 291,62.95 291,61.76 287.78,61.76 287.33,62.2 287.33,62.9 287.75,63.32 287.75,64.33 291.27,67.86 291.27,69.63 291.59,69.95 294.07,69.95 294.58,70.46
GND on BOTTOM (solid shape): 260.03,14.26 260.03,10.58 259.43,9.98 248.33,9.98 248.16,10.16 248.16,11.35 248.3,11.49 252.33,11.49 252.4,11.46 252.43,11.39 252.68,11.01 253.11,11.14 253.15,11.16 253.19,11.15 253.28,11.09 253.38,11.07 253.45,11.05 253.48,10.99 254.05,10.75 253.98,11.36 253.97,11.37 253.92,11.41 254,11.49 254.03,11.49 258.23,11.49 259.08,12.34 259.08,14.33 259.27,14.52 259.78,14.52
GND on BOTTOM (solid shape): 233.25,109.24 233.75,109.05 233.99,108.57 234.02,108.34 235.59,108.34 235.59,98.3 235.62,98.09 235.71,97.9 235.71,96.75 235.26,96.3 230.88,96.3 230.69,96.49 230.69,100.81 230.25,101.26 226.5,101.26 225.87,100.62 225.87,98.21 225.55,97.89 224.19,97.89 223.87,97.57 222.06,97.57 221.68,97.95 221.68,101.19 222.35,101.19 223.41,100.99 223.21,102.05 223.21,108.29 224.94,108.29 224.96,108.54 225.19,109.04 225.7,109.24
GND on BOTTOM (solid shape): 199.5,9.53 199.5,9.41 199.45,9.33 199.35,9.32 199.15,9.36 198.98,9.26 198.9,9.23 198.83,9.26 198.65,9.36 198.46,9.32 198.36,9.33 198.31,9.41 198.31,9.54 198.13,9.72 198.12,9.73 197.67,9.97 197.45,9.5 197.44,9.41 197.37,9.36 197.26,9.33 197.18,9.26 197.1,9.23 197.03,9.26 197.01,9.28 197.01,10.97 196.85,11.13 196.85,11.53 196.89,11.61 196.98,11.62 197.13,11.6 197.28,11.64 197.29,11.65 197.38,11.65
GND on BOTTOM (solid shape): 253.09,107.5 257.35,103.24 261.61,107.5 261.61,108.62 263.89,108.62 263.89,100.56 263.5,100.23 263.4,99.73 261.56,99.73 260.22,101.07 257.36,101.07 255.65,99.35 255.65,97.19 255.08,96.62 250.38,96.62 250.01,96.99 250.01,108.34 251.58,108.34 251.61,108.57 251.85,109.05 252.34,109.24 253.09,109.24
GND on BOTTOM (solid shape): outline of 206 points within 283.79,78.69 303.15,94.03
GND on BOTTOM (solid shape): outline of 198 points within 32.05,7.84 35.76,13.25
GND on BOTTOM (solid shape): 67.37,109.24 75.15,109.24 75.65,109.05 75.89,108.57 75.92,108.34 77.49,108.34 77.49,98.34 77.47,98.31 77.47,97 77.15,96.68 75.56,96.68 74.86,97.38 74.86,106.91 74.42,107.35 67.05,107.35 67.05,108.2 66.29,108.2 66.22,108.12 66.22,107.23 65.69,106.7 60.81,106.7 60.5,106.4 59.24,106.4 54.21,101.37 54,101.37 52.21,99.58 52.21,93.84 52.69,93.36 52.69,90.12 53.32,89.49 54.03,89.37 54.69,89.06 61.46,83.42 66.59,76.25 66.92,75.12 66.74,73.95 65.82,71.57 65.82,71.56 65.74,71.13 65.81,70.7 65.94,70.35 66.06,70.01 66.12,69.84 67.25,65.45 67.74,60.93 67.76,60.37 58.68,37.51 36,27.99 33.97,27.99 33.97,28.49 36,28.49 59.89,39.59 66.81,65.01 66.8,65.06 66.19,67.82 65.34,70.52 65.23,71.14 65.35,71.76 65.35,71.76 66.27,74.13 66.41,75.08 66.15,76.01 61.09,83.07 54.41,88.63 53.83,88.9 53.2,88.99 50,88.99 49.47,89.21 49.25,89.73 49.25,101.35 49.33,101.52 49.5,101.6 51.5,101.6 52.39,101.96 52.75,102.85 52.75,108.5 52.97,109.03 53.5,109.25 67.37,109.25
GND on BOTTOM (solid shape): 100.54,100.85 107.7,93.69 114.86,100.85 114.86,107.74 125.7,107.74 126.59,108.11 127.03,109.17 127.2,109.24 177.7,109.24 177.87,109.17 178.31,108.11 179.2,107.74 188.54,107.74 188.54,100.85 195.7,93.69 202.86,100.85 202.86,109.24 204.7,109.24 205.21,109.04 205.44,108.54 205.46,108.29 207.19,108.29 207.19,102.05 206.99,100.99 208.05,101.19 208.79,101.19 208.79,97.95 208.4,97.57 202.62,97.57 194.02,93.38 188.04,100.85 188.04,102.95 187.89,103.1 183.58,103.1 181.99,104.69 181.99,106.92 181.67,107.24 179.2,107.24 178.05,107.67 177.46,108.74 127.44,108.74 126.85,107.67 125.7,107.24 121.6,107.24 121.47,107.11 121.47,104.75 119.82,103.1 115.62,103.1 115.36,102.84 115.36,100.85 108.91,93.28 100.42,98.46 95.5,98.46 94.36,97.32 94.36,89.7 94.74,89.32 94.74,88.43 90.04,88.43 89.85,88.62 89.85,90.14 92.33,92.62 92.33,96.56 91.91,96.98 91.91,108.34 93.48,108.34 93.51,108.57 93.75,109.05 94.24,109.24 100.54,109.24
GND on BOTTOM (solid shape): outline of 384 points within 135.77,70.7 157.59,73.36
GND on BOTTOM (solid shape): outline of 16656 points within 0.25,0.25 304.5,51.6
GND on IN1 (solid shape): 52.14,15.52 52.14,12.06 51.86,11.79 48,11.79 48,11.78 47.43,11.78 47.11,12.09 47.11,15.49 47.55,15.93 51.73,15.93
GND on IN1 (solid shape): 103.12,57.51 103.12,47.66 102.5,47.04 100.48,47.04 100.26,47.26 100.26,57.44 100.58,57.76 102.87,57.76
GND on IN1 (solid shape): 295.11,70.46 295.37,70.02 295.85,69.84 299.29,69.84 299.29,69.85 301.15,69.85 301.32,69.77 301.4,69.6 301.4,63.45 301.32,63.28 301.15,63.2 299.29,63.2 299.29,63.21 297.04,63.21 297.04,63.2 292.46,63.2 291.62,63.69 291,62.95 291,61.76 287.78,61.76 287.33,62.2 287.33,62.9 287.72,63.28 287.72,64.3 291.27,67.86 291.27,69.63 291.59,69.95 294.07,69.95 294.58,70.46
GND on IN1 (solid shape): 233.25,109.24 233.75,109.05 233.99,108.57 234.02,108.34 235.59,108.34 235.59,98.3 235.62,98.09 235.71,97.9 235.71,96.75 235.26,96.3 230.88,96.3 230.69,96.49 230.69,100.81 230.25,101.26 226.5,101.26 225.87,100.62 225.87,98.21 225.23,97.57 222.06,97.57 221.68,97.95 221.68,101.19 222.35,101.19 223.41,100.99 223.21,102.05 223.21,108.29 224.94,108.29 224.96,108.54 225.19,109.04 225.7,109.24
GND on IN1 (solid shape): 253.09,107.5 257.35,103.24 261.61,107.5 261.61,108.62 263.89,108.62 263.89,100.56 263.5,100.23 263.4,99.73 261.56,99.73 260.22,101.07 257.36,101.07 255.65,99.35 255.65,97.19 255.08,96.62 250.38,96.62 250.01,96.99 250.01,108.34 251.58,108.34 251.61,108.57 251.85,109.05 252.34,109.24 253.09,109.24
GND on IN1 (solid shape): outline of 205 points within 283.79,78.69 303.15,94.03
GND on IN1 (solid shape): outline of 122 points within 0.25,0.25 304.5,51.6
GND on IN1 (solid shape): outline of 545 points within 33.97,27.99 77.49,109.25
GND on IN1 (solid shape): 100.54,100.85 107.7,93.69 114.86,100.85 114.86,107.74 125.7,107.74 126.59,108.11 127.03,109.17 127.2,109.24 177.7,109.24 177.87,109.17 178.31,108.11 179.2,107.74 188.54,107.74 188.54,100.85 195.7,93.69 202.86,100.85 202.86,109.24 204.7,109.24 205.21,109.04 205.44,108.54 205.46,108.29 207.19,108.29 207.19,102.05 206.99,100.99 208.05,101.19 208.79,101.19 208.79,97.95 208.4,97.57 202.62,97.57 194.02,93.38 188.04,100.85 188.04,102.97 187.59,103.42 183.7,103.42 182.24,104.88 182.24,106.67 181.67,107.24 179.2,107.24 178.05,107.67 177.46,108.74 127.44,108.74 126.85,107.67 125.7,107.24 121.6,107.24 121.16,106.79 121.16,104.81 119.76,103.42 115.87,103.42 115.36,102.91 115.36,100.85 108.91,93.28 100.42,98.46 95.12,98.46 93.34,96.68 92.2,96.68 91.91,96.98 91.91,108.34 93.48,108.34 93.51,108.57 93.75,109.05 94.24,109.24 100.54,109.24
